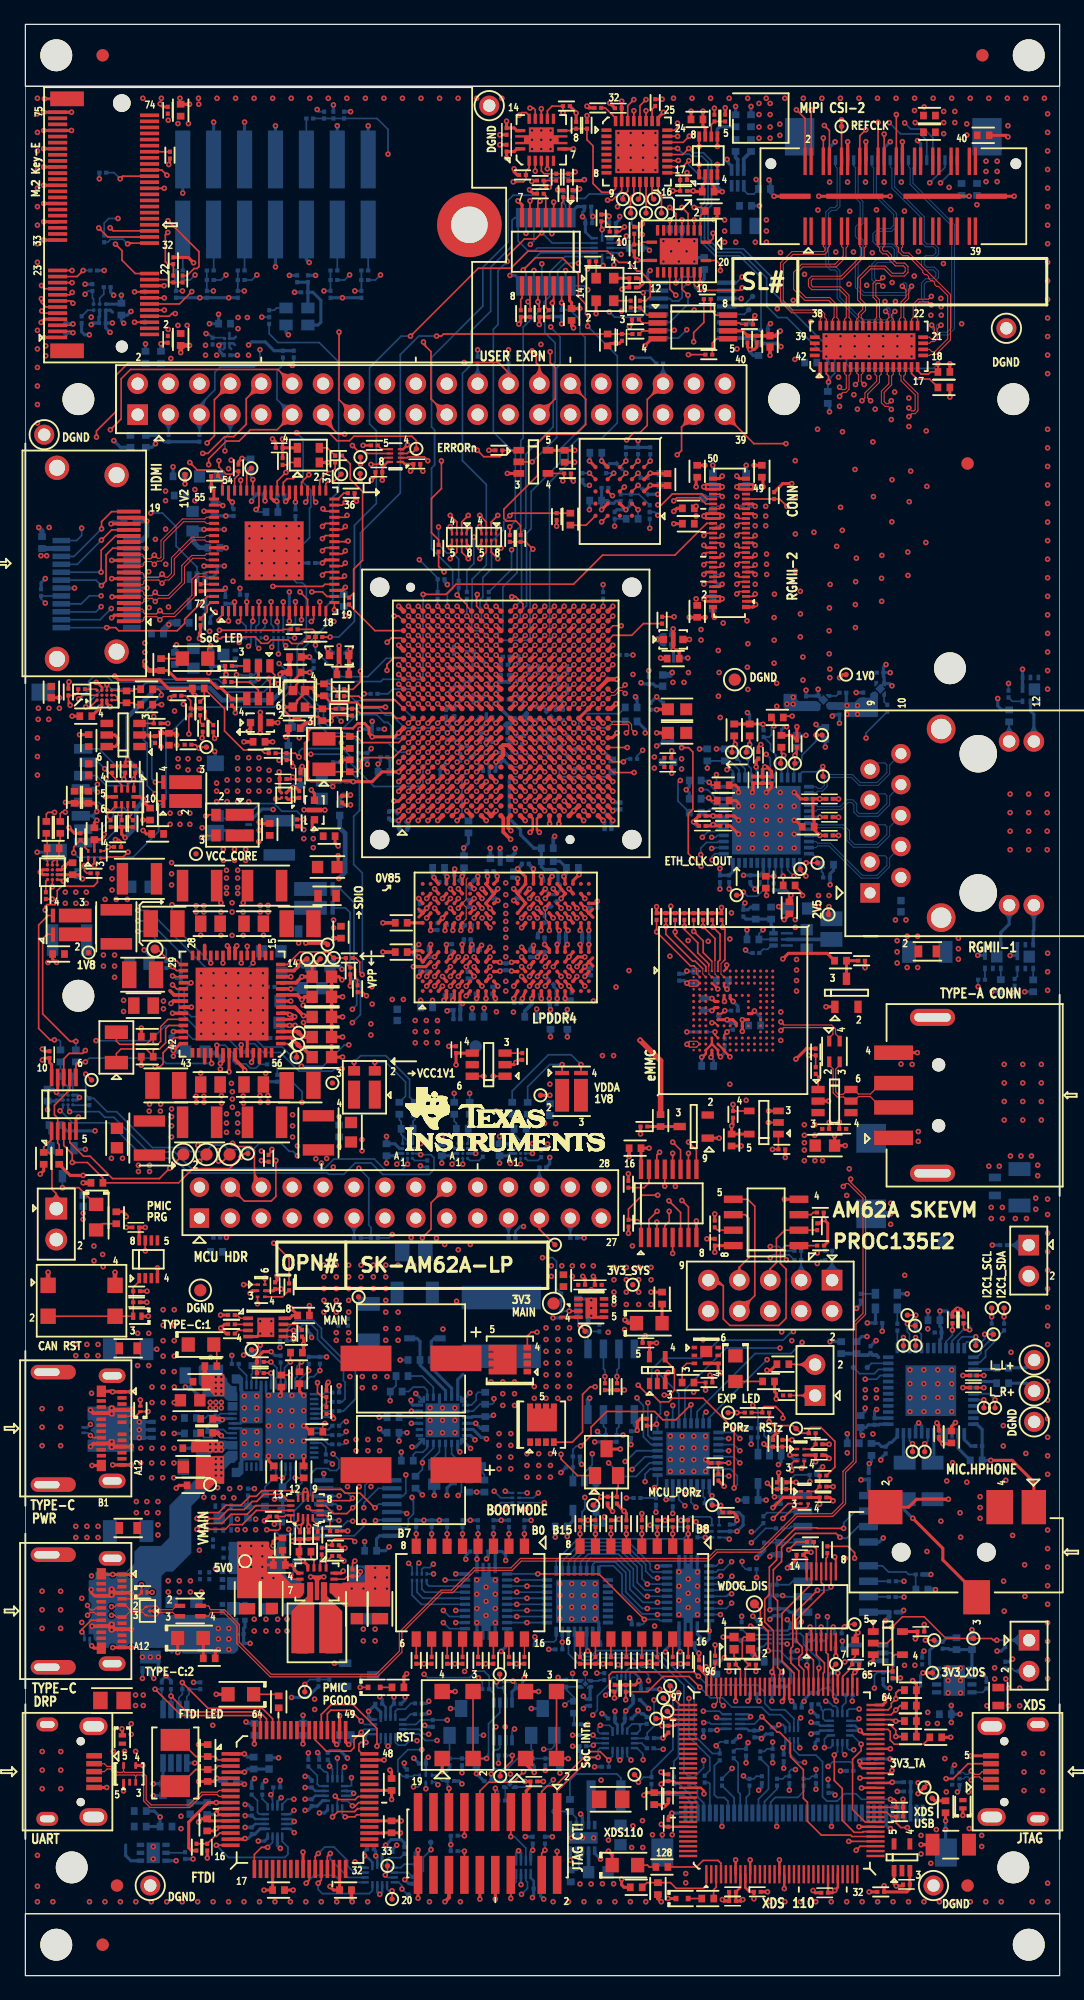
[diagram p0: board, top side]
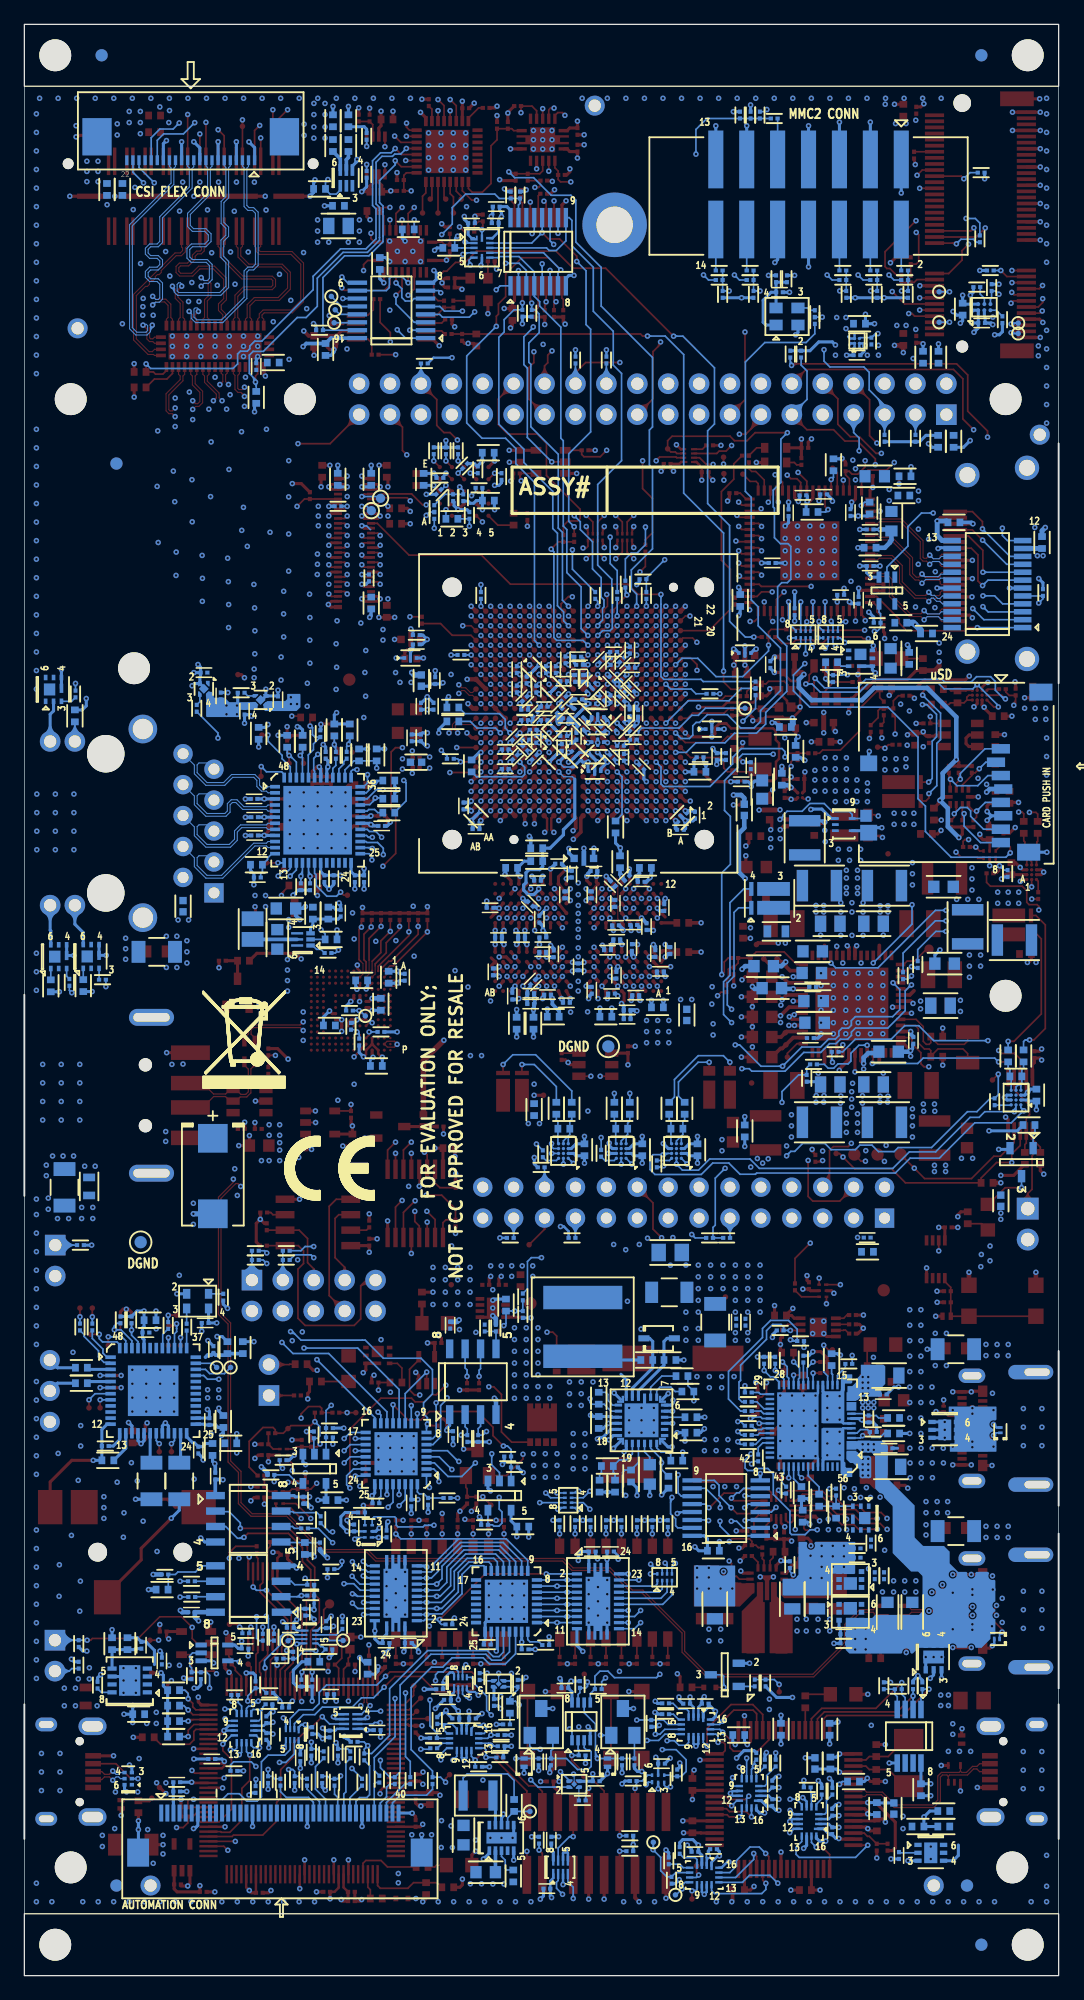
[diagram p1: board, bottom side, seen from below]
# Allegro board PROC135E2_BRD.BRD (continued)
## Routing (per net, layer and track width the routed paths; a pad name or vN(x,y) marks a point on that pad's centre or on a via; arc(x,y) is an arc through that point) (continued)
VBUS_5V0_TYPEA: length 0.6
  TOP w0.254: R125.2 v1(69,82.78)
  BOTTOM w0.14: C398.1 69.53,68.79
  vias: v1(73.38,69.33) v1(73.38,68.52)
VBUS_TYPEC1: length 8.4
  TOP w0.305: v1(5.35,43.45) 5.6,43.7 J13.B4 6.88,43.7 7.13,43.45 J13.A9 v1(8.7,43.45) ; v1(8.7,46.45) J13.A4 7.13,46.45 6.88,46.2 J13.B9 5.6,46.2 v1(5.35,46.45)
  TOP w0.381: R160.1 C118.1
  vias: v1(7.09,46.61) v1(7.09,46.15) v1(7.09,43.86) v1(7.09,43.4) v1(15.65,49.17) v1(15.65,48.71) v1(15.65,48.25) v1(15.65,47.8) v1(16.1,49.17) v1(16.1,48.71) v1(16.1,48.25) v1(16.1,47.8)
VBUS_TYPEC2: length 87.1
  TOP w0.254: v1(15.86,26.79) 15.6,26.54 R203.1 ; v1(7.09,31.27) 7.01,31.2 J15.B9 5.68,31.2 5.41,31.46 v1(5.41,31.71) ; R135.2 v1(50.55,69.13) ; v1(7.09,31.73) 7.37,31.45
  TOP w0.305: 7.37,31.45 J15.A4 v1(8.7,31.45) ; v1(5.48,28.7) J15.B4 6.84,28.7 7.09,28.45 J15.A9 v1(8.7,28.45)
  L06_PWR01 w0.508: v1(8.7,31.45) 8.7,32.11 12.59,35.99 20.74,35.99 22.04,34.7 22.04,33.81 22.54,33.3 22.54,31.64 23.6,30.58 33.91,30.58 36.57,33.24 39.72,33.24 44.85,38.37 44.85,44.73 45.54,45.41 45.54,51.42 47.38,53.26 47.38,59.95 50.55,63.13 v1(50.55,69.13)
  vias: v1(7.09,28.86) v1(7.09,28.4) v1(15.19,43.64) v1(15.19,43.18) v1(15.65,43.64) v1(15.65,43.18) v1(15.86,28.52) v1(15.86,27.65) v1(16.1,43.64) v1(16.1,43.18) v1(16.72,28.52) v1(16.72,27.65) v1(16.72,26.79)
VCC1V1: length 0.7
  BOTTOM w0.254: C90.2 v1(25.79,70.55)
  vias: v1(21.96,70.71) v1(21.96,69.79) v1(21.96,68.88)
VCC1V8_CLKBUF: length 29.1
  TOP w0.254: U7.6 58.95,135.08 C14.2 ; v1(46.19,140.15) 46.34,140.31 R23.2 ; v1(49.63,135.42) 49.86,135.64 R33.2 ; v1(49.04,138.5) 49.19,138.65 C15.2 C12.2 U6.4
  TOP w0.305: v1(62.04,135.07) 61.64,134.68 FL1.2 C16.2 C14.2
  L07_PWR02 w0.381: v1(62.04,135.07) 59.42,135.07 58.7,135.79 52.72,135.79 51.93,135 50.05,135 v1(49.63,135.42) 50.08,135.87 50.08,137.45 v1(49.04,138.5) 47.91,139.62 46.72,139.62 v1(46.19,140.15)
VCC1V8_SYS: length 97.8
  TOP w0.203: C22.1 31.18,124.16 31.02,124.32 U10.1 ; U28.M4 U28.N4 ; U28.N4 U28.P3 55.92,75.71 55.64,75.43 v1(55.58,75.43) ; U28.N4 U28.P5 56.92,75.67 v1(57.13,75.46) ; v1(57.67,81.01) 57.42,81.26 U28.C6 ; R40.1 v1(27.75,125.68) ; U54.2 22.82,37.18 v1(22.51,36.87)
  TOP w0.254: U12.D1 v1(51.35,123.4) 51.39,123.36 C26.2 ; U11.5 C21.1 v1(45.15,125.28) ; U32.5 C101.1 v1(58.04,69.78) 58.15,69.9 R133.1 ; v1(39.54,149.28) C9.2 40.18,149.81 40.4,150.03 U1.1 ; R49.2 v1(43.66,119.04) ; v1(31.65,123.56) 31.89,123.8 C22.1 ; R41.2 v1(38.09,125.28) ; U12.E4 v1(47.35,124.4) ; v1(40.17,148.39) 40.17,148.14 40.42,147.89 R9.2 ; v1(22.51,36.87) 22.51,36.86 22.57,36.81 C178.2 ; U12.B4 v1(47.35,120.4) ; v1(57.21,87.73) R118.1 R117.1 R116.1 R115.1 R114.1 R113.1 R112.1 R111.1 v1(51.88,87.8) ; R46.2 44.83,122.94 v1(45.03,122.75)
  TOP w0.305: U27.10 v1(21.81,81.04)
  L10_SIG03 w0.254: v1(58.48,36.49) 57.34,36.49 56.38,35.53 30.85,35.53 30.35,36.03 28.19,36.03 28.01,36.21 26.93,36.21 26.75,36.03 23.35,36.03 v1(22.51,36.87)
  BOTTOM w0.203: U51.1 48.24,142.7 48.53,142.99 ; C439.2 U96.5
  BOTTOM w0.254: R264.1 v1(23.85,139.64) ; v1(46.35,122.4) 46,122.4 45.79,122.61 R301.2 ; R277.2 v1(14.34,137.8) R276.2 v1(16.72,137.8) R275.2 ; C199.1 v1(47.35,120.4) ; C199.1 R303.2 ; C199.1 47.86,121.15 48.08,120.93 48.36,120.93 48.53,121.1 R306.2 ; R454.1 58.63,38.04 58.99,37.68 58.99,36.99 v1(58.48,36.49) C439.2 ; R262.2 v1(6.48,140.04) ; C191.1 47.37,124.41 v1(47.35,124.4) 47.35,124.39 47.74,124.01 R300.2 47.79,123.96 48.01,124.18 R299.2 ; R297.2 R296.2 ; R296.2 v1(50.35,126.07) ; R296.2 R295.2 ; v1(57.13,75.46) 57.48,75.82 R373.1 ; v1(57.67,81.01) 57.77,81.11 C358.1 ; R372.1 v1(54.36,77.51) ; R273.2 v1(26.06,137.8) R274.2 ; C384.1 v1(55.58,75.43) ; R411.2 v1(66.13,52.07) ; C195.1 51.37,123.38 v1(51.35,123.4) 51.13,123.17 R302.2 ; v1(48.85,144.48) 48.85,144.25 C173.2 48.53,142.99 ; R304.2 v1(51.97,121.66) ; R241.2 v1(26.73,153.09)
  BOTTOM w0.381: C361.1 22.71,81.04 v1(21.81,81.04)
  vias: v1(6.42,83.83) v1(6.42,82.91) v1(7.33,83.83) v1(7.33,82.91) v1(7.33,82)
VCC1V8_SYS_SW: length 1.2
  TOP w0.305: 11.89,80.89 12.24,80.54 U27.34
VCC2V5_PG: length 25.1
  L03_SIG01 w0.102: v1(69.09,101.64) 68.99,101.64 64.64,97.29 64.64,88.59 63.27,87.21 61.94,87.21 v1(60.62,85.9)
  BOTTOM w0.14: v1(69.09,101.64) 69.09,102.06 R329.1 ; U81.2 R360.1 60.28,85.56 v1(60.62,85.9)
VCC3V3_EXP: length 13.6
  BOTTOM w0.203: 17.22,133.92 17.09,134.05 U57.A1 16.77,133.74 16.92,133.59 ; v1(49.85,132.88) 51.37,132.88 R291.1 ; R290.1 v1(37.17,133.53) ; R289.1 v1(39.71,133.53)
  BOTTOM w0.254: C184.1 v1(17.43,133.09) ; R293.1 R294.1 11.42,125.98 10.9,126.5 C189.2 ; R287.1 R288.1 20.44,133.45 19.71,134.18 18.59,134.18 v1(18.34,133.92)
  vias: v1(18.34,133.09)
VCC3V3_TA: length 48.3
  TOP w0.254: R210.2 v1(37.83,25.61) R209.2 ; TP88.1 73.88,15.46 v1(73.37,14.95) ; R213.2 R214.2 v1(47.49,25.61) R215.2 ; R205.2 v1(32.75,25.61) R206.2 ; U45.5 C142.1 73.31,27.83 v1(73.14,27.66) ; v1(49.23,48.09) R166.1 R165.1 ; R208.2 v1(35.29,25.61) R207.2 ; R219.2 v1(53.85,25.61) R220.2 ; R211.2 v1(40.37,25.61) R212.2 ; R216.2 R217.2 51.17,25.61 v1(51.3,25.75) 51.44,25.61 R218.2
  L03_SIG01 w0.508: v1(61.18,34.42) 61.18,34.83 62.93,36.58 62.93,37.95 v1(61.56,39.32)
  BOTTOM w0.178: C453.2 60.69,28.55 60.9,28.34 U102.8
  BOTTOM w0.254: v1(66.54,14.84) 66.37,15.01 R559.1 ; U100.27 46.13,26.75 v1(46.22,26.66) ; U98.1 C457.2 53.72,26.7 v1(53.82,26.61) ; R546.2 v1(64.97,15.3) ; U101.1 C442.2 39.17,34.83 39.47,34.53 v1(39.47,34.1) ; v1(79.86,26.66) 80.2,26.66 R486.2 ; R548.2 60.52,15.49 v1(60.26,15.22) ; v1(49.66,29.38) 49.83,29.21 R480.2 ; v1(45.63,13.27) 45.78,13.12 U120.8 ; v1(59.6,28.7) 59.75,28.55 C453.2 ; U97.8 62.83,39.43 62.73,39.32 C437.2 v1(61.56,39.32) ; C460.2 v1(44.13,27.39) U100.31 ; J23.3 72.75,14.28 72.76,14.29 C492.1 C489.1 ; R490.2 v1(41.87,27.82) ; R547.2 v1(62.78,15.23) ; R531.2 v1(59.23,17.48) ; R530.2 v1(61.41,17.49) ; v1(58.7,19.65) 58.51,19.46 58.43,19.46 R527.2 ; R543.1 v1(66.99,16.82)
  BOTTOM w0.381: v1(70.68,29.14) 70.99,29.44 C451.2 U99.8 ; R470.2 61.35,34.59 v1(61.18,34.42) ; R474.2 v1(74.8,31.7)
  vias: v1(47.31,16.06) v1(47.89,52.83) v1(49.24,53.07) v1(73.37,15.84) v1(74.13,15.84)
VCC3V3_XDS: length 61.8
  TOP w0.203: v1(68.71,15.42) 68.72,15.43 U47.47 ; U47.113 53.44,15.83 53.29,15.98 C150.1 ; U47.8 58.77,7.25 C164.1 ; U47.101 53.48,20.63 53.37,20.52 C147.2 ; v1(66.51,7) 66.77,7.25 U47.28 ; v1(66.77,24.86) U47.69 ; U47.39 v1(68.51,12.23) ; C137.2 64.2,34.3 U44.14 ; U47.79 62.77,22.75 v1(62.97,22.55) ; U47.90 v1(58.37,22.55) ; U47.26 C166.1 ; U47.16 v1(61.97,9.51) ; U47.122 C156.1 ; U47.52 68.74,17.43 v1(68.56,17.6) 68.56,17.23 68.77,17.03 U47.51 ; U47.7 v1(58.37,9.51)
  TOP w0.254: v1(72.12,14.48) R233.1 R234.1 ; v1(68.43,28.17) 68.2,27.94 R202.2 ; v1(66.51,7) 66.32,6.81 C166.1 ; C137.2 64.14,34.77 v1(64.57,34.77) ; v1(58.96,6.25) 58.83,6.12 C167.1 C164.1 ; v1(52.25,15.72) 52.5,15.98 C150.1 ; C147.2 v1(52.32,20.52) ; C156.1 52.46,12.23 v1(52.26,12.43) ; TP79.1 v1(73.77,24.87) ; R239.1 v1(69.34,6.88)
  BOTTOM w0.178: U112.8 62.46,18.93 v1(62.26,18.73) ; U102.1 62.63,28.34 C454.2
  BOTTOM w0.203: C481.2 65.32,20.13 U111.2 ; C479.2 59.45,20.13 59.31,20.27 U109.8
  BOTTOM w0.254: v1(64.57,19.85) 64.64,19.92 C481.2 ; v1(61.35,22.55) R503.1 R502.1 62.58,23.74 62.89,24.05 62.89,25.09 62.19,25.78 R494.2 ; 74.31,25.55 74.31,26.72 75.01,27.42 C458.1 75.71,27.75 R488.1 ; v1(62.26,18.73) 62.32,18.66 C482.2 ; U99.1 62.81,29.85 62.53,30.13 C452.2 61.27,30.13 v1(61.19,30.05) 61.19,30.56 R479.1 R477.1 ; v1(62.97,22.55) 63.25,22.27 C469.1 ; R525.2 R522.2 R518.2 R514.2 73.58,23.8 73.58,24.68 v1(73.77,24.87) ; v1(68.56,17.6) 68.76,17.79 C483.2 ; C454.2 62.86,28.98 v1(62.61,29.24) ; C479.2 60.29,20.13 v1(60.49,20.33) ; v1(66.77,24.86) 66.2,24.86 66,24.66 R506.2
  BOTTOM w0.305: v1(68.67,40.72) 68.7,40.75 C135.2 69.31,39.44 U97.1
  vias: v1(72.25,25.49) v1(73.1,25.49)
VCC5V0_EXP: length 3.1
  BOTTOM w0.254: v1(6.96,134.96) 6.61,135.32 C181.1 ; C181.1 v1(7.15,135.73) ; C181.1 U53.A1 7,136.78 7.17,136.61
VCC_0V85: length 5.2
  TOP w0.305: v1(23.04,84.81) 24.71,84.81 TP30.1 ; C82.1 22.96,80.39 v1(22.73,80.16) 22.35,80.54 U27.9
  L08_PWR03 w0.457: v1(22.83,79.7) 22.73,79.81 v1(22.73,80.16)
  vias: v1(22.46,84.81)
VCC_1V8_AUD: length 3.3
  BOTTOM w0.305: 70.11,50.79 69.94,50.96 69.64,50.96 C411.1 69.28,50.96 68.44,50.96 C409.1 R411.1
VCC_1V8_FT4232: length 9.4
  TOP w0.254: v1(30.88,12.71) C158.2 U48.37 ; U48.49 26.32,19.19 26.53,18.98 v1(26.58,18.98) ; U48.12 15.1,12.71 C157.2 14.49,12.87 v1(14.24,12.62) ; U48.64 v1(18.82,19.03)
  BOTTOM w0.254: C476.2 v1(18.82,19.03) ; C480.1 26.78,19.18 v1(26.58,18.98)
VCC_3V3_AUD: length 20.1
  TOP w0.254: C125.1 76.04,43.69 v1(75.41,43.69) 75.07,44.03 C124.1
  BOTTOM w0.254: U88.16 75.66,43.94 v1(75.41,43.69) 75.16,43.94 U88.17 ; U88.24 71.66,44.27 71.17,43.78 71.04,43.78 C425.1 70.36,43.44 70.1,43.71 C424.1 ; U93.5 C434.1 v1(60.88,39.06) ; U88.25 70.22,45.29 70.16,45.23 C418.1 69.28,45.23 69.07,45.02 C419.1 68.64,44.51 v1(68.8,44.36) ; R402.1 R403.1 75.74,54.58 v1(75.16,54.58) C402.1 75.16,53.32 75.29,53.2 C407.1 75.29,52.36 75.16,52.23 U88.44 ; R399.1 68.65,55.15 v1(68.3,54.8) ; U86.4 C406.1 v1(69.19,53.61) ; R427.2 v1(58.75,44.97)
  vias: v1(69.65,44.49)
VCC_3V3_FT4232: length 23.8
  TOP w0.254: U48.20 C162.2 v1(19.61,7.03) ; U48.42 C152.2 v1(30.1,14.47) ; LD8.2 v1(15.69,23.11) ; U48.31 C163.2 25.33,7.03 v1(25.03,7.33) ; U48.56 v1(22.82,19.03) ; U48.50 v1(25.82,21.34)
  BOTTOM w0.203: U123.2 28.92,9.71 v1(28.79,9.84) ; U110.2 29.61,22.05 C468.2 ; C499.2 18.89,12.46 U119.2 ; U118.2 23.82,14.77 C493.2
  BOTTOM w0.254: R509.2 11.96,24.24 v1(11.57,24.64) 11.2,24.27 R510.2 ; v1(10.51,15.76) C491.2 U113.8 ; R508.2 v1(13.82,24.09) ; v1(22.99,14.49) C493.2 ; FL14.2 v1(20.82,17.89) ; C468.2 29.33,22.71 v1(29.12,22.91) ; v1(18.06,12.18) C499.2 ; C475.2 v1(22.82,19.03) ; C502.2 28.79,10.23 v1(28.79,9.84)
  vias: v1(12.79,13.09) v1(12.79,12.08)
VCC_3V3_MAIN: length 47.8
  TOP w0.254: v1(1.4,75.2) 1.56,75.36 C88.2 1.99,74.99 2.16,74.82 U31.10 ; U21.B2 20.9,97.29 C51.1 20.9,98.82 v1(20.86,98.86) ; R138.2 1.51,66.11 v1(1.22,65.83) ; v1(21.02,56.39) C107.2 20.38,56.25 U36.5 ; 43.95,54.08 U37.4
  TOP w0.279: U27.12 v1(21.81,82.04) ; U27.8 v1(21.81,80.04)
  TOP w0.305: v1(11.97,79.85) 12.16,80.04 U27.35 ; U27.54 19.24,74.97 ; U27.48 16.24,75.13 v1(16.03,74.91) ; R80.1 21.61,101.95 v1(21.41,101.75) ; U27.4 v1(21.71,78.04) v1(22.17,78.04) ; U27.26 14.74,84.61 ; U27.17 19.24,84.61 ; U27.45 14.74,74.97
  L06_PWR01 w0.254: v1(21.81,82.04) 21.81,83.36 21.8,83.38
  L06_PWR01 w0.432: v1(20.86,98.86) 20.86,99.01 19.78,100.08
  L07_PWR02 w0.381: v1(30.63,54.5) 31.43,54.5 37.9,48.02 v1(37.9,44.08) 37.9,42.69 v1(34.65,39.43)
  BOTTOM w0.254: v1(34.65,39.43) 34.65,40.05 R443.2 ; v1(21.41,101.75) 21.61,101.55 C280.1 ; C92.1 19.8,73.42 R574.1 ; R401.2 v1(43.36,54.02) ; v1(37.9,44.08) 37.78,44.2 37.46,44.2 36.81,44.86 U89.17
  BOTTOM w0.381: C383.1 14.88,75.77 15.64,75.77 16.03,75.39 v1(16.03,74.91)
  vias: v1(4.75,62.62) v1(4.75,62.12) v1(11.35,80.04) v1(11.35,79.41) v1(14.03,87.87) v1(14.03,87.36) v1(14.03,72.22) v1(14.06,71.74) v1(14.41,85.45) v1(14.41,74.13) v1(14.67,87.87) v1(14.67,87.36) v1(14.67,72.22) v1(14.69,71.74) v1(16.03,74.46) v1(19.31,87.89) v1(19.31,87.36) v1(19.28,72.27) v1(19.31,71.74) v1(19.57,85.45) v1(19.75,74.12) v1(19.94,87.89) v1(19.94,87.36) v1(19.92,72.27) v1(19.94,71.74) v1(24.54,58.36) v1(24.54,57.39) v1(24.54,56.43) v1(24.54,55.46) v1(24.54,54.5) v1(25.55,58.36) v1(25.55,57.39) v1(25.55,56.43) v1(25.55,55.46) v1(25.55,54.5) v1(26.57,58.36) v1(26.57,57.39) v1(26.57,56.43) v1(26.57,55.46) v1(26.57,54.5) v1(27.58,58.36) v1(27.58,57.39) v1(27.58,56.43) v1(28.6,58.36) v1(28.6,57.39) v1(28.6,56.43) v1(29.62,58.36) v1(29.62,57.39) v1(29.62,56.43) v1(29.62,55.46) v1(29.62,54.5) v1(30.63,58.36)
VCC_3V3_MAIN_PG: length 103.5
  TOP w0.14: U36.3 v1(19.08,55.18)
  L03_SIG01 w0.102: v1(35.57,39.43) 35.57,41.82 34.79,42.61 34.79,47.12 34.32,47.59 v1(34.32,53.1)
  L05_SIG02 w0.102: v1(54.92,47.92) 54.92,49.49 57.3,51.88 57.3,53.97 57.3,54.16 57.3,67.78 58.73,69.2 58.73,73.36 60.43,75.06 60.43,80.43 59.18,81.67 v1(59.18,84.24) ; v1(19.08,55.18) 19.85,55.18 20.08,55.41 21.85,55.41 23.61,53.65 33.77,53.65 v1(34.32,53.1)
  L10_SIG03 w0.102: v1(35.57,39.43) 35.57,41.55 37.42,43.39 37.42,44.43 37.9,44.91 40.37,44.91 40.61,44.67 46.5,44.67 48.32,42.85 50.27,42.85 52.28,44.86 52.28,46.67 52.94,47.33 54.33,47.33 v1(54.92,47.92)
  BOTTOM w0.14: U89.21 34.53,42.14 R443.1 35.65,41.53 35.84,41.34 35.84,39.7 v1(35.57,39.43) ; R361.1 59.44,83.99 v1(59.18,84.24)
VCC_3V3_SYS: length 227.8
  TOP w0.14: U4.19 v1(55.46,139.03) ; U2.27 v1(51.01,153.17)
  TOP w0.203: U54.3 23.22,36.95 v1(23.29,36.88) ; U10.8 29.77,124.32 29.33,123.88 C25.2 ; C65.1 U24.5
  TOP w0.229: J4.48 57.07,122.08 v1(57.27,122.28) 57.07,122.48 J4.50 55.96,122.48 v1(55.76,122.28) 55.96,122.08 J4.48
  TOP w0.254: v1(50.43,24.23) 50.43,24.19 50.12,23.87 R224.1 R223.1 ; v1(65.27,38.73) C133.1 U42.5 ; R83.2 R84.2 60.61,102.8 v1(60.63,102.77) ; v1(13.82,140.68) 13.38,141.12 R22.2 ; R162.2 61.56,47.97 61.71,47.82 v1(61.71,47.37) ; U33.16 C103.2 v1(51.26,67.96) ; C62.1 56.63,94.43 v1(56.52,94.54) 56.41,94.43 C61.1 ; R285.2 26.01,36.52 26.01,36.53 v1(26.49,36.53) ; R39.1 v1(75.98,129.64) ; C75.1 62.79,88.6 v1(62.92,88.74) ; R172.2 50.54,45.73 50.28,45.48 v1(50.28,44.79) ; v1(46.15,153.54) 46.29,153.4 R3.2 ; C180.2 23.29,36.87 v1(23.29,36.88) ; U1.14 40.4,151.53 40.18,151.75 C6.2 v1(39.54,152.31) ; R68.2 3.53,106.21 v1(3.58,106.26) ; v1(45.56,136.92) C13.2 44.89,137.4 44.72,137.58 U5.14 ; v1(55.69,153.12) C5.2 55.69,151.93 55.87,151.74 U3.7 ; R263.2 20,37.71 v1(19.65,37.35) ; U2.31 C1.2 v1(49.01,153.95) ; v1(48.26,38.13) 47.85,38.54 R183.1 ; U25.B1 C71.1 4.35,90.42 v1(4.7,90.07) ; v1(21.85,54.8) 22.37,54.28 C111.1 21.95,54.22 21.72,53.99 U38.8 ; R151.1 v1(16.04,54.25) ; U9.4 C20.2 ; C20.2 R44.2 ; C20.2 v1(21.14,126.2) ; R1.2 v1(52.33,154.11) ; v1(24.89,48.73) 24.74,48.58 R167.1 ; v1(51.87,51.96) C112.2 U40.5 ; U16.4 C35.2 16.09,105.75 15.76,105.75 15.05,106.47 12.42,106.47 11.7,107.19 R62.2 ; v1(63.4,102.58) R86.2 62.98,101.87 R85.2 ; R175.2 v1(63,44) ; R181.2 v1(63.33,40.52) ; v1(31.34,24.79) 31.11,24.57 R222.2 ; v1(41.06,15.95) C151.1 41.51,15.53 41.16,15.18 J19.5 ; v1(64.94,42.21) C127.1 U41.5 ; R136.2 v1(62.45,67.2) ; U28.E6 57.42,80.04 v1(57.45,80.01) ; R30.1 R29.1 40.71,135.79 v1(40.56,135.64) ; R32.1 R31.1 v1(42.24,135.61) ; U17.B1 6.29,104.35 v1(6.12,104.18) 6.12,104.11 C37.1 ; v1(8.29,62.33) 8.29,62.49 8.04,62.73 R143.2 ; R17.1 41.76,146.35 v1(41.43,146.67) ; R79.2 v1(11.71,102.84) ; R182.2 v1(66.39,40.16) ; R2.2 45.27,153.02 v1(45.27,152.97) R6.2 ; R126.2 v1(26.7,81.29) ; v1(29.33,122.82) C25.2 ; v1(63.32,75.27) 64.19,76.14 R128.1 ; C43.1 60.05,99.77 v1(60.05,99.27) ; U28.J10 v1(58.92,78.51) U28.K9 v1(58.92,77.55) ; C65.1 6.23,93.3 6.48,93.55 v1(6.48,93.74) ; v1(35.4,74.8) C87.2 U29.4 ; R38.1 v1(75.98,132.39) ; v1(56.42,80.26) 56.67,80.01 U28.F5 ; R176.2 v1(66.06,43.64) ; v1(65.19,131.37) 65.33,131.51 U8.1 ; v1(45.54,146.75) 45.44,146.64 R16.1 ; v1(55.12,122.28) 55.12,123.03 55.21,123.12 ; R150.2 v1(51.42,56.14) ; v1(62.98,122.54) 62.24,122.54 R571.2 ; R13.2 v1(54.37,148.08) ; R179.2 v1(57.42,40.19)
  TOP w0.305: v1(22.88,94.12) 22.6,94.4 R97.2
  TOP w0.381: v1(9.82,107.92) 9.82,107.55 10.18,107.19 R62.2
  L05_SIG02 w0.508: v1(63.44,26.7) 64.22,27.48 v1(67.14,27.48)
  L07_PWR02 w0.254: v1(20.37,95.77) 19.32,95.77 18.31,94.76 13.72,94.76 v1(13.52,94.55)
  BOTTOM w0.14: U83.B3 v1(41.68,67.53)
  BOTTOM w0.178: U112.1 62.46,20.4 62.24,20.61 v1(61.91,20.61) ; 49.79,24.9 49.69,24.79 U106.8 ; U106.1 49.69,23.26 49.79,23.15
  BOTTOM w0.203: U109.1 56.95,20.27 v1(56.84,20.17) ; U122.1 41.53,8.02 41.77,7.78 C506.2 ; v1(40.94,61.52) 40.66,61.52 40.27,61.14 R391.1 ; C496.2 18.89,12.86 U119.3 ; C467.2 30.01,22.05 U110.3 ; 16.77,134.92 U57.A2 17.15,134.45 17.3,134.61 ; U114.2 48.66,20.6 ; U111.3 65.32,20.53 C473.2 ; U118.3 23.82,15.17 C490.2 ; U116.5 C487.2 ; 49.79,24.9 50.02,24.9 50.43,24.49 v1(50.43,24.23) ; R390.2 v1(45.92,60.59) ; 46.02,143.21 46.53,142.7 U51.11 ; U114.3 49.06,20.63
  BOTTOM w0.254: R505.1 v1(40.07,24.19) 40.3,23.96 C462.2 39.99,23.31 U108.8 ; v1(45.85,22.95) 46.08,22.72 C466.2 U107.5 ; R408.1 23.52,52.63 v1(23.52,52.41) ; U101.24 v1(37.11,34.2) C443.1 ; U101.23 v1(35.37,32.99) ; 49.06,20.63 49.26,20.83 C471.2 49.26,21.66 v1(49.34,21.74) 49.95,22.35 C465.2 49.95,22.99 49.79,23.15 ; v1(55.12,37.28) 55.23,37.17 R465.2 ; v1(44.98,18.84) R528.2 45.53,18.42 45.64,18.31 R537.2 ; v1(1.83,71.11) C388.1 2.45,71.83 2.54,71.92 U82.B1 ; v1(6.08,147.57) 6.08,148.07 R250.2 ; R392.2 v1(79.47,60) ; R339.1 v1(56.79,100.75) ; U92.27 v1(55.2,39.51) ; R252.2 45.31,146.52 v1(45.54,146.75) ; C473.2 64.64,20.74 v1(64.57,20.81) ; v1(23.25,18.3) R541.2 ; U87.1 50.05,45.2 50.28,44.96 v1(50.28,44.79) 50.21,44.71 C422.1 ; 56.49,122.28 v1(57.27,122.28) ; R433.1 R434.1 v1(46.79,43.83) ; U78.19 60.65,90.68 C310.1 C311.1 v1(59.02,90.37) ; U95.16 29.12,36.13 28.86,35.87 C441.2 29.58,34.9 v1(29.9,35.22) ; U94.5 45,37.35 C438.1 v1(44.53,36.06) ; v1(21.87,22.85) 23.18,22.85 R501.2 ; C487.2 32.91,17.74 v1(33.11,17.94) ; R539.1 v1(35.88,16.66) ; v1(55.46,139.03) 55.79,139.36 C176.2 ; v1(1.64,114.74) 1.29,114.39 R317.2 ; R534.2 v1(38.88,17.44) ; R335.2 60.63,102.33 v1(60.63,102.77) ; v1(35.88,15.75) 35.64,15.99 R552.1 ; v1(61.91,20.61) 61.71,20.41 C478.2 ; R438.2 45.56,42.14 v1(45.71,41.99) ; v1(62.92,88.74) 62.5,89.15 R354.2 R355.1 ; U84.B1 35.1,67.53 34.91,67.34 C396.1 v1(34.22,66.73) ; R388.1 43.09,66.67 v1(43.09,67.2) ; v1(71.05,23.61) 70.75,23.61 70.5,23.86 R498.2 ; U92.31 C435.2 v1(52.66,39.1) ; v1(63.44,26.7) 63.34,26.6 R492.2 ; v1(43.78,24.5) 43.99,24.29 R504.2 ; U117.5 C488.2 v1(38.29,16.58) ; R367.2 v1(82.12,80.8) ; R346.2 54.56,97.65 v1(54.31,97.4) 54.56,97.15 R347.2 ; R558.1 v1(20.94,16.04) ; C61.1 56.41,94.43 v1(56.52,94.54) 56.62,94.64 U78.30 ; R542.2 46.9,17.15 46.89,17.15 v1(46.78,17.15) ; v1(18.84,16.19) 18.59,15.95 R561.2 ; R409.1 v1(20.93,51.6) ; v1(29.68,66.73) C397.1 30.37,67.34 30.56,67.53 U85.B1 ; v1(31.18,7.88) 31.51,7.55 R570.1 ; v1(44.07,135.66) R278.1 R279.1 ; R353.2 4.53,90.23 v1(4.7,90.07) ; U98.23 v1(56.2,28.32) 56.2,27.66 55.85,27.32 C456.1 55.56,27.72 55.22,28.06 U98.24 ; U84.B3 v1(37.01,67.53) ; U82.B3 4.24,71.92 v1(4.45,72.12) 4.26,72.32 U82.C3 ; v1(22.99,15.45) C490.2 ; R516.2 32.98,22.36 v1(33.15,22.54) ; v1(18.06,13.14) C496.2 ; v1(38.97,66.73) C395.1 39.66,67.34 39.85,67.53 U83.B1 ; v1(30.29,22.88) C467.2 ; U52.16 45.04,144.99 45.34,145.29 C172.2 45.94,144.97 45.79,144.82 v1(45.79,144.46) 46.02,144.23 C174.2 46.02,143.21 ; U103.5 67.71,27.16 67.42,26.87 C459.2 v1(67.14,27.48) ; U123.3 29.32,9.89 C503.2 v1(29.6,10.72) 30.06,11.17 30.89,11.17 31.14,10.92 R565.2 ; v1(66.08,128.44) 66.08,128.99 R292.1 ; v1(41.67,6.41) 41.77,6.52 C506.2 ; U85.C3 32.08,67.93 v1(32.49,68.34) ; R538.1 42.74,16.85 v1(42.73,16.85) ; R544.1 31.14,17.14 v1(31.14,17.46) ; R564.1 v1(34.96,10.76) R566.1 ; U79.1 18.69,95.03 19.46,95.81 20.33,95.81 v1(20.37,95.77) ; 48.66,20.6 48.45,20.81 C472.2 v1(48.45,21.72) ; R272.1 v1(21.7,139.64) ; C463.2 50.59,24.09 50.46,24.23 v1(50.43,24.23) ; v1(79.91,104.89) 79.91,104.28 80.24,103.95 R330.1 ; U122.8 41.53,10.13 v1(41.69,10.3) C501.2 ; R451.2 v1(51.82,38.06) ; R366.2 v1(79.43,80.82) ; v1(56.84,20.17) C477.2 ; U78.41 60.15,99.18 v1(60.05,99.27) 60.05,99.77 C43.1 ; R435.2 v1(67.54,44.51)
  BOTTOM w0.305: U55.16 59.81,134.49 C183.2 61.83,134.05 v1(62.09,133.79)
  BOTTOM w0.381: v1(56.42,80.26) 56.41,80.27 C371.1
  vias: v1(9.82,109.45) v1(9.82,108.69) v1(11.13,100.93) v1(11.74,152.39) v1(11.74,135.2) v1(11.9,95.47) v1(11.9,94.55) v1(12.45,101.05) v1(12.54,152.11) v1(12.54,135.53) v1(12.71,95.47) v1(12.71,94.55) v1(13.3,135.53) v1(13.4,152.11) v1(13.52,95.47) v1(17.48,136.18) v1(17.48,135.27) v1(18.24,136.18) v1(48.37,58.17) v1(48.37,57.15) v1(48.37,56.14) v1(48.37,55.12) v1(49.39,58.17) v1(49.39,57.15) v1(49.39,56.14) v1(49.39,55.12) v1(50.4,58.17) v1(50.4,57.15) v1(50.4,56.14) v1(50.4,55.12) v1(51.42,58.17) v1(51.42,57.15) v1(51.42,55.12) v1(63.38,83.45) v1(63.38,82.59) v1(63.38,81.73) v1(63.38,80.86) v1(67.54,42.94) v1(71.5,86.7) v1(72.37,86.7) v1(75.47,153.11) v1(75.47,152.19) v1(75.47,151.28) v1(76.38,153.11) v1(76.38,152.19) v1(78.95,149.02) v1(78.95,148.18) v1(78.95,147.34) v1(79.86,149.02) v1(79.86,148.18) v1(79.86,147.34)
VCC_3V3_SYS_EN: length 61.5
  TOP w0.14: TP53.1 45.99,52.99 v1(45.6,53.38) ; U27.47 v1(15.74,76.41) ; U37.3 v1(44.69,54.58)
  L05_SIG02 w0.102: v1(15.74,76.41) 15.26,76.41 14.12,75.27 14.12,74.48 13.52,73.88 13.52,65.66 13.23,65.37 13.23,61.48 16.25,58.46 23.23,58.46 23.88,57.81 41.46,57.81 v1(44.69,54.58)
  BOTTOM w0.14: v1(45.6,53.38) 45.42,53.56 R400.2 v1(44.69,54.58) R401.1 R398.2 ; v1(15.74,76.41) 16.42,76.41 17.07,75.76 17.07,75.11 17.3,74.88 18.13,74.88 18.48,74.53 18.94,74.53 19.26,74.84 R575.2
VCC_5V0: length 25.7
  TOP w0.229: 57.07,119.68 J4.36 55.96,119.68 v1(55.76,119.88) 55.96,120.08 J4.38 57.07,120.08 v1(57.27,119.88) 57.07,119.68
  TOP w0.254: R196.2 26.01,35.12 v1(26.27,35.12) ; v1(19.47,33.57) 19.62,33.72 R200.1 20.38,34.48 v1(20.39,34.49)
  L07_PWR02 w0.254: v1(20.39,34.49) 20.94,35.04 20.94,38.67 v1(20.47,39.14)
  L10_SIG03 w0.254: v1(20.39,32.66) 21.33,33.61 24.54,33.61 26.06,35.12 v1(26.27,35.12)
  BOTTOM w0.254: v1(7.26,138.01) 7,138.26 R270.1 ; C436.1 21.14,38.33 R447.1 20.53,39.19 v1(20.47,39.14) ; v1(7.89,138.01) C179.1 7.81,137.28 U53.A2 ; v1(5.26,134.76) 4.87,134.76 4.62,135.01 R281.2 ; 19.81,32.59 19.81,31.98
  BOTTOM w0.406: U58.11 C204.1 1.37,117.21
  vias: v1(1.28,116.62) v1(1.75,116.62) v1(17.65,35.3) v1(17.65,34.44) v1(17.65,33.57) v1(18.56,35.3) v1(18.56,34.44) v1(18.56,33.57) v1(19.47,35.3) v1(19.47,34.44) v1(19.47,32.66) v1(55.12,120.68) v1(55.12,119.88) v1(57.46,144.2) v1(57.46,143.28) v1(57.46,142.37) v1(58.38,142.37) v1(60.84,120.68) v1(60.84,119.88) v1(60.84,119.08) v1(64.02,69.88) v1(64.02,69.02) v1(64.02,68.41) v1(64.02,67.8) v1(64.02,66.94) v1(64.88,69.88) v1(64.88,69.02) v1(64.88,66.94) v1(65.52,66.94)
VCC_5V0_EN: length 45.6
  TOP w0.14: v1(27.54,33.19) 27.54,32.94 27.4,32.8 R201.2 26.47,32.8 26.24,32.56 U43.14
  L03_SIG01 w0.102: v1(27.54,33.19) 28.35,34 28.35,35.97 27.42,36.9 27.42,39.34 26.99,39.77 26.99,41.1 27.66,41.78 27.66,44.51 28.12,44.96 28.12,49.71 30.1,51.69 30.1,56.54 v1(31.9,58.34)
  L05_SIG02 w0.102: v1(31.9,58.34) 41.87,58.34 v1(42.5,58.97)
  BOTTOM w0.14: v1(42.5,58.97) 43.33,58.97 43.65,58.65 43.65,56.4 R398.1
VCC_5V0_FB: length 2.9
  TOP w0.254: R195.1 21.13,34.5 21.36,34.27 R200.2 21.9,33.72 22.1,33.53 22.1,33.35 22.39,33.06 U43.5
VCC_5V0_HDMICONN: length 5.1
  TOP w0.305: J5.18 9.7,119.74 v1(9.98,119.46)
  BOTTOM w0.406: U58.13 9.57,117.86 9.98,118.27 v1(9.98,119.46) 9.2,119.46 C202.1
VCC_5V0_PG: length 28.8
  TOP w0.14: v1(27.07,35.65) 26.84,35.88 25.42,35.88 25.21,35.67 R196.1 24.88,35.35 24.68,35.15 R197.2
  L05_SIG02 w0.102: v1(27.07,35.65) 27.07,35.65 27.07,35.16 26.55,34.64 26.05,34.64 25.25,33.84 25.25,28.77 27.11,26.9 27.11,18.98 30.59,15.5 v1(31.9,15.5)
  BOTTOM w0.14: U116.3 32.41,15.64 32.27,15.5 v1(31.9,15.5)
VCC_CORE:
  vias: v1(10.2,71.58) v1(10.18,71) v1(11.12,71.58) v1(11.09,71) v1(12.02,91.41) v1(12.02,90.5) v1(12.02,89.58) v1(12.02,71.18) v1(12.02,70.55) v1(12.02,69.79) v1(12.02,68.88) v1(16.27,92.51) v1(16.27,91.59) v1(17.19,92.51) v1(17.19,91.59) v1(18.1,92.51) v1(18.1,91.59) v1(19.18,93.13)
VCC_CSI_IO: length 9.5
  TOP w0.14: v1(54.96,145.22) 55.57,145.22 C11.2 55.46,144.52 U4.2 ; R4.2 v1(56.63,153.37)
  TOP w0.254: v1(50.7,143.88) 50.44,143.62 R20.2 ; v1(57.27,146.52) C10.2 56.61,146.98 56.37,147.21 U3.3
  BOTTOM w0.254: R249.1 56.87,146.92 v1(57.27,146.52) ; R246.1 56.87,151.65 57.07,151.85 R245.1
  vias: v1(60.29,151.83) v1(60.29,150.91) v1(61.21,151.83) v1(61.21,150.91) v1(77.36,152.08) v1(77.36,151.17)
VCC_LM5141: length 6.4
  BOTTOM w0.254: D9.2 32.18,52.34 32.43,52.09 C413.1 32.43,50.14 34.53,48.04 U89.10
VDD1_LPDDR4_1V8: length 12.5
  TOP w0.254: U26.U12 43.06,90.06 v1(43.29,90.29) ; U26.G4 v1(36.23,82.87) ; U26.U1 v1(43.06,80.24) ; U26.F12 v1(35.91,90.29) ; U26.G9 v1(36.88,87.67) ; U26.T9 v1(42.08,87.67) ; v1(35.92,79.84) 35.71,80.05 35.71,80.67 U26.F1 ; U26.T4 v1(42.73,83.67)
  BOTTOM w0.254: v1(42.08,87.67) 42.67,87.07 C328.1
  BOTTOM w0.305: C345.1 42.68,83.72 v1(42.73,83.67) ; v1(35.92,79.84) 35.74,79.66 C374.1 C375.2 ; C322.1 36.76,87.79 v1(36.88,87.67) ; C363.1 43.11,80.29 v1(43.06,80.24) 43.06,79.85 C370.1 43.11,79.4 v1(43.16,79.35) C378.1 ; C314.2 43.11,90.11 v1(43.29,90.29) ; v1(36.23,82.87) 36.34,82.75 C355.1 ; 35.66,89.94 35.91,90.18 v1(35.91,90.29) 36.05,90.43 C302.1
  vias: v1(30.15,80.17) v1(31.07,80.17)
VDD_1V0: length 26.6
  TOP w0.229: J4.2 55.96,112.88 v1(55.76,113.08) 55.96,113.28 J4.4 57.07,113.28 v1(57.27,113.08)
  TOP w0.254: J4.2 57.07,112.88 v1(57.27,113.08) ; C60.1 v1(65.29,95.14) ; C48.1 C49.1 ; C49.1 C50.1 61.33,98.91 60.97,99.27 v1(60.76,99.27) 60.57,99.07 C49.1 ; C59.1 v1(56.52,95.25) C58.1 ; v1(66.91,106.6) 67.17,106.85 TP17.1
  L07_PWR02 w0.305: v1(57.08,90.93) 57.08,94.69 v1(56.52,95.25) 57.89,96.62 57.89,97.63 58.4,98.13 59.63,98.13 v1(60.76,99.27)
  BOTTOM w0.254: C60.1 v1(65.29,95.14) U78.6 ; U78.24 58.15,90.67 C312.1 C313.1 v1(57.08,90.93) ; C267.1 v1(65.74,100.9) ; U78.42 60.65,99.15 v1(60.76,99.27) ; U78.31 56.62,95.14 v1(56.52,95.25)
  vias: v1(55.12,113.08) v1(66.11,107.31) v1(66.11,106.6)
VDD_1V2: length 0.8
  TOP w0.254: v1(13.12,122.51) TP13.1
  vias: v1(13.93,122.06) v1(13.93,121.14) v1(62.59,104.43) v1(63.1,104.99) v1(63.1,104.43)
VDD_2V5: length 18.7
  TOP w0.229: J4.49 58.67,122.48 v1(58.47,122.28) 58.67,122.08 J4.47 59.78,122.08 v1(59.98,122.28) 59.78,122.48 J4.49
  TOP w0.254: 60.52,123.12 60.61,123.03 v1(60.61,122.28) ; v1(66.04,87.8) 66,87.76 TP29.1 ; C67.1 v1(65.29,93.64) 64.82,94.11 C63.1 64.82,94.9 64.73,95 C54.1 v1(65.29,96.64) C300.1
  BOTTOM w0.203: U65.4 66.58,104.45
  BOTTOM w0.254: C67.1 v1(65.29,93.64) U78.9 ; R358.1 59.6,87.75 59.39,87.54 C327.1 59,87.97 v1(59.13,88.1) ; 66.58,104.45 C256.1 ; 59.24,122.28 v1(58.47,122.28) ; C293.1 v1(65.29,96.64) U78.3 ; v1(67.52,103.59) 67.52,103.6 67.52,104.07 67.4,104.19 v1(67.52,104.31) 67.46,104.38 R325.1
  BOTTOM w0.305: R360.2 v1(59.3,85.88)
  vias: v1(65.18,88.71) v1(65.18,87.8) v1(66.04,88.71) v1(68.39,104.31) v1(68.39,103.59)
VDD_2V5_FB: length 3.6
  BOTTOM w0.254: U81.3 61.48,86.07 61.29,86.26 R357.1 R358.2 59.21,86.77 C327.2
VDD_CANUART: length 24
  TOP w0.305: C47.1 22.6,99.16 v1(22.75,99.31)
  TOP w0.356: U18.H9 v1(36.28,101.27)
  L07_PWR02 w0.165: v1(36.28,101.27) 36.68,100.86 36.68,100.23 36.52,100.07 31.08,100.07 30.68,100.47 31.08,100.87 35.88,100.87 v1(36.28,101.27)
  L07_PWR02 w0.305: 30.68,100.47 29.12,100.47 28.84,100.18 25.58,100.18 24.46,99.05 23,99.05 v1(22.75,99.31)
  BOTTOM w0.305: v1(36.28,101.27) 36.28,101.02 C277.1
  BOTTOM w0.381: R95.2 v1(22.75,99.31)
VDD_CANUART_EN: length 33.9
  TOP w0.14: v1(20.59,96.64) 20.95,96.64 U21.A2
  L10_SIG03 w0.102: v1(20.59,96.64) 21.05,96.18 23.56,96.18 23.87,95.87 23.87,94.8 24.19,94.48 24.19,88.08 23.45,87.34 23.45,77.37 22.24,76.15 22.24,72.22 v1(22.74,71.72)
  BOTTOM w0.14: v1(22.74,71.72) 22.74,72.61 21.36,73.98 R574.2 20.7,74.56 R575.1
VDD_CORE: length 53.9
  TOP w0.305: v1(16.6,84.58) 16.74,84.45 U27.22
  TOP w0.356: U18.M12 v1(40.28,104.46) ; U18.J15 v1(37.08,106.86) ; U18.J13 v1(37.08,105.26) ; U18.N11 v1(41.08,102.87) ; U18.J11 v1(37.08,102.87) ; U18.R15 v1(42.68,106.86) ; U18.L11 v1(38.68,102.87) ; U18.J9 v1(37.08,101.26) ; U18.U15 v1(44.28,106.86) ; U18.K14 v1(37.88,106.06) ; U18.P14 v1(41.88,106.07) ; U18.L9 v1(38.68,101.27) ; U18.N13 v1(41.08,105.26) ; U18.P10 v1(41.88,102.07) ; U18.T16 v1(43.48,107.66) ; U18.L13 v1(38.68,105.26) ; U18.R9 v1(42.68,101.27)
  L03_SIG01 w0.14: v1(37.08,102.87) 36.83,103.11 36.83,103.7 36.53,104 30.1,104 28.58,102.48 28.2,102.48 27.62,101.9 27.43,101.9 26,100.47 25.6,100.47 24.43,99.29 24.43,97.44 23.68,96.69 22.68,96.69 22.15,96.15 22.15,88.4 19.99,86.25 17.11,86.25 16.57,85.7 16.57,84.61 v1(16.6,84.58)
  BOTTOM w0.254: v1(41.88,106.07) C508.1 ; v1(43.48,107.66) C512.1 ; C508.3 v1(41.08,105.26) ; v1(42.68,106.86) C512.3
  BOTTOM w0.305: C510.3 38.38,103.17 v1(38.68,102.87) 38.68,102.95 39.07,103.34 ; C246.1 36.95,105.26 v1(37.08,105.26) ; C248.1 39.93,104.81 v1(40.28,104.46) 39.87,104.05 C509.3 ; v1(37.08,102.87) 37.08,103.07 C510.1 ; v1(37.08,101.26) 37.12,101.3 C513.3 ; C511.1 37.97,106.06 v1(37.88,106.06) ; C511.3 38.79,105.37 v1(38.68,105.26) ; C513.1 38.64,101.3 v1(38.68,101.27) ; v1(44.28,106.86) 44.4,106.99 C227.1 ; C274.1 42.69,101.26 v1(42.68,101.27) ; 40.88,103.14 40.88,103.06 v1(41.08,102.87) 41.2,102.99 41.2,103.68 41.17,103.68 C260.1 40.88,103.14
  BOTTOM w0.381: v1(37.08,106.86) 36.93,106.71 C234.1
  vias: v1(15.71,97.95) v1(15.71,97.28) v1(15.71,96.42) v1(16.58,98.2) v1(16.58,97.28) v1(16.58,96.42) v1(17.44,100.03) v1(17.44,99.11) v1(17.44,98.2) v1(17.44,97.28) v1(17.44,96.42) v1(18.36,100.03) v1(18.36,99.11) v1(18.36,98.2) v1(18.36,97.28) v1(18.36,96.42) v1(19.19,100.03) v1(19.19,99.11) v1(19.19,98.2) v1(19.19,97.28) v1(20.03,98.99) v1(20.03,98.2) v1(20.03,97.28) v1(53.22,106.21) v1(54.13,106.21)
VDD_LPDDR4: length 133
  TOP w0.102: v1(42.73,87.67) 42.73,86.79 U26.U8 ; U26.F8 36.23,86.79 36.23,87.74 U26.F10 36.23,88.39 36.23,90.02 36.36,90.15
  TOP w0.254: v1(37.49,84.62) 37.49,84.59 37.47,84.56 37.46,84.56 37.21,84.31 U26.H5 ; U26.K10 v1(38.83,88.3) ; v1(35.89,84.69) 35.91,84.67 U26.F5 ; U26.U3 v1(42.73,82.07) ; U26.AA10 v1(45.98,87.67) U26.AB9 ; U26.AA8 45.66,85.91 v1(45.58,85.84) ; v1(32.33,83.67) U26.A4 U26.B5 v1(33.31,84.69) ; 43.06,84.06 U26.U5 43.06,84.3 v1(42.67,84.69) ; U26.N12 v1(40.46,90.1) ; U26.D5 v1(34.61,84.69) ; U26.N10 v1(40.13,88.3) ; U26.K3 38.97,82.46 v1(39.01,82.51) ; U26.AA3 v1(45.98,82.87) U26.AB4 ; U26.R5 v1(41.76,84.61) ; v1(44.25,90.29) 44.36,90.18 U26.W12 ; U26.N1 v1(40.13,80.24) ; v1(38.63,80.24) 38.51,80.37 U26.K1 ; v1(38.78,90.29) 38.78,89.94 U26.K12 ; U26.B3 v1(32.98,82.07) ; U26.D12 34.61,90.21 v1(34.66,90.26) ; U26.W8 44.36,86.09 v1(44.6,85.84) ; U26.AB4 46.63,83.59 ; U26.AB4 46.65,82.92 ; U26.W1 44.36,80.25 v1(44.36,80.24) ; U26.N3 39.99,82.46 v1(39.95,82.51) ; U26.AA5 45.66,84.62 v1(45.58,84.69) ; v1(43.06,85.84) 43.06,85.85 U26.U8 ; v1(41.61,80.24) 41.76,80.39 U26.R1 ; U26.D8 34.48,86.34 v1(34.48,85.84) ; U26.U10 v1(42.73,87.67) ; U26.F3 v1(35.58,82.07) ; U26.F10 v1(35.58,87.67) ; U26.B10 v1(32.98,87.67) U26.A9 ; U26.R8 41.76,86.03 ; U26.W5 44.36,84.5 v1(44.54,84.69) ; U26.A9 32.33,86.94 ; U26.A9 32.32,87.6 ; U26.B8 v1(33.31,85.84) ; U26.AB9 46.65,86.92 ; U26.AB9 46.63,87.59 ; U26.H12 37.21,90.26 v1(37.18,90.29) ; U26.F8 35.78,86.34 v1(35.78,85.84) ; U26.H1 37.21,80.37 v1(37.08,80.24) ; U26.H8 37.21,86.03 ; U26.R12 v1(41.76,90.9)
  TOP w0.305: U18.A2 v1(30.68,95.67) ; v1(34.39,80.1) 34.61,80.31 U26.D1 ; R119.1 v1(29.38,86.46) ; U27.50 17.24,75.24 18.03,74.45 v1(18.03,74.35) ; U18.B1 v1(31.48,94.87) ; R122.1 v1(29.38,84.07) ; U18.AA1 v1(47.48,94.87) ; U18.AB2 v1(48.28,95.67)
  TOP w0.356: v1(40.28,100.47) U18.M8 39.69,101.05 39.27,101.05 U18.L8 39.27,100.67 39.27,100.26 U18.L7 v1(38.68,99.67) ; U18.J7 v1(37.08,99.67) ; U18.K8 v1(37.88,100.47) ; U18.P8 v1(41.88,100.47) ; U18.N7 v1(41.08,99.67)
  L03_SIG01 w0.14: v1(18.03,74.35) 18.03,74.45 17.98,74.5 17.98,75.39 18.12,75.53 19.81,75.53 20.96,76.67 20.96,83.99 25.07,88.1 25.07,93.17 26.3,94.4 26.3,98.26 28.05,100.01 28.96,100.01 30.39,101.45 30.7,101.45 31.09,101.84 31.09,102.27 31.28,102.47 35.7,102.47 35.88,102.29 35.88,101.09 36.11,100.87 37.48,100.87 v1(37.88,100.47)
  L08_PWR03 w0.381: v1(38.68,99.67) v1(37.88,100.47) v1(37.08,99.67) ; v1(40.28,100.47) v1(41.08,99.67) v1(41.88,100.47)
  BOTTOM w0.14: 40.02,99.27 40.68,99.27 v1(41.08,99.67)
  BOTTOM w0.254: v1(41.08,99.67) v1(40.28,100.47) 40.08,100.47 39.99,100.56 ; C524.3 v1(47.48,94.87) ; v1(39.95,82.51) 39.89,82.57 C351.1 39.07,82.57 v1(39.01,82.51) ; C524.1 48.23,95.62 v1(48.28,95.67) ; C520.1 41.88,100.46 v1(41.88,100.47) ; C518.3 37.63,99.12 v1(37.08,99.67) v1(37.88,100.47) ; 40.02,99.27 39.87,99.27 39.29,99.85 39.1,99.67 v1(38.68,99.67) 38.68,98.97 C518.1 ; R352.2 43.92,91.53 C304.1
  BOTTOM w0.305: C365.1 41.72,80.36 v1(41.61,80.24) 41.61,79.79 41.04,79.22 R369.2 ; C341.1 34.63,84.71 v1(34.61,84.69) ; C348.1 41.49,84.35 v1(41.76,84.61) ; C366.1 34.48,80.18 v1(34.39,80.1) ; C333.1 33.34,85.88 v1(33.31,85.84) ; v1(37.49,84.62) 37.49,84.56 37.35,84.42 C342.1 ; C308.2 40.36,90.19 v1(40.46,90.1) ; C525.1 30.57,95.55 v1(30.68,95.67) 29.96,95.67 C295.1 ; v1(35.78,85.84) 35.78,85.92 C332.1 ; v1(38.78,90.29) 38.66,90.41 38.66,90.53 C306.1 ; v1(32.98,87.67) 32.76,87.45 C324.1 ; v1(32.98,82.07) 33.01,82.09 C352.1 ; R370.2 v1(37.7,79.46) ; C316.2 36.81,89.92 v1(37.18,90.29) ; C299.1 31.48,94.23 v1(31.48,94.87) 31.37,94.75 31.28,94.75 ; v1(48.28,95.67) 48.4,95.79 C294.1 ; C367.1 44.43,80.17 v1(44.36,80.24) ; C343.1 32.09,83.91 v1(32.33,83.67) ; C315.1 34.61,89.86 34.61,90.21 v1(34.66,90.26) 34.66,90.29 34.45,90.49 C305.1 ; v1(38.63,80.24) 38.63,80.38 C362.1 ; C373.1 v1(33.46,80.1) ; C331.1 34.48,86.14 v1(34.48,85.84) ; v1(44.6,85.84) 44.42,85.66 C337.1 44.42,84.81 v1(44.54,84.69) ; v1(37.08,80.24) 37.02,80.3 C364.1 ; C353.1 46.13,82.72 v1(45.98,82.87) ; v1(44.25,90.29) 44.47,90.5 C304.1 ; C321.1 38.65,88.48 v1(38.83,88.3) ; v1(45.58,84.69) 45.75,84.85 C336.1 45.75,85.68 v1(45.58,85.84) ; v1(33.31,84.69) 33.14,84.53 C347.1 ; v1(40.13,80.24) 40.17,80.2 C369.2 ; v1(41.76,90.9) 41.37,91.28 C303.1 ; v1(42.73,87.67) 42.88,87.82 C323.1 ; C359.1 42.99,81.8 v1(42.73,82.07) ; C325.1 46.02,87.7 v1(45.98,87.67) ; v1(38.19,92.59) 38.22,92.57 C517.3 ; v1(47.48,94.87) 47.6,94.74 C298.1 ; C338.2 36.03,84.83 v1(35.89,84.69) ; v1(40.13,88.3) 40.31,88.48 C320.1 ; C517.1 40.24,92.18 v1(40.24,92.57) ; C377.1 v1(44.54,79.35) ; C335.1 v1(42.67,84.69)
  vias: v1(32.04,78.45) v1(32.04,77.53) v1(32.04,76.62) v1(32.95,78.45) v1(32.95,77.53) v1(32.95,76.62) v1(33.87,78.45) v1(33.87,77.53) v1(33.87,76.62)
VDD_MMC1: length 2.5
  TOP w0.254: U20.5 7.35,101.89 7.61,101.64 7.61,101.18 7.37,100.94 U20.6
VDD_MMC1_SD: length 1.5
  BOTTOM w0.381: v1(5.92,97.2) 5.67,97.46 J22.4
  vias: v1(5.92,97.84)
VDDA1V8: length 4.2
  TOP w0.254: TP40.1 v1(43.11,72.3)
  TOP w0.305: C84.1 23.47,78.84 v1(22.85,78.84) 22.15,79.54 U27.7
  L08_PWR03 w0.457: v1(22.85,78.84) v1(22.85,78.28)
  vias: v1(43.11,73.22)
VDDA_1V8: length 49.1
  TOP w0.305: C515.3 v1(54.57,109.74) ; FL1.1 v1(61.2,133.08) ; C515.1 v1(51.89,109.74) ; C30.1 52.25,108.17 v1(52.2,108.22)
  TOP w0.356: U18.G18 v1(35.48,109.26) ; U18.T10 v1(43.48,102.07) ; U18.L10 v1(38.68,102.07) ; U18.P16 v1(41.88,107.66)
  L07_PWR02 w0.457: v1(25.76,90.11) 25.76,89.12 28.18,86.69 28.18,83.73 29.33,82.58 29.33,77.47 31.17,75.63 41.15,75.63 41.22,75.56 v1(47.43,75.56)
  L08_PWR03 w0.381: v1(47.43,75.56) v1(48.34,75.56)
  BOTTOM w0.254: C516.1 v1(54.44,108.22) ; C214.1 52.25,110.1 v1(51.89,109.74) 52.3,109.34 C215.1 ; C516.3 v1(52.2,108.22)
  BOTTOM w0.305: v1(41.88,107.66) 42,107.54 C228.1 ; C266.1 43.46,102.08 v1(43.48,102.07) ; C263.1 38.78,102.07 v1(38.68,102.07) ; v1(35.48,109.26) 35.36,109.14 C216.1
  BOTTOM w0.381: v1(25.76,90.11) 26.28,90.63 26.28,93.82 25.83,94.26 FL10.1
  BOTTOM w0.457: v1(53.16,107.02) 52.96,106.82 FL7.1
  vias: v1(53.93,99.94) v1(53.93,99.1)
VDDA_1V8_FB1: length 5.4
  TOP w0.254: U18.K13 v1(37.88,105.26) ; U18.M13 v1(40.28,105.26) ; U18.J10 v1(37.08,102.07) ; U18.R11 v1(42.68,102.87) ; U18.N9 v1(41.08,101.27) ; U18.K10 v1(37.88,102.07)
  BOTTOM w0.305: C243.1 37.73,105.11 v1(37.88,105.26) ; v1(37.88,102.07) 37.38,102.07 C265.1 v1(37.08,102.07) ; v1(42.68,102.87) 42.56,102.99 C262.1 ; C245.1 v1(40.28,105.26) ; C278.1 40.95,101.27 v1(41.08,101.27)
  vias: v1(51.69,100.09) v1(51.69,99.18)
VDDA_1V8_FB2: length 21.8
  TOP w0.356: U18.T12 v1(43.48,104.46)
  L06_PWR01 w0.381: v1(50.6,106.19) 50.83,105.95 50.83,104.85 49.91,103.93 44.02,103.93 v1(43.48,104.46)
  L07_PWR02 w0.381: v1(50.6,106.19) 50.83,105.95 50.83,104.85 49.91,103.93 44.02,103.93 v1(43.48,104.46)
  BOTTOM w0.254: FL7.2 51.8,105.9 51.62,106.08 C236.1 50.7,106.08 v1(50.6,106.19) ; C254.1 43.6,104.34 v1(43.48,104.46)
VDDA_1V8_FB_OSC: length 22.3
  TOP w0.254: v1(26.72,96.97) 26.65,96.89 C56.1
  TOP w0.356: U18.J8 v1(37.08,100.47)
  L06_PWR01 w0.165: 31.11,100.07 36.68,100.07 v1(37.08,100.47) 36.68,100.87 31.11,100.87 30.71,100.47 31.11,100.07
  L06_PWR01 w0.381: v1(26.72,96.97) 28.6,98.84 29.36,98.84 29.87,99.35 29.87,100.09 30.25,100.47 30.71,100.47
  BOTTOM w0.305: 36.88,100.26 v1(37.08,100.47)
  BOTTOM w0.381: FL10.2 25.83,96.71 26.09,96.97 v1(26.72,96.97)
VDDA_CORE_CSI: length 21.2
  TOP w0.254: FL3.2 51.91,104 v1(51.88,103.98)
  TOP w0.356: U18.T11 v1(43.48,102.87)
  L06_PWR01 w0.381: v1(51.88,103.98) 51.3,103.39 44.01,103.39 v1(43.48,102.87)
  L07_PWR02 w0.381: v1(51.88,103.98) 51.3,103.39 44.01,103.39 v1(43.48,102.87)
  BOTTOM w0.254: 43.21,103.4 43.21,103.13 v1(43.48,102.87) ; C252.1 v1(51.88,103.98) C251.1
  BOTTOM w0.305: C261.1 43.6,102.99 v1(43.48,102.87)
VDDA_CORE_USB: length 13.7
  TOP w0.254: FL4.2 v1(51.88,102.07)
  TOP w0.356: U18.T9 v1(43.48,101.27)
  L08_PWR03 w0.165: 48.44,101.67 43.88,101.67 v1(43.48,101.27) 43.88,100.87 48.8,100.87
  BOTTOM w0.254: v1(51.88,102.07) 52.28,102.07 C272.1 C271.1
  BOTTOM w0.305: C275.1 43.5,101.28 v1(43.48,101.27)
VDDA_DDR_PLL0: length 28.4
  TOP w0.356: U18.M9 v1(40.28,101.27)
  L07_PWR02 w0.165: 30.42,98.47 37.29,98.47 37.71,98.89 37.33,99.27 30.42,99.27 30.02,98.87 30.42,98.47
  L07_PWR02 w0.305: 37.71,98.89 38.64,98.89 39.32,99.57 39.32,100.31 v1(40.28,101.27) ; 30.02,98.87 26.8,98.87 25.6,97.66 v1(25.26,97.66)
  BOTTOM w0.254: 25.26,97.8 25.26,97.82 24.97,98.11 24.38,98.11 24.36,98.13 ; 25.26,97.8 25.52,98.06 C292.1 ; 25.26,97.8 v1(25.26,97.66)
  BOTTOM w0.305: v1(40.28,101.27) 39.87,101.27 C269.1
VDDA_LM5141: length 2.8
  BOTTOM w0.254: U89.19 35.53,43.2 v1(35.71,43.02) ; v1(30.71,43.9) C421.2 v1(31.36,44.59) ; U89.5 v1(31.73,46.36)
VDDA_SYS_MON: length 16.5
  TOP w0.305: R80.2 23.05,102.91 v1(23.55,102.91)
  TOP w0.356: U18.H12 v1(36.28,104.46)
  L07_PWR02 w0.254: v1(23.55,102.91) 24.58,103.94 28.19,103.94 28.93,104.68 29.82,104.68 30.57,103.94 35.75,103.94 v1(36.28,104.46)
  BOTTOM w0.254: v1(23.55,102.91) 23.3,102.91 R332.1
VDDC_1V2: length 5.6
  TOP w0.203: U47.115 53.42,15.03 ; U47.87 59.57,22.75 v1(59.37,22.55)
  TOP w0.254: v1(50.84,14.82) 51.05,15.03 C154.1 C153.1 53.42,15.03
  BOTTOM w0.254: C464.2 59.55,22.73 v1(59.37,22.55)
VDDIM: length 4
  TOP w0.102: 54.36,81.5 v1(54.36,81.51) 54.61,81.76 55.17,81.76 U28.C2 55.17,81.26 54.6,81.26 54.36,81.5
  BOTTOM w0.254: C356.1 54.15,81.72 v1(54.36,81.51) C357.1
VDDR_CORE: length 54.9
  TOP w0.254: 23.57,94.93 23.57,94.25 23.66,94.17 ; v1(23.5,97.38) 23.5,97.35 23.76,97.09 C526.3
  TOP w0.356: U18.P12 v1(41.88,104.46) ; U18.K12 v1(37.88,104.46) ; U18.P9 v1(41.88,101.26) ; U18.J14 v1(37.08,106.07) ; U18.M10 v1(40.28,102.07) ; U18.M14 v1(40.28,106.06)
  L10_SIG03 w0.381: v1(5.73,69.38) 7.13,67.98 11.64,67.98 13.61,66.01 20.49,66.01 21.18,66.69 21.18,91.67 v1(22.88,93.38)
  BOTTOM w0.254: C527.1 v1(29.51,102.38) ; v1(5.73,69.38) 3.4,69.38 R384.1 ; C527.3 v1(27.49,102.38)
  BOTTOM w0.305: C273.1 v1(41.88,101.26) ; C268.1 40.28,101.94 v1(40.28,102.07) ; C250.1 37.88,104.47 v1(37.88,104.46) ; v1(41.88,104.46) 42,104.34 C253.1 ; C237.1 40.4,106.18 v1(40.28,106.06)
  vias: v1(23.66,94.12) v1(23.66,93.38) v1(23.66,92.64)
VDDSHV_SDIO: length 60.6
  TOP w0.254: R90.2 9.02,99.35 R91.2 ; R91.2 8.21,99.67 v1(8.41,99.87) ; R91.2 7.14,99.35 R92.2 ; R100.2 R99.2 ; R99.2 7.92,93.75 v1(8.2,93.46) ; R99.2 R98.2 ; C57.2 9.88,96.25 9.88,96.4 v1(9.75,96.52) 9.47,96.81 U22.10 ; v1(22.43,83.26) 22.79,83.26 23.04,83.51 TP34.1
  TOP w0.305: U27.13 22.07,82.54 22.43,82.9 v1(22.43,83.26)
  TOP w0.381: v1(20.93,106.87) 21.09,107.03 C31.1 21.7,107.06 R61.1
  L07_PWR02 w0.508: v1(8.2,93.46) 9.88,91.79 9.88,88.99 12.37,86.49 19.72,86.49 21.29,84.92 21.29,84.4 v1(22.43,83.26)
  BOTTOM w0.381: v1(8.2,93.46) 9.11,94.37 9.11,95.88 v1(9.75,96.52) 9.53,96.75 9.53,98.75 v1(8.41,99.87) 8.41,103.36 10.81,105.76 15.17,105.76 16.17,104.75 20.3,104.75 21.35,105.8 21.35,106.45 v1(20.93,106.87) ; C350.1 22.78,82.91 v1(22.43,83.26)
VINT_PMIC_1V8: length 3.2
  TOP w0.305: U27.2 21.82,77.04 TP101.1 22.71,76.15 22.86,76.15 C382.1
ADCIN1: length 3.7
  BOTTOM w0.14: U90.6 16.57,44.56 16.28,44.84 15.71,44.84 R428.2 15.52,44.37 15.34,44.2 14.68,44.2 14.35,44.53 R429.1
ADCIN2: length 3.1
  BOTTOM w0.14: U90.10 16.03,46.16 15.88,46 R425.2 14.99,46 14.79,45.8 R424.1
ADDR_IO_EXP: length 1.6
  BOTTOM w0.14: R452.2 55.83,39.24 55.7,39.36 U92.26
ADDR_IO_EXP1: length 1.3
  TOP w0.14: R1.1 51.51,153.29 U2.26
AUD_RSTN: length 15.5
  L03_SIG01 w0.102: v1(64.47,40.58) 64.47,43.4 65.48,44.41 65.48,45.45 v1(69.01,48.98)
  BOTTOM w0.14: v1(64.47,40.58) 64.46,40.59 R450.2 63.24,41.13 62.54,40.43 U93.4 ; U88.33 70.26,49.29 69.95,48.98 v1(69.01,48.98)
AUDIO_EXT_REFCLK1: length 12.8
  TOP w0.14: R42.2 26.7,124.15 26.7,122.9 27.71,121.88 27.71,116.24 26.98,115.51 26.98,113.55 R55.1
AUDIO_MSTRCLK: length 1.4
  BOTTOM w0.14: R407.1 U88.37
AUTO_100M_1000M_CONFIG: length 41.1
  TOP w0.14: v1(57.27,117.48) 57.07,117.68 J4.26 ; v1(54.57,151.08) 54.06,150.56 U2.22
  L03_SIG01 w0.102: v1(54.96,136.79) 56.03,137.85 56.03,150.54 55.49,151.08 v1(54.57,151.08)
  L10_SIG03 w0.102: v1(54.96,136.79) 56.29,135.46 56.29,126.19 59.1,123.38 59.1,118.28 58.7,117.88 57.67,117.88 v1(57.27,117.48)
BOOTMODE0: length 25.5
  L05_SIG02 w0.102: v1(39.44,38.31) 38.97,38.78 38.97,40.04 38.46,40.55 32.26,40.55 30.33,38.62 30.33,33.01 v1(34.35,28.99)
  BOTTOM w0.14: U101.14 34.85,28.49 v1(34.35,28.99) ; RA5.1 39.58,38.45 v1(39.44,38.31)
BOOTMODE1: length 20.7
  L05_SIG02 w0.102: v1(35.37,28.99) 34.77,29.59 34.77,30.18 32.6,32.35 31.86,32.35 30.82,33.39 30.82,36.14 33.15,38.47 38.36,38.47 v1(38.52,38.31)
  BOTTOM w0.14: v1(38.52,38.31) 39.06,38.85 RA5.2 ; U101.15 v1(35.37,28.99)
BOOTMODE2: length 21.4
  L05_SIG02 w0.102: v1(38.52,39.79) 37.46,38.73 32.98,38.73 30.58,36.32 30.58,33.14 33.73,29.99 v1(34.35,29.99)
  BOTTOM w0.14: RA5.3 39.06,39.25 v1(38.52,39.79) ; U101.16 34.85,29.49 v1(34.35,29.99)
BOOTMODE3: length 21.6
  L05_SIG02 w0.102: v1(39.44,39.79) 39.88,39.35 39.88,37.25 39.42,36.79 32.01,36.79 31.05,35.84 31.05,33.61 32,32.66 32.71,32.66 v1(35.37,29.99)
  BOTTOM w0.14: U101.17 v1(35.37,29.99) ; v1(39.44,39.79) 39.58,39.65 RA5.4
BOOTMODE4: length 5.9
  BOTTOM w0.14: U101.18 32.54,30.49 31.78,31.25 RA6.4
BOOTMODE5: length 5.1
  BOTTOM w0.14: RA6.3 32.18,31.5 32.68,30.99 U101.19
BOOTMODE6: length 4.4
  BOTTOM w0.14: RA6.2 32.58,31.75 32.84,31.49 U101.20
BOOTMODE7: length 3.5
  BOTTOM w0.14: U101.21 33.16,31.99 32.98,32.18 RA6.1
BOOTMODE8: length 114.1
  L05_SIG02 w0.102: v1(57.15,34.02) 55.76,35.42 53.52,35.42 51.25,37.69 51.25,38.87 48.89,41.22 45.81,41.22 45.3,41.74 45.3,43.29 42.31,46.28 42.31,49.28 34.69,56.9 23.97,56.9 22.68,58.18 16.19,58.18 12.99,61.38 12.99,65.62 13.25,65.89 13.25,73.99 13.82,74.56 13.82,75.93 14.9,77.01 14.9,82.8 14.71,82.99 14.71,83.62 15.11,84.02 15.11,88.32 15.65,88.86 15.65,92.83 15.88,93.05 15.88,95.39 15.06,96.2 15.06,98.23 16.21,99.38 16.21,101.66 20.17,105.62 21.08,105.62 22.13,106.67 v1(22.13,109.87)
  BOTTOM w0.14: RA3.1 v1(22.13,109.87) ; U98.14 56.78,33.65 v1(57.15,34.02)
BOOTMODE9: length 115.8
  L05_SIG02 w0.102: v1(58.04,34) 57.69,33.64 56.92,33.64 55.4,35.17 52.43,35.17 50.24,37.36 50.24,39.49 48.82,40.92 45.8,40.92 45.06,41.66 45.06,43.18 41.43,46.81 41.43,48.77 34.18,56.01 23.97,56.01 22.02,57.95 16.06,57.95 12.75,61.26 12.75,65.75 13.02,66.03 13.02,74.11 13.59,74.68 13.59,78.83 14.07,79.3 14.07,81.99 13.65,82.4 13.65,91.31 15.62,93.29 15.62,95.32 14.82,96.12 14.82,98.31 15.97,99.46 15.97,101.84 20.45,106.32 20.45,106.97 20.8,107.33 21.09,107.33 21.39,107.63 v1(21.39,109.23)
  BOTTOM w0.14: v1(21.39,109.23) 21.19,109.43 RA3.2 ; v1(58.04,34) 57.38,33.33 56.96,33.33 56.78,33.15 U98.15
BOOTMODE10: length 114.3
  L05_SIG02 w0.102: v1(20.79,108.55) 20.44,108.55 18.7,106.81 18.7,106.05 15.16,102.51 15.16,98.97 14.61,98.42 14.61,98.42 14.59,98.41 14.59,96.02 15.39,95.22 15.39,93.38 13.22,91.21 13.22,74.7 12.8,74.27 12.8,66.24 12.5,65.95 12.5,61.15 16.14,57.51 18.67,57.51 19.37,56.81 22.62,56.81 24.42,55 34.84,55 41.18,48.67 41.18,46.72 44.8,43.1 44.8,41.43 45.57,40.66 48.67,40.66 50.01,39.33 50.01,36.35 51.48,34.89 55.1,34.89 v1(57.15,32.83)
  BOTTOM w0.14: U98.16 57.01,32.65 57.15,32.79 v1(57.15,32.83) ; v1(20.79,108.55) RA3.3
BOOTMODE11: length 116.3
  L05_SIG02 w0.102: v1(20.25,109.12) 20.25,108.88 18.38,107.01 18.38,106.12 14.92,102.66 14.92,99.13 14.36,98.57 14.36,95 14.93,94.44 14.93,93.27 12.97,91.31 12.97,74.88 12.56,74.47 12.56,66.42 12.23,66.08 12.23,61.09 16.12,57.2 18.52,57.2 19.8,55.92 23.07,55.92 23.92,55.07 23.92,54.46 24.27,54.11 35.4,54.11 40.78,48.73 40.78,46.69 44.54,42.93 44.54,41.32 45.5,40.36 47.55,40.36 49.78,38.13 49.78,36.18 51.36,34.61 54.82,34.61 57.03,32.4 57.66,32.4 v1(58.07,32.81)
  BOTTOM w0.14: U98.17 57.42,32.15 v1(58.07,32.81) ; RA3.4 20.39,109.27 v1(20.25,109.12)
BOOTMODE12: length 118.2
  L05_SIG02 w0.102: v1(58.73,32.19) 58.69,32.14 56.9,32.14 54.74,34.3 50.72,34.3 47.73,37.3 47.05,37.3 44.59,39.75 43.66,39.75 42.67,40.74 42.67,43.63 39.78,46.52 39.78,46.98 39.42,47.33 39.13,47.33 36.52,49.95 36.52,51.51 34.15,53.88 23.7,53.88 21.94,55.64 21.75,55.64 19.99,55.64 19.97,55.63 18.72,55.63 18.34,55.25 17.33,55.25 11.35,61.22 11.35,67.85 11.63,68.13 11.63,74.43 12.74,75.54 12.74,91.89 13.84,92.99 13.84,93.59 14.13,93.88 14.13,95.87 13.82,96.18 13.82,100.93 14.07,101.18 14.07,102.25 18.06,106.24 18.06,107.24 19.79,108.96 v1(19.79,109.87)
  BOTTOM w0.14: U98.18 57.39,31.65 57.93,32.19 v1(58.73,32.19) ; RA4.1 v1(19.79,109.87)
BOOTMODE13: length 118.2
  L05_SIG02 w0.102: v1(58.04,31.36) 56.84,31.36 56.62,31.58 54.98,31.58 54.48,32.08 54.3,32.08 53.8,32.58 52.99,32.58 52.47,33.1 49.62,33.1 48.65,34.07 46.57,34.07 44.95,35.7 44.95,36.25 43.13,38.06 41.95,38.06 40.72,39.29 40.72,39.94 39.35,41.31 39.35,44.64 39.09,44.9 38.71,44.9 34.06,49.54 31.02,49.54 27.37,53.19 23.35,53.19 22.41,54.14 20.77,54.14 20.42,54.5 17.43,54.5 10.59,61.34 10.59,66.88 9.65,67.81 9.65,74.13 10.06,74.53 10.06,76.01 12.5,78.45 12.5,92.07 13.56,93.13 13.56,93.76 13.9,94.1 13.9,95.71 13.51,96.11 13.51,98.18 12.96,98.73 12.96,100.47 13.83,101.34 13.83,102.43 17.76,106.36 17.76,107.58 v1(19.18,109.01)
  BOTTOM w0.14: v1(19.18,109.01) 18.94,109.24 RA4.2 ; U98.19 57.61,31.15 57.82,31.36 v1(58.04,31.36)
BOOTMODE14: length 118.4
  L05_SIG02 w0.102: v1(18.34,109.18) 18.34,108.69 16.9,107.26 16.9,106.04 13.06,102.2 13.06,101 12.07,100.01 12.07,99.12 13.09,98.1 13.09,93.04 11.6,91.55 11.6,80.94 10.9,80.24 10.9,77.25 8.89,75.24 8.89,67.73 9.67,66.95 9.67,62.24 10.24,61.67 10.24,61.32 17.31,54.24 20.35,54.24 20.69,53.9 22.24,53.9 23.18,52.96 24.17,52.96 25.34,51.79 28.45,51.79 31.15,49.09 33.7,49.09 36.53,46.26 36.53,45.31 37.25,44.59 37.97,44.59 38.38,44.17 38.38,41.49 38.76,41.11 39.14,41.11 40.44,39.82 40.44,38.16 40.82,37.78 42.42,37.78 44.05,36.16 44.05,35.79 46.6,33.24 47.57,33.24 49.27,31.54 51.14,31.54 51.66,32.07 52.3,32.07 53.03,31.34 53.88,31.34 54.23,30.98 54.74,30.98 55.02,31.26 55.63,31.26 56.24,30.65 v1(57.13,30.65)
  BOTTOM w0.14: v1(57.13,30.65) U98.20 ; RA4.3 18.54,109.39 v1(18.34,109.18)
BOOTMODE15: length 121.5
  L05_SIG02 w0.102: v1(58.04,30.6) 57.62,30.18 55.13,30.18 54.65,30.66 54.24,30.66 53.92,30.34 53.13,30.34 52.38,31.1 51.78,31.1 51.36,30.67 49.01,30.67 46.93,32.75 45.95,32.75 42.17,36.54 41.46,36.54 40.19,37.81 40.19,39.66 39.07,40.78 38.03,40.78 36.15,42.66 36.15,46.31 33.6,48.86 31.06,48.86 28.42,51.5 25.21,51.5 24.73,51.98 23.35,51.98 23.05,52.27 23.05,52.63 22.16,53.52 21.21,53.52 21.06,53.37 17.83,53.37 11.3,59.9 10.71,59.9 8.91,61.71 8.91,67.39 8.66,67.64 8.66,75.51 10.67,77.52 10.67,80.47 11.32,81.12 11.32,91.66 12.31,92.65 12.31,98.56 11.84,99.03 11.84,99.22 11.84,100.14 12.04,100.34 12.04,101.31 12.23,101.49 12.58,101.49 12.8,101.72 12.8,102.35 16.12,105.67 16.12,107.02 17.57,108.47 v1(17.57,109.49)
  BOTTOM w0.14: U98.21 57.6,30.15 v1(58.04,30.6) ; v1(17.57,109.49) 17.95,109.87 RA4.4
BOOTMODE_I2C_EN: length 5.4
  BOTTOM w0.14: R474.1 73.17,31.72 R473.2 72.59,32.95 72.38,33.15 70.94,33.15 70.43,33.66 U99.5
BOOTMODE_I2C_SCL: length 58.8
  TOP w0.14: TP77.1 73.97,27.55 v1(73.96,27.55)
  L03_SIG01 w0.102: v1(65.97,16.12) 67.65,16.12 70.72,19.19 71.81,19.19 72.94,20.33 72.94,23.33 73.36,23.74 73.36,25.13 74.25,26.02 74.25,27.27 v1(73.96,27.55) 73.08,28.44 73.08,30.22 v1(72.21,31.09)
  L05_SIG02 w0.102: v1(65.97,16.12) 66.41,16.57 66.41,17.44 65.54,18.3 64.67,18.3 63.33,19.65 61.28,19.65 60.29,18.66 57.65,18.66 56.68,17.69 v1(55.74,17.69)
  BOTTOM w0.14: R478.1 v1(72.21,31.09) ; v1(65.97,16.12) 66,16.09 R559.2 ; v1(55.74,17.69) 55.74,17.08 54.96,16.3 R549.1 54.12,16.73 54.12,23.86 51.59,26.4 47.07,26.4 46.58,25.91 45.82,25.91 45.13,26.6 U100.29
BOOTMODE_I2C_SDA: length 63.9
  TOP w0.14: v1(50.38,15.89) 50.38,16.18 TP86.1
  L03_SIG01 w0.102: v1(72.21,32.39) 71.6,31.78 71.6,30.92 72,30.51 72.28,30.51 72.65,30.14 72.65,24.94 72.46,24.74 72.46,21.06 71.71,20.31 70.59,20.31 67.85,17.57 66.36,17.57 v1(65.97,17.18)
  L05_SIG02 w0.102: v1(50.38,15.89) 50.81,15.89 51.82,14.87 53.93,14.87 54.59,15.53 59.64,15.53 60.35,16.24 62.27,16.24 62.8,16.78 62.8,17.34 63.45,17.98 65.16,17.98 v1(65.97,17.18)
  BOTTOM w0.14: R543.2 68.06,17.31 67.8,17.56 66.35,17.56 v1(65.97,17.18) ; R476.1 v1(72.21,32.39) ; v1(50.38,15.89) 50.79,16.3 R551.1 51.46,16.81 53.22,18.57 53.22,23.66 51.54,25.34 50.62,25.34 49.85,26.1 47.29,26.1 46.78,25.59 45.48,25.59 44.63,26.44 U100.30
BOOTMODEON: length 45.8
  TOP w0.14: U45.4 71.45,26.36 71.27,26.18 R221.2 69.42,25.01 v1(69.21,24.79)
  L05_SIG02 w0.102: v1(69.21,24.79) 68.71,25.29 66.7,25.29 65.9,26.09 60.69,26.09 v1(57.13,29.65)
  L10_SIG03 w0.102: v1(57.13,29.65) 55.42,31.36 55.1,31.36 53.9,32.55 52.91,32.55 52.33,33.14 43.84,33.14 43.21,32.5 41.48,32.5 40.82,33.16 36.65,33.16 35.99,32.49 v1(34.5,32.49)
  BOTTOM w0.14: v1(34.5,32.49) U101.22 ; U98.22 v1(57.13,29.65)
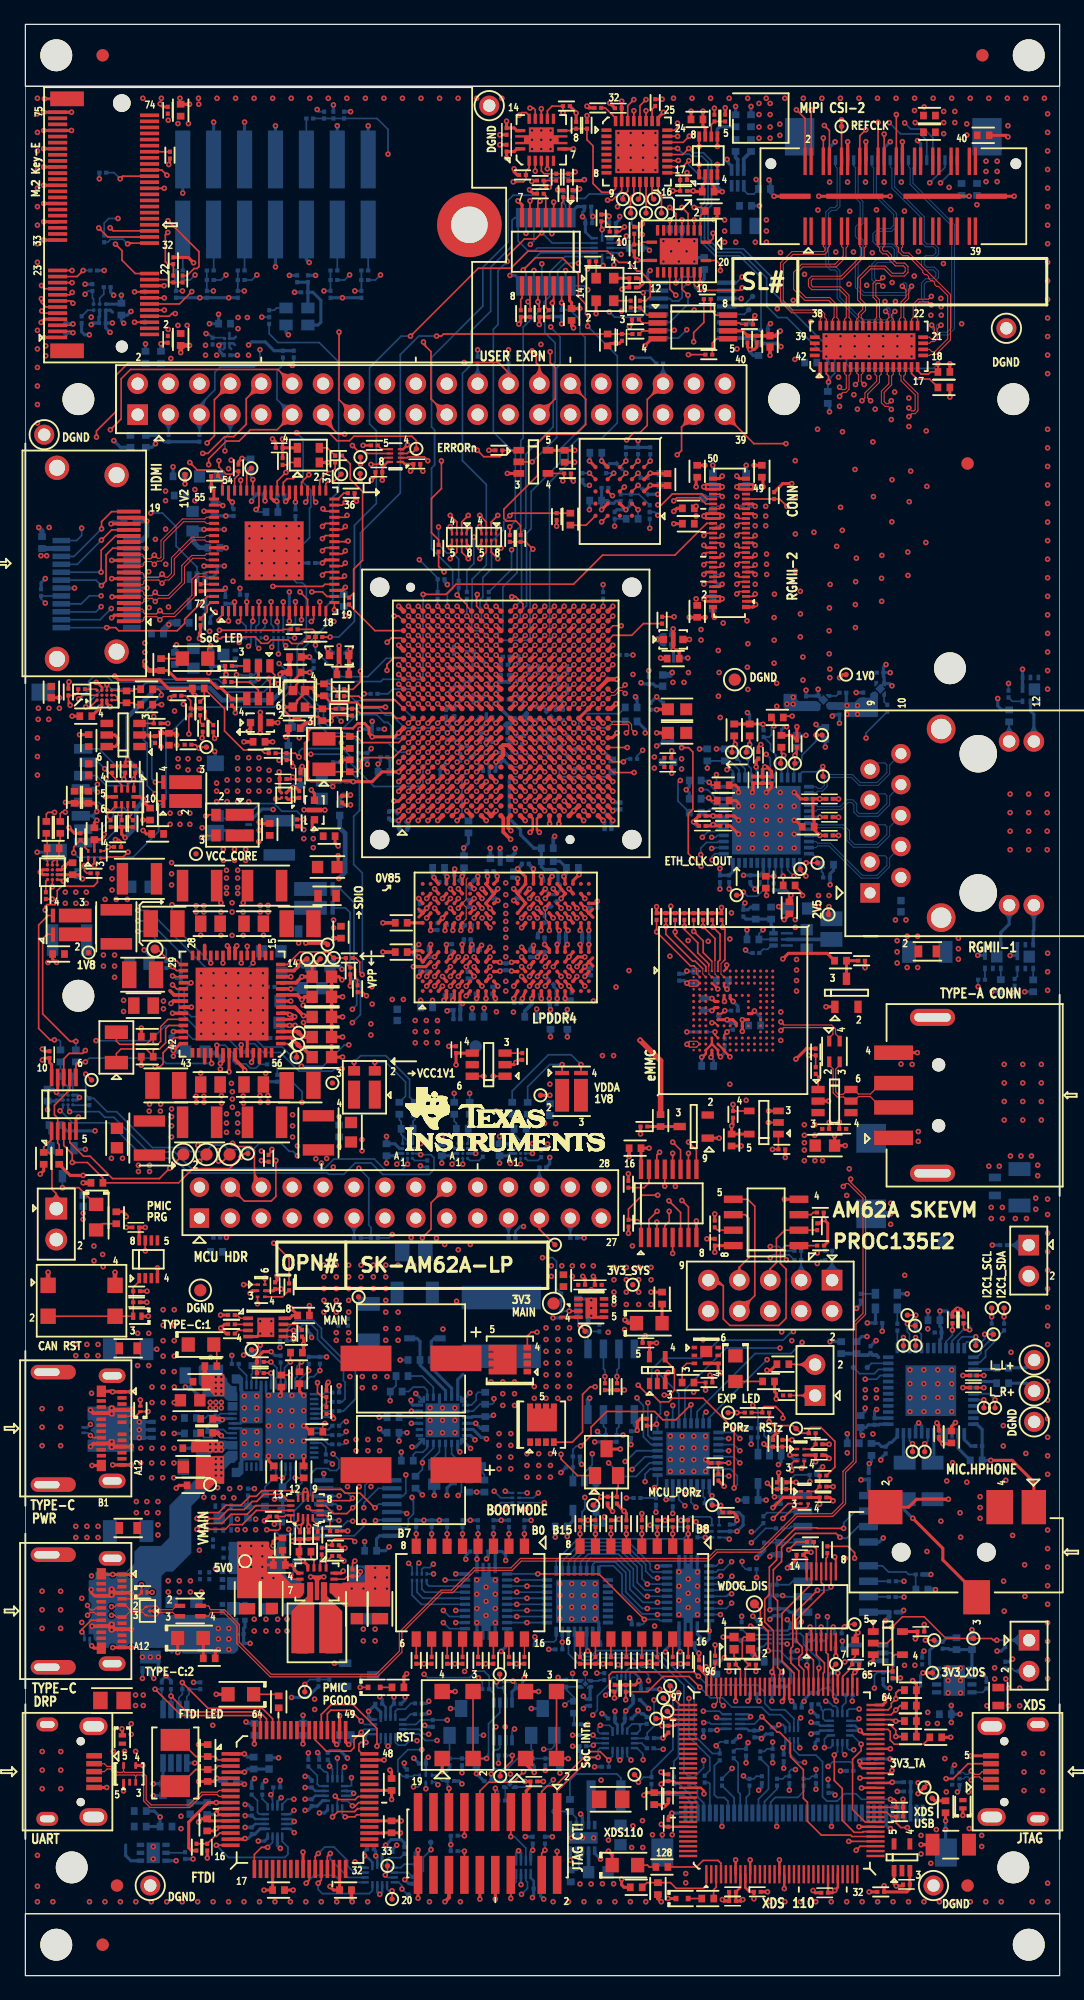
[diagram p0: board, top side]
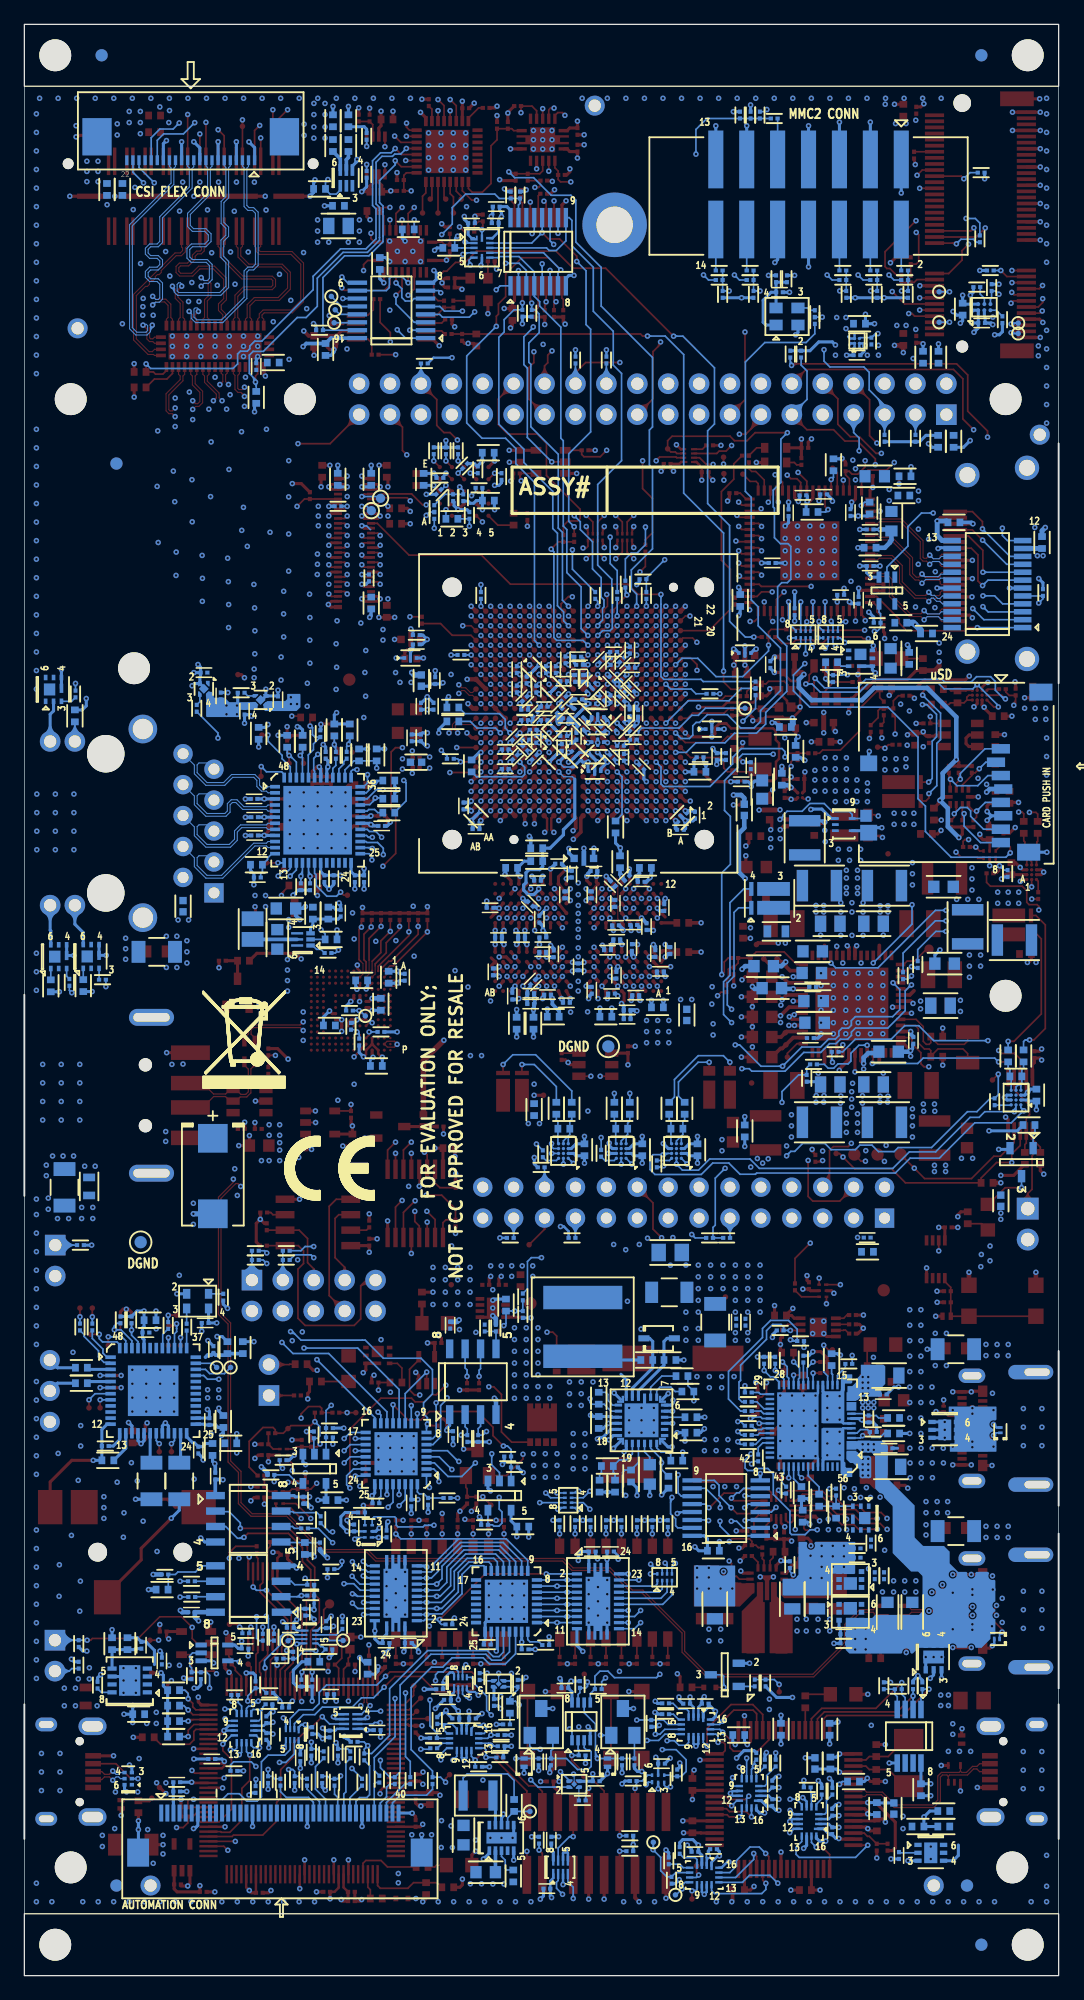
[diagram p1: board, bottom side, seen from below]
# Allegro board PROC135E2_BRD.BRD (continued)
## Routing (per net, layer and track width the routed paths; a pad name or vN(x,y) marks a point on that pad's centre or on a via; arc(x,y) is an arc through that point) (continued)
BT_EN_SOC: length 177.7
  TOP w0.14: v1(7.79,147.57) 8.01,147.79 J2.54
  L03_SIG01 w0.102: v1(16.79,39.99) 16.47,39.67 15.37,39.67 14.31,40.73 14.31,54.64 11.27,57.68 8.72,57.68 7.17,59.23 v1(6.35,59.23)
  L05_SIG02 w0.102: v1(11.96,132.81) 11.94,132.83 11.94,134.13 9.84,136.23 9.84,145.52 v1(7.79,147.57)
  L10_SIG03 w0.102: v1(16.79,39.99) 17.14,39.99 17.75,39.38 19.6,39.38 19.73,39.52 21.55,39.52 22.09,38.98 23.56,38.98 23.71,38.82 29.7,38.82 29.91,38.62 35.62,38.62 36.51,39.51 36.51,40.71 38.85,43.05 40.17,43.05 40.78,43.66 44.87,43.66 46.42,42.11 v1(47.93,42.11) ; v1(6.35,59.23) 1.94,59.23 1.34,59.83 1.34,64.64 2.29,65.59 2.29,71.21 3.81,72.73 4.4,72.73 7.37,75.71 7.37,80.81 7.8,81.24 7.8,84.09 4.68,87.21 4.24,87.21 3.76,87.69 3.76,89.96 3.88,90.08 3.88,91.49 3.52,91.85 3.52,92.71 5.48,94.67 5.48,98.69 5.69,98.91 5.69,105.14 5.26,105.58 5.26,108.19 7.85,110.78 7.85,121.3 9.65,123.1 9.65,125.6 7.82,127.42 7.82,131.36 9.28,132.81 v1(11.96,132.81)
  BOTTOM w0.14: v1(47.93,42.11) 49.05,41 50.18,41 51.3,42.11 U92.3 ; R250.1 7.29,148.08 v1(7.79,147.57)
BT_UART_WAKE_SOC_1V8: length 44.6
  TOP w0.14: v1(11.72,144.13) 14.27,141.59 14.27,140.36 14.11,140.21 13.87,140.21 13.28,139.62 R25.2 ; U1.3 v1(41.9,148.2)
  L05_SIG02 w0.102: v1(41.9,148.2) 41.24,148.86 39.16,148.86 37.41,150.62 29.1,150.62 26.78,148.3 11.28,148.3 10.83,147.86 10.83,145.02 v1(11.72,144.13)
BT_UART_WAKE_SOC_3V3: length 183.6
  TOP w0.14: v1(41.47,153.38) 41.76,153.38 41.9,153.24 U1.12 ; v1(11.7,143.17) 11.5,142.97 11.5,140.77 11.71,140.56 R22.1 R24.2
  L03_SIG01 w0.102: v1(41.47,153.38) 41.47,152.76 40.66,151.95 40.66,148.9 40.95,148.6 40.95,144.04 45.78,139.21 47.47,139.21 52.02,134.66 57.42,134.66 v1(58.48,133.6)
  L05_SIG02 w0.102: v1(41.47,153.38) 41.47,152.53 40.72,151.78 29.39,151.78 27.41,149.81 12.06,149.81 10.51,148.26 10.51,144.36 v1(11.7,143.17) ; v1(58.48,133.6) 59.49,134.61 62.38,134.61 64.75,132.25 64.75,131.12 65.62,130.25 65.62,110.15 67.32,108.45 67.32,106.35 66.8,105.84 66.8,103.34 66.37,102.91 66.37,99.4 65.71,98.74 65.71,90.91 66.66,89.97 66.66,78.5 67.34,77.83 67.34,68.97 66.6,68.24 66.6,64.02 67.44,63.18 67.44,54.04 66.35,52.95 65.36,52.95 63.95,51.54 v1(62.02,51.54)
  BOTTOM w0.14: U92.12 54.2,48.14 57.6,51.54 v1(62.02,51.54)
BT_UART_WAKE_SOC_R: length 2.8
  TOP w0.14: R25.1 R24.1 11.88,139.06 11.65,139.29 J2.20
BT_WLAN_EN: length 37.5
  TOP w0.14: v1(11.64,147.86) 11.21,148.29 J2.56 ; R11.2 R10.1 42.59,147.01 42.73,146.87 v1(43.05,146.87)
  L05_SIG02 w0.102: v1(11.64,147.86) 26.76,147.86 29.23,150.34 37.16,150.34 39.71,147.79 42.07,147.79 43,146.87 v1(43.05,146.87)
BUF_BOOTMODE_I2C1_SCL: length 22
  TOP w0.14: v1(67.25,36.73) 65.09,36.73 65.05,36.78 63.3,36.78 61.74,35.22 61.74,34.14 61.14,33.54 61.14,31.29 60.76,30.92 60.76,29.05 61.48,28.33 61.48,25.06 v1(61.35,24.93) 61.57,24.71 U47.82
  BOTTOM w0.14: R503.2 v1(61.35,24.93) ; v1(67.25,36.73) 67.25,37.19 68.17,38.11 69.24,38.11 U97.2
BUF_BOOTMODE_I2C1_SDA: length 21
  TOP w0.14: U47.81 61.97,24.71 v1(62.19,24.93) 61.81,25.31 61.81,30.79 61.47,31.14 61.47,33.34 62.15,34.02 62.15,35.17 63.3,36.32 66.62,36.32 v1(66.95,36)
  BOTTOM w0.14: U97.3 68.45,36.89 67.48,35.92 67.02,35.92 v1(66.95,36) ; v1(62.19,24.93) 62.23,24.89 R502.2
BUF_BOOTMODE_I2C_SCL: length 35.3
  TOP w0.14: v1(68.59,16.23) U47.49
  L03_SIG01 w0.102: v1(62.23,31.22) 62.34,31.1 66.35,31.1 68.19,32.95 72.64,32.95 73.33,32.25 73.33,28.79 74.63,27.49 74.63,24.54 73.44,23.35 73.44,20.06 71.57,18.19 70.55,18.19 v1(68.59,16.23)
  BOTTOM w0.14: R479.2 v1(62.23,31.22) 62.33,31.12 U99.2
BUF_BOOTMODE_I2C_SDA: length 35
  TOP w0.14: v1(71.22,16.85) 71,16.63 U47.50
  L03_SIG01 w0.102: v1(71.22,16.85) 73.75,19.38 73.75,23.18 74.96,24.39 74.96,30.75 73.88,31.83 73.88,32.62 73.2,33.3 66.64,33.3 65.46,32.13 62.43,32.13 v1(61.92,32.64)
  BOTTOM w0.14: U99.3 63.06,32.39 62.78,32.11 R477.2 61.75,32.46 v1(61.92,32.64)
BUF_TEST_GPIO1: length 3.9
  TOP w0.14: U47.74 64.77,25.91 64.2,26.48 U44.1
BUF_TEST_GPIO2: length 6.8
  TOP w0.14: v1(65.22,25.27) 65.17,25.22 U47.73
  BOTTOM w0.14: v1(65.22,25.27) 65.26,25.31 65.26,25.88 63.95,27.19 63.95,27.84 63.69,28.1 62.86,28.1 62.75,27.99 U102.2
BUF_TEST_GPIO3: length 4
  TOP w0.14: U47.72 65.57,24.83 65.67,24.93 65.67,25.68 65,26.34 U44.3
BUF_TEST_GPIO4: length 3.7
  TOP w0.14: U44.5 65.8,26.54 65.97,26.38 U47.71
BUF_TEST_PORZN: length 11.6
  TOP w0.14: v1(66.2,31.92) U44.9 ; U47.77 63.57,25.03 62.91,25.68 62.91,26.88 63.07,27.04 63.07,29.63 v1(65.09,31.65)
  BOTTOM w0.14: v1(65.09,31.65) 65.93,31.65 v1(66.2,31.92)
BUF_TEST_POWERDOWN: length 10.9
  TOP w0.14: U47.78 63.17,24.84 62.18,25.83 62.18,29.74 64.6,32.17 U44.13
BUF_TEST_WARMRESETN: length 11
  TOP w0.14: U44.11 65.4,32.28 65.63,32.06 65.63,31.5 63.37,29.24 63.37,27.46 63.85,26.98 63.85,26.44 63.57,26.16 63.57,25.51 63.97,25.11 U47.76
CAN_FD_WKUP_HDR_INH: length 47.5
  TOP w0.14: v1(13.44,101.97) 13.44,103.37 R75.1
  L05_SIG02 w0.102: v1(19.4,67.73) 18.81,67.14 18.81,65.75 18.33,65.27 18.33,63.27 J8.5
  L10_SIG03 w0.102: v1(19.4,67.73) 18.47,66.8 17.55,66.8 15.38,68.97 15.38,74.04 14.86,74.56 14.86,82.67 13.55,83.97 13.55,93.54 14.1,94.09 14.1,96.09 13.84,96.35 13.84,100.33 13.44,100.72 v1(13.44,101.97)
CAN_FD_WKUP_SW_INH: length 49.3
  TOP w0.14: v1(15.55,101.61) 15.45,101.71 R82.2 ; U35.7 v1(9.85,59.52)
  L03_SIG01 w0.102: v1(9.85,59.52) 9.06,60.31 9.06,64.46 8.77,64.76 8.77,83.96 9.88,85.08 9.88,90.72 11.12,91.96 14.58,91.96 16.16,93.53 16.16,101.05 15.6,101.61 v1(15.55,101.61)
CAN_IO_3V3: length 140
  TOP w0.254: v1(9.85,61.45) C104.1 U35.8 ; v1(13.92,105.15) 13.72,105.35 R65.1 11.75,105.72 11.04,106.43 7.65,106.43 v1(7.34,106.73) ; R149.1 v1(10,56.21) ; R139.2 3.69,65.72 v1(4.75,65.72)
  TOP w0.356: U18.H8 v1(36.28,100.47)
  TOP w0.381: R140.2 v1(4.75,65.11)
  L03_SIG01 w0.254: v1(13.92,105.15) 13.4,105.67 13.4,109.12 12.9,109.63 12.9,110.24 14.57,111.92 15.54,111.92 v1(15.6,111.98)
  L07_PWR02 w0.381: v1(4.75,65.11) 11.91,65.11 13.05,66.25 21.1,66.25 21.48,66.63 21.48,67.27 v1(22.36,68.14)
  L08_PWR03 w0.165: 30.78,100.47 31.18,100.86 35.88,100.86 v1(36.28,100.47) 35.88,100.07 31.17,100.07 30.78,100.46 30.78,100.47
  L08_PWR03 w0.381: 30.78,100.47 29.09,100.47 v1(28.1,99.48)
  L10_SIG03 w0.254: v1(7.34,106.73) 7.34,104.9 7.52,104.72 7.52,96.27 7.27,96.01 7.27,95.33 5.93,93.99 5.93,91.86 6.31,91.48 6.31,89.35 6.04,89.07 6.04,87.18 8.56,84.66 8.56,73.21 4.45,69.09 4.45,66.03 v1(4.75,65.72)
  L10_SIG03 w0.305: v1(28.1,99.48) 27.31,99.48 26.01,98.18 26.01,97.58 25.35,96.93 25.35,94.84 24.91,94.39 24.91,87.66 24.09,86.84 24.09,70.37 22.85,69.13 22.85,68.64 v1(22.36,68.14)
  BOTTOM w0.254: v1(26.47,17.87) 25.86,18.48 25.03,18.48 R535.1 ; v1(28.1,99.48) C282.1 C283.1 ; R579.2 15.2,111.57 v1(15.6,111.98) ; v1(32.82,20.56) 32.95,20.43 R523.1
CAP_VDDS0: length 0.8
  TOP w0.254: U18.G13 v1(35.48,105.26)
  BOTTOM w0.381: C241.1 v1(35.48,105.26)
CAP_VDDS1: length 0.8
  TOP w0.254: U18.K16 v1(37.88,107.66)
  BOTTOM w0.305: C222.1 37.74,107.8 v1(37.88,107.66)
CAP_VDDS2: length 0.8
  TOP w0.254: U18.T14 v1(43.48,106.06)
  BOTTOM w0.305: C235.1 43.55,106.13 v1(43.48,106.06)
CAP_VDDS3: length 0.9
  TOP w0.254: U18.M16 v1(40.28,107.66)
  BOTTOM w0.305: C220.1 40.4,107.79 v1(40.28,107.66)
CAP_VDDS4: length 0.9
  TOP w0.254: U18.R8 v1(42.68,100.47)
  BOTTOM w0.305: 42.88,100.26 v1(42.68,100.47)
CAP_VDDS5: length 0.7
  TOP w0.254: U18.G15 v1(35.48,106.86)
  BOTTOM w0.305: C231.1 v1(35.48,106.86)
CAP_VDDS6: length 0.8
  TOP w0.254: U18.J16 v1(37.08,107.66)
  BOTTOM w0.305: C223.1 37.07,107.65 v1(37.08,107.66)
CAP_VDDS_CANUART: length 0.9
  TOP w0.254: U18.G8 v1(35.48,100.47)
  BOTTOM w0.254: v1(35.48,100.47) 35.6,100.34 C287.1
CAP_VDDS_MCU: length 0.9
  TOP w0.254: U18.G10 v1(35.48,102.07)
  BOTTOM w0.305: v1(35.48,102.07) 35.43,102.07 C264.1
CLKOUT0: length 2.5
  TOP w0.14: R27.2 R28.2 50.51,136.97 51.1,136.38 U7.1
CLKOUT_OSC: length 1.4
  TOP w0.14: R27.1 U6.3
COM_SDIO_CLK: length 34.1
  TOP w0.14: v1(1.35,136.72) 1.52,136.54 J2.9
  L10_SIG03 w0.102: v1(23.98,153.26) 15.94,145.23 9.28,145.23 6.39,142.33 3.26,142.33 0.85,139.93 0.85,137.21 v1(1.35,136.72)
  BOTTOM w0.14: R243.1 24.16,153.09 v1(23.98,153.26)
COM_SDIO_CMD: length 34
  TOP w0.14: v1(1.31,137.73) 1.31,137.41 1.68,137.04 J2.11
  L10_SIG03 w0.102: v1(1.31,137.73) 1.97,138.38 1.97,140.01 3.31,141.35 9.06,141.35 11.36,143.65 15.09,143.65 18.13,140.61 18.36,140.61 18.54,140.79 18.54,141 16.21,143.33 16.21,143.49 16.38,143.65 16.57,143.65 19.03,141.19 v1(19.03,139.68)
  BOTTOM w0.14: v1(19.03,139.68) 18.61,139.26 R267.1
COM_SDIO_D0: length 34
  TOP w0.14: v1(3.91,137.35) 3.72,137.54 J2.13
  L10_SIG03 w0.102: v1(13.95,139.68) 14.4,140.13 14.4,142.45 14.2,142.65 12.09,142.65 11.97,142.53 11.97,142.36 12.09,142.24 13.5,142.24 13.62,142.12 13.62,141.96 13.5,141.84 12.09,141.84 11.97,141.72 11.97,141.55 12.09,141.43 13.37,141.43 13.49,141.31 13.49,141.14 13.37,141.02 11.69,141.02 11.57,141.14 11.57,142.3 11.46,142.4 10.98,142.4 10.86,142.29 10.86,141.1 10.73,140.96 3.48,140.96 2.38,139.86 2.38,139.54 2.5,139.42 2.93,139.42 3.05,139.3 3.05,139.13 2.93,139.01 2.5,139.01 2.38,138.89 2.38,138.72 2.5,138.61 2.93,138.61 3.05,138.49 3.05,138.32 2.93,138.2 2.5,138.2 2.38,138.08 2.38,137.55 2.58,137.35 v1(3.91,137.35)
  BOTTOM w0.14: v1(13.95,139.68) 13.53,139.26 R269.1
COM_SDIO_D1: length 34
  TOP w0.14: J2.15 3.65,138.04 v1(3.85,138.24)
  L10_SIG03 w0.102: v1(3.85,138.24) 3.35,138.74 3.35,140.31 3.66,140.62 7,140.62 7.12,140.5 7.12,139.92 7.24,139.8 10.6,139.8 10.73,139.93 10.73,140.1 10.61,140.21 7.64,140.21 7.53,140.33 7.53,140.5 7.64,140.62 11.19,140.62 12.54,139.26 14.71,139.26 14.82,139.38 14.82,141.58 14.94,141.7 15.75,141.7 15.87,141.58 15.87,141.41 15.75,141.29 15.35,141.29 15.23,141.17 15.23,141.01 15.35,140.89 15.73,140.89 15.85,140.77 15.85,140.6 15.73,140.48 15.35,140.48 15.23,140.36 15.23,140.19 15.35,140.07 15.75,140.07 15.87,139.95 15.87,139.79 15.75,139.67 15.35,139.67 15.23,139.55 15.23,139.38 15.35,139.26 16.07,139.26 v1(16.49,139.68)
  BOTTOM w0.14: v1(16.49,139.68) 16.07,139.26 R268.1
COM_SDIO_D2: length 34.1
  TOP w0.14: v1(1.32,138.81) 1.59,138.54 J2.17
  L10_SIG03 w0.102: v1(1.32,138.81) 1.32,139.9 3.41,141.98 6.55,141.98 9.27,144.7 21.62,144.7 22.43,143.89 22.43,143.7 22.33,143.61 22.33,143.42 22.47,143.29 22.66,143.29 22.75,143.38 22.94,143.38 23.08,143.25 23.08,143.06 22.98,142.96 22.98,142.77 23.11,142.64 23.3,142.64 23.4,142.73 23.59,142.73 v1(26.65,139.68)
  BOTTOM w0.14: v1(26.65,139.68) 26.23,139.26 R266.1
COM_SDIO_D3: length 34.1
  TOP w0.14: J2.19 v1(3.84,139.04)
  L10_SIG03 w0.102: v1(29.19,139.68) 28.43,138.91 26.08,138.91 25.94,139.05 25.94,139.58 25.81,139.71 25.62,139.71 25.49,139.58 25.49,139.05 25.35,138.91 25.16,138.91 25.03,139.05 25.03,139.58 24.9,139.71 24.71,139.71 24.57,139.58 24.57,139.05 24.44,138.91 22.84,138.91 22.71,139.05 22.71,139.64 22.56,139.78 22.37,139.78 22.25,139.65 22.25,139.05 22.11,138.91 20.54,138.91 20.4,139.05 20.4,139.8 20.27,139.93 20.08,139.93 19.95,139.8 19.95,139.05 19.81,138.91 12.16,138.91 11.7,139.37 4.17,139.37 v1(3.84,139.04)
  BOTTOM w0.14: v1(29.19,139.68) 28.77,139.26 R265.1
COMP_LM5141: length 4.1
  BOTTOM w0.14: C433.1 36.45,41.17 36.6,41.32 R441.1 36.1,42.36 35.52,42.36 35.03,42.85 U89.20
CONN_MCU_PORZ: length 45.9
  L03_SIG01 w0.102: v1(55.88,35.99) 56.37,36.47 56.37,37.87 55.87,38.37 55.87,39.66 55.25,40.27 52.4,40.27 49.93,42.75 48.54,42.75 47.86,43.44 47.86,47.99 47.17,48.68 47.17,50 53.68,56.51 53.68,63.08 53.42,63.34 v1(53.42,64.82)
  L10_SIG03 w0.102: v1(53.42,64.82) 52.85,65.39 50.59,65.39 49.96,64.76 J8.28
  BOTTOM w0.14: R465.1 55.24,35.99 v1(55.88,35.99) U96.1
CONN_MCU_RESETZ: length 25.1
  TOP w0.14: Q3.1 45.38,41.07 44.02,42.43 v1(44.02,42.83)
  L03_SIG01 w0.102: v1(44.02,42.83) 44.02,46.83 44.26,47.07 44.26,54.89 44.52,55.14 44.52,59.83 44.79,60.1 J8.25
  BOTTOM w0.14: R390.1 J8.25
CPSW1_GPIO_0: length 4.2
  BOTTOM w0.14: Q7.1 R367.1
  BOTTOM w0.254: J6.14 82.88,85.86 82.82,85.81 Q7.6
CPSW1_LED_1000: length 3.4
  BOTTOM w0.254: Q5.2 82.6,103.87 82.88,103.59 J6.12
CPSW1_LED_ACT: length 4.4
  BOTTOM w0.14: Q6.1 R366.1
  BOTTOM w0.254: J6.13 80.85,86.36 80.16,85.67 Q6.6
CPSW_ETH1_D0N: length 10.2
  BOTTOM w0.089: U78.2 64.97,97.14 65.11,97.28 65.51,97.28 65.89,97.67 65.89,98.17 66.14,98.42 67.87,98.42 68.53,97.76 70.08,97.76 71.03,98.7 71.03,99.42 J6.10
CPSW_ETH1_D0P: length 10.1
  BOTTOM w0.089: U78.1 64.97,97.64 65.11,97.51 65.41,97.51 65.67,97.76 65.67,98.26 66.05,98.64 67.97,98.64 68.63,97.99 69.99,97.99 70.8,98.8 70.8,99.44 70.64,99.6 69.93,99.6 J6.9
CPSW_ETH1_D1M: length 10.2
  BOTTOM w0.089: J6.8 71.03,96.88 71.03,96.16 70.08,95.22 68.43,95.22 68.09,95.56 68.09,96.16 67.9,96.35 67.62,96.35 67.05,95.78 65.11,95.78 64.97,95.64 U78.5
CPSW_ETH1_D1P: length 10.2
  BOTTOM w0.089: U78.4 64.97,96.14 65.11,96.01 66.96,96.01 67.52,96.58 68,96.58 68.32,96.25 68.32,95.65 68.52,95.45 69.99,95.45 70.8,96.26 70.8,96.9 70.64,97.06 69.93,97.06 J6.7
CPSW_ETH1_D2M: length 10.2
  BOTTOM w0.089: J6.6 71.03,94.34 71.03,93.62 70.08,92.68 68.06,92.68 67.5,93.24 67.5,93.92 67.14,94.28 65.11,94.28 64.97,94.14 U78.8
CPSW_ETH1_D2P: length 10.2
  BOTTOM w0.089: U78.7 64.97,94.64 65.11,94.51 67.23,94.51 67.73,94.01 67.73,93.33 68.15,92.91 69.99,92.91 70.8,93.72 70.8,94.36 70.64,94.52 69.93,94.52 J6.5
CPSW_ETH1_D3M: length 10.2
  BOTTOM w0.089: U78.11 64.97,92.64 65.11,92.78 66.05,92.78 68.69,90.14 70.08,90.14 71.03,91.08 71.03,91.8 J6.4
CPSW_ETH1_D3P: length 10.2
  BOTTOM w0.089: U78.10 64.97,93.14 65.11,93.01 66.14,93.01 68.79,90.37 69.99,90.37 70.8,91.18 70.8,91.82 70.64,91.98 69.93,91.98 J6.3
CPSW_ETH1_GPIO_0: length 51.7
  TOP w0.14: TP20.1 58.07,100.86 v1(58.35,101.13) 58.35,101.27 58.26,101.36 R83.1
  L03_SIG01 w0.102: v1(58.35,101.13) 58.47,101.13 59.01,101.66 63.19,101.66 64.42,102.89 64.42,103.75 65.48,104.81 69.14,104.81 69.95,104 69.95,101.46 68.07,99.57 68.07,85.77 72.14,81.7 80.13,81.7 v1(81.1,80.73)
  BOTTOM w0.14: R342.1 58.51,100.97 v1(58.35,101.13) 58.26,101.22 R83.1 ; v1(81.1,80.73) 81.3,80.92 R365.1
CPSW_ETH1_GPIO_1: length 2.8
  TOP w0.14: TP21.1 59.24,100.82 v1(59.53,101.11) R84.1
  BOTTOM w0.14: R341.1 59.4,100.98 v1(59.53,101.11) R84.1
CPSW_ETH1_LED0: length 4.7
  TOP w0.14: v1(64.98,101.89) TP18.1
  BOTTOM w0.14: U78.47 63.15,99.28 63.81,99.94 63.81,100.23 64.98,101.39 v1(64.98,101.89)
CPSW_ETH1_LED_1000: length 31.7
  TOP w0.14: TP23.1 v1(63.24,100.21) 63.4,100.37 R86.1
  L10_SIG03 w0.102: v1(80.8,106.13) 80.06,106.86 80.06,109.31 79.02,110.35 73.64,110.35 72.34,109.06 72.34,105.78 68.23,101.66 65.51,101.66 64.06,100.21 v1(63.24,100.21)
  BOTTOM w0.14: R327.1 v1(80.8,106.13) ; U78.46 62.65,99.67 63.18,100.2 63.23,100.2 v1(63.24,100.21) 63.24,100.27 63.4,100.43 R86.1
CPSW_ETH1_LED_ACT: length 42.5
  TOP w0.14: R85.1 62.13,100.41 v1(62.33,100.21) 62.06,99.95 TP22.1
  L03_SIG01 w0.102: v1(78.3,81.22) 72.13,81.22 67.76,85.6 67.76,99.73 69.62,101.59 69.62,101.99 69.37,102.25 66.3,102.25 64.87,100.83 62.89,100.83 62.33,100.26 v1(62.33,100.21)
  BOTTOM w0.14: U78.45 62.15,100.03 v1(62.33,100.21) 62.13,100.41 R85.1 ; R364.1 v1(78.3,81.22)
CPSW_ETH2_INH: length 78.7
  TOP w0.14: J4.28 57.07,118.08 v1(57.27,118.28)
  L05_SIG02 w0.102: v1(42.37,133.97) 44.12,133.97 45.85,132.25 50.32,132.25 51.08,131.48 51.08,127.97 51.95,127.1 51.96,127.1 52.35,126.71 53.72,126.71 55.22,125.21 55.22,123.77 56.8,122.19 56.8,118.78 57.27,118.31 v1(57.27,118.28)
  L10_SIG03 w0.102: v1(10.31,120.12) 10.25,120.12 10.08,120.3 10.08,122.18 10.66,122.76 10.66,124.44 13.25,127.03 13.25,131.27 14.18,132.2 15.85,132.2 17.99,134.33 23.17,134.33 24.29,133.21 33.61,133.21 34.88,134.48 41.86,134.48 v1(42.37,133.97)
  BOTTOM w0.14: v1(10.31,120.12) 11.27,120.12 12.39,119 12.39,117.4 14.11,115.68 U124.2
CPSW_ETH2_WAKE: length 37
  TOP w0.132: U18.E13 v1(33.88,105.26)
  TOP w0.14: v1(55.76,118.28) 55.96,118.48 J4.30
  L03_SIG01 w0.102: v1(57.35,111.09) 52.66,111.09 51.44,109.87 48.59,109.87 48.44,110.02 48.03,110.02 47.68,109.67 46.51,109.67 46.28,109.43 46.28,109.1 46.05,108.86 45.96,108.86 44.11,108.86 43.88,108.63 43.88,108.53 43.88,106.7 43.65,106.47 43.61,106.47 43.61,106.46 42.05,106.46 37.25,106.46 34.51,106.46 34.46,106.41 34.44,106.41 34.28,106.25 34.28,105.9 34.24,105.86 34.24,105.5 34.01,105.26 v1(33.88,105.26)
  L10_SIG03 w0.102: v1(57.35,111.09) 57.35,112.03 56.52,112.86 56.52,117.52 v1(55.76,118.28)
CPSW_ETH_INTN: length 52.5
  TOP w0.14: R53.1 33.96,117.92 33.37,118.51 33.37,121.32 34.19,122.13 v1(34.19,124.41) ; R78.1 62.4,103.44 v1(63.02,103.44)
  L03_SIG01 w0.102: v1(63.02,103.44) 62.73,103.44 62.08,102.79 62.08,102.37 61.7,101.99 59.9,101.99 58.88,103.01 58.88,105.22 58.52,105.58 58.52,108.57 57.41,109.69 v1(55.53,109.69)
  L10_SIG03 w0.102: v1(34.19,124.41) 40.5,124.41 41.28,123.64 43.34,123.64 43.56,123.42 45.03,123.42 45.8,122.65 45.8,122.28 46.33,121.76 46.89,121.76 54.02,114.63 54.02,111.2 v1(55.53,109.69)
CPSW_RGMII1_ETH1_CLK: length 55.9
  TOP w0.14: v1(54.92,134.18) 54.92,134.94 55.76,135.78 R26.2
  L05_SIG02 w0.102: v1(54.92,134.18) 54.92,132.51 53.83,131.41 53.83,127.57 55.04,126.35 58.36,126.35 61.3,123.42 61.3,115.93 62.77,114.46 62.77,105.96 63.48,105.24 63.48,103.32 62.94,102.78 62.94,102.2 62.77,102.02 62.77,92.06 63.15,91.68 v1(63.15,90.29)
  BOTTOM w0.14: U78.15 62.65,90.8 v1(63.15,90.29)
CPSW_RGMII1_ETH1_CLK_OUT: length 5.1
  TOP w0.132: v1(59.01,88.99) 58.75,88.74 TP28.1
  BOTTOM w0.14: U78.18 61.15,90.53 61.03,90.41 61.03,89.54 60.14,88.65 59.34,88.65 v1(59.01,88.99)
CPSW_RGMII1_ETH1_RBIAS: length 2.6
  BOTTOM w0.14: U78.12 64.65,92.14 65.01,91.78 65.01,91.66 R351.1 65.44,90.66 65.57,90.53 C307.2
CPSW_RGMII1_MDC: length 2.5
  TOP w0.14: R108.2 v1(62.28,90.29)
  BOTTOM w0.14: R354.1 v1(62.28,90.29) 62.15,90.42 U78.16
CPSW_RGMII1_MDIO: length 2.4
  TOP w0.14: R107.2 v1(61.52,90.29)
  BOTTOM w0.14: R355.2 v1(61.52,90.29) 61.65,90.42 U78.17
CPSW_RGMII1_RD0: length 32.3
  TOP w0.132: U18.AB16 v1(48.28,107.66)
  TOP w0.14: v1(56.16,96.73) 56.38,96.51 R96.2
  L05_SIG02 w0.102: v1(56.16,96.73) 56.59,96.73 56.75,96.89 56.75,97.05 56.38,97.42 56.38,97.59 56.49,97.7 56.64,97.7 57.02,97.32 57.18,97.32 57.29,97.43 57.29,97.59 56.87,98.01 56.87,98.15 56.98,98.27 57.15,98.27 57.56,97.85 57.72,97.85 57.83,97.97 57.83,98.12 57.58,98.38 57.58,98.52 57.69,98.63 57.86,98.63 58.1,98.39 58.26,98.39 58.43,98.56 58.43,100.63 58.33,100.73 58.13,100.73 58.03,100.63 58.03,99.57 57.92,99.47 57.74,99.47 57.64,99.56 57.64,101.1 58.42,101.87 58.42,104.22 55.22,107.41 54.04,107.41 53.89,107.27 53.66,107.27 53.51,107.41 52.58,107.41 52.47,107.3 52.47,107.09 52.36,106.98 52.2,106.98 52.09,107.09 52.09,107.3 51.98,107.41 51.72,107.41 51.47,107.66 50.96,107.66 50.79,107.5 50.58,107.5 50.41,107.66 49.23,107.66 49.1,107.54 49.1,107.29 48.99,107.18 48.39,107.18 48.28,107.28 48.28,107.66 v1(48.28,107.66)
  BOTTOM w0.14: U78.33 57.37,96.17 56.62,96.17 56.16,96.63 v1(56.16,96.73) 55.61,96.73 R347.1
CPSW_RGMII1_RD1: length 30.9
  TOP w0.132: U18.V15 v1(45.08,106.86)
  L05_SIG02 w0.102: v1(45.08,106.86) 44.88,106.86 44.48,106.46 44.06,106.46 43.88,106.29 43.88,105.1 44.11,104.86 48.73,104.86 49.25,104.34 51.59,104.34 51.76,104.5 52.29,104.5 54.54,102.25 54.72,102.25 54.86,102.38 54.86,102.57 52.71,104.72 52.71,104.86 52.88,105.03 53.04,105.03 55.23,102.84 55.23,101.37 54.36,100.5 54.36,98.58 v1(55.54,97.41)
  BOTTOM w0.14: v1(55.54,97.41) 56.07,97.41 56.83,96.64 U78.34
CPSW_RGMII1_RD2: length 32.3
  TOP w0.132: U18.W15 v1(45.88,106.86)
  TOP w0.14: R93.2 56.43,97.78 v1(56.2,98)
  L05_SIG02 w0.102: v1(56.2,98) 55.5,98 55.31,98.19 55.31,98.57 55.2,98.69 54.83,98.69 54.71,98.81 54.71,99.11 54.81,99.21 55.19,99.21 55.31,99.33 55.31,99.63 55.17,99.77 54.83,99.77 54.71,99.89 54.71,100.15 54.87,100.31 55.62,100.31 55.8,100.49 55.8,103.02 55.57,103.25 55.37,103.25 53.9,104.72 53.9,104.89 54.02,105.01 54.19,105.01 55.52,103.68 55.68,103.68 55.78,103.78 55.78,104 54.31,105.46 53.9,105.46 53.7,105.26 53.36,105.26 53.12,105.51 51.63,105.51 51.45,105.33 51.45,104.81 51.27,104.64 51.07,104.64 50.93,104.78 50.56,104.78 50.42,104.64 49.38,104.64 48.36,105.66 44.84,105.66 44.68,105.82 44.68,106.31 44.84,106.47 45.25,106.47 45.65,106.86 v1(45.88,106.86)
  BOTTOM w0.14: R346.1 56.05,98.16 v1(56.2,98) 56.37,97.84 56.37,97.68 56.9,97.14 U78.35
CPSW_RGMII1_RD3: length 30.9
  TOP w0.132: U18.V14 v1(45.08,106.06)
  L05_SIG02 w0.102: v1(56.8,98.64) 55.84,98.64 55.63,98.85 55.63,99.53 56.21,100.11 56.21,100.86 57.79,102.44 57.79,103.97 57.66,104.1 57.44,104.1 57.34,104 57.34,103.82 57.24,103.72 57.02,103.72 56.93,103.81 56.93,103.99 56.82,104.1 56.63,104.1 56.51,103.98 56.51,102.92 56.61,102.82 57.09,102.82 57.19,102.72 57.19,102.46 57.09,102.36 56.64,102.36 56.54,102.26 56.54,101.86 56.43,101.76 56.23,101.76 56.12,101.87 56.12,104.36 54.64,105.83 50.87,105.83 50.67,105.63 49.93,105.63 49.76,105.8 49.76,106.25 49.59,106.42 49.13,106.42 48.75,106.05 48.27,106.05 48.17,106.15 48.17,106.34 48.07,106.44 47.82,106.44 47.72,106.34 47.72,106.14 47.63,106.05 47.28,106.05 47.18,106.15 47.18,106.35 47.07,106.47 45.7,106.47 45.3,106.06 v1(45.08,106.06)
  BOTTOM w0.14: U78.36 57.11,97.64 56.8,97.96 v1(56.8,98.64)
CPSW_RGMII1_RESETN: length 83.8
  TOP w0.14: U41.4 64,41.89 v1(63.78,41.67)
  L05_SIG02 w0.102: v1(63.78,41.67) 63.78,41.19 64,40.97 64,39.37 64.75,38.62 64.75,37.99 63.65,36.89 61.33,36.89 58.63,39.59 56.93,39.59 55.45,41.07 55.45,44.72 55.27,44.9 55.27,46.78 57.81,49.32 57.81,53.79 57.53,54.06 57.53,66.02 59.79,68.28 59.79,73.31 63.73,77.25 63.73,79.87 62.95,80.65 62.94,84.54 62.85,84.63 62.85,87.73 60.86,89.73 60.86,91.78 61.34,92.27 61.34,97.85 61.45,97.96 61.45,99.74 v1(60.88,100.31)
  BOTTOM w0.14: v1(60.88,100.31) 61.22,99.97 61.22,99 61.15,98.93 U78.43 ; R440.1 64.01,41.9 v1(63.78,41.67)
CPSW_RGMII1_RX_CTL: length 31
  TOP w0.132: U18.AA15 v1(47.48,106.86)
  L05_SIG02 w0.102: v1(47.48,106.86) 49.29,106.86 49.73,107.3 50.1,107.3 50.76,106.64 51.24,106.64 51.35,106.53 51.35,106.32 51.46,106.2 51.62,106.2 51.73,106.32 51.73,106.53 51.84,106.64 52,106.64 52.11,106.53 52.11,106.32 52.22,106.2 52.38,106.2 52.49,106.32 52.49,106.53 52.6,106.64 55.57,106.64 56.63,105.57 56.63,105.39 56.53,105.28 56.33,105.28 55.34,106.28 55.18,106.28 55.03,106.14 55.03,105.99 56.33,104.69 56.57,104.69 56.75,104.51 57.1,104.51 57.28,104.69 57.5,104.69 58.09,104.1 58.09,102.08 57.31,101.3 57.31,99.24 57.21,99.14 57.06,99.14 56.94,99.26 56.94,100.24 56.84,100.34 56.66,100.34 56.56,100.24 56.56,99.3 56.43,99.17 v1(56.05,99.17)
  BOTTOM w0.14: v1(56.05,99.17) R340.2 R339.2 57.91,99.77 58.65,99.03 U78.38
CPSW_RGMII1_RXC: length 29.2
  TOP w0.132: U18.AA16 v1(47.48,107.66)
  L05_SIG02 w0.102: v1(53.82,98.16) 54.09,97.89 54.38,97.89 55.96,96.32 56.67,96.32 58.75,98.39 58.75,104.34 55.28,107.81 51.89,107.81 51.63,108.06 47.88,108.06 v1(47.48,107.66)
  BOTTOM w0.14: R348.1 54.56,95.55 53.63,96.48 53.63,97.97 v1(53.82,98.16)
CPSW_RGMII1_TD0: length 27.3
  TOP w0.132: U18.Y17 v1(46.68,108.46)
  L03_SIG01 w0.102: v1(46.68,108.46) 47.08,108.07 48.57,108.07 49.36,108.85 50.58,108.85 51.99,107.45 53.49,107.45 54.71,106.23 54.88,106.23 55.01,106.36 55.18,106.36 55.3,106.24 55.3,106.07 55.17,105.94 55.17,105.77 55.28,105.65 55.45,105.65 55.59,105.78 55.76,105.78 55.87,105.67 55.87,105.5 55.74,105.36 55.74,105.19 56.09,104.85 56.09,103.09 56.32,102.85 56.32,102.38 56.44,102.26 56.73,102.26 56.85,102.14 56.85,101.97 56.73,101.86 56.44,101.86 56.32,101.74 56.32,100.41 56.66,100.07 56.66,99.12 56.38,98.85 56.38,98.45 56.95,97.88 56.95,94.04 v1(56.4,93.49)
  BOTTOM w0.14: v1(56.4,93.49) 56.73,93.49 56.88,93.64 U78.28
CPSW_RGMII1_TD1: length 27.3
  TOP w0.132: U18.V16 v1(45.08,107.66)
  L03_SIG01 w0.102: v1(45.08,107.66) 45.48,107.26 46.05,107.26 46.28,107.03 46.28,107.02 46.28,106.62 46.44,106.47 47.9,106.47 48.31,106.88 49.07,106.88 49.56,106.39 50.13,106.39 50.4,106.65 50.78,106.65 51.51,105.92 51.67,105.92 52.69,104.89 52.99,104.89 54.71,103.18 54.71,97.18 55.34,96.55 55.34,94.42 54.9,93.97 54.9,92.67 v1(55.5,92.06)
  BOTTOM w0.14: U78.27 56.92,93.14 56.85,93.07 55.97,93.07 55.5,92.59 v1(55.5,92.06)
CPSW_RGMII1_TD2: length 27.3
  TOP w0.132: U18.Y16 v1(46.68,107.66)
  L03_SIG01 w0.102: v1(56.4,92.58) 55.61,92.58 55.23,92.96 55.23,93.86 55.72,94.35 55.72,96.63 55.02,97.33 55.02,101.09 55.43,101.5 55.43,102.43 55.28,102.58 55.28,103.64 54.92,104 54.92,104.17 55.18,104.44 55.18,104.61 55.06,104.73 54.9,104.73 54.63,104.46 54.46,104.46 54.34,104.58 54.34,104.75 54.61,105.01 54.61,105.18 54.49,105.3 54.32,105.3 54.05,105.04 53.89,105.04 53.63,105.29 52.97,105.29 52.36,105.91 52.36,106.48 52.18,106.66 51.2,106.66 50.77,107.09 50.77,107.43 50.6,107.6 49.02,107.6 48.68,107.26 47.08,107.26 v1(46.68,107.66)
  BOTTOM w0.14: v1(56.4,92.58) 56.46,92.64 U78.26
CPSW_RGMII1_TD3: length 27.3
  TOP w0.132: U18.AA17 v1(47.48,108.46)
  L03_SIG01 w0.102: v1(56.44,91.63) 57.25,92.44 57.25,102.57 56.52,103.3 56.52,105.61 54.65,107.47 54.08,107.47 53.76,107.8 52.06,107.8 50.71,109.16 49.13,109.16 48.83,108.86 48.11,108.86 47.71,108.46 v1(47.48,108.46)
  BOTTOM w0.14: U78.25 56.66,92.14 56.44,91.92 v1(56.44,91.63)
CPSW_RGMII1_TX_CTL: length 27.3
  TOP w0.132: U18.W16 v1(45.88,107.66)
  L03_SIG01 w0.102: v1(45.88,107.66) 46.28,108.07 46.28,108.68 46.47,108.86 47.65,108.86 47.88,109.1 47.88,109.49 48.08,109.69 48.45,109.69 48.65,109.49 50.93,109.49 51.62,108.8 52.23,108.8 52.82,108.21 53.85,108.21 54.26,107.79 54.9,107.79 55.05,107.65 55.22,107.65 55.55,107.98 55.72,107.98 55.84,107.86 55.84,107.69 55.5,107.36 55.5,107.19 55.62,107.08 55.79,107.08 56.12,107.41 56.29,107.41 56.41,107.29 56.41,107.12 56.08,106.79 56.08,106.62 56.57,106.13 56.74,106.13 57.09,106.49 57.26,106.49 57.38,106.37 57.38,106.2 57.02,105.84 57.02,105.67 57.66,105.04 57.66,104.56 57.54,104.44 57.11,104.44 56.99,104.32 56.99,104.15 57.11,104.03 57.54,104.03 57.66,103.92 v1(57.66,99.05)
  BOTTOM w0.14: v1(57.66,99.05) 58.01,99.05 58.15,98.91 U78.37
CPSW_RGMII1_TXC: length 24.2
  L03_SIG01 w0.102: v1(55.64,93.49) 56.03,93.89 56.03,95.39 56.56,95.92 56.56,97.03 55.41,98.17 55.41,99.98 55.53,100.1 55.76,100.1 55.86,100.2 55.86,102.68 55.66,102.89 55.66,104.77 54.66,105.78 53.04,105.78 52.69,106.13 52.69,106.83 52.48,107.04 51.91,107.04 50.81,108.14 50.44,108.14 50.21,107.91 49.53,107.91 49.4,108.04 49.4,108.34 49.53,108.46 v1(49.93,108.46)
  BOTTOM w0.14: v1(55.64,93.49) 56.11,93.97 56.65,93.97 56.82,94.14 U78.29 ; R322.2 v1(49.93,108.46)
CPSW_RGMII2_ETH2_CLK: length 23.8
  TOP w0.14: J4.22 55.96,116.88 v1(55.76,116.68) ; v1(54.48,133.13) R37.2
  L05_SIG02 w0.102: v1(55.76,116.68) 56.26,117.18 56.93,117.18 57.05,117.06 57.46,117.06 57.84,117.44 57.84,125.18 57.13,125.9 55.04,125.9 53.57,127.37 53.57,132.22 v1(54.48,133.13)
CPSW_RGMII2_RD0: length 20.4
  TOP w0.132: U18.AA21 v1(47.48,111.66)
  TOP w0.14: J4.27 59.78,118.08 v1(59.98,118.28)
  L03_SIG01 w0.102: v1(59.98,118.28) 59.57,118.69 54.34,118.69 54.17,118.51 54.17,118.34 54.44,118.07 54.44,117.91 54.33,117.79 54.16,117.79 53.89,118.06 53.72,118.06 52.99,117.33 52.99,113.66 50.59,111.26 47.88,111.26 v1(47.48,111.66)
CPSW_RGMII2_RD1: length 20.4
  TOP w0.132: U18.Y20 v1(46.68,110.86)
  TOP w0.14: v1(58.47,119.88) 58.67,119.68 J4.35
  L03_SIG01 w0.102: v1(46.68,110.86) 47.08,111.26 47.08,111.88 47.27,112.07 50.15,112.07 51.87,113.78 51.87,118.53 53.07,119.73 54.04,119.73 54.59,120.28 58.06,120.28 v1(58.47,119.88)
CPSW_RGMII2_RD2: length 20.3
  TOP w0.132: U18.AB21 v1(48.28,111.66)
  TOP w0.14: v1(58.47,119.08) 58.67,119.28 J4.33
  L03_SIG01 w0.102: v1(48.28,111.66) 50.41,111.66 52.63,113.88 52.63,114.18 52.51,114.3 52.37,114.3 52.25,114.42 52.25,114.59 52.37,114.7 52.51,114.7 52.63,114.82 52.63,114.99 52.51,115.11 52.37,115.11 52.25,115.23 52.25,115.4 52.37,115.52 52.51,115.52 52.63,115.64 52.63,115.8 52.51,115.92 52.37,115.92 52.25,116.04 52.25,116.21 52.37,116.33 52.51,116.33 52.63,116.45 52.63,116.62 52.51,116.74 52.37,116.74 52.25,116.86 52.25,117.02 52.37,117.14 52.51,117.14 52.63,117.26 52.63,117.63 52.78,117.78 52.78,117.95 52.42,118.31 52.42,118.48 52.54,118.6 52.71,118.6 53.07,118.24 53.24,118.24 54.45,119.46 58.09,119.46 v1(58.47,119.08)
CPSW_RGMII2_RD3: length 20.3
  TOP w0.132: v1(48.97,110.86) 48.28,110.86 U18.AB20
  TOP w0.14: J4.29 58.67,118.48 v1(58.47,118.28)
  L03_SIG01 w0.102: v1(48.97,110.86) 50.81,110.86 53.76,113.82 53.76,114.46 53.65,114.58 53.41,114.58 53.29,114.7 53.29,114.87 53.41,114.99 53.65,114.99 53.76,115.1 53.76,115.27 53.65,115.39 53.41,115.39 53.29,115.51 53.29,115.68 53.41,115.8 53.65,115.8 53.76,115.92 53.76,116.09 53.65,116.2 53.41,116.2 53.29,116.32 53.29,116.49 53.41,116.61 53.75,116.61 55,117.86 56.2,117.86 56.32,117.98 56.32,118.26 56.44,118.38 56.61,118.38 56.73,118.26 56.73,117.98 56.85,117.86 58.91,117.86 59.01,117.96 59.01,118.17 58.91,118.28 v1(58.47,118.28)
CPSW_RGMII2_RX_CTL: length 20.3
  TOP w0.132: U18.W18 v1(45.88,109.26)
  TOP w0.14: v1(58.47,116.68) 58.67,116.88 J4.21
  L03_SIG01 w0.102: v1(58.47,116.68) 58.08,116.29 55.49,116.29 55.2,115.99 55.2,114.16 54.44,113.41 54.44,113.24 54.65,113.02 54.65,112.86 54.53,112.74 54.37,112.74 54.15,112.95 53.98,112.95 53.86,112.83 53.86,112.66 54.08,112.45 54.08,112.28 53.96,112.16 53.79,112.16 53.58,112.38 53.41,112.38 51.21,110.18 48.66,110.18 48.38,110.46 46.51,110.46 46.28,110.23 46.28,109.89 46.08,109.69 46.08,109.46 v1(45.88,109.26)
CPSW_RGMII2_RXC: length 20.3
  TOP w0.132: U18.AA20 v1(47.48,110.86)
  TOP w0.14: v1(58.47,117.48) 58.67,117.28 J4.23
  L03_SIG01 w0.102: v1(58.47,117.48) 58.06,117.07 56.87,117.07 56.75,117.19 56.75,117.42 56.63,117.54 56.47,117.54 56.35,117.42 56.35,117.19 56.23,117.07 54.8,117.07 54.1,116.37 54.1,116.15 54.22,116.03 54.77,116.03 54.89,115.91 54.89,115.74 54.77,115.62 54.22,115.62 54.1,115.5 54.1,115.33 54.22,115.22 54.77,115.22 54.89,115.1 54.89,114.93 54.77,114.81 54.22,114.81 54.1,114.69 54.1,113.57 51.01,110.48 48.76,110.48 48.38,110.86 v1(47.48,110.86)
CPSW_RGMII2_TD0: length 16.3
  TOP w0.132: U18.AA19 v1(47.48,110.06)
  TOP w0.14: v1(59.98,115.88) 59.78,115.68 J4.15
  L05_SIG02 w0.102: v1(59.98,115.88) 59.56,115.46 54.51,115.46 49.51,110.45 47.87,110.45 v1(47.48,110.06)
CPSW_RGMII2_TD1: length 16.3
  TOP w0.132: U18.Y18 v1(46.68,109.26)
  TOP w0.14: v1(58.47,115.08) 58.67,114.88 J4.11
  L05_SIG02 w0.102: v1(58.47,115.08) 58.06,114.67 56.87,114.67 56.75,114.55 56.75,114.3 56.63,114.18 56.46,114.18 56.34,114.3 56.34,114.55 56.22,114.67 54.38,114.67 49.82,110.1 48.13,110.1 47.69,109.67 47.65,109.67 47.08,109.67 46.68,109.27 v1(46.68,109.26)
CPSW_RGMII2_TD2: length 16.3
  TOP w0.132: U18.AA18 v1(47.48,109.26)
  TOP w0.14: v1(58.47,114.28) 58.67,114.48 J4.9
  L05_SIG02 w0.102: v1(47.48,109.26) 47.66,109.26 48.14,109.74 50.08,109.74 53.74,113.4 53.91,113.4 54.17,113.14 54.34,113.14 54.46,113.26 54.46,113.43 54.19,113.69 54.19,113.86 54.43,114.09 55.14,114.09 55.42,113.81 56.18,113.81 56.3,113.69 56.3,113.46 56.42,113.34 56.59,113.34 56.71,113.46 56.71,113.69 56.83,113.81 58,113.81 v1(58.47,114.28)
CPSW_RGMII2_TD3: length 16.3
  TOP w0.132: U18.W17 v1(45.88,108.46)
  TOP w0.14: J4.5 58.67,113.68 v1(58.47,113.48)
  L05_SIG02 w0.102: v1(45.88,108.46) 46.28,108.86 48.57,108.86 49.03,109.33 50.34,109.33 53.68,112.67 58.03,112.67 58.47,113.1 v1(58.47,113.48)
CPSW_RGMII2_TX_CTL: length 16.3
  TOP w0.132: U18.Y19 v1(46.68,110.06)
  TOP w0.14: v1(58.47,115.88) 58.67,116.08 J4.17
  L05_SIG02 w0.102: v1(46.68,110.06) 46.71,110.06 47.08,110.43 47.08,111.06 47.28,111.26 49.77,111.26 54.76,116.26 58.09,116.26 v1(58.47,115.88)
CPSW_RGMII2_TXC: length 11.5
  TOP w0.14: R56.2 v1(53.31,111.6) ; J4.3 59.78,113.28 v1(59.98,113.48)
  L05_SIG02 w0.102: v1(53.31,111.6) 53.89,112.18 57.31,112.18 57.43,112.06 57.43,111.65 57.55,111.53 57.72,111.53 57.84,111.65 57.84,112.06 57.96,112.18 58.39,112.18 58.52,112.06 58.52,111.74 58.64,111.62 59.01,111.62 59.14,111.74 59.14,112.64 v1(59.98,113.48)
CPSW_RGMII2_TXC_R: length 5
  TOP w0.14: U18.AB19 48.3,110.08 49.83,110.08 50.79,111.04 R56.1
CPSW_RGMII_INTN: length 22.4
  TOP w0.14: J4.10 55.96,114.48 v1(55.76,114.28) ; v1(61.52,102.63) 61.52,103.12 R78.2
  L03_SIG01 w0.102: v1(61.52,102.63) 61.52,103.37 60.28,104.61 60.28,111.19 59.24,112.23 56.85,112.23 56.37,112.71 56.37,113.67 v1(55.76,114.28)
  BOTTOM w0.14: v1(61.52,102.63) 61.46,102.63 61.32,102.49 61.32,101.92 61.13,101.73 R335.1 61.24,101.16 61.24,100.68 61.67,100.25 61.67,98.42 U78.44
CPSW_RGMII_TXC_R: length 1.1
  TOP w0.132: U18.AB17 v1(48.28,108.46)
  BOTTOM w0.14: R322.1 v1(48.28,108.46)
CS_LM5141: length 12.9
  L03_SIG01 w0.254: v1(35.44,55.39) 35.44,47.96 36.35,47.04 36.35,44.61 v1(36.95,44.01)
  BOTTOM w0.254: U89.18 36.6,44.36 v1(36.95,44.01)
CSI0_FLEX_RXCLKN: length 20.1
  TOP w0.089: v1(70.47,138.75) 70.23,138.99 69.99,138.99 69.89,138.89 69.89,137.94 70.19,137.64 70.19,136.18 70.33,136.04 U8.28
  BOTTOM w0.089: v1(70.47,138.75) 70.23,138.99 69.86,138.99 69.57,139.29 69.57,140.55 69.96,140.94 71.19,140.94 71.41,141.15 71.41,141.77 71.18,141.99 70.08,141.99 69.65,142.42 69.65,143.06 70.08,143.48 71.09,143.48 71.36,143.75 71.36,144.64 69.71,146.29 69.71,148.47 69.58,148.61 J20.8
CSI0_FLEX_RXCLKP: length 20.1
  TOP w0.089: v1(70.47,139.46) 70.23,139.22 69.9,139.22 69.66,138.99 69.66,137.84 69.96,137.54 69.96,136.18 69.83,136.04 U8.29
  BOTTOM w0.089: J20.9 70.08,148.63 69.94,148.49 69.94,146.39 71.59,144.74 71.59,143.65 71.19,143.25 70.17,143.25 69.88,142.96 69.88,142.51 70.17,142.22 71.27,142.22 71.64,141.86 71.64,141.06 71.29,140.71 70.05,140.71 69.79,140.45 69.79,139.38 69.96,139.22 70.22,139.22 v1(70.47,139.46)
CSI0_FLEX_RXN0: length 20.1
  TOP w0.089: U8.26 71.33,136.04 71.19,136.18 71.19,136.42 v1(71.46,136.68)
  BOTTOM w0.089: J20.2 66.58,148.59 66.71,148.45 66.71,145.38 66.53,145.21 66.15,145.21 65.78,144.84 65.78,140.46 66.15,140.09 66.53,140.09 66.71,139.91 66.71,137.74 68.69,135.77 70.94,135.77 71.29,136.12 71.29,136.51 v1(71.46,136.68)
CSI0_FLEX_RXN1: length 20.1
  TOP w0.089: v1(72.83,138.75) 72.6,138.52 72.6,137.76 72.19,137.35 72.19,136.18 72.33,136.04 U8.24
  BOTTOM w0.089: v1(72.83,138.75) 72.67,138.59 72.67,138.27 72.41,138 68.85,138 68.21,138.64 68.21,140.8 68.62,141.2 68.62,142.44 68.21,142.85 68.21,143.61 68.6,144 68.6,145.62 68.21,146.01 68.21,148.5 68.08,148.63 J20.5
CSI0_FLEX_RXN2: length 20.1
  TOP w0.089: v1(74.46,137.21) 74.2,137.46 73.47,137.46 73.19,137.18 73.19,136.18 73.33,136.04 U8.22
  BOTTOM w0.089: v1(74.46,137.21) 74.23,137.43 73.9,137.43 73.64,137.69 73.64,139.02 73.99,139.36 74.61,139.36 74.82,139.57 74.82,139.87 74.61,140.09 73.99,140.09 73.64,140.43 73.64,140.92 73.99,141.27 74.61,141.27 74.82,141.48 74.82,141.78 74.61,141.99 73.99,141.99 73.64,142.34 73.64,144.36 71.21,146.8 71.21,148.42 71.08,148.56 J20.11
CSI0_FLEX_RXN3: length 20.1
  TOP w0.089: U8.20 74.3,134.07 74.44,134.2 74.71,134.2 74.93,134.42 74.93,135.24 v1(75.25,135.56)
  BOTTOM w0.089: J20.14 72.58,148.58 72.71,148.44 72.71,147.12 76.12,143.71 76.12,135.35 75.75,134.97 75,134.97 74.87,135.11 74.87,135.51 74.97,135.62 75.18,135.62 v1(75.25,135.56)
CSI0_FLEX_RXP0: length 20.1
  TOP w0.089: v1(70.7,136.68) 70.96,136.42 70.96,136.18 70.83,136.04 U8.27
  BOTTOM w0.089: J20.3 67.08,148.62 66.94,148.49 66.94,145.29 66.63,144.98 66.25,144.98 66.01,144.74 66.01,140.55 66.25,140.32 66.63,140.32 66.94,140.01 66.94,137.83 68.78,135.99 70.84,135.99 71.06,136.21 71.06,136.88 70.97,136.97 70.79,136.97 70.7,136.87 v1(70.7,136.68)
CSI0_FLEX_RXP1: length 20.1
  TOP w0.089: v1(72.07,138.75) 72.37,138.45 72.37,137.85 71.96,137.44 71.96,136.18 71.83,136.04 U8.25
  BOTTOM w0.089: J20.6 68.58,148.65 68.44,148.51 68.44,146.1 68.83,145.71 68.83,143.9 68.44,143.51 68.44,142.94 68.85,142.54 68.85,141.11 68.44,140.7 68.44,138.73 68.94,138.23 72.31,138.23 72.44,138.36 72.44,138.9 72.32,139.03 72.17,139.03 72.07,138.92 v1(72.07,138.75)
CSI0_FLEX_RXP2: length 20.1
  TOP w0.089: U8.23 72.83,136.04 72.96,136.18 72.96,137.28 73.37,137.69 74.22,137.69 v1(74.46,137.92)
  BOTTOM w0.089: J20.12 71.58,148.6 71.44,148.47 71.44,146.89 73.87,144.46 73.87,142.43 74.08,142.22 74.71,142.22 75.05,141.87 75.05,141.38 74.71,141.04 74.08,141.04 73.87,140.83 73.87,140.53 74.08,140.31 74.71,140.31 75.05,139.97 75.05,139.48 74.71,139.13 74.08,139.13 73.87,138.92 73.87,137.78 73.99,137.66 74.2,137.66 v1(74.46,137.92)
CSI0_FLEX_RXP3: length 20.1
  TOP w0.089: v1(74.49,135.56) 74.71,135.34 74.71,134.52 74.62,134.43 74.44,134.43 74.3,134.57 U8.21
  BOTTOM w0.089: J20.15 73.08,148.6 72.94,148.47 72.94,147.21 76.35,143.8 76.35,135.25 75.84,134.74 74.91,134.74 74.64,135.02 74.64,135.4 v1(74.49,135.56)
CSI0_MIPI_RXCLKN: length 13.7
  TOP w0.089: J1.7 66.08,142.02 65.94,141.88 65.94,141.61 65.7,141.37 63.09,141.37 62.28,140.56 62.28,137.58 63.07,136.79 65.38,136.79 65.69,136.48 65.69,136.18 65.83,136.04 U8.37
CSI0_MIPI_RXCLKP: length 13.7
  TOP w0.089: J1.5 65.58,142.02 65.71,141.88 65.71,141.7 65.6,141.6 63,141.6 62.06,140.66 62.06,137.48 62.97,136.57 65.28,136.57 65.46,136.39 65.46,136.18 65.33,136.04 U8.38
CSI0_MIPI_RXN0: length 13.7
  TOP w0.089: U8.35 66.83,136.04 66.69,136.18 66.69,137.24 66.11,137.82 64.14,137.82 63.37,138.6 63.37,139.8 63.9,140.33 66.63,140.33 67.44,141.14 67.44,141.88 67.58,142.02 J1.11
CSI0_MIPI_RXN1: length 13.7
  TOP w0.089: U8.33 67.83,136.04 67.69,136.18 67.69,138.01 67,138.7 64.72,138.7 64.58,138.83 64.58,139.22 64.71,139.34 67.12,139.34 68.94,141.17 68.94,141.88 69.08,142.02 J1.15
CSI0_MIPI_RXN2: length 13.7
  TOP w0.089: J1.19 70.58,142.02 70.44,141.88 70.44,141.75 70.55,141.64 70.86,141.64 71.19,141.3 71.19,141.05 71.59,140.65 72.26,140.65 72.53,140.37 72.53,139.88 72.24,139.58 71.16,139.58 70.57,140.17 69.47,140.17 68.62,139.33 68.62,137.73 69.04,137.3 69.04,136.76 68.69,136.4 68.69,136.18 68.83,136.04 U8.31
CSI0_MIPI_RXN3: length 13.7
  TOP w0.089: U8.18 74.3,133.07 74.38,133.15 74.83,133.15 76.02,134.34 76.02,138.07 72.61,141.49 72.18,141.49 72,141.67 72,141.89 72.08,141.97 J1.23
CSI0_MIPI_RXP0: length 13.7
  TOP w0.089: U8.36 66.33,136.04 66.46,136.18 66.46,137.14 66.01,137.59 64.05,137.59 63.14,138.5 63.14,139.9 63.81,140.56 66.54,140.56 67.21,141.24 67.21,141.88 67.08,142.02 J1.9
CSI0_MIPI_RXP1: length 13.7
  TOP w0.089: J1.13 68.58,142.02 68.71,141.88 68.71,141.26 67.02,139.57 64.62,139.57 64.35,139.31 64.35,138.74 64.63,138.47 66.91,138.47 67.46,137.92 67.46,136.18 67.33,136.04 U8.34
CSI0_MIPI_RXP2: length 13.7
  TOP w0.089: U8.32 68.33,136.04 68.46,136.18 68.46,136.5 68.82,136.85 68.82,137.21 68.39,137.63 68.39,139.42 69.37,140.4 70.67,140.4 71.26,139.81 72.15,139.81 72.31,139.97 72.31,140.28 72.16,140.42 71.49,140.42 70.96,140.95 70.96,141.21 70.76,141.41 70.46,141.41 70.21,141.65 70.21,141.88 70.08,142.02 J1.17
CSI0_MIPI_RXP3: length 13.6
  TOP w0.089: U8.19 74.3,133.57 74.49,133.37 74.74,133.37 75.8,134.43 75.8,137.98 75.04,138.74 74.89,138.74 74.72,138.9 74.72,139.06 74.55,139.22 74.4,139.22 74.23,139.39 74.23,139.54 74.07,139.71 73.91,139.71 73.75,139.87 73.75,140.03 72.52,141.26 72.09,141.26 71.77,141.58 71.77,141.9 71.58,142.09 J1.21
CSI0_RXCLKN: length 53
  TOP w0.089: U8.6 67.83,131.56 67.69,131.43 67.69,130.27 67.45,130.03 67.19,130.03 66.91,129.75 v1(66.91,129.7) ; v1(49.29,106.02) 49.05,105.77 48.74,105.77 48.34,105.38 48.17,105.38 U18.AB14
  L10_SIG03 w0.089: v1(66.91,129.7) 66.91,129.99 67,130.08 67.32,130.08 67.42,129.97 67.42,128.23 66.13,126.94 66.13,120.54 65.94,120.35 65.47,120.35 65.28,120.54 65.28,125.87 64.9,126.25 64.28,126.25 63.92,125.89 63.92,114.99 54.69,105.76 49.55,105.76 49.46,105.85 49.46,105.85 v1(49.29,106.02)
CSI0_RXCLKP: length 53
  TOP w0.089: v1(49.29,105.3) 49.05,105.55 48.83,105.55 48.44,105.15 48.17,105.15 U18.AB13 ; v1(66.91,130.46) 67.11,130.26 67.35,130.26 67.46,130.37 67.46,131.43 67.33,131.56 U8.5
  L10_SIG03 w0.089: v1(49.29,105.3) 49.54,105.55 54.78,105.55 64.14,114.91 64.14,125.8 64.37,126.03 64.81,126.03 65.07,125.78 65.07,120.45 65.38,120.14 66.03,120.14 66.34,120.45 66.34,126.85 67.64,128.14 67.64,130.06 67.41,130.29 67.08,130.29 v1(66.91,130.46)
CSI0_RXN0: length 53.1
  TOP w0.089: U8.8 68.83,131.61 68.69,131.48 68.69,130.92 v1(68.93,130.68) ; U18.W12 v1(45.88,104.46)
  L10_SIG03 w0.089: v1(68.93,130.68) 68.78,130.68 68.67,130.57 68.67,130.29 68.77,130.18 69.4,130.18 69.5,130.27 69.82,130.27 69.91,130.18 70.41,130.18 71,130.78 71.71,130.78 72.07,130.41 72.07,117.23 57.35,102.52 48.36,102.52 47.17,103.7 46.41,103.7 46.07,104.04 46.07,104.27 v1(45.88,104.46)
CSI0_RXN1: length 53.1
  TOP w0.089: U18.Y13 v1(46.68,105.26) ; U8.11 70.33,131.51 70.19,131.38 70.19,130.85 69.22,129.89 69.22,129.59 v1(69.46,129.35)
  L10_SIG03 w0.089: v1(46.68,105.26) 46.88,105.47 47.09,105.47 47.29,105.66 47.99,105.66 49.3,104.35 55.45,104.35 66.13,115.03 66.13,115.5 65.2,116.43 65.2,116.73 65.42,116.94 65.72,116.94 66.64,116.02 67.12,116.02 67.62,116.52 67.62,117.88 67.84,118.09 68.93,118.09 69.27,118.43 69.27,118.91 68.93,119.25 67.84,119.25 67.62,119.46 67.62,119.76 67.84,119.97 68.93,119.97 69.27,120.31 69.27,120.79 68.93,121.12 67.84,121.12 67.54,121.42 67.54,125.85 67.85,126.16 68.73,126.16 69.22,126.65 69.22,129.1 v1(69.46,129.35)
CSI0_RXN2: length 53
  TOP w0.089: U18.AA13 v1(47.48,105.26) ; U8.13 71.33,131.51 71.19,131.38 71.19,130.65 70.58,130.03 70.58,129.28 70.75,129.11 70.92,129.11 v1(71.16,129.35)
  L10_SIG03 w0.089: v1(71.16,129.35) 71.16,129.12 71.08,129.03 70.69,129.03 70.39,128.73 70.39,125.44 70.18,125.22 68.77,125.22 68.43,124.89 68.43,124.41 68.77,124.07 70.18,124.07 70.39,123.86 70.39,123.56 70.18,123.34 68.77,123.34 68.43,123.01 68.43,122.53 68.77,122.19 70.18,122.19 70.39,121.98 70.39,117.72 56.24,103.58 48.83,103.58 48.14,104.27 48.14,104.66 47.91,104.9 47.57,104.9 47.48,104.99 v1(47.48,105.26)
CSI0_RXN3: length 53
  TOP w0.089: U8.15 72.33,131.51 72.19,131.38 72.19,131.08 73.35,129.92 73.35,128.52 73.12,128.28 72.85,128.28 v1(72.61,128.04) ; U18.AB11 48.17,102.98 49.6,102.98 49.82,102.76 49.82,102.35 v1(50.1,102.07)
  L10_SIG03 w0.089: v1(72.61,128.04) 72.61,128.18 72.77,128.34 73.08,128.34 73.23,128.19 73.23,126.17 73.57,125.83 73.94,125.83 74.16,125.62 74.16,125.32 73.94,125.11 73.57,125.11 73.23,124.77 73.23,124.29 73.57,123.95 73.94,123.95 74.16,123.74 74.16,123.44 73.94,123.23 73.57,123.23 73.23,122.89 73.23,116.86 58.01,101.64 49.89,101.64 49.78,101.74 49.78,101.92 49.93,102.07 v1(50.1,102.07)
CSI0_RXP0: length 53.1
  TOP w0.089: U18.W13 v1(45.88,105.26) ; U8.7 68.33,131.61 68.46,131.48 68.46,130.92 v1(68.22,130.68)
  L10_SIG03 w0.089: v1(45.88,105.26) 46.29,104.86 46.29,104.13 46.5,103.92 47.26,103.92 48.45,102.73 57.26,102.73 71.86,117.32 71.86,130.32 71.62,130.56 71.09,130.56 70.5,129.97 68.68,129.97 68.45,130.2 68.45,130.44 v1(68.22,130.68)
CSI0_RXP1: length 53.1
  TOP w0.089: U18.Y14 v1(46.68,106.06) ; U8.10 69.83,131.51 69.96,131.38 69.96,130.95 68.99,129.98 68.99,129.59 v1(68.75,129.35)
  L10_SIG03 w0.089: v1(68.75,129.35) 69,129.1 69,126.74 68.64,126.38 67.76,126.38 67.33,125.94 67.33,121.33 67.75,120.91 68.84,120.91 69.05,120.7 69.05,120.4 68.84,120.18 67.75,120.18 67.41,119.85 67.41,119.37 67.75,119.03 68.84,119.03 69.05,118.82 69.05,118.52 68.84,118.31 67.75,118.31 67.41,117.97 67.41,116.61 67.03,116.23 66.73,116.23 65.81,117.16 65.33,117.16 64.99,116.82 64.99,116.34 65.91,115.42 65.91,115.12 55.36,104.57 49.39,104.57 48.08,105.88 47.2,105.88 47,105.68 46.69,105.68 46.61,105.77 46.61,105.99 v1(46.68,106.06)
CSI0_RXP2: length 53
  TOP w0.089: U18.AA12 v1(47.48,104.46) ; U8.12 70.83,131.51 70.96,131.38 70.96,130.74 70.35,130.13 70.35,129.18 70.65,128.88 70.92,128.88 v1(71.16,128.64)
  L10_SIG03 w0.089: v1(47.48,104.46) 47.48,104.54 47.62,104.68 47.82,104.68 47.93,104.57 47.93,104.18 48.74,103.36 56.33,103.36 70.6,117.63 70.6,122.07 70.26,122.4 68.86,122.4 68.65,122.62 68.65,122.92 68.86,123.13 70.26,123.13 70.6,123.47 70.6,123.95 70.26,124.28 68.86,124.28 68.65,124.5 68.65,124.8 68.86,125.01 70.26,125.01 70.6,125.35 70.6,128.64 70.78,128.81 70.99,128.81 v1(71.16,128.64)
CSI0_RXP3: length 53
  TOP w0.089: v1(72.61,128.75) 72.85,128.51 73.02,128.51 73.13,128.61 73.13,129.82 71.96,130.98 71.96,131.38 71.83,131.51 U8.14 ; v1(49.39,102.07) 49.59,102.26 49.59,102.67 49.5,102.75 48.17,102.75 U18.AB10
  L10_SIG03 w0.089: v1(72.61,128.75) 72.8,128.56 73.17,128.56 73.44,128.28 73.44,126.26 73.65,126.05 74.03,126.05 74.37,125.71 74.37,125.23 74.03,124.89 73.65,124.89 73.44,124.68 73.44,124.38 73.65,124.17 74.03,124.17 74.37,123.83 74.37,123.35 74.03,123.01 73.65,123.01 73.44,122.8 73.44,116.77 58.1,101.42 49.8,101.42 49.57,101.66 49.57,101.89 v1(49.39,102.07)
CSI0_RXRCALIB: length 6.1
  TOP w0.132: U18.V10 v1(45.08,102.07)
  BOTTOM w0.14: R328.2 48.79,103.65 45.95,103.65 45.48,103.17 45.48,102.47 v1(45.08,102.07)
CSI_EN: length 30.8
  TOP w0.14: U2.21 v1(53.61,150.06) ; U8.2 65.83,131.56 66,131.38 v1(66,130.88)
  BOTTOM w0.14: R292.2 65.94,130.82 v1(66,130.88) 66,131.09 66.51,131.59 66.51,133.08 66.2,133.4 65.35,133.4 62.57,136.18 61.84,136.18 60.92,137.1 60.92,139.41 58.8,141.53 56.8,141.53 55.81,142.52 55.81,142.76 55.81,145.22 56.1,145.51 56.1,148.93 55.61,149.42 54.74,149.42 54.56,149.6 54.07,149.6 v1(53.61,150.06)
CSI_GPIO0: length 138.3
  TOP w0.14: v1(57.12,140.04) 57.12,140.53 56.78,140.87 U4.20
  L05_SIG02 w0.102: v1(63.83,52.01) 65.15,53.33 65.15,57.85 66.17,58.87 66.17,66.96 65.44,67.7 65.44,72.87 66.43,73.86 66.43,88.9 66.13,89.21 65.85,89.21 65.48,89.58 65.48,92.47 64.7,93.25 64.7,100.5 65.89,101.69 65.89,104.43 66.53,105.07 66.53,108.75 65.2,110.07 65.2,116.28 65.2,117 65.2,123.8 62.55,126.45 61.05,126.45 59.39,128.11 59.39,132.09 57.12,134.36 v1(57.12,140.04)
  L10_SIG03 w0.102: v1(71,152.19) 71.43,152.19 72.54,151.07 72.54,150.23 70.56,148.24 68.98,148.24 68.02,147.27 68.02,146.16 61.89,140.04 v1(57.12,140.04)
  BOTTOM w0.14: U92.14 55.2,46.31 59.98,51.09 62.92,51.09 v1(63.83,52.01) ; v1(71,152.19) 71.93,151.26 73.55,151.26 74.08,150.73 J20.17
CSI_GPIO1: length 143.6
  TOP w0.14: U4.18 54.96,138.87 55.41,138.42 58.7,138.42 v1(58.91,138.62)
  L05_SIG02 w0.102: v1(55.94,46.29) 55.98,46.29 56.42,46.72 58.88,46.72 60.56,45.05 61.49,45.05 61.7,45.25 64.16,45.25 66.09,47.18 66.09,50.34 67.8,52.04 67.8,63.43 68.29,63.93 68.29,77.35 66.9,78.74 66.9,90.12 65.94,91.07 65.94,98.37 66.7,99.12 66.7,102.02 67.34,102.65 67.34,103.11 67.06,103.39 67.06,105.63 67.55,106.12 67.55,108.47 67.55,117.54 66.48,118.62 66.48,131.07 62.89,134.66 62.89,136.77 61.04,138.62 v1(58.91,138.62)
  L10_SIG03 w0.102: v1(72.27,152.16) 72.85,151.58 72.85,149.87 70.89,147.92 69.12,147.92 68.49,147.29 68.49,146.31 60.8,138.62 v1(58.91,138.62)
  BOTTOM w0.14: v1(72.27,152.16) 72.77,151.66 73.86,151.66 74.58,150.95 J20.18 ; U92.15 55.7,46.05 v1(55.94,46.29)
CSI_GPIO2: length 4.4
  TOP w0.14: U4.17 v1(54.46,139.03)
  BOTTOM w0.14: U55.6 52.97,137.74 53.17,137.54 53.69,137.54 53.98,137.82 53.98,138.55 v1(54.46,139.03)
CSI_GPIO3: length 5.9
  TOP w0.14: U4.16 53.96,138.51 v1(54.46,138.01)
  BOTTOM w0.14: U55.3 52.96,135.79 54.46,137.29 v1(54.46,138.01)
CSI_GPIO4: length 6.1
  TOP w0.14: U4.15 v1(53.46,139.03)
  BOTTOM w0.14: v1(53.46,139.03) 53.96,139.53 54.85,139.53 55,139.37 55,138.64 55.26,138.39 U55.10
CSI_I2C2_NINT1: length 2
  TOP w0.14: R29.2 40.71,137.66 40.82,137.77 U5.8
CSI_I2C2_SCL: length 67.8
  TOP w0.14: R31.2 42.24,137.35 v1(42.12,137.47) U5.10 ; U3.8 v1(55.37,150.21)
  L05_SIG02 w0.102: v1(74.32,147.25) 71.49,150.08 64.98,150.08 64.57,150.48 59.9,150.48 59.49,150.89 56.47,150.89 55.79,150.21 v1(55.37,150.21)
  L10_SIG03 w0.102: v1(55.37,150.21) 55.9,149.68 55.9,148.39 55.21,147.7 47.06,147.7 46.8,147.96 45.71,147.96 45.51,147.76 41.29,147.76 41.01,147.48 41.01,145.31 41.45,144.87 49.38,144.87 50.31,143.94 50.31,141.49 48.16,139.34 43.99,139.34 v1(42.12,137.47)
  BOTTOM w0.14: J20.20 75.58,148.5 v1(74.32,147.25)
CSI_I2C2_SDA: length 68.9
  TOP w0.14: R30.2 41.47,137.31 v1(41.3,137.48) 41.47,137.64 U5.9 ; U3.1 v1(55.37,148.73)
  L05_SIG02 w0.102: v1(55.37,148.73) 56.26,149.62 57.25,149.62 57.89,150.25 64.39,150.25 64.8,149.85 70.77,149.85 73.82,146.8 74.77,146.8 v1(75.21,147.24)
  L10_SIG03 w0.102: v1(41.3,137.48) 41.58,137.76 41.85,137.76 43.66,139.57 48.04,139.57 50.03,141.56 50.03,143.48 49.49,144.03 41.01,144.03 40,145.03 40,146.14 40.62,146.76 40.62,148.1 41.6,149.08 44.6,149.08 45,148.68 55.32,148.68 v1(55.37,148.73)
  BOTTOM w0.14: J20.21 76.08,148.11 v1(75.21,147.24)
CSI_I2C_LT_EN: length 2.2
  TOP w0.14: U3.6 56.37,152.02 R4.1 R5.2
CSI_MIPI_GPIO0: length 26.9
  TOP w0.14: v1(56.51,143.1) 56.51,142.67 56.22,142.37 U4.1 ; J1.6 v1(65.58,150.93)
  L10_SIG03 w0.102: v1(65.58,150.93) 65.58,150.1 62.08,146.6 58.34,146.6 57.7,147.23 52.63,147.23 52.5,147.1 51.82,146.42 51.82,144.42 53.13,143.1 v1(56.51,143.1)
CSI_MIPI_GPIO1: length 28.1
  TOP w0.14: U4.3 v1(54.96,144.2) ; v1(65.66,151.95) 66.08,151.54 J1.8
  L10_SIG03 w0.102: v1(54.96,144.2) 54.23,143.47 53.13,143.47 52.12,144.48 52.12,146.4 52.73,147 57.61,147 58.28,146.34 60.64,146.34 61.24,145.73 61.88,145.73 66.04,149.9 66.04,151.57 v1(65.66,151.95)
CSI_MIPI_GPIO2: length 25.7
  TOP w0.14: v1(53.96,145.22) 54.46,144.72 U4.4 ; J1.18 v1(70.08,152.21)
  L10_SIG03 w0.102: v1(70.08,152.21) 70.08,150.88 68.66,149.47 66.72,149.47 62.18,144.92 60.05,144.92 59.34,145.63 54.37,145.63 v1(53.96,145.22)
CSI_MIPI_GPIO3: length 23.3
  TOP w0.14: U4.5 v1(53.96,144.2) ; J1.20 v1(70.58,151.26)
  L10_SIG03 w0.102: v1(53.96,144.2) 54.59,144.84 59.71,144.84 59.95,144.59 62.25,144.59 66.79,149.13 69.23,149.13 70.58,150.48 v1(70.58,151.26)
CSI_MIPI_GPIO4: length 32.7
  TOP w0.14: U4.6 53.46,144.72 v1(52.96,145.22) ; v1(71.58,152.86) J1.22
  L10_SIG03 w0.102: v1(71.58,152.86) 70.93,152.86 70.59,152.52 70.59,151.78 71.51,150.86 71.51,150.3 69.9,148.69 66.79,148.69 61.88,143.78 60.35,143.78 59.53,144.59 54.78,144.59 54.38,144.19 54.38,144 54.16,143.78 53.67,143.78 53.39,144.06 53.39,144.79 52.97,145.22 v1(52.96,145.22)
CSI_MIPI_I2C2_SCL: length 19.3
  TOP w0.14: v1(63.37,153.24) 64.08,152.53 J1.2 ; U3.5 v1(56.87,150.23)
  L10_SIG03 w0.102: v1(63.37,153.24) 63.46,153.15 63.46,149.07 61.49,147.1 59.11,147.1 56.87,149.34 v1(56.87,150.23)
  BOTTOM w0.14: R246.2 v1(56.87,150.23)
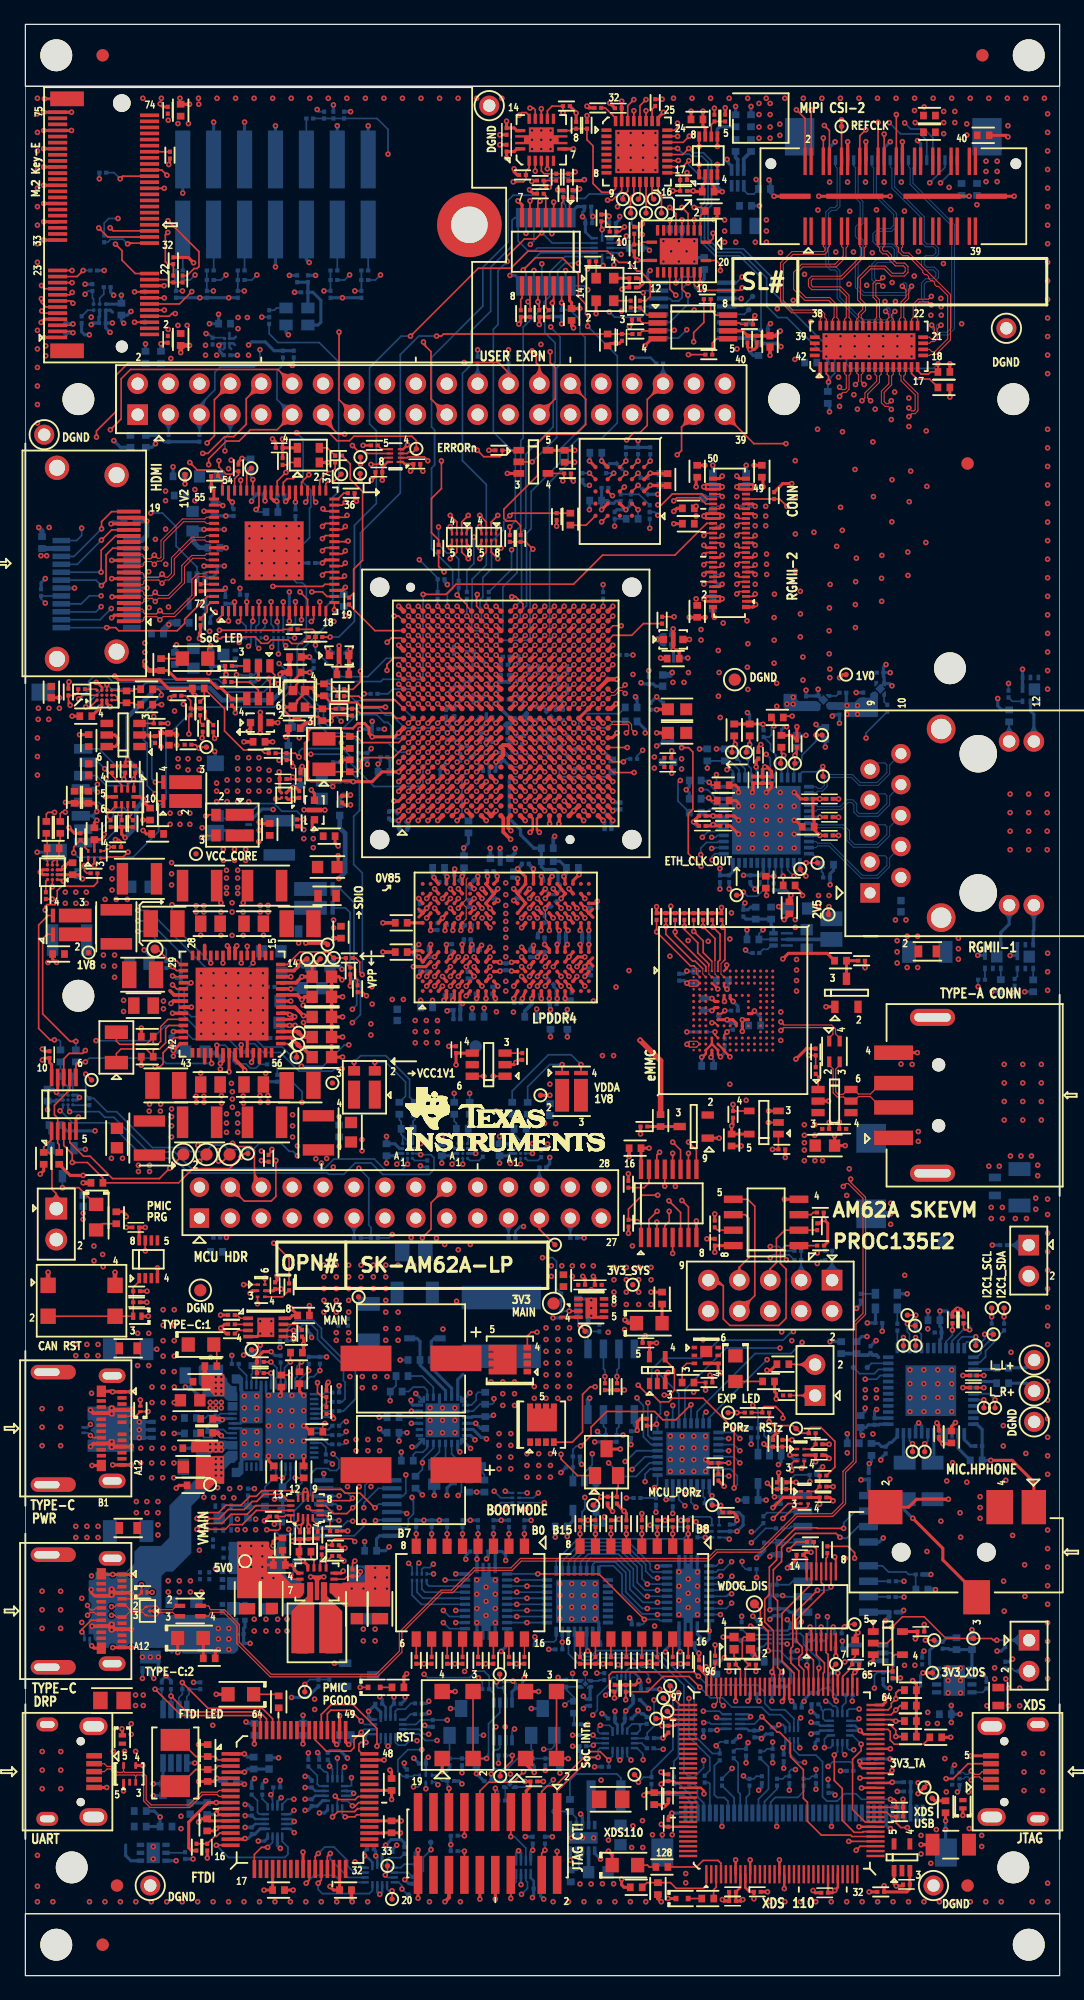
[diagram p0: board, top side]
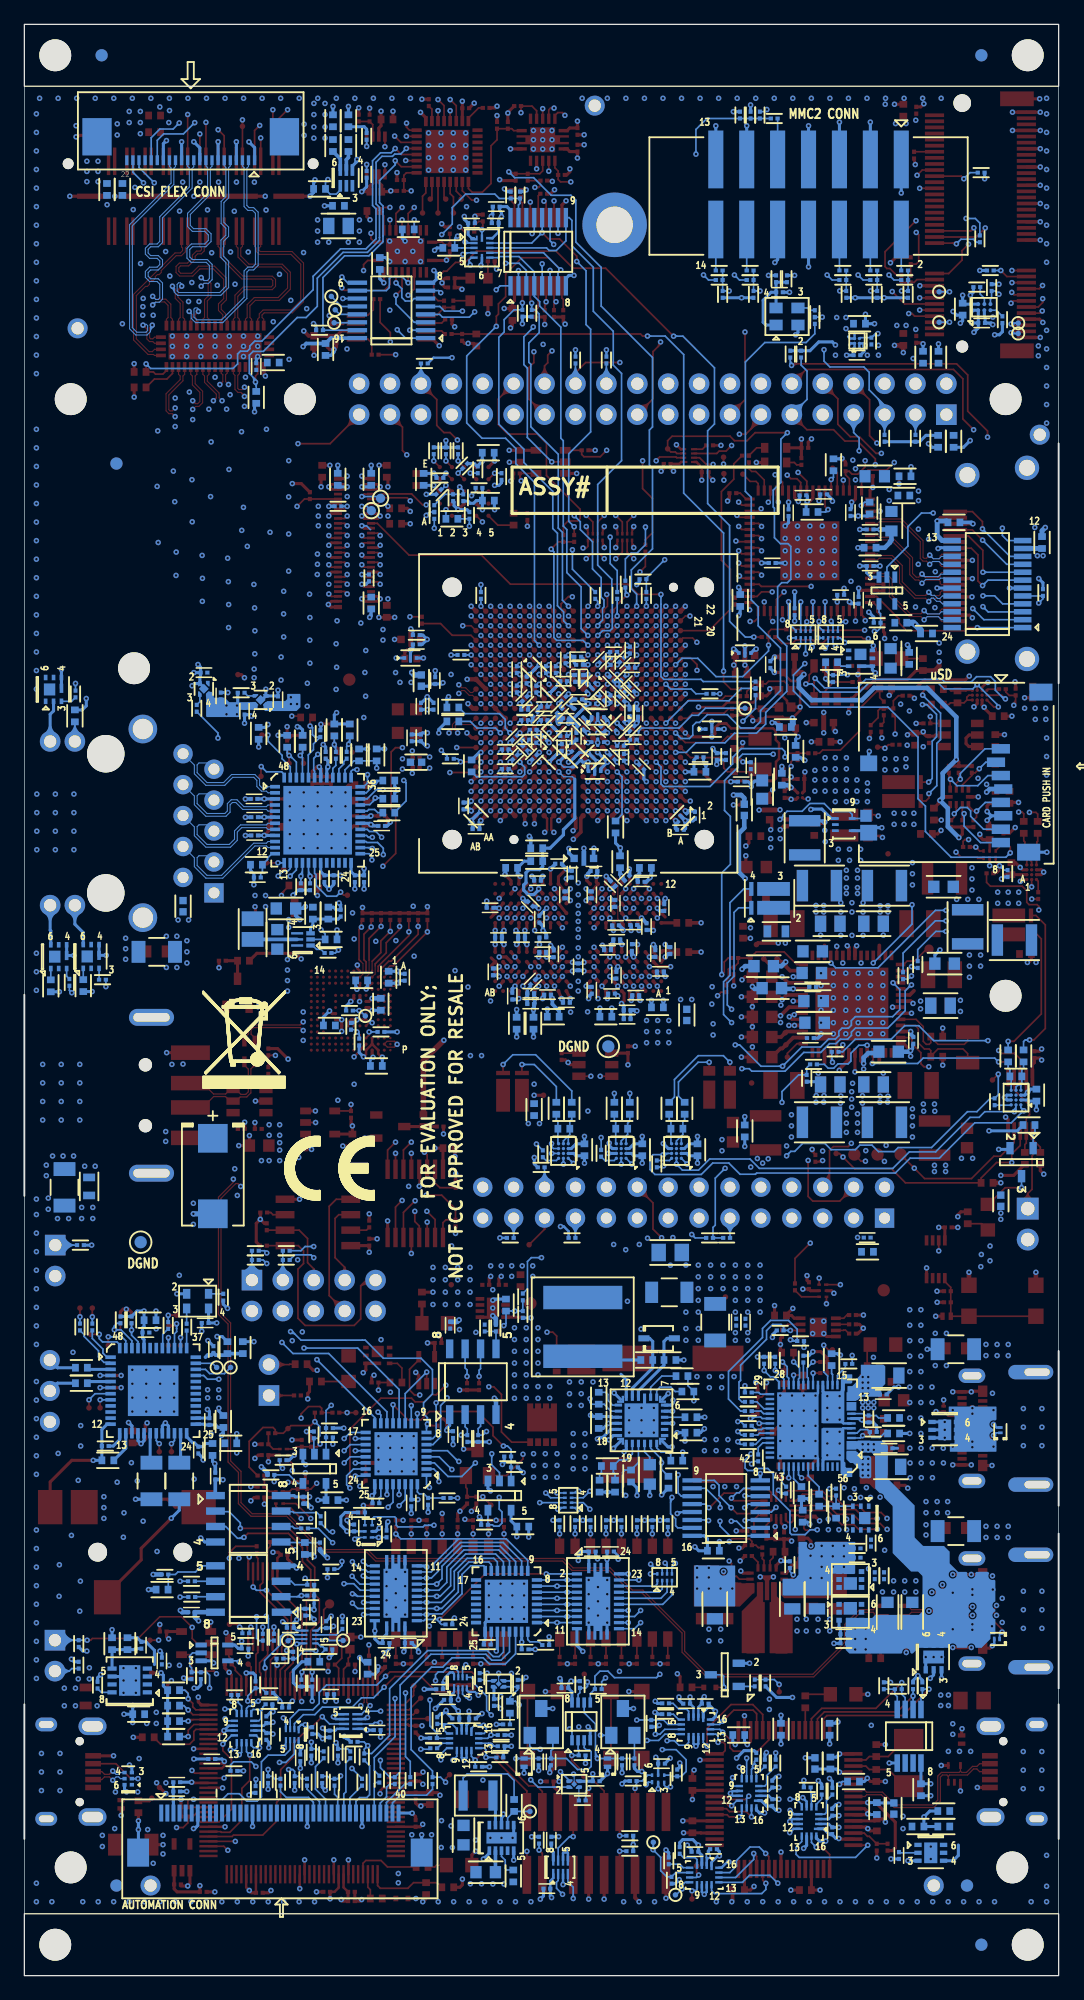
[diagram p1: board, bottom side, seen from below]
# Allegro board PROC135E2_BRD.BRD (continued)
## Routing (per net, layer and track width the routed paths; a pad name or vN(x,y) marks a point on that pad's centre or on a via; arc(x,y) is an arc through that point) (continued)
CSI_MIPI_I2C2_SDA: length 18.8
  TOP w0.14: U3.4 v1(56.87,148.75) ; J1.4 v1(64.58,153.24)
  L10_SIG03 w0.102: v1(64.58,153.24) 64.58,149.72 61.73,146.88 58.75,146.88 v1(56.87,148.75)
  BOTTOM w0.14: v1(56.87,148.75) R249.2
CSI_MIPI_LT_EN: length 2.4
  TOP w0.14: R20.1 R21.2 50.47,142.17 50.66,142.37 U4.10
CSI_MIPI_RSTZ: length 25.6
  TOP w0.14: U4.7 v1(52.96,144.2) ; v1(69.07,151.6) 68.58,151.11 J1.14
  L10_SIG03 w0.102: v1(52.96,144.2) 52.43,144.73 52.43,145.32 53.13,146.02 60.59,146.02 61.13,145.48 62.16,145.48 66.47,149.79 67.51,149.79 69.07,151.36 v1(69.07,151.6)
  BOTTOM w0.14: R255.1 v1(52.96,144.2)
CSI_REFCLK: length 34.4
  TOP w0.14: v1(67.08,152.41) TP1.1 J1.10 ; R34.2 59.79,136.18 v1(59.95,136.34)
  L10_SIG03 w0.102: v1(59.95,136.34) 60.41,136.8 60.41,136.94 70.14,146.67 72.08,146.67 73.74,148.33 73.74,152.21 73.27,152.68 72.91,152.68 72.24,153.35 68.02,153.35 v1(67.08,152.41)
CSI_RSTZ: length 15.8
  TOP w0.14: v1(47.84,145.82) 48.23,145.82 49.01,146.59 U2.10 ; v1(53.46,138.01) 52.96,138.51 U4.14
  L03_SIG01 w0.102: v1(53.46,138.01) 52,139.47 50.13,139.47 47.91,141.69 47.91,143.79 47.48,144.22 47.48,145.45 v1(47.84,145.82)
CSI_SEL1: length 3.2
  TOP w0.14: U8.16 72.83,131.58 73.28,131.13 74.31,131.13 R39.2
CSI_SEL2: length 38.3
  TOP w0.14: v1(75,132.37) R38.2 74.4,131.71 74.22,131.53 73.61,131.53 73.33,131.82 U8.17 ; v1(54.52,150.06) 54.02,149.56 U2.20
  BOTTOM w0.14: v1(54.52,150.06) 54.52,150.05 54.86,149.71 55.73,149.71 56.38,149.05 56.38,145.39 56.1,145.1 56.1,142.64 56.92,141.82 59.01,141.82 61.27,139.57 61.27,138.46 65.48,134.24 66.07,134.24 66.47,133.84 66.47,133.62 66.68,133.41 67.24,133.41 67.47,133.18 67.47,132.37 67.85,131.99 74.62,131.99 v1(75,132.37)
CSI_VLDO_SEL: length 12.2
  TOP w0.14: U2.23 v1(53.6,151.06)
  L10_SIG03 w0.102: v1(60.05,147.51) 60.05,148.04 56.61,151.49 54.03,151.49 v1(53.6,151.06)
  BOTTOM w0.14: v1(60.05,147.51) 60.25,147.32 R251.1 60.25,146.7 59.87,146.32 59.36,146.32 59.04,146.64 U50.1
DEBOUNCE_CAN_FD_WKUP: length 10.3
  TOP w0.14: U35.1 9.35,57.01 8.86,56.53 R149.2 C110.2 D3.2 SW1.3 SW1.2
DEBOUNCE_GPIO_INT_MCU_SOC: length 17.7
  TOP w0.14: SW5.3 SW5.2 44.53,17.83 44.54,17.83 v1(44.62,17.83)
  BOTTOM w0.14: C484.2 40.44,17.83 39.54,16.93 38.67,16.93 38.42,17.18 38.42,18.4 38.57,18.55 38.82,18.55 38.99,18.72 U108.3 ; C484.2 R538.2 D12.2 44.53,17.83 44.54,17.83 v1(44.62,17.83) ; C484.2 41.72,18.48 41.57,18.63 Q13.2
DEBOUNCE_MCU_RESETZ: length 27.1
  TOP w0.14: Q3.2 48.71,40.09 48.61,40 C134.2 R183.2 v1(47.32,39.33) 46.66,38.67 TP70.1
  L03_SIG01 w0.102: v1(47.32,39.33) 47.32,39.31 44.99,36.97 44.99,34.58 43.46,33.06 43.46,25.44 40.2,22.18 v1(40.2,20.26)
  BOTTOM w0.14: v1(40.2,20.26) 39.99,20.05 U108.1
DEBOUNCE_SOC_WARMRESETN: length 16.6
  TOP w0.14: SW4.3 SW4.2 v1(37.91,17.83)
  BOTTOM w0.14: Q14.2 C485.2 R539.2 D13.2 v1(37.91,17.83) 38.06,17.99 38.06,20.67 38.99,21.6 U108.6
DIR: length 15.6
  TOP w0.132: v1(42.11,32.99) 47.13,32.99 v1(50.87,29.25)
  BOTTOM w0.14: U98.2 52.16,29.15 52.06,29.25 v1(50.87,29.25) 50.87,28.99 50.72,28.85 R480.1 ; U101.2 v1(42.11,32.99)
DRAIN1: length 3.2
  BOTTOM w0.203: U90.8 17.69,45.36 v1(18,45.66) ; v1(18,47.6) 17.78,47.81 U90.15 ; v1(19.01,47.6) 19.38,47.96 U90.19
  vias: v1(18,46.63) v1(19.01,46.63) v1(19.01,45.66)
DRAIN2: length 3.2
  BOTTOM w0.203: U90.7 17.71,44.96 v1(18,44.67) ; U90.56 17.78,42.52 v1(18,42.74) ; U90.52 19.38,42.37 v1(19.01,42.74)
  vias: v1(18,43.71) v1(19.01,44.67) v1(19.01,43.71)
EEPROM_A0: length 1.2
  TOP w0.132: U38.1 17.66,53.99 17.4,54.25 R151.2
EEPROM_A1: length 1.1
  TOP w0.132: U38.2 R154.1
EEPROM_A2: length 1.2
  TOP w0.132: U38.3 17.68,52.99 17.66,53.01 17.51,53.01 17.23,52.73 R156.1
EEPROM_WP: length 1.7
  TOP w0.132: U38.7 22.28,53.49 R155.1
EMMC_RSTN: length 10.8
  TOP w0.14: v1(58.15,71.55) R133.2 U32.4 ; U28.K5 56.67,78.26 v1(56.42,78.26)
  L10_SIG03 w0.102: v1(58.15,71.55) 58.42,71.82 58.42,77.38 57.81,77.99 56.69,77.99 v1(56.42,78.26)
EN_DRV_OUT: length 2.9
  TOP w0.14: U27.29 12.73,83.04 12.45,83.33 11.84,83.33 10.85,84.31 TP31.1
EN_LM5141_ON: length 90.9
  TOP w0.14: v1(14.53,101.65) 14.58,101.7 R81.2
  L03_SIG01 w0.102: v1(15.22,50.78) 15.22,55.41 10.61,60.03 10.61,64.52 9.73,65.4 9.73,66.77 9.03,67.47 9.03,82.91 10.44,84.32 10.44,89.72 11.72,90.99 13.99,90.99 16.45,93.45 16.45,95.35 17.03,95.92 17.03,101.37 16.28,102.12 15.05,102.12 14.58,101.65 v1(14.53,101.65)
  L10_SIG03 w0.102: v1(15.22,50.78) 15.26,50.81 15.56,50.81 16.98,49.4 16.98,42.54 17.85,41.66 23.37,41.66 24.18,40.85 25.53,40.85 26.2,41.52 29.93,41.52 30.74,42.33 32.44,42.33 v1(32.63,42.13)
  BOTTOM w0.14: R444.1 32.63,41.58 v1(32.63,42.13) 32.63,42.42 33.53,43.32 U89.23
ETH1_EARTH:
  vias: v1(76.68,85.2) v1(76.68,84.34) v1(76.68,83.48) v1(80.93,97.04) v1(80.93,95.52) v1(80.93,93.99) v1(80.93,92.47) v1(82.45,97.04) v1(82.45,95.52) v1(82.45,93.99) v1(82.45,92.47) v1(83.97,97.04) v1(83.97,95.52) v1(83.97,93.99) v1(83.97,92.47)
ETH_CAN_INH: length 4.3
  TOP w0.14: R70.1 13.17,105.12 13.58,104.7 R75.2 R73.2 14.66,104.07 14.84,103.9 14.84,103.31 R82.1
ETH_CAN_INH_PREREG: length 0.9
  TOP w0.14: R76.1 14.37,102.93 R81.1
ETH_CAN_INH_SOC: length 9.8
  TOP w0.14: R73.1 14.7,104.97 R65.2 16.37,104.05 16.37,102.22 17.93,100.66 19.39,100.66 19.66,100.4 R88.1
EXP_CLKOUT0: length 28.6
  TOP w0.14: R59.1 22.75,109.41 21.89,109.41 21.6,109.7 20.2,109.7 19.93,109.42 19.4,109.42 18.87,109.94 16.2,109.94 16.06,109.81 v1(15.64,109.81)
  L10_SIG03 w0.102: v1(15.64,109.81) 15.54,109.91 15.54,110.57 14.62,111.49 14.62,113.42 15.11,113.9 15.11,121.42 15.72,122.03 15.72,123.78 15.49,124.01 15.49,124.82 15.89,125.23 v1(16.4,125.23)
  BOTTOM w0.14: J3.7 16.85,126.74 16.4,126.29 v1(16.4,125.23)
EXP_EHRPWM1_B: length 47.8
  TOP w0.132: U18.B20 v1(31.48,110.86)
  L05_SIG02 w0.102: J3.33 50.7,127.37 51.29,127.37 52.89,125.77 53.95,125.77 54.74,124.98 54.74,118.63 51.56,115.46 47.48,115.46 44.68,112.66 44.68,108.29 44.45,108.07 44.45,108.07 43.31,108.07 43.08,107.83 43.08,107.48 42.86,107.26 42.51,107.26 42.28,107.03 42.28,106.63 42.11,106.47 36.91,106.47 36.68,106.7 36.68,107.03 36.45,107.26 36.11,107.26 35.88,107.5 35.88,109.45 35.67,109.67 34.47,109.67 34.28,109.85 34.28,110.27 34.09,110.47 32.1,110.47 31.7,110.86 v1(31.48,110.86)
EXP_GPIO0_14: length 24.9
  TOP w0.14: v1(28.4,124.12) 28.96,124.12 29.51,124.67 U10.7
  L05_SIG02 w0.102: v1(28.4,124.12) 27.74,124.78 25.58,124.78 23.31,127.05 23.31,131.57 24.03,132.3 33.07,132.3 J3.22
EXP_GPIO0_14_LT: length 43.7
  TOP w0.132: U18.G20 v1(35.48,110.86)
  TOP w0.14: v1(33.07,124.41) 33.07,124.44 32.79,124.73 31.45,124.73 31.39,124.67 U10.2
  L10_SIG03 w0.102: v1(33.07,124.41) 33.05,124.44 30.42,124.44 30.18,124.69 27.45,124.69 26.2,123.44 24.87,123.44 22.6,121.17 22.6,120.11 22.08,119.59 22.08,113.41 21.81,113.15 21.81,112.5 22.21,112.1 24.59,112.1 25.31,112.82 25.83,112.82 26.79,113.79 26.79,114.63 28.25,116.09 31.94,116.09 35.09,112.93 35.6,112.93 35.88,112.65 35.88,111.24 35.51,110.86 v1(35.48,110.86)
EXP_GPIO0_32: length 18.2
  TOP w0.14: J3.30 46.05,129.48 46.05,127.39 45.27,126.61 42.85,126.61 42.09,125.85 42.09,123.2 39.32,120.44 39.32,119.67 39.52,119.47 40.31,119.47 40.7,119.08 R52.1
EXP_GPIO0_33: length 34.6
  TOP w0.132: U18.L17 v1(38.68,108.46)
  L05_SIG02 w0.102: v1(38.68,108.46) 39.11,108.46 39.47,108.83 39.47,110.15 39.79,110.47 40.45,110.47 40.68,110.7 40.68,111.09 40.86,111.26 41.27,111.26 41.48,111.48 41.48,112.61 41.48,112.61 41.48,112.63 45.32,116.47 51.08,116.47 53.8,119.19 53.8,123.63 50.93,126.51 49.03,126.51 J3.31
EXP_GPIO0_36: length 37.5
  TOP w0.132: U18.M18 v1(40.28,109.26)
  L05_SIG02 w0.102: v1(40.28,109.26) 40.28,109.4 40.68,109.8 40.68,110.23 40.91,110.47 42.05,110.47 42.06,110.48 42.06,110.48 42.28,110.69 42.28,112.7 45.82,116.24 51.26,116.24 54.05,119.03 54.05,123.72 50.98,126.79 49.15,126.79 48.45,127.49 48.45,128.99 48.08,129.35 45.93,129.35 J3.29
EXP_GPIO0_38: length 67.6
  TOP w0.132: U18.R17 v1(42.68,108.46)
  L05_SIG02 w0.102: v1(42.68,108.46) 42.28,108.06 42.28,107.49 42.05,107.26 36.91,107.26 36.91,107.27 36.68,107.5 36.68,107.53 36.68,107.53 36.68,108.68 36.86,108.86 37.25,108.86 37.48,109.1 37.48,109.44 37.71,109.67 38.05,109.67 38.28,109.9 38.28,110.23 38.51,110.46 38.9,110.46 39.88,111.44 39.88,112.63 40.11,112.86 40.41,112.86 44.85,117.31 50.77,117.31 52.41,118.95 52.41,123.88 51.06,125.24 48.41,125.24 47.32,126.33 26.88,126.33 26.61,126.06 25.99,126.06 25.74,126.32 25.74,129.47 J3.16
EXP_GPIO0_39: length 53.8
  TOP w0.132: U18.K17 v1(37.88,108.46)
  L05_SIG02 w0.102: v1(37.88,108.46) 38.28,108.86 38.85,108.86 38.85,108.87 38.86,108.87 39.17,109.18 39.17,110.44 39.99,111.26 40.45,111.26 40.68,111.5 40.68,111.83 41.07,112.22 41.07,112.72 45.07,116.73 50.93,116.73 52.88,118.68 52.88,124.18 51.36,125.69 48.8,125.69 47.61,126.88 31.38,126.88 30.76,127.5 30.76,129.53 J3.18
EXP_GPIO0_40/PR0_ECAP0_IN_APWM_: length 42.2
  TOP w0.132: U18.K18 v1(37.88,109.26)
  L05_SIG02 w0.102: v1(37.88,109.26) 37.88,109.14 37.48,108.74 37.48,108.3 37.71,108.06 41.22,108.06 41.22,108.07 41.25,108.07 41.48,108.3 41.48,108.63 41.71,108.86 43.68,108.86 43.88,109.07 43.88,112.7 46.92,115.74 51.46,115.74 54.51,118.78 54.51,124.78 53.95,125.34 52.86,125.34 51.13,127.06 49.28,127.06 48.65,127.69 48.65,129.42 J3.32
EXP_GPIO0_41: length 32.5
  TOP w0.132: U18.M19 v1(40.28,110.06)
  TOP w0.14: J3.37 53.93,127.18 53.93,125.26 v1(53.57,124.91)
  L05_SIG02 w0.102: v1(53.57,124.91) 54.28,124.19 54.28,118.94 51.34,115.99 46.41,115.99 43.08,112.66 43.08,109.9 42.85,109.67 42.83,109.66 41.71,109.66 41.48,109.43 41.48,109.08 41.27,108.86 39.95,108.86 39.84,108.97 39.84,109.63 v1(40.28,110.06)
EXP_GPIO0_42: length 51.6
  TOP w0.132: U18.M21 v1(40.28,111.66)
  TOP w0.14: J3.13 24.47,127.84 25.71,126.6 v1(26.24,126.6)
  L05_SIG02 w0.102: v1(40.28,111.66) 40.28,111.84 40.71,112.28 40.71,112.77 45,117.06 50.85,117.06 52.65,118.85 52.65,124 51.18,125.46 48.57,125.46 47.43,126.6 v1(26.24,126.6)
EXP_GPIO1_22: length 87.1
  TOP w0.132: U18.F14 v1(34.68,106.06)
  TOP w0.14: J3.15 25.78,129.43 v1(25.78,134.99)
  L10_SIG03 w0.102: v1(34.68,106.06) 34.45,106.06 34.05,105.67 33.72,105.67 33.48,105.43 33.48,105.42 33.48,105.1 33.25,104.86 32.91,104.86 32.68,104.63 32.68,104.6 32.68,104.6 32.68,104.3 32.13,103.75 30.98,103.75 30.7,103.47 29.05,103.47 28.77,103.75 27.73,103.75 26.23,102.25 24.08,102.25 22.74,100.9 22.11,100.9 21.83,100.62 17.98,100.62 16.46,102.15 14.03,102.15 13.04,103.13 12.1,103.13 11.94,103.29 11.3,103.29 8.89,105.69 8.89,110.63 8.75,110.76 8.13,111.39 8.13,121.22 9.9,122.99 9.9,125.93 8.03,127.8 8.03,131.12 9.25,132.35 12.03,132.35 12.38,132.7 12.38,133.61 13.22,134.45 15.01,134.45 17.17,136.62 24.15,136.62 v1(25.78,134.99)
EXP_HAT_DETECT: length 103.4
  TOP w0.14: v1(62.51,125.82) 59.87,125.82 J3.39 ; v1(51.88,45.3) 51.75,45.17 R172.1
  L05_SIG02 w0.102: v1(62.51,125.82) 64.21,124.12 64.21,116.05 64.76,115.5 64.76,107.31 66.03,106.04 66.03,105.19 65.46,104.61 65.46,101.66 64.47,100.67 64.47,93.03 65.1,92.4 65.1,89.48 65.59,88.99 65.59,87.18 65.25,86.84 65.25,73.69 63.59,72.03 63.59,58.96 64.86,57.69 64.86,53.98 63.78,52.9 v1(63.12,52.9)
  BOTTOM w0.14: U92.8 51.95,45.22 v1(51.88,45.3) 51.88,45.83 52.19,46.14 52.19,47.05 51.46,47.77 51.46,49.77 52.4,50.71 55.5,50.71 56.98,52.19 57.22,52.19 62.26,52.19 62.97,52.9 v1(63.12,52.9)
EXP_I2C2_NINT0: length 2
  TOP w0.14: U5.4 42.77,146.17 R17.2
EXP_I2C2_SCL: length 65.4
  TOP w0.14: U5.6 v1(41.47,145.76)
  L10_SIG03 w0.102: v1(19.28,133.54) 19.41,133.67 23.01,133.67 23.93,132.75 33.81,132.75 35.03,133.97 38.18,133.97 39.29,132.86 43.59,132.86 44.5,133.77 44.5,135.4 45.05,135.95 45.53,135.95 47.64,138.06 49.24,138.06 49.61,138.44 49.61,138.91 51.97,141.27 51.97,143.9 49.37,146.5 46.98,146.5 46.74,146.26 41.97,146.26 v1(41.47,145.76)
  BOTTOM w0.14: v1(19.28,133.54) 19.28,132.6 18.8,132.12 16,132.12 15.57,131.69 15.57,130.24 14.31,128.97 J3.5 R293.2
EXP_I2C2_SDA: length 65.5
  TOP w0.14: v1(42.3,145.74) 42.12,145.56 U5.5
  L10_SIG03 w0.102: J3.3 10.53,129.44 10.53,131.66 10.99,132.12 12.25,132.12 13.66,133.52 14.96,133.52 17.22,135.78 24.31,135.78 25.69,134.4 27.26,134.4 28.14,135.28 33.88,135.28 35.47,136.87 42.18,136.87 44.37,139.06 48.56,139.06 49.63,140.13 50.12,140.13 50.83,140.85 50.83,142.2 51.14,142.51 51.14,143.99 49.46,145.67 48.38,145.67 47.94,145.23 42.81,145.23 v1(42.3,145.74)
  BOTTOM w0.14: R294.2 J3.3
EXP_PS_3V3_EN: length 169
  L03_SIG01 w0.102: v1(15.8,40.08) 15.39,40.08 14.56,40.91 14.56,55.03 10.94,58.66 8.2,58.66 7.19,59.67 6.09,59.67 5.64,59.22 v1(5.64,58.71)
  L10_SIG03 w0.102: v1(14.85,134.86) 13.76,135.95 12.34,135.95 12.11,136.17 7.06,136.17 6.58,135.7 6.58,131.66 7.39,130.86 7.39,127.48 9.37,125.49 9.37,123.25 7.57,121.45 7.57,110.91 4.85,108.19 4.85,106.21 3.26,104.62 3.26,103.92 1.98,102.63 1.98,90.83 1.02,89.87 1.02,67.56 1.64,66.94 1.64,65.42 1.05,64.83 1.05,59.67 2.01,58.71 v1(5.64,58.71) ; v1(15.8,40.08) 16.52,40.8 17.01,40.8 17.52,41.31 23.24,41.31 24,40.56 25.73,40.56 26.33,41.16 30.02,41.16 30.91,42.06 31.97,42.06 32.34,41.69 32.84,41.69 34.03,42.88 34.03,43.33 34.82,44.11 34.82,45.73 35.13,46.04 35.7,46.04 36.07,46.41 38.63,46.41 39.18,45.86 48.66,45.86 v1(50.26,47.45)
  BOTTOM w0.14: U92.6 51.43,43.61 50.79,44.25 50.79,46.82 50.26,47.35 v1(50.26,47.45) ; v1(14.85,134.86) 15.06,134.86 R286.2 16.3,134.53 U57.B2
EXP_PS_5V0_EN: length 160
  L03_SIG01 w0.102: v1(6.4,58.23) 7.65,58.23 8.46,57.41 11.13,57.41 14.04,54.5 14.04,39.92 v1(14.67,39.29)
  L10_SIG03 w0.102: v1(14.67,39.29) 15.07,39.69 16.11,39.69 16.32,39.91 16.32,40.17 16.61,40.45 20.7,40.45 20.86,40.29 25.93,40.29 26.52,40.89 30.13,40.89 30.99,41.75 31.66,41.75 32,41.41 32.99,41.41 34.45,42.86 34.45,43.13 35.91,44.6 35.91,45.11 36.79,45.99 37.68,45.99 38.04,45.63 48.89,45.63 49.9,46.64 50.74,46.64 v1(51.16,47.05) ; v1(6.4,58.23) 2.04,58.23 0.79,59.48 0.79,90.8 1.53,91.54 1.53,104.84 4.55,107.86 4.55,108.85 6.09,110.39 6.09,111.08 6.66,111.65 6.66,121.43 6.25,121.83 6.25,126.91 7.16,127.82 7.16,130.76 4.6,133.32 4.6,137.78 v1(4.9,138.09)
  BOTTOM w0.14: U92.7 51.43,44.11 51.16,44.39 v1(51.16,47.05) ; U53.C2 5.61,137.69 5.51,137.78 R271.2 5.17,138.36 v1(4.9,138.09)
EXP_SPI0_CLK: length 25.9
  L10_SIG03 w0.102: v1(53.33,135.14) 53.33,132.1 53.52,131.91 53.52,127.6 53.01,127.09 38.28,127.09 J3.23
  BOTTOM w0.14: U55.2 v1(53.33,135.14)
EXP_SPI0_CS0: length 27.9
  L10_SIG03 w0.102: J3.24 37.51,130.74 38.59,131.81 44.38,131.81 48.54,135.98 48.54,136.88 48.96,137.3 58.39,137.3 v1(58.83,137.74)
  BOTTOM w0.14: R290.2 J3.24 ; U55.11 v1(58.83,137.74)
EXP_SPI0_CS1: length 76.9
  TOP w0.132: U18.C16 v1(32.28,107.66)
  TOP w0.14: v1(36.06,132.49) 38.87,132.49 39.71,131.65 J3.26
  L10_SIG03 w0.102: v1(32.28,107.66) 32.05,107.66 31.65,107.26 30.4,107.26 30.08,107.58 29.26,107.58 28.1,106.41 27,106.41 25.33,104.74 16.04,104.74 12,108.77 12,109.86 12.52,110.37 12.52,121.92 12.09,122.34 12.09,123 12.52,123.42 12.52,124.42 14.38,126.28 19.48,126.28 20.86,127.65 20.86,132.12 21.36,132.63 22.76,132.63 23.53,131.86 34.31,131.86 34.94,132.49 v1(36.06,132.49)
  BOTTOM w0.14: R289.2 J3.26
EXP_SPI0_D0: length 39.2
  L10_SIG03 w0.102: J3.19 33.51,126.79 53.09,126.79 53.83,127.53 53.83,135.55 52.67,136.71 v1(48.99,136.71)
  BOTTOM w0.14: U55.5 50.85,137.09 50.47,136.71 v1(48.99,136.71)
EXP_SPI0_D1: length 87.8
  TOP w0.132: U18.E15 v1(33.88,106.86)
  TOP w0.14: v1(32.72,134.17) 32.72,134 33.33,133.38 33.33,129.5 J3.21
  L10_SIG03 w0.102: v1(33.88,106.86) 33.88,106.64 33.48,106.24 33.48,105.9 33.25,105.67 32.96,105.67 32.96,105.66 32.91,105.66 32.68,105.43 32.68,105.39 32.68,105.07 32.48,104.86 32.11,104.86 31.88,104.64 31.88,104.63 31.88,104.3 31.65,104.07 30.75,104.07 30.43,103.74 29.25,103.74 28.93,104.07 27.65,104.07 26.14,102.55 23.98,102.55 22.56,101.13 22.01,101.13 21.73,100.85 19.05,100.85 17.53,102.37 14.21,102.37 13.19,103.39 12.19,103.39 12.04,103.54 11.5,103.54 9.12,105.92 9.12,110.72 8.85,110.99 8.36,111.48 8.36,121.13 10.2,122.97 10.2,124.69 12.82,127.31 12.82,131.6 13.92,132.71 15.08,132.71 15.34,132.96 15.34,133.24 15.61,133.52 16.33,133.52 18.37,135.55 24.06,135.55 25.43,134.17 v1(32.72,134.17)
EXP_SPI2_CLK: length 141.6
  TOP w0.14: J3.12 20.75,131.92 8.64,131.92 7.87,131.15 7.87,127.84 v1(6.99,126.96)
  L05_SIG02 w0.102: v1(25.8,38.43) 24.97,38.43 24.21,37.68 22.87,37.68 22.41,38.14 22.41,39.97 22.99,40.54 22.99,41.22 22.44,41.77 19.94,41.77 18.2,40.03 18.2,39.69 16.75,38.24 13.31,38.24 11.82,39.74 11.82,52.28 10.38,53.72 7.05,53.72 1.08,59.69 1.08,64.16 1.6,64.68 1.6,66.89 1.35,67.15 1.35,74.33 1.78,74.77 1.78,76.32 1.1,76.99 1.1,89.83 1.97,90.7 1.97,96.06 3.65,97.75 3.65,102.05 4.27,102.68 4.27,104.34 3.98,104.63 3.98,105.41 4.33,105.76 4.33,107.38 4.8,107.86 4.8,118.03 9.63,122.85 9.63,125.36 8.03,126.96 v1(6.99,126.96)
  BOTTOM w0.14: v1(25.8,38.43) 25.51,38.73 U95.5
EXP_SPI2_CS0/EHRPWM0_A: length 178.3
  TOP w0.14: v1(5.84,126.35) 5.84,126.86 7.47,128.49 7.47,131.46 8.38,132.37 21.82,132.37 v1(21.95,132.25)
  L05_SIG02 w0.102: v1(5.84,126.35) 6.71,126.35 6.89,126.53 8.03,126.53 9.25,125.31 9.25,122.92 4.5,118.17 4.5,108.12 4,107.62 4,105.98 3.24,105.22 3.24,97.79 1.65,96.2 1.65,92.15 0.77,91.28 0.77,59.57 6.94,53.4 9.3,53.4 9.73,52.97 9.73,51.25 10.85,50.13 10.85,40.25 13.16,37.94 16.92,37.94 18.35,39.37 18.87,39.37 20.94,41.44 22.34,41.44 22.64,41.14 22.64,40.64 22.05,40.05 22.05,37.93 22.63,37.35 24.71,37.35 25.21,37.85 26.38,37.85 v1(26.91,37.32)
  L10_SIG03 w0.102: J3.35 51.06,129.55 23.88,129.55 23.19,130.24 23.19,131.48 22.43,132.25 v1(21.95,132.25)
  BOTTOM w0.14: v1(21.95,132.25) 22.05,132.35 R287.2 ; U95.2 25.92,36.78 26.47,37.32 v1(26.91,37.32)
EXP_SPI2_CS1: length 49.3
  TOP w0.132: U18.A19 30.89,109.86 30.08,109.86 v1(29.73,109.51)
  TOP w0.14: v1(15.06,124.09) 15.06,124.58 16.53,126.04 17.57,126.04 18.49,126.96 20.69,126.96 J3.11
  L10_SIG03 w0.102: v1(15.06,124.09) 15.06,124.04 14.59,123.57 14.59,120.79 14.28,120.47 14.28,110.48 14.7,110.06 14.7,109.2 16.23,107.67 17.1,107.67 19.09,105.68 21.48,105.68 23.48,107.68 25.13,107.68 26,108.55 26.9,108.55 27.86,109.51 v1(29.73,109.51)
  BOTTOM w0.14: J3.11 20.68,129.45 20.68,131.79 21.16,132.28 R288.2
EXP_SPI2_CS2: length 81.5
  TOP w0.132: U18.B18 v1(31.48,109.26)
  TOP w0.14: v1(49.41,126.12) 50.01,126.73 50.51,126.73 51.11,127.32 51.11,129.44 J3.36
  L10_SIG03 w0.102: v1(49.41,126.12) 49.1,126.43 33.17,126.43 32.54,127.07 24.97,127.07 23.7,125.79 19.69,125.79 19.43,126.05 16.23,126.05 14.36,124.18 14.36,120.96 13.9,120.5 13.9,108.9 17.34,105.45 22.33,105.45 23.49,106.62 25.49,106.62 26.16,107.29 26.16,107.64 26.84,108.32 27.31,108.32 27.85,108.86 31.08,108.86 v1(31.48,109.26)
  BOTTOM w0.14: R291.2 J3.36
EXP_SPI2_D0: length 123.4
  L05_SIG02 w0.102: J3.40 56.24,129.5 56.24,127.32 56.77,126.79 58.46,126.79 61.61,123.63 61.61,116.09 63.07,114.64 63.07,106.08 63.8,105.36 63.8,102.4 63.48,102.08 63.48,100.65 63.65,100.47 63.65,90.06 64.27,89.44 64.27,77.13 62.13,74.98 62.13,67.78 61.65,67.3 61.65,62.95 62.54,62.07 v1(62.54,58.79)
  L10_SIG03 w0.102: v1(62.54,58.79) 62.59,58.74 62.59,54.06 57.13,48.6 52.63,48.6 51.78,47.75 51.78,46.92 51.22,46.36 50.06,46.36 49.09,45.39 37.62,45.39 37.1,44.87 36.53,44.87 34.71,43.05 34.71,42.66 33.19,41.13 v1(31.27,41.13)
  BOTTOM w0.14: v1(31.27,41.13) 31.27,39.64 31.01,39.38 U95.11
EXP_SPI2_D1/ECAP2_IN_APWM_OUT: length 134.1
  L05_SIG02 w0.102: J3.38 56.14,131.94 57.89,131.94 58.6,131.23 58.6,127.1 61.89,123.81 61.89,116.18 63.3,114.77 63.3,107.64 64.57,106.37 64.57,105.1 64.03,104.56 64.03,102.3 63.72,101.99 63.72,100.93 63.92,100.73 63.92,92.31 64.56,91.67 64.56,77.09 62.38,74.91 62.38,67.7 61.9,67.22 61.9,63.26 62.98,62.18 62.98,58.55 62.35,57.91 62.35,53.06 v1(62.16,52.87)
  L10_SIG03 w0.102: v1(28.77,37.37) 28.77,37.14 28.96,36.95 37.04,36.95 37.55,37.45 37.55,38.12 38.97,39.55 38.97,39.99 39.28,40.3 39.66,40.3 40.73,41.36 43.37,41.36 43.85,40.88 50.22,40.88 52.15,42.81 56.42,42.81 57.19,43.59 58.84,43.59 59.38,44.12 59.38,45.14 60.51,46.27 60.51,51.22 v1(62.16,52.87)
  BOTTOM w0.14: U95.14 29.07,37.43 29.02,37.37 v1(28.77,37.37)
EXP_UART5_RXD: length 47.4
  TOP w0.132: U18.B17 v1(31.48,108.46)
  TOP w0.14: v1(14.57,125.02) 15,125.02 16.37,126.39 17.12,126.39 18.15,127.42 18.15,129.5 J3.10
  L10_SIG03 w0.102: v1(31.48,108.46) 28.12,108.46 24.88,105.22 16.26,105.22 13.12,108.37 13.12,109.59 12.98,109.73 12.98,121.84 13.92,122.78 13.92,124.38 v1(14.57,125.02)
EXP_UART5_TXD: length 49
  TOP w0.132: U18.C18 v1(32.28,109.26)
  TOP w0.14: J3.8 15.54,129.43 15.54,126.47 v1(14.94,125.87)
  L10_SIG03 w0.102: v1(14.94,125.87) 14.4,125.87 12.75,124.21 12.75,123.33 12.4,122.98 12.4,122.44 12.75,122.09 12.75,109.62 12.89,109.48 12.89,108.27 16.17,105 25.08,105 26.72,106.64 27.79,106.64 29.21,108.07 32.45,108.07 32.68,108.3 U18.C18 v1(32.28,109.26)
EXT_CLKOUT0: length 55.3
  TOP w0.14: R28.1 51,137.56 51.35,137.92 51.35,139.16 50.53,139.98 50.29,139.98 49.57,140.71 48.77,140.71 47.85,141.63 41.3,141.63 39.9,140.23 37.23,140.23 v1(31.65,134.65) ; R60.1 v1(25.05,109.94)
  BOTTOM w0.14: v1(25.05,109.94) 25.75,109.94 27.04,111.23 27.04,119.1 28.84,120.91 28.84,126.87 28.29,127.43 28.29,132.06 30.88,134.65 v1(31.65,134.65)
EXT_CLKOUT0_R: length 13
  TOP w0.132: U18.B16 v1(31.48,107.66)
  TOP w0.14: R58.2 23.62,110.57 23.84,110.35 R60.2 v1(23.84,109.27)
  BOTTOM w0.14: v1(23.84,109.27) 23.84,108.8 25.96,106.69 28.15,106.69 29.66,108.19 30.95,108.19 v1(31.48,107.66)
FT4232_DO: length 2.7
  BOTTOM w0.14: U113.4 13.26,22.91 13.46,23.11 13.46,23.12 R513.2 R508.1
FT4232_EECLK: length 11.2
  TOP w0.14: U48.62 19.82,21.09 19.25,21.66 13.27,21.66 v1(11.96,22.97)
  BOTTOM w0.14: R509.1 v1(11.96,22.97) U113.2
FT4232_EECS: length 12.9
  TOP w0.14: v1(10.66,23.53) 12.82,21.36 19.04,21.36 19.32,21.09 U48.63
  BOTTOM w0.14: v1(10.66,23.53) R510.1 11.2,22.98 11.31,22.87 U113.1
FT4232_EEDATA: length 11.9
  TOP w0.14: v1(12.9,24.07) 15.02,21.95 19.47,21.95 20.32,21.1 U48.61
  BOTTOM w0.14: U113.3 12.61,22.83 12.9,23.12 R513.1 v1(12.9,24.07)
FT4232_MCU_UART0_CTS_3V3: length 9.4
  TOP w0.14: v1(28.89,18.84) 28.89,20.3 26.93,22.26 25.14,22.26 24.32,21.45 U48.53
  BOTTOM w0.14: v1(28.89,18.84) 29.21,19.16 U110.12
FT4232_MCU_UART0_RTS_3V3: length 7.1
  TOP w0.14: U48.54 23.82,19.36 24.74,18.44 26.72,18.44 27.01,18.72 27.01,19.39 v1(27.6,19.99)
  BOTTOM w0.14: U110.14 27.85,20.23 v1(27.6,19.99)
FT4232_MCU_UART0_RX_3V3: length 3.3
  TOP w0.14: v1(27.99,19.16) 27.55,19.16 27.41,19.02 27.41,18.48 27.67,18.21 U48.48
  BOTTOM w0.14: v1(27.99,19.16) 27.99,19.66 28.17,19.83 U110.13
FT4232_MCU_UART0_TX_3V3: length 5.7
  TOP w0.14: U48.52 24.82,21.51 25.11,21.81 26.7,21.81 v1(27.6,20.9)
  BOTTOM w0.14: U110.15 27.87,20.63 v1(27.6,20.9)
FT4232_REF: length 1.9
  TOP w0.14: U48.6 v1(18.01,15.71)
  BOTTOM w0.14: R553.2 17.78,15.94 v1(18.01,15.71)
FT4232_RESET: length 3.2
  TOP w0.14: U48.14 15.98,11.71 15.71,11.44 15.56,11.44 C160.2 R235.1
FT4232_SOC_UART0_RX_3V3: length 9.3
  TOP w0.14: U48.16 v1(15.69,10.71)
  BOTTOM w0.14: v1(15.69,10.71) 16.69,9.71 21.32,9.71 21.58,9.97 21.58,10.55 21.11,11.02 U119.13
FT4232_SOC_UART0_TX_3V3: length 3.6
  TOP w0.14: U48.17 18.82,9.95 19.41,10.54 v1(19.91,10.54)
  BOTTOM w0.14: U119.15 20.31,10.94 v1(19.91,10.54)
FT4232_SOC_UART1_CTS_3V3: length 7
  TOP w0.14: U48.28 24.32,7.85 v1(24.06,7.59)
  BOTTOM w0.14: v1(24.06,7.59) 24.06,7.08 24.4,6.74 28.27,6.74 28.52,6.99 U123.12
FT4232_SOC_UART1_RTS_3V3: length 5.3
  TOP w0.14: U48.29 24.82,9.79 v1(25.06,10.04)
  BOTTOM w0.14: v1(25.06,10.04) 25.06,9.55 26.54,8.06 U123.14
FT4232_SOC_UART1_RX_3V3: length 6.6
  TOP w0.14: v1(23.08,7.59) 23.32,7.83 U48.26
  BOTTOM w0.14: U123.13 25.98,7.66 25.41,8.24 23.73,8.24 v1(23.08,7.59)
FT4232_SOC_UART1_TX_3V3: length 6.6
  TOP w0.14: v1(24.08,10.04) 23.82,9.78 U48.27
  BOTTOM w0.14: v1(24.08,10.04) 24.61,10.56 25.36,10.56 26.48,9.45 26.48,9 27.02,8.46 U123.15
FT4232_USB_DM: length 14.8
  TOP w0.102: 8.07,16.79 7.97,16.69 7.58,16.69 7.08,17.18 6.72,17.18 6.5,17.4 J17.2 ; 8.07,16.79 8.17,16.69 9.64,16.69 9.93,16.39 9.93,14.43 10.34,14.02 13.43,14.02 14.48,15.07 15.78,15.07 15.92,15.21 U48.7 ; 8.07,16.79 U46.5
FT4232_USB_DP: length 14.8
  TOP w0.102: 9.07,16.37 9.17,16.48 9.55,16.48 9.72,16.3 9.72,14.34 10.25,13.81 13.52,13.81 14.57,14.86 15.78,14.86 15.92,14.71 U48.8 ; 9.07,16.37 U46.3 ; 9.07,16.37 8.96,16.48 7.49,16.48 6.99,16.97 6.72,16.97 6.5,16.75 J17.3
FT4232_USB_VBUS: length 3
  TOP w0.254: U46.1 v1(8.07,15.17)
  BOTTOM w0.254: U121.4 8.67,9.44 8.24,9.87 8.24,10.73
  vias: v1(7.23,18.42) v1(8.15,18.42) v1(9.06,18.42)
FT4232_WKUP_UART0_CTS_3V3: length 2.3
  TOP w0.14: U48.40 27.38,14.21 27.12,13.95 v1(26.88,13.95)
  BOTTOM w0.14: U118.12 26.45,14.37 v1(26.88,13.95)
FT4232_WKUP_UART0_RTS_3V3: length 4.1
  TOP w0.14: U48.41 27.35,14.71 27.11,14.46 25.74,14.46 v1(25.46,14.74)
  BOTTOM w0.14: U118.14 25.64,14.57 v1(25.46,14.74)
FT4232_WKUP_UART0_RX_3V3: length 2.9
  TOP w0.14: U48.38 27.24,13.21 27.07,13.04 v1(26.28,13.04)
  BOTTOM w0.14: U118.13 26.04,13.28 v1(26.28,13.04)
FT4232_WKUP_UART0_TX_3V3: length 4
  TOP w0.14: v1(25.24,13.04) 25.68,13.47 27.06,13.47 27.3,13.71 U48.39
  BOTTOM w0.14: U118.15 v1(25.24,13.04)
FT_PWREN#: length 1.8
  TOP w0.14: U48.60 R228.1
GPIO1_23_INTN: length 151.4
  TOP w0.132: U18.C15 v1(32.28,106.86)
  L03_SIG01 w0.102: v1(49.39,39.23) 48.4,40.22 46.2,40.22 43.03,37.05 43.03,35.72 39.93,32.63 39.93,28.31 37.24,25.62 v1(37.24,24.46)
  L05_SIG02 w0.102: v1(32.28,106.86) 31.88,107.26 31.3,107.26 31.08,107.48 31.08,107.87 30.85,108.1 28.82,108.1 28.4,108.51 24.67,108.51 24.32,108.86 24.32,109.39 23.24,110.48 17.7,110.48 16.89,109.67 16.89,108.68 15.55,107.33 15.55,105.96 11.53,101.94 11.53,100.51 11.36,100.35 11.36,98.86 11.79,98.43 11.79,96.36 11.28,95.84 11.28,92.8 10.81,92.33 10.81,81.4 10.09,80.67 10.09,77.76 8.14,75.82 8.14,67.51 8.37,67.29 8.37,66.42 7.68,65.73 7.68,61.12 9.81,58.99 11.41,58.99 15.65,54.75 15.65,54.01 16,53.66 16.74,53.66 18.16,52.24 21,52.24 22.11,51.12 23.86,51.12 28.62,46.35 28.62,41.71 29.78,40.55 29.78,36.12 28.3,34.64 28.3,31.22 35.06,24.46 v1(37.24,24.46)
  BOTTOM w0.14: R448.1 v1(49.39,39.23) ; R512.2 37.55,24.14 v1(37.24,24.46)
GPIO2_BUF_EN: length 2.3
  BOTTOM w0.14: U102.5 60.91,27.29 60.65,27.03 60.48,27.03 R491.2 60.72,26.32 R494.1
GPIO_AUD_RSTN: length 12.4
  L10_SIG03 w0.102: v1(52.7,46.17) 52.7,46.19 52.85,46.34 55.13,46.34 55.63,46.84 v1(59.78,46.84)
  BOTTOM w0.14: v1(52.7,46.17) U92.9 ; v1(59.78,46.84) 60.21,46.41 R427.1 R432.2 U93.1
GPIO_CPSW1_RST: length 18.3
  TOP w0.14: v1(60.69,43.66) 60.92,43.44 R174.1 R175.1 62.68,43.44 62.86,43.25 U41.1
  L10_SIG03 w0.102: v1(60.69,43.66) 60.69,41.6 59.56,40.47 57.85,40.47 57.68,40.65 57.04,40.65 56.48,40.09 53.97,40.09 53.41,39.53 51.38,39.53 50.93,39.98 v1(50.93,40.58)
  BOTTOM w0.14: v1(50.93,40.58) 50.93,41.19 51.35,41.61 U92.2
GPIO_CPSW2_RST: length 144
  TOP w0.14: U42.1 63.2,39.77 63.01,39.96 R181.1 R180.1 61.46,39.96 v1(60.98,40.44) ; v1(53.66,149.08) 53.65,149.06 U2.19
  L05_SIG02 w0.102: v1(53.66,149.08) 53.94,149.08 54.96,148.06 57.35,148.06 59.17,149.89 62.6,149.89 66.49,146 66.49,145.52 70.66,141.36 72.76,141.36 75.79,138.33 75.79,133.76 75.56,133.53 75.56,131.37 74.85,130.66 74.85,119.56 73.53,118.24 73.53,110.19 72.76,109.43 72.76,101.5 73.3,100.97 73.3,89.26 70.81,86.77 70.81,80.09 71.19,79.71 71.19,64.65 72.03,63.81 72.03,59.47 74.67,56.82 74.67,52.56 73.37,51.26 69.08,51.26 67.13,49.31 67.13,46.21 63.09,42.17 62.63,42.17 62.27,42.52 61.44,42.52 60.98,42.06 v1(60.98,40.44)
GPIO_EMMC_RSTN: length 28.3
  TOP w0.14: U32.1 R136.1 v1(61.4,67.86)
  L03_SIG01 w0.102: v1(61.4,67.86) 60.21,67.86 53.95,61.6 53.95,47.58 v1(53.2,46.83)
  BOTTOM w0.14: v1(53.2,46.83) U92.10
GPIO_HDMI_RSTN: length 16.3
  TOP w0.14: v1(54.7,46.89) 53.46,45.65 52.39,45.65 51.71,46.33 47.77,46.33 46.48,45.05 46.48,44.35 v1(45.63,43.5)
  BOTTOM w0.14: U94.1 R442.2 R438.1 45,43.21 45.29,43.5 v1(45.63,43.5) ; v1(54.7,46.89) U92.13
GPIO_MCU_SOC: length 54.6
  L03_SIG01 w0.102: v1(30.15,60.87) 30.91,60.11 33.91,60.11 34.33,60.53 36.73,60.53 37.14,60.12 37.14,45.86 37.47,45.53 37.47,41.7 36.53,40.76 36.53,38.27 35.33,37.07 35.33,35.95 33.99,34.61 33.99,31.38 33.38,30.77 33.38,25.36 v1(32.77,24.75)
  BOTTOM w0.14: U108.5 38.49,23.15 R512.1 38.11,24.59 37.7,25.01 37.04,25.01 36.5,24.47 33.05,24.47 v1(32.77,24.75) ; v1(30.15,60.87) 29.87,60.59 R572.1
GPIO_MCU_SOC_INTN: length 49
  TOP w0.14: U18.B9 v1(31.48,101.27)
  L05_SIG02 w0.102: v1(27.41,66.31) 26.94,66.78 26.94,70.23 24,73.18 24,91.78 24.11,91.89 24.11,96.59 24.8,97.28 24.8,97.96 26.93,100.09 28.67,100.09 29.6,101.02 30.14,101.02 30.39,101.27 v1(31.48,101.27)
  BOTTOM w0.14: R573.1 R572.2 28.4,61.45 28.22,61.63 28.22,65.49 v1(27.41,66.31)
GPIO_OSPI_RSTN: length 52
  TOP w0.132: U18.G19 v1(35.48,110.06)
  TOP w0.14: U11.1 R41.1 39.2,124.93 39.01,124.75 37.67,124.75 v1(37.14,125.28)
  L10_SIG03 w0.102: v1(35.48,110.06) 35.45,110.06 35.08,110.43 35.08,112.52 35.08,112.52 35.08,112.63 34.85,112.86 34.76,112.86 31.77,115.85 28.34,115.85 27.13,114.64 27.13,113.22 25.68,111.77 21.39,111.77 20.81,112.35 20.81,113.42 21.05,113.65 21.05,119.48 21.81,120.24 21.81,121.24 23.46,122.89 23.46,122.89 23.68,123.11 23.68,123.12 24.29,123.73 26.01,123.73 27.29,125.01 36.88,125.01 v1(37.14,125.28)
HB_LM5141: length 6.1
  BOTTOM w0.254: U89.11 35.03,48.25 33.36,49.92 C412.2 33.36,52.09 33.61,52.34 D9.1
HDMI_AUDD1: length 7.4
  TOP w0.14: TP10.1 v1(27.54,124.14) ; v1(23.03,121.01) 23.19,121.18 U13.40
  L10_SIG03 w0.102: v1(23.03,121.01) 23.03,121.02 23.03,121.06 25.11,123.14 26.53,123.14 v1(27.54,124.14)
HDMI_AUDD2: length 6
  TOP w0.132: v1(23.86,121.01) 23.69,121.18 U13.39
  TOP w0.14: TP12.1 v1(27.51,122.82)
  L10_SIG03 w0.102: v1(27.51,122.82) 25.67,122.82 v1(23.86,121.01)
HDMI_AUDD3: length 2.2
  TOP w0.132: U13.37 24.69,122.55 24.87,122.72 25.36,122.72 TP14.1
HDMI_CEC: length 14
  TOP w0.14: v1(6.68,110.71) 7.41,110.71 7.67,110.45 12.47,110.45 13.1,111.08 13.1,111.41 14.96,113.27 U13.71
  BOTTOM w0.14: U58.1 v1(6.68,110.71)
HDMI_CEC_D: length 2
  TOP w0.14: TP11.1 18.19,123.43 U13.50
HDMI_CLK+: length 11.7
  TOP w0.089: U13.59 14.88,119.27 14.74,119.41 13.01,119.41 11.37,117.77 11.37,116.4 11.15,116.17 10.86,116.17 v1(10.6,115.91) 10.36,116.14 9.86,116.14 9.73,116.01 9.73,115.86 9.61,115.74 J5.10
  BOTTOM w0.089: U58.16 9.6,115.91 9.83,116.14 10.36,116.14 v1(10.6,115.91)
HDMI_CLK-: length 11.7
  TOP w0.089: J5.12 9.6,116.74 9.73,116.6 9.73,116.46 9.82,116.37 10.3,116.37 v1(10.6,116.67) 10.86,116.4 11.06,116.4 11.15,116.49 11.15,117.87 12.91,119.64 14.74,119.64 14.88,119.77 U13.58
  BOTTOM w0.089: v1(10.6,116.67) 10.3,116.37 9.83,116.37 9.64,116.56 U58.15
HDMI_CONN_I2CSCL: length 7.8
  TOP w0.14: J5.15 7.41,118.24 6.23,117.06 v1(6.23,115.26)
  BOTTOM w0.14: U58.8 v1(6.23,115.26)
HDMI_CONN_I2CSDA: length 6.7
  TOP w0.14: v1(6.25,117.9) 7.09,118.74 J5.16
  BOTTOM w0.14: v1(6.25,117.9) 4.27,115.91 U58.9
HDMI_CONNCEC: length 8.3
  TOP w0.14: J5.13 7.18,117.24 6.63,116.69 6.63,114.54 v1(6.25,114.16)
  BOTTOM w0.14: v1(6.25,114.16) 5.8,114.61 U58.7
HDMI_EXTSWING: length 1.6
  TOP w0.14: U13.56 16.17,120.77 16.17,120.77 16.19,120.77 v1(16.23,120.73)
  BOTTOM w0.14: v1(16.23,120.73) 15.94,121.02 R308.1
HDMI_HPD: length 22.3
  TOP w0.14: v1(13.51,124.27) 14.13,123.65 15.66,123.65 15.83,123.48 R47.1 16.19,122.8 U13.54
  L05_SIG02 w0.102: v1(6.23,113.32) 6.78,113.88 7.29,113.88 7.6,114.19 7.6,116.88 8.8,118.09 8.8,119.84 12.09,123.13 12.36,123.13 v1(13.51,124.27)
  BOTTOM w0.14: v1(6.23,113.32) 5.26,113.32 4.6,112.66 U58.4
HDMI_I2C_SCL: length 27.6
  TOP w0.14: U13.49 v1(18.69,122.87)
  L05_SIG02 w0.102: v1(18.69,122.87) 18.69,121.96 19.18,121.48 19.18,120.94 19.59,120.54 19.59,120.21 19.31,119.93 17.45,119.93 17.07,120.31 16.06,120.31 15.51,119.76 11.22,119.76 8.13,116.68 8.13,112.76 7.65,112.28 v1(7.06,112.28)
  BOTTOM w0.14: v1(7.06,112.28) 6.14,111.36 U58.2 ; v1(18.69,122.87) 18.5,123.06 R298.2
HDMI_I2C_SDA: length 25.1
  TOP w0.14: U13.48 19.19,120.65 v1(18.95,120.41)
  L05_SIG02 w0.102: v1(6.23,112.43) 6.58,112.79 7.47,112.79 7.88,113.2 7.88,116.75 11.58,120.46 13.85,120.46 14.94,121.55 17.33,121.55 18.47,120.41 v1(18.95,120.41)
  BOTTOM w0.14: U58.3 2.96,112 5.79,112 v1(6.23,112.43) ; v1(18.95,120.41) 19.15,120.21 R310.2
HDMI_INTN: length 158.9
  TOP w0.14: v1(15.9,124.42) 15.9,123.91 16.5,123.32 16.98,123.32 17.22,123.55 R45.2 17.51,123.27 17.19,122.95 U13.52
  L05_SIG02 w0.102: v1(16.27,39.27) 15.84,38.84 14.53,38.84 13.67,39.71 13.67,53.02 12.42,54.27 11.03,54.27 10.39,54.9 8.37,54.9 4.02,59.26 4.02,66.03 4.32,66.33 4.32,69.73 5.4,70.81 5.4,76.15 5.08,76.47 5.08,77.07 7.21,79.21 7.21,81.52 6.89,81.85 6.89,84.48 5.54,85.82 5.54,89.61 5.29,89.87 5.29,92.07 4.89,92.46 4.89,99.4 5.39,99.89 5.39,104.56 5.18,104.76 5.18,106.77 5.57,107.15 5.57,115.63 8.28,118.35 8.28,120.03 10.59,122.34 10.59,123.59 11.89,124.88 14.07,124.88 14.32,124.64 15.69,124.64 v1(15.9,124.42)
  L10_SIG03 w0.102: v1(16.27,39.27) 16.9,38.65 19.7,38.65 20.55,37.8 29.25,37.8 29.66,37.38 32.03,37.38 32.51,37.86 36.45,37.86 38.06,39.47 38.06,39.95 38.73,40.62 39.52,40.62 40.59,41.68 40.59,41.97 40.97,42.36 44.2,42.36 45.44,41.11 50.12,41.11 52.56,43.54 52.56,44.49 52.86,44.79 58.03,44.79 v1(58.72,44.11)
  BOTTOM w0.14: v1(58.72,44.11) 58.22,44.61 U92.17
HDMI_MSTRCLK: length 3
  TOP w0.132: R43.2 25.45,123.76 25.22,123.53 24.89,123.53 24.19,122.83 U13.38
HDMI_PCLK: length 47.2
  TOP w0.14: U13.22 24.61,114.27 24.44,114.1 v1(20.34,114.1)
  L03_SIG01 w0.102: v1(20.34,114.1) 20.96,114.72 20.96,119.1 22.6,120.74 22.6,121.4 24.95,123.75 25.26,123.75 26.31,124.8 36.26,124.8 36.63,124.44 40.75,124.44 41.31,123.87 42.24,123.87 47.48,118.63 v1(47.48,114.24)
  BOTTOM w0.14: R318.2 v1(47.48,114.24)
HDMI_RSTN: length 145.8
  TOP w0.132: U13.51 v1(17.69,122.82)
  L05_SIG02 w0.102: v1(17.69,122.82) 17.29,123.23 15.12,123.23 13.69,124.66 12.02,124.66 10.87,123.51 10.87,122.26 8.54,119.93 8.54,118.25 5.79,115.51 5.79,106.97 5.41,106.59 5.41,104.99 5.66,104.73 5.66,99.29 5.23,98.86 5.23,92.68 6.11,91.79 6.11,90.76 5.88,90.52 5.88,86.2 6.1,85.97 6.11,85.97 7.82,84.27 7.82,81.59 7.44,81.22 7.44,79.07 5.39,77.02 5.39,76.56 5.74,76.21 5.74,70.77 4.54,69.57 4.54,66.16 4.24,65.86 4.24,59.39 7.9,55.74 11.74,55.74 13.9,53.58 13.9,40.86 15.46,39.29 v1(15.46,39.27)
  L10_SIG03 w0.102: v1(45.98,39.28) 44.96,40.3 40.97,40.3 39.91,39.24 39.91,37.08 38.68,35.85 31.52,35.85 30.92,36.45 28.31,36.45 27.84,36.93 25.47,36.93 24.87,37.52 20.48,37.52 19.79,38.21 16.53,38.21 v1(15.46,39.27)
  BOTTOM w0.14: v1(45.98,39.28) 45.98,38.32 45.75,38.09 45.75,37.17 46,36.92 46.42,36.92 46.53,37.02 R463.2 U94.4
HDMI_TX0+: length 12.4
  TOP w0.089: U13.62 14.88,117.77 14.74,117.91 13.78,117.91 12.23,116.36 12.23,115.06 11.79,114.62 11.5,114.62 v1(11.23,114.36) 10.98,114.61 9.83,114.61 9.73,114.51 9.73,114.34 9.63,114.24 J5.7
  BOTTOM w0.089: v1(11.23,114.36) 10.91,114.67 9.8,114.67 9.69,114.78 9.37,114.78 9.21,114.61 U58.18
HDMI_TX0-: length 12.4
  TOP w0.089: U13.61 14.88,118.27 14.74,118.14 13.69,118.14 12.01,116.46 12.01,115.16 11.7,114.85 11.5,114.85 v1(11.23,115.12) 10.95,114.84 9.83,114.84 9.73,114.94 9.73,115.1 9.6,115.24 J5.9
  BOTTOM w0.089: U58.17 9.22,115.26 9.38,115.1 9.69,115.1 9.89,114.9 11.02,114.9 v1(11.23,115.12)
HDMI_TX1+: length 11.9
  TOP w0.089: U13.65 14.88,116.27 14.74,116.41 13.77,116.41 13.08,115.72 13.08,114.38 11.82,113.12 10.94,113.12 v1(10.67,112.86) 10.42,113.11 9.83,113.11 9.73,113.01 9.73,112.84 9.63,112.74 J5.4
  BOTTOM w0.089: v1(10.67,112.86) 10.67,112.92 10.45,113.14 10.29,113.14 10.03,112.87 9.75,112.87 9.54,112.66 U58.21
HDMI_TX1-: length 11.9
  TOP w0.089: U13.64 14.88,116.77 14.74,116.64 13.67,116.64 12.85,115.81 12.85,114.47 11.73,113.35 10.94,113.35 v1(10.67,113.62) 10.39,113.34 9.83,113.34 9.73,113.44 9.73,113.6 9.6,113.74 J5.6
  BOTTOM w0.089: U58.20 9.56,113.31 9.77,113.1 9.93,113.1 10.2,113.36 10.46,113.36 10.67,113.58 v1(10.67,113.62)
HDMI_TX2+: length 12.2
  TOP w0.089: J5.1 9.63,111.24 9.73,111.34 9.73,111.51 9.83,111.61 10.8,111.61 v1(11.05,111.36) 11.32,111.62 12.27,111.62 13.91,113.26 13.91,114.57 14.24,114.91 14.74,114.91 14.88,114.77 U13.68
  BOTTOM w0.089: v1(11.05,111.36) 10.8,111.61 9.88,111.61 9.64,111.36 U58.23
HDMI_TX2-: length 12.2
  TOP w0.089: U13.67 14.88,115.27 14.74,115.14 14.15,115.14 13.68,114.67 13.68,113.35 12.18,111.85 11.32,111.85 v1(11.05,112.12) 10.77,111.84 9.83,111.84 9.73,111.94 9.73,112.1 9.6,112.24 J5.3
  BOTTOM w0.089: v1(11.05,112.12) 10.77,111.83 9.81,111.83 9.64,112.01 U58.22
HDMICONN_HPD: length 7.4
  TOP w0.14: J5.19 7.08,120.24 6.26,119.42 v1(6.26,118.82)
  BOTTOM w0.14: v1(6.26,118.82) 4,116.56 U58.10
HFOSC0_CLKOUT_32K: length 48.5
  TOP w0.132: U18.B10 v1(31.48,102.07)
  BOTTOM w0.14: v1(31.48,102.07) 31.02,101.61 30.35,101.61 30.07,101.88 30.07,102.65 29.79,102.93 29.51,102.93 28.87,103.56 27.22,103.56 26.13,102.47 25.04,102.47 24.5,103 24.5,103.89 22.86,105.53 22.86,109.03 24.69,110.86 24.69,112.42 25.26,112.99 25.26,121.41 25.75,121.9 25.75,132.53 24.15,134.13 20.75,134.13 20.03,134.85 R282.1
HO_LM5141: length 2.3
  BOTTOM w0.14: U89.13 36.65,46.86 37.05,47.26 37.05,47.74 37.22,47.91 R420.1
HOL_LM5141: length 11.8
  TOP w0.14: v1(42.05,52.85) 41.57,52.85 41.25,52.53 U39.4
  L03_SIG01 w0.102: v1(38.51,47.38) 38.76,47.64 38.76,49.56 v1(42.05,52.85)
  BOTTOM w0.14: v1(38.51,47.38) 38.51,47.07 38.37,46.93 R420.2 37.36,46.93 36.78,46.36 U89.14
HPLOUT: length 6.8
  TOP w0.254: J14.2 72.59,38.48 73.24,39.13 v1(75.86,39.13)
  BOTTOM w0.254: C430.2 v1(75.86,39.13)
HPLOUT_C: length 2.5
  BOTTOM w0.254: U88.18 74.66,42.23 C430.1
HPROUT: length 10.5
  TOP w0.254: v1(72.92,37.56) 75.4,35.09 75.4,34.15 77.4,32.14 77.4,31.85 J14.3
  BOTTOM w0.254: C431.2 72.27,38.22 v1(72.92,37.56)
HPROUT_C: length 2.5
  BOTTOM w0.254: U88.23 72.16,42.23 C431.1
INA_ALERT: length 83.8
  TOP w0.14: v1(3.69,104.33) 3.53,104.48 R68.1 4.06,105.14 4.35,105.43 R67.2 ; R109.2 v1(2.21,88.42) ; TP38.1 v1(4.96,74.04)
  L10_SIG03 w0.102: v1(22.36,67.33) 22.37,67.33 22.62,67.58 27.07,67.58 27.43,67.22 31.76,67.22 v1(32.46,66.51) 33.05,66.51 35.37,68.84 v1(37.6,68.84) 37.95,68.48 40.83,68.48 41.16,68.81 42.41,68.81 v1(42.92,68.3) ; v1(3.69,104.33) 3.69,103.87 2.83,103.02 2.83,93.96 2.36,93.49 2.36,90.78 1.81,90.23 1.81,88.82 v1(2.21,88.42) 2.21,85.57 1.43,84.78 1.43,76.65 4.03,74.04 v1(4.96,74.04)
  BOTTOM w0.14: R385.2 v1(37.6,68.84) ; v1(4.96,74.04) 4.96,72.35 R377.2 5.62,72.05 6.72,70.96 7.5,70.96 10.44,68.01 13.19,68.01 13.52,67.68 14.81,67.68 15.34,68.21 16.33,68.21 16.71,67.83 18.69,67.83 19.21,68.35 21.03,68.35 21.68,67.7 22,67.7 22.36,67.35 v1(22.36,67.33) ; R386.2 v1(42.92,68.3) ; v1(32.46,66.51) 32.59,66.39 R387.2
IO_EXP1_INTN: length 1.8
  TOP w0.14: U2.32 48.51,152.55 47.66,153.4 R3.1
IO_EXP_ADDR: length 1.1
  BOTTOM w0.14: U100.26 46.63,27.24 R489.1
IO_EXP_INTN: length 3
  BOTTOM w0.14: U92.32 52.7,39.73 52.53,39.56 52.15,39.56 R451.1 R448.2
IO_EXP_TEST_LED: length 10.3
  TOP w0.14: R163.1 R164.2 v1(55.9,48.09)
  L03_SIG01 w0.102: v1(57.81,41.03) 56.96,41.89 56.96,47.03 v1(55.9,48.09)
  BOTTOM w0.14: U92.24 57.03,41.03 v1(57.81,41.03)
JTAG_CTI_RTCK: length 3.1
  TOP w0.14: J19.9 v1(38.62,15.39)
  BOTTOM w0.14: v1(38.62,15.39) 38.87,15.15 R562.1
JTAG_CTI_TCK: length 25.2
  TOP w0.132: J19.11 37.35,15.16 38.08,15.89 40.08,15.89 v1(40.94,16.75)
  L05_SIG02 w0.102: v1(44.34,22.24) 44.05,22.52 38.46,22.52 37.09,21.15 37.09,19.44 37.82,18.71 38.66,18.71 40.62,16.75 v1(40.94,16.75)
  BOTTOM w0.14: v1(40.94,16.75) 40.21,16.02 U117.1 ; U107.1 R504.1 44.46,23.49 45.09,22.85 R519.1 44.64,22.54 v1(44.34,22.24)
JTAG_DIR: length 3.1
  BOTTOM w0.14: 50.52,20.68 50.01,20.68 50.01,20.67 49.86,20.67 49.46,20.27 U114.4 ; 50.52,20.68 R521.2 ; 50.52,20.68 50.52,20.16 50.24,19.89 U114.5
JTAG_EMU0: length 32.8
  TOP w0.14: J19.13 v1(36.08,11.49)
  L10_SIG03 w0.102: v1(36.08,11.49) 37.88,9.69 43.88,9.69 44.4,10.21 44.4,13.91 47.24,16.74 47.84,16.74 48.4,17.3 48.4,18.45 48.9,18.95 48.9,23.06 49.32,23.48 50.47,23.48 v1(51.21,24.22)
  BOTTOM w0.14: v1(51.21,24.22) 51.21,24.72 50.98,24.94 50.57,24.94 50.24,25.28 49.64,25.28 49.34,24.97 U106.7 ; R564.2 v1(36.08,11.49)
JTAG_EMU1: length 29.5
  TOP w0.14: J19.14 v1(36.08,10.22)
  L05_SIG02 w0.102: v1(36.08,10.22) 36.2,10.22 36.74,10.76 36.74,16.04 36.4,16.38 36.4,21.25 38.46,23.31 40.95,23.31 43.06,25.41 47.06,25.41 47.34,25.13 48.31,25.13 v1(48.72,25.54)
  BOTTOM w0.14: v1(48.72,25.54) 48.72,25.52 48.99,25.25 U106.6 ; R566.2 v1(36.08,10.22)
JTAG_EMU_RSTN: length 4.1
  TOP w0.14: J19.15 v1(34.81,15.38)
  BOTTOM w0.14: v1(34.81,15.38) 34.68,15.5 R552.2 34.23,15.99 33.76,16.46 U116.6
JTAG_TCK: length 9.1
  L10_SIG03 w0.102: v1(46.68,18.92) 46.73,18.92 47.89,20.08 47.89,21.97 46.97,22.9 v1(46.97,24.84)
  BOTTOM w0.14: R499.1 v1(46.97,24.84) ; R528.1 46.59,18.84 v1(46.68,18.92) 46.84,19.09 U114.14
JTAG_TDI: length 10.3
  TOP w0.14: v1(47.94,17.7) 47.24,18.4 46.37,18.4 43.55,15.58 42.89,15.58 42.43,15.12 J19.3
  BOTTOM w0.14: U114.12 48.26,18.02 v1(47.94,17.7) R542.1
JTAG_TDIS: length 2.7
  TOP w0.14: J19.4 42.43,10.04 v1(42.7,10.31)
  BOTTOM w0.14: R567.2 v1(42.7,10.31)
JTAG_TDO: length 4.7
  TOP w0.14: J19.7 v1(39.89,11.41)
  BOTTOM w0.14: v1(39.89,11.41) 40.2,11.41 41.13,10.48 U122.7
JTAG_TMS: length 8.4
  TOP w0.14: v1(47.07,17.93) 46.47,17.93 43.7,15.16 J19.1
  BOTTOM w0.14: U114.13 47.21,18.69 47.07,18.55 v1(47.07,17.93) 46.21,17.93 R537.1
JTAG_TRST#: length 14.4
  TOP w0.14: J19.2 v1(43.7,10.21)
  L10_SIG03 w0.102: v1(43.7,10.21) 44.11,10.62 44.11,14.25 45.58,15.72 45.58,18.69 v1(46.65,19.76)
  BOTTOM w0.14: R524.2 v1(46.65,19.76) 46.92,19.49 U114.15
LDO_1V8: length 1.6
  TOP w0.14: C122.1 24.44,45.19 v1(24.61,45.36)
  BOTTOM w0.14: U90.35 v1(24.61,45.36)
LDO_3V3: length 96.4
  TOP w0.254: v1(65.61,62.12) 65.94,61.78 65.94,60.26 R147.1 ; v1(65.61,62.12) 65.27,61.78 R146.1 ; v1(65.61,62.12) R142.1 ; R161.1 R158.1 19.03,50.74 19.54,51.25 v1(20.2,51.25) ; R145.1 v1(56.66,62.56) ; v1(16.74,74.22) U27.49 ; U34.8 C105.1 v1(56.66,59.41)
  TOP w0.381: C121.2 15.99,45.73 16.06,45.66 v1(16.18,45.66)
  L03_SIG01 w0.14: v1(16.74,74.22) 16.05,73.54 14.52,73.54 13.4,72.42 13.4,68.1 12.52,67.21 12.52,59.75 17.47,54.79 17.47,52.58 18.81,51.25 v1(20.2,51.25)
  L10_SIG03 w0.254: v1(24.75,50.81) 25.33,51.4 39.35,51.4 42.47,54.52 43.92,54.52 44.45,53.99 45.98,53.99 46.38,53.58 48.11,53.58 48.85,54.32 51.44,54.32 52.3,55.18 52.3,56.88 54.83,59.41 v1(56.66,59.41) 56.66,61.24 56.37,61.53 56.37,62.27 v1(56.66,62.56) 56.67,62.57 65.15,62.57 v1(65.61,62.12)
  BOTTOM w0.254: R412.1 20.52,50.92 v1(20.2,51.25) ; R419.1 v1(25.78,48.45) ; R428.1 14.96,45.16 15.24,45.44 R425.1 15.97,45.44 v1(16.18,45.66) 16.28,45.76 U90.9 ; R415.1 R414.1 v1(24.75,50.81)
LINE1L+: length 2.4
  BOTTOM w0.254: C414.1 82.27,49.93 TP59.1
LINE1L+_C: length 2
  BOTTOM w0.254: U88.3 79.69,49.79 C414.2
LINE1R+: length 2.4
  BOTTOM w0.254: TP60.1 82.27,48.66 C416.1
LINE1R+_C: length 2
  BOTTOM w0.254: C416.2 79.69,48.79 U88.5
LO_LM5141: length 3.3
  BOTTOM w0.14: U89.8 33.53,48.32 32.61,49.24 R417.1
LOL_LM5141: length 2.9
  BOTTOM w0.14: R418.1 31.51,47.97 31.87,48.33 32.76,48.33 33.03,48.06 U89.7
LPDDR4_CA0: length 33.9
  TOP w0.305: U26.H2 v1(37.53,81.27) ; U18.J5 v1(37.08,98.07) ; U26.R2 v1(41.43,81.27)
  L03_SIG01 w0.076: v1(41.43,81.27) 41.43,80.81 41.33,80.71 41.04,80.71 40.96,80.79 40.96,80.91 40.88,80.99 40.57,80.99 40.36,80.78 39.97,80.78 39.88,80.87 v1(39.48,80.87) 39.08,80.87 38.99,80.78 38.6,80.78 38.39,80.99 38.08,80.99 38,80.91 38,80.79 37.92,80.71 37.63,80.71 37.53,80.81 v1(37.53,81.27)
  L10_SIG03 w0.165: 33.48,94.7 33.48,95.06 33.69,95.27 34.88,95.27 35.08,95.46 35.08,95.83 35.31,96.07 35.65,96.07 35.88,96.3 35.88,96.63 36.11,96.86 36.49,96.86 36.68,97.06 36.68,97.44 37.08,97.84 v1(37.08,98.07)
  L10_SIG03 w0.203: 33.48,94.7 33.48,94.57 31.71,92.8 31.71,92.04 31.38,91.71 31.38,86.27 32.84,84.82 32.84,84.51 33.12,84.23 36.94,84.23 37.51,83.66 37.51,82.01 38.18,81.34 38.18,81.26 38.61,80.82 39.44,80.82 v1(39.48,80.87)
LPDDR4_CA1: length 33.9
  TOP w0.305: U26.P2 v1(40.78,82.07) ; U18.J2 v1(37.08,95.67) ; U26.J2 v1(38.18,82.07)
  L03_SIG01 w0.076: v1(38.18,82.07) 37.94,81.83 37.94,81.67 38.03,81.59 38.53,81.59 38.64,81.69 38.64,81.99 38.72,82.07 38.98,82.07 39.06,81.99 39.06,81.75 39.14,81.67 v1(39.48,81.67) 39.82,81.67 39.91,81.75 39.91,81.99 39.98,82.07 40.24,82.07 40.32,81.99 40.32,81.69 40.43,81.59 40.93,81.59 41.02,81.67 41.02,81.83 v1(40.78,82.07)
  L10_SIG03 w0.165: 38.71,83.96 38.71,83.5 38.61,83.4 38.61,82.33 38.82,82.13
  L10_SIG03 w0.203: v1(37.08,95.67) 36.61,95.19 36.22,95.19 36,94.98 36,94.74 35.7,94.43 34.21,94.43 32.37,92.59 32.37,91.88 31.89,91.4 31.89,88.13 32.09,87.93 32.33,87.93 32.53,87.72 32.53,87.38 32.32,87.17 32.05,87.17 31.89,87.01 31.89,86.57 32.5,85.97 32.78,85.97 33.45,86.63 33.82,86.63 34.05,86.4 34.05,85.89 33.6,85.44 33.6,85.08 33.81,84.88 34.16,84.88 34.62,85.34 35.57,85.34 35.8,85.12 36.31,85.12 36.42,85.23 36.8,85.23 36.98,85.04 38.46,85.04 38.71,84.8 38.71,83.96 ; 38.82,82.13 38.98,81.96 39.18,81.96 v1(39.48,81.67)
LPDDR4_CA2: length 33.9
  TOP w0.305: U26.R9 v1(42.08,86.86) ; U26.H9 v1(36.88,86.86) ; U18.J4 v1(37.88,98.07)
  L03_SIG01 w0.076: v1(42.08,86.86) 41.71,87.23 v1(39.48,87.23) 37.25,87.23 v1(36.88,86.86)
  L10_SIG03 w0.165: 34.7,88.06 35.83,88.06 35.99,88.23 35.99,88.64 35.77,88.86 33.38,88.86 33.29,88.95 ; v1(37.88,98.07) U18.J4 37.48,95.44
  L10_SIG03 w0.203: 33.29,88.95 33.25,88.99 32.67,88.99 32.46,89.2 32.46,91.11 32.99,91.63 32.99,92.39 34.54,93.95 36.05,93.95 37.48,95.38 37.48,95.44 ; 34.7,88.06 34.68,88.05 34.27,88.05 34.1,87.87 34.1,87.48 34.24,87.34 34.61,87.34 34.83,87.12 34.83,86.47 35.02,86.29 35.68,86.29 35.85,86.45 36.35,86.45 36.51,86.29 36.75,86.29 37,86.04 37,85.8 37.27,85.53 38.46,85.53 38.77,85.84 38.77,86.97 39.03,87.23 v1(39.48,87.23)
LPDDR4_CA3: length 33.9
  TOP w0.305: U18.L4 v1(38.68,97.27) ; U26.R10 v1(41.43,87.67) ; U26.H10 v1(37.53,87.67)
  L03_SIG01 w0.076: v1(37.53,87.67) 37.53,87.96 37.61,88.03 38.5,88.03 38.6,87.93 38.6,87.71 38.69,87.62 38.94,87.62 39.02,87.7 39.02,87.81 39.1,87.89 v1(39.48,87.89) 39.86,87.89 39.94,87.81 39.94,87.7 40.02,87.62 40.27,87.62 40.36,87.71 40.36,87.93 40.47,88.03 41.35,88.03 41.43,87.96 v1(41.43,87.67)
  L10_SIG03 w0.165: 40.01,96.87 40.51,96.87 40.68,96.69 40.68,96.24 40.85,96.07 43.68,96.07 43.88,95.86 43.88,95.43 ; v1(39.48,87.89) 39.48,88.21 39.88,88.61 39.88,88.62 39.88,88.95 39.73,89.1 39.73,89.43 39.96,89.66
  L10_SIG03 w0.203: v1(38.68,97.27) 38.99,97.57 39.55,97.57 39.76,97.37 39.76,97.11 40.01,96.87 ; 39.96,89.66 40.01,89.71 40.01,92.19 39.78,92.42 39.78,92.61 39.4,93 39.4,95.08 39.14,95.34 39.14,96.36 39.31,96.53 39.62,96.53 39.83,96.33 39.83,95.43 40.04,95.21 40.41,95.21 40.65,94.97 40.65,94.61 40.86,94.41 41.35,94.41 41.53,94.59 41.53,95.04 41.74,95.24 42.36,95.24 42.57,95.04 42.57,94.28 42.78,94.06 43.94,94.06 44.32,94.45 44.72,94.45 44.86,94.59 44.86,94.92 44.68,95.11 44.08,95.11 43.88,95.31 43.88,95.43
LPDDR4_CA4: length 33.9
  TOP w0.305: U26.H11 v1(37.53,88.46) ; U26.R11 v1(41.43,88.46) ; U18.J1 v1(37.88,94.87)
  L03_SIG01 w0.076: v1(41.43,88.46) 41.43,88.76 41.35,88.83 41.03,88.83 40.94,88.74 40.94,88.55 40.85,88.46 40.63,88.46 40.53,88.56 40.53,88.7 40.45,88.78 v1(39.48,88.78) 38.51,88.78 38.43,88.7 38.43,88.56 38.33,88.46 38.11,88.46 38.02,88.55 38.02,88.74 37.93,88.83 37.61,88.83 37.53,88.76 v1(37.53,88.46)
  L10_SIG03 w0.203: v1(39.48,88.78) 38.64,88.78 38.4,88.54 38.18,88.54 38,88.73 38,88.94 38.4,89.35 38.4,89.64 38.21,89.83 37.02,89.83 36.83,90.02 36.61,90.02 36.46,89.87 36.46,89.25 36.35,89.14 36.09,89.14 36,89.23 36,89.71 35.86,89.85 35.28,89.85 35.13,90.01 35.13,90.4 34.82,90.71 34.82,91.03 35.75,91.97 35.75,92.2 35.56,92.39 35.26,92.39 33.87,91 33.87,90.76 34.08,90.55 34.08,90.22 34.54,89.76 34.54,89.54 34.37,89.37 34.16,89.37 33.8,89.73 33.25,89.73 33.05,89.94 33.05,90.97 33.8,91.73 33.8,91.95 33.69,92.07 33.69,92.29 33.85,92.44 34.07,92.44 34.18,92.33 34.4,92.33 34.56,92.49 34.56,92.71 34.44,92.82 34.44,93.04 34.6,93.2 34.82,93.2 34.94,93.08 35.16,93.08 35.51,93.43 36.25,93.43 36.45,93.23 36.45,92.71 36.58,92.58 36.87,92.58 36.98,92.7 36.98,94.14 37.49,94.65 37.66,94.65 v1(37.88,94.87)
LPDDR4_CA5: length 33.9
  TOP w0.305: U26.J11 v1(37.53,89.26) ; U18.K5 v1(38.68,98.07) ; U26.P11 v1(41.43,89.26)
  L03_SIG01 w0.076: v1(37.53,89.26) 37.79,89.53 37.95,89.53 38.03,89.45 38.03,89.22 38.1,89.15 38.33,89.15 38.41,89.23 38.41,89.5 38.66,89.75 v1(39.48,89.75) 40.3,89.75 40.55,89.5 40.55,89.23 40.63,89.15 40.86,89.15 40.93,89.22 40.93,89.45 41.01,89.53 41.17,89.53 v1(41.43,89.26)
  L10_SIG03 w0.165: 38.28,95.5 38.28,98.29 38.1,98.47 37.72,98.47 37.6,98.6 37.6,98.77 37.72,98.9
  L10_SIG03 w0.203: v1(39.48,89.75) 39.22,90.01 39.22,90.42 39.47,90.68 39.47,92.02 39.35,92.14 39.05,92.14 38.92,92.01 38.92,90.9 38.77,90.76 38.55,90.76 38.4,90.9 38.4,92.03 38.29,92.14 37.99,92.14 37.87,92.02 37.87,90.82 37.73,90.68 37.5,90.68 37.34,90.84 37.34,91.35 37.19,91.49 36.74,91.49 36.62,91.37 36.62,91.12 36.8,90.94 36.8,90.69 36.69,90.57 36.4,90.57 36.24,90.72 36.06,90.72 35.84,90.94 35.84,91.37 36.52,92.05 37.14,92.05 37.5,92.41 37.5,92.89 37.65,93.04 38.7,93.04 38.85,93.19 38.85,93.46 38.7,93.6 37.71,93.6 37.57,93.73 37.57,94.01 37.73,94.16 38.7,94.16 38.85,94.31 38.85,94.52 38.71,94.65 38.52,94.65 38.38,94.79 38.38,95.15 38.28,95.26 38.28,95.5 ; 37.72,98.9 38.43,98.9 38.83,98.5 38.83,98.21 v1(38.68,98.07)
LPDDR4_CAL0: length 5
  TOP w0.132: U18.H6 v1(36.28,98.87)
  BOTTOM w0.14: R349.1 35.88,95.36 35.88,98.47 v1(36.28,98.87)
LPDDR4_CK_N: length 33.9
  TOP w0.305: U18.L1 39.27,95.07 39.27,93.93 39.87,93.33 v1(39.88,93.33) ; U26.J9 v1(38.18,86.86) ; U26.P9 v1(40.78,86.86)
  L03_SIG01 w0.076: v1(38.18,86.86) 38.18,86.76 38.3,86.64 38.73,86.64 38.96,86.41 38.96,86.01 38.86,85.91 38.86,85.64 38.98,85.51 39.19,85.51 39.27,85.59 39.27,85.72 v1(39.48,85.93) 39.69,85.72 39.69,85.59 39.77,85.51 39.98,85.51 40.1,85.63 40.1,85.91 40,86.01 40,86.4 40.24,86.64 40.66,86.64 40.78,86.76 v1(40.78,86.86)
  L10_SIG03 w0.188: v1(39.88,93.33) 40.13,93.58 40.64,93.58 41.05,93.17 42.79,93.17 42.98,92.98 42.98,92.72 42.79,92.52 42.79,92.01 43.15,91.64 43.7,91.64 43.98,91.93 44.25,91.93 44.56,91.61 45.09,91.61 45.31,91.83 45.61,91.83 45.99,91.44 45.99,89.96 45.79,89.76 45.25,89.76 45.04,89.96 45.04,90.65 44.68,91.01 42.66,91.01 41.94,91.74 41.94,92.26 41.57,92.62 40.9,92.62 40.52,92.24 40.52,91.44 41.02,90.94 41.02,90.02 40.57,89.57 40.57,88.01 39.97,87.41 39.97,85.89 39.8,85.72 39.67,85.72 39.48,85.91 v1(39.48,85.93)
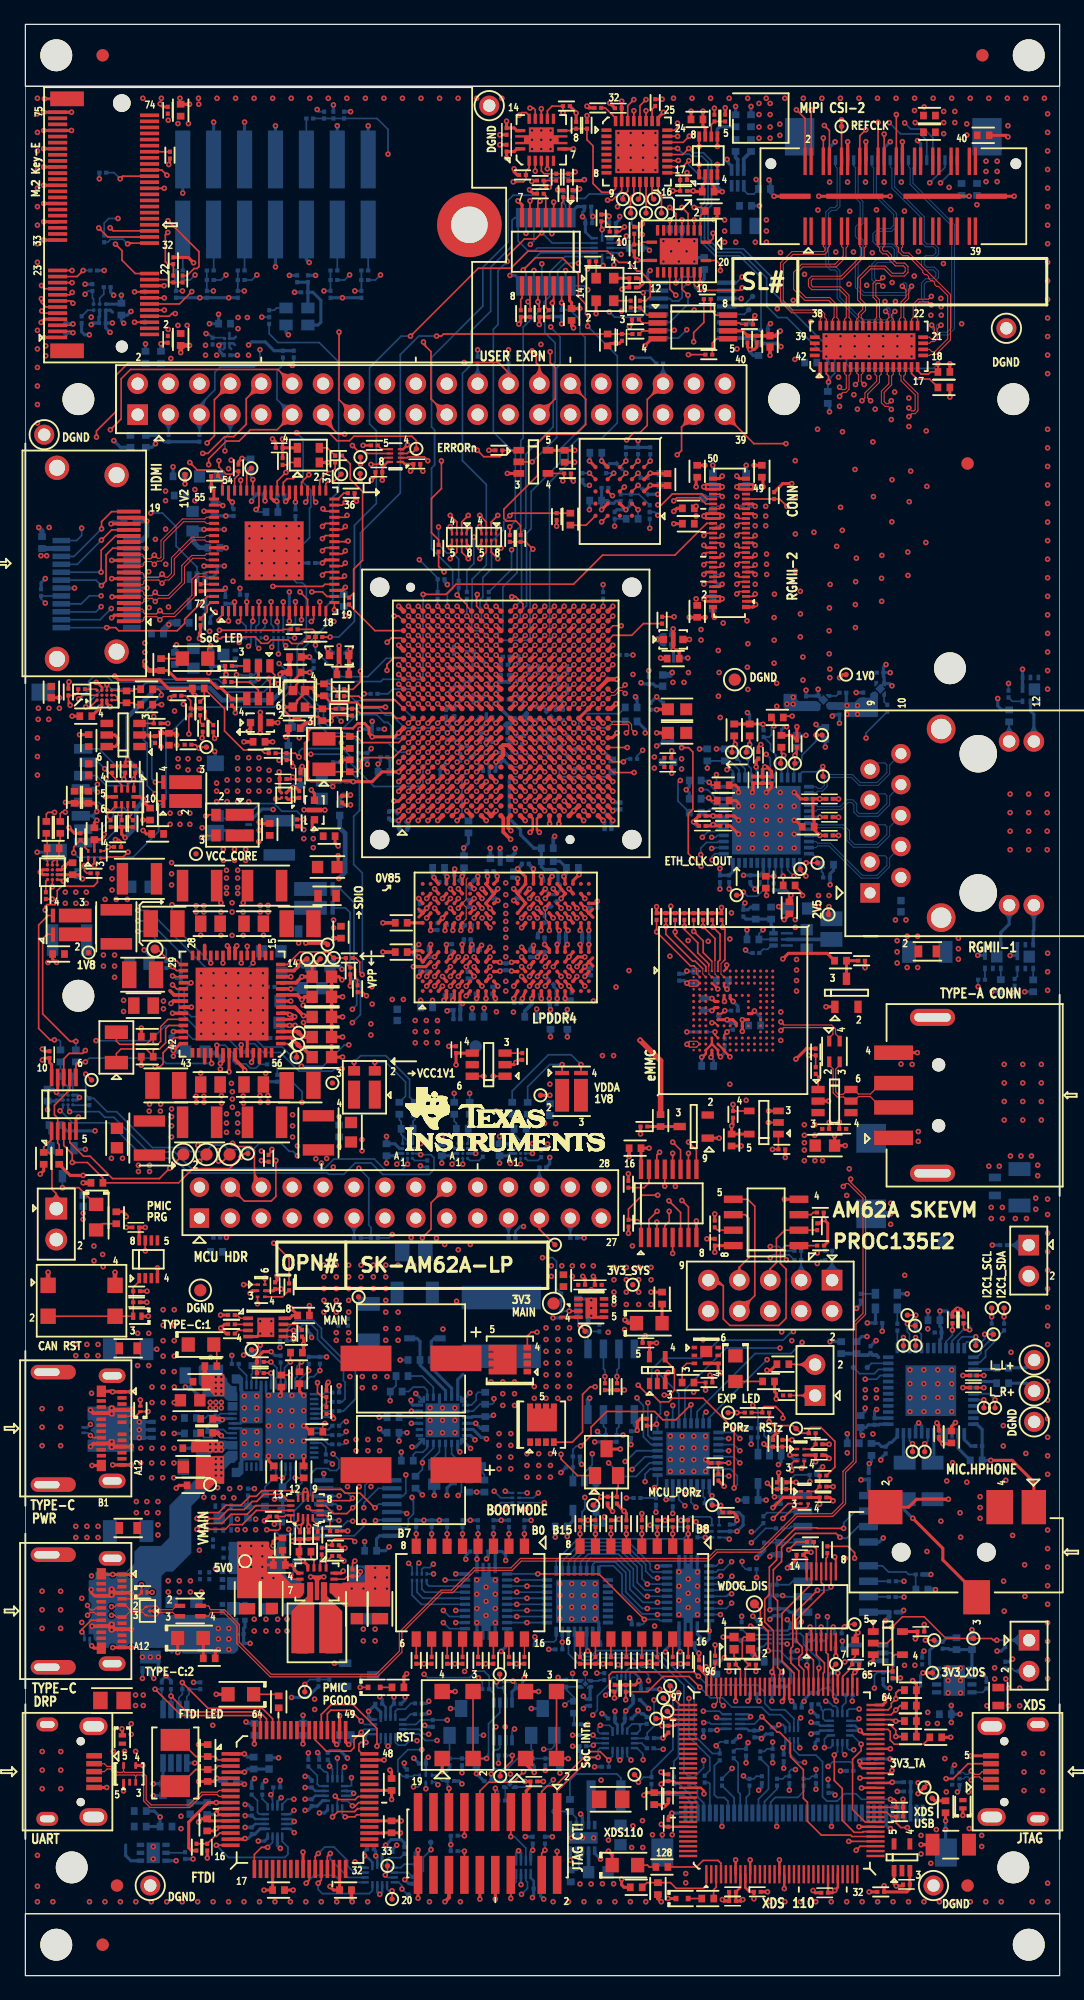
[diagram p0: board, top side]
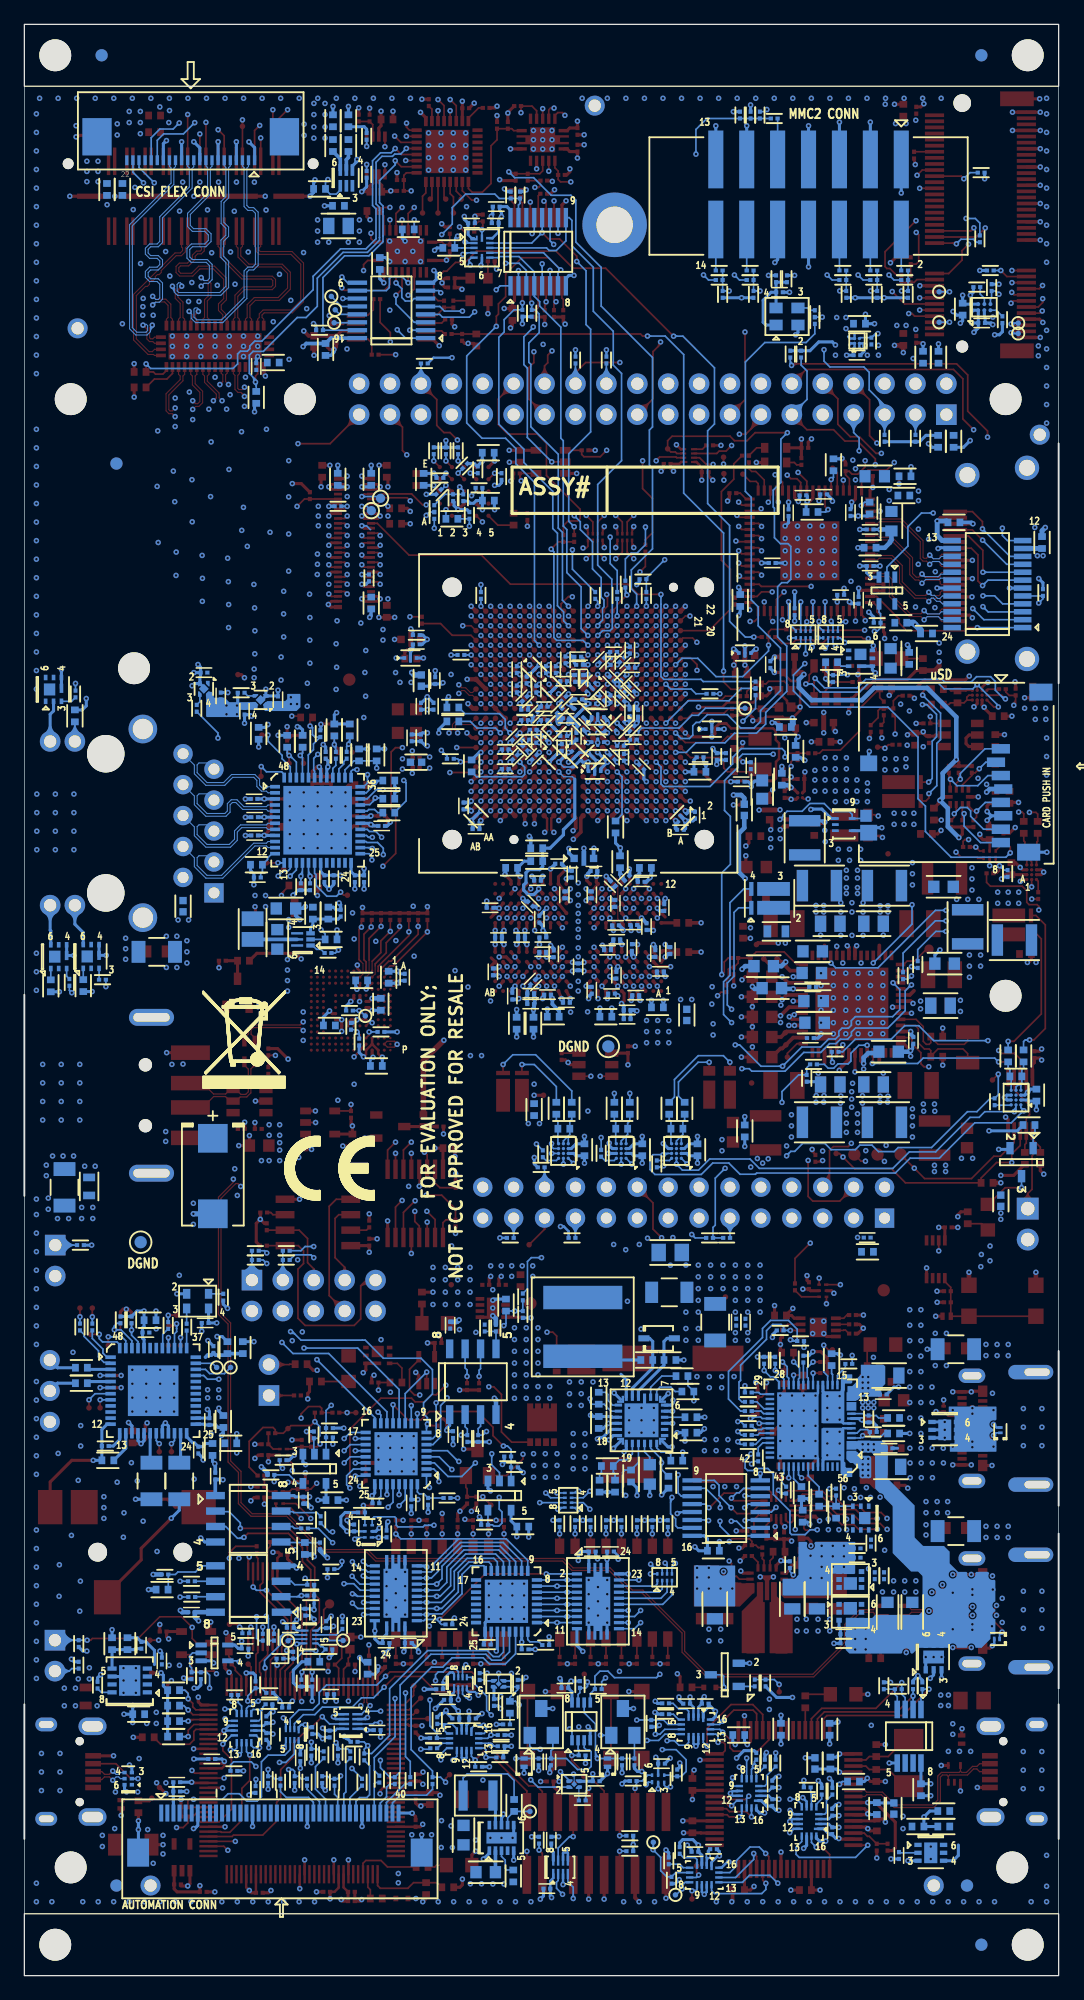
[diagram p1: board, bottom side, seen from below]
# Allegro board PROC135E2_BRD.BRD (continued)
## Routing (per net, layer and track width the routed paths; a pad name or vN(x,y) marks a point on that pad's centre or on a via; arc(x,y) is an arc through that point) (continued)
LPDDR4_CK_P: length 34
  TOP w0.305: U26.P8 v1(40.78,86.06) ; U18.M1 39.69,95.07 39.69,94.25 v1(39.9,94.04) ; U26.J8 v1(38.18,86.06)
  L03_SIG01 w0.076: v1(40.78,86.06) 40.86,86.15 40.86,86.33 40.79,86.4 40.34,86.4 40.24,86.3 40.24,86.11 40.34,86.01 40.34,85.53 40.08,85.27 v1(39.48,85.27) 38.88,85.27 38.62,85.54 38.62,86.01 38.72,86.11 38.72,86.31 38.63,86.4 38.17,86.4 38.1,86.33 38.1,86.15 v1(38.18,86.06)
  L10_SIG03 w0.188: v1(39.9,94.04) 40.06,93.88 40.77,93.88 41.17,93.47 42.92,93.47 43.28,93.11 43.28,92.59 43.09,92.4 43.09,92.13 43.27,91.94 43.57,91.94 43.86,92.23 44.37,92.23 44.69,91.91 44.97,91.91 45.18,92.13 45.73,92.13 46.29,91.57 46.29,89.84 45.91,89.46 45.12,89.46 44.74,89.84 44.74,90.52 44.55,90.71 42.54,90.71 41.64,91.61 41.64,92.14 41.45,92.32 41.03,92.32 40.82,92.12 40.82,91.56 41.32,91.06 41.32,89.9 40.87,89.45 40.87,87.89 40.27,87.29 40.27,85.77 39.92,85.42 39.63,85.42 v1(39.48,85.27)
LPDDR4_CKE0: length 33.9
  TOP w0.305: U18.P3 v1(41.08,96.47) ; U26.P4 v1(40.78,83.67) ; U26.J4 v1(38.18,83.67)
  L03_SIG01 w0.076: v1(38.18,83.67) 37.81,83.67 37.72,83.75 37.72,83.97 37.82,84.06 38.59,84.06 38.7,83.95 38.7,83.78 38.81,83.67 v1(39.48,83.67) 40.15,83.67 40.26,83.78 40.26,83.95 40.37,84.06 41.14,84.06 41.24,83.97 41.24,83.75 41.15,83.67 v1(40.78,83.67)
  L10_SIG03 w0.165: 45.48,95.51 45.48,95.83 45.25,96.07 45.23,96.07 44.85,96.07 44.68,96.23 44.68,96.66 44.48,96.87 41.48,96.87 v1(41.08,96.47)
  L10_SIG03 w0.203: v1(39.48,83.67) 39.47,83.67 39.06,84.09 39.06,84.64 39.26,84.84 39.87,84.84 40.56,85.53 41.75,85.53 41.96,85.74 41.96,86.06 42.16,86.26 42.38,86.26 42.6,86.48 42.6,86.93 43.02,87.35 43.44,87.35 43.58,87.49 43.58,87.87 43.18,88.27 43.18,88.63 43.32,88.77 43.62,88.77 43.91,89.06 44.23,89.06 44.59,88.7 44.59,88.27 44.75,88.12 45.27,88.12 45.39,88.24 45.39,88.69 45.6,88.89 46.81,88.89 47.02,89.1 47.02,91.84 46.13,92.72 46.13,94.1 45.93,94.3 45.62,94.3 45.35,94.57 45.35,95.05 45.48,95.18 45.48,95.51
LPDDR4_CKE1: length 33.9
  TOP w0.305: U26.P5 v1(40.78,84.47) ; U26.J5 v1(38.18,84.47) ; U18.P5 v1(41.08,98.07)
  L03_SIG01 w0.076: v1(40.78,84.47) 41.11,84.8 41.11,84.98 41.01,85.08 40.49,85.08 40.16,84.75 40.16,84.51 40.06,84.41 v1(39.48,84.41) 38.9,84.41 38.8,84.51 38.8,84.75 38.47,85.08 37.95,85.08 37.85,84.98 37.85,84.8 v1(38.18,84.47)
  L10_SIG03 w0.165: v1(41.08,98.07) 41.48,97.67 44.45,97.67 44.68,97.43 44.68,97.1 44.91,96.87 45.25,96.87 45.48,96.63 45.48,96.63 45.48,96.3 45.71,96.07 46.07,96.07 46.28,95.85 46.28,95.42
  L10_SIG03 w0.203: v1(39.48,84.41) 39.99,84.41 40.66,85.08 42.43,85.08 42.63,85.28 46.68,85.28 47.51,86.11 47.51,86.76 47.32,86.95 46.86,86.95 46.66,87.14 46.66,87.43 46.87,87.63 47.36,87.63 47.6,87.87 47.6,91.98 46.73,92.85 46.73,94.97 46.28,95.42
LPDDR4_CS0_A: length 28.4
  TOP w0.305: U26.H4 v1(36.88,83.67) ; U18.J6 v1(37.08,98.87)
  L10_SIG03 w0.165: v1(36.88,83.67) 36.88,83.43 36.72,83.27 35.91,83.27 35.81,83.17 35.81,82.99 35.7,82.88 35.47,82.88 35.35,83 35.35,83.17 35.26,83.27 34.65,83.27 34.51,83.41 34.51,83.68 34.4,83.79 34.16,83.79 34.05,83.68 34.05,83.41 33.91,83.27 33.42,83.27 ; v1(37.08,98.87) 37.08,98.64 36.68,98.24 36.68,97.9 36.45,97.67 36.09,97.67 35.88,97.46 35.88,97.1 35.65,96.86 35.31,96.86 35.08,96.63 35.08,96.28 34.87,96.07 33.71,96.07 33.48,95.83 33.48,95.5 33.25,95.26 32.91,95.26 32.68,95.03 32.68,95.03 32.68,94.66
  L10_SIG03 w0.203: 33.42,83.27 33.35,83.27 33.25,83.37 32.95,83.37 32.79,83.52 32.79,83.87 32.5,84.16 31.58,84.16 31.34,84.39 31.34,84.68 31.47,84.81 31.66,84.81 31.8,84.95 31.8,85.17 31.59,85.38 31.3,85.38 31.19,85.26 30.99,85.26 30.87,85.37 30.87,91.97 31.2,92.3 31.2,93.12 32.68,94.59 32.68,94.66
LPDDR4_CS0_B: length 28.9
  TOP w0.305: U18.M6 v1(40.28,98.87) ; U26.R4 v1(41.43,82.87)
  L10_SIG03 w0.165: 47.88,94.62 47.88,95.08 47.69,95.26 47.31,95.26 47.08,95.5 47.08,95.83 46.85,96.07 46.51,96.07 46.28,96.3 46.28,96.63 46.05,96.86 45.71,96.86 45.48,97.1 45.48,97.43 45.25,97.67 44.91,97.67 44.68,97.9 44.68,98.23 44.45,98.47 44.4,98.47 40.68,98.47 v1(40.28,98.87)
  L10_SIG03 w0.203: v1(41.43,82.87) 41.43,83.7 41.85,84.12 46.41,84.12 48.11,85.82 48.11,92.19 47.76,92.54 47.76,94.29 47.88,94.41 47.88,94.62
LPDDR4_CS1_A: length 32.6
  TOP w0.305: U18.N4 v1(41.08,97.27) ; U26.H3 v1(36.88,82.87)
  L10_SIG03 w0.165: v1(36.88,82.87) 36.88,82.86 36.48,82.47 33.35,82.47 ; v1(41.08,97.27) U18.N4 40.08,97.67 39.41,98.34 39.41,98.5 38.65,99.26 36.91,99.26 36.68,99.03 36.68,98.67 36.47,98.47 36.11,98.47 35.88,98.23 35.88,97.89 35.66,97.67 35.3,97.67 35.08,97.44 35.08,97.09 34.85,96.87 33.71,96.87 33.48,96.64 33.48,96.33 33.48,96.3 33.25,96.07 32.91,96.07 32.68,95.83 32.68,95.48 32.46,95.27 32.1,95.27 31.88,95.05 31.88,94.72
  L10_SIG03 w0.203: 31.88,94.72 31.88,94.55 30.69,93.36 30.69,92.65 30.36,92.33 30.36,84.62 31.67,83.31 32.09,83.31 32.81,82.58 33.23,82.58 33.35,82.47
LPDDR4_CS1_B: length 32.5
  TOP w0.305: U18.M5 v1(40.28,98.07) ; U26.R3 v1(41.43,82.07)
  L10_SIG03 w0.165: v1(40.28,98.07) 40.25,98.07 39.88,98.43 39.88,99.05 40.1,99.26 44.47,99.26 44.68,99.05 44.68,98.7 44.91,98.47 45.27,98.47 45.48,98.25 45.48,97.9 45.71,97.66 46.05,97.66 46.28,97.43 46.28,97.1 46.51,96.87 46.85,96.87 47.08,96.63 47.08,96.3 47.31,96.07 47.65,96.07 47.88,95.83 47.88,95.5 48.11,95.26 48.46,95.26 ; v1(41.43,82.07) 41.43,82.07 41.83,82.47 41.83,82.64 42.46,83.27 46.17,83.27
  L10_SIG03 w0.203: 48.46,95.26 48.52,95.26 48.72,95.06 48.72,94.53 48.27,94.08 48.27,92.76 48.61,92.41 48.61,85.56 46.32,83.27 46.17,83.27
LPDDR4_DMI0: length 25.7
  TOP w0.267: U26.C3 v1(33.63,82.07) ; U18.C2 v1(32.28,95.67)
  L05_SIG02 w0.14: v1(32.28,95.67) 31.88,96.07 31.88,96.66 31.68,96.87 30.47,96.87 30.35,96.99 29.71,96.99 27.16,94.43 27.16,84.95 29.93,82.17 30.79,82.17 30.91,82.3 31.37,82.3 31.5,82.17 31.79,82.17 32.09,82.47 33.23,82.47 v1(33.63,82.07)
LPDDR4_DMI1: length 16.4
  TOP w0.267: U18.F3 v1(34.68,96.47) ; U26.C10 v1(33.63,88.47)
  L03_SIG01 w0.14: v1(33.63,88.47) 33.21,88.89 33.07,88.89 32.93,89.03 32.93,89.56 32.82,89.68 32.62,89.68 32.51,89.57 32.51,89.01 32.38,88.88 32.18,88.88 32.05,89 32.05,89.96 31.96,90.06 31.96,91.16 31.83,91.28 31.69,91.28 31.57,91.17 31.57,90.47 31.46,90.35 31.21,90.35 31.07,90.49 31.07,91.27 31.47,91.68 31.8,91.68 31.92,91.8 31.92,93.34 33.03,94.45 33.28,94.45 33.48,94.65 33.48,95.03 33.71,95.26 34.14,95.26 34.28,95.4 34.28,96.33 34.42,96.47 v1(34.68,96.47)
LPDDR4_DMI2: length 25.3
  TOP w0.267: U18.U1 43.88,94.64 v1(43.84,94.6) ; U26.Y3 v1(44.68,82.87)
  L05_SIG02 w0.14: v1(44.68,82.87) 45.28,83.46 45.28,83.77 45.74,84.23 46.55,84.23 47.4,85.09 47.4,88.79 45.95,90.24 45.95,90.6 44.84,91.72 42.76,91.72 42.27,92.21 42.27,92.89 42.68,93.3 42.68,94.35 42.28,94.75 42.28,97.52 42.43,97.67 42.92,97.67 43.08,97.5 43.08,95.36 v1(43.84,94.6)
LPDDR4_DMI3: length 19.6
  TOP w0.267: U18.W3 v1(45.88,96.47) ; U26.Y10 v1(45.33,87.67)
  L03_SIG01 w0.14: v1(45.88,96.47) 46.28,96.07 48.9,96.07 49.3,95.66 49.3,95.43 49.14,95.26 48.05,95.26 47.88,95.1 47.88,92.36 48.03,92.21 48.03,91.94 47.88,91.79 47.88,91.32 47.98,91.21 48.25,91.21 48.35,91.31 48.35,91.52 48.49,91.66 48.69,91.66 49.09,91.25 49.33,91.25 49.47,91.11 49.47,90.52 49.34,90.39 49.14,90.39 48.88,90.65 48.68,90.65 48.54,90.52 48.54,90.32 48.81,90.06 48.81,89.86 47.76,88.81 46.98,88.81 46.23,88.07 45.73,88.07 v1(45.33,87.67)
LPDDR4_DQ0: length 25.7
  TOP w0.267: U18.A5 v1(30.68,98.07) ; U26.B2 v1(32.98,81.27)
  L05_SIG02 w0.14: v1(32.98,81.27) 32.32,81.27 32.29,81.23 29.68,81.23 26.32,84.6 26.32,94.78 27.78,96.24 27.78,97.27 28.57,98.07 v1(30.68,98.07)
LPDDR4_DQ1: length 25.7
  TOP w0.267: U26.C2 v1(33.63,81.27) ; U18.B4 v1(31.48,97.27)
  L05_SIG02 w0.14: v1(33.63,81.27) 33.23,81.67 29.84,81.67 26.74,84.77 26.74,94.61 28.21,96.08 28.21,96.48 28.41,96.69 28.59,96.69 29.47,97.56 30.35,97.56 30.45,97.66 31.08,97.66 v1(31.48,97.27)
LPDDR4_DQ2: length 25.7
  TOP w0.267: U18.B6 v1(31.48,98.87) ; U26.E2 v1(34.93,81.27)
  L05_SIG02 w0.14: v1(31.48,98.87) 31.88,98.47 32.47,98.47 32.68,98.26 32.68,97.9 32.91,97.67 33.27,97.67 33.48,97.46 33.48,97.1 33.71,96.87 34.05,96.87 34.28,96.63 34.28,96.3 34.51,96.07 34.85,96.07 35.08,95.83 35.08,91.43 34.86,91.21 34.86,90.69 35.99,89.57 35.99,87.43 35.82,87.27 35.3,87.27 35.07,87.03 35.07,86.47 35.28,86.26 36,86.26 36.18,86.08 36.18,85.27 36.29,85.16 36.29,84.42 36.64,84.07 37.04,84.07 37.29,83.82 37.29,82.65 37.1,82.46 36.56,82.46 36.34,82.25 36.34,81.92 36.09,81.67 35.33,81.67 v1(34.93,81.27)
LPDDR4_DQ3: length 25.7
  TOP w0.267: U18.D5 v1(33.08,98.07) ; U26.F2 v1(35.58,81.27)
  L05_SIG02 w0.14: v1(33.08,98.07) 33.56,98.55 34.14,98.55 34.28,98.41 34.28,97.8 34.42,97.67 34.88,97.67 35.08,97.47 35.08,97.07 35.28,96.86 35.65,96.86 35.88,96.63 35.88,93.35 35.61,93.07 35.61,92.26 35.75,92.12 36.17,92.12 36.31,91.97 36.31,91.78 36.17,91.63 35.79,91.63 35.65,91.49 35.65,91.21 35.79,91.07 36.29,91.07 36.45,90.91 36.45,87.22 36.33,87.11 36.33,86.61 36.6,86.34 36.74,86.34 37.02,86.07 37.02,85.78 37.22,85.57 37.22,85.26 37.09,85.13 37.09,84.46 37.33,84.22 37.53,84.22 37.68,84.07 37.68,82.12 37.36,81.8 37.2,81.8 36.78,81.38 36.78,81 36.64,80.86 35.98,80.86 v1(35.58,81.27)
LPDDR4_DQ4: length 25.7
  TOP w0.267: U26.F4 v1(36.23,83.67) ; U18.C5 v1(32.28,98.07)
  L05_SIG02 w0.14: v1(36.23,83.67) 36.23,83.93 35.95,84.2 35.57,84.2 35.25,84.52 35.25,85.14 34.94,85.44 32.12,85.44 31.9,85.67 31.9,86.01 32.14,86.26 32.14,86.66 31.9,86.91 31.9,87.28 32.18,87.56 32.18,87.93 31.9,88.21 31.9,89.77 32.07,89.94 32.26,89.94 32.81,89.39 33.01,89.39 33.14,89.53 33.14,89.72 32.59,90.27 32.59,90.47 33.01,90.88 33.2,90.88 33.43,90.65 33.63,90.65 33.77,90.78 33.77,90.98 33.53,91.21 33.53,91.4 33.67,91.54 33.87,91.54 34.1,91.31 34.29,91.31 34.43,91.45 34.43,91.64 34.2,91.88 34.2,92.07 34.55,92.42 34.55,95.02 34.28,95.29 34.28,95.83 34.05,96.07 33.71,96.07 33.48,96.3 33.48,96.63 33.25,96.86 33.21,96.87 32.86,96.87 32.68,97.04 32.68,97.5 32.54,97.64 32.42,97.64 32.28,97.78 v1(32.28,98.07)
LPDDR4_DQ5: length 25.7
  TOP w0.267: U26.E4 v1(35.58,83.67) ; U18.C3 v1(32.28,96.47)
  L05_SIG02 w0.14: v1(35.58,83.67) 35.57,83.67 34.99,84.25 34.45,84.25 34.18,84.51 34.18,84.92 34.02,85.09 31.46,85.09 31.2,85.34 31.2,85.82 31.46,86.07 31.46,90.11 31.84,90.49 31.84,90.69 31.36,91.17 31.36,91.36 31.5,91.5 31.69,91.5 32.17,91.02 32.37,91.02 32.51,91.16 32.51,91.35 32.02,91.84 32.02,92.03 32.16,92.17 32.36,92.17 32.84,91.68 33.03,91.68 33.27,91.92 33.27,92.11 32.84,92.54 32.84,92.73 32.98,92.87 33.17,92.87 33.6,92.44 33.79,92.44 34.1,92.75 34.1,93.21 33.93,93.38 33.55,93.38 33.41,93.52 33.41,93.76 33.51,93.86 33.95,93.86 34.09,94 34.09,94.24 33.95,94.38 33.62,94.38 33.48,94.52 33.48,95.83 33.25,96.07 32.68,96.07 v1(32.28,96.47)
LPDDR4_DQ6: length 25.7
  TOP w0.267: U26.C4 v1(33.63,82.86) ; U18.B2 v1(31.48,95.67)
  L05_SIG02 w0.14: v1(31.48,95.67) 31.08,95.27 31.08,94.36 30.7,93.98 30.7,92.59 29.79,91.68 29,91.68 28.77,91.45 28.77,91 28.63,90.86 28.19,90.86 28.01,90.68 28.01,90.44 28.16,90.29 28.74,90.29 28.91,90.12 28.91,89.91 28.77,89.77 28.16,89.77 28.01,89.61 28.01,89.4 28.16,89.25 28.74,89.25 28.91,89.08 28.91,88.87 28.77,88.72 28.16,88.72 28.01,88.57 28.01,88.36 28.16,88.2 28.74,88.2 28.91,88.04 28.91,87.82 28.77,87.68 28.16,87.68 28.01,87.53 28.01,87.25 28.16,87.1 28.72,87.1 28.87,86.95 28.87,86.73 28.72,86.58 28.16,86.58 28.01,86.43 28.01,85.93 28.14,85.79 28.53,85.79 30.78,83.55 31.84,83.55 32.13,83.27 32.63,83.27 32.75,83.38 33.11,83.38 v1(33.63,82.86)
LPDDR4_DQ7: length 25.7
  TOP w0.267: v1(31.89,82.86) 32.91,82.86 U26.B4 ; v1(30.27,96.47) 30.68,96.47 U18.A3
  L05_SIG02 w0.14: v1(30.27,96.47) 30.27,96.06 30.2,95.99 30.2,95.02 30.05,94.87 29.85,94.87 29.71,95.01 29.71,95.6 29.54,95.77 29.2,95.77 29.05,95.61 29.05,95.06 28.88,94.9 28.21,94.9 27.57,94.26 27.57,92.14 27.71,92 28.11,92 28.26,91.86 28.26,91.45 28.12,91.31 27.71,91.31 27.57,91.17 27.57,85.22 27.79,85 28,85 28.21,85.21 28.42,85.21 28.57,85.06 28.57,84.84 28.37,84.64 28.37,84.42 28.53,84.27 28.76,84.27 28.93,84.09 28.93,83.86 29.33,83.47 29.57,83.47 29.74,83.64 29.94,83.64 30.15,83.43 30.15,83.22 29.95,83.02 29.95,82.82 30.09,82.68 30.63,82.68 30.82,82.86 v1(31.89,82.86)
LPDDR4_DQ8: length 16.3
  TOP w0.267: U26.B11 v1(32.98,88.47) ; U18.E2 v1(33.88,95.67)
  L03_SIG01 w0.14: v1(33.88,95.67) 33.65,95.67 33.25,95.27 32.92,95.27 32.68,95.03 32.68,94.7 31.5,93.52 31.5,92.3 30.6,91.41 30.6,88.26 30.74,88.12 31.09,88.12 31.23,88.26 31.23,89.79 31.35,89.91 31.52,89.91 31.63,89.79 31.63,88.04 31.77,87.9 32.41,87.9 v1(32.98,88.47)
LPDDR4_DQ9: length 16.4
  TOP w0.267: U18.F5 v1(34.68,98.07) ; U26.C11 v1(33.63,89.27)
  L03_SIG01 w0.14: v1(33.63,89.27) 33.33,89.57 33.33,89.7 32.88,90.15 32.59,90.15 32.38,90.35 32.38,93.18 33.21,94 33.42,94 33.83,94.41 34.19,94.41 34.48,94.7 34.48,94.87 35.08,95.47 35.08,96.64 34.85,96.87 34.49,96.87 34.28,97.08 34.28,97.49 34.1,97.67 32.88,97.67 32.68,97.87 32.68,98.27 32.87,98.47 34.19,98.47 34.59,98.07 v1(34.68,98.07)
LPDDR4_DQ10: length 16.4
  TOP w0.267: U26.E11 v1(34.93,89.26) ; U18.E6 v1(34.68,98.87)
  L03_SIG01 w0.14: v1(34.93,89.26) 34.71,89.49 34.71,89.69 35.08,90.06 35.08,90.51 34.8,90.79 34.8,93.03 35,93.23 36.08,93.23 36.22,93.37 36.22,95.14 35.88,95.49 35.88,97.51 35.73,97.67 35.22,97.67 35.08,97.81 35.08,99.12 34.94,99.27 33.62,99.27 33.52,99.16 33.52,98.97 33.62,98.87 v1(34.68,98.87)
LPDDR4_DQ11: length 16.4
  TOP w0.267: U26.F11 v1(35.58,89.26) ; U18.G2 v1(36.28,96.47)
  L03_SIG01 w0.14: v1(36.28,96.47) 36.54,96.47 36.68,96.33 36.68,95.36 36.93,95.11 36.93,94.77 36.65,94.49 36.65,94.22 36.94,93.94 36.94,93.69 36.65,93.4 36.65,93.13 36.5,92.98 36.5,92.7 36.82,92.38 36.82,91.24 36.71,91.12 36.71,90.98 36.6,90.88 36.44,90.88 36.3,91.01 36.3,91.38 36.42,91.5 36.42,92.13 36.32,92.23 36.13,92.23 36.05,92.15 36.05,91.77 35.93,91.66 35.71,91.66 35.61,91.76 35.61,92.7 35.51,92.8 35.32,92.8 35.22,92.7 35.22,91.44 35.38,91.28 35.79,91.28 35.93,91.14 35.93,90.9 35.44,90.41 35.44,90.15 35.72,89.87 35.72,89.68 35.58,89.54 v1(35.58,89.26)
LPDDR4_DQ12: length 16.4
  TOP w0.267: U18.G6 v1(35.48,98.87) ; U26.F9 v1(35.58,86.87)
  L03_SIG01 w0.14: v1(35.58,86.87) 36.38,87.67 36.38,89.35 36.85,89.81 37.28,89.81 37.58,90.12 37.58,90.6 37.67,90.69 37.67,92.85 37.79,92.97 37.79,94.18 38.28,94.67 38.28,96.64 38.05,96.87 37.71,96.87 37.48,97.1 37.48,97.11 37.48,97.46 37.28,97.67 36.91,97.67 36.68,97.9 36.68,98.26 36.48,98.47 35.88,98.47 v1(35.48,98.87)
LPDDR4_DQ13: length 16.4
  TOP w0.267: U18.G4 v1(36.28,98.07) ; U26.E9 v1(34.93,87.67)
  L03_SIG01 w0.14: v1(36.28,98.07) 36.28,97.85 36.68,97.45 36.68,97.03 36.84,96.87 37.27,96.87 37.48,96.65 37.48,95.5 37.37,95.38 37.37,93.24 37.24,93.11 37.24,90.92 36.74,90.42 36.74,90.23 36.08,89.57 36.08,88.24 35.9,88.07 34.37,88.07 34.2,87.9 34.2,87.58 34.71,87.07 35.04,87.07 35.18,87.21 35.18,87.41 v1(34.93,87.67)
LPDDR4_DQ14: length 16.4
  TOP w0.267: U26.C9 v1(33.63,87.67) ; U18.E4 v1(33.88,97.27)
  L03_SIG01 w0.14: v1(33.88,97.27) 33.48,96.86 33.48,96.3 33.25,96.07 32.88,96.07 32.68,95.86 32.68,95.48 32.46,95.27 32.11,95.27 31.88,95.04 31.88,94.58 31.08,93.78 31.08,92.47 30.18,91.58 30.18,87.99 30.91,87.27 31.76,87.27 31.96,87.47 32.51,87.47 32.71,87.27 33.23,87.27 v1(33.63,87.67)
LPDDR4_DQ15: length 16.3
  TOP w0.267: U18.D3 v1(33.08,96.47) ; U26.B9 v1(32.98,86.87)
  L03_SIG01 w0.14: v1(33.08,96.47) 32.68,96.86 31.3,96.86 31.08,96.65 31.08,94.43 30.66,94.01 30.66,92.65 29.77,91.75 29.77,87.8 30.72,86.85 32.96,86.85 v1(32.98,86.87)
LPDDR4_DQ16: length 25.3
  TOP w0.267: U26.AA2 v1(45.98,81.27) ; U18.T6 v1(43.48,98.87)
  L05_SIG02 w0.14: v1(45.98,81.27) 46.78,81.27 49.5,83.98 49.5,91.45 48.3,92.65 48.3,94.29 48.71,94.7 48.71,95.8 48.45,96.07 48.11,96.07 47.88,96.3 47.88,96.63 47.65,96.86 47.31,96.86 47.08,97.1 47.08,97.43 46.85,97.67 46.51,97.67 46.28,97.9 46.28,98.23 46.05,98.47 43.88,98.47 v1(43.48,98.87)
LPDDR4_DQ17: length 25.3
  TOP w0.267: U18.T4 v1(43.48,97.27) ; U26.Y2 v1(45.33,82.07)
  L05_SIG02 w0.14: v1(43.48,97.27) 43.48,97.55 43.58,97.65 43.77,97.65 43.88,97.54 43.88,97.07 44.09,96.87 46.05,96.87 46.28,96.63 46.28,96.3 46.51,96.07 46.85,96.07 47.08,95.83 47.08,95.22 46.98,95.13 46.82,95.13 46.7,95.01 46.7,94.61 46.84,94.46 47.31,94.46 47.45,94.32 47.45,94.13 47.32,93.99 46.45,93.99 46.31,93.85 46.31,93.64 46.42,93.52 47.27,93.52 47.44,93.35 47.44,92.31 48.66,91.09 48.66,84.34 46.79,82.47 45.73,82.47 v1(45.33,82.07)
LPDDR4_DQ18: length 25.3
  TOP w0.267: U18.U5 v1(44.28,98.07) ; U26.V2 v1(44.03,81.27)
  L05_SIG02 w0.14: v1(44.28,98.07) 44.68,97.67 46.06,97.67 46.28,97.44 46.28,97.1 46.51,96.86 46.85,96.86 47.08,96.63 47.08,96.3 47.31,96.07 47.65,96.07 47.88,95.83 47.88,95.8 47.88,92.46 49.08,91.26 49.08,84.16 46.58,81.67 45.71,81.67 45.39,81.35 45.39,81.01 45.12,80.74 44.17,80.74 44.03,80.88 v1(44.03,81.27)
LPDDR4_DQ19: length 25.3
  TOP w0.267: U26.U2 v1(42.73,81.27) ; U18.R5 v1(41.88,98.07)
  L05_SIG02 w0.14: v1(41.88,98.07) 41.48,97.67 39.68,97.67 38.88,96.87 38.52,96.87 38.28,96.63 38.28,96.3 38.05,96.07 37.71,96.07 37.48,95.83 37.48,95.3 37.37,95.19 37.37,92.05 38.38,91.05 38.38,88.16 39.07,87.47 39.07,85.11 39.33,84.85 39.61,84.85 39.89,84.57 39.89,83.86 40.35,83.4 40.35,82.33 40.24,82.22 40.24,81.73 41.22,80.76 42.22,80.76 v1(42.73,81.27)
LPDDR4_DQ20: length 25.3
  TOP w0.267: U18.P2 v1(41.88,95.67) ; U26.U4 v1(42.73,82.87)
  L05_SIG02 w0.14: v1(42.73,82.87) 43.3,83.44 43.3,84.01 43.06,84.25 42.4,84.25 42.23,84.42 42.23,84.83 42.1,84.96 42.1,85.26 42.24,85.4 42.59,85.4 42.72,85.27 43.24,85.27 43.47,85.49 43.47,86.06 43.16,86.37 42.81,86.37 42.65,86.53 42.65,87.02 42.8,87.17 42.98,87.17 43.19,87.38 43.47,87.38 43.59,87.5 43.59,87.75 43.38,87.96 43.38,88.3 43.56,88.48 43.56,88.73 43.42,88.87 42.32,88.87 42.1,89.08 42.1,90 41.87,90.23 41.51,90.23 41.37,90.09 41.37,89.93 41.24,89.81 41.01,89.81 40.87,89.95 40.87,91.1 40.65,91.32 39.69,91.32 38.61,92.4 38.61,93.81 38.76,93.96 38.76,94.98 39.84,96.07 U18.P2 v1(41.88,95.67)
LPDDR4_DQ21: length 25.3
  TOP w0.267: U26.V4 v1(43.38,82.87) ; U18.R3 v1(41.88,96.47)
  L05_SIG02 w0.14: v1(43.38,82.87) 42.98,82.47 42.39,82.47 41.92,82.93 41.92,83.13 41.36,83.69 41.36,85.3 41.21,85.45 40.72,85.45 40.6,85.33 40.6,85.16 40.46,85.02 40.11,85.02 39.95,85.19 39.95,85.65 40.13,85.84 40.13,86.12 39.95,86.31 39.95,86.61 40.16,86.82 40.16,87.09 39.95,87.3 39.95,87.58 40.09,87.73 40.55,87.73 40.74,87.91 40.74,88.58 40.54,88.78 40.05,88.78 39.73,89.1 39.73,89.43 39.94,89.64 39.94,90.38 38.39,91.93 38.25,91.93 37.79,92.39 37.79,94.27 37.93,94.41 38.12,94.41 38.28,94.56 38.28,95.83 38.51,96.07 38.94,96.07 39.14,96.26 39.14,96.47 39.53,96.87 41.48,96.87 v1(41.88,96.47)
LPDDR4_DQ22: length 25.3
  TOP w0.267: U18.T2 v1(43.48,95.67) ; v1(45.98,83.67) 45.41,83.67 U26.Y4
  L05_SIG02 w0.14: v1(43.48,95.67) 43.89,95.25 44.19,95.25 44.41,95.04 44.68,95.04 44.9,95.25 45.22,95.25 45.41,95.07 45.41,94.67 45.16,94.41 44.27,94.41 44.02,94.17 43.28,94.17 43.1,93.99 43.1,93.13 42.71,92.74 42.71,92.39 42.92,92.19 43.24,92.19 43.51,92.45 43.93,92.45 44.19,92.19 45.07,92.19 45.51,91.75 46.21,91.75 46.35,91.61 46.35,90.85 46.49,90.71 47.31,90.71 47.45,90.85 47.66,90.85 47.82,90.69 47.82,90.39 47.69,90.26 46.99,90.26 46.87,90.14 46.87,89.93 46.99,89.81 47.68,89.81 47.82,89.67 47.82,84.69 46.8,83.67 v1(45.98,83.67)
LPDDR4_DQ23: length 25.3
  TOP w0.267: U26.AA4 v1(45.33,82.87) ; U18.U3 v1(43.48,96.47)
  L05_SIG02 w0.14: v1(45.33,82.87) 45.73,83.27 46.29,83.27 46.51,83.04 46.77,83.04 48.24,84.51 48.24,90.91 47.66,91.49 47.48,91.49 47.12,91.13 46.92,91.13 46.78,91.28 46.78,91.48 47.13,91.84 47.13,92.02 46.96,92.19 45.68,92.19 45.56,92.31 45.56,92.53 45.66,92.63 46.88,92.63 47.02,92.77 47.02,92.97 46.91,93.08 46.01,93.08 45.87,93.22 45.87,93.73 45.59,94.01 45.59,94.25 45.77,94.42 46.14,94.42 46.28,94.56 46.28,95.83 46.05,96.07 43.88,96.07 v1(43.48,96.47)
LPDDR4_DQ24: length 19.6
  TOP w0.267: U18.Y2 v1(46.68,95.67) ; U26.AA11 v1(45.98,88.46)
  L03_SIG01 w0.14: v1(46.68,95.67) 46.93,95.67 47.08,95.52 47.08,95.21 46.72,94.86 46.72,94.58 46.84,94.47 47.33,94.47 47.46,94.34 47.46,94.12 47.32,93.98 46.04,93.98 45.9,93.84 45.9,93.64 46.04,93.5 47.32,93.5 47.46,93.37 47.46,93.17 47.32,93.03 46.45,93.03 46.31,92.89 46.31,92.68 46.51,92.48 47.32,92.48 47.46,92.34 47.46,92.11 47.32,91.97 46.8,91.97 46.66,91.83 46.66,91.62 46.8,91.48 47.32,91.48 47.46,91.34 47.46,91.15 47.32,91.01 46.98,91.01 46.84,90.87 46.84,90.56 47.01,90.4 47.44,90.4 47.7,90.66 47.97,90.66 48.11,90.52 48.11,89.76 47.73,89.37 47.5,89.37 47.36,89.51 47.36,89.82 47.22,89.96 47.02,89.96 46.88,89.82 46.88,89.37 v1(45.98,88.46)
LPDDR4_DQ25: length 19.6
  TOP w0.267: U18.V2 v1(44.28,96.47) ; U26.Y11 v1(44.68,89.26)
  L03_SIG01 w0.14: v1(44.68,89.26) 44.01,89.26 43.75,89.52 43.75,90.66 43.1,91.31 42.14,91.31 41.98,91.47 41.6,91.47 41.45,91.31 41.23,91.31 41.04,91.5 41.04,91.7 41.27,91.93 41.27,92.12 41.13,92.27 40.89,92.27 40.62,92 40.33,92 39.93,91.59 39.73,91.59 39.57,91.75 39.57,91.95 39.84,92.23 39.84,92.74 40.08,92.97 40.39,92.97 40.53,93.11 40.53,93.47 40.33,93.67 40.33,93.92 40.57,94.17 40.57,94.5 40.46,94.61 40.14,94.61 40.03,94.73 40.03,95.07 40.14,95.18 40.51,95.18 40.68,95.36 40.68,95.83 40.91,96.07 41.27,96.07 41.48,96.28 41.48,96.65 41.7,96.87 44.14,96.87 44.28,96.73 v1(44.28,96.47)
LPDDR4_DQ26: length 19.6
  TOP w0.267: U26.V11 v1(43.38,89.26) ; U18.V4 v1(45.08,97.27)
  L03_SIG01 w0.14: v1(43.38,89.26) 43.38,89.52 43.24,89.67 42.87,89.67 42.75,89.79 42.75,90.01 42.84,90.1 42.84,90.43 42.95,90.54 42.95,90.75 42.81,90.88 42.35,90.88 41.92,90.46 41.3,90.46 40.87,90.89 40.87,91.07 40.55,91.39 40.34,91.39 39.94,90.99 39.74,90.99 39.06,91.66 39.06,92.06 39.42,92.42 39.42,92.93 39.31,93.04 39.31,94.12 39.64,94.45 39.64,95.82 39.89,96.07 40.45,96.07 40.68,96.3 40.68,96.65 40.9,96.87 41.25,96.87 41.48,97.1 41.48,97.45 41.7,97.67 44.94,97.67 45.08,97.53 v1(45.08,97.27)
LPDDR4_DQ27: length 19.6
  TOP w0.267: U18.W5 v1(45.88,98.07) ; U26.U11 v1(42.73,88.46)
  L03_SIG01 w0.14: v1(45.88,98.07) U18.W5 41.71,98.47 41.48,98.23 41.48,98.22 41.48,97.89 41.25,97.67 40.91,97.67 40.68,97.43 40.68,97.1 40.45,96.87 40.09,96.87 39.19,95.97 39.19,94.6 38.87,94.27 38.87,93.59 38.61,93.33 38.61,91.52 39.64,90.5 40.69,90.5 41.13,90.06 41.38,90.06 42.11,89.33 42.11,89.09 v1(42.73,88.46)
LPDDR4_DQ28: length 19.6
  TOP w0.267: U26.U9 v1(43.38,86.87) ; U18.Y4 v1(46.68,97.27)
  L03_SIG01 w0.14: v1(46.68,97.27) 46.28,96.87 44.9,96.87 44.68,96.65 44.68,96.28 44.47,96.07 42.49,96.07 42.28,95.86 42.28,95.47 41,94.19 41,93.06 42.33,91.73 43.39,91.73 45.1,90.02 45.1,89.12 44.79,88.81 44.4,88.81 44.33,88.89 43.69,88.89 43.47,88.67 43.47,87.41 43.38,87.32 v1(43.38,86.87)
LPDDR4_DQ29: length 19.6
  TOP w0.267: U18.AA3 v1(47.48,96.47) ; U26.V9 v1(44.03,86.87)
  L03_SIG01 w0.14: v1(47.48,96.47) 47.88,96.87 48.51,96.87 48.64,96.74 49.13,96.74 49.27,96.6 49.27,96.29 49.59,95.97 49.83,95.97 49.97,95.83 49.97,95.61 49.86,95.49 49.86,95.3 49.97,95.18 49.97,94.98 49.83,94.84 48.88,94.84 48.31,94.27 48.31,92.62 49.2,91.74 49.68,91.74 49.89,91.53 49.89,90.35 47.91,88.37 47.61,88.37 47.45,88.2 47.45,87.91 46.8,87.27 44.43,87.27 v1(44.03,86.87)
LPDDR4_DQ30: length 19.6
  TOP w0.267: U18.AA5 v1(47.48,98.07) ; U26.Y9 v1(45.33,86.87)
  L03_SIG01 w0.14: v1(45.33,86.87) 45.95,86.24 47.02,86.24 51.8,91.03 51.8,95.33 49.45,97.68 48.53,97.68 48.51,97.66 47.88,97.66 v1(47.48,98.07)
LPDDR4_DQ31: length 19.6
  TOP w0.267: U18.AB4 v1(48.28,97.26) ; U26.AA9 v1(45.98,86.87)
  L03_SIG01 w0.14: v1(45.98,86.87) 47.01,86.87 50.54,90.4 50.54,90.59 50.32,90.82 50.32,91.01 50.46,91.15 50.65,91.15 50.87,90.92 51.07,90.92 51.39,91.24 51.39,91.51 51.25,91.64 50.83,91.64 50.7,91.78 50.7,91.98 50.84,92.13 51.25,92.13 51.39,92.26 51.39,95.15 51.2,95.34 51.01,95.34 50.87,95.2 50.87,94.84 50.73,94.71 50.55,94.71 50.41,94.85 50.41,96.1 49.24,97.26 v1(48.28,97.26)
LPDDR4_DQS0_N: length 25.7
  TOP w0.203: v1(34.93,82.07) U26.E3 ; U18.C1 v1(32.28,94.87)
  L05_SIG02 w0.127: v1(34.93,82.07) 34.55,82.44 34.41,82.44 34.13,82.72 34.13,83.73 33.79,84.06 31.06,84.06 30.65,84.47 30.65,84.74 30.17,85.23 29.89,85.23 29.6,85.52 29.6,85.97 29.88,86.25 30.56,86.25 30.69,86.37 30.69,86.62 30.53,86.78 29.78,86.78 29.49,87.07 29.49,87.48 29.78,87.77 30.53,87.77 30.69,87.92 30.69,88.14 30.53,88.3 29.78,88.3 29.49,88.59 29.49,89 29.78,89.29 30.53,89.29 30.69,89.45 30.69,89.73 30.54,89.88 29.75,89.88 29.47,90.17 29.47,90.8 29.76,91.1 30.08,91.1 31.28,92.29 31.28,93.23 31.57,93.52 32.47,93.52 32.63,93.68 32.63,94.09 32.46,94.26 32.46,94.61 32.46,94.69 v1(32.28,94.87)
LPDDR4_DQS0_P: length 25.7
  TOP w0.203: v1(34.93,82.86) U26.D3 ; U18.D1 v1(33.08,94.86)
  L05_SIG02 w0.127: v1(33.08,94.86) 32.95,94.99 32.77,94.99 32.69,94.9 32.69,94.7 32.69,94.35 32.85,94.19 32.85,93.58 32.57,93.29 31.67,93.29 31.51,93.13 31.51,92.2 30.18,90.87 29.86,90.87 29.69,90.71 29.69,90.26 29.84,90.11 30.63,90.11 30.92,89.83 30.92,89.35 30.63,89.06 29.88,89.06 29.72,88.91 29.72,88.68 29.88,88.53 30.63,88.53 30.92,88.24 30.92,87.83 30.63,87.54 29.88,87.54 29.72,87.38 29.72,87.16 29.88,87 30.63,87 30.92,86.71 30.92,86.28 30.66,86.02 29.98,86.02 29.83,85.87 29.83,85.61 29.98,85.46 30.26,85.46 30.88,84.84 30.88,84.57 31.16,84.29 33.89,84.29 34.36,83.82 34.36,82.82 34.5,82.67 34.74,82.67 v1(34.93,82.86)
LPDDR4_DQS1_N: length 16.4
  TOP w0.203: U18.F1 v1(35.48,95.67) ; U26.E10 v1(35.58,88.47)
  L03_SIG01 w0.127: v1(35.58,88.47) 35.57,88.47 35.17,88.86 34.77,88.86 34.26,89.37 34.26,90.48 34.37,90.59 34.37,92.58 34.11,92.84 33.74,92.84 33.47,92.57 33.47,90.93 33.34,90.81 33.16,90.81 33.03,90.94 33.03,92.77 33.63,93.38 34.27,93.38 34.54,93.64 35.53,93.64 35.79,93.9 35.79,94.51 35.87,94.59 35.87,95.06 35.48,95.45 v1(35.48,95.67)
LPDDR4_DQS1_P: length 16.4
  TOP w0.203: v1(35.48,94.87) U18.G1 ; U26.D10 v1(34.93,88.47)
  L03_SIG01 w0.127: v1(35.48,94.87) 35.27,95.08 35.1,95.08 34.86,94.83 34.86,94.51 34.98,94.38 35.48,94.38 35.57,94.29 35.57,93.99 35.44,93.87 34.44,93.87 34.18,93.6 33.54,93.6 32.8,92.86 32.8,90.85 33.07,90.58 33.44,90.58 33.7,90.84 33.7,92.47 33.83,92.61 34.01,92.61 34.14,92.49 34.14,90.68 34.03,90.58 34.03,89.28 34.68,88.63 34.76,88.63 v1(34.93,88.47)
LPDDR4_DQS2_N: length 25.3
  TOP w0.203: U26.V3 v1(44.03,82.07) ; v1(41.48,93.9) 41.7,94.11 41.7,95.05 U18.P1
  L05_SIG02 w0.127: v1(41.48,93.9) 41.75,93.62 41.75,93.48 41.62,93.35 41.33,93.35 40.72,93.95 40.72,94.2 40.26,94.66 39.62,94.66 39.24,94.28 39.24,92.93 39.52,92.65 39.52,92.4 40,91.91 41.37,91.91 42.53,90.75 44.38,90.75 44.76,90.38 44.76,90.25 46.38,88.63 46.38,87.63 46.71,87.3 46.71,85.67 46.43,85.39 45.39,85.39 44.95,84.95 44.95,84.54 44.71,84.29 44.4,84.29 44,83.89 44,82.65 44.24,82.41 44.24,82.28 v1(44.03,82.07)
LPDDR4_DQS2_P: length 25.3
  TOP w0.203: v1(42.24,93.9) 42.04,94.1 42.04,95.02 U18.R1 ; U26.W3 v1(44.68,82.07)
  L05_SIG02 w0.127: v1(42.24,93.9) 41.98,93.63 41.98,93.38 41.72,93.12 41.23,93.12 40.5,93.86 40.5,94.1 40.17,94.43 39.72,94.43 39.47,94.18 39.47,93.02 39.75,92.75 39.75,92.49 40.1,92.14 41.46,92.14 42.62,90.98 44.47,90.98 44.98,90.47 44.98,90.35 46.61,88.73 46.61,87.72 46.94,87.39 46.94,85.57 46.53,85.16 45.48,85.16 45.18,84.85 45.18,84.44 44.8,84.06 44.5,84.06 44.23,83.8 44.23,82.75 44.47,82.51 44.47,82.28 v1(44.68,82.07)
LPDDR4_DQS3_N: length 19.6
  TOP w0.203: U18.Y1 v1(45.88,95.67) ; v1(44.03,87.67) U26.V10
  L03_SIG01 w0.127: v1(45.88,95.67) 45.48,95.27 45.48,94.78 45.35,94.65 44.78,94.65 44.19,95.25 42.68,95.25 42.33,94.9 42.33,94.41 42.83,93.91 42.83,93.57 42.7,93.45 42.24,93.45 41.98,93.19 41.98,92.72 42.38,92.33 43.54,92.33 44.41,91.45 44.82,91.45 45.6,92.23 45.82,92.23 45.99,92.06 45.99,91.8 45.57,91.38 45.57,90.97 46.21,90.33 46.21,89.68 44.92,88.39 44.58,88.39 44.31,88.12 44.31,87.95 v1(44.03,87.67)
LPDDR4_DQS3_P: length 19.6
  TOP w0.203: v1(44.68,87.67) U26.W10 ; U18.W1 v1(45.88,94.86)
  L03_SIG01 w0.127: v1(45.88,94.86) 46.18,94.86 46.3,94.74 46.3,94.56 46.17,94.43 44.69,94.43 44.1,95.02 42.77,95.02 42.56,94.8 42.56,94.51 43.06,94.01 43.06,93.48 42.79,93.22 42.34,93.22 42.21,93.09 42.21,92.82 42.47,92.56 43.63,92.56 44.51,91.68 44.73,91.68 45.5,92.46 45.91,92.46 46.22,92.15 46.22,91.71 45.8,91.29 45.8,91.06 46.43,90.42 46.43,89.59 45.01,88.16 44.68,88.16 44.54,88.02 44.54,87.81 v1(44.68,87.67)
LPDDR4_ODT_CA_A: length 3.3
  TOP w0.267: U26.G2 v1(36.23,81.27)
  L10_SIG03 w0.14: v1(36.72,79.46) 36.72,79.97 36.62,80.08 36.62,80.36 36.72,80.46 36.72,80.78 v1(36.23,81.27)
  BOTTOM w0.267: R370.1 v1(36.72,79.46)
LPDDR4_ODT_CA_B: length 3.1
  TOP w0.267: U26.T2 v1(42.08,81.27)
  L10_SIG03 w0.14: v1(42.02,79.38) 42.02,79.38 42.02,80.74 42.08,80.8 v1(42.08,81.27)
  BOTTOM w0.267: R369.1 v1(42.02,79.38)
LPDDR4_RESET_N: length 16
  TOP w0.267: U26.T11 v1(42.73,89.26) ; U18.P6 v1(41.08,98.87)
  BOTTOM w0.114: v1(41.08,98.87) 40.68,98.47 39.96,98.47 39.76,98.27
  BOTTOM w0.267: v1(42.73,89.26) 42.73,89.18 43.12,88.79 43.6,88.79 43.96,89.15 43.96,89.58 43.77,89.77 43.77,90.58 43.52,90.84 42.64,90.84 42.4,91.08 R352.1 R350.2 41.79,92.6 40.7,93.69 40.7,94.11 39.76,95.05 39.76,98.27
LPDDR4_ZQ0: length 1.4
  TOP w0.267: U26.A5 32.54,84.18 32.01,84.18 31.89,84.07 R122.2
LPDDR4_ZQ1: length 1.3
  TOP w0.267: U26.A8 R119.2
M2_LED1#: length 2.1
  TOP w0.14: J2.6 v1(8.97,135.79)
  BOTTOM w0.14: TP95.1 v1(8.97,135.79)
M2_LED2#: length 2.1
  TOP w0.14: J2.16 v1(8.97,138.29)
  BOTTOM w0.14: TP92.1 v1(8.97,138.29)
MCASP1_ACLKX_AUD: length 123.6
  TOP w0.14: TP56.1 v1(72.16,52.41)
  L05_SIG02 w0.102: v1(45.46,140.63) 45.23,140.86 45.23,142.03 47.34,144.14 47.34,144.65 48.55,145.86 58.34,145.86 59.62,144.58 61.09,144.58 68.88,136.79 68.88,132.82 70.46,131.25 70.46,118.47 69.45,117.46 69.45,103.37 67.82,101.74 67.82,80.16 69.66,78.32 69.66,54.61 71.87,52.41 v1(72.16,52.41)
  BOTTOM w0.14: U88.38 v1(72.16,52.41) ; v1(45.46,140.63) 44.34,140.63 43.74,140.04 U52.3
MCASP1_ACLKX_BT: length 42.4
  TOP w0.14: v1(12.32,136.5) 12.05,136.5 11.83,136.29 J2.8
  L10_SIG03 w0.102: v1(48.36,140.49) 47.63,141.22 44.65,141.22 41.46,138.02 35.96,138.02 33.61,135.68 25.86,135.68 24.69,136.84 12.66,136.84 v1(12.32,136.5)
  BOTTOM w0.14: v1(48.36,140.49) 48.45,140.58 48.45,140.89 48.24,141.1 U51.5
MCASP1_ACLKX_BUF: length 36.5
  TOP w0.132: U18.L19 v1(38.68,110.06)
  BOTTOM w0.14: U51.7 46.09,141.1 46,141.19 44.35,141.19 43.09,139.93 U52.4 43.09,137.92 42.65,137.48 42.65,137.13 40.91,135.39 40.91,126.26 40.71,126.07 40.71,119.06 40.41,118.76 40.41,115.23 39.25,114.06 39.25,110.63 v1(38.68,110.06)
MCASP1_ACLKX_HDMI: length 39.8
  TOP w0.14: v1(21.42,123.46) 20.69,122.74 U13.45
  L05_SIG02 w0.102: v1(44.39,140.04) 43.53,139.17 34.33,139.17 31.68,136.53 24.65,136.53 20.5,132.38 20.5,127.52 21.87,126.15 21.87,123.91 v1(21.42,123.46)
  BOTTOM w0.14: U52.2 v1(44.39,140.04)
MCASP1_AFSX_AUD: length 134.4
  TOP w0.14: TP52.1 72.65,53.38 v1(72.49,53.54)
  L05_SIG02 w0.102: v1(72.49,53.54) 70.59,55.44 70.59,78.95 69.94,79.59 69.94,87.2 70.59,87.85 70.59,101.79 71.65,102.84 71.65,117.61 73.27,119.23 73.27,136.63 71.95,137.95 70.58,137.95 69.87,138.66 69.87,139.3 68.75,140.42 68.14,140.42 67.56,141 67.56,141.61 66.97,142.19 66.47,142.19 61.9,146.76 59.38,146.76 58.72,147.42 46.87,147.42 44.02,144.57 40.44,144.57 39.81,143.94 39.81,142.03 v1(41.79,140.05)
  BOTTOM w0.14: v1(72.49,53.54) 72.49,53.15 72.48,53.14 72.48,52.89 72.66,52.71 U88.39 ; U52.6 v1(41.79,140.05)
MCASP1_AFSX_BT: length 42.7
  TOP w0.14: J2.10 v1(11.42,136.79)
  L10_SIG03 w0.102: v1(11.42,136.79) 11.7,137.07 24.97,137.07 26.11,135.93 33.47,135.93 35.91,138.37 41.3,138.37 44.39,141.47 48.86,141.47 v1(48.96,141.37)
  BOTTOM w0.14: v1(48.96,141.37) 48.83,141.5 U51.4
MCASP1_AFSX_BUF: length 49.3
  TOP w0.132: U18.R18 v1(42.68,109.26)
  TOP w0.14: v1(46.21,135.46) 46.21,136.28 46.04,136.45 46.04,137.3 45.45,137.89 45.45,139.76 44.12,141.09 41.92,141.09 v1(40.91,140.08)
  BOTTOM w0.14: U51.8 42.33,141.5 v1(40.91,140.08) 41.14,139.85 U52.7 ; v1(46.21,135.46) 48.64,133.02 48.64,127.52 47.39,126.26 45.46,126.26 44.6,125.41 44.6,124.17 43.08,122.64 43.08,109.66 v1(42.68,109.26)
MCASP1_AFSX_HDMI: length 43.6
  TOP w0.14: U13.44 21.19,122.63 21.51,122.94 22.01,122.94 v1(22.31,123.24)
  L05_SIG02 w0.102: v1(42.44,140.59) 44.5,140.59 44.82,140.28 44.82,139.54 44.02,138.74 35.06,138.74 32.5,136.19 24.98,136.19 20.81,132.01 20.81,127.62 22.31,126.12 v1(22.31,123.24)
  BOTTOM w0.14: U52.5 v1(42.44,140.59)
MCASP1_AXR0_AUD: length 126.1
  TOP w0.14: TP57.1 v1(73.16,52.41)
  L05_SIG02 w0.102: v1(41.14,143.09) 41.74,143.69 44.26,143.69 47.53,146.96 58.23,146.96 59.16,146.03 60.42,146.03 66.17,140.28 66.94,140.28 68.23,138.99 68.23,137.95 69.8,136.38 69.8,132.61 70.75,131.66 70.75,128.4 70.75,118.21 69.87,117.33 69.87,103.38 68.11,101.62 68.11,80.29 70,78.41 70,54.79 71.94,52.85 72.72,52.85 v1(73.16,52.41)
  BOTTOM w0.14: U88.40 v1(73.16,52.41) ; U52.10 v1(41.14,143.09)
MCASP1_AXR0_BT: length 46.1
  TOP w0.14: v1(13.68,138.31) 12.66,137.29 J2.12
  L10_SIG03 w0.102: v1(49.39,142.87) 49.35,142.91 47.04,142.91 46.72,142.59 43.72,142.59 41.86,140.73 40.21,140.73 38.72,139.24 35.64,139.24 32.87,136.46 26.62,136.46 25.55,137.53 17.92,137.53 17.04,138.41 16.64,138.41 16.17,137.94 15.06,137.94 14.68,138.31 v1(13.68,138.31)
  BOTTOM w0.14: U51.3 49.03,141.9 49.04,141.9 R256.2 49.63,142.67 49.43,142.87 v1(49.39,142.87)
MCASP1_AXR0_BUF: length 47.7
  TOP w0.132: U18.K19 v1(37.88,110.06)
  BOTTOM w0.14: U51.9 42.08,141.9 41.87,141.68 41.28,141.68 40.49,142.47 U52.9 40.22,144.38 40,144.16 40,142.07 38.24,140.31 38.24,136.69 36.6,135.05 36.6,132.27 35.92,131.59 35.92,124.42 37.88,122.46 37.88,115.85 36.72,114.68 36.72,112.78 36.68,112.75 36.68,110.64 36.86,110.46 37.48,110.46 v1(37.88,110.06)
MCASP1_AXR0_HDMI: length 44
  TOP w0.14: v1(23.3,123.27) 22.69,122.66 U13.41
  L05_SIG02 w0.102: v1(41.5,142.18) 43.33,142.18 45.12,140.4 45.12,139.43 43.92,138.24 35.02,138.24 32.52,135.73 25.46,135.73 23.05,133.32 23.05,123.53 v1(23.3,123.27)
  BOTTOM w0.14: v1(41.5,142.18) 41.79,142.48 U52.11
MCASP1_AXR2: length 13.1
  TOP w0.132: U18.L18 v1(38.68,109.26)
  TOP w0.14: v1(41.71,117.16) 41.11,117.76 R52.2 R51.2
  BOTTOM w0.14: v1(38.68,109.26) 39.08,109.67 41.25,109.67 41.48,109.9 41.48,116.93 v1(41.71,117.16)
MCASP1_AXR2_AUD: length 131.3
  TOP w0.14: TP51.1 73.17,54.25 v1(73.18,54.24)
  L05_SIG02 w0.102: v1(73.18,54.24) 73.18,53.49 72.8,53.11 72.17,53.11 70.28,55 70.28,78.65 68.35,80.59 68.35,101.47 70.28,103.4 70.28,109.96 70.9,110.59 70.9,117.37 71.82,118.29 71.82,131.47 71.06,132.24 71.06,135.71 68.65,138.12 68.65,139.26 67.4,140.51 66.56,140.51 60.73,146.34 59.31,146.34 58.46,147.19 47.2,147.19 44.05,144.03 40.98,144.03 40.71,143.77 40.71,142.92 40.95,142.68 42.88,142.68 v1(43.27,143.07)
  BOTTOM w0.14: v1(43.27,143.07) 43.09,143.24 U52.13 ; R404.1 v1(73.18,54.24)
MCASP1_AXR2_BT: length 42.6
  TOP w0.14: J2.14 v1(11.42,137.79)
  L10_SIG03 w0.102: v1(11.42,137.79) 11.91,137.3 25.25,137.3 26.34,136.21 33.26,136.21 35.8,138.75 41.22,138.75 44.19,141.71 48.01,141.71 48.67,142.38 v1(48.79,142.38)
  BOTTOM w0.14: U51.2 48.59,142.3 48.67,142.38 v1(48.79,142.38)
MCASP1_AXR2_BUF: length 33.8
  TOP w0.14: R51.1 v1(39.81,118.99) ; v1(39.6,140.78) 39.6,141.22 41.01,142.63 41.93,142.63 v1(42.44,143.15)
  BOTTOM w0.14: U51.10 43.3,142.3 v1(42.44,143.15) U52.12 ; v1(39.81,118.99) 40.26,119.44 40.26,124.98 38.46,126.79 38.46,135.22 38.84,135.6 38.84,140.02 v1(39.6,140.78)
MCASP1_BUF_BT_EN: length 128.6
  TOP w0.14: v1(49.24,143.62) 48.85,143.23 R19.1
  L05_SIG02 w0.102: v1(57.8,43.11) 58.18,42.73 60.93,42.73 61.52,43.32 63.31,43.32 66.83,46.84 66.83,50.08 68.71,51.96 68.71,53.94 69.29,54.53 69.29,78.17 67.59,79.88 67.59,101.89 69.09,103.39 69.09,117.67 70.22,118.79 70.22,130.99 68.55,132.66 68.55,136.18 60.96,143.78 59.08,143.78 58.26,144.59 50.21,144.59 v1(49.24,143.62)
  BOTTOM w0.14: U92.20 v1(57.8,43.11)
MCASP1_BUF_BT_EN_1V8: length 2.7
  TOP w0.14: v1(47.39,143.39) 47.32,143.47 R18.2 47.66,144.07 48.02,143.71 R19.2
  BOTTOM w0.14: U51.12 v1(47.39,143.39)
MCASP1_FET_EN: length 133.8
  L05_SIG02 w0.102: v1(50.7,142.99) 54.98,142.99 56.96,141.01 61.97,141.01 67.69,135.28 67.69,128.4 68.77,127.32 68.77,103.42 67.16,101.81 67.16,98.6 66.45,97.88 66.45,91.24 67.36,90.34 67.36,79.24 68.99,77.61 68.99,54.55 68.46,54.01 68.46,52.06 66.55,50.15 66.55,46.88 63.25,43.59 61.41,43.59 60.93,43.11 v1(58.72,43.11)
  BOTTOM w0.14: U92.19 58.22,43.61 v1(58.72,43.11) ; U52.15 44.39,145.42 44.27,145.55 R253.2 R252.1 45.97,145.96 46.33,146.32 48.73,146.32 49.83,145.21 49.83,143.86 v1(50.7,142.99)
MCASP1_FET_SEL: length 145.6
  TOP w0.132: R168.1 63.79,47.65 63.8,47.65 J12.1
  L03_SIG01 w0.102: J12.1 63.92,46.67 61.01,46.67 60.07,45.73 60.07,42.66 59.52,42.11 v1(58.72,42.11)
  L05_SIG02 w0.102: v1(58.72,42.11) 58.33,41.72 57.43,41.72 57.13,42.03 57.13,43.19 57.55,43.61 58.89,43.61 59.44,44.16 62.05,44.16 62.41,44.51 63.86,44.51 66.32,46.98 66.32,50.25 68.2,52.13 68.2,54.08 68.68,54.57 68.68,77.33 67.13,78.89 67.13,90.24 66.22,91.15 66.22,98.11 66.94,98.82 66.94,101.91 67.95,102.92 67.95,104.48 67.72,104.71 67.72,105.53 68.1,105.91 68.1,109.67 67.79,109.98 67.79,127.4 67.41,127.78 67.41,135.03 61.96,140.48 55.88,140.48 55.42,140.01 53.16,140.01 50.93,137.78 46.9,137.78 v1(46.22,138.46)
  BOTTOM w0.14: U92.21 58.22,42.61 v1(58.72,42.11) ; U52.1 45.89,138.78 v1(46.22,138.46)
MCU_GPIO0_15: length 37.3
  TOP w0.14: R89.2 21.84,99.84 21.99,99.69 v1(21.99,99.31)
  L05_SIG02 w0.102: J8.10 23.48,65.74 23.48,70.33 23.29,70.53 23.29,83.21 21.84,84.67 21.84,89.24 22.13,89.52 22.13,94.35 21.9,94.57 21.9,95.97 22.51,96.58 22.51,98.79 v1(21.99,99.31)
MCU_GPIO0_15_R: length 17
  TOP w0.132: U18.D7 v1(33.08,99.67)
  TOP w0.14: v1(22.49,100.08) 22.18,100.4 R89.1 R88.2
  BOTTOM w0.14: v1(22.49,100.08) 22.49,100.53 22.74,100.78 26.07,100.78 26.79,100.06 26.79,99.52 28.65,97.67 32.48,97.67 32.68,97.87 32.68,99.27 v1(33.08,99.67)
MCU_GPIO0_16: length 1.6
  BOTTOM w0.14: R573.2 J8.11
MCU_I2C0_SCL: length 86.6
  TOP w0.132: U18.E12 v1(33.88,104.46) ; v1(13.61,81.54) U27.32
  L05_SIG02 w0.102: J8.24 41.13,63.64 34.04,63.64 33.53,64.15 33.53,65.3 32.7,66.13 30.87,66.13 30.73,66.26 29.59,66.26 29.09,66.76 29.09,71.08 26.58,73.58 v1(26.58,76.44)
  L10_SIG03 w0.102: v1(33.88,104.46) 33.88,103.59 34.28,103.19 34.28,102.7 34.05,102.47 30.3,102.47 29.06,101.23 27.83,101.23 26.82,100.22 25.89,100.22 25.04,99.37 25.04,98.24 24.72,97.93 24.72,96.45 24.19,95.92 24.19,94.89 24.44,94.64 24.44,87.93 23.69,87.19 23.69,77.1 22.68,76.09 v1(22.68,74.69)
  BOTTOM w0.14: R388.2 J8.24 ; v1(26.58,76.44) 26.22,76.44 24.46,74.69 v1(22.68,74.69) 21.11,76.26 19.56,76.26 18.9,76.92 18.34,76.92 18.06,77.2 18.06,77.56 17.8,77.82 17.27,77.82 17.04,78.05 17.04,78.43 16.71,78.76 13.64,78.76 13.06,79.34 13.06,80.99 v1(13.61,81.54)
MCU_I2C0_SDA: length 99.2
  TOP w0.132: U18.D9 v1(33.08,101.26)
  TOP w0.14: R137.2 19.5,66.84 v1(19.4,66.94) ; U27.33 12.42,81.04 v1(12.09,81.37)
  L05_SIG02 w0.102: v1(26.04,74.49) 26.04,73.81 28.86,70.99 28.86,66.67 29.5,66.03 30.63,66.03 30.76,65.9 32.54,65.9 33.26,65.18 33.26,64.06 33.89,63.44 34.12,63.44 38.49,63.44 J8.21
  L10_SIG03 w0.102: v1(26.04,74.49) 25.61,74.92 25.61,76.85 24.74,77.72 24.74,82.55 26.16,83.97 26.16,96.17 26.54,96.55 27.2,96.55 29.44,98.79 29.44,99.53 30.77,100.86 32.5,100.86 32.9,101.26 v1(33.08,101.26) ; v1(12.09,81.37) 12.07,81.34 11.3,81.34 10.9,80.94 10.9,76.21 12.46,74.65 12.46,68.05 14.04,66.47 18.93,66.47 v1(19.4,66.94)
  BOTTOM w0.14: J8.21 39.71,62.21 R391.2 ; v1(12.09,81.37) 12.12,81.37 12.61,80.88 12.61,79.25 14.04,77.82 16.7,77.82 17.03,77.49 17.03,77.23 17.35,76.91 17.93,76.91 18.29,76.54 18.83,76.54 19.55,75.82 20.94,75.82 22.48,74.28 25.22,74.28 25.42,74.49 v1(26.04,74.49)
MCU_INTN: length 36
  TOP w0.132: U18.E11 v1(33.88,102.87)
  TOP w0.14: R123.1 27.15,83.58 27.48,83.25 27.48,82.42 v1(27.69,82.21)
  L10_SIG03 w0.102: v1(23.46,100.32) 24.43,100.32 24.71,100.59 26.46,100.59 28.17,102.3 28.6,102.3 29.22,102.91 30.95,102.91 31.3,103.27 33.48,103.27 v1(33.88,102.87)
  BOTTOM w0.14: v1(27.69,82.21) 27.69,90.56 26.98,91.27 26.98,95.21 27.46,95.69 27.46,98.14 26.38,99.22 26.38,99.91 25.97,100.32 v1(23.46,100.32)
MCU_MCAN0_RX: length 48.8
  TOP w0.132: U18.E8 v1(33.88,100.47)
  L03_SIG01 w0.102: J8.22 38.45,66.02 38.45,70.77 v1(38.69,71.01)
  L10_SIG03 w0.102: v1(33.88,100.47) 33.48,100.06 33.48,99.5 33.25,99.27 32.92,99.27 32.68,99.03 32.68,98.65 32.5,98.47 30.5,98.47 26.92,94.89 26.92,82.2 27.63,81.49 27.63,77.29 28.84,76.08 29.33,76.08 34.4,71.01 v1(38.69,71.01)
MCU_MCAN0_TX: length 46.1
  TOP w0.132: U18.C7 v1(32.28,99.67)
  L05_SIG02 w0.102: J8.16 31.35,65.49 30.76,65.49 30.45,65.81 29.39,65.81 28.35,66.85 28.35,69.65 24.48,73.52 24.48,91.55 24.72,91.78 24.72,94.89 25.87,96.05 25.87,98.32 26.59,99.04 29.15,99.04 30.17,100.07 31.88,100.07 v1(32.28,99.67)
MCU_OSC0_XI: length 5.3
  TOP w0.14: U18.A12 30.35,104.8 27.68,104.8 27.39,105.09 R69.2
MCU_OSC0_XO: length 5.3
  TOP w0.14: R74.2 R77.2 27.14,104.04 27.49,103.69 30.08,103.69 30.5,103.26 U18.A11
MCU_PORZ: length 89.9
  TOP w0.132: U18.A7 v1(30.68,99.67)
  TOP w0.14: TP69.1 56.48,38.62 v1(57.14,38.62) 57.14,38.22 R184.1
  L05_SIG02 w0.102: v1(57.14,38.62) 56.69,38.62 54.35,40.96 52.92,40.96 51.75,42.13 51.75,44.31 49.88,46.18 49.88,50.18 48.77,51.29 48.77,68.09 38.92,77.94 31.35,77.94 30.49,78.8 28.1,78.8 26.9,80 25.92,80 25.55,80.37 25.55,81.39 24.72,82.22 24.72,91.21 25,91.49 25,94.8 26.1,95.91 26.1,98.23 26.69,98.81 29.39,98.81 30.25,99.67 v1(30.68,99.67)
  BOTTOM w0.14: v1(57.14,38.62) 57.01,38.49 R454.2 U96.4
MCU_RESETSTATZ: length 74.5
  TOP w0.132: U18.D14 v1(33.08,106.07)
  TOP w0.14: J8.23 42.25,61.3 TP45.1
  L05_SIG02 w0.102: v1(33.08,106.07) U18.D14 33.48,104.04 32.68,103.24 32.68,102.67 32.48,102.47 30.51,102.47 29.65,101.6 29.18,101.6 28.83,101.26 27.66,101.26 26.96,100.56 25.77,100.56 23.92,98.7 23.92,97.23 23.47,96.79 23.47,95.59 23.22,95.35 22.55,95.35 22.38,95.18 22.38,94.8 22.6,94.58 23.09,94.58 23.28,94.39 23.28,92.07 23.76,91.59 23.76,71.23 26.19,68.8 26.19,66.41 26.75,65.85 27.64,65.85 28.12,65.37 28.12,64.1 28.86,63.36 32.54,63.36 33.2,62.7 33.2,60.44 33.52,60.12 33.9,60.12 34.88,61.1 41.3,61.1 42.25,62.04 J8.23
MCU_RESETZ: length 127.7
  TOP w0.132: U18.C12 v1(32.28,104.46)
  TOP w0.14: v1(38.72,24.11) 38.98,24.37 TP80.1
  L03_SIG01 w0.102: v1(23.77,22.71) 23.77,24.36 22.78,25.34 22.78,33.13 23.86,34.21 23.86,39.79 22.41,41.24 22.41,48.33 22.74,48.67 22.74,49.81 23.21,50.28 23.21,51.2 23.95,51.94 23.95,52.74 22.63,54.06 22.63,56.44 21.08,57.99 20.16,57.99 18.08,60.08 18.08,64.98 18.36,65.26 18.36,72.47 17.14,73.69 17.14,74.6 15.99,75.75 13.58,75.75 12.57,76.76 11.06,76.76 10.58,77.25 10.58,80.5 10.58,83.03 12.89,85.34 12.89,88.39 14.54,90.04 15.21,90.04 16.36,91.19 17.5,91.19 17.68,91.37 17.68,94.97 18.8,96.09 18.8,100.43 19.16,100.79 21.63,100.79 v1(22.51,101.66)
  L05_SIG02 w0.102: v1(22.51,101.66) 23.01,101.66 24.9,103.55 28.7,103.55 29.02,103.23 30.64,103.23 31,103.58 31.77,103.58 32.28,104.09 v1(32.28,104.46)
  L10_SIG03 w0.102: v1(23.77,22.71) 24.34,23.28 28.76,23.28 29.33,23.84 38.45,23.84 v1(38.72,24.11)
  BOTTOM w0.14: v1(38.72,24.11) 38.72,23.76 38.85,23.63 R505.2 39.34,23.24 39.49,23.09 U108.7
MCU_SAFETY_ERRORZ_1V8: length 48.6
  TOP w0.132: U18.B8 v1(31.48,100.47)
  TOP w0.14: v1(22.29,126.72) 24.95,126.72 25.61,126.06 26.63,126.06 27,126.43 31.77,126.43 32.13,126.06 TP9.1 31.87,125.13 31.5,125.13 31.38,125.02 U10.3
  BOTTOM w0.14: v1(31.48,100.47) 30.6,100.47 29.81,101.25 27.42,101.25 26.64,102.04 24.83,102.04 24.07,102.8 24.07,103.74 22.34,105.47 22.34,109.2 23.09,109.95 23.09,114.07 22.76,114.4 22.29,114.4 22.01,114.68 22.01,117.37 22.24,117.6 22.86,117.6 23.36,118.1 23.36,120.52 23.46,120.62 23.46,122 22.82,122.63 22.82,126.19 v1(22.29,126.72)
MCU_SAFETY_ERRORZ_3V3: length 124.3
  TOP w0.132: v1(18.71,83.17) 18.71,83.77 U27.18
  TOP w0.14: U10.6 28.09,125.02 27.9,125.21 27.33,125.21 v1(26.88,125.67)
  L03_SIG01 w0.102: v1(26.88,125.67) 22.37,125.67 17.99,121.29 17.99,116.68 12.95,111.64 12.95,110.9 11.7,109.66 11.7,106.51 13.88,104.33 13.88,103.36 12.96,102.43 12.96,98.54 15.78,95.71 15.78,93.52 14.45,92.19 10.62,92.19 9.25,90.82 v1(9.25,87.49)
  L05_SIG02 w0.102: J8.26 43.47,63.44 43.47,61.32 42.89,60.73 35.73,60.73 34.58,59.59 19.74,59.59 18.13,61.2 18.13,65.63 18.45,65.95 18.45,67.68 19.48,68.72 19.48,70.5 18.85,71.13 18.85,73.8 19.6,74.55 19.6,76.57 19.13,77.04 19.13,82.78 18.74,83.17 v1(18.71,83.17)
  BOTTOM w0.14: v1(9.25,87.49) 10.13,87.49 14.85,82.77 18.31,82.77 v1(18.71,83.17)
MCU_SPI0_CLK: length 72.6
  TOP w0.132: U18.B13 v1(31.48,105.26)
  TOP w0.14: v1(32.63,60.61) 33.34,61.31 33.34,63.47 J8.18
  L05_SIG02 w0.102: v1(31.48,105.26) 31.48,105.17 30.91,104.6 29.43,104.6 29.16,104.32 23.48,104.32 21.82,102.66 21.29,102.66 20.71,102.07 20.71,101.1 19.6,100 19.6,89.28 20.45,88.43 20.45,74.89 21.06,74.28 21.06,71.03 20.68,70.65 20.68,67.71 20.15,67.18 20.15,66.2 20.64,65.71 20.64,61.58 22.09,60.14 32.16,60.14 v1(32.63,60.61)
MCU_SPI0_CS1: length 44.4
  L05_SIG02 w0.102: J8.8 21.93,66.24 22.8,67.11 22.8,70.57 21.92,71.44 21.92,74.89 21.25,75.57 21.25,95.09 21.6,95.43 21.6,99.79 24.4,102.6 25.52,102.6 v1(25.95,103.03)
  BOTTOM w0.14: R580.1 24.91,104.07 v1(25.95,103.03)
MCU_SPI0_CS1_R: length 9.1
  TOP w0.132: U18.C11 v1(32.28,102.87)
  BOTTOM w0.14: R581.2 26.08,105.72 27.09,104.7 30.44,104.7 v1(32.28,102.87)
MCU_SPI0_D0: length 59.4
  TOP w0.132: U18.A15 v1(30.68,106.86)
  TOP w0.14: v1(17.04,68.36) 17.31,68.09 18.51,68.09 18.83,67.77 18.83,65.32 J8.6
  L05_SIG02 w0.102: v1(30.68,106.86) 30.31,106.49 22.69,106.49 21.44,105.24 20.2,105.24 16.44,101.48 16.44,99.21 15.29,98.06 15.29,96.3 16.15,95.44 16.15,93 15.89,92.74 15.89,88.62 15.36,88.08 15.36,84.38 15.83,83.91 15.83,82.7 16.01,82.51 16.01,77.13 16.23,76.91 16.23,76.1 15.74,75.6 15.27,75.6 14.85,75.19 14.85,74.59 15.47,73.97 15.47,68.78 15.89,68.36 v1(17.04,68.36)
MCU_SPI0_D1: length 56
  TOP w0.132: U18.B12 v1(31.48,104.46)
  TOP w0.14: J8.4 17.99,63.62 20.21,63.62 20.59,64 v1(20.59,66.95)
  L05_SIG02 w0.102: v1(20.59,66.95) 20.98,67.35 20.98,70.52 21.36,70.91 21.36,74.49 20.75,75.1 20.75,88.56 19.95,89.36 19.95,96.58 20.45,97.07 20.45,100.33 21.02,100.9 21.02,101.94 21.36,102.28 21.87,102.28 23.6,104.01 29.02,104.01 29.31,103.73 30.42,103.73 31.16,104.46 v1(31.48,104.46)
MCU_UART0_CTS: length 78
  TOP w0.132: U18.B11 v1(31.48,102.87)
  TOP w0.14: U33.9 55.15,67.81 v1(54.5,68.46)
  L05_SIG02 w0.102: v1(25.31,66.41) 25.31,69.15 23.53,70.92 23.53,91.35 22.42,92.46 22.42,94.41 22.15,94.68 22.15,95.85 22.75,96.45 22.75,97.85 25.68,100.79 26.66,100.79 28.06,102.18 28.95,102.18 29.2,101.94 29.63,101.94 30.38,102.69 31.3,102.69 v1(31.48,102.87)
  L10_SIG03 w0.102: v1(54.5,68.46) 54,67.96 54,67.58 53.19,66.76 48.02,66.76 47.37,66.12 29.6,66.12 28.85,66.87 25.76,66.87 v1(25.31,66.41)
MCU_UART0_CTS_3V3: length 64.3
  TOP w0.14: U33.11 53.85,67.81 v1(53.2,68.46)
  L03_SIG01 w0.102: v1(53.2,68.46) 52.37,68.46 50.68,66.77 50.68,63.52 47.11,59.95 47.11,54.19 45.23,52.31 45.23,47.17 44.47,46.41 44.47,39.87 42.06,37.46 42.06,36.63 40.77,35.35 39.91,35.35 38.05,33.49 37.34,33.49 36.55,32.7 36.55,27.73 34.78,25.95 34.78,24.96 32.18,22.37 v1(32.18,19.29)
  BOTTOM w0.14: U110.9 30.41,19.15 30.64,18.92 31.21,18.92 31.57,19.29 v1(32.18,19.29)
MCU_UART0_CTS_CONN: length 30
  TOP w0.14: U33.10 v1(54.5,67.54)
  L10_SIG03 w0.102: v1(54.5,67.54) 53.41,66.46 48.03,66.46 47.44,65.86 28.11,65.86 J8.12
MCU_UART0_MUX_OE: length 3
  TOP w0.14: R141.1 50.86,64.72 51.25,65.11 U33.15
MCU_UART0_MUX_SEL: length 44.8
  TOP w0.14: v1(51.97,64.1) 50.7,64.1 49.56,62.96 R144.2 50.36,62.08 50.6,61.84 U33.1
  L03_SIG01 w0.102: v1(51.97,64.1) 51.97,65.37 53.04,66.43 55.91,66.43 58.24,68.77 61.95,68.77 63.35,67.37 63.35,66 70.82,58.54 75.26,58.54 76.38,57.41 76.53,57.41 76.57,57.46 J10.2
MCU_UART0_RTS: length 66
  TOP w0.132: U18.D10 v1(33.08,102.07)
  TOP w0.14: U33.12 v1(53.2,67.54)
  L10_SIG03 w0.102: v1(53.2,67.54) 51.16,69.58 29.92,69.58 24.48,75.02 24.48,86.52 25.3,87.34 25.3,93.47 25.88,94.04 25.88,96.84 26.55,97.52 27.17,97.52 28.56,98.91 28.56,99.89 30.34,101.67 32.68,101.67 v1(33.08,102.07)
MCU_UART0_RTS_3V3: length 59.5
  TOP w0.14: U33.14 51.9,67.4 v1(52.12,67.63)
  L03_SIG01 w0.102: v1(52.12,67.63) 50.93,66.43 50.93,63.37 47.41,59.85 47.41,54.06 45.46,52.11 45.46,47.02 44.74,46.31 44.74,39.74 42.29,37.29 42.29,36.06 39.04,32.8 39.04,28.84 35.87,25.67 35.87,25.44 33.8,23.38 33.8,20.48 v1(33.15,19.83)
  BOTTOM w0.14: U110.7 32.36,20.23 32.77,19.83 v1(33.15,19.83)
MCU_UART0_RTS_CONN: length 20.4
  TOP w0.14: U33.13 v1(52.55,64.83)
  L10_SIG03 w0.102: J8.17 36.03,63.62 50.6,63.62 51.81,64.83 v1(52.55,64.83)
MCU_UART0_RX_3V3: length 57.6
  TOP w0.14: U33.2 51.25,62.1 v1(51.92,62.78)
  L03_SIG01 w0.102: v1(51.92,62.78) 50.77,62.78 47.69,59.7 47.69,53.92 45.71,51.94 45.71,46.85 45,46.14 45,39.67 42.55,37.22 42.55,35.89 39.37,32.71 39.37,28.66 36.55,25.85 36.55,22.77 35.21,21.43 34.37,21.43 34.11,21.17 34.11,19.6 v1(33.83,19.32)
  BOTTOM w0.14: v1(33.83,19.32) 32.87,19.32 32.36,19.83 U110.8
MCU_UART0_RXD: length 69
  TOP w0.132: U18.D8 v1(33.08,100.47)
  TOP w0.14: U33.4 52.55,61.57 52.91,61.94 v1(52.91,62.78)
  L10_SIG03 w0.102: v1(33.08,100.47) 33.08,100.3 32.68,99.9 32.68,99.5 32.45,99.26 30.31,99.26 30.01,98.96 30.01,98.4 26.63,95.02 26.63,82.09 27.32,81.41 27.32,77.23 28.79,75.76 29.21,75.76 34.34,70.63 53.26,70.63 54.99,68.9 55.12,68.76 55.12,64.16 53.74,62.78 v1(52.91,62.78)
MCU_UART0_RXD_CONN: length 24.4
  TOP w0.14: v1(51.9,61.89) U33.3
  L10_SIG03 w0.102: J8.13 30.69,61.08 47.7,61.08 48.52,61.89 v1(51.9,61.89)
MCU_UART0_TX_3V3: length 55.2
  TOP w0.14: U33.5 v1(53.2,59.31)
  L03_SIG01 w0.102: v1(53.2,59.31) 52.07,60.44 49.58,60.44 47.92,58.78 47.92,53.77 45.93,51.79 45.93,46.75 45.23,46.05 45.23,39.58 42.8,37.15 42.8,35.82 39.7,32.72 39.7,28.41 36.81,25.52 36.81,22.44 35.36,20.99 v1(34.67,20.99)
  BOTTOM w0.14: v1(34.67,20.99) R523.2 32.46,20.99 32.1,20.63 U110.6
MCU_UART0_TXD: length 71.2
  TOP w0.132: U18.F8 v1(34.68,100.47)
  TOP w0.14: v1(53.95,63.67) 54.5,63.12 U33.7
  L10_SIG03 w0.102: v1(53.95,63.67) 54.89,64.61 54.89,68.67 53.18,70.38 34.21,70.38 29.08,75.5 28.59,75.5 25.56,78.53 25.56,83.01 26.4,83.86 26.4,95.25 29.72,98.57 29.72,99.39 30.39,100.07 32.4,100.07 32.45,100.07 32.68,100.3 32.68,100.59 32.68,100.63 32.91,100.86 34.28,100.86 v1(34.68,100.47)
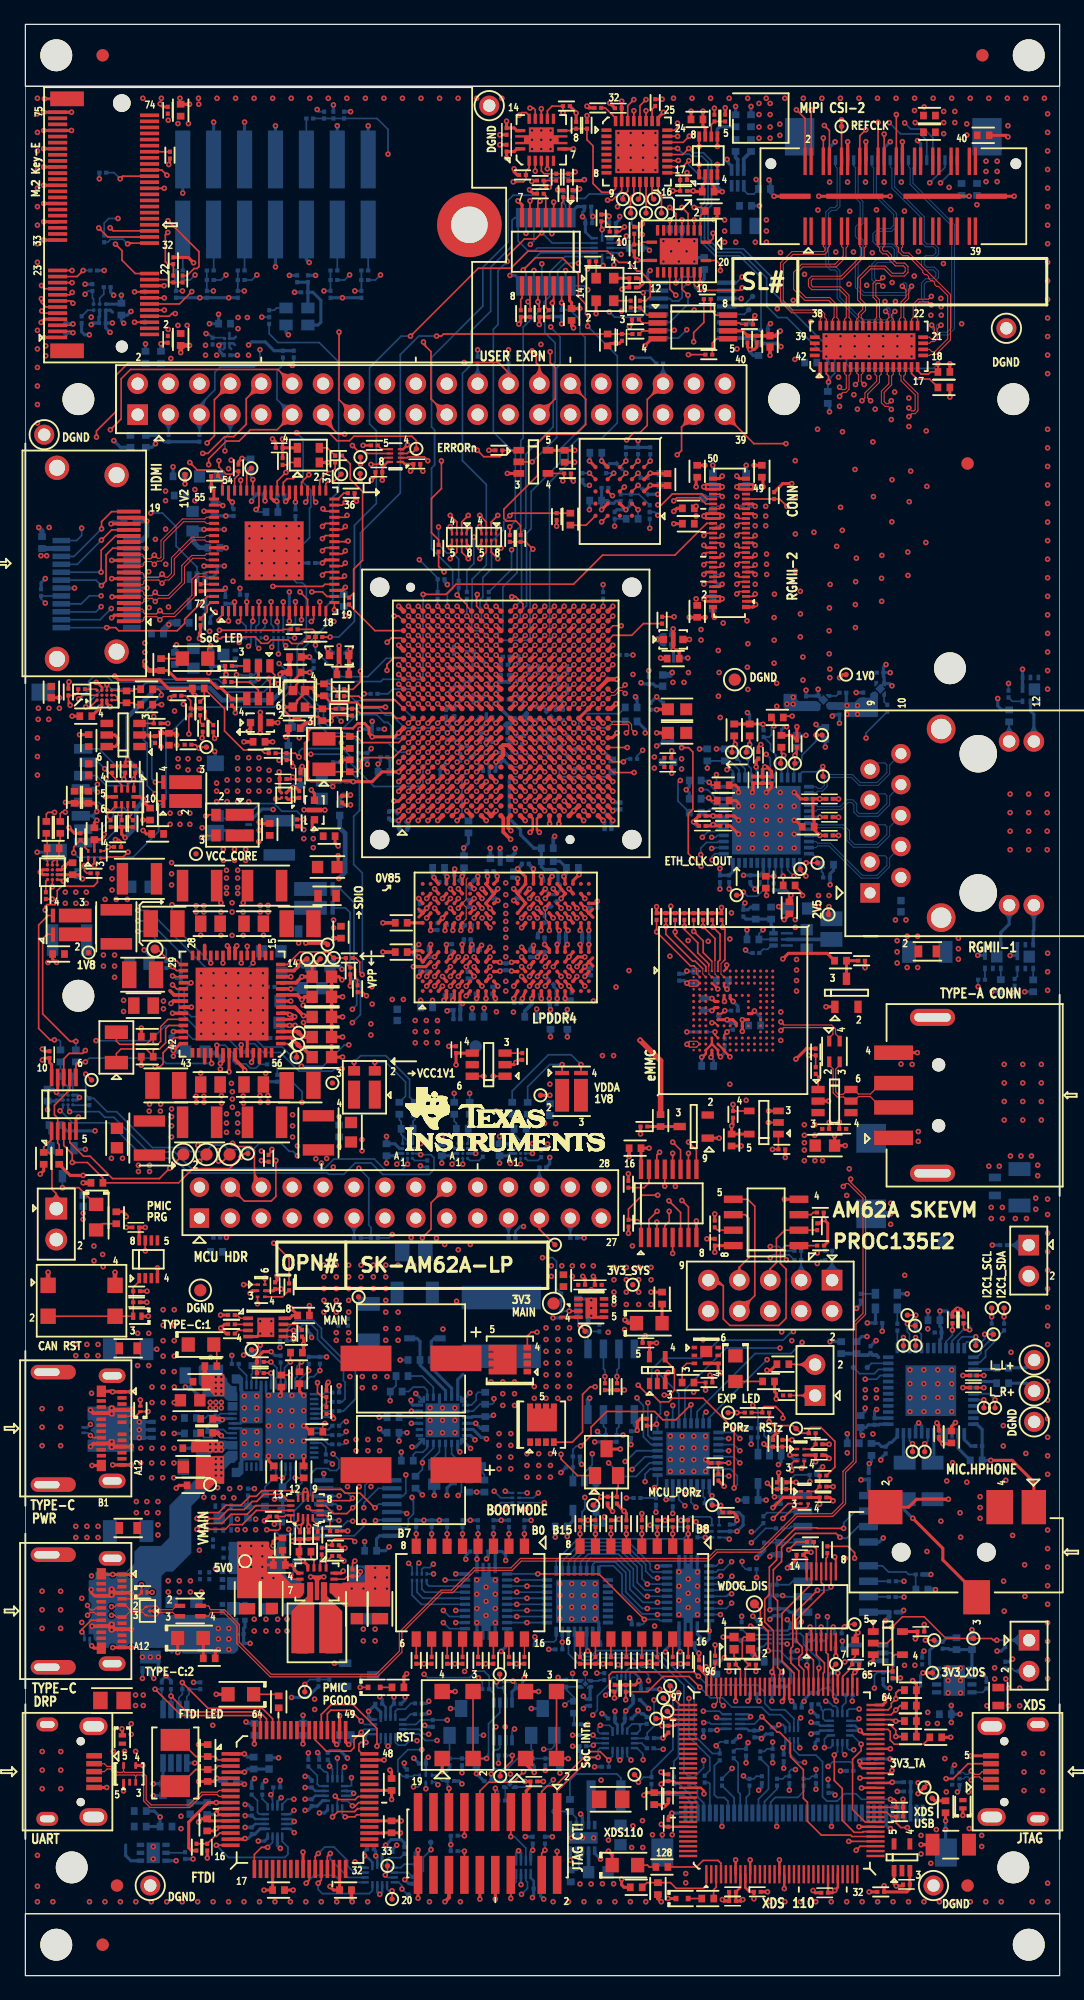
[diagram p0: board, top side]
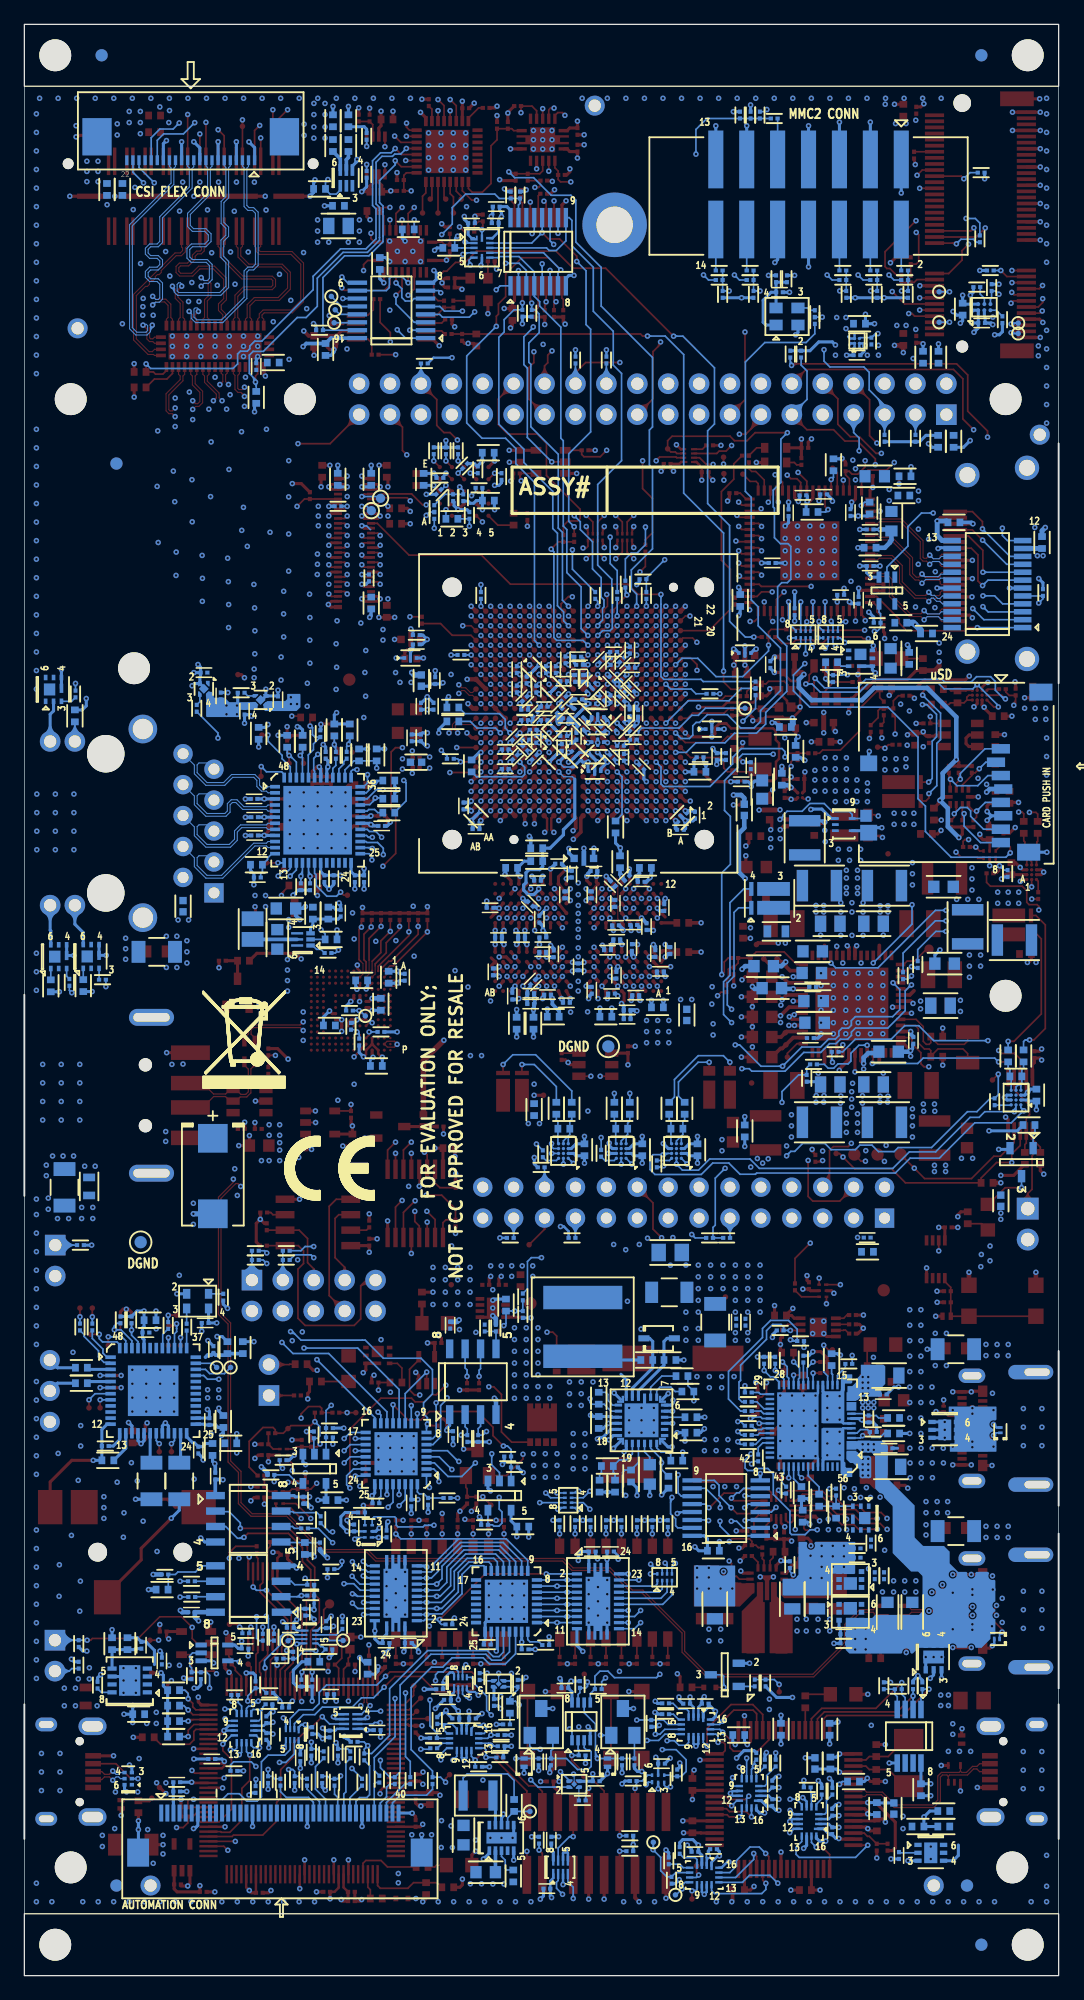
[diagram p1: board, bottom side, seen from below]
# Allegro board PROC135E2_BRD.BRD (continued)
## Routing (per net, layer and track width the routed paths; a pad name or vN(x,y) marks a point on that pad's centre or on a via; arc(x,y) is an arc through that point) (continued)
MCU_UART0_TXD_CONN: length 19.7
  TOP w0.14: U33.6 53.85,62.68 v1(52.89,63.64)
  L10_SIG03 w0.102: v1(52.89,63.64) 51.69,63.64 51.41,63.36 38.31,63.36 J8.19
MFP0: length 2.8
  TOP w0.14: R152.1 v1(76.19,53.02)
  BOTTOM w0.14: U88.45 75.66,52.07 76.19,52.6 v1(76.19,53.02) R152.1
MFP1: length 4.3
  TOP w0.14: R153.1 77.1,53.15 77.21,53.04 v1(77.61,53.04)
  BOTTOM w0.14: R153.1 77.38,53.58 77.61,53.35 v1(77.61,53.04) 77.07,53.04 76.16,52.14 U88.46
MFP2: length 2.9
  TOP w0.14: TP55.1 v1(78.11,52.47)
  BOTTOM w0.14: U88.47 76.66,52.14 76.99,52.47 v1(78.11,52.47)
MFP3: length 3.2
  TOP w0.14: TP54.1 v1(78.84,52.67)
  BOTTOM w0.14: U88.48 77.16,51.82 77.38,52.05 78.57,52.05 78.84,52.31 v1(78.84,52.67)
MIC_IN: length 10.5
  TOP w0.254: v1(79.34,42.32) 81.09,42.32 82.88,40.54 J14.1
  BOTTOM w0.254: U88.12 78.19,45.29 78.63,44.86 R437.1 C426.1 v1(79.34,42.32)
MMC0_CLK: length 29.6
  TOP w0.14: U28.M6 57.42,77.26 v1(57.67,77.51)
  L05_SIG02 w0.102: v1(57.67,77.51) 58.3,78.14 58.3,78.84 58.61,79.14 58.61,85.75 54.52,89.83 54.52,95.24 52.14,97.62 52.14,99.29 51.81,99.62 51.5,99.62 50.73,100.4 v1(50.73,100.64)
  BOTTOM w0.14: R371.1 57.85,77.69 v1(57.67,77.51) 57.48,77.32 R373.2 ; v1(50.73,100.64) 50.27,100.17 R343.1
MMC1_CLK: length 53.8
  TOP w0.14: R98.1 6.74,95.15 v1(6.74,95.64) 6.98,95.64 7.42,96.07 U22.6
  L05_SIG02 w0.102: v1(32.37,116.29) 30.22,118.44 16.82,118.44 16.62,118.24 11.56,118.24 8.79,115.47 8.79,107.61 7.5,106.31 7.5,104.1 7.04,103.65 7.04,95.93 v1(6.74,95.64)
  BOTTOM w0.14: R321.1 R315.1 33.88,114.78 v1(32.37,116.29) ; J22.5 6.03,96.36 v1(6.74,95.64)
MMC1_CLK_R: length 1.2
  TOP w0.132: U18.E22 v1(33.88,112.46)
  BOTTOM w0.14: R321.2 v1(33.88,112.46)
MMC1_CMD: length 55.6
  TOP w0.132: U18.C21 v1(32.28,111.66)
  TOP w0.14: U22.1 8.92,98.19 8.89,98.21 v1(8.89,98.26) 8.89,98.31 9.02,98.44 R90.1
  L05_SIG02 w0.102: v1(32.28,111.66) 31.88,112.06 27.34,112.06 26.99,112.41 26.99,112.94 26.86,113.07 26.61,113.07 26.48,113.21 26.48,113.4 26.61,113.53 26.86,113.53 26.99,113.66 26.99,114.31 26.8,114.5 25.69,114.5 25.57,114.62 25.57,115.01 25.45,115.12 25.22,115.12 25.1,115 25.1,114.62 24.98,114.5 23.82,114.5 23.7,114.62 23.7,114.97 23.58,115.09 23.33,115.09 23.19,114.96 23.19,114.66 23.07,114.53 19.62,114.53 19.47,114.38 19.47,114.03 19.35,113.91 19.18,113.91 19.06,114.03 19.06,114.38 18.94,114.5 18.78,114.5 18.66,114.38 18.66,114.03 18.54,113.91 18.37,113.91 18.25,114.03 18.25,114.51 17.78,114.98 15.67,114.98 14.72,114.02 14.53,114.02 13.89,114.65 13.7,114.65 13.57,114.52 13.57,114.33 14.2,113.69 14.2,113.5 13.11,112.41 13.11,112.22 13.49,111.83 13.49,111.61 13.29,111.41 13.15,111.41 12.7,111.86 12.56,111.86 12.2,111.5 12.2,110.7 11.97,110.47 11.15,110.47 11.02,110.33 11.02,110.11 11.12,110.01 11.35,110.01 11.45,109.91 11.45,109.68 11.35,109.58 10.69,109.58 10.59,109.49 10.59,109.15 10.71,109.03 11.08,109.03 11.2,108.91 11.2,108.74 11.08,108.63 10.71,108.63 10.59,108.51 10.59,107.67 8.74,105.82 8.74,100.09 8.89,99.94 v1(8.89,98.26)
  BOTTOM w0.14: v1(8.89,98.26) 8.36,97.73 6.65,97.73 5.82,98.56 J22.3
MMC1_D0: length 55.9
  TOP w0.132: U18.B22 v1(31.48,112.46)
  TOP w0.14: R100.1 8.58,95.14 v1(8.58,95.43) 8.58,95.48 8.42,95.64 U22.8
  L05_SIG02 w0.102: v1(8.58,95.43) 8.58,94.77 8.3,94.49 7.37,94.49 7.21,94.66 7.21,94.87 7.33,94.99 7.96,94.99 8.18,95.21 8.18,95.77 8.49,96.08 8.49,98.67 8,99.15 8,103.24 8.44,103.67 8.44,105.94 10.29,107.8 10.29,110.04 12.48,112.23 12.48,112.42 11.93,112.97 11.93,113.16 12.06,113.29 12.25,113.29 12.8,112.74 12.99,112.74 13.63,113.38 13.63,113.64 13.12,114.15 13.12,114.53 13.86,115.27 14.36,115.27 14.74,114.89 15.14,114.89 15.57,115.32 17.81,115.32 18.03,115.54 26.4,115.54 27.34,114.6 27.34,113.57 28.47,112.44 29.84,112.44 30.28,112.88 30.87,112.88 31.08,112.68 31.27,112.68 v1(31.48,112.46)
  BOTTOM w0.14: J22.7 6.17,94.16 7.23,95.21 7.23,95.66 7.51,95.94 8.07,95.94 v1(8.58,95.43)
MMC1_D1: length 56.3
  TOP w0.132: U18.D21 v1(33.08,111.66)
  TOP w0.14: 7.78,95.44 7.92,95.3 R99.1 ; 7.78,95.44 v1(7.77,95.44) ; 7.78,95.44 7.92,95.58 U22.7
  L05_SIG02 w0.102: v1(7.77,95.44) 7.37,95.84 7.37,96.27 7.57,96.47 7.57,96.72 7.37,96.93 7.37,97.24 7.58,97.45 7.58,97.69 7.37,97.91 7.37,103.54 7.81,103.98 7.81,106.18 9.1,107.47 9.1,113.64 11.08,115.63 11.08,116.07 12.75,117.74 16.66,117.74 16.97,117.44 29.93,117.44 33.06,114.31 33.06,113.19 32.68,112.8 32.68,112.06 v1(33.08,111.66)
  BOTTOM w0.14: v1(7.77,95.44) 7.77,94.4 6.42,93.06 J22.8
MMC1_D2: length 55.8
  TOP w0.132: U18.C22 v1(32.28,112.46)
  TOP w0.14: U22.2 8.42,97.92 v1(8.08,98.26) 8.21,98.39 R91.1
  L05_SIG02 w0.102: v1(32.28,112.46) 31.74,113 31.24,113 30.61,113.64 30.61,115.04 30.23,115.42 30.23,115.68 30.5,115.94 30.5,116.18 30.31,116.37 30.08,116.37 29.78,116.07 29.58,116.07 28.68,116.97 28.15,116.97 27.93,116.75 27.93,115.29 27.74,115.09 27.54,115.09 27.36,115.27 27.36,116.3 27.16,116.5 18.06,116.5 17.72,116.16 16.05,116.16 15.92,116.28 15.92,117.05 15.79,117.17 15.62,117.17 15.49,117.05 15.49,116.28 15.36,116.16 15.18,116.16 15.06,116.28 15.06,117.05 14.93,117.17 14.75,117.17 14.63,117.05 14.63,116.28 14.5,116.16 14.21,116.16 11.13,113.08 11.13,112.75 9.4,111.02 9.4,107.34 8.12,106.06 8.12,103.82 7.67,103.37 7.67,98.67 v1(8.08,98.26)
  BOTTOM w0.14: v1(8.08,98.26) 8.08,98.73 6.05,100.76 J22.1
MMC1_D3: length 57.4
  TOP w0.132: U18.D22 v1(33.08,112.47)
  TOP w0.14: U22.3 7.92,97.79 7.14,98.57 R92.1 6.86,98.79 v1(6.52,99.13)
  L05_SIG02 w0.102: v1(6.52,99.13) 6.52,104.7 6.23,104.99 6.23,109.4 8.44,111.6 8.44,116.53 11.28,119.38 11.93,119.38 12.06,119.25 12.06,118.89 12.2,118.76 12.39,118.76 12.52,118.89 12.52,119.25 12.66,119.38 12.84,119.38 12.98,119.25 12.98,118.89 13.11,118.76 13.3,118.76 13.44,118.89 13.44,119.25 13.57,119.38 16.74,119.38 16.86,119.5 26.93,119.5 27.06,119.37 27.06,119.18 27.19,119.05 27.36,119.05 27.49,119.18 27.49,119.37 27.62,119.5 27.8,119.5 27.92,119.37 27.92,119.18 28.05,119.05 28.23,119.05 28.35,119.18 28.35,119.37 28.48,119.5 29.92,119.5 32.82,116.6 32.82,114.99 33.37,114.44 33.37,113.01 33.08,112.72 v1(33.08,112.47)
  BOTTOM w0.14: v1(6.52,99.13) 5.99,99.66 J22.2
MMC1_SD_EN: length 107
  TOP w0.14: R106.1 5.92,89.79 5.61,89.47 2.99,89.47 2.62,89.1 2.62,88.15 2.43,87.96 1.77,87.96 1.63,87.82 v1(1.63,87.52)
  L05_SIG02 w0.102: v1(17.14,39.24) 16.45,38.55 14.49,38.55 12.77,40.27 12.77,53.51 12.37,53.91 10.95,53.91 10.24,54.62 6.65,54.62 1.38,59.89 1.38,63.83 2.26,64.71 2.26,71.46 1.68,72.05 1.68,74.08 2.09,74.49 2.09,76.44 1.44,77.08 1.44,87.33 v1(1.63,87.52)
  L10_SIG03 w0.102: v1(49.86,41.57) 45.59,41.57 44.96,42.2 44.96,42.42 44.14,43.25 41.06,43.25 40.57,42.75 40.57,42.72 39.96,42.12 39.85,42.12 39.4,41.67 39.4,41.55 38.82,40.98 38.77,40.98 37.62,39.83 37.62,39.71 36.3,38.39 30.27,38.39 29.92,38.05 20.8,38.05 19.89,38.96 17.42,38.96 v1(17.14,39.24)
  BOTTOM w0.14: U92.4 50.91,42.61 v1(49.86,41.57)
MMC1_SD_LS_EN: length 21.9
  TOP w0.14: v1(10.55,103.41) R79.1 U20.3 ; U24.4 6.49,92.37 v1(6.81,92.69) 6.82,92.7 R105.2
  L03_SIG01 w0.102: v1(10.55,103.41) 9.28,103.41 1.98,96.11 1.98,94.22 3.06,93.14 6.36,93.14 v1(6.81,92.69)
MMC1_SDCARD_EN: length 33.4
  TOP w0.14: R105.1 7.85,93.16 7.71,93.3 v1(7.4,93.3)
  L05_SIG02 w0.102: v1(5.81,76.79) 5.81,76.86 7.69,78.74 7.69,81.06 8.09,81.46 8.09,84.77 6.14,86.71 6.14,90.05 6.53,90.44 6.53,91.52 7.4,92.39 v1(7.4,93.3)
  BOTTOM w0.14: R374.1 17.74,75.87 16.7,76.91 13.76,76.91 12.65,78.02 11.49,78.02 10.27,76.79 v1(5.81,76.79)
MMC1_SDCD: length 32.5
  TOP w0.132: U18.E18 v1(33.88,109.26)
  TOP w0.14: R97.1 v1(22.9,94.96)
  L05_SIG02 w0.102: v1(33.88,109.26) 33.88,109.03 34.28,108.63 34.28,104.26 33.48,103.46 33.48,102.65 33.3,102.47 32.88,102.47 32.68,102.27 32.68,101.84 32.5,101.67 30.33,101.67 29.99,101.33 29.53,101.33 28.52,100.32 25.86,100.32 24.51,98.97 24.51,97.42 23.81,96.72 23.81,95.27 23.5,94.96 v1(22.9,94.96)
  BOTTOM w0.14: J22.9 16.06,95.03 U79.5 16.97,95.37 17.21,95.61 18.61,95.61 19.26,96.26 20.45,96.26 21.08,95.63 22.32,95.63 22.63,95.31 22.63,95.23 v1(22.9,94.96)
MMC2_CLK: length 63.2
  L05_SIG02 w0.102: v1(33.96,118.98) 29.71,123.22 27.08,123.22 26.62,122.76 21.52,122.76 20.98,123.3 20.98,124.36 18.28,127.06 18.28,131.45 20.04,133.21 20.04,133.83 23.16,136.95 26.35,136.95 28.62,139.21 28.62,140.35 29.81,141.54 v1(29.81,149.6)
  BOTTOM w0.14: R316.2 35.61,116.35 35.13,116.83 34.65,116.83 33.96,117.52 v1(33.96,118.98) ; R244.1 R243.2 R242.1 25.32,152.53 R241.1 28.9,152.53 29.81,151.62 v1(29.81,149.6)
MMC2_CMD: length 66.9
  TOP w0.132: U18.G22 v1(35.48,112.46)
  L05_SIG02 w0.102: v1(17.99,138.36) 17.99,138.87 18.18,139.05 19.86,139.05 19.96,139.15 19.96,141.17 20.09,141.31 20.5,141.31 20.64,141.44 20.64,141.63 20.5,141.76 20.09,141.76 19.96,141.9 19.96,142.15 19.86,142.25 19.58,142.25 19.44,142.11 19.44,140.31 19.31,140.17 19.12,140.17 18.98,140.31 18.98,142.13 18.85,142.25 18.67,142.25 18.53,142.11 18.53,139.61 18.39,139.47 18.2,139.47 18.07,139.61 18.07,142.13 17.94,142.25 17.68,142.25 17.55,142.13 17.55,137.16 16.97,136.58 16.97,134.67 17.11,134.53 17.81,134.53 17.94,134.4 17.94,134.21 17.81,134.07 17.11,134.07 16.97,133.94 16.97,133.06 15.73,131.81 15.73,127.42 16.5,126.64 17.8,126.64 20.35,124.09 20.35,122.98 21.2,122.13 29.64,122.13 34.21,117.56 34.21,116.1 35.07,115.24 35.07,113.17 35.48,112.77 v1(35.48,112.46)
  BOTTOM w0.14: v1(17.99,138.36) R275.1 R267.2 R259.2
MMC2_D0: length 67.3
  TOP w0.132: U18.E20 v1(33.88,110.86)
  L05_SIG02 w0.102: v1(33.88,110.86) 33.48,111.26 33.48,112.69 33.67,112.88 33.67,114.62 33.19,115.1 33.19,117.03 29.71,120.52 25.36,120.52 24.89,120.05 20.95,120.05 20.17,120.83 20.17,121.74 19.3,122.61 19.3,123.85 17.52,125.63 15.99,125.63 15.24,126.38 13.87,126.38 12.88,127.37 12.88,131.71 13.97,132.79 13.97,135.9 13.51,136.36 13.51,136.53 13.88,136.9 13.88,137.07 13.76,137.19 13.59,137.19 13.22,136.82 13.05,136.82 12.93,136.94 12.93,137.1 13.31,137.48 13.31,137.65 13.19,137.77 13.02,137.77 12.64,137.39 12.48,137.39 12.25,137.61 12.25,139.03 12.01,139.27 10.48,139.27 10.32,139.43 10.32,141.24 10.5,141.41 11.07,141.41 11.2,141.28 11.2,139.84 11.33,139.71 11.52,139.71 11.66,139.84 11.66,141.28 11.79,141.41 11.98,141.41 12.11,141.28 12.11,139.84 12.25,139.71 12.44,139.71 12.57,139.84 12.57,141.28 12.7,141.41 13.17,141.41 13.34,141.24 13.34,138.79 v1(12.91,138.36)
  BOTTOM w0.14: R261.2 R269.2 R277.1 v1(12.91,138.36)
MMC2_D1: length 67.2
  TOP w0.132: U18.F21 v1(34.68,111.66)
  L05_SIG02 w0.102: v1(15.45,138.36) 15.94,138.85 15.94,139.75 16.67,140.48 16.67,142.64 16.43,142.88 14.57,142.88 14.44,142.75 14.44,142.48 14.57,142.35 16.16,142.35 16.29,142.22 16.29,142.03 16.16,141.89 14.57,141.89 14.44,141.76 14.44,141.57 14.57,141.44 16.16,141.44 16.29,141.3 16.29,141.11 16.16,140.98 14.57,140.98 14.44,140.85 14.44,140.49 14.57,140.36 15.38,140.36 15.52,140.23 15.52,140.04 15.38,139.9 14.57,139.9 14.44,139.77 14.44,138.37 14.99,137.83 15.33,137.83 15.47,137.68 15.47,137.23 15.35,137.1 14.57,137.1 14.33,136.86 14.33,132.72 13.18,131.57 13.18,127.5 13.96,126.72 15.38,126.72 16.17,125.93 17.64,125.93 19.66,123.92 19.66,122.74 20.92,121.49 29.28,121.49 33.53,117.24 33.53,115.2 33.98,114.75 33.98,112.96 34.28,112.66 34.28,112.06 v1(34.68,111.66)
  BOTTOM w0.14: v1(15.45,138.36) R276.1 R268.2 R260.2
MMC2_D2: length 67
  TOP w0.132: U18.F20 v1(34.68,110.86)
  L05_SIG02 w0.102: v1(24.54,138.36) 24.54,142.16 24.04,142.66 23.45,142.66 23.32,142.53 23.32,141.58 23.18,141.44 22.99,141.44 22.86,141.58 22.86,142.53 22.72,142.66 22.53,142.66 22.4,142.53 22.4,141.58 22.27,141.44 22.08,141.44 21.94,141.58 21.94,142.53 21.81,142.66 21.62,142.66 21.49,142.53 21.49,141.58 21.35,141.44 21.16,141.44 21.03,141.58 21.03,142.53 20.9,142.66 17.44,142.66 17.12,142.35 17.12,137.42 16.6,136.89 16.6,133.11 15.42,131.94 15.42,127.17 16.31,126.29 17.72,126.29 20.03,123.98 20.03,122.82 21.02,121.82 29.45,121.82 33.83,117.44 33.83,115.33 34.28,114.87 34.28,113.43 35.08,112.63 35.08,111.26 v1(34.68,110.86)
  BOTTOM w0.14: v1(24.54,138.36) R274.1 R266.2 R258.2
MMC2_D3: length 67
  TOP w0.132: U18.G21 v1(35.48,111.66)
  L05_SIG02 w0.102: v1(35.48,111.66) 35.48,111.83 35.89,112.24 35.89,114.85 34.51,116.23 34.51,117.8 29.89,122.43 21.38,122.43 20.67,123.13 20.67,124.2 17.96,126.92 17.96,132.15 18.81,132.99 18.81,133.81 19.21,134.21 19.21,134.38 18.93,134.66 18.93,134.82 19.05,134.94 19.22,134.94 19.5,134.66 19.67,134.66 19.79,134.78 19.79,134.95 19.51,135.23 19.51,135.4 19.63,135.52 19.8,135.52 20.07,135.24 20.24,135.24 20.88,135.88 20.88,136.77 20.57,137.08 18.19,137.08 18.09,137.19 18.09,137.45 18.2,137.55 21.4,137.55 21.52,137.67 21.52,137.92 21.38,138.06 18.7,138.06 18.55,138.21 18.55,138.5 18.71,138.67 22.46,138.67 22.61,138.81 22.61,140.2 22.71,140.3 23.01,140.3 23.13,140.19 23.13,137.76 23.35,137.54 24.75,137.54 25.58,138.36 v1(27.08,138.36)
  BOTTOM w0.14: v1(27.08,138.36) R273.1 R265.2 R257.2
Net_1350: length 0.6
  TOP w0.132: 44.68,103.26 v1(45.08,102.87)
Net_1352: length 0.6
  TOP w0.132: 40.68,96.07 v1(41.08,95.67)
Net_1355: length 0.6
  TOP w0.132: 42.28,100.07 v1(42.68,99.67)
Net_1356: length 0.6
  TOP w0.132: 41.48,97.67 v1(41.88,97.26)
Net_1366: length 0.6
  TOP w0.132: 38.28,96.86 v1(37.88,96.47)
Net_1367: length 0.6
  TOP w0.132: 39.88,96.07 v1(40.28,95.67)
Net_1368: length 0.6
  TOP w0.132: 39.88,96.86 v1(40.28,96.47)
Net_1371: length 0.6
  TOP w0.132: 33.48,99.26 v1(33.08,98.87)
Net_1372: length 0.6
  TOP w0.132: 32.68,99.26 v1(32.28,98.87)
Net_1373: length 0.6
  TOP w0.132: 34.28,100.07 v1(33.88,99.67)
OSC0: length 5
  TOP w0.14: Y4.3 59.06,27.8 58.92,27.66 58.92,26.07 59.43,25.55 C146.2 59.17,25.25 U47.88
OSC1: length 3.3
  TOP w0.14: U47.89 58.77,25.17 C145.2 58.38,26.07 58.24,26.21 Y4.1
OSPI0_CSN0: length 2
  TOP w0.132: U18.H21 v1(36.28,111.66)
  BOTTOM w0.14: R320.2 v1(36.28,111.66)
OSPI0_LBCLK: length 25.2
  L05_SIG02 w0.102: v1(51.31,118.87) 50.38,117.94 42.71,117.94 42.51,117.73 42.51,116.93 42.26,116.68 41.51,116.68 41.39,116.56 41.39,115.24 41.26,115.11 41.07,115.11 40.95,115.23 40.95,117.18 40.81,117.32 40.6,117.32 40.48,117.2 40.48,115.26 40.35,115.14 40.1,115.14 39.96,115.27 v1(39.96,117.11)
  BOTTOM w0.14: v1(39.96,117.11) 39.96,115.51 R319.1 ; R312.2 v1(51.31,118.87)
OSPI0_LBCLKO_R: length 1.3
  TOP w0.132: U18.K22 v1(37.88,112.46)
  BOTTOM w0.14: v1(37.88,112.46) 37.88,112.47 37.88,112.87 R319.2
OSPI_CLK: length 27.8
  TOP w0.132: U18.L22 v1(38.68,112.46)
  L05_SIG02 w0.102: v1(48.42,119.04) 49.02,119.04 49.26,119.28 49.26,119.45 49.18,119.53 49.18,119.7 49.3,119.82 49.46,119.82 49.55,119.73 49.72,119.73 49.97,119.99 50.12,119.99 50.29,119.82 50.29,119.67 49.24,118.62 47.99,118.62 47.87,118.74 47.87,118.88 47.75,119 47.58,119 47.46,118.89 47.46,118.74 47.35,118.62 46.34,118.62 46.22,118.74 46.22,119.08 46.1,119.2 45.93,119.2 45.81,119.08 45.81,118.74 45.69,118.62 45.53,118.62 45.41,118.74 45.41,119.08 45.29,119.2 45.12,119.2 45,119.08 45,118.74 44.88,118.62 44.71,118.62 44.59,118.74 44.59,119.08 44.47,119.2 44.31,119.2 44.19,119.08 44.19,118.74 44.07,118.62 43.3,118.62 43.13,118.79 43.13,119.06 42.98,119.21 41.45,119.21 41.06,118.83 41.06,118.66 41.19,118.53 41.19,118.36 41.07,118.24 40.91,118.24 40.78,118.37 40.61,118.37 40.26,118.02 38.51,118.02 38.14,117.65 38.14,116.27 38.6,115.81 38.6,112.55 v1(38.68,112.46)
  BOTTOM w0.14: R313.1 R311.1 v1(48.42,119.04)
OSPI_CS: length 27.7
  TOP w0.14: U12.C2 v1(50.35,122.4)
  L05_SIG02 w0.102: v1(50.35,122.4) 50.81,122.4 50.89,122.31 50.89,121.88 50.79,121.78 50.3,121.78 50.2,121.68 50.2,121.47 50.28,121.38 51.53,121.38 51.65,121.26 51.65,121.08 51.54,120.97 49.39,120.97 48.84,120.43 48.84,119.63 48.72,119.51 48.46,119.51 48.35,119.62 48.35,120.38 48.23,120.49 47.98,120.49 47.85,120.36 47.85,120 47.72,119.88 47.1,119.88 46.79,119.57 41.38,119.57 40.14,118.33 38.11,118.33 37.92,118.15 v1(36.86,118.15)
  BOTTOM w0.14: R320.1 36.28,115.4 36.86,115.97 v1(36.86,118.15) ; R304.1 50.69,122.06 v1(50.35,122.4)
OSPI_DQ0: length 22.8
  TOP w0.14: RA1.2 35.86,119.39 v1(36.4,119.93) ; U12.D3 v1(49.35,123.4)
  L05_SIG02 w0.102: v1(49.35,123.4) 49.34,123.39 48.97,123.39 48.28,122.7 47.45,122.7 47.18,122.96 47.18,123.83 46.86,124.16 46.86,124.61 46.57,124.89 44.61,124.89 44.49,124.78 44.49,124.54 44.37,124.42 44.2,124.42 44.08,124.54 44.08,124.78 43.96,124.89 43.8,124.89 43.68,124.78 43.68,124.54 43.56,124.42 43.39,124.42 43.27,124.54 43.27,124.78 43.15,124.89 42.53,124.89 42.39,125.03 42.08,125.03 41.94,124.89 41.44,124.89 41.31,125.03 41.31,125.2 41.17,125.34 40.98,125.34 40.85,125.2 40.85,125.03 40.72,124.89 40.02,124.89 36.4,121.28 v1(36.4,119.93)
  BOTTOM w0.14: R299.1 48.98,123.77 v1(49.35,123.4)
OSPI_DQ1: length 19
  TOP w0.14: v1(38.82,119.01) 38.68,118.87 RA2.1 ; U12.D2 v1(50.35,123.4)
  L05_SIG02 w0.102: v1(38.82,119.01) 38.82,119.29 39.35,119.82 39.35,120.29 39.79,120.73 40.77,120.73 40.89,120.61 40.89,120.4 41.01,120.28 41.18,120.28 41.3,120.4 41.3,120.61 41.42,120.73 41.59,120.73 41.71,120.61 41.71,120.4 41.83,120.28 41.99,120.28 42.11,120.4 42.11,120.61 42.23,120.73 42.4,120.73 42.52,120.61 42.52,120.4 42.64,120.28 42.81,120.28 42.93,120.4 42.93,120.61 43.04,120.73 43.21,120.73 43.33,120.61 43.33,120.4 43.45,120.28 43.62,120.28 43.74,120.4 43.74,120.61 43.86,120.73 44.03,120.73 44.14,120.61 44.14,120.4 44.26,120.28 44.43,120.28 44.55,120.4 44.55,120.61 44.67,120.73 46.01,120.73 46.44,121.16 48.69,121.16 49.63,122.09 49.63,122.66 50.35,123.39 v1(50.35,123.4)
  BOTTOM w0.14: R302.1 50.57,123.18 v1(50.35,123.4)
OSPI_DQ2: length 20.8
  TOP w0.14: RA2.2 38.28,119.39 v1(38.82,119.93) ; U12.C4 v1(48.25,121.55)
  L05_SIG02 w0.102: v1(38.82,119.93) 38.82,120.76 39.85,121.79 40.38,121.79 40.5,121.67 40.5,121.27 40.62,121.15 40.79,121.15 40.91,121.27 40.91,121.67 41.03,121.79 41.2,121.79 41.31,121.67 41.31,121.27 41.43,121.15 41.6,121.15 41.72,121.27 41.72,121.67 41.84,121.79 42.01,121.79 42.13,121.67 42.13,121.27 42.25,121.15 42.41,121.15 42.53,121.27 42.53,121.67 42.65,121.79 42.82,121.79 42.94,121.67 42.94,121.27 43.06,121.15 43.23,121.15 43.35,121.27 43.35,121.67 43.47,121.79 43.63,121.79 43.75,121.67 43.75,121.27 43.87,121.15 44.04,121.15 44.16,121.27 44.16,121.67 44.28,121.79 44.45,121.79 44.57,121.67 44.57,121.27 44.68,121.15 44.85,121.15 44.97,121.27 44.97,121.67 45.09,121.79 45.26,121.79 45.38,121.67 45.38,121.27 45.5,121.15 45.67,121.15 45.79,121.27 45.79,121.67 45.9,121.79 47.47,121.79 47.7,121.55 v1(48.25,121.55)
  BOTTOM w0.14: v1(48.25,121.55) 47.91,121.89 R303.1
OSPI_DQ3: length 20.3
  TOP w0.14: RA1.3 35.46,119.39 v1(34.92,119.93) ; U12.D4 v1(48.35,123.4)
  L05_SIG02 w0.102: v1(34.92,119.93) 34.92,120.23 40.34,125.66 46.69,125.66 48.35,123.99 v1(48.35,123.4)
  BOTTOM w0.14: R300.1 v1(48.35,123.4)
OSPI_DQ4: length 23.1
  TOP w0.14: v1(37.34,119.01) 37.48,118.87 RA2.4 ; U12.D5 v1(46.35,123.4)
  L05_SIG02 w0.102: v1(46.35,123.4) 46.1,123.14 46.1,122.87 45.96,122.73 45.67,122.73 45.57,122.84 45.57,123.2 45.37,123.4 41.39,123.4 41.27,123.28 41.27,123.11 41.39,122.99 43.32,122.99 43.43,122.88 43.43,122.71 43.3,122.58 40.98,122.58 40.86,122.7 40.86,123.28 40.74,123.4 40.45,123.4 39.54,122.49 39.37,122.49 39.07,122.79 38.91,122.79 38.79,122.67 38.79,122.5 39.09,122.2 39.09,122.04 38.97,121.92 38.8,121.92 38.5,122.22 38.33,122.22 38.21,122.1 38.21,121.93 38.51,121.63 38.51,121.46 38.39,121.34 38.22,121.34 37.92,121.64 37.76,121.64 37.64,121.52 37.64,121.35 37.94,121.05 37.94,120.89 37.77,120.72 37.77,119.44 v1(37.34,119.01)
  BOTTOM w0.14: R301.1 v1(46.35,123.4)
OSPI_DQ5: length 21.2
  TOP w0.14: RA1.4 35.06,118.87 v1(34.92,119.01) ; U12.E3 v1(49.35,124.4)
  L05_SIG02 w0.102: v1(34.92,119.01) 34.53,119.41 34.53,120.29 40.21,125.97 47.23,125.97 48.8,124.4 v1(49.35,124.4)
  BOTTOM w0.14: R297.1 v1(49.35,124.4)
OSPI_DQ6: length 22.1
  TOP w0.14: RA2.3 37.88,119.39 v1(37.34,119.93) ; U12.E2 v1(50.35,124.4)
  L05_SIG02 w0.102: v1(37.34,119.93) 37.34,119.68 36.95,119.3 36.95,118.84 37.16,118.63 39.05,118.63 39.36,118.94 39.36,119.18 39.62,119.44 40.54,119.44 41.01,119.91 46.54,119.91 46.84,120.21 46.84,120.5 47.18,120.85 48.84,120.85 49.97,121.98 49.97,122.55 50.37,122.95 50.51,122.95 50.82,123.25 50.82,123.93 v1(50.35,124.4)
  BOTTOM w0.14: R296.1 v1(50.35,124.4)
OSPI_DQ7: length 23.7
  TOP w0.14: RA1.1 36.26,118.87 v1(36.4,119.01) ; U12.E1 v1(51.35,124.4)
  L05_SIG02 w0.102: v1(51.35,124.4) 50.84,124.91 50.15,124.91 49.81,124.58 49.81,123.31 49.34,122.83 49.04,122.83 48.53,122.31 47.24,122.31 46.79,122.76 46.79,123.55 46.44,123.9 40.87,123.9 40.75,124.01 40.75,124.24 40.63,124.36 40.47,124.36 40.35,124.24 40.35,124.01 40.23,123.9 39.47,123.9 36.83,121.26 36.83,119.74 36.4,119.3 v1(36.4,119.01)
  BOTTOM w0.14: R295.1 v1(51.35,124.4)
OSPI_DQS: length 4
  TOP w0.14: U12.C3 v1(49.23,122.27)
  BOTTOM w0.14: v1(49.23,122.27) 48.93,121.97 R306.1 R305.1 50.43,121.66 51.31,120.78 R309.1
OSPI_DQS_SOC: length 25.2
  TOP w0.132: U18.L21 v1(38.68,111.66)
  L05_SIG02 w0.102: v1(38.68,111.66) 39,111.66 39.37,112.03 39.37,112.8 39.25,112.92 39.25,116.63 39.04,116.84 38.61,116.84 38.44,117 38.44,117.52 38.61,117.69 41.85,117.69 42.13,117.97 42.13,118.75 42.23,118.86 42.46,118.86 42.58,118.74 42.58,118.39 42.68,118.29 49.59,118.29 50.87,119.58 50.87,120.42 50.99,120.54 51.35,120.54 51.46,120.43 51.46,120.1 51.63,119.93 v1(51.97,119.93)
  BOTTOM w0.14: R312.1 51.7,120.21 v1(51.97,119.93)
OSPI_INTN: length 15.9
  TOP w0.132: U18.K20 v1(37.88,110.86)
  TOP w0.14: R50.1 R49.1 40.01,120.11 v1(39.81,119.91)
  BOTTOM w0.114: 37.48,111.32 37.48,112.3
  BOTTOM w0.14: 37.48,112.3 37.37,112.41 37.37,112.99 37.6,113.22 37.6,114.82 38.31,115.54 38.31,117.76 39.31,118.77 39.31,119.41 v1(39.81,119.91) ; 37.48,111.32 37.88,110.93 v1(37.88,110.86)
OSPI_RSTN: length 7.7
  TOP w0.14: U11.4 R46.1 44.27,122.95 44.17,122.84 v1(44.17,122.77) ; U12.A4 v1(47.35,119.4)
  L10_SIG03 w0.102: v1(47.35,119.4) 46.87,119.88 46.87,120.66 46.1,121.43 45.51,121.43 v1(44.17,122.77)
P2_PP_EXT_ENABLE: length 2.6
  BOTTOM w0.14: R449.1 19.69,40.15 20.58,41.04 U90.49
PD_GPIO0: length 2
  BOTTOM w0.14: U90.16 18.18,49.3 17.53,49.95 R416.2
PD_GPIO2: length 4.3
  TOP w0.14: TP58.1 18.92,51.4 v1(19.3,51.78)
  BOTTOM w0.14: v1(19.3,51.78) 19.3,49.58 18.98,49.26 U90.18
PD_HRESET: length 1.8
  BOTTOM w0.14: R445.1 22.72,40.49 22.72,41.09 22.58,41.23 U90.44
PD_I2C_IRQ: length 58.1
  TOP w0.14: v1(58.24,40.04) 58.24,44.88 55.7,47.43 53.18,47.43 52.88,47.12 52.14,47.12 51.55,47.71 51.15,47.71 v1(50.36,48.49) ; R169.1 R167.2 24.39,47.52 24.01,47.91 v1(24.01,48.71)
  L10_SIG03 w0.102: v1(50.36,48.49) 49.98,48.11 49.98,47.78 48.3,46.11 39.35,46.11 38.72,46.74 38.41,46.74 37.92,47.22 37.32,47.22 37.18,47.09 37,47.09 33.09,47.09 32.66,46.65 32.66,44.93 31.2,43.47 30.68,43.47 30.22,43.02 29.95,43.02 29.57,42.64 26.75,42.64 25.65,41.54 24.99,41.54 23.74,42.79 23.74,48.44 v1(24.01,48.71)
  BOTTOM w0.14: U92.23 57.95,41.61 58.51,41.05 58.51,40.31 v1(58.24,40.04)
PD_M_I2C3_IRQ: length 1.9
  BOTTOM w0.14: U90.23 R412.2
PD_M_I2C3_SCL: length 53.4
  TOP w0.14: R161.2 v1(20.18,49.49)
  L10_SIG03 w0.102: v1(65.08,58.48) 64.16,59.4 60.89,59.4 60,58.51 55.6,58.51 53.57,56.48 53.57,54.47 50.5,51.4 45.65,51.4 45.04,50.79 42.27,50.79 41.89,50.41 31.54,50.41 31.05,49.92 25.22,49.92 24.62,49.32 23.55,49.32 23.08,48.85 20.82,48.85 v1(20.18,49.49)
  BOTTOM w0.14: R395.1 65.37,58.77 v1(65.08,58.48) ; v1(20.18,49.49) U90.21
PD_M_I2C3_SDA: length 55.1
  TOP w0.14: R158.2 v1(20.18,50.4)
  L10_SIG03 w0.102: v1(20.18,50.4) 19.68,49.9 19.68,49.21 20.3,48.59 23.35,48.59 23.85,49.09 24.71,49.09 25.31,49.69 31.15,49.69 31.64,50.18 42.09,50.18 42.39,49.87 44.94,49.87 46.03,50.97 52.5,50.97 53.95,52.41 53.95,56.48 55.72,58.24 60.16,58.24 60.89,58.97 v1(61.22,58.97)
  BOTTOM w0.14: v1(20.18,50.4) 20.66,49.92 20.66,49.16 20.58,49.08 U90.22 ; v1(61.22,58.97) 61.45,59.2 62.78,59.2 R396.1
PD_MS_I2C1_IRQ: length 1.5
  BOTTOM w0.14: U90.29 24.5,47.76 24.64,47.89 R419.2
PD_MS_I2C1_SCL: length 50.7
  L10_SIG03 w0.102: v1(65.08,59.35) 63.91,60.52 61.04,60.52 59.49,58.97 55.36,58.97 52.94,56.55 52.94,55.21 51.16,53.43 50.23,53.43 49.08,52.28 45.84,52.28 45.4,52.72 42.6,52.72 40.82,50.94 25.48,50.94 24.91,50.37 24.11,50.37 23.43,49.7 v1(23.29,49.7)
  BOTTOM w0.14: U90.27 22.58,48.99 v1(23.29,49.7) R415.2 ; R393.1 65.27,59.54 v1(65.08,59.35)
PD_MS_I2C1_SDA: length 46.6
  L10_SIG03 w0.102: v1(61.22,59.88) 60.89,59.88 59.74,58.74 55.45,58.74 53.19,56.48 53.19,55.08 51.23,53.13 50.65,53.13 49.28,51.75 42.42,51.75 41.3,50.64 31.44,50.64 30.95,50.15 24.65,50.15 v1(24.21,49.7)
  BOTTOM w0.14: v1(61.22,59.88) 61.93,59.88 62.27,59.54 R394.1 ; U90.28 22.98,48.76 23.41,49.18 23.69,49.18 v1(24.21,49.7) R414.2
PD_S_I2C2_IRQ: length 2.6
  TOP w0.14: R169.2 25.19,46.14 25.33,46 v1(25.33,45.76)
  BOTTOM w0.14: U90.34 24.36,45.76 24.48,45.88 25.21,45.88 v1(25.33,45.76)
PD_S_I2C2_SCL: length 1.7
  BOTTOM w0.14: R421.2 24.79,47.13 24.22,46.56 U90.32
PD_S_I2C2_SDA: length 1.6
  BOTTOM w0.14: R422.2 24.46,46.37 24.25,46.16 U90.33
PD_SPI_CLK: length 50.9
  TOP w0.14: U34.6 59.16,62.49 59.46,62.19 59.46,58.97 58.68,58.18 J11.7
  L10_SIG03 w0.102: J11.7 57.51,55.96 57.51,53.05 54.97,50.51 47.68,50.51 45.11,47.94 42.59,47.94 42.31,48.22 42.31,48.68 41.29,49.7 32,49.7 30.62,48.31 30.19,48.31 28.71,46.83 26.52,46.83 25.76,46.06 25.76,44.46 v1(26.37,43.85)
  BOTTOM w0.14: v1(26.37,43.85) 26.15,43.64 R436.2
PD_SPI_MISO: length 51.6
  TOP w0.14: R146.2 U34.2 62.41,61.22 61.72,60.54 61.72,58.56 61.22,58.05 J11.5
  L10_SIG03 w0.102: v1(26.37,45.51) 26.49,45.38 29.8,45.38 31.29,46.87 31.29,47.63 32.01,48.35 40.41,48.35 40.78,47.98 40.78,47.07 41.28,46.57 47.09,46.57 50.52,50 56.49,50 60.03,53.54 60.03,55.94 J11.5
  BOTTOM w0.14: R426.2 26.13,45.51 v1(26.37,45.51)
PD_SPI_MOSI: length 53.3
  TOP w0.14: U34.5 59.37,63.76 59.95,63.18 59.95,55.85 J11.8
  L10_SIG03 w0.102: J11.8 58.12,54.02 58.12,52.77 55.63,50.28 50.29,50.28 46.82,46.8 41.49,46.8 41.05,47.25 41.05,48.68 40.52,49.21 32.38,49.21 30.87,47.7 30.87,47.24 30.12,46.49 26.68,46.49 25.99,45.8 25.99,45.07 v1(26.37,44.69)
  BOTTOM w0.14: R431.2 26.07,44.4 v1(26.37,44.69)
PD_SPI_SS: length 62.8
  TOP w0.14: J11.9 56.89,57.12 57.36,56.66 57.36,53.94 57.89,53.4 61.93,53.4 62.51,53.99 62.51,58.03 62.05,58.48 62.05,59.53 62.48,59.95 U34.1 R147.2
  L10_SIG03 w0.102: v1(25.23,42.02) 24.03,43.22 24.03,45.38 25.86,47.21 28.68,47.21 30.08,48.61 30.59,48.61 31.9,49.92 41.56,49.92 42.57,48.91 44.99,48.91 46.81,50.74 52.78,50.74 54.94,52.9 54.94,55.93 J11.9
  BOTTOM w0.14: R439.2 25.01,42.24 v1(25.23,42.02)
PD_VIN_3V3: length 1.8
  TOP w0.381: C123.2 15.81,44.58 16.04,44.35 v1(16.11,44.35)
  BOTTOM w0.14: v1(16.11,44.35) 16.3,44.16 U90.5
PMIC_AMUXOUT: length 2
  TOP w0.14: TP36.1 22.29,75.75 21.5,76.54 U27.1
PMIC_ENABLE: length 26.6
  TOP w0.14: U31.4 3.66,68.42 4.78,67.3 5.32,67.3 7.16,65.46 11.01,65.46 v1(11.86,66.31) 11.86,66.32 TP42.1 ; U36.1 v1(17.93,56.75)
  L05_SIG02 w0.102: v1(11.86,66.31) 11.86,61.08 16.19,56.75 v1(17.93,56.75)
PMIC_ENABLE_SEL: length 7.3
  TOP w0.14: J9.1 2.54,64.23 2.19,64.58 2.19,67.33 1.91,67.61 R138.1 1.51,68.04 2.16,68.69 U31.1
PMIC_INT_B: length 8.8
  TOP w0.14: R127.2 27.3,81.75 27.13,81.92 27.13,81.93 27.14,81.94 27.14,82.65 27,82.79 R126.1 26.34,83.16 R123.2 TP33.1 24.85,84.08 22.55,84.08 21.52,83.04 U27.14
PMIC_INTN: length 46
  TOP w0.132: U18.F17 v1(34.68,108.46)
  TOP w0.14: R127.1 27.74,80.77 v1(28.03,80.48) ; v1(34.41,115.29) 33.96,115.73 R53.2
  L10_SIG03 w0.102: v1(28.03,80.48) 28.03,81.63 28.13,81.73 28.13,82.52 27.2,83.45 27.2,94.8 30.06,97.67 32.45,97.67 32.68,97.9 32.68,98.23 32.91,98.47 33.25,98.47 34.28,99.5 34.28,99.83 34.51,100.07 34.78,100.07 34.85,100.07 35.08,100.3 U18.F17 v1(34.68,108.46) 35.08,108.86 35.65,108.86 35.88,109.1 35.88,110.23 35.89,110.24 36.11,110.47 36.45,110.47 36.68,110.7 36.68,111.83 36.3,112.21 36.3,113.4 v1(34.41,115.29)
PMIC_LPM_EN0: length 83.3
  TOP w0.132: U18.D12 v1(33.08,104.46)
  TOP w0.14: TP41.1 18.01,67.52 v1(17.72,67.23) 16.75,66.26 13.73,66.26 12.59,65.11 R140.1 6.37,65.51 5.1,66.78 v1(3.85,66.78) 3.85,67.48 3.16,68.18 U31.3 ; U31.8 3.16,75.29 3.61,75.74 4.69,75.74 v1(4.93,75.99)
  L05_SIG02 w0.102: v1(4.93,75.99) 4.04,75.09 4.04,70.78 3.91,70.65 3.91,66.84 v1(3.85,66.78)
  L10_SIG03 w0.102: v1(33.08,104.46) 33.08,103.93 33.09,103.93 32.64,103.48 31.05,103.48 30.75,103.18 28.93,103.18 28.71,103.4 27.84,103.4 26.34,101.91 24.13,101.91 22.9,100.67 22.32,100.67 21.92,100.27 20.27,100.27 19.6,99.6 19.04,99.6 18.76,99.32 18.76,95.44 18.49,95.17 18.49,88.39 18.51,88.37 18.51,88.05 18.51,87.86 18.49,87.85 18.49,87.62 18.51,87.61 18.51,87.1 18.49,87.08 18.49,85.51 19.24,84.76 19.24,82.82 18.95,82.53 18.95,76.04 19.17,75.82 19.17,74.63 18.56,74.02 18.56,68.76 17.72,67.93 v1(17.72,67.23)
PMIC_NPWRON/ENABLE: length 29.7
  TOP w0.132: v1(17.74,83.17) U27.20
  TOP w0.14: v1(20.41,60.16) 21.67,58.9 R148.2
  L03_SIG01 w0.102: v1(17.74,83.17) 17.57,83.17 17.01,82.6 17.01,75.65 17.62,75.04 17.62,74.07 18.81,72.88 18.81,71.14 19.85,70.11 19.85,66.64 20.9,65.59 20.9,60.65 v1(20.41,60.16)
PMIC_NSLEEP: length 13.5
  TOP w0.14: U27.46 15.24,74.99 v1(15.31,74.91) ; v1(4.93,75.04) 4.34,75.04 4.16,74.86 U31.6
  BOTTOM w0.14: v1(4.93,75.04) 5.25,75.36 11.14,75.36 11.58,74.91 v1(15.31,74.91)
PMIC_OSC32KCAP: length 1.4
  TOP w0.305: U27.40 v1(12.16,77.54)
  BOTTOM w0.305: v1(12.16,77.54) 12.16,77.32 C381.1
PMIC_OSC32KIN: length 8.7
  TOP w0.132: 10.51,77.08 C85.2 ; 10.51,77.08 9.92,76.49 7.75,76.49 7.48,76.76 Y3.2 ; 10.51,77.08 10.51,76.62 10.64,76.49 10.88,76.49 11.12,76.73 11.12,77.94 11.72,78.54 U27.38
PMIC_OSC32KOUT: length 8.7
  TOP w0.132: U27.39 11.79,78.04 11.53,77.78 11.53,76.6 11.03,76.11 10.64,76.11 10.51,75.97 10.51,75.52 ; Y3.1 7.48,75.73 7.86,76.11 9.92,76.11 10.51,75.52 ; 10.51,75.52 C89.2
PMIC_POWERGOOD: length 98.6
  TOP w0.132: v1(15.24,83.17) U27.25
  TOP w0.14: TP81.1 v1(22.96,23.92)
  L03_SIG01 w0.102: v1(12.05,87.95) 12.05,85.26 10.12,83.33 10.12,80.88 10.12,76.59 10.12,76.03 10.31,75.84 10.31,75.83 12.76,73.39 12.76,68.66 10.97,66.87 10.97,60.23 15.61,55.58 15.61,51.66 17.59,49.68 17.59,40.9 18.14,40.36 18.14,39.98 21.04,37.08 21.04,34.7 22.45,33.29 22.45,24.99 22.96,24.47 v1(22.96,23.92)
  L05_SIG02 w0.102: v1(22.96,23.92) 23.32,23.56 23.32,20.49 25.37,18.44 27.14,18.44 30.72,14.86 33.08,14.86 v1(33.9,15.68)
  BOTTOM w0.14: v1(33.9,15.68) 33.9,15.7 33.72,15.89 U116.1 ; v1(12.05,87.95) 12.05,86.36 v1(15.24,83.17) ; v1(22.96,23.92) 23.37,24.32 R501.1 R500.1
PMIC_WDOG_DISABLE: length 92.4
  TOP w0.14: TP74.1 60.4,30.05 60.4,28.93 61.04,28.28 v1(61.04,26.69) ; U27.41 12.23,77.04 12.06,76.87 12.06,76.55 11.32,75.8 11.32,74.9 11.07,74.65 v1(10.67,74.65)
  L05_SIG02 w0.102: v1(61.04,26.69) 61.04,27.94 60.55,28.43 60.55,29.46 58.12,31.89 56.26,31.89 55.52,32.63 55.17,32.63 53.75,34.04 50.33,34.04 49.77,34.6 47.54,34.6 46.11,36.03 46.11,36.6 42.33,40.38 42,40.38 41.73,40.65 41.73,43.34 32.37,52.69 29.16,52.69 28.43,53.42 23.46,53.42 22.48,54.4 20.89,54.4 20.56,54.73 17.52,54.73 10.91,61.33 10.91,67.58 10.67,67.82 10.67,74.6 10.67,74.6 v1(10.67,74.65)
  BOTTOM w0.14: R493.2 R492.1 62.66,26.04 62.01,26.69 v1(61.04,26.69)
PMIC_WDOG_TRIGG: length 52.5
  TOP w0.132: U18.D13 v1(33.08,105.26)
  TOP w0.14: R137.1 20.26,67.67 v1(20.26,67.86)
  L05_SIG02 w0.102: v1(20.26,67.86) 20.26,70.69 20.75,71.18 20.75,74.11 20.14,74.72 20.14,85.74 18.82,87.06 18.82,88.54 18.5,88.86 18.5,90.79 18.74,91.02 18.74,100.31 20.1,101.67 20.1,102.8 20.81,103.52 21.54,103.52 22.67,104.65 29.04,104.65 29.34,104.95 30.34,104.95 30.44,104.86 30.84,104.86 31.08,105.1 31.08,105.43 31.31,105.66 32.68,105.66 v1(33.08,105.26)
PORZ_OUT: length 188.2
  TOP w0.132: U18.F18 v1(34.68,109.26)
  TOP w0.14: U42.3 62.69,38.77 v1(61.46,37.55) ; U41.3 63.17,42.25 62.98,42.06 v1(62.98,41.49) ; R170.2 v1(58.47,46.24) TP63.1 ; U24.6 5.17,92.4 4.91,92.66 4.91,92.89 R104.1 3.97,92.7 v1(3.97,92.21)
  L03_SIG01 w0.102: v1(5.63,59.92) 7.43,59.92 8.47,58.89 11.15,58.89 14.79,55.25 14.79,41.37 15.63,40.53 17.18,40.53 v1(17.64,40.07)
  L05_SIG02 w0.102: v1(58.47,46.24) 56.75,44.51 56.75,41.85 57.13,41.47 58.2,41.47 59.86,39.81 60.72,39.81 60.95,40.04 61.89,40.04 62.3,40.44 62.3,40.81 v1(62.98,41.49) 63.71,40.76 63.71,37.94 62.93,37.17 61.84,37.17 v1(61.46,37.55)
  L10_SIG03 w0.102: v1(34.68,109.26) 34.6,109.26 34.2,109.66 33.71,109.66 33.48,109.9 33.48,110.3 33.32,110.47 32.9,110.47 32.68,110.68 32.68,111.1 32.51,111.26 31.12,111.26 31.12,111.26 30.47,110.61 26.29,110.61 25.12,109.44 24.31,109.44 24.09,109.65 22.75,109.65 v1(20.86,107.76) ; v1(17.64,40.07) 18.09,39.61 19.28,39.61 19.51,39.84 21.76,39.84 22.36,39.24 24.98,39.24 25.54,39.81 26.14,39.81 26.32,39.63 29.54,39.63 30.27,38.9 35.58,38.9 36.06,39.38 36.06,41.22 38.77,43.94 46.02,43.94 46.61,43.34 47.08,43.34 47.82,42.61 50.35,42.61 53.16,45.42 57.66,45.42 v1(58.47,46.24) ; v1(3.97,92.21) 4.26,91.92 4.26,89.61 4.57,89.3 4.57,87.92 8.16,84.33 8.16,80.91 7.67,80.43 7.67,73.13 3.38,68.84 3.38,65.14 3.75,64.76 3.75,60.82 4.65,59.92 v1(5.63,59.92)
  BOTTOM w0.14: v1(3.97,92.21) 4.33,91.86 8.84,91.86 10.95,93.97 10.95,96.05 11.56,96.66 11.56,101.72 14.02,104.18 20.45,104.18 21.8,105.53 21.8,106.82 v1(20.86,107.76)
PP1_CABLE: length 1.6
  TOP w0.14: C117.1 v1(21.78,49.32)
  BOTTOM w0.14: v1(21.78,49.32) U90.25
PP2_CABLE: length 1.9
  BOTTOM w0.14: R447.2 21.78,40.81 U90.46
PR0_PRU0_GPO0: length 121.3
  TOP w0.132: U18.N21 v1(41.08,111.66)
  L10_SIG03 w0.102: v1(41.17,38.31) 40.84,38.64 40.84,39.82 41.08,40.07 44.58,40.07 45.94,38.71 47.69,38.71 48.63,39.65 50.72,39.65 51.66,38.71 53.5,38.71 54.15,38.06 57.64,38.06 58.18,38.61 59.32,38.61 60.35,39.65 61.21,39.65 61.71,40.15 61.71,40.9 61.45,41.16 61.45,43.63 62.92,45.1 62.92,51.37 63.38,51.83 63.38,52.52 64.87,54.01 64.87,57.45 64.87,57.65 66.09,58.86 66.09,62.37 64.24,64.22 59.52,64.22 55.4,68.35 55.4,69.52 50.95,73.96 50.95,82.19 49.54,83.6 49.54,89.81 51.51,91.78 51.51,93.64 49.09,96.07 48.11,96.07 47.88,96.3 47.88,96.63 47.65,96.86 47.32,96.86 47.31,96.87 47.08,97.1 47.08,97.11 47.08,97.43 46.85,97.67 46.8,97.67 46.8,97.67 46.51,97.67 46.28,97.9 46.28,98.23 46.05,98.47 45.71,98.47 45.48,98.7 45.48,99.03 45.25,99.26 44.91,99.26 44.68,99.5 44.68,99.89 44.5,100.07 39.91,100.07 39.39,100.58 39.39,110.19 39.69,110.49 39.69,111.84 39.91,112.06 40.68,112.06 v1(41.08,111.66)
  BOTTOM w0.14: v1(41.17,38.31) 41.03,38.45 RA5.8
PR0_PRU0_GPO1: length 117
  TOP w0.132: U18.N20 v1(41.08,110.86)
  L10_SIG03 w0.102: v1(42.65,38.85) 43.04,38.46 47.92,38.46 48.24,38.78 50.98,38.78 51.29,38.48 53.41,38.48 54.23,37.66 57.61,37.66 58.27,38.31 60.76,38.31 61.34,38.89 61.77,38.89 62.31,39.44 62.31,44.08 63.17,44.95 63.17,50.76 65.1,52.69 65.1,57.54 66.32,58.76 66.32,62.47 64.33,64.45 59.61,64.45 55.62,68.44 55.62,69.61 51.18,74.05 51.18,82.31 49.77,83.72 49.77,89.69 51.74,91.66 51.74,93.77 48.64,96.87 48.11,96.87 47.88,97.1 47.88,97.43 47.65,97.67 47.31,97.67 47.08,97.9 47.08,98.23 46.85,98.47 46.46,98.47 46.28,98.64 46.28,99.03 46.05,99.26 46,99.26 46,99.27 45.71,99.27 45.48,99.5 45.48,99.83 45.25,100.07 44.91,100.07 44.68,100.3 44.68,100.34 44.68,100.63 44.45,100.86 40.07,100.86 39.63,101.31 39.63,110.03 40.06,110.47 U18.N20 v1(41.08,110.86)
  BOTTOM w0.14: RA5.7 v1(42.65,38.85)
PR0_PRU0_GPO2: length 119.3
  TOP w0.132: U18.N19 v1(41.08,110.06)
  L10_SIG03 w0.102: v1(41.08,110.06) 41.08,110 40.74,109.66 40.09,109.66 39.87,109.45 39.87,101.85 40.06,101.67 44.45,101.67 44.68,101.43 44.68,101.1 44.91,100.86 45.25,100.86 45.48,100.63 45.48,100.28 45.7,100.07 46.05,100.07 46.28,99.83 46.28,99.54 46.28,99.5 46.51,99.27 46.56,99.27 46.56,99.26 46.85,99.26 47.08,99.03 47.08,98.7 47.31,98.47 47.65,98.47 47.88,98.23 47.88,97.9 48.11,97.67 48.45,97.67 52,94.11 52,91.53 50,89.53 50,83.85 51.41,82.44 51.41,74.15 55.85,69.71 55.85,68.65 59.82,64.68 64.43,64.68 67.41,61.7 67.41,53.96 66.67,53.23 66.02,53.23 63.43,50.64 63.43,42.79 62.54,41.9 62.54,38.98 61.49,37.93 58.39,37.93 57.71,37.25 55.71,37.25 55.21,36.74 54.73,36.74 54.47,37.01 52.28,37.01 51.9,37.39 50.87,37.39 50.56,37.08 47.57,37.08 46.51,38.14 42.69,38.14 42.15,38.67 v1(42.15,39.65)
  BOTTOM w0.14: RA5.6 41.75,39.25 v1(42.15,39.65)
PR0_PRU0_GPO3: length 117.7
  TOP w0.132: U18.N18 v1(41.08,109.26)
  L10_SIG03 w0.102: v1(41.08,109.26) U18.N18 40.68,102.7 40.91,102.47 44.45,102.47 44.68,102.23 44.68,101.9 44.91,101.67 45.2,101.67 45.25,101.67 45.48,101.43 45.48,101.1 45.71,100.86 46.05,100.86 46.28,100.63 46.28,100.3 46.51,100.07 46.8,100.07 46.85,100.07 47.08,99.83 47.08,99.79 47.08,99.5 47.31,99.26 47.69,99.26 47.91,99.04 47.91,98.71 48.14,98.49 48.42,98.49 52.25,94.66 52.25,91.33 50.23,89.31 50.23,84.03 51.67,82.59 51.67,74.22 56.08,69.8 56.08,68.8 59.98,64.91 64.52,64.91 67.64,61.8 67.64,53.84 66.75,52.95 66.07,52.95 63.68,50.56 63.68,42.69 63.38,42.38 63.38,41.26 62.77,40.66 62.77,38.7 61.87,37.8 61.87,37.37 61.45,36.95 56.66,36.95 56.09,36.38 55.51,36.38 55.04,35.9 51.68,35.9 50.75,36.82 43.56,36.82 41.24,39.14 v1(41.24,39.65)
  BOTTOM w0.14: RA5.5 v1(41.24,39.65)
PR0_PRU0_GPO4: length 125.2
  TOP w0.132: U18.N17 v1(41.08,108.46)
  L10_SIG03 w0.102: v1(31.5,33.86) 32.82,35.18 58.36,35.18 59.2,36.02 61.41,36.02 63.76,38.37 63.76,40.96 64.24,41.44 64.24,45.35 66.04,47.16 66.04,51.14 67.87,52.97 67.87,61.89 64.62,65.14 60.07,65.14 56.31,68.9 56.31,69.9 51.93,74.27 51.93,82.73 50.48,84.18 50.48,89.1 52.5,91.12 52.5,94.92 47.91,99.51 47.91,99.8 47.65,100.07 47.3,100.07 47.08,100.28 47.08,100.71 46.93,100.86 46.55,100.86 46.55,100.87 46.51,100.87 46.28,101.1 46.28,101.41 46.28,101.43 46.05,101.67 45.65,101.67 45.48,101.83 45.48,102.31 45.33,102.47 44.91,102.47 44.68,102.7 44.68,103.03 44.42,103.29 42.09,103.29 41.48,103.9 41.48,107.83 41.25,108.06 41.25,108.29 v1(41.08,108.46)
  BOTTOM w0.14: v1(31.5,33.86) 31.78,33.58 RA6.5
PR0_PRU0_GPO5: length 126
  TOP w0.132: U18.P18 v1(41.88,109.26)
  L10_SIG03 w0.102: v1(32.34,33.89) 33.37,34.91 58.65,34.91 58.87,35.13 60.88,35.13 64.06,38.32 64.06,40.83 64.49,41.26 64.49,45.2 66.3,47 66.3,51.07 68.15,52.92 68.15,54.04 68.73,54.62 68.73,61.38 64.75,65.37 60.3,65.37 57.89,67.78 57.89,68.64 52.2,74.33 52.2,82.81 50.73,84.29 50.73,88.99 52.75,91.02 52.75,95.17 48.24,99.69 48.24,99.98 47.88,100.34 47.88,100.63 47.65,100.86 47.64,100.87 47.31,100.87 47.08,101.1 47.08,101.55 46.97,101.67 46.51,101.67 46.28,101.9 46.28,102.35 46.17,102.47 45.71,102.47 45.48,102.7 45.48,103.05 45.01,103.52 42.73,103.52 42.28,103.96 42.28,107.9 42.12,108.07 41.71,108.07 41.48,108.3 U18.P18 v1(41.88,109.26)
  BOTTOM w0.14: RA6.6 32.18,33.73 v1(32.34,33.89)
PR0_PRU0_GPO6: length 125.3
  TOP w0.132: U18.P19 v1(41.88,110.07)
  L10_SIG03 w0.102: v1(41.88,110.07) 42.04,109.91 42.04,109.72 42.28,109.48 42.28,108.3 42.51,108.06 42.85,108.06 43.08,107.83 43.08,105.89 43.3,105.66 43.66,105.66 43.88,105.45 43.88,105.07 44.08,104.86 44.45,104.86 44.68,104.63 44.68,104.25 45.6,103.32 45.99,103.32 46.28,103.03 46.28,102.7 46.51,102.47 46.85,102.47 47.08,102.23 47.08,101.9 47.31,101.67 47.73,101.67 47.88,101.51 47.88,101.05 48.54,100.39 48.54,99.76 52.98,95.32 52.98,90.93 50.96,88.9 50.96,84.38 52.43,82.91 52.43,74.43 58.17,68.69 58.17,67.86 60.43,65.6 64.84,65.6 68.99,61.45 68.99,54.47 68.43,53.91 68.43,52.85 66.58,50.99 66.58,41.89 64.38,39.7 64.38,38.21 61.03,34.85 59.07,34.85 58.9,34.68 34.42,34.68 v1(33.53,33.8)
  BOTTOM w0.14: RA6.7 32.58,33.38 32.72,33.52 33.25,33.52 v1(33.53,33.8)
PR0_PRU0_GPO7: length 129.3
  TOP w0.132: U18.P21 v1(41.88,111.66)
  L10_SIG03 w0.102: v1(33.54,32.99) 34.25,33.7 40.07,33.7 40.78,34.41 55.15,34.41 55.97,33.58 61.44,33.58 62.17,34.32 62.17,35.29 63.29,36.4 63.8,36.4 65.66,38.26 65.66,40.47 66.8,41.62 66.8,50.84 68.71,52.74 68.71,53.79 69.24,54.32 69.24,61.52 64.94,65.83 60.56,65.83 58.43,67.95 58.43,68.75 52.69,74.49 52.69,82.97 51.18,84.48 51.18,88.8 53.21,90.83 53.21,96.26 49.22,100.24 49.08,100.24 48.08,101.23 48.08,101.6 47.91,101.77 47.91,102.3 47.74,102.47 47.31,102.47 47.08,102.7 47.08,103.05 46.82,103.31 46.34,103.31 45.48,104.17 45.48,104.67 45.28,104.86 44.89,104.86 44.68,105.07 44.68,105.43 44.45,105.66 44.1,105.66 43.88,105.88 43.88,107.93 43.74,108.07 43.23,108.07 43.08,108.22 43.08,109.49 42.9,109.67 42.51,109.67 42.28,109.9 42.28,110.25 42.07,110.47 41.71,110.47 41.48,110.7 U18.P21 v1(41.88,111.66)
  BOTTOM w0.14: RA6.8 v1(33.54,32.99)
REFCLK1_R: length 5.4
  TOP w0.14: U18.A20 28.73,110.47 26.6,112.6 R55.2
RES_LM5141: length 2.2
  BOTTOM w0.14: U89.24 33.03,43.35 32.67,42.99 32.08,42.99 31.87,42.78 C427.1
RESETSTATZ: length 281.8
  TOP w0.132: U18.F19 v1(34.68,110.06)
  TOP w0.14: U32.2 v1(61.06,70.07) ; R171.2 v1(61.13,45.5) 61.45,45.17 63.09,45.17 TP65.1 63.72,44.55 R173.1 64.38,44.83 64.57,45.02 65.38,45.02 66.53,43.88 66.53,41.77 R178.1 ; U2.28 50.51,153.58 v1(51.01,154.08) ; U11.2 v1(41.66,124.33) ; U5.3 v1(43.42,145.66) ; U24.3 6.64,91.77 6.75,91.88 8.04,91.88 v1(8.43,92.27)
  L03_SIG01 w0.102: v1(43.42,145.66) 45.51,145.66 47.04,147.19 47.04,150.96 49.69,153.61 50.53,153.61 v1(51.01,154.08) ; v1(46.59,42.86) 46.59,42.01 47.51,41.09 49.07,41.09 50.53,39.62 53.24,39.62 53.84,39.02 54.56,39.02 v1(55.11,38.47)
  L05_SIG02 w0.102: v1(59.24,71.89) 59.24,73.13 63.47,77.37 63.47,79.79 62.72,80.55 62.72,84.44 62.31,84.85 62.31,86.07 60.86,87.52 60.48,87.52 59.57,88.43 59.57,90.84 59.34,91.07 59.34,97.55 59.67,97.88 59.67,99.76 60.05,100.14 60.05,105.63 58.24,107.43 58.24,108.98 56.67,110.55 v1(55.53,110.55) ; v1(8.43,92.27) 8.43,92.86 8.88,93.31 8.88,95.12 8.98,95.21 8.98,97.33 9.27,97.63 9.27,99.99 9.04,100.22 9.04,105.69 11.55,108.2 11.55,109.23 14,111.67 14,112.33 16.18,114.52 v1(17.06,114.52) ; v1(61.06,70.07) 60.58,69.58 60.58,67.04 60.1,66.56 60.1,47.66 61.13,46.64 v1(61.13,45.5)
  L10_SIG03 w0.102: v1(34.68,110.06) 34.28,110.46 34.28,112.95 31.64,115.59 28.39,115.59 27.51,114.7 27.51,112.31 26.37,111.16 25.89,111.16 25.56,110.83 24.7,110.83 24.45,110.58 19.72,110.58 19.2,111.1 19.2,111.45 18.6,112.06 18.26,112.06 17.7,112.62 17.7,113.05 17.25,113.49 17.25,114.33 v1(17.06,114.52) 17.25,114.71 17.25,116.05 17.93,116.73 17.93,121.17 21.9,125.13 25.66,125.13 25.72,125.2 25.73,125.2 26.65,126.12 32.31,126.12 32.73,125.71 40.28,125.71 v1(41.66,124.33) 42.02,123.97 43.86,123.97 44.07,123.76 45.2,123.76 46.05,122.91 47.47,122.91 49.51,120.87 50.45,120.87 54.66,116.66 54.66,112.59 55.2,112.05 55.2,110.88 v1(55.53,110.55) ; v1(55.11,38.47) 56.4,38.47 57.25,39.33 58.07,39.33 58.74,40 61.2,40 61.42,40.22 61.42,40.76 61.13,41.05 v1(61.13,45.5) ; v1(43.42,145.66) 46.82,145.66 47.4,146.24 49.3,146.24 51.68,143.87 51.68,141.34 50.18,139.85 49.79,139.85 48.69,138.75 47.09,138.75 45.75,137.4 44.92,137.4 43.17,135.66 v1(43.17,135.41) ; v1(59.24,71.89) v1(61.06,70.07)
  BOTTOM w0.14: U94.2 45.95,41.31 46.59,41.95 v1(46.59,42.86) ; v1(55.11,38.47) 54.7,38.88 U92.28 ; v1(43.17,135.41) 43.17,135.37 43.94,134.6 43.94,132.31 43.67,132.03 43.67,126.33 v1(41.66,124.33) ; v1(61.13,45.5) 60.72,45.1 60.72,44.34 60.93,44.13 R430.1 61.21,42.88 U93.2
RGMII2_BRD_CONN_DET: length 96.9
  TOP w0.14: v1(62.59,120.67) 61.98,121.28 R571.1 J4.43
  L05_SIG02 w0.102: v1(62.59,120.67) 62.59,116.97 64.33,115.23 64.33,107.04 65.68,105.69 65.68,105.34 64.36,104.02 64.36,102.6 64.59,102.37 64.59,101.4 64.15,100.97 64.15,92.74 64.79,92.11 64.79,86.95 64.94,86.8 64.94,73.89 63.32,72.27 63.32,58.4 62.63,57.71 62.63,52.51 v1(62.98,52.15)
  L10_SIG03 w0.102: v1(62.98,52.15) 62.55,51.72 62.55,51.26 61.71,50.42 61.71,48.8 60.98,48.06 60.98,46.18 60.19,45.39 60.19,42.83 58.79,41.43 57.14,41.43 56.46,40.75 53.97,40.75 53.31,40.09 v1(51.71,40.09)
  BOTTOM w0.14: v1(51.71,40.09) 51.95,40.33 U92.1
RGMII2_RSTN: length 96.5
  TOP w0.14: U42.4 64.33,38.56 64.15,38.38 63.09,38.38 v1(62.25,37.55) ; J4.12 57.07,114.88 v1(57.27,115.08)
  L05_SIG02 w0.102: v1(62.25,37.55) 62.25,39.45 61.97,39.73 61.1,39.73 60.9,39.53 59.53,39.53 58.46,40.6 57.36,40.6 56.42,41.54 56.42,44.59 55.53,45.48 55.53,46.62 59.79,50.89 59.79,66.79 60.12,67.12 60.12,73.3 63.96,77.13 63.96,80.02 63.81,80.17 63.81,87.19 61.09,89.9 61.09,91.69 61.57,92.17 61.57,97.6 61.7,97.73 61.7,99.94 61.37,100.27 61.37,101.84 61.93,102.4 61.93,103.32 61.32,103.93 61.32,107.38 61.14,107.56 61.14,114.86 v1(60.92,115.08)
  L10_SIG03 w0.102: v1(60.92,115.08) 60.52,115.48 57.68,115.48 v1(57.27,115.08)
  BOTTOM w0.14: v1(57.27,115.08) R314.1
RMII_PHY_OBSCLK: length 40.9
  TOP w0.14: v1(32.68,113.44) 34.56,113.44 35.4,114.28 45.05,114.28 47.44,116.67 53.38,116.67 55.99,119.28 J4.34
  BOTTOM w0.14: v1(32.68,113.44) 32.68,112.63 32.68,112.63 32.68,109.9 32.68,109.9 32.68,106.69 32.45,106.46 29.39,106.46 29.2,106.28 R581.1
RMII_REF_CLOCK: length 67.5
  TOP w0.14: J4.39 58.67,120.48 v1(58.47,120.68) ; R58.1 21.17,110.57 21.1,110.5 v1(15.94,110.5)
  L10_SIG03 w0.102: v1(58.47,120.68) 58.07,121.07 55.58,121.07 51.28,125.38 47.61,125.38 46.95,126.04 32.98,126.04 32.48,126.54 26.75,126.54 25.63,125.43 17.29,125.43 16.48,124.62 16.48,124.26 16.1,123.88 16.1,121.87 15.49,121.26 15.49,113.57 15.06,113.14 15.06,111.49 15.94,110.6 v1(15.94,110.5)
  BOTTOM w0.14: R307.2 v1(58.47,120.68)
RT_LM5141: length 1.7
  BOTTOM w0.14: U89.4 30.71,45.86 R423.1
SEL_XDS: length 42.7
  L03_SIG01 w0.102: v1(46.63,21.4) 46.97,21.06 51.5,21.06 52.17,21.72 v1(55.72,21.72) ; v1(65.67,18.72) 65.18,18.24 63.32,18.24 63.02,18.54 63.02,21.69 63.48,22.15 63.48,22.76 65.23,24.51 65.48,24.51 66.74,25.77 v1(67.34,25.77)
  L05_SIG02 w0.102: v1(65.67,18.72) 65.12,19.28 64.4,19.28 63.58,20.09 61.73,20.09 61,20.82 60.17,20.82 60.08,20.73 56.71,20.73 v1(55.72,21.72)
  BOTTOM w0.14: U111.1 65.96,19.73 65.67,19.44 v1(65.67,18.72) 66.16,18.72 66.34,18.9 U111.16 ; v1(46.63,21.4) 47.01,21.78 47.01,22.96 48.14,24.09 48.14,24.36 48.28,24.5 U106.5 ; v1(67.34,25.77) 67.46,25.77 67.55,25.86 U103.4 ; U109.4 57.29,21.47 57.04,21.72 v1(55.72,21.72)
SEL_XDS110_INV: length 72.5
  TOP w0.14: J19.8 v1(39.89,6.34)
  L03_SIG01 w0.102: v1(69.78,23.61) 68.99,22.82 68.84,22.82 65.31,19.29 64.23,19.29 v1(63.64,18.7) ; v1(43.39,16.09) 44.73,16.09 45.58,16.94 45.58,19.36 46.78,20.56 v1(47.25,20.56)
  L05_SIG02 w0.102: v1(44.97,24.83) 47.84,21.95 47.84,21.15 v1(47.25,20.56) ; v1(39.89,6.34) 39.89,10.57 40.46,11.14 40.46,13.17 v1(43.39,16.09) 44.38,15.09 48.76,15.09 50,16.33 50.9,16.33 51.96,15.28 53.33,15.28 53.94,15.89 59.35,15.89 60.14,16.68 61.25,16.68 63.28,18.7 v1(63.64,18.7)
  BOTTOM w0.14: U114.16 47.22,19.89 47.03,20.08 47.03,20.34 v1(47.25,20.56) 48,20.56 48.26,20.3 U114.1 ; v1(44.97,24.83) 44.97,24.35 45.12,24.21 U107.2 ; U103.2 71.17,26.51 71.4,26.28 71.4,25.42 71.26,25.28 R497.2 R498.1 70.01,24.91 69.78,24.68 v1(69.78,23.61) ; U112.5 63.51,18.84 v1(63.64,18.7) ; v1(43.39,16.09) 42.79,15.49 U117.2 ; v1(39.89,6.34) 39.89,7.26 40.33,7.7 U122.4
SLOW_CLK: length 15.7
  TOP w0.14: J2.50 v1(11.42,146.79)
  L03_SIG01 w0.102: v1(11.42,146.79) 18.53,139.68 18.53,137.11 v1(19.43,136.21)
  BOTTOM w0.14: R280.2 v1(19.43,136.21)
SOC_CLKIN: length 49.6
  TOP w0.14: R69.1 26.93,105.64 27.54,106.26 v1(27.54,107.13) ; R35.2 C19.1 R36.2 34.36,134.83 34.19,134.66 v1(33.79,134.66)
  BOTTOM w0.14: v1(33.79,134.66) 32.33,134.66 30.81,133.14 30.81,121.76 27.54,118.48 v1(27.54,107.13)
SOC_DVDD1V8: length 52.6
  TOP w0.279: U27.37 v1(12.09,79.04)
  TOP w0.305: C32.1 26.58,107.51 v1(26.7,107.63) 26.58,107.75 C528.3 26.71,108.55 v1(26.71,108.95) ; C528.1 24.86,108.55 v1(24.86,108.95)
  TOP w0.356: U18.F12 v1(34.68,104.46) ; U18.U8 v1(44.28,100.47) ; U18.K15 v1(37.88,106.86) ; U18.L16 v1(38.68,107.66) ; U18.H16 v1(36.28,107.66) ; U18.H17 v1(36.28,108.46) ; U18.T8 v1(43.48,100.47)
  L03_SIG01 w0.14: v1(34.68,104.46) 34.28,104.86 31.05,104.86 30.81,104.62 29.1,104.62 27.03,102.55 26.49,102.55 23.56,99.63 23.56,98.47 22.16,97.08 21.78,97.08 21.29,96.58 21.29,87.96 19.93,86.6 16.55,86.6 13.13,83.19 13.13,80.03 12.14,79.04 v1(12.09,79.04)
  BOTTOM w0.254: C218.1 39.09,108.17 C225.1 ; C529.3 24.95,108.95 v1(24.86,108.95) ; v1(26.71,108.95) 26.61,108.95 C529.1
  BOTTOM w0.305: v1(36.28,107.66) 36.08,107.87 C221.1 ; 43.65,100.6 43.62,100.6 v1(43.48,100.47) ; 44.48,100.26 v1(44.28,100.47) ; v1(34.68,104.46) 34.68,104.06 C258.1 ; v1(38.68,107.66) 38.69,107.66 C225.1 ; C217.1 36.3,108.48 v1(36.28,108.46)
  vias: v1(3.28,88.99) v1(3.28,88.07) v1(4.15,88.99) v1(4.15,88.07) v1(5.01,88.99) v1(5.01,88.07) v1(28.4,78.17) v1(28.4,77.26)
SOC_DVDD3V3: length 16.6
  TOP w0.305: C522.1 18.51,102.34 v1(18.35,102.19) ; C522.3 v1(20.74,102.91) ; C41.1 v1(20.32,101.33)
  TOP w0.356: U18.F9 v1(34.68,101.27) ; U18.G14 v1(35.48,106.06) ; U18.H10 v1(36.28,102.07) ; U18.U13 v1(44.28,105.26) ; U18.R13 v1(42.68,105.26) ; U18.N15 v1(41.08,106.86) ; U18.M15 v1(40.28,106.86) ; U18.G11 v1(35.48,102.87) ; U18.T13 v1(43.48,105.26) ; U18.H13 v1(36.28,105.26) ; U18.L15 v1(38.68,106.86) ; U18.U10 v1(44.28,102.07)
  L07_PWR02 w0.165: 43.8,102.47 43.17,102.47
  L07_PWR02 w0.406: v1(36.28,105.26) v1(35.48,106.06) ; v1(38.68,106.86) v1(40.28,106.86)
  BOTTOM w0.305: C239.1 42.8,105.39 v1(42.68,105.26) ; v1(38.68,106.86) 38.72,106.82 C233.1 ; C229.1 41.2,106.99 v1(41.08,106.86) ; C232.1 40.24,106.82 v1(40.28,106.86) ; v1(34.68,101.27) 34.68,101.51 C276.1 ; C523.3 36.39,102.17 v1(36.28,102.07) ; C238.1 44.4,105.39 v1(44.28,105.26) ; C244.1 v1(43.48,105.26) ; C247.1 v1(36.28,105.26) ; v1(44.28,102.07) 44.47,101.88 C270.1 ; 35.68,102.97 35.59,102.97 v1(35.48,102.87) 35.26,103.09 C257.1 ; C240.1 v1(35.48,106.06)
  vias: v1(12.55,99.94) v1(12.55,99.28) v1(13.36,99.94) v1(13.36,99.03) v1(14.28,99.94) v1(14.28,99.03)
SOC_EMU0: length 156.6
  TOP w0.132: U18.C13 v1(32.28,105.26)
  TOP w0.14: v1(55.43,23.69) 54.54,24.57 52.41,24.57 51.15,23.31 R224.2 v1(49.34,22.65)
  L03_SIG01 w0.102: v1(31.7,60.62) 32.13,61.05 37.1,61.05 37.85,60.3 37.85,47.3 39.42,45.73 39.42,41.49 38.08,40.15 38.08,37.83 36.76,36.51 36.76,35.65 35.79,34.68 35.79,31.51 34.8,30.52 34.8,26.4 34.44,26.05 34.44,25.01 31.71,22.27 31.71,18.72 32.91,17.52 36.5,17.52 37.74,18.76 39.73,18.76 44.48,23.51 48.48,23.51 v1(49.34,22.65)
  L05_SIG02 w0.102: v1(32.28,105.26) 31.88,104.86 31.88,104.17 31.67,103.96 31.07,103.96 30.59,103.49 29.11,103.49 28.82,103.78 23.79,103.78 22.13,102.11 22.13,101.6 21.35,100.83 21.35,95.98 20.43,95.06 20.43,89.34 20.98,88.79 20.98,75.3 21.59,74.69 21.59,70.81 21.24,70.46 21.24,66.13 20.87,65.77 20.87,61.78 21.49,61.16 22.21,60.44 31.52,60.44 v1(31.7,60.62)
  BOTTOM w0.14: U106.2 v1(49.34,22.65) ; U112.2 62.81,20.7 62.07,21.43 61.13,21.43 60.51,22.05 58.06,22.05 57.29,22.82 56.3,22.82 v1(55.43,23.69)
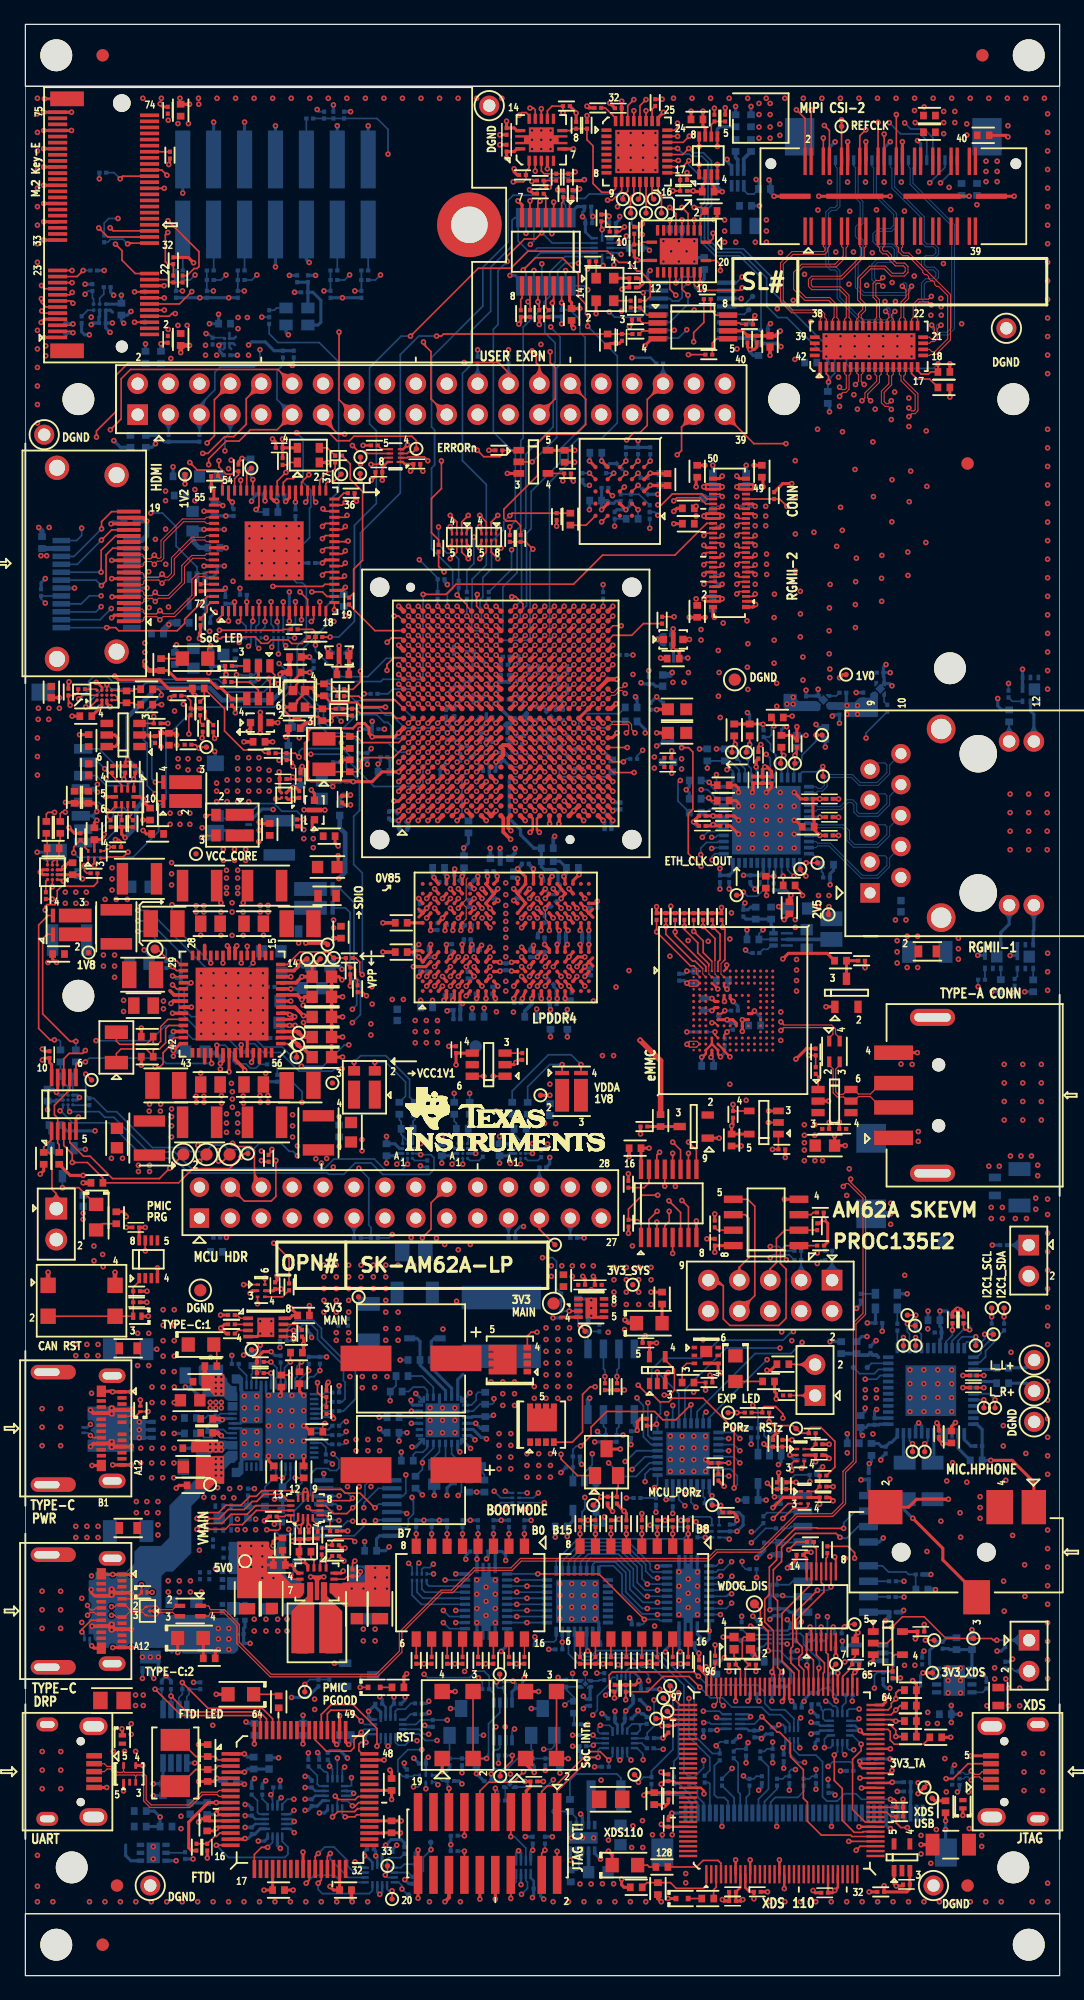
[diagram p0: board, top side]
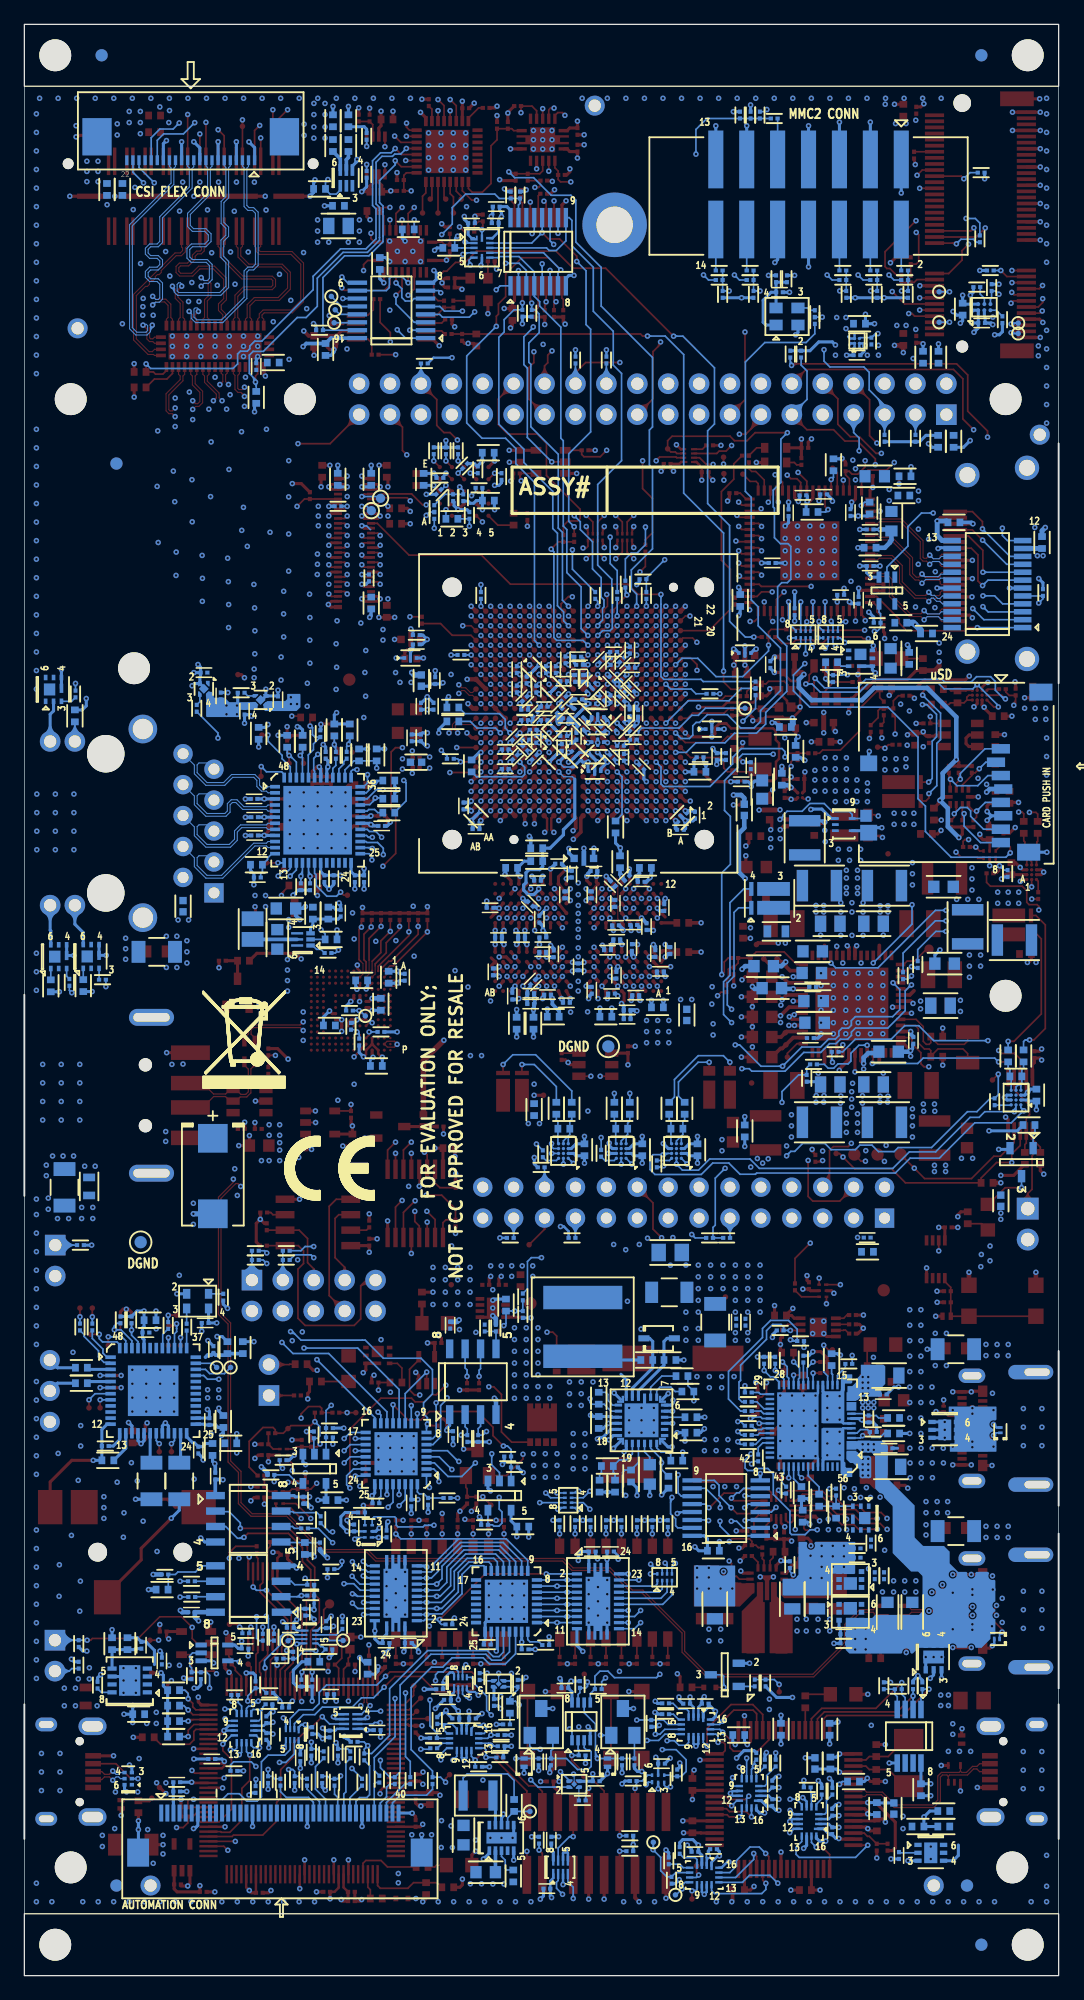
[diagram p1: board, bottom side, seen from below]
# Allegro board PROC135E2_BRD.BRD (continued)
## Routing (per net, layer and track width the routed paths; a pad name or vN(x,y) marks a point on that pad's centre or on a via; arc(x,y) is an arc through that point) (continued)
SOC_EMU1: length 146
  TOP w0.132: U18.E10 v1(33.88,102.07)
  TOP w0.14: v1(48.41,22.8) 48.41,22.88 48.42,22.88 R223.2 48.32,23.42 48.14,23.42 47.98,23.58 47.98,24.69 48.24,24.94 54.95,24.94 v1(55.31,24.58)
  L03_SIG01 w0.102: v1(33.78,60.57) 34,60.78 36.91,60.78 37.51,60.18 37.51,46.18 38.41,45.28 38.41,41.11 37.65,40.35 37.65,37.91 36.43,36.69 36.43,35.9 35.38,34.86 35.38,33.9 34.95,33.47 34.95,31.51 33.89,30.44 33.89,24.91 31.31,22.33 31.31,17.88 31.92,17.27 36.71,17.27 37.89,18.46 39.86,18.46 42.92,21.51 46.04,21.51 46.63,22.1 47.71,22.1 v1(48.41,22.8)
  L05_SIG02 w0.102: v1(33.88,102.07) 33.48,101.66 32.9,101.66 32.68,101.44 32.68,101.06 32.48,100.87 30.53,100.87 30.35,100.69 29.67,100.69 28.84,99.86 27.09,99.86 25.64,98.42 25.64,96.14 24.41,94.91 24.41,91.86 24.24,91.69 24.24,73.43 28.12,69.56 28.12,65.85 28.4,65.57 28.4,64.3 29.06,63.64 32.64,63.64 33.48,62.8 33.48,60.87 v1(33.78,60.57)
  BOTTOM w0.14: v1(55.31,24.58) 56.03,23.87 60.17,23.87 60.77,23.26 60.77,22.35 61.28,21.84 62.42,21.84 63.16,21.11 U112.3 ; v1(48.41,22.8) 48.67,22.8 48.99,23.12 U106.3
SOC_GPIO1_49: length 22.6
  TOP w0.132: U18.D18 v1(33.08,109.26)
  L03_SIG01 w0.102: v1(17.35,106.85) 17.35,105.36 18.05,104.66 25.4,104.66 27.15,106.41 27.97,106.41 30.42,108.86 32.68,108.86 v1(33.08,109.26)
  BOTTOM w0.14: v1(17.35,106.85) 17.75,106.85 17.79,106.81 R324.2 18.77,106.81 19.15,107.18 R323.1
SOC_I2C0_SCL: length 195.8
  TOP w0.132: U38.6 v1(22.05,52.99) ; U18.D17 v1(33.08,108.46)
  TOP w0.14: v1(41.63,133.44) 41.99,133.09 41.99,132.46 42.25,132.2 J3.28 ; v1(53.29,121.12) 53.54,121.37 55.43,121.37 55.92,120.88 J4.42
  L03_SIG01 w0.102: v1(22.05,52.99) 21.79,53.24 18.84,53.24 18.05,54.03 18.05,54.95 13.24,59.76 13.24,67.25 v1(14.18,68.19) ; J3.28 43.5,129.49 43.5,127.62 44.32,126.81 50.9,126.81 52.69,125.02 52.69,121.71 v1(53.29,121.12) ; v1(12.99,104.43) 12.99,103.09 11.95,102.05 11.95,99.22 15.52,95.64 15.52,93.59 14.36,92.42 10.52,92.42 10.51,92.41 10.16,92.41 8.85,91.09 8.85,87.03 v1(9.25,86.63)
  L10_SIG03 w0.102: v1(41.63,133.44) 40.87,134.2 34.93,134.2 33.72,132.98 24.08,132.98 23.07,134 19,134 18.82,133.82 18.82,132.98 18.09,132.25 16.51,132.25 15.73,131.46 15.73,127.83 15.05,127.15 13.7,127.15 10.89,124.34 10.89,122.66 10.56,122.33 10.56,120.55 10.76,120.35 10.76,119.66 9.04,117.94 9.04,111.77 9.41,111.4 9.41,111.4 10.36,110.46 10.36,107.06 v1(12.99,104.43) 14.45,102.96 19.75,102.96 20.23,102.48 22.11,102.48 23.33,103.7 25.75,103.7 26.9,104.85 30.83,104.85 31.08,105.1 31.08,105.49 31.26,105.67 31.65,105.67 31.88,105.9 31.88,106.31 32.03,106.47 32.45,106.47 32.68,106.7 32.68,106.99 32.68,107.03 32.91,107.26 33.22,107.26 33.25,107.26 33.48,107.5 33.48,108.06 v1(33.08,108.46) ; v1(14.18,68.19) 13.21,69.16 13.21,82.41 10.59,85.03 9.25,85.03 8.81,85.47 8.81,86.19 v1(9.25,86.63)
  BOTTOM w0.14: v1(9.25,86.63) 10.14,86.63 12.79,83.98 R363.1 ; v1(22.05,52.99) R408.2 22.6,53.27 22.81,53.48 23.5,53.48 24.01,52.97 24.01,52.26 26.14,50.13 26.14,48.88 26.27,48.76 26.27,47.36 26.04,47.13 R421.1
SOC_I2C0_SCL_PMIC: length 18.7
  TOP w0.132: U27.31 12.18,82.04 12.12,82.11 v1(12.09,82.11)
  TOP w0.14: TP43.1 14.32,66.87 v1(14.32,66.87)
  L10_SIG03 w0.102: v1(14.32,66.87) 12.71,68.48 12.71,81.49 v1(12.09,82.11)
  BOTTOM w0.14: R363.2 12.38,81.85 12.12,82.11 v1(12.09,82.11)
SOC_I2C0_SDA: length 204.2
  TOP w0.132: v1(22.05,52.22) 21.78,52.49 U38.5 ; U18.E16 v1(33.88,107.66)
  TOP w0.14: J4.44 56.01,121.28 55.59,121.69 53.17,121.69 52.28,120.8 v1(51.97,120.8) ; v1(43.13,133.37) 43.13,132.48 43.54,132.06 43.54,129.5 J3.27
  L03_SIG01 w0.102: v1(22.05,52.22) 22.48,52.66 22.48,53.13 21.17,54.44 18.93,54.44 15.42,57.95 15.42,67.32 v1(15.85,67.76) ; J3.27 43.9,126.55 50.67,126.55 52.41,124.81 52.41,121.23 v1(51.97,120.8) ; v1(12.26,103.86) 12.25,103.86 12.25,102.68 11.72,102.15 11.72,99.12 15.29,95.54 15.29,93.68 14.35,92.74 9.98,92.74 7.97,90.72 7.97,87.04 v1(9.25,85.76)
  L10_SIG03 w0.102: v1(15.85,67.76) 15.42,67.76 13.61,69.56 13.61,74.14 14.06,74.59 14.06,82.13 10.42,85.76 v1(9.25,85.76) ; v1(43.13,133.37) 43.13,134.06 42.47,134.71 34.78,134.71 33.51,133.44 25.61,133.44 23.8,135.24 18.58,135.24 15.81,132.48 14.1,132.48 13.02,131.4 13.02,127.13 10.43,124.53 10.43,122.86 8.59,121.02 8.59,111.58 9.22,110.95 9.38,110.79 9.38,106.39 10.98,104.79 11.34,104.79 v1(12.26,103.86) 13.11,103.86 14.29,102.69 19.64,102.69 20.08,102.24 22.2,102.24 23.42,103.47 25.85,103.47 26.97,104.59 30.98,104.59 31.25,104.86 31.65,104.86 31.88,105.1 31.88,105.44 32.11,105.67 32.45,105.67 32.68,105.9 32.68,106.23 32.91,106.46 33.25,106.46 33.48,106.7 33.48,107.03 33.88,107.43 v1(33.88,107.66)
  BOTTOM w0.14: v1(9.25,85.76) 10.09,85.76 11.58,84.27 R362.1 ; R422.1 26.14,46.37 27.13,47.36 27.13,49.62 24.34,52.41 24.34,53.15 23.68,53.81 22.2,53.81 21.49,53.1 R409.2 21.95,52.12 v1(22.05,52.22)
SOC_I2C0_SDA_PMIC: length 20.8
  TOP w0.132: U27.30 12.42,82.54 v1(12.09,82.87)
  TOP w0.14: TP44.1 16.24,66.89 v1(15.88,66.89)
  L10_SIG03 w0.102: v1(12.09,82.87) 12.97,81.99 12.97,68.85 14.93,66.89 v1(15.88,66.89)
  BOTTOM w0.14: v1(12.09,82.87) 11.99,82.76 R362.2
SOC_I2C1_SCL: length 332.9
  TOP w0.132: U13.1 16.19,111.79 15.89,111.48 v1(15.89,111.28) ; U18.C17 v1(32.28,108.46)
  TOP w0.14: U29.1 v1(38.44,73.87) ; U2.29 v1(50.01,153.17) ; U17.C3 v1(6.69,106.04) ; U17.A1 5.33,104.2 v1(4.96,104.2) ; U25.A1 3,90.02 v1(3.15,89.87) ; U16.1 20.1,107.22 20.5,106.82 20.5,106.36 v1(20.78,106.08) ; TP49.1 v1(79.41,54.11)
  L03_SIG01 w0.102: v1(38.44,73.87) 39.87,72.44 v1(39.87,66.7) 40.41,66.16 40.91,66.16 41.25,66.5 41.25,67.92 v1(41.67,68.34) ; v1(2.85,71.03) 3.76,70.12 4.52,70.12 7.68,73.27 7.68,80.27 7.96,80.55 7.96,84.08 5.13,86.91 3.88,86.91 2.88,87.91 2.88,89.6 v1(3.15,89.87)
  L05_SIG02 w0.102: v1(4.96,104.2) 4.96,106.97 5.34,107.35 5.34,115.81 8.03,118.5 8.03,120.16 10.26,122.39 10.26,125.59 7.6,128.26 7.6,131.73 6.32,133.01 6.32,138.5 5.16,139.66 3.63,139.66 3.33,139.96 3.33,146.55 7.93,151.15 26.68,151.15 28.18,152.66 36.51,152.66 37.01,152.16 38.76,152.16 40.53,153.93 46.72,153.93 47.49,153.17 v1(50.01,153.17) ; v1(30.53,66.65) 31.31,67.43 v1(32.49,67.43) 34.28,67.43 v1(35.07,66.65) 35.64,67.22 36.25,67.22 37.19,66.28 39.45,66.28 v1(39.87,66.7) 40.32,67.15 41.1,67.15 41.73,66.51 45.51,66.51 46.22,65.8 46.22,61.77 47.53,60.47 47.53,53.6 47.12,53.19 47.12,48.92 49.12,46.93 v1(49.12,44.39) 49.79,44.39 51.21,42.97 51.21,42.05 52.96,40.3 53.41,40.3 v1(54.2,39.51) 54.71,39 55.63,39 56.47,38.16 58.95,38.16 60.68,36.44 63.78,36.44 65.91,38.56 65.91,41.97 65.56,42.31 65.56,43.86 67.66,45.95 67.66,49.18 69.33,50.86 78,50.86 79.41,52.27 v1(79.41,54.11)
  L10_SIG03 w0.102: v1(3.15,89.87) 3.59,90.32 3.59,91.33 3.09,91.82 3.09,92.65 5.18,94.74 5.18,103.97 v1(4.96,104.2) ; v1(32.28,108.46) 31.88,108.86 31.88,109.5 31.72,109.66 31.2,109.66 30.83,110.03 27.16,110.03 25.04,107.91 23.08,107.91 21.25,106.08 v1(20.78,106.08) 19.03,106.08 16.72,108.4 16.72,110.48 15.92,111.28 v1(15.89,111.28)
  BOTTOM w0.14: U92.29 v1(54.2,39.51) ; U87.2 48.78,45.08 48.6,44.9 R433.2 v1(49.12,44.39) ; U84.A1 v1(35.07,66.65) ; U85.A1 v1(30.53,66.65) ; U85.B3 32.39,67.53 v1(32.49,67.43) 33.33,67.43 33.58,67.17 33.58,66.21 33.17,65.8 29.36,65.8 28.43,66.74 27.1,66.74 26.18,65.82 24.92,65.82 24.82,65.92 13.42,65.92 12.21,67.14 9.8,67.14 6.89,70.04 3.89,70.04 2.9,71.03 v1(2.85,71.03) 3.1,71.29 U82.A1 ; R406.1 v1(79.41,54.11) ; v1(41.67,68.34) 41.67,68.09 41.51,67.93 U83.C3 ; v1(4.96,104.2) 5.08,104.32 5.08,104.43 v1(6.69,106.04) 7.05,105.68 9.41,105.68 9.91,106.18 15.6,106.18 16.36,105.42 19.59,105.42 20.26,106.08 v1(20.78,106.08) ; U83.A1 v1(39.87,66.7)
SOC_I2C1_SDA: length 328
  TOP w0.132: v1(16.69,111.25) U13.2 ; U18.E17 v1(33.88,108.46)
  TOP w0.14: TP50.1 v1(80.43,54.11) ; U29.6 v1(37.68,73.87) ; U17.A2 4.68,105.16 v1(4.37,104.85) ; U2.30 49.51,153.58 v1(50.01,154.08) ; v1(20.02,106.54) 20.1,106.46 U16.6 ; U25.A2 v1(2.22,89.42)
  L03_SIG01 w0.102: v1(37.68,73.87) 38.22,74.41 39.14,74.41 40.7,72.86 v1(40.7,66.65) ; v1(2.22,89.42) 2.63,89.01 2.63,87.84 3.79,86.68 5.04,86.68 7.73,83.99 7.73,81.23 7.45,80.95 7.45,73.52 4.88,70.96 v1(3.63,70.96)
  L05_SIG02 w0.102: v1(80.43,54.11) 80.43,52.38 78.61,50.55 69.67,50.55 68.27,49.15 68.27,45.85 66.88,44.46 66.88,37.07 65.64,35.83 64.06,35.83 63.83,36.06 60.73,36.06 58.91,37.89 54.91,37.89 v1(54.2,38.6) 48.11,44.69 v1(47.02,44.69) 47.02,47.47 46.36,48.13 46.36,52.75 47.21,53.6 47.21,60.36 45.99,61.58 45.99,65.58 45.38,66.19 41.15,66.19 v1(40.7,66.65) 40.06,66 36.59,66 v1(35.95,66.65) 35.53,66.23 33.94,66.23 33.2,66.97 31.73,66.97 31.41,66.65 v1(31.41,66.65) ; v1(50.01,154.08) 49.32,153.39 47.59,153.39 46.83,154.16 40.35,154.16 38.61,152.41 37.21,152.41 36.68,152.95 28.04,152.95 26.55,151.46 7.77,151.46 2.98,146.68 2.98,139.86 3.41,139.43 5.06,139.43 6.07,138.43 6.07,132.93 7.37,131.64 7.37,128.06 9.96,125.46 9.96,122.49 7.67,120.21 7.67,118.53 5.11,115.96 5.11,107.58 4.7,107.18 4.7,105.56 4.37,105.23 v1(4.37,104.85)
  L10_SIG03 w0.102: v1(16.69,111.25) 17.04,110.91 17.04,109.26 19.76,106.54 v1(20.02,106.54) 20.83,107.35 21.31,107.35 22.68,108.73 23.95,108.73 24.11,108.57 25.01,108.57 25.24,108.8 25.24,109.2 26.31,110.28 30.92,110.28 31.11,110.46 32.46,110.46 32.68,110.24 32.68,109.84 32.85,109.66 33.28,109.66 33.48,109.46 33.48,108.95 33.88,108.55 v1(33.88,108.46) ; v1(4.37,104.85) 4.37,104.15 4.85,103.67 4.85,94.83 2.72,92.69 2.72,90.68 2.22,90.18 v1(2.22,89.42)
  BOTTOM w0.14: U85.A2 v1(31.41,66.65) 30.92,66.16 29.59,66.16 28.68,67.07 25.36,67.07 24.59,66.3 13.62,66.3 12.27,67.65 10.11,67.65 7.28,70.49 6.53,70.49 6.07,70.96 v1(3.63,70.96) 3.5,71.09 U82.A2 ; U92.30 53.7,39.1 v1(54.2,38.6) ; U84.A2 v1(35.95,66.65) ; v1(4.37,104.85) 4.49,104.85 5.2,105.57 5.2,106.29 5.59,106.68 6.75,106.68 7.19,106.24 9.35,106.24 9.58,106.46 15.86,106.46 16.56,105.77 19.24,105.77 v1(20.02,106.54) ; v1(47.02,44.69) 47.32,44.39 R434.2 47.71,44.93 47.51,45.12 U87.3 ; U83.A2 v1(40.7,66.65) ; R405.1 v1(80.43,54.11)
SOC_I2C1_TA_SCL: length 50.3
  TOP w0.14: R166.2 v1(48.62,49.21)
  L03_SIG01 w0.102: v1(48.62,49.21) 48.62,45.78 50.31,44.09 50.31,42.95 52.69,40.57 56.12,40.57 59.66,37.02 v1(59.66,36.45) 59.25,36.45 58.8,36.9 57.36,36.9 55.78,35.32 55.78,29.45 54.42,28.09 54.42,25.22 53.21,24.01 53.21,23.04 53.48,22.76 v1(54.53,22.76)
  BOTTOM w0.14: v1(54.53,22.76) 54.53,19.62 56.25,17.91 56.25,16.85 55.83,16.43 R545.1 ; v1(48.62,49.21) 48.62,49.75 48.78,49.91 U87.7 ; v1(59.66,36.45) 59.93,36.45 R464.1
SOC_I2C1_TA_SDA: length 52.1
  TOP w0.14: R165.2 v1(47.63,49.21)
  L03_SIG01 w0.102: v1(47.63,49.21) 48.11,49.7 49.01,49.7 49.7,49.01 49.7,46.33 50.72,45.32 50.72,43.11 52.94,40.88 56.14,40.88 60.13,36.89 60.13,36.02 v1(59.66,35.56) 58.78,35.56 58.04,36.3 57.37,36.3 56.06,34.99 56.06,29.17 54.82,27.93 54.82,24.37 v1(53.68,23.23)
  BOTTOM w0.14: v1(47.63,49.21) 47.63,49.73 47.51,49.85 U87.6 ; v1(53.68,23.23) 53.68,17.99 53.29,17.6 R550.1 ; v1(59.66,35.56) 60.84,36.73 R466.1
SOC_I2C2_SCL: length 29
  TOP w0.132: U18.M22 v1(40.28,112.46)
  TOP w0.14: v1(43.31,137.37) 43.42,137.48 U5.12
  BOTTOM w0.14: v1(43.31,137.37) 43.31,137.37 R279.2 43.03,136.81 42.69,136.47 42.69,134.94 43.54,134.09 43.54,132.5 43.37,132.34 43.37,127.2 41.13,124.96 41.13,118.89 40.78,118.54 40.78,112.96 v1(40.28,112.46)
SOC_I2C2_SDA: length 32.1
  TOP w0.132: U18.M20 v1(40.28,110.86)
  TOP w0.14: U5.13 v1(44.07,137.39)
  BOTTOM w0.14: v1(44.07,137.39) 44.07,137.39 R278.2 44.76,136.81 45.57,136.01 45.57,134.99 46,134.56 46,127.42 43.94,125.36 43.94,124.27 41.57,121.9 41.57,118.85 41.19,118.47 41.19,112.51 40.68,112 40.68,111.26 v1(40.28,110.86)
SOC_MMC0_CLK: length 2.1
  TOP w0.14: v1(49.15,99.69) 48.26,99.69 U18.AB7
  BOTTOM w0.14: v1(49.15,99.69) 49.4,99.94 R343.2
SOC_MMC0_CMD: length 32.8
  TOP w0.132: U18.Y6 v1(46.68,98.87)
  TOP w0.14: v1(56.67,77.51) 56.67,77.26 U28.M5
  L05_SIG02 w0.102: v1(56.67,77.51) 55.48,77.51 54.84,78.15 53.56,78.15 53.07,78.64 53.07,78.82 53.29,79.05 53.29,79.23 53.17,79.35 52.99,79.35 52.76,79.13 52.58,79.13 52.46,79.25 52.46,79.43 52.68,79.66 52.68,79.84 52.56,79.96 52.38,79.96 52.15,79.74 51.97,79.74 51.85,79.86 51.85,80.04 52.07,80.27 52.07,80.45 51.94,80.57 51.77,80.57 51.54,80.35 51.36,80.35 50.53,81.18 50.53,91.02 51.66,92.15 51.66,93.98 48.77,96.87 48.77,97.38 48.49,97.67 48.11,97.67 47.88,97.9 47.88,98.24 47.65,98.47 47.08,98.47 v1(46.68,98.87)
  BOTTOM w0.14: R372.2 v1(56.67,77.51)
SOC_MMC0_DAT0: length 32.9
  TOP w0.132: U18.AA6 v1(47.48,98.87)
  TOP w0.14: U28.A3 55.92,82.89 53.4,85.41 v1(53.4,85.72) R113.2
  L05_SIG02 w0.102: v1(47.48,98.87) 48.08,98.87 49.1,97.84 49.1,97 51.97,94.13 51.97,92.03 50.83,90.89 50.83,81.58 51.13,81.29 52.96,81.29 53.21,81.54 53.21,82.76 53.67,83.22 53.67,85.45 v1(53.4,85.72)
SOC_MMC0_DAT1: length 33.5
  TOP w0.102: U28.A4 56.42,83.31
  TOP w0.14: v1(50.03,98.81) 48.33,98.81 U18.AB6 ; R115.2 v1(54.92,85.76) 55.7,84.98 55.7,84.02 56.42,83.31
  L05_SIG02 w0.102: v1(54.92,85.76) 54.92,81 54.68,80.75 53.87,80.75 53.64,80.98 53.64,82.68 54.03,83.08 54.03,85.44 54.59,85.99 54.59,87.48 53.19,88.88 53.19,94.72 50.33,97.58 50.33,98.52 v1(50.03,98.81)
SOC_MMC0_DAT2: length 33.3
  TOP w0.14: U18.Y7 v1(46.68,99.67) ; R117.2 56.5,86.65 v1(56.5,86.12) 57.09,85.53 57.09,83.43 56.92,83.26 U28.A5
  L05_SIG02 w0.102: v1(46.68,99.67) U18.Y7 46.28,100.72 46.43,100.87 48.25,100.87 49.04,100.08 49.37,100.08 50.74,98.71 50.74,97.62 53.55,94.81 53.55,89.13 55.16,87.52 55.16,86.13 55.35,85.95 55.35,83.57 55.8,83.11 56.37,83.11 56.83,83.58 56.83,85.41 56.5,85.75 v1(56.5,86.12)
SOC_MMC0_DAT3: length 32.9
  TOP w0.081: 55.17,82.7 55.17,82.26 U28.B2
  TOP w0.132: U18.AA7 v1(47.48,99.67)
  TOP w0.14: 55.17,82.7 54.94,82.93 54.66,82.93 51.88,85.72 v1(51.88,85.73) R111.2
  L05_SIG02 w0.102: v1(47.48,99.67) 48.17,99.67 49.71,98.12 49.71,97.25 52.58,94.38 52.58,91.79 52.57,91.78 52.57,91.77 51.45,90.65 51.45,87.11 51.56,87 51.99,87 52.11,86.88 52.11,86.72 52,86.62 51.56,86.62 51.45,86.51 51.45,83.94 51.71,83.69 52.45,83.69 52.55,83.79 52.55,84.03 52.45,84.14 51.92,84.14 51.81,84.25 51.81,84.41 51.92,84.52 52.45,84.52 52.56,84.63 52.56,84.79 52.45,84.9 51.92,84.9 51.81,85.01 51.81,85.17 51.92,85.28 52.45,85.28 52.56,85.39 52.56,85.6 52.39,85.78 51.92,85.78 v1(51.88,85.73)
SOC_MMC0_DAT4: length 32.6
  TOP w0.081: U28.B3 55.67,82.26 55.67,82.7
  TOP w0.132: U18.Y8 v1(46.68,100.47)
  TOP w0.14: 55.67,82.7 55.05,83.31 54.85,83.31 52.64,85.53 v1(52.64,86.17) R112.2
  L05_SIG02 w0.102: v1(46.68,100.47) 47.08,100.07 48.22,100.07 50.02,98.26 50.02,97.4 52.89,94.53 52.89,91.23 52.77,91.12 52.58,91.12 52.46,91.01 52.46,90.85 52.58,90.74 52.77,90.74 52.89,90.63 52.89,90.37 52.77,90.26 51.93,90.26 51.82,90.15 51.82,89.99 51.93,89.88 52.77,89.88 52.89,89.77 52.89,89.61 52.77,89.5 51.93,89.5 51.82,89.39 51.82,89.23 51.93,89.12 52.77,89.12 52.89,89.01 52.89,88.85 52.77,88.74 51.93,88.74 51.82,88.63 51.82,88.47 51.93,88.36 52.49,88.36 52.59,88.26 52.59,87.46 52.75,87.31 53.88,87.31 54,87.2 54,87.04 53.89,86.93 52.75,86.93 52.64,86.82 v1(52.64,86.17)
SOC_MMC0_DAT5: length 32.7
  TOP w0.081: 56.17,82.93 56.17,82.26 U28.B4
  TOP w0.132: U18.W7 v1(45.88,99.67)
  TOP w0.14: R114.2 v1(54.16,86.17) 54.16,85.93 55.26,84.83 55.26,84 56.17,83.09 56.17,82.93
  L05_SIG02 w0.102: v1(45.88,99.67) 46.28,99.26 48.14,99.26 49.41,97.99 49.41,97.65 49.41,97.12 52.28,94.26 52.28,91.9 51.14,90.77 51.14,83.76 51.68,83.21 53.05,83.21 53.35,83.52 53.35,84.58 53.01,84.92 53.01,85.91 53.27,86.17 v1(54.16,86.17)
SOC_MMC0_DAT6: length 32.5
  TOP w0.081: 56.67,83.4 56.67,82.26 U28.B5
  TOP w0.132: U18.W9 v1(45.88,101.26)
  TOP w0.14: R116.2 v1(55.69,86.17) 56.67,85.18 56.67,83.4
  L05_SIG02 w0.102: v1(55.69,86.17) 55.68,86.17 55.68,84.01 55.84,83.86 56.33,83.86 56.52,84.04 56.52,85.21 56.09,85.63 56.09,87.13 53.88,89.35 53.88,94.95 51.41,97.42 51.41,98.48 50.95,98.94 50.95,99.02 49.53,100.44 49.27,100.44 48.05,101.67 46.28,101.67 v1(45.88,101.26)
SOC_MMC0_DAT7: length 33.4
  TOP w0.081: U28.B6 57.17,82.26 57.17,83.12 57.36,83.31
  TOP w0.14: 57.36,83.31 57.5,83.44 57.5,85.91 v1(57.3,86.11) 57.3,86.61 R118.2 ; v1(49.47,100.86) U18.AB8
  L05_SIG02 w0.102: v1(57.3,86.11) 57.76,86.11 58.29,85.58 58.29,82.84 57.96,82.5 57.45,82.5 57.23,82.72 57.23,85.56 56.9,85.9 56.9,86.85 54.21,89.54 54.21,95.09 51.72,97.58 51.72,98.61 51.27,99.05 51.27,99.29 49.69,100.86 v1(49.47,100.86)
SOC_MMC2_CLK: length 2.5
  TOP w0.14: U18.H22 36.3,112.45 36.3,112.57 v1(35.48,113.39)
  BOTTOM w0.14: R316.1 35.61,113.52 v1(35.48,113.39)
SOC_OSPI_DQ0: length 7.7
  TOP w0.132: U18.J21 v1(37.08,111.66)
  TOP w0.14: v1(36.4,116.37) 35.86,116.91 RA1.7
  L05_SIG02 w0.102: v1(36.4,116.37) 37.64,115.14 37.64,113.23 37.08,112.67 v1(37.08,111.66)
SOC_OSPI_DQ1: length 11.3
  TOP w0.132: U18.J18 v1(37.08,109.26)
  TOP w0.14: RA2.8 38.68,117.39 38.82,117.25 v1(39.09,117.25)
  L05_SIG02 w0.102: v1(39.09,117.25) 39.56,116.77 39.56,113.03 39.65,112.94 39.65,111.89 39.03,111.26 38.51,111.26 38.47,111.26 38.28,111.07 38.28,110.7 38.05,110.47 38.03,110.46 37.68,110.46 37.48,110.26 37.48,109.89 37.08,109.49 v1(37.08,109.26)
SOC_OSPI_DQ2: length 9.9
  TOP w0.132: U18.J19 v1(37.08,110.07)
  TOP w0.14: RA2.7 38.28,116.91 v1(38.82,116.37)
  L05_SIG02 w0.102: v1(38.82,116.37) 38.92,116.28 38.92,112.84 39.09,112.67 39.09,112.3 38.85,112.07 38.54,112.07 38.54,112.06 38.51,112.06 38.28,111.83 38.28,111.5 38.05,111.26 37.71,111.26 37.48,111.03 37.48,110.73 37.48,110.72 37.48,110.69 37.08,110.29 v1(37.08,110.07)
SOC_OSPI_DQ3: length 10.3
  TOP w0.132: U18.H18 v1(36.28,109.26)
  TOP w0.14: v1(34.92,116.37) 35.46,116.91 RA1.6
  L05_SIG02 w0.102: v1(34.92,116.37) 36.26,115.03 36.26,112.21 35.88,111.83 35.88,109.9 36.28,109.5 v1(36.28,109.26)
SOC_OSPI_DQ4: length 7.4
  TOP w0.132: U18.K21 v1(37.88,111.66)
  TOP w0.14: RA2.5 37.48,117.43 v1(37.34,117.29)
  L05_SIG02 w0.102: v1(37.34,117.29) 37.83,116.8 37.83,116.11 38.28,115.65 38.28,112.4 38.28,112.28 37.88,111.88 v1(37.88,111.66)
SOC_OSPI_DQ5: length 9.3
  TOP w0.132: U18.H19 v1(36.28,110.06)
  TOP w0.14: RA1.5 35.06,117.43 v1(34.92,117.29)
  L05_SIG02 w0.102: v1(34.92,117.29) 35.56,116.64 35.56,116.18 36.68,115.06 36.68,110.46 v1(36.28,110.06)
SOC_OSPI_DQ6: length 8.4
  TOP w0.132: U18.J20 v1(37.08,110.86)
  TOP w0.14: RA2.6 37.88,116.91 v1(37.34,116.37)
  L05_SIG02 w0.102: v1(37.08,110.86) 37.08,111.08 37.48,111.48 37.48,111.53 37.48,112.63 37.94,113.09 37.94,115.47 37.34,116.07 v1(37.34,116.37)
SOC_OSPI_DQ7: length 6.7
  TOP w0.132: U18.J22 37.08,112.47 37.08,113.38 v1(37.14,113.44)
  TOP w0.14: v1(36.4,117.29) 36.26,117.43 RA1.8
  L05_SIG02 w0.102: v1(37.14,113.44) 37.14,115.07 36.02,116.19 36.02,116.9 v1(36.4,117.29)
SOC_PORZ: length 46.7
  L03_SIG01 w0.102: v1(51.33,36.99) 53.12,36.99 53.67,36.44 53.67,35.47 52.96,34.76 52.96,29 47.83,23.87 44.37,23.87 39.63,19.13 37.62,19.13 37.05,18.56 v1(32.58,18.56)
  BOTTOM w0.14: v1(32.58,18.56) 31.44,18.56 30.62,17.74 30.62,16.76 31.01,16.37 R544.2 31.84,16.37 31.93,16.46 U116.4 ; U96.3 56.41,37.53 56.26,37.68 54.57,37.68 54.44,37.55 54.44,36.99 54.3,36.85 52.24,36.85 52.1,36.99 51.77,36.99 51.76,36.99 v1(51.33,36.99)
SOC_RGMII_MDC: length 67.9
  TOP w0.132: U18.V12 v1(45.08,104.46)
  TOP w0.14: R108.1 63.26,89.49 63.87,88.88 v1(63.87,88.71) ; v1(57.27,115.88) 57.07,115.68 J4.16
  L03_SIG01 w0.102: v1(57.27,115.88) 57.66,115.48 60.48,115.48 v1(60.91,115.91) ; v1(63.87,88.71) 63.37,88.21 60.53,88.21 60.18,88.56 58.83,88.56 58.35,89.04 58.35,89.54 57.78,90.11 55.43,90.11 54.26,91.28 54.26,96.47 53.39,97.33 53.39,98.37 53.52,98.5 53.52,102.65 52.6,103.57 51.57,103.57 50.84,104.31 49.25,104.31 48.94,104.62 48.94,104.63 48.7,104.86 45.48,104.86 v1(45.08,104.46)
  L05_SIG02 w0.102: v1(60.91,115.91) 60.91,115.64 62.16,114.39 62.16,100.78 61.85,100.47 61.85,100.12 62.05,99.91 62.05,98.02 62.46,97.62 62.46,90.84 62.74,90.56 62.74,89.84 v1(63.87,88.71)
SOC_RGMII_MDIO: length 70.5
  TOP w0.132: U18.V13 v1(45.08,105.26)
  TOP w0.14: R107.1 60.85,88.78 v1(60.91,88.71) ; v1(55.76,115.88) 55.96,116.08 J4.18
  L03_SIG01 w0.102: v1(60.91,88.71) 60.91,89.47 60.52,89.86 58.92,89.86 58.4,90.38 55.53,90.38 54.48,91.42 54.48,96.64 53.9,97.23 53.9,97.58 54.39,98.07 54.39,102.54 52.3,104.63 49.41,104.63 48.38,105.67 45.48,105.67 v1(45.08,105.26) ; v1(60.91,116.75) 61.39,116.27 61.39,114.91 61.17,114.68 56.95,114.68 v1(55.76,115.88)
  L05_SIG02 w0.102: v1(60.91,116.75) 60.45,116.29 60.45,106.62 60.86,106.21 60.86,103.44 61.06,103.24 61.06,102.3 60.89,102.12 60.89,100.98 60.43,100.52 60.43,100.06 60.71,99.78 60.99,99.78 61.19,99.58 61.19,98.49 60.33,97.63 60.33,89.93 60.91,89.34 v1(60.91,88.71)
SOC_SPI0_CLK: length 89.9
  TOP w0.14: v1(29.72,107.2) 29.72,107.68 30.28,108.24 30.9,108.24 U18.A17
  L10_SIG03 w0.102: v1(29.72,107.2) 28.7,106.19 27.13,106.19 25.35,104.41 22.11,104.41 21.5,103.8 20.66,103.8 20.1,104.36 16.08,104.36 11.75,108.69 11.75,110.03 11.38,110.4 11.38,111.14 12.27,112.03 12.27,121.72 11.64,122.35 11.64,124.11 14.04,126.51 19.28,126.51 20.63,127.85 20.63,132.21 21.27,132.86 22.86,132.86 23.64,132.07 24.21,132.07 34.11,132.07 34.91,132.87 36.49,132.87 37.19,132.17 44.36,132.17 47.99,135.8 v1(47.99,136.65)
  BOTTOM w0.14: v1(47.99,136.65) 48.43,136.21 50.64,136.21 50.87,136.44 U55.4
SOC_SPI0_CS0: length 105.4
  TOP w0.132: U18.D16 v1(33.08,107.66)
  L10_SIG03 w0.102: v1(58.91,139.51) 52.94,139.51 52.06,138.63 50.32,138.63 49.51,137.82 48.15,137.82 47.33,136.99 47.33,135.87 44.09,132.63 37.49,132.63 36.79,133.33 34.71,133.33 33.91,132.53 24.02,132.53 23.83,132.53 22.99,133.36 21.06,133.36 20.37,132.68 19.2,132.68 17.96,131.43 17.96,127.6 17.31,126.95 13.83,126.95 11.12,124.23 11.12,122.56 10.86,122.31 10.86,120.68 11.07,120.48 11.07,119.49 9.27,117.69 9.27,111.86 10.72,110.41 10.72,107.4 14.93,103.19 19.56,103.19 19.67,103.31 21.19,103.31 21.63,102.86 22.08,102.86 23.15,103.93 25.66,103.93 27.4,105.67 30.85,105.67 31.08,105.9 31.08,106.23 31.31,106.46 31.65,106.46 31.88,106.7 31.88,107.03 32.11,107.26 32.6,107.26 33,107.66 v1(33.08,107.66)
  BOTTOM w0.14: v1(58.91,139.51) 58.43,139.04 U55.9
SOC_SPI0_D0: length 92.2
  TOP w0.132: U18.B15 v1(31.48,106.86)
  L10_SIG03 w0.102: v1(31.48,106.86) 31.25,106.86 30.85,106.47 30.51,106.47 30.01,105.96 27.36,105.96 25.59,104.18 22.21,104.18 21.58,103.55 20.29,103.55 19.71,104.13 15.76,104.13 11.09,108.79 11.09,110.37 9.5,111.96 9.5,117.39 11.37,119.26 11.37,120.6 11.12,120.86 11.12,122.18 11.35,122.41 11.35,124.14 13.95,126.74 17.54,126.74 18.29,127.5 18.29,131.31 19.38,132.4 20.42,132.4 21.13,133.11 22.93,133.11 23.74,132.3 23.93,132.3 24.12,132.3 34.01,132.3 34.81,133.1 36.64,133.1 37.34,132.4 44.26,132.4 47.58,135.71 47.58,136.81 48.36,137.59 50.16,137.59 v1(50.78,138.21)
  BOTTOM w0.14: v1(50.78,138.21) 50.95,138.39 U55.7
SOC_SPI2_CLK: length 118.8
  TOP w0.132: U18.A21 30.68,111.66 v1(30.3,111.66)
  TOP w0.14: U54.8 26.68,39.01 v1(26.89,39.22)
  L05_SIG02 w0.102: v1(30.3,111.66) 27.31,111.66 26.16,112.81 25.84,112.81 24.55,114.1 21.16,114.1 20.62,113.56 16.63,113.56 16.08,113.01 15.11,113.01 14.32,112.22 14.32,111.24 13.03,109.96 13.03,109.18 9.35,105.5 9.35,100.34 9.58,100.12 9.58,97.5 9.28,97.21 9.28,95.08 9.24,95.04 9.24,93.16 9.01,92.93 9.01,90.09 7.98,89.05 7.98,87.91 8.54,87.35 8.54,79.12 6.21,76.79 6.21,68.58 5.5,67.87 5.5,61.1 9.95,56.66 11.28,56.66 14.2,53.73 14.2,51.11 15.28,50.03 16.2,50.03 18.1,48.14 22.16,48.14 22.43,47.87 22.43,47.45 22.77,47.12 23.06,47.12 23.47,46.71 23.47,39.56 22.73,38.82 22.73,38.27 23.01,37.99 24.04,37.99 24.99,38.94 26.61,38.94 v1(26.89,39.22)
  BOTTOM w0.14: v1(26.89,39.22) 26.45,39.66 26.25,39.66 25.88,40.03 U95.7
SOC_SPI2_CS0: length 110.2
  TOP w0.132: U18.B21 v1(31.48,111.66)
  TOP w0.14: v1(23.22,38.46) 23.47,38.21 U54.6
  L05_SIG02 w0.102: v1(31.48,111.66) 31.08,111.26 27.28,111.26 26.04,112.51 25.71,112.51 24.98,113.24 16.76,113.24 16.22,112.7 15.28,112.7 14.69,112.11 14.69,111.17 13.86,110.34 13.86,109.58 9.65,105.37 9.65,100.5 9.88,100.27 9.88,97 10.19,96.69 10.19,96.41 10.05,96.27 10.05,93.5 9.39,92.84 9.39,88.62 8.85,88.08 8.85,78.99 6.52,76.67 6.52,68.45 5.81,67.75 5.81,61.22 10.05,56.99 11.41,56.99 14.51,53.89 14.51,52.19 18.23,48.46 22.68,48.46 23.79,47.34 23.79,39.02 v1(23.22,38.46)
  BOTTOM w0.14: v1(23.22,38.46) 23.61,38.08 U95.4
SOC_SPI2_D0: length 117.5
  TOP w0.132: U18.C19 v1(32.28,110.06)
  TOP w0.14: U54.7 24.67,38.61 25.33,37.95 26.43,37.95 v1(26.91,38.43)
  L05_SIG02 w0.102: v1(26.91,38.43) 27.4,38.92 27.4,39.42 27.14,39.68 26.31,39.68 25.15,40.83 25.15,41.32 24.08,42.4 24.08,47.53 22.92,48.69 18.33,48.69 14.73,52.28 14.73,54.01 11.53,57.21 10.14,57.21 6.17,61.19 6.17,67.71 6.81,68.36 6.81,76.64 9.08,78.9 9.08,84.69 9.82,85.43 9.82,92.95 10.28,93.41 10.28,96.17 10.42,96.31 10.42,96.79 10.11,97.09 10.11,100.38 9.94,100.55 9.94,104.92 14.68,109.66 14.68,110.8 14.95,111.06 14.95,111.99 15.44,112.48 16.86,112.48 17.01,112.32 24.52,112.32 25.17,111.67 25.63,111.67 26.59,110.71 30.6,110.71 30.85,110.46 31.67,110.46 32.07,110.06 v1(32.28,110.06)
  BOTTOM w0.14: U95.9 28.3,40.68 27.91,40.28 27.91,39.43 v1(26.91,38.43)
SOC_SPI2_D1: length 116.6
  TOP w0.132: U18.B19 v1(31.48,110.06)
  TOP w0.14: U54.9 23.62,39.68 23.87,39.93 25.98,39.93 26.28,39.63 27.5,39.63 28.7,38.43 v1(28.74,38.43)
  L05_SIG02 w0.102: v1(31.48,110.06) 30.6,110.06 30.31,110.36 25.6,110.36 23.9,112.06 16.68,112.06 16.3,111.67 16.3,111 16.48,110.83 16.48,110.27 16.15,109.94 16.15,109.52 15.11,108.49 14.5,108.49 12.36,106.35 12.36,104.75 12.11,104.5 11.98,104.5 11.43,103.94 10.51,103.94 10.17,103.6 10.17,100.65 10.39,100.43 10.39,98.86 11.07,98.18 11.07,96.61 10.54,96.08 10.54,93.25 10.04,92.76 10.04,85.34 9.3,84.59 9.3,78.81 7.04,76.54 7.04,68.27 6.44,67.67 6.44,61.23 10.24,57.44 11.76,57.44 14.96,54.24 14.96,52.37 18.41,48.93 23.14,48.93 25.9,46.17 25.9,42.86 27.91,40.85 27.91,39.26 v1(28.74,38.43)
  BOTTOM w0.14: v1(28.74,38.43) 29.03,38.73 U95.12
SOC_TCK: length 177.9
  TOP w0.132: U18.A14 v1(30.68,106.07)
  L03_SIG01 w0.102: v1(36.57,60.05) 35.3,60.05 33.26,58.02 33.26,47.88 32.7,47.32 32.7,43.53 33.1,43.13 33.1,38.39 31.61,36.9 31.61,34.67 31.93,34.35 31.93,31.89 30.41,30.37 30.41,26.53 29.77,25.9 29.77,22.62 30.41,21.98 30.41,15.9 32.1,14.2 47.04,14.2 50.27,17.43 50.27,18.22 50.64,18.6 v1(52.42,18.6)
  L05_SIG02 w0.102: v1(36.57,60.05) 36.57,59.77 35.57,58.78 17.69,58.78 15.39,61.07 15.39,65.73 16.37,66.71 16.37,67 18.09,68.72 18.09,70.77 17.5,71.35 17.5,75.79 16.87,76.42 16.87,83.22 16.13,83.96 16.13,84.88 16.58,85.32 16.58,88.32 16.91,88.65 16.91,91.13 16.81,91.24 16.81,92.75 16.46,93.1 16.46,95.66 16.15,95.96 16.15,98.33 16.75,98.94 16.75,101.27 18.49,103.01 19.12,103.01 19.83,103.72 19.83,104 20.74,104.92 21.59,104.92 22.77,106.1 30.65,106.1 v1(30.68,106.07)
  L10_SIG03 w0.102: v1(67.96,22.55) 68.84,22.55 69.09,22.3 69.09,20.9 68.87,20.68 68.05,20.68 67.72,20.36 64.04,20.36 63.6,19.92 60,19.92 59.67,20.25 58.1,20.25 57.43,19.58 56.54,19.58 55.55,18.6 v1(52.42,18.6)
  BOTTOM w0.14: v1(67.96,22.55) 67.96,23.02 R515.1 ; v1(52.42,18.6) 51.72,18.6 R529.1
SOC_TDI: length 166.5
  TOP w0.132: U18.A16 v1(30.68,107.66)
  L05_SIG02 w0.102: v1(49.77,17.7) 49.77,25.14 48.77,26.14 33.93,26.14 29.19,30.88 29.19,35.1 30.07,35.99 30.07,45.94 28.23,47.78 28.23,49.27 27.34,50.16 26.09,50.16 24.81,51.44 22.24,51.44 20.56,53.11 17.76,53.11 17.74,53.14 17.7,53.14 11.32,59.53 10.59,59.53 8.67,61.45 8.67,67.31 8.37,67.6 8.37,75.73 10.31,77.67 10.31,80.56 11.04,81.28 11.04,92.2 11.5,92.66 11.5,95.75 12.02,96.27 12.02,98.52 11.61,98.93 11.61,99.31 11.61,100.27 11.76,100.41 11.76,101.84 15.85,105.93 15.85,107.24 17.12,108.51 17.12,109.57 17.79,110.25 22.31,110.25 24.41,108.15 28.22,108.15 28.71,107.66 v1(30.68,107.66)
  L10_SIG03 w0.102: v1(65.78,22.55) 64.19,24.13 52.04,24.13 49.77,21.87 v1(49.77,17.7)
  BOTTOM w0.14: U114.9 49.46,18.02 v1(49.77,17.7) ; U111.6 66.74,21.95 66.57,22.13 66.4,22.13 65.98,22.55 v1(65.78,22.55)
SOC_TDO: length 180.9
  L03_SIG01 w0.102: v1(35.58,59.62) 35.58,59.13 33.75,57.3 33.75,40.15 34.08,39.82 34.08,38.59 33.34,37.86 33.34,37.02 32.74,36.42 32.74,32.19 30.71,30.16 30.71,16.07 32.27,14.5 46.68,14.5 49.29,17.11 49.29,18.59 50.79,20.09 53.03,20.09 53.73,20.79 v1(55.74,20.79) 55.74,20.32 54.26,18.84 54.26,12.1 50.92,8.77 42.86,8.77 v1(40.77,6.68)
  L05_SIG02 w0.102: v1(35.58,59.62) 35.04,59.08 18.71,59.08 16.64,61.15 16.22,61.15 15.78,61.6 15.78,65.37 16.68,66.27 16.68,66.88 18.39,68.59 18.39,74 19.07,74.68 19.07,76.13 18.02,77.18 18.02,82.44 17.69,82.77 17.44,82.77 17.26,82.94 17.26,83.66 17.8,84.19 17.8,84.8 17.44,85.15 17.44,88.28 17.91,88.75 17.91,91.15 17.67,91.39 17.67,93 17.06,93.61 17.06,100.44 17.48,100.85 18.17,100.85 18.84,101.52 18.84,102.29 20.22,103.67 20.22,103.89 20.93,104.61 21.82,104.61 22.49,105.28 v1(27.84,105.28)
  BOTTOM w0.14: R326.1 v1(27.84,105.28) ; U122.2 41.13,7.81 41.26,7.68 41.26,7.17 v1(40.77,6.68) ; U109.2 56.34,20.67 56.22,20.79 v1(55.74,20.79)
SOC_TDO_R: length 4.2
  TOP w0.132: U18.C14 v1(32.28,106.06)
  BOTTOM w0.14: v1(32.28,106.06) 31.88,105.66 30.19,105.66 29.81,105.28 R326.2
SOC_TMS: length 167.6
  TOP w0.132: U18.B14 v1(31.48,106.06)
  L03_SIG01 w0.102: v1(34.46,60.05) 32.72,58.31 32.72,47.88 32.21,47.37 32.21,37.99 30.94,36.72 30.94,31.36 30.1,30.52 30.1,26.89 28.69,25.47 28.69,22.57 29.39,21.87 29.39,18.68 29.05,18.34 29.05,16.81 31.97,13.89 47.35,13.89 50.77,17.31 v1(50.77,17.72)
  L05_SIG02 w0.102: v1(31.48,106.06) 31.25,106.06 30.85,105.67 29.39,105.67 28.6,104.88 22.56,104.88 21.43,103.75 20.71,103.75 19.75,102.79 19.75,101.83 18.54,100.62 18.31,100.62 17.91,100.22 17.91,94.83 18.5,94.24 18.5,91.11 18.28,90.88 18.28,90.69 18.28,90.69 18.28,88.76 18.51,88.53 18.51,85.87 19.92,84.46 19.92,74.56 20.53,73.95 20.53,71.31 19.83,70.61 19.83,66.05 20.44,65.43 20.44,61.35 21.97,59.82 34.23,59.82 v1(34.46,60.05)
  L10_SIG03 w0.102: v1(68.52,21.9) 68.18,21.55 65.41,21.55 65.13,21.28 64.27,21.28 63.88,21.67 61.86,21.67 60.96,20.77 56.56,20.77 56.05,21.28 51.98,21.28 50.77,20.07 v1(50.77,17.72)
  BOTTOM w0.14: U111.8 67.54,21.74 67.69,21.9 v1(68.52,21.9) ; U114.8 50.27,18.69 50.74,18.22 50.74,17.75 v1(50.77,17.72)
SOC_TRST#: length 139.8
  TOP w0.132: U18.F15 v1(34.68,106.86)
  L03_SIG01 w0.102: v1(51.67,22.65) 51.67,24.58 53.19,26.1 53.19,34.56 53.98,35.35 53.98,36.56 51.15,39.39 50.44,39.39 48.97,40.86 47.35,40.86 46.19,42.02 46.19,45.17 46.86,45.83 46.86,47.55 46.19,48.22 46.19,50.41 48.42,52.63 48.42,53.61 48.87,54.06 48.87,58.92 v1(49.89,59.93)
  L05_SIG02 w0.102: v1(68.51,21.1) 66.23,21.1 65.22,22.12 64.21,22.12 63.82,21.73 56.41,21.73 55.89,22.26 53.59,22.26 53.2,22.65 v1(51.67,22.65) ; v1(49.89,59.93) 49.08,60.75 49.08,68.11 38.94,78.24 34.89,78.24 34.04,79.09 28.17,79.09 24.95,82.32 24.95,91.12 25.22,91.4 25.22,94.65 26.33,95.76 26.33,98.1 26.81,98.58 29.62,98.58 30.3,99.27 33.26,99.27 33.48,99.49 33.48,99.85 33.7,100.07 34.05,100.07 34.28,100.3 34.28,100.66 34.49,100.87 34.88,100.87 35.08,101.07 35.08,106.46 v1(34.68,106.86)
  BOTTOM w0.14: v1(68.51,21.1) 68.33,20.93 U111.9 ; U114.6 51.08,19.49 R526.1 51.1,19.94 51.67,20.51 v1(51.67,22.65)
SOC_UART0_RX_3V3: length 140.3
  TOP w0.132: U18.E14 v1(33.88,106.06)
  L05_SIG02 w0.102: v1(22.07,14.49) 22.38,14.79 22.38,28.21 23.96,29.79 23.96,33.58 26.42,36.04 28.15,36.04 29.44,37.33 29.44,40.23 27.67,42.01 27.67,45.88 25.35,48.2 25.35,49.26 23.77,50.85 19.04,50.85 17.34,52.54 16.03,52.54 15.42,53.15 15.42,54.57 11.36,58.64 9.74,58.64 7.45,60.92 7.45,67.25 7.72,67.53 7.72,76.57 9.76,78.61 9.76,80.88 10.51,81.63 10.51,92.5 11.05,93.03 11.05,95.94 11.55,96.45 11.55,98.34 10.96,98.94 10.96,100.55 10.67,100.84 10.67,102.47 11.55,103.35 12.54,103.35 13.48,104.29 13.48,106.13 16.66,109.31 16.66,109.76 17.6,110.71 23.67,110.71 24.87,109.51 25.35,109.51 25.48,109.64 28,109.64 29.26,108.38 31,108.38 31.31,108.07 32.45,108.07 32.68,107.83 32.68,106.7 32.91,106.47 33.48,106.47 v1(33.88,106.06)
  BOTTOM w0.14: v1(22.07,14.49) 21.53,14.49 21.11,14.07 U119.8
SOC_UART0_TX_3V3: length 141.8
  TOP w0.132: U18.D15 v1(33.08,106.86)
  L05_SIG02 w0.102: v1(33.08,106.86) 33.48,107.27 33.48,107.86 33.28,108.07 32.91,108.07 32.68,108.3 32.68,108.65 32.47,108.86 29.45,108.86 28.31,110.01 25.55,110.01 23.83,111.73 17.46,111.73 17.09,111.36 17.09,110.51 16.43,109.86 16.43,109.49 12.64,105.69 12.64,104.63 12.28,104.27 12.22,104.27 12.08,104.27 10.4,102.59 10.4,100.74 10.63,100.51 10.63,98.94 11.32,98.26 11.32,96.53 10.79,96.01 10.79,93.13 10.29,92.62 10.29,81.98 9.53,81.22 9.53,78.71 7.35,76.53 7.35,68.2 6.69,67.53 6.69,61.31 10.33,57.67 11.92,57.67 15.19,54.4 15.19,52.98 16.34,51.83 17.73,51.83 19.61,49.96 22.43,49.96 23.2,49.19 24.17,49.19 24.47,48.89 24.47,48.25 26.79,45.93 26.79,42.43 29.15,40.06 29.15,38.19 28.93,37.97 28.64,37.97 28.34,37.67 28.34,37.17 28.09,36.92 26.12,36.92 23.61,34.41 23.61,33.85 20.17,30.41 v1(20.17,14.86)
  BOTTOM w0.14: U119.6 20.31,14.72 v1(20.17,14.86) 20.38,15.07 R558.2
SOC_UART1_CTS: length 40.9
  TOP w0.14: TP91.1 v1(30.13,6.97)
  L03_SIG01 w0.102: v1(27.81,38.43) 28.45,37.8 29.86,37.8 30.48,37.17 30.48,31.74 29.64,30.9 29.64,27.31 28.16,25.83 28.16,22.4 28.83,21.73 28.83,20.61 27.6,19.38 27.6,18.72 28.2,18.12 28.2,10.92 28.38,10.74 28.38,8.73 v1(30.13,6.97)
  BOTTOM w0.14: U123.9 29.72,7.1 29.85,6.97 v1(30.13,6.97) ; U95.10 29.01,40.03 27.81,38.83 v1(27.81,38.43)
SOC_UART1_CTS_BT: length 135.3
  TOP w0.14: v1(14.09,36.65) 14.18,36.65 14.66,37.13 16.14,37.13 16.9,37.89 18.21,37.89 18.93,38.61 U54.14 ; v1(6.03,143.53) 6.77,142.79 J2.34
  L03_SIG01 w0.102: v1(14.09,36.65) 11.74,39 11.74,52.37 10.79,53.33 10.79,54.25 10.25,54.78 6.54,54.78 0.77,60.54 0.77,90.96 1.36,91.55 1.36,92.63 1.07,92.93 1.07,97.62 10.32,106.88 10.32,109.79 9.13,110.99 9.13,121.56 9.88,122.32 9.88,124.89 7.28,127.5 7.28,130.73 4.73,133.28 4.73,136.73 5.36,137.36 5.36,142.87 v1(6.03,143.53)
SOC_UART1_RTS: length 34.8
  TOP w0.14: TP90.1 29.75,8.44 v1(29.58,8.27)
  L03_SIG01 w0.102: v1(31.34,37.95) 30.71,37.32 30.71,31.53 29.87,30.7 29.87,27.22 28.44,25.78 28.44,22.45 29.06,21.82 29.06,19.61 28.43,18.97 28.43,11.01 29.58,9.86 v1(29.58,8.27)
  BOTTOM w0.14: v1(29.58,8.27) 29.78,8.06 U123.7 ; v1(31.34,37.95) 31.22,38.08 U95.13
SOC_UART1_RTS_BT: length 134.8
  TOP w0.14: v1(6.97,143.55) 7.22,143.29 J2.36 ; U54.12 22.42,39.63 22.22,39.83 19.44,39.83 18.98,39.37 18.45,39.37 17.72,38.64 16.5,38.64 15.89,38.04 14.59,38.04 v1(14.1,37.55)
  L03_SIG01 w0.102: v1(14.1,37.55) 13,38.65 13,47.73 12.73,48.01 12.73,53.6 11.79,54.53 11.79,55.04 11.11,55.73 7.03,55.73 3.84,58.92 3.84,64.82 1.2,67.46 1.2,72.31 1.92,73.03 1.92,76.3 1,77.22 1,89.61 1.63,90.23 1.63,92.96 1.29,93.3 1.29,97.53 10.55,106.78 10.55,109.89 9.35,111.08 9.35,121.32 10.11,122.07 10.11,125 7.5,127.61 7.5,130.85 5.83,132.53 5.83,142.41 v1(6.97,143.55)
SOC_UART1_RX_BT: length 134.3
  TOP w0.14: v1(7.4,142.21) 7.94,141.67 7.94,140.89 9.03,139.79 J2.22 ; v1(14.89,36.66) 16.43,36.66 16.82,37.04 17.82,37.04 18.99,38.21 U54.15
  L03_SIG01 w0.102: v1(14.89,36.66) 14.5,37.05 14.5,38.19 13.3,39.38 13.3,47.72 13.56,47.98 13.56,54.04 10.86,56.75 6.48,56.75 4.1,59.12 4.1,64.88 1.43,67.55 1.43,72.21 2.15,72.93 2.15,76.45 1.23,77.38 1.23,89.52 1.86,90.14 1.86,93.06 1.52,93.39 1.52,97.43 10.95,106.86 10.95,110.68 12.25,111.98 12.25,118.91 10.38,120.78 10.38,125.08 7.73,127.72 7.73,130.95 6.08,132.6 6.08,138.91 7.4,140.23 v1(7.4,142.21)
SOC_UART1_RXD: length 39.8
  L03_SIG01 w0.102: v1(30.95,7.12) 30.95,6.69 30.26,6.01 28.83,6.01 26.32,8.52 26.32,10.71 27.43,11.82 27.43,18.01 27.05,18.4 27.05,19.21 26.57,19.69 26.57,29.96 25.41,31.12 25.41,37.08 25.71,37.38 v1(25.77,37.38)
  BOTTOM w0.14: U95.3 25.73,37.43 v1(25.77,37.38) ; TP72.1 31.43,6.63 v1(30.95,7.12) 30.95,7.12 30.95,7.4 30.69,7.66 U123.8
SOC_UART1_TX_BT: length 134.2
  TOP w0.14: v1(14.9,37.54) 15.93,37.54 16.68,38.28 17.97,38.28 18.64,38.94 19.01,38.94 19.6,39.54 21.05,39.54 21.57,39.01 U54.13
  L03_SIG01 w0.102: v1(7.61,144.31) 7.61,142.93 7.88,142.67 7.88,140.25 6.31,138.68 6.31,132.69 7.96,131.04 7.96,127.87 10.6,125.23 10.6,120.9 12.52,118.98 12.52,111.01 11.3,109.78 11.3,106.89 1.75,97.34 1.75,93.68 2.08,93.35 2.08,90.05 1.82,89.78 1.82,88.09 2.03,87.88 2.03,83.94 1.46,83.38 1.46,79.03 3.21,77.28 3.21,72.21 2.4,71.41 2.4,66.9 4.36,64.95 4.36,59.33 6.55,57.13 10.93,57.13 13.81,54.25 13.81,39.42 14.9,38.34 v1(14.9,37.54)
  BOTTOM w0.14: R254.2 6.47,143.94 6.85,144.31 v1(7.61,144.31)
SOC_UART1_TXD: length 49.4
  L03_SIG01 w0.102: v1(33.34,10.35) 33.02,10.35 30.54,7.87 30.54,6.65 30.15,6.26 28.96,6.26 26.55,8.68 26.55,10.61 27.66,11.73 27.66,18.22 27.28,18.6 27.28,19.45 26.88,19.86 26.88,30.02 25.64,31.25 25.64,36.49 26.32,37.17 26.32,38.88 v1(25.78,39.42)
  BOTTOM w0.14: v1(25.78,39.42) 25.74,39.38 U95.6 ; TP71.1 33.31,10.38 v1(33.34,10.35) 32.7,9.71 32.7,8.62 32.2,8.11 R570.2 31.46,8.46 U123.6
SOC_USB0_DM: length 139.6
  TOP w0.102: v1(67.82,65.42) 67.82,65.16 69.05,63.93 69.05,54.31 68.26,53.52 68.26,42.19 67.4,41.33 67.4,38.76 66.37,37.73 63.44,37.73 60.49,34.78 56.87,34.78 56.14,34.05 40.76,34.05 39.99,33.28 36.95,33.28 35.12,31.45 34.26,31.45 30.95,28.14 30.95,26.56 28.93,24.54 20.12,24.54 17.37,27.29 17.37,28.76 16.28,29.84 15.24,29.84 15.14,29.74 15.14,29.62 15.03,29.52 L7.4 ; U18.AA10 v1(47.48,102.07)
  L03_SIG01 w0.102: v1(67.82,65.42) 67.41,65.42 66.75,66.08 66.75,67.07 65.59,68.24 65.59,70.42 62.92,73.09 62.92,84.01 61.93,85 60.83,85 60.06,85.77 60.06,86.4 57.86,88.61 55.96,88.61 53.52,91.05 53.52,96.2 51.62,98.11 51.62,98.65 50.14,100.13 50.14,101.14 49.72,101.56 48.32,101.56 48.06,101.82 47.72,101.82 v1(47.48,102.07)
SOC_USB0_DP: length 139.6
  TOP w0.102: L7.1 15.03,30.37 15.14,30.27 15.14,30.16 15.24,30.05 16.37,30.05 17.58,28.84 17.58,27.38 20.2,24.75 28.84,24.75 30.74,26.65 30.74,28.23 34.17,31.66 35.03,31.66 36.86,33.49 39.91,33.49 40.68,34.26 56.05,34.26 56.78,34.99 60.4,34.99 63.35,37.94 66.28,37.94 67.19,38.85 67.19,41.42 68.05,42.27 68.05,53.61 68.84,54.4 68.84,63.84 67.63,65.05 67.46,65.05 v1(67.22,64.82) ; U18.AA9 v1(47.48,101.27)
  L03_SIG01 w0.102: v1(67.22,64.82) 67.4,65 67.4,65.14 66.55,65.99 66.55,66.99 65.38,68.15 65.38,70.34 62.72,73.01 62.72,83.93 61.84,84.8 60.74,84.8 59.86,85.68 59.86,86.32 57.77,88.4 55.88,88.4 53.32,90.96 53.32,96.12 51.41,98.02 51.41,98.57 49.94,100.04 49.94,101.06 49.64,101.36 48.24,101.36 47.98,101.62 47.58,101.62 47.48,101.52 v1(47.48,101.27)
SOC_USB0_DRVVBUS: length 94.9
  TOP w0.132: U18.C20 v1(32.28,110.86)
  L03_SIG01 w0.102: v1(32.28,110.86) 32.29,110.86 32.69,110.47 33.25,110.47 33.47,110.24 33.47,110.24 33.48,110.23 33.48,109.87 33.68,109.67 34.05,109.67 34.28,109.44 34.28,108.3 34.05,108.07 33.72,108.07 33.48,107.83 33.48,107.5 33.25,107.26 30.37,107.26 29.01,105.9 27.38,105.9 25.43,103.95 21.95,103.95 21.35,103.35 19.98,103.35 18.86,102.23 18.86,101.28 17.93,100.35 17.93,95.82 16.79,94.68 16.79,92.42 16.42,92.05 15.68,92.05 12.58,88.95 12.58,85.43 10.35,83.19 10.35,80.78 10.35,76.5 10.35,76.12 12.99,73.48 12.99,68.27 11.42,66.71 11.42,60.1 16.97,54.56 v1(16.97,50.94) 18.49,49.41 18.49,40.32 v1(18.82,39.99)
  BOTTOM w0.14: R446.1 v1(18.82,39.99) ; R416.1 v1(16.97,50.94)
SOC_USB0_RCALIB: length 4.4
  TOP w0.132: U18.W10 v1(45.88,102.07)
  BOTTOM w0.14: R331.1 48.35,103.01 47.81,102.47 46.28,102.47 v1(45.88,102.07)
SOC_USB0_VBUS: length 13.7
  TOP w0.356: U18.V8 v1(45.08,100.47)
  TOP w0.457: v1(50.52,76.82) 52.2,75.14 R134.1
  L07_PWR02 w0.165: 47.93,100.86 45.48,100.86 v1(45.08,100.47) 45.48,100.07 47.93,100.07
  BOTTOM w0.305: v1(45.08,100.47) 45.2,100.59 R338.1
SOC_USB1_DM: length 42.4
  TOP w0.102: v1(62.08,77.62) 62.32,77.86 66.17,77.86 66.37,77.67 66.37,77.33 66.07,77.02 L4.1 ; U18.Y11 v1(46.68,102.87)
  L05_SIG02 w0.102: v1(46.68,102.87) 47.08,103.27 50.13,103.27 50.65,102.75 52.18,102.75 52.73,102.19 52.73,98.39 55.79,95.33 55.79,94.64 56.32,94.11 56.93,94.11 58.23,92.82 58.23,90.37 58.49,90.1 58.49,88.15 60.05,86.58 60.05,85.38 61.66,83.78 61.66,80.51 62.9,79.27 62.9,78.17 62.61,77.88 62.34,77.88 v1(62.08,77.62)
SOC_USB1_DP: length 42.7
  TOP w0.102: v1(62.08,78.33) 62.34,78.08 66.26,78.08 66.58,77.76 66.58,77.36 66.92,77.02 L4.4 ; U18.Y10 v1(46.68,102.07)
  L05_SIG02 w0.102: v1(62.08,78.33) 62.34,78.08 62.53,78.08 62.7,78.25 62.7,79.18 61.45,80.43 61.45,83.7 59.85,85.3 59.85,86.5 58.29,88.06 58.29,90.02 58.02,90.28 58.02,92.73 56.85,93.91 56.24,93.91 55.59,94.56 55.59,95.24 52.53,98.31 52.53,102.11 52.09,102.55 50.57,102.55 50.05,103.07 47.99,103.07 47.89,102.96 47.89,102.58 47.78,102.47 46.79,102.47 46.68,102.36 v1(46.68,102.07)
SOC_USB1_DRVVBUS: length 60.6
  TOP w0.132: U18.D19 v1(33.08,110.07)
  TOP w0.14: v1(55.54,91.11) 54.48,92.17 54.48,95.41 54.86,95.79 54.86,100.5 54.5,100.85 v1(53.93,100.85) ; R130.1 R128.2 v1(64.37,75.58)
  L05_SIG02 w0.102: v1(53.93,100.85) 53.93,102.25 52.62,103.56 51.7,103.56 51.29,103.97 44.21,103.97 43.88,104.3 43.88,104.63 43.65,104.86 43.63,104.86 37.64,104.86 37.48,105.02 37.48,105.46 37.27,105.66 36.89,105.66 36.68,105.87 36.68,106.23 36.45,106.46 36.11,106.46 35.88,106.7 35.88,107.03 35.65,107.26 35.64,107.26 35.31,107.26 35.08,107.5 35.08,108.65 34.86,108.86 34.51,108.86 34.49,108.89 34.28,109.1 34.28,109.43 34.05,109.66 34.04,109.67 U18.D19 v1(33.08,110.07)
  L10_SIG03 w0.102: v1(64.37,75.58) 63.56,76.39 61.71,76.39 60.86,77.24 60.86,80.07 60.25,80.68 60.25,81.65 58.52,83.38 58.52,85.7 55.54,88.69 v1(55.54,91.11)
SOC_USB1_RCALIB: length 6.3
  TOP w0.132: U18.U7 v1(44.28,99.67)
  BOTTOM w0.14: R344.1 47.84,98.47 44.07,98.47 43.88,98.66 43.88,99.24 44.28,99.64 v1(44.28,99.67)
SOC_USB1_VBUS: length 38.1
  TOP w0.254: v1(62.25,83.5) 62.71,83.96 65.89,83.96 R124.1 ; U18.V6 v1(45.08,98.87)
  L03_SIG01 w0.14: v1(45.08,98.87) U18.V6 44.68,99.91 44.83,100.07 48,100.07 48.39,99.67 47.98,99.27 45.48,99.27 v1(45.08,98.87)
  L03_SIG01 w0.254: 48.39,99.67 49.81,98.25 50.43,98.25 52.83,95.85 52.83,90.41 56.35,86.89 57.48,86.89 60.84,83.52 62.23,83.52 v1(62.25,83.5)
  BOTTOM w0.305: v1(45.08,98.87) 45.2,98.99 R345.1
SOC_VDDSHV5_SDIO: length 2.6
  TOP w0.356: U18.H15 v1(36.28,106.86) ; U18.G16 v1(35.48,107.66)
  TOP w0.381: R61.2 v1(23.35,108.3)
  BOTTOM w0.254: v1(23.35,108.3) 23.69,107.95 C224.1
  BOTTOM w0.305: C226.1 35.36,107.54 v1(35.48,107.66)
SOC_VOUT0_DATA0: length 48.3
  TOP w0.132: U18.U22 v1(44.28,112.46)
  TOP w0.14: U13.32 24.67,119.27 v1(24.41,119.02)
  L10_SIG03 w0.102: v1(44.28,112.46) 44.28,112.79 43.84,113.23 43.84,113.85 43.71,113.98 43.34,113.98 43.18,114.14 43.18,114.39 43.3,114.5 43.87,114.5 43.99,114.62 43.99,114.79 43.87,114.91 43.3,114.91 43.18,115.03 43.18,115.2 43.3,115.32 43.87,115.32 43.99,115.44 43.99,115.6 43.87,115.72 43.3,115.72 43.18,115.84 43.18,116.01 43.3,116.13 43.87,116.13 43.99,116.25 43.99,116.42 43.87,116.54 43.3,116.54 43.18,116.66 43.18,117.53 42.86,117.85 42.28,117.85 42.13,117.69 42.13,115.83 42.02,115.73 39.71,115.73 39.55,115.89 39.55,117.38 39.66,117.49 40.08,117.49 40.26,117.67 40.26,118.45 40.1,118.61 38.44,118.61 38.27,118.78 38.27,119.29 38.43,119.45 40.04,119.45 40.26,119.68 40.26,120.13 40.09,120.31 35.45,120.31 35.3,120.16 35.3,119.55 35.18,119.42 33.81,119.42 33.53,119.14 32.82,119.14 32.7,119.26 32.7,119.72 32.58,119.84 32.41,119.84 32.29,119.72 32.29,119.26 32.17,119.14 32,119.14 31.88,119.26 31.88,119.72 31.76,119.84 31.6,119.84 31.48,119.72 31.48,119.26 31.36,119.14 31.19,119.14 31.07,119.26 31.07,119.72 30.95,119.84 30.78,119.84 30.66,119.72 30.66,119.26 30.55,119.14 30.38,119.14 30.26,119.26 30.26,119.72 30.14,119.84 29.97,119.84 29.85,119.72 29.85,119.26 29.73,119.14 29.56,119.14 29.45,119.26 29.45,119.72 29.33,119.84 29.16,119.84 29.04,119.72 29.04,119.26 28.92,119.14 28.47,119.14 27.92,118.58 24.85,118.58 v1(24.41,119.02)
SOC_VOUT0_DATA1: length 48.1
  TOP w0.132: U18.U21 v1(44.28,111.66)
  TOP w0.14: v1(26.3,119.02) 26.05,118.77 U13.31
  L10_SIG03 w0.102: v1(44.28,111.66) 44.68,112.06 44.68,112.66 45.12,113.1 45.12,116.62 45,116.74 44.83,116.74 44.73,116.64 44.73,113.25 44.63,113.15 44.42,113.15 44.32,113.25 44.32,116.91 42.07,119.17 41.4,119.17 41.28,119.04 41.28,118.73 41.12,118.57 41.12,118.32 41.28,118.17 41.28,117.92 41.12,117.76 41.12,117.51 41.28,117.35 41.28,116.85 41.38,116.75 41.65,116.75 41.78,116.61 41.78,116.21 41.66,116.09 40.09,116.09 39.99,116.19 39.99,116.57 40.13,116.71 40.45,116.71 40.57,116.83 40.57,119.38 40.69,119.5 41.19,119.5 41.31,119.62 41.31,119.78 41.19,119.9 40.69,119.9 40.57,120.02 40.57,120.45 40.4,120.62 34.46,120.62 34.34,120.5 34.34,119.87 34.22,119.75 34.05,119.75 33.94,119.87 33.94,120.5 33.82,120.62 33.65,120.62 33.53,120.5 33.53,119.87 33.41,119.75 33.24,119.75 33.12,119.87 33.12,120.5 33,120.62 32.77,120.62 32.49,120.34 29.06,120.34 27.74,119.02 v1(26.3,119.02)
SOC_VOUT0_DATA2: length 48.4
  TOP w0.132: U18.U20 v1(44.28,110.86)
  TOP w0.14: U13.30 24.67,118.27 v1(24.41,118.02)
  L10_SIG03 w0.102: v1(44.28,110.86) 44.28,110.89 43.88,111.29 43.88,112.65 43.46,113.06 43.46,113.43 42.88,114.01 42.88,117.38 42.75,117.51 42.58,117.51 42.44,117.37 42.44,115.51 42.34,115.41 39.5,115.41 39.22,115.69 39.22,116.64 39.03,116.84 37.86,116.84 37.74,116.96 37.74,117.72 37.85,117.82 39.78,117.82 39.88,117.93 39.88,118.1 39.75,118.23 37.85,118.23 37.74,118.34 37.74,119.38 37.62,119.5 37,119.5 36.88,119.37 36.88,118.87 36.43,118.42 36.43,117.89 36.88,117.45 36.88,116.97 36.73,116.82 36.08,116.82 35.9,117.01 35.9,117.55 35.65,117.79 33.89,117.79 33.77,117.91 33.77,118.08 33.89,118.2 35.67,118.2 36.01,118.54 36.01,119.87 35.91,119.97 35.72,119.97 35.61,119.86 35.61,118.76 35.42,118.57 33.39,118.57 33.16,118.8 28.65,118.8 28.11,118.27 24.66,118.27 v1(24.41,118.02)
SOC_VOUT0_DATA3: length 48.7
  TOP w0.132: U18.U19 v1(44.28,110.06)
  TOP w0.14: v1(26.52,117.82) 26.47,117.77 U13.29
  L10_SIG03 w0.102: v1(44.28,110.06) 44.28,110.28 44.68,110.68 44.68,111.03 44.91,111.26 45.25,111.26 45.48,111.5 45.48,112.63 45.75,112.9 45.75,116.53 45.12,117.16 44.6,117.16 41.28,120.48 41.28,120.65 41.4,120.77 41.57,120.77 43.01,119.33 43.18,119.33 43.29,119.45 43.29,119.62 41.57,121.34 41.4,121.34 41,120.94 40.83,120.94 40.17,121.6 38.49,121.6 38.37,121.48 38.37,121.11 38.25,121 38.08,121 37.97,121.11 37.97,121.48 37.85,121.6 37.68,121.6 37.56,121.48 37.56,121.11 37.44,121 37.27,121 37.15,121.11 37.15,121.48 37.03,121.6 36.87,121.6 36.75,121.48 36.75,121.11 36.63,121 36.46,121 36.34,121.11 36.34,121.48 36.22,121.6 36.05,121.6 35.93,121.48 35.93,121.11 35.81,121 35.65,121 35.53,121.11 35.53,121.48 35.41,121.6 35.24,121.6 35.12,121.48 35.12,121.11 35,121 34.83,121 34.71,121.11 34.71,121.48 34.59,121.6 32.97,121.6 32.02,120.65 28.84,120.65 27.68,119.48 24.17,119.48 24,119.31 24,117.61 24.13,117.48 24.69,117.48 25.18,117.96 26.38,117.96 v1(26.52,117.82)
SOC_VOUT0_DATA4: length 47.9
  TOP w0.132: U18.T19 v1(43.48,110.06)
  TOP w0.14: U13.28 24.67,117.27 v1(24.41,117.02)
  L10_SIG03 w0.102: v1(43.48,110.06) 43.32,110.06 42.92,110.46 42.51,110.46 42.28,110.7 42.28,112.94 41.74,113.49 40.65,113.49 40.33,113.81 39.79,113.81 39.79,113.81 39.54,113.81 39.08,113.35 39.08,110.7 38.85,110.47 38.52,110.47 38.28,110.23 38.28,106.67 38.08,106.46 37.62,106.46 37.48,106.61 37.48,110.23 37.72,110.47 38.05,110.47 38.28,110.7 38.28,113.07 37.92,113.44 37.92,113.6 38.13,113.82 38.13,113.98 38.01,114.1 37.84,114.1 37.63,113.89 37.39,113.89 36.63,114.64 36.17,114.64 34.83,115.99 33.94,115.99 32.28,117.64 28.63,117.64 27.58,116.6 26.21,116.6 25.82,116.21 25.82,115.65 25.44,115.28 25.44,115.03 25.32,114.91 24.96,114.91 24.84,114.79 24.84,114.62 24.96,114.5 25.32,114.5 25.44,114.38 25.44,114.15 25.1,113.81 24.66,113.81 24,114.46 24,116.84 24.18,117.02 v1(24.41,117.02)
SOC_VOUT0_DATA5: length 48.3
  TOP w0.132: U18.U18 v1(44.28,109.26)
  TOP w0.14: v1(26.3,117.02) 26.05,116.77 U13.27
  L10_SIG03 w0.102: v1(26.3,117.02) 25.6,117.02 25.5,116.92 25.5,115.76 25.32,115.58 25.02,115.58 24.82,115.78 24.82,117.15 25.12,117.44 27.79,117.44 28.42,118.07 28.68,118.07 28.8,117.95 28.97,117.95 29.09,118.07 29.09,118.38 29.21,118.5 29.38,118.5 29.5,118.38 29.5,118.07 29.62,117.95 29.78,117.95 29.9,118.07 29.9,118.38 30.02,118.5 30.19,118.5 30.31,118.38 30.31,118.07 30.43,117.95 30.6,117.95 30.72,118.07 30.72,118.38 30.84,118.5 31,118.5 31.12,118.38 31.12,118.07 31.24,117.95 31.41,117.95 31.53,118.07 31.53,118.38 31.65,118.5 32.59,118.5 32.85,118.24 32.85,118.08 32.68,117.9 32.68,117.76 32.82,117.62 32.96,117.62 33.13,117.79 33.3,117.79 33.42,117.67 33.42,117.5 33.25,117.33 33.25,117.18 33.39,117.04 33.54,117.04 33.71,117.21 33.92,117.21 34.3,116.83 35.1,116.83 36.29,115.64 37.31,115.64 37.94,116.26 38.11,116.26 38.23,116.14 38.23,115.98 37.57,115.31 37.57,115.15 37.69,115.03 37.86,115.03 38.52,115.69 38.69,115.69 38.8,115.57 38.8,115.4 38.14,114.74 38.14,114.57 38.26,114.45 38.43,114.45 39.09,115.11 39.26,115.11 39.38,114.99 39.38,114.83 38.72,114.16 38.72,114 38.92,113.79 39.09,113.79 39.7,114.4 39.7,114.77 39.82,114.89 39.99,114.89 40.11,114.77 40.11,114.31 40.21,114.21 40.41,114.21 40.52,114.31 40.52,114.77 40.63,114.89 40.8,114.89 40.92,114.77 40.92,113.91 41.04,113.79 41.21,113.79 41.33,113.91 41.33,114.77 41.45,114.89 41.62,114.89 41.73,114.77 41.73,113.91 41.85,113.79 42.02,113.79 42.14,113.91 42.14,114.77 42.26,114.89 42.43,114.89 42.55,114.77 42.55,113.91 43.08,113.38 43.08,110.7 43.31,110.47 43.7,110.47 43.88,110.29 43.88,109.66 v1(44.28,109.26)
SOC_VOUT0_DATA6: length 50.1
  TOP w0.132: U18.V22 v1(45.08,112.46)
  TOP w0.14: v1(26.3,116.02) 26.05,115.77 U13.25
  L03_SIG01 w0.102: v1(26.3,116.02) 25.51,116.81 25.51,117.04 25.63,117.16 25.79,117.16 25.91,117.28 25.91,117.45 25.79,117.57 25.39,117.57 25.28,117.69 25.28,117.86 25.39,117.98 25.79,117.98 26.14,118.33 27,118.33 27.88,119.21 27.88,120.11 28,120.23 28.17,120.23 28.29,120.11 28.29,119.21 28.41,119.09 28.58,119.09 28.7,119.21 28.7,120.11 28.82,120.23 28.98,120.23 29.1,120.11 29.1,119.21 29.22,119.09 29.48,119.09 29.6,119.21 29.6,120.99 29.71,121.1 29.88,121.1 30.01,120.97 30.01,119.21 30.13,119.09 30.3,119.09 30.41,119.21 30.41,120.99 30.52,121.1 30.69,121.1 30.82,120.97 30.82,119.21 30.94,119.09 31.14,119.09 31.27,119.22 31.27,120.98 31.39,121.1 31.54,121.1 31.7,120.94 31.7,120.18 31.8,120.08 31.98,120.08 32.1,120.2 32.1,120.99 32.21,121.1 32.38,121.1 32.51,120.97 32.51,120.2 32.63,120.08 32.79,120.08 32.91,120.2 32.91,120.99 33.02,121.1 33.19,121.1 33.32,120.97 33.32,120.2 33.44,120.08 34.06,120.08 34.98,120.99 40.92,120.99 41.2,121.27 42.12,121.27 45.08,118.31 v1(45.08,112.46)
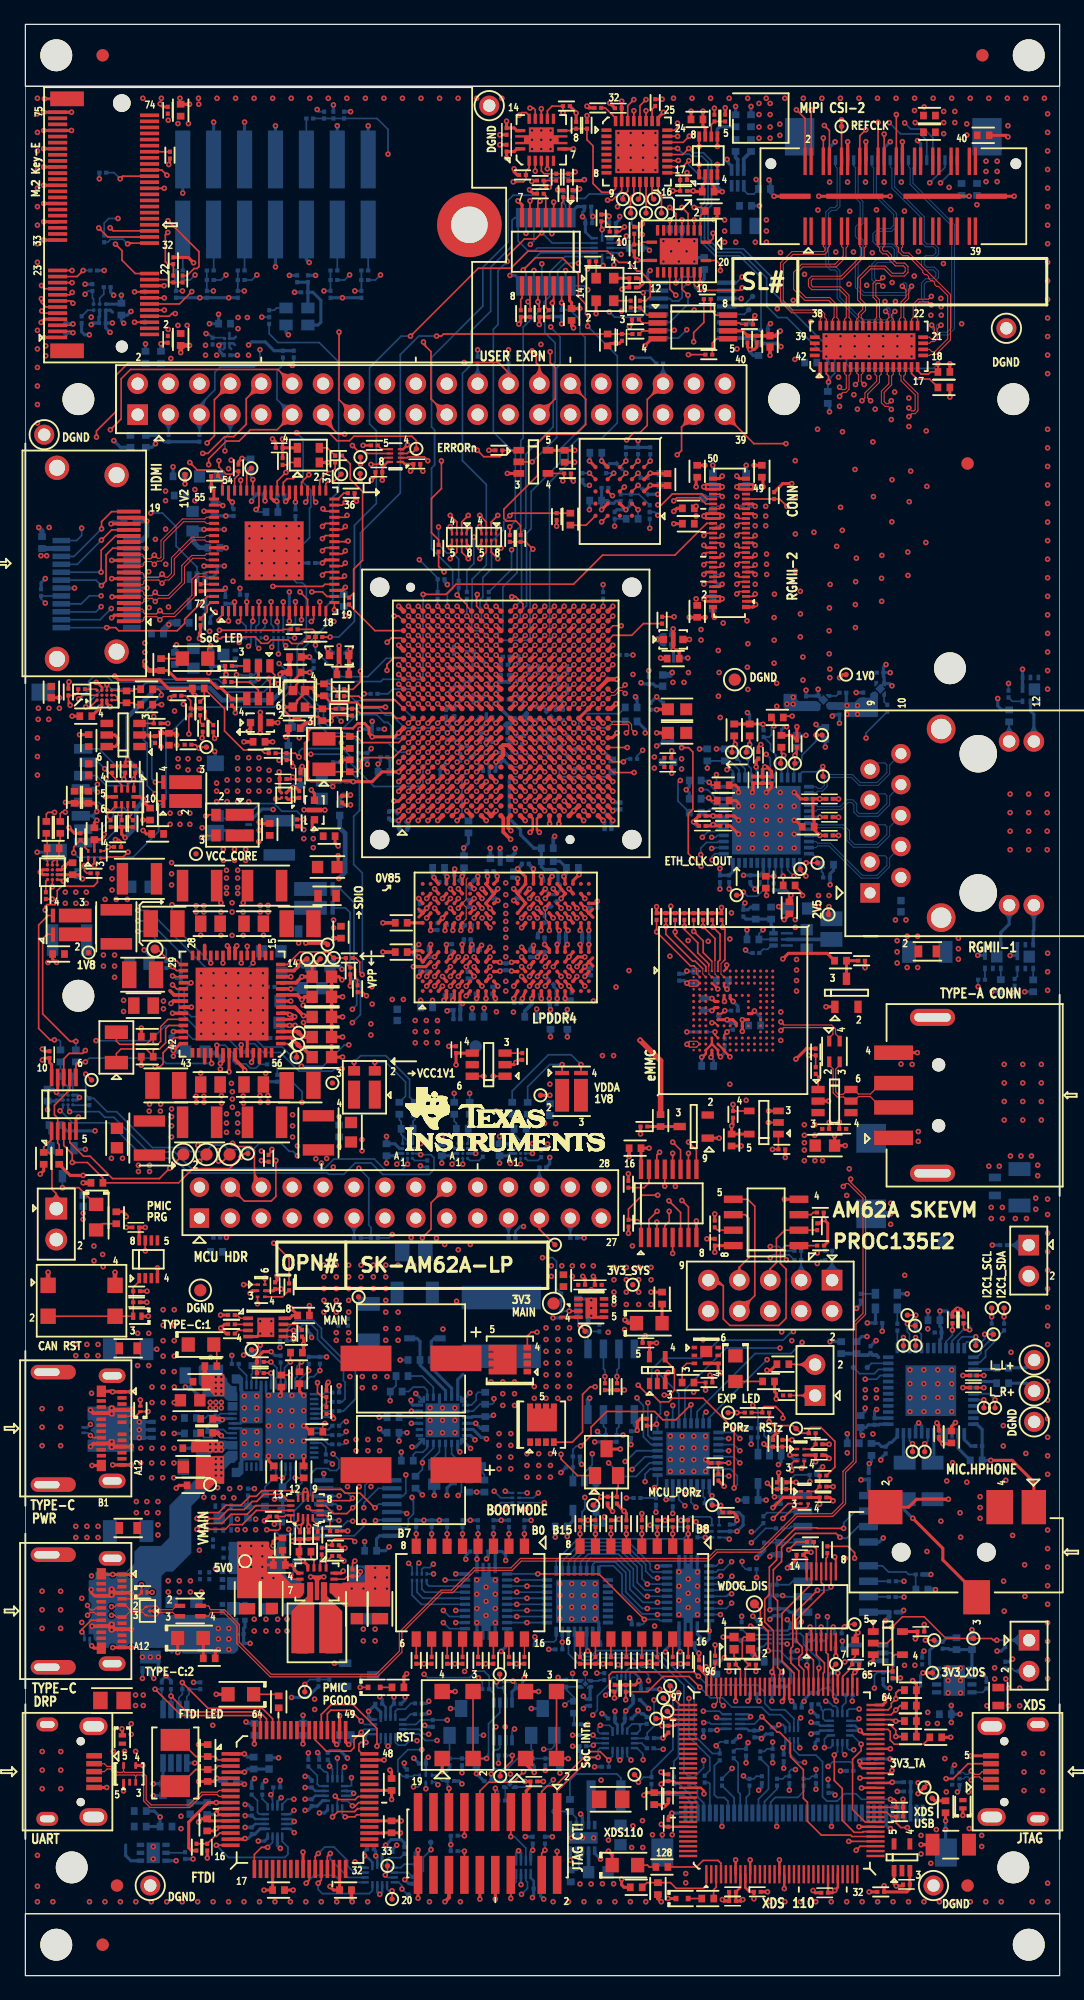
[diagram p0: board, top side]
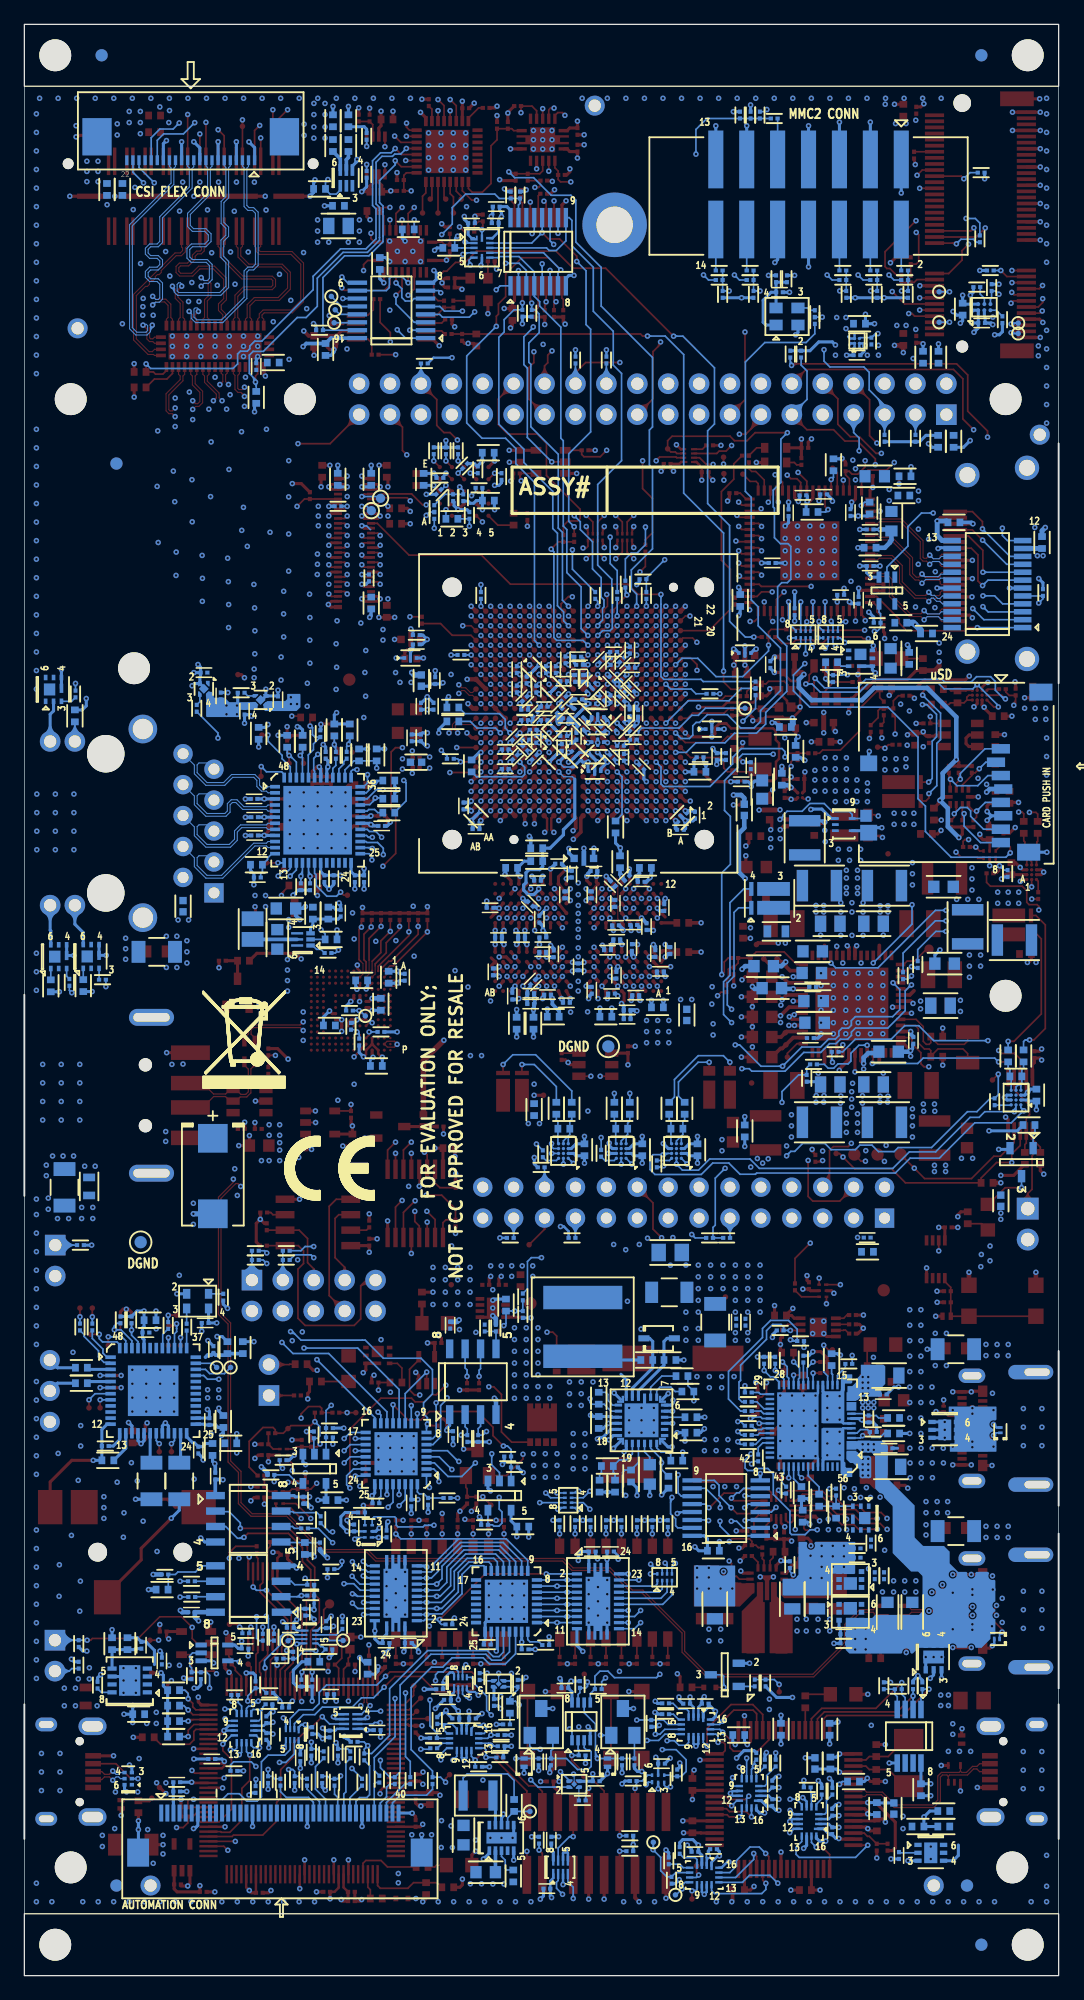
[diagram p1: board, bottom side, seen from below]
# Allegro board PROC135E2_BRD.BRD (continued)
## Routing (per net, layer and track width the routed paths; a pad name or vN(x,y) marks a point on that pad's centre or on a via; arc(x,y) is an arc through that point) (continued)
SOC_VOUT0_DATA7: length 50.2
  TOP w0.132: U18.V21 v1(45.08,111.66)
  TOP w0.14: U13.24 24.67,115.27 v1(24.41,115.02)
  L03_SIG01 w0.102: v1(24.41,115.02) 24.7,115.02 25.29,115.62 26.43,115.62 26.93,116.11 26.93,117.64 28.07,118.78 31.48,118.78 31.7,119.01 31.7,119.37 31.81,119.47 32.12,119.47 32.23,119.36 32.23,118.98 31.62,118.38 28.25,118.38 27.47,117.6 27.47,117.46 27.69,117.24 27.83,117.24 28.6,118.01 31.79,118.01 33.51,119.72 34.17,119.72 35.11,120.66 40.9,120.66 41.21,120.35 41.38,120.35 41.84,120.8 42.01,120.8 42.12,120.68 42.12,120.51 41.67,120.06 41.67,119.89 41.79,119.77 41.96,119.77 42.41,120.22 42.58,120.22 42.7,120.11 42.7,119.94 42.25,119.48 42.25,119.31 42.36,119.2 42.53,119.2 42.99,119.65 43.16,119.65 43.27,119.53 43.27,119.36 42.82,118.91 42.82,118.74 43.46,118.1 43.63,118.1 44.16,118.63 44.33,118.63 44.44,118.51 44.44,118.34 43.91,117.81 43.91,117.65 44.78,116.78 44.78,112.99 44.68,112.89 44.68,112.07 45.08,111.67 v1(45.08,111.66)
SOC_VOUT0_DATA8: length 50.3
  TOP w0.132: U18.V19 v1(45.08,110.06)
  TOP w0.14: v1(26.23,114.95) 26.23,114.95 26.05,114.77 U13.23
  L03_SIG01 w0.102: v1(26.23,114.95) 26.23,114.99 28.89,117.64 31.9,117.64 33.68,119.42 35.26,119.42 36.2,120.36 40.51,120.36 40.71,120.16 40.71,119.56 40.54,119.4 36,119.4 35.84,119.23 35.84,118.78 35.66,118.6 33.68,118.6 33.53,118.45 33.53,118.1 33.64,117.98 36.04,117.98 36.63,118.57 40.6,118.57 41.1,119.06 42.04,119.06 43.86,117.23 43.86,116.56 43.98,116.44 44.35,116.44 44.47,116.32 44.47,116.15 44.35,116.03 43.98,116.03 43.86,115.91 43.86,115.74 43.98,115.62 44.35,115.62 44.47,115.5 44.47,115.34 44.35,115.22 43.98,115.22 43.86,115.1 43.86,114.93 43.98,114.81 44.35,114.81 44.47,114.69 44.47,114.52 44.35,114.4 43.98,114.4 43.86,114.29 43.86,114.12 43.98,114 44.35,114 44.47,113.88 44.47,113.71 44.35,113.59 43.98,113.59 43.88,113.49 43.88,111.5 44.11,111.26 44.5,111.26 44.68,111.09 44.68,110.46 v1(45.08,110.06)
SOC_VOUT0_DATA9: length 48.6
  TOP w0.132: U18.V18 v1(45.08,109.26)
  TOP w0.14: U13.20 24.79,113.27 24.41,113.65 v1(23.54,113.65)
  L10_SIG03 w0.102: v1(23.54,113.65) 23.29,113.89 23.29,119.49 23.89,120.09 25.48,120.09 26.03,120.64 27.37,120.64 28.43,121.7 31.42,121.7 32.28,122.56 42.26,122.56 48.36,116.46 48.36,113.4 49.52,112.25 49.52,110.87 48.31,109.67 45.48,109.67 v1(45.08,109.26)
SOC_VOUT0_DATA10: length 49.4
  TOP w0.132: U18.W22 v1(45.88,112.47)
  TOP w0.14: v1(25.39,112.16) U13.19
  L03_SIG01 w0.102: v1(45.88,112.47) 45.88,118.39 41.72,122.54 38.93,122.54 38.82,122.43 38.82,122.09 38.68,121.96 38.37,121.96 38.25,122.07 38.25,122.4 38.13,122.52 37.96,122.52 37.84,122.4 37.84,122.07 37.72,121.96 37.52,121.96 37.4,122.07 37.4,122.4 37.28,122.52 37.11,122.52 36.99,122.4 36.99,122.07 36.87,121.96 36.71,121.96 36.59,122.07 36.59,122.4 36.47,122.52 36.3,122.52 36.18,122.4 36.18,122.07 36.06,121.96 35.89,121.96 35.77,122.07 35.77,122.4 35.65,122.52 35.49,122.52 35.37,122.4 35.37,122.07 35.25,121.96 35.08,121.96 34.96,122.07 34.96,122.4 34.84,122.52 34.67,122.52 34.55,122.4 34.55,122.07 34.44,121.96 34.27,121.96 34.15,122.07 34.15,122.4 34.03,122.52 33.86,122.52 33.74,122.4 33.74,122.07 33.62,121.96 33.45,121.96 33.33,122.07 33.33,122.4 33.22,122.52 33.05,122.52 32.93,122.4 32.93,122.07 32.81,121.96 32.64,121.96 32.52,122.07 32.52,122.4 32.4,122.52 32.23,122.52 32.12,122.4 32.12,122.07 32,121.96 31.83,121.96 31.71,122.07 31.71,122.4 31.59,122.52 31.42,122.52 31.3,122.4 31.3,122.07 31.18,121.96 31.02,121.96 30.9,122.07 30.9,122.4 30.78,122.52 30.61,122.52 30.49,122.4 30.49,122.07 30.37,121.96 29.43,121.96 29.07,121.6 26.95,121.6 26.75,121.4 26.75,120.89 26.38,120.53 25.99,120.53 25.58,120.11 25.58,119.95 25.75,119.77 25.75,119.6 25.63,119.48 25.46,119.48 25.35,119.59 25.14,119.59 24.93,119.38 24.93,118.84 24.57,118.48 24.19,118.48 24.01,118.3 24.01,115.97 23.66,115.62 23.66,114.61 25.39,112.88 25.39,112.16 v1(25.39,112.16)
SOC_VOUT0_DATA11: length 49.6
  TOP w0.132: U18.W21 v1(45.88,111.66)
  TOP w0.14: U13.18 24.69,111.52 25,111.22 v1(25.36,111.22)
  L03_SIG01 w0.102: v1(45.88,111.66) 45.48,112.06 45.48,118.34 42.22,121.6 41.38,121.6 41.26,121.72 41.26,122.07 41.15,122.19 40.98,122.19 40.86,122.07 40.86,121.72 40.74,121.6 40.57,121.6 40.45,121.72 40.45,122.07 40.33,122.19 40.17,122.19 40.05,122.07 40.05,121.72 39.93,121.6 39.76,121.6 39.64,121.72 39.64,122.07 39.52,122.19 39.35,122.19 39.23,122.07 39.23,121.72 39.11,121.6 34.27,121.6 34.15,121.48 34.15,120.9 34.03,120.78 33.86,120.78 33.74,120.9 33.74,121.48 33.62,121.6 29.54,121.6 28.63,120.69 27.79,120.69 26.53,119.43 26.03,119.43 24.95,118.35 24.95,115.86 24.57,115.49 24.1,115.49 23.96,115.35 23.96,114.75 24.78,113.93 25.12,113.93 25.3,114.11 25.59,114.11 26.11,113.6 26.11,112.51 25.88,112.27 25.88,111.93 25.65,111.7 24.99,111.7 24.88,111.8 24.88,112.31 24.78,112.41 24.52,112.41 24.42,112.31 24.42,110.9 24.52,110.8 24.93,110.8 v1(25.36,111.22)
SOC_VOUT0_DATA12: length 48.1
  TOP w0.132: U18.W20 v1(45.88,110.86)
  TOP w0.14: v1(24.19,112.83) U13.17
  L10_SIG03 w0.102: v1(45.88,110.86) 46.28,110.46 48.31,110.46 48.49,110.65 48.49,111.03 49.14,111.67 49.14,112.17 47.98,113.33 47.98,116.38 42.13,122.23 32.59,122.23 31.69,121.34 28.51,121.34 27.51,120.34 26.18,120.34 25.63,119.79 24.02,119.79 23.63,119.4 23.63,114.36 24.14,113.85 24.14,113.41 23.91,113.18 22.83,113.18 22.73,113.08 22.73,112.88 22.83,112.78 24.15,112.78 v1(24.19,112.83)
SOC_VOUT0_DATA13: length 49.7
  TOP w0.132: v1(23.5,111.21) 23.69,111.41 U13.16 ; U18.W19 v1(45.88,110.07)
  L03_SIG01 w0.102: v1(23.5,111.21) 23.5,110.7 23.65,110.54 23.88,110.54 24.05,110.71 24.05,112 23.7,112.36 23.7,113.05 23.97,113.32 23.97,113.84 23.3,114.51 23.3,116.31 23.42,116.43 23.58,116.43 23.7,116.55 23.7,116.72 23.58,116.83 23.42,116.83 23.3,116.95 23.3,117.12 23.42,117.24 23.58,117.24 23.7,117.36 23.7,117.53 23.58,117.65 23.42,117.65 23.3,117.77 23.3,118.6 24.34,119.64 24.71,119.64 25.21,120.14 25.21,120.6 26.98,122.37 27.41,122.37 27.53,122.25 27.53,122.02 27.65,121.9 27.81,121.9 27.93,122.02 27.93,122.25 28.05,122.37 28.22,122.37 28.34,122.25 28.34,122.02 28.46,121.9 28.63,121.9 28.75,122.02 28.75,122.25 28.87,122.37 29.51,122.37 30.02,122.87 41.83,122.87 46.28,118.43 46.28,111.4 46.14,111.26 45.64,111.26 45.48,111.11 45.48,110.17 45.59,110.07 v1(45.88,110.07)
SOC_VOUT0_DATA14: length 49.7
  TOP w0.132: U18.Y21 v1(46.68,111.66)
  TOP w0.14: U13.15 23.19,113.02 v1(22.56,113.65)
  L03_SIG01 w0.102: v1(22.56,113.65) 22.56,113.26 22.63,113.19 22.63,112.13 22.33,111.82 21.91,111.82 21.62,112.12 21.62,113.11 21.26,113.46 21.26,114.16 21.98,114.87 21.98,119.35 23.45,120.82 23.45,121.5 25.17,123.23 26.31,123.23 26.77,123.7 31.01,123.7 31.31,123.99 34.39,123.99 34.48,124.09 40.46,124.09 41.02,123.53 42.07,123.53 47.08,118.52 47.08,112.3 46.68,111.9 v1(46.68,111.66)
SOC_VOUT0_DATA15: length 49.5
  TOP w0.132: U18.Y22 v1(46.68,112.46)
  TOP w0.14: U13.14 v1(22.69,111.35)
  L03_SIG01 w0.102: v1(22.69,111.35) 22.96,111.61 22.96,118.78 23.08,118.9 23.08,119.15 22.78,119.46 22.78,119.62 22.9,119.74 23.08,119.74 23.37,119.44 23.54,119.44 23.66,119.56 23.66,119.73 23.35,120.04 23.35,120.2 23.47,120.32 23.65,120.32 23.99,119.98 24.54,119.98 24.87,120.3 24.87,120.68 25.14,120.95 25.14,121.12 24.46,121.8 24.46,121.97 24.58,122.09 24.74,122.09 25.42,121.41 25.59,121.41 25.71,121.53 25.71,121.7 25.02,122.39 25.02,122.54 25.15,122.67 25.32,122.67 25.95,122.03 26.1,122.03 27.33,123.27 31.4,123.27 31.49,123.18 38.52,123.18 39.13,123.79 40.27,123.79 40.84,123.21 41.95,123.21 46.68,118.48 v1(46.68,112.46)
SOC_VOUT0_DATA16: length 50.9
  TOP w0.132: v1(22.19,112.84) U13.13 ; U18.P22 v1(41.88,112.47)
  L10_SIG03 w0.102: v1(22.19,112.84) 22.62,112.42 24.42,112.42 25.81,113.81 25.81,115.11 26.29,115.59 27.21,115.59 28.79,117.17 29.17,117.17 29.29,117.05 29.29,116.63 29.41,116.51 29.57,116.51 29.69,116.63 29.69,117.05 29.81,117.17 29.98,117.17 30.1,117.05 30.1,116.63 30.22,116.51 30.39,116.51 30.51,116.63 30.51,117.05 30.63,117.17 30.79,117.17 30.91,117.05 30.91,116.63 31.03,116.51 31.2,116.51 31.32,116.63 31.32,117.05 31.44,117.17 32.25,117.17 33.04,116.38 33.04,116.21 32.91,116.09 32.91,115.92 33.03,115.8 33.2,115.8 33.33,115.92 33.49,115.92 33.74,115.68 34.62,115.68 36.68,113.63 36.68,112.9 37.48,112.09 37.48,110.7 37.25,110.47 36.84,110.47 36.68,110.3 36.68,104.28 36.91,104.05 38.91,104.05 39.11,104.26 39.11,108.6 39.11,110.4 39.38,110.67 39.38,112.47 39.75,112.84 40.14,112.84 40.32,113.02 41.71,113.02 41.88,112.85 v1(41.88,112.47)
  BOTTOM w0.14: v1(22.19,112.84) 22.19,111.07 21.59,110.47 RA3.8
SOC_VOUT0_DATA17: length 52
  TOP w0.132: U18.R19 v1(42.68,110.06)
  TOP w0.14: v1(21.19,112.83) U13.11
  L03_SIG01 w0.102: v1(42.68,110.06) 42.28,110.47 41.71,110.47 41.48,110.7 41.48,111.03 41.25,111.26 40.9,111.26 40.68,111.49 40.68,113.1 40.15,113.63 38.92,113.63 38.77,113.48 38.77,113.2 38.65,113.08 38.49,113.08 38.37,113.2 38.37,113.38 38.25,113.5 37.86,113.5 37.47,113.11 37.47,112.29 37.24,112.06 36.52,112.06 36.41,112.18 36.41,112.55 36.29,112.67 36.12,112.67 36,112.55 36,112.18 35.88,112.06 32.05,112.06 31.88,111.89 31.88,111.5 31.65,111.26 31.22,111.26 30.21,110.26 30.21,109.24 27.69,106.72 27,106.72 25.25,104.97 18.72,104.97 17.78,105.9 17.78,107.28 16.43,108.63 16.43,110.91 16.3,111.04 16.3,113.14 17.48,114.32 19.46,114.32 20.1,113.68 20.46,113.68 21.19,112.94 v1(21.19,112.83)
  BOTTOM w0.14: RA3.7 v1(21.19,112.83)
SOC_VOUT0_DATA18: length 51.1
  TOP w0.132: U18.R20 v1(42.68,110.86) ; U13.10 v1(20.69,111.19)
  L03_SIG01 w0.102: v1(20.69,111.19) 20.73,111.22 20.73,112.94 20.37,113.3 19.88,113.3 19.62,113.56 17.18,113.56 16.69,113.07 16.69,112.28 17.1,111.87 17.1,110.59 16.8,110.3 16.8,109.13 18.11,107.83 18.11,106.03 18.87,105.28 21.21,105.28 21.33,105.4 21.33,105.73 21.45,105.85 21.62,105.85 21.74,105.73 21.74,105.4 21.86,105.28 22.03,105.28 22.15,105.4 22.15,105.73 22.27,105.85 22.43,105.85 22.55,105.73 22.55,105.4 22.67,105.28 24.92,105.28 29.05,109.41 29.05,109.65 29.35,109.95 29.35,110.12 29.11,110.36 29.11,110.53 29.22,110.65 29.39,110.65 29.64,110.4 29.81,110.4 29.93,110.52 29.93,110.69 29.68,110.94 29.68,111.11 29.8,111.23 29.97,111.23 30.21,110.98 30.38,110.98 31.08,111.68 31.08,112.63 31.31,112.87 35.58,112.87 36.66,113.95 40.28,113.95 41.16,113.07 41.16,112.15 41.48,111.83 41.48,111.5 41.71,111.26 42.07,111.26 42.47,110.86 v1(42.68,110.86)
  BOTTOM w0.14: RA3.6 20.79,111.09 v1(20.69,111.19)
SOC_VOUT0_DATA19: length 51.9
  TOP w0.132: v1(20.19,112.84) U13.9 ; U18.R22 v1(42.68,112.46)
  L03_SIG01 w0.102: v1(42.68,112.46) 42.68,113.1 40.91,114.87 37.72,114.87 36.62,115.97 33.78,115.97 33.02,116.73 29.27,116.73 27.3,114.76 27.3,110.84 26.27,109.8 26.27,109.11 25.91,108.75 25.55,108.75 25.33,108.52 24.9,108.52 24.74,108.37 24.74,107.46 24.51,107.23 24.05,107.23 23.83,107.45 23.83,108.63 23.59,108.87 23.14,108.87 22.95,108.68 22.95,108.06 22.79,107.9 22.49,107.9 22.29,108.1 22.29,108.51 22.17,108.63 21.89,108.63 21.74,108.47 21.74,107.98 21.65,107.89 21.35,107.89 21.26,107.98 21.26,108.77 21.08,108.94 20.64,108.94 20.39,108.69 20.39,107.54 20.28,107.44 20.1,107.44 19.99,107.55 19.99,108.7 19.64,109.06 19.64,109.43 18.25,110.83 18.25,111.52 18.48,111.75 18.48,112.39 18.58,112.49 18.89,112.49 19,112.39 19,111.88 19.13,111.74 19.36,111.74 19.48,111.86 19.48,112.36 19.6,112.48 19.77,112.48 19.89,112.36 19.89,111.86 20.01,111.74 20.3,111.74 20.41,111.85 20.41,112.63 v1(20.19,112.84)
  BOTTOM w0.14: RA3.5 20.39,110.79 20.19,110.99 v1(20.19,112.84)
SOC_VOUT0_DATA20: length 50.5
  TOP w0.132: U18.T22 v1(43.48,112.46) ; U13.8 v1(19.69,111.21)
  L03_SIG01 w0.102: v1(19.69,111.21) 20.27,110.64 22.09,110.64 22.66,110.07 24.41,110.07 24.74,110.4 25.62,110.4 26.68,111.46 26.68,115 29.01,117.34 34.05,117.34 34.38,117.67 36.98,117.67 37.47,118.15 40.36,118.15 40.49,118.02 40.49,117.79 40.36,117.67 38,117.67 37.8,117.46 37.8,117.1 37.94,116.96 38.24,116.96 38.36,116.84 38.36,116.67 38.24,116.55 37.9,116.55 37.8,116.45 37.8,115.89 37.9,115.79 38.2,115.79 38.38,115.96 38.73,115.96 38.97,115.72 39.31,115.72 39.5,115.9 39.5,116.57 39.63,116.7 40.21,116.7 40.34,116.57 40.34,115.63 40.44,115.53 40.69,115.53 40.85,115.69 40.85,118.35 41.2,118.71 41.92,118.71 43.48,117.14 v1(43.48,112.46)
  BOTTOM w0.14: v1(19.69,111.21) 19.69,110.77 RA4.8
SOC_VOUT0_DATA21: length 51.9
  TOP w0.132: U18.R21 v1(42.68,111.66) ; U13.7 v1(19.19,112.84)
  L03_SIG01 w0.102: v1(19.19,112.84) 19.19,113.15 19.09,113.25 17.81,113.25 17.63,113.07 17.63,111.65 17.94,111.34 17.94,110.57 18.15,110.36 18.15,110.19 18.01,110.05 18.01,109.88 18.13,109.76 18.3,109.76 18.44,109.9 18.6,109.9 18.78,109.73 18.78,107.16 18.89,107.06 19.16,107.06 19.28,107.18 19.28,108.5 19.39,108.6 19.59,108.6 19.69,108.5 19.69,107.18 19.81,107.06 20.51,107.06 20.78,107.33 21.33,107.33 21.52,107.52 21.78,107.52 21.88,107.42 21.88,106.69 22,106.58 22.17,106.58 22.29,106.69 22.29,107.47 22.4,107.59 22.57,107.59 22.69,107.47 22.69,106.69 22.81,106.58 24.44,106.58 25.25,107.39 25.25,107.76 25.87,108.38 26.81,108.38 27.18,108.75 27.18,110.14 27.61,110.57 27.61,114.64 29.01,116.04 32.03,116.04 32.4,115.67 36.42,115.67 37.52,114.57 40.54,114.57 42.28,112.82 42.28,112.3 42.68,111.9 v1(42.68,111.66)
  BOTTOM w0.14: v1(19.19,112.84) 19.2,112.84 19.2,111.05 18.94,110.79 RA4.7
SOC_VOUT0_DATA22: length 50.4
  TOP w0.132: U18.T20 v1(43.48,110.86) ; v1(18.69,111.24) U13.6
  L03_SIG01 w0.102: v1(18.69,111.24) 18.97,111.24 20.48,109.73 21.57,109.73 21.83,109.47 22.7,109.47 22.95,109.72 24.47,109.72 24.71,109.48 25.32,109.48 26.99,111.14 26.99,114.88 29.14,117.03 33.17,117.03 33.42,116.79 36.64,116.79 36.85,116.58 36.85,116.2 37.87,115.18 40.9,115.18 41.23,115.51 41.23,117.49 41.46,117.72 42.47,117.72 43.18,117.02 43.18,116.72 43.06,116.6 41.96,116.6 41.86,116.5 41.86,116.29 41.96,116.19 43.06,116.19 43.18,116.07 43.18,115.9 43.06,115.78 41.99,115.78 41.89,115.68 41.89,115.48 41.99,115.38 43.06,115.38 43.18,115.26 43.18,114.97 43.06,114.86 42,114.86 41.89,114.74 41.89,114.57 42,114.45 43.06,114.45 43.18,114.33 43.18,114.11 43.06,113.99 42.87,113.99 42.75,113.87 42.75,113.7 42.87,113.58 43.06,113.58 43.18,113.46 43.18,112.73 43.08,112.63 43.08,111.5 43.48,111.1 v1(43.48,110.86)
  BOTTOM w0.14: RA4.6 18.54,110.79 18.54,111.09 v1(18.69,111.24)
SOC_VOUT0_DATA23: length 51.5
  TOP w0.132: U18.T21 v1(43.48,111.66) ; v1(17.5,111.2) 17.69,111.4 U13.4
  L03_SIG01 w0.102: v1(43.48,111.66) 43.48,111.48 43.88,111.08 43.88,109.9 43.65,109.66 43.31,109.66 43.08,109.43 43.08,107.39 42.96,107.26 42.41,107.26 42.28,107.39 42.28,109.49 42.46,109.67 42.85,109.67 43.08,109.9 43.08,111.03 42.85,111.26 42.51,111.26 42.28,111.5 42.28,111.83 42.05,112.06 42.02,112.06 42.02,112.07 41.71,112.07 41.48,112.3 41.48,112.31 41.48,113.18 40.4,114.26 37.05,114.26 36.66,114.65 33.54,114.65 33.08,115.12 31.1,115.12 30.6,114.62 30.6,112.97 29.9,112.26 29.63,112.26 29.47,112.11 29.47,111.84 29.32,111.69 29.05,111.69 28.9,111.54 28.9,111.26 28.64,111 28.64,109.77 26.95,108.08 26.55,108.08 26.24,107.77 26.24,107.42 25.06,106.24 21.62,106.24 21.39,106.47 20.55,106.47 20.14,106.06 18.95,106.06 18.48,106.53 18.48,108 17.18,109.3 17.18,110.14 17.5,110.46 v1(17.5,111.2)
  BOTTOM w0.14: v1(17.5,111.2) 17.76,111.2 18.14,110.82 RA4.5
SOC_VOUT0_DE: length 48.1
  TOP w0.132: U18.U17 v1(44.28,108.46)
  TOP w0.14: U13.33 26.28,119.77 v1(26.44,119.93)
  L10_SIG03 w0.102: v1(44.28,108.46) 44.68,108.86 44.68,110.23 44.91,110.46 45.33,110.46 45.48,110.62 45.48,111.05 45.7,111.26 45.75,111.26 47.75,111.26 47.88,111.39 47.88,111.9 47.71,112.07 46.41,112.07 46.28,112.2 46.28,112.77 46.38,112.87 47.57,112.87 47.68,112.97 47.68,113.16 47.54,113.29 46.42,113.29 46.28,113.43 46.28,115.77 46.37,115.86 46.5,115.86 46.61,115.75 46.61,113.72 46.7,113.63 46.84,113.63 46.92,113.71 46.92,115.53 47.02,115.64 47.17,115.64 47.27,115.53 47.27,114.75 47.38,114.64 47.54,114.64 47.65,114.74 47.65,116.23 41.96,121.92 32.78,121.92 31.82,120.96 28.64,120.96 27.62,119.93 v1(26.44,119.93)
SOC_VOUT0_HSYNC: length 48.3
  TOP w0.132: U18.T18 v1(43.48,109.26)
  TOP w0.14: v1(24.45,120.47) 24.65,120.27 U13.34
  L10_SIG03 w0.102: v1(24.45,120.47) 26.29,122.31 29.74,122.31 31.42,123.99 40.29,123.99 40.97,123.31 42.84,123.31 47.15,119 47.86,119 51.83,115.03 51.83,111.44 48.45,108.06 44.11,108.06 43.88,108.3 43.88,108.86 v1(43.48,109.26)
SOC_VOUT0_PCLK: length 1.2
  TOP w0.132: U18.AA22 v1(47.48,112.46)
  BOTTOM w0.14: R318.1 v1(47.48,112.46)
SOC_VOUT0_VSYNC: length 48.3
  TOP w0.132: U18.V17 v1(45.08,108.46)
  TOP w0.14: v1(26.3,121.02) 26.05,120.77 U13.35
  L10_SIG03 w0.102: v1(26.3,121.02) 27.28,122.01 30.58,122.01 31.47,122.9 42.65,122.9 46.86,118.69 47.73,118.69 47.93,118.49 47.93,118.33 47.52,117.91 47.52,117.74 47.64,117.62 47.8,117.62 48.22,118.04 48.39,118.04 48.51,117.92 48.51,117.75 48.09,117.33 48.09,117.16 48.21,117.04 48.38,117.04 48.8,117.46 48.97,117.46 49.08,117.34 49.08,117.18 48.67,116.76 48.67,116.59 48.79,116.47 48.95,116.47 49.37,116.89 49.54,116.89 49.66,116.77 49.66,116.6 49.24,116.18 49.24,116.01 49.36,115.89 49.53,115.89 49.95,116.31 50.12,116.31 51.41,115.02 51.41,111.68 50.84,111.11 50.67,111.11 50.36,111.42 50.19,111.42 50.07,111.3 50.07,111.13 50.39,110.82 50.39,110.65 48.6,108.86 45.48,108.86 v1(45.08,108.46)
SOC_WARM_RESETZ: length 140.5
  TOP w0.132: U18.E19 v1(33.88,110.06)
  TOP w0.14: TP87.1 39.02,16.67 40.02,17.66 v1(40.02,18.09)
  L03_SIG01 w0.102: v1(33.88,110.06) 34.28,110.47 34.89,110.47 35.08,110.27 35.08,108.3 34.85,108.06 34.51,108.06 34.28,107.83 34.28,107.5 34.05,107.26 33.71,107.26 33.48,107.03 33.48,106.7 33.25,106.47 33.23,106.46 29.98,106.46 29.19,105.67 27.58,105.67 25.44,103.54 24.82,103.54 24.02,102.75 24.02,102.28 22.23,100.48 20.27,100.48 19.64,99.85 19.64,96.08 18.63,95.07 18.63,87.45 18.1,86.92 14.89,86.92 10.81,82.84 10.81,77.39 11.17,77.03 12.68,77.03 13.69,76.01 16.16,76.01 17.39,74.78 17.39,73.89 18.59,72.7 18.59,66.89 19.33,66.15 19.91,66.15 20.57,65.49 20.57,61.5 19.83,60.76 19.83,59.29 20.67,58.45 21.42,58.45 22.93,56.94 22.93,54.29 24.35,52.87 24.35,51.81 23.78,51.24 23.78,49.24 23.29,48.75 23.29,40.68 24.09,39.88 24.09,33.99 23.01,32.91 23.01,25.62 24.25,24.38 24.25,22.34 v1(23.77,21.86)
  L10_SIG03 w0.102: v1(23.77,21.86) 26.68,21.86 27.16,22.34 29.03,22.34 29.77,21.6 32.49,21.6 35.52,18.57 39.54,18.57 v1(40.02,18.09)
  BOTTOM w0.14: v1(40.02,18.09) R534.1 39.44,18.56 39.49,18.61 U108.2
SOC_WLAN_SDIO_RST: length 15.8
  TOP w0.14: U1.13 41.4,152.77 41.16,153.01 40.8,153.01 v1(40.58,152.78) ; U2.24 53.34,151.56 53.59,151.82 v1(53.59,152.14)
  L10_SIG03 w0.102: v1(40.58,152.78) 40.62,152.78 41.26,152.14 v1(53.59,152.14)
SPI0_FET_OE: length 22.6
  TOP w0.14: U2.18 54.02,148.56 v1(54.52,149.06)
  BOTTOM w0.14: U55.15 R284.2 60.46,139.47 58.68,141.24 56.68,141.24 55.53,142.4 55.53,142.88 55.53,144.87 55.53,144.87 55.53,145.1 55.53,145.11 55.53,145.34 55.81,145.63 55.81,147.43 54.52,148.72 v1(54.52,149.06)
SPI0_FET_SEL: length 18.5
  TOP w0.14: v1(53.21,146.58) R14.2 R13.1 53.81,147.85 53.6,148.06 U2.17
  L03_SIG01 w0.102: v1(53.21,146.58) 51.98,145.35 51.98,141.91 53.98,139.91 53.98,135.55 v1(54.35,135.18)
  BOTTOM w0.14: v1(54.35,135.18) 53.67,134.49 U55.1
SPI_HOLDN: length 1.6
  TOP w0.14: R145.2 56.89,61.22 U34.7
SPI_WPN: length 1.5
  TOP w0.14: R142.2 64.75,62.67 64.57,62.49 U34.3
SS_LM5141: length 1.9
  BOTTOM w0.14: U89.22 34.03,43.02 33.6,42.59 C429.1
SW_2V5: length 3.7
  BOTTOM w0.305: L9.1 U81.5
SW_LM5141: length 6.5
  BOTTOM w0.254: C412.1 38.8,50.56 ; 35.97,49.39 35.53,48.95 U89.12
  vias: v1(41.82,48.38) v1(41.82,47.42) v1(42.79,53.21) v1(42.79,52.24) v1(42.79,51.28) v1(42.79,50.31) v1(42.79,49.35) v1(42.79,48.38) v1(42.79,47.42) v1(43.76,53.21) v1(43.76,52.24) v1(43.76,51.28) v1(43.76,50.31) v1(43.76,49.35) v1(43.76,48.38) v1(43.76,47.42) v1(44.72,53.21) v1(44.72,52.24) v1(44.72,51.28) v1(44.72,50.31) v1(44.72,49.35) v1(44.72,48.38) v1(44.72,47.42)
SYS_BOOTMODE0: length 17.4
  TOP w0.14: v1(41.01,36.28) SW2.1
  L05_SIG02 w0.102: v1(41.22,28.99) 41.73,28.99 43.41,30.67 44.91,30.67 45.34,31.1 45.34,32.98 42.04,36.28 v1(41.01,36.28)
  BOTTOM w0.14: R455.1 v1(41.01,36.28) ; U100.1 v1(41.22,28.99) U101.10
SYS_BOOTMODE1: length 17.3
  TOP w0.14: v1(39.74,36.28) SW2.2
  L05_SIG02 w0.102: v1(39.74,36.28) 40.19,35.83 42.09,35.83 44.43,33.49 44.43,31.99 44.12,31.69 43.54,31.69 41.34,29.49 v1(40.38,29.49)
  BOTTOM w0.14: U100.2 v1(40.38,29.49) U101.9 ; R456.1 v1(39.74,36.28)
SYS_BOOTMODE2: length 15.8
  TOP w0.14: v1(38.47,36.28) SW2.3
  L05_SIG02 w0.102: v1(38.47,36.28) 39.18,35.57 41.96,35.57 43.54,34 43.54,32.31 v1(41.22,29.99)
  BOTTOM w0.14: R457.1 v1(38.47,36.28) ; U101.8 v1(41.22,29.99) U100.3
SYS_BOOTMODE3: length 17
  TOP w0.14: v1(37.2,36.28) SW2.4
  L05_SIG02 w0.102: v1(40.38,30.49) 40.41,30.52 41.35,30.52 43.21,32.37 43.21,33.9 41.84,35.27 38.21,35.27 v1(37.2,36.28)
  BOTTOM w0.14: U101.7 v1(40.38,30.49) U100.4 ; R458.1 v1(37.2,36.28)
SYS_BOOTMODE4: length 16.3
  TOP w0.14: v1(35.93,36.28) SW2.5
  L05_SIG02 w0.102: v1(35.93,36.28) 35.93,36.27 37.19,35.01 41.67,35.01 42.85,33.83 42.85,32.62 v1(41.22,30.99)
  BOTTOM w0.14: R459.1 v1(35.93,36.28) ; U101.6 v1(41.22,30.99) U100.5
SYS_BOOTMODE5: length 16.6
  TOP w0.14: v1(34.66,36.28) SW2.6
  L05_SIG02 w0.102: v1(40.38,31.49) 41.26,31.49 41.73,31.96 41.73,34.23 41.23,34.74 36.21,34.74 v1(34.66,36.28)
  BOTTOM w0.14: U100.6 v1(40.38,31.49) U101.5 ; R460.1 v1(34.66,36.28)
SYS_BOOTMODE6: length 15
  TOP w0.14: v1(33.39,36.28) SW2.7
  L05_SIG02 w0.102: v1(41.22,31.99) 41.22,32.81 40.31,33.72 35.95,33.72 v1(33.39,36.28)
  BOTTOM w0.14: U100.7 v1(41.22,31.99) U101.4 ; R461.1 v1(33.39,36.28)
SYS_BOOTMODE7: length 14.7
  TOP w0.14: v1(32.12,36.28) SW2.8
  L05_SIG02 w0.102: v1(40.38,32.49) 39.5,33.38 35.03,33.38 v1(32.12,36.28)
  BOTTOM w0.14: U101.3 v1(40.38,32.49) U100.8 ; R462.1 v1(32.12,36.28)
SYS_BOOTMODE8: length 19
  TOP w0.14: R192.1 v1(54.47,36.28) SW3.1
  BOTTOM w0.14: U100.9 43.63,34.1 45.4,35.87 49.31,35.87 ; U98.10 51.57,33.15 51.35,33.38 51.35,33.84 49.31,35.87 ; 49.31,35.87 54.06,35.87 v1(54.47,36.28)
SYS_BOOTMODE9: length 17.3
  TOP w0.14: SW3.2 v1(53.2,36.28) R191.1
  L03_SIG01 w0.102: v1(51.95,32.65) 52.61,33.32 52.61,35.69 v1(53.2,36.28)
  BOTTOM w0.14: U98.9 v1(51.95,32.65) 51.55,32.65 50.98,33.22 50.98,33.75 49.16,35.57 45.65,35.57 44.13,34.05 U100.10
SYS_BOOTMODE10: length 17.3
  TOP w0.14: R190.1 v1(51.93,36.28) SW3.3
  L03_SIG01 w0.102: v1(51.11,32.15) 51.11,35.46 v1(51.93,36.28)
  BOTTOM w0.14: U100.11 44.63,34.01 45.89,35.27 49.03,35.27 50.68,33.63 50.68,32.59 v1(51.11,32.15) U98.8
SYS_BOOTMODE11: length 18.2
  TOP w0.14: SW3.4 v1(50.66,36.28) R189.1
  L03_SIG01 w0.102: v1(51.95,31.65) 51.94,31.66 51.03,31.66 50.66,32.03 v1(50.66,36.28)
  BOTTOM w0.14: U98.7 v1(51.95,31.65) 50.92,31.65 50.28,32.3 50.28,33.56 48.88,34.96 46.01,34.96 45.13,34.08 U100.12
SYS_BOOTMODE12: length 17.8
  TOP w0.14: SW3.5 v1(49.39,36.28) R188.1
  L03_SIG01 w0.102: v1(51.11,31.15) 49.39,32.87 v1(49.39,36.28)
  BOTTOM w0.14: U100.13 45.63,33.99 46.27,34.63 48.73,34.63 49.97,33.4 49.97,32.02 50.83,31.15 v1(51.11,31.15) U98.6
SYS_BOOTMODE13: length 19.2
  TOP w0.14: R187.1 v1(48.12,36.28) SW3.6
  L03_SIG01 w0.102: v1(51.95,30.65) 51.92,30.68 50.92,30.68 48.12,33.47 v1(48.12,36.28)
  BOTTOM w0.14: U100.14 46.13,33.98 46.42,34.27 48.6,34.27 49.67,33.21 49.67,31.74 50.76,30.65 v1(51.95,30.65) U98.5
SYS_BOOTMODE14: length 19
  TOP w0.14: SW3.7 v1(46.85,36.28) R186.1
  L03_SIG01 w0.102: v1(51.11,30.15) 50.66,30.15 46.85,33.96 v1(46.85,36.28)
  BOTTOM w0.14: U100.15 46.63,33.77 46.82,33.97 48.48,33.97 49.34,33.11 49.34,31.51 50.7,30.15 v1(51.11,30.15) U98.4
SYS_BOOTMODE15: length 20.2
  TOP w0.14: SW3.8 v1(45.58,36.28) R185.1
  L03_SIG01 w0.102: v1(45.58,36.28) 45.58,34.71 50.63,29.65 v1(51.95,29.65)
  BOTTOM w0.14: U98.3 v1(51.95,29.65) 51.89,29.71 50.69,29.71 49.03,31.36 49.03,32.95 48.32,33.66 47.26,33.66 47.13,33.54 U100.16
SYSBOOT_BUF_ENZ: length 30.6
  TOP w0.132: v1(69.68,29.04) U45.1
  TOP w0.14: R170.1 R171.1 60.57,46.6 60.71,46.74 61.66,46.74 62.26,46.14 v1(62.26,45.79)
  L03_SIG01 w0.102: v1(69.68,29.04) 68.41,30.32 61.5,30.32 60.55,31.27 60.55,35.11 60.91,35.47 60.91,37.38 59.81,38.49 59.81,41.66 62.26,44.11 v1(62.26,45.79)
TCA6424_EXP_INT: length 2
  BOTTOM w0.14: R490.1 42.7,27.42 43.45,27.42 43.63,27.6 U100.32
TEMP_DIODE_P: length 10.3
  TOP w0.132: U18.F10 v1(34.68,102.07)
  BOTTOM w0.14: TP99.1 29.03,104.09 29.61,103.51 30.14,103.51 31.19,102.47 34.26,102.47 34.66,102.07 v1(34.68,102.07)
TEST_GPIO1: length 41.4
  L03_SIG01 w0.102: v1(59.01,16.41) 59.01,17.05 58.63,17.43 58.63,18.97 59.18,19.51 59.18,21.65 59.89,22.35 59.89,23.84 60.77,24.73 60.77,25.36 61.97,26.56 61.97,27.17 62.65,27.85 64.42,27.85 64.94,28.38 64.94,29.34 v1(65.12,29.52)
  L05_SIG02 w0.102: v1(59.01,16.41) 58.82,16.22 51.7,16.22 51.26,16.66 49.77,16.66 48.71,15.6 46.12,15.6 43.14,18.59 v1(42.6,18.59)
  BOTTOM w0.14: v1(65.12,29.52) 64.95,29.35 64.95,27.63 64.83,27.52 R484.1 ; R548.1 60.07,16.38 59.86,16.17 R556.1 59.26,16.17 v1(59.01,16.41) ; Q13.1 43.47,18.85 43.21,18.59 v1(42.6,18.59)
TEST_GPIO2: length 39.5
  L03_SIG01 w0.102: v1(59.39,19.14) 59.72,18.8 59.72,16.03 59.36,15.66 58.24,15.66 57.65,16.26 57.65,19.87 57.97,20.19 57.97,22.62 57.24,23.35 57.24,24.97 58.24,25.97 58.24,27.32 58.86,27.94 v1(58.86,29.52) 59.63,30.28 59.63,34.73 60.48,35.57 60.48,37.22 59.27,38.42 59.27,40.67 58.29,41.65 58.29,43.63 v1(57.8,44.11)
  BOTTOM w0.14: R533.1 58.42,18.63 R531.1 59.23,18.98 v1(59.39,19.14) ; U92.18 v1(57.8,44.11) ; v1(58.86,29.52) R481.1
TEST_GPIO3: length 42.5
  TOP w0.132: U45.2 70.82,27.31 71.21,27.69 v1(71.21,28.61) 72.07,29.47 73.87,29.47 75.65,27.69 TP76.1 79.41,27.69 79.55,27.55 v1(79.84,27.55)
  L03_SIG01 w0.102: v1(58.08,17.02) 58.08,19.75 58.91,20.57 58.91,26.11 62.77,29.98 65.42,29.98 v1(65.91,29.48) 67.67,29.48 68.56,28.58 70.75,28.58 70.78,28.61 v1(71.21,28.61)
  BOTTOM w0.14: v1(79.84,27.55) R486.1 J16.1 ; v1(65.91,29.48) 65.91,27.71 65.72,27.52 R483.1 ; v1(58.08,17.02) 57.25,16.19 R557.1
TEST_GPIO4: length 44.9
  TOP w0.14: TP75.1 67.53,28.86 v1(67.31,28.63)
  L03_SIG01 w0.102: v1(56.77,18.89) 57.24,18.42 57.24,16.17 58.03,15.38 59.47,15.38 60.05,15.96 60.05,21.53 60.73,22.21 60.73,22.77 66.04,28.08 66.75,28.08 v1(67.31,28.63)
  BOTTOM w0.14: v1(67.31,28.63) 67.08,28.41 R482.1 ; U100.28 45.63,26.57 45.99,26.2 46.46,26.2 46.95,26.69 51.86,26.69 54.98,23.57 54.98,19.73 56.46,18.25 R536.1 57.07,18.59 v1(56.77,18.89) 57.09,19.2 R527.1
TEST_PORZN: length 37.1
  L03_SIG01 w0.102: v1(63.29,16.93) 61.13,14.77 57.53,14.77 56.38,15.92 56.38,19.05 57.74,20.42 57.74,22.42 57.01,23.15 57.01,25.06 58.01,26.06 58.01,27.96 56.34,29.63 56.34,34.34 v1(57.85,35.85)
  L05_SIG02 w0.102: v1(57.85,35.85) 57.85,35.82 58.65,35.02 58.9,34.77 v1(58.9,34.02)
  BOTTOM w0.14: R555.1 62.24,16.17 62.45,16.38 R547.1 62.78,16.78 62.93,16.93 v1(63.29,16.93) ; R472.1 59.2,33.38 58.9,33.69 v1(58.9,34.02) ; v1(57.85,35.85) 57.71,35.99 U96.6
TEST_POWERDOWN: length 104.6
  TOP w0.14: v1(27.08,34.05) 26.89,33.86 R201.1 ; R194.1 63.37,35.62 v1(62.73,34.98) ; U36.6 v1(19.68,57.29)
  L03_SIG01 w0.102: v1(21.64,36.65) 21.64,41.51 21.42,41.73 21.42,48.39 22.3,49.26 22.3,51.9 22.81,52.41 22.81,53.18 19.68,56.31 v1(19.68,57.29) ; v1(62.73,34.98) 62.73,34.42 61.17,32.86 61.17,31.13 61.65,30.65 69.4,30.65 69.75,30.29 71.05,30.29 71.78,29.55 71.78,25.51 70.23,23.96 70.23,21.89 68.94,20.6 68.21,20.6 64.97,17.36 v1(64.97,16.93)
  L10_SIG03 w0.102: v1(21.64,36.65) 21.89,36.65 22.85,35.68 26.31,35.68 27.08,34.91 v1(27.08,34.05) 27.18,33.95 28.01,33.95 28.33,34.28 30.46,34.28 32.13,32.6 33.84,32.6 34.66,33.43 40.23,33.43 40.98,34.18 54.85,34.18 55.8,33.23 61.59,33.23 62.73,34.37 v1(62.73,34.98)
  BOTTOM w0.14: v1(64.97,16.93) R546.1 64.64,16.38 64.43,16.17 R554.1
TEST_WARMRESETN: length 55.3
  TOP w0.14: v1(68.15,34.28) 68.15,34.74 67.63,35.26 R198.1
  L05_SIG02 w0.102: v1(61.41,19.18) 60.61,18.38 58.18,18.38 56.91,17.1 49.63,17.1 49.04,16.52 46.67,16.52 43.44,19.75 v1(37.65,19.75)
  L10_SIG03 w0.102: v1(68.15,34.28) 68.15,31.36 70.16,29.35 70.16,21.02 68.32,19.18 v1(61.41,19.18)
  BOTTOM w0.14: R532.1 60.74,18.41 60.95,18.63 R530.1 v1(61.41,19.18) ; Q14.1 37.62,19.74 37.63,19.75 v1(37.65,19.75)
TM4C129_TCK: length 2.7
  TOP w0.132: TP85.1 53.43,21.1 53.51,21.03 U47.100
TM4C129_TDI: length 2.4
  TOP w0.14: TP83.1 53.39,21.83 U47.98
TM4C129_TDO: length 2.6
  TOP w0.14: TP82.1 52.99,23.39 53.01,23.37 53.01,23.01 53.8,22.23 U47.97
TM4C129_TMS: length 1.8
  TOP w0.14: TP84.1 53.04,21.43 U47.99
TMP1_ADD0: length 3.2
  TOP w0.14: U16.5 19.15,105.55 18.46,106.24 R64.1
TMP1_ADD1: length 1.2
  TOP w0.14: R63.1 U16.3
TMP2_ADD1: length 1.4
  TOP w0.14: U29.3 R129.1
TPS6593_EN: length 2.2
  TOP w0.14: U36.4 21.13,55.75 R148.1
UART1_FET_BUF_EN: length 54.5
  TOP w0.14: v1(19.83,36.62) 19.87,36.59 20.79,36.59 20.93,36.73 20.93,37.43 R263.1 21.3,37.71 21.4,37.81 U54.16 21.82,37.36 21.96,37.22 22.24,37.22 22.42,37.4 U54.1 ; U40.2 v1(51.93,49.57)
  L10_SIG03 w0.102: v1(51.93,49.57) 50.6,49.57 49.68,48.65 49.68,47.96 48.05,46.34 40.06,46.34 39.79,46.6 39.79,47.09 39.54,47.34 39.12,47.34 38.68,47.78 37.55,47.78 37.09,47.31 32.97,47.31 32.18,46.52 32.18,45.94 32,45.76 31.27,45.76 29.7,44.19 29.7,43.95 29.33,43.58 26.95,43.58 26.23,42.85 v1(25.29,42.85)
  BOTTOM w0.14: v1(25.29,42.85) 25.77,42.37 25.77,41.69 25.57,41.49 25.03,41.49 24.87,41.65 23.9,41.65 23.45,41.2 23.45,39.52 22.08,38.15 22.08,36.36 21.94,36.22 20.83,36.22 20.43,36.62 v1(19.83,36.62) ; U92.11 53.7,47.8 v1(51.93,49.57)
UART1_FET_BUF_EN_INV: length 32.8
  TOP w0.14: U40.4 52.58,50.56 53.34,49.8 53.34,48.1 52.94,47.69 v1(52.5,47.69)
  L10_SIG03 w0.102: v1(31.78,39.28) 35,42.5 35,43.01 36.57,44.58 37.18,44.58 37.76,45.16 49.29,45.16 50.23,46.11 51.41,46.11 52.05,46.74 52.05,47.23 v1(52.5,47.69)
  BOTTOM w0.14: U95.15 31.3,36.78 31.47,36.95 31.47,37.51 31.89,37.93 31.89,39.17 v1(31.78,39.28)
UART1_FET_SEL: length 39.5
  TOP w0.14: R179.1 R177.2 v1(57.8,42.11)
  L10_SIG03 w0.102: v1(27.83,37.33) 28.45,36.71 37.7,36.71 38.98,38 38.98,38.69 40.82,40.53 50.19,40.53 51.59,41.93 57.62,41.93 v1(57.8,42.11)
  BOTTOM w0.14: v1(27.83,37.33) 27.83,36.93 27.02,36.13 U95.1 ; R177.2 v1(57.8,42.11)
UART_SHIELD:
  vias: v1(1.38,18.4) v1(1.38,16.88) v1(1.38,15.36) v1(2.91,18.4) v1(2.91,16.88) v1(2.91,15.36)
USB_DM: length 1.9
  TOP w0.132: v1(3.91,135.65) 3.77,135.65 3.66,135.54 J2.5
  BOTTOM w0.14: TP97.1 3.77,135.72 3.83,135.65 v1(3.91,135.65)
USB_DP: length 1.9
  TOP w0.132: v1(3.91,134.94) 3.77,134.94 3.66,135.04 J2.3
  BOTTOM w0.14: v1(3.91,134.94) 3.84,134.87 TP98.1
USB_TYPEA_EARTH:
  vias: v1(79.18,66.48) v1(80.04,66.48) v1(80.44,74.84) v1(80.44,73.32) v1(80.44,71.79) v1(80.44,70.27) v1(80.96,67.32) v1(81.82,67.32) v1(81.97,74.84) v1(81.97,73.32) v1(81.97,71.79) v1(81.97,70.27) v1(82.68,67.32) v1(83.19,66.56) v1(83.19,65.7) v1(83.49,74.84) v1(83.49,73.32) v1(83.49,71.79) v1(83.49,70.27)
USB_TYPEACONN_DM: length 8.5
  TOP w0.102: J7.2 70.33,71.3 69.44,72.2 68.47,72.2 68.1,71.83 U30.5 67.59,71.83 67.26,72.17 66.72,72.17 66.38,72.5 66.38,74.47 66.07,74.79 L4.2
USB_TYPEACONN_DP: length 8.1
  TOP w0.102: L4.3 66.92,74.77 66.59,74.45 66.59,72.59 66.81,72.38 67.2,72.38 67.6,72.78 U30.6 68.09,72.78 68.46,72.41 69.45,72.41 70.34,73.3 J7.3
USB_TYPEC1_EARTH:
  vias: v1(1.37,46.57) v1(1.37,45.05) v1(1.37,43.52) v1(2.9,46.57) v1(2.9,45.05) v1(2.9,43.52) v1(4.14,51.84) v1(4.14,50.92) v1(5.06,51.84) v1(5.06,50.92) v1(5.97,51.84) v1(5.97,50.92)
USB_TYPEC2_EARTH:
  vias: v1(1.37,31.57) v1(1.37,30.05) v1(1.37,28.52) v1(2.9,31.57) v1(2.9,30.05) v1(2.9,28.52) v1(4.14,36.9) v1(4.14,35.99) v1(5.06,36.9) v1(5.06,35.99) v1(5.97,36.9) v1(5.97,35.99)
USBC_CONN1_CC1: length 21.4
  TOP w0.14: v1(10.08,46.33) D4.1 9.07,45.95 J13.A5 ; C113.1 21.79,50.41 v1(21.78,50.4)
  L10_SIG03 w0.102: v1(21.78,50.4) 21.38,50.8 19.44,50.8 18.48,51.76 15.22,51.76 14.65,51.19 14.64,51.19 14.42,50.97 14.42,50.96 13.97,50.52 13.97,47.57 12.73,46.33 v1(10.08,46.33)
  BOTTOM w0.14: U90.24 21.38,49 21.3,49.09 21.3,49.92 v1(21.78,50.4)
USBC_CONN1_CC2: length 28.1
  TOP w0.14: v1(5.35,44.36) 5.52,44.2 J13.B5 ; v1(22.69,50.4) 22.53,50.24 C116.1
  L10_SIG03 w0.102: v1(5.35,44.36) 6.3,44.36 7.83,45.89 7.83,46.39 9.29,47.85 13.32,47.85 13.66,48.19 13.66,50.93 14.98,52.25 21.26,52.25 21.76,51.75 21.76,51.34 v1(22.69,50.4)
  BOTTOM w0.14: D10.1 5.14,44.58 v1(5.35,44.36) ; U90.26 22.18,49.06 22.31,49.2 22.31,50.02 v1(22.69,50.4)
USBC_CONN2_CC1: length 21.2
  TOP w0.14: v1(9.55,32.1) D5.1 9.01,30.95 J15.A5 ; C131.1 v1(22.18,40.88)
  L05_SIG02 w0.102: v1(22.18,40.88) 21.56,40.26 20.98,40.26 18.49,37.77 18.49,36.35 17.98,35.84 13.28,35.84 v1(9.55,32.1)
  BOTTOM w0.14: U90.45 v1(22.18,40.88)
USBC_CONN2_CC2: length 28.4
  TOP w0.14: J15.B5 5.41,29.2 4.65,28.44 v1(4.65,28.23) ; C130.1 v1(21.12,40.88)
  L05_SIG02 w0.102: v1(4.65,28.23) 5,27.87 7.18,27.87 9.12,29.82 9.12,32.67 12.62,36.17 15.96,36.17 16.83,37.04 17.68,37.04 18.25,37.61 18.25,38.01 v1(21.12,40.88)
  BOTTOM w0.14: U90.47 21.38,41.14 v1(21.12,40.88) ; D11.1 4.85,28.02 v1(4.65,28.23)
USBC_CONN2_DM: length 12.3
  TOP w0.102: v1(7.07,29.59) 7.36,29.59 7.5,29.45 J15.A7 8.17,29.45 8.56,29.84 9.65,29.84 D6.3 10.05,29.61 10.12,29.53 10.8,29.53 11.11,29.84 12.09,29.84 12.41,29.52 L7.3 ; v1(5.11,30.41) 5.11,30.3 5.36,30.05 5.64,30.05 5.79,30.2 J15.B7
  L10_SIG03 w0.102: v1(7.07,29.59) 7.25,29.76 7.53,29.76 7.85,30.08 7.85,30.56 7.53,30.89 6.46,30.89 5.8,30.23 5.28,30.23 v1(5.11,30.41)
USBC_CONN2_DP: length 12.3
  TOP w0.102: v1(5.11,29.59) 5.35,29.84 5.65,29.84 5.79,29.7 J15.B6 ; v1(7.07,30.3) 7.35,30.3 7.5,30.45 J15.A6 8.19,30.45 8.58,30.05 9.65,30.05 D6.2 10.05,30.29 10.12,30.36 10.8,30.36 11.11,30.05 12.08,30.05 12.4,30.37 L7.2
  L10_SIG03 w0.102: v1(7.07,30.3) 7.07,30.07 7.18,29.97 7.45,29.97 7.65,30.17 7.65,30.48 7.44,30.68 6.54,30.68 5.88,30.02 5.03,30.02 4.93,29.92 4.93,29.77 v1(5.11,29.59)
VHDMI_AVCC_1V2: length 6
  TOP w0.254: v1(14.68,115.77) U13.66 ; v1(14.68,118.77) U13.60
  BOTTOM w0.254: C207.1 v1(14.68,115.77) ; C203.1 v1(14.68,118.77)
  BOTTOM w0.381: v1(14.68,118.77) 13.97,118.77 13.85,118.65 FB2.1 13.74,117.9 13.85,117.79 13.85,117.71 14.29,117.27 C205.1
VHDMI_CVCC_1V2: length 9
  TOP w0.254: U13.12 v1(21.69,111.25) ; U13.5 v1(18.19,112.82) ; v1(22.2,121.02) 22.2,121.12 22.19,121.12 U13.42 ; U13.53 16.69,121.28 16.96,121.01 v1(17.01,121.01) ; U13.26 24.67,116.27 v1(24.41,116.02) ; U13.47 v1(19.69,121.12)
  BOTTOM w0.254: C196.1 19.59,121.22 v1(19.69,121.12) ; v1(24.41,116.02) C206.1 ; C201.1 v1(22.2,121.02) ; C200.1 17.01,120.54 v1(17.01,121.01) ; C212.1 v1(21.69,111.25) ; C208.1 v1(18.19,112.82)
  vias: v1(16.69,123.76) v1(16.69,122.85)
VHDMI_IOVCC_3V3: length 10.5
  TOP w0.254: U13.3 v1(17.19,112.82) ; R45.1 17.51,124.32 v1(17.8,124.61) ; v1(26.3,114.02) 26.05,113.77 U13.21 ; v1(14.3,109.82) 14.3,110.28 14.39,110.37 R57.1 ; U13.46 20.19,121.35 20.45,121.09 v1(20.66,121.09)
  L06_PWR01 w0.381: 18.75,124.61 v1(17.8,124.61) 17.45,124.96
  L06_PWR01 w0.406: 20.78,121.81 20.66,121.68 v1(20.66,121.09)
  BOTTOM w0.254: v1(17.8,124.61) 17.85,124.61 17.88,124.57 R298.1 ; C197.1 20.66,121.5 v1(20.66,121.09) 20.75,121 R310.1 ; C210.1 17.05,112.68 v1(17.19,112.82) ; C211.1 26.17,113.89 v1(26.3,114.02)
  vias: v1(13.44,109.82)
VLDO_CSI_1V8: length 1.6
  BOTTOM w0.305: U50.5 58.54,149.15 58.37,149.32 R248.1
VLDO_CSI_3V3: length 1.8
  BOTTOM w0.305: R247.1 59.04,149.22 U50.6
VMAIN: length 5.5
  TOP w0.254: R199.1 v1(26.17,34.06)
  BOTTOM w0.254: R444.2 32.08,40.03 v1(32.63,39.49) ; v1(38.47,46.03) 38.37,45.92 C420.1 36.75,45.92 36.69,45.86 U89.15
  BOTTOM w0.305: U120.2 C505.1
  vias: v1(15.19,47.09) v1(15.19,46.63) v1(15.65,47.09) v1(15.65,46.63) v1(15.65,42.45) v1(15.65,41.99) v1(15.65,41.53) v1(15.65,41.08) v1(16.1,47.09) v1(16.1,46.63) v1(16.1,42.45) v1(16.1,41.99) v1(16.1,41.53) v1(16.1,41.08) v1(26.82,31.79) v1(27.78,31.79) v1(28.75,33.49) v1(28.75,32.7) v1(28.75,31.79) v1(29.71,33.49) v1(29.71,32.7) v1(29.71,31.79) v1(38.27,48.76) v1(38.93,44.52) v1(38.93,43.55) v1(38.93,42.59) v1(38.93,41.62) v1(39.23,48.76) v1(39.23,47.8) v1(39.23,46.83) v1(39.89,44.52) v1(39.89,43.55) v1(39.89,42.59) v1(39.89,41.62) v1(40.2,48.76) v1(40.2,47.8) v1(40.2,46.83) v1(45.58,7.53) v1(46.5,7.53)
VPHY_3V3_FT4232: length 3.3
  TOP w0.254: U48.4 v1(18.01,16.71)
  BOTTOM w0.254: FL14.1 C486.2 18.26,16.97 v1(18.01,16.71)
VPLL_3V3_FT4232: length 9.1
  TOP w0.254: U48.9 v1(15.69,14.21) 15.03,14.21 13.42,12.61 13.42,10.5 13.65,10.27 R235.2
  BOTTOM w0.254: v1(15.69,14.21) C494.2 14.91,14.18 FL15.1
VPP_1V8: length 8.4
  TOP w0.254: TP35.1 23.57,82.84 C81.1
  TOP w0.305: C81.1 v1(22.73,82.04) 22.23,81.54 U27.11
  TOP w0.356: U18.F7 v1(34.68,99.67)
  L06_PWR01 w0.457: v1(22.73,82.04) 23.44,82.04
  L08_PWR03 w0.305: 35.03,99.31 v1(34.68,99.67) 34.31,99.29
  BOTTOM w0.254: C288.1 29.19,99.73 28.99,99.53 v1(28.99,99.51) C291.1
  BOTTOM w0.305: v1(34.68,99.67) 34.48,99.46 C290.1
VPP_EN: length 75.4
  TOP w0.132: U27.19 v1(18.24,84.54)
  L05_SIG02 w0.102: v1(18.24,84.54) 18.24,82.95 18.43,82.75 18.74,82.75 18.9,82.59 18.9,76.91 19.37,76.44 19.37,74.66 18.62,73.9 18.62,68.46 18.15,67.99 18.15,66.96 17.92,66.73 17.92,61.01 19.6,59.34 34.74,59.34 35.85,60.45 42.19,60.45 43.65,58.99 43.65,56.68 45.13,55.21 45.13,45.95 46.8,44.27 46.9,44.27 48.95,42.23 v1(49.29,42.23)
  BOTTOM w0.14: U92.5 50.22,43.11 49.34,42.23 v1(49.29,42.23)
VRTC_PMIC_1V8: length 2.8
  TOP w0.305: U27.3 22.36,77.54 TP37.1 22.82,77.09 C86.1
VSEL_SD_SOC: length 59.7
  TOP w0.132: v1(16.24,83.17) U27.23
  TOP w0.14: v1(39.97,113.24) 39.99,113.26 40.29,113.26 40.89,112.66 40.89,112.28 U18.N22 ; TP19.1 14.37,100.9 v1(14.28,100.8) 13.99,101.09 R87.1
  L03_SIG01 w0.102: v1(14.28,100.8) 14.06,101.02 14.06,102.06 14.94,102.94 19.25,102.94 19.89,103.58 21.25,103.58 21.9,104.23 25.33,104.23 27.25,106.15 28.09,106.15 30,108.06 33.29,108.06 33.48,108.25 33.48,109.44 33.25,109.67 32.45,109.67 32.06,109.67 31.88,109.84 31.88,111.08 32.06,111.26 38.91,111.26 39.5,111.86 39.5,112.78 v1(39.97,113.24)
  L10_SIG03 w0.102: v1(16.24,83.17) 15.22,84.19 15.22,88.53 15.65,88.96 15.65,95.73 15.15,96.23 15.15,99.93 v1(14.28,100.8)
WKUP_LFOSCO_XI: length 7.8
  TOP w0.14: Y2.1 24.74,98.87 C45.1 27.21,98.87 27.52,99.19 27.52,99.72 27.84,100.04 30.25,100.04 30.48,100.26 U18.A8
WKUP_LFOSCO_XO: length 7
  TOP w0.14: U18.A9 30.69,101.27 27.71,101.27 27.21,101.77 C42.1 24.74,101.77 Y2.2
WKUP_UART0_CTS_3V3: length 96
  TOP w0.132: U18.C10 v1(32.28,102.07)
  L03_SIG01 w0.102: v1(26.8,16.27) 26.78,16.24 25.28,16.24 24.51,17.01 24.51,24.62 23.87,25.26 23.87,33.32 24.35,33.8 24.35,40 23.55,40.8 23.55,47.41 24.41,48.27 24.41,48.96 24.6,49.15 24.6,50.14 24.23,50.51 24.23,51.11 24.72,51.6 24.72,53.58 23.93,54.37 23.93,60.36 23.23,61.06 23.23,66.28 22.94,66.57 22.94,70.48 23.55,71.08 23.55,80.99 26.93,84.37 26.93,94.43 27.56,95.07 27.56,97.47 29.57,99.48 29.57,99.93 31.3,101.67 31.88,101.67 v1(32.28,102.07)
  BOTTOM w0.14: U118.9 26.71,15.57 26.8,15.66 v1(26.8,16.27)
WKUP_UART0_RTS_3V3: length 91
  TOP w0.132: U18.C8 v1(32.28,100.47)
  L03_SIG01 w0.102: v1(25.64,17.87) 25.12,18.39 25.12,25.1 24.94,25.28 24.94,40.08 24.02,41 24.02,46.03 26.19,48.2 26.19,50.2 27.13,51.14 27.13,60.24 28.17,61.28 28.17,75.38 28.9,76.1 28.9,81.81 27.38,83.33 27.38,94.24 28.02,94.88 28.02,97.24 30.03,99.25 30.03,99.61 30.48,100.07 31.68,100.07 32.08,100.47 v1(32.28,100.47)
  BOTTOM w0.14: v1(25.64,17.87) U118.7
WKUP_UART0_RX_3V3: length 92.3
  TOP w0.132: U18.C9 v1(32.28,101.27)
  L03_SIG01 w0.102: v1(32.28,101.27) 31.88,100.87 30.93,100.87 29.8,99.73 29.8,99.39 27.79,97.38 27.79,94.97 27.16,94.34 27.16,81.73 27.61,81.27 27.61,70.35 26.88,69.61 26.88,68.09 25.71,66.92 25.71,59.09 26.04,58.76 26.04,51.7 25.29,50.95 25.29,48.37 23.78,46.85 23.78,40.92 24.64,40.06 24.64,33.69 24.1,33.15 24.1,25.56 24.79,24.87 24.79,18.05 25.71,17.13 v1(26.24,17.13)
  BOTTOM w0.14: v1(26.24,17.13) 26.04,16.93 U118.8
WKUP_UART0_TX_3V3: length 95.8
  TOP w0.132: U18.E9 v1(33.88,101.27)
  L03_SIG01 w0.102: v1(24.99,17.2) 25.54,16.65 26.43,16.65 26.9,17.12 26.9,18.07 26.03,18.94 26.03,20.6 26.28,20.84 26.28,28.7 25.17,29.8 25.17,39.66 25.76,40.26 25.76,45.76 27.23,47.23 27.23,49.92 28.15,50.84 28.15,60.49 28.48,60.82 28.48,74.07 29.15,74.75 29.15,81.99 27.61,83.53 27.61,94.15 28.25,94.78 28.25,97.09 30.42,99.27 31.65,99.27 31.88,99.5 31.88,99.83 32.11,100.07 32.45,100.07 32.68,100.3 32.68,100.64 32.91,100.87 33.48,100.87 v1(33.88,101.27)
  BOTTOM w0.14: U118.6 25.24,16.95 24.99,17.19 v1(24.99,17.2) 24.99,17.59 R535.2
WL_LT_EN: length 9.6
  TOP w0.14: U1.8 44.78,151.53 44.94,151.69 R6.1 R7.2 46.15,150.78 46.65,150.28 46.65,147.18 47.36,146.47 48.2,146.47 48.51,146.78 U2.9
WLAN_ALERT_1V8: length 34.2
  TOP w0.14: U1.5 v1(42.9,148.39) ; v1(11.78,148.74) 11.88,148.84 R8.2
  L05_SIG02 w0.102: v1(42.9,148.39) 42.6,148.7 42.08,148.7 40.98,149.8 38.9,149.8 37.83,150.87 28.89,150.87 26.76,148.74 v1(11.78,148.74)
WLAN_ALERTN: length 143.8
  TOP w0.14: U1.10 42.9,153.16 43.28,153.54 R2.1 v1(44.19,153)
  L03_SIG01 w0.102: v1(72.27,57.52) 67.99,53.24 66.06,53.24 63.41,50.59 v1(60.96,50.59)
  L05_SIG02 w0.102: v1(72.27,57.52) 71.53,58.25 71.53,63.77 70.88,64.42 70.88,79.19 70.33,79.74 70.33,87.05 70.88,87.6 70.88,101.32 72.26,102.7 72.26,109.57 73.03,110.35 73.03,118.33 73.61,118.91 73.61,139.68 72.65,140.64 69.74,140.64 67.56,142.83 66.36,142.83 62.18,147 59.67,147 58.98,147.69 48.64,147.69 46.84,149.49 46.84,150.34 v1(44.19,153)
  BOTTOM w0.14: v1(60.96,50.59) 56.2,45.84 U92.16
WLAN_EN: length 47.9
  TOP w0.132: U18.F22 v1(34.68,112.46)
  TOP w0.14: v1(45.19,148.15) 45.03,147.99 R12.2 R11.1 42.64,147.99 42.4,148.22 U1.4
  BOTTOM w0.14: v1(34.68,112.46) 34.68,113.46 35.12,113.89 35.12,115.44 33.38,117.18 33.38,123.81 33.63,124.07 33.63,126.94 33.38,127.19 33.38,132.9 37.59,137.12 37.59,140.3 39.68,142.38 39.68,145.81 40.09,146.22 41.7,146.22 43.15,147.66 44.71,147.66 v1(45.19,148.15)
WLAN_EN_3V3: length 8.1
  TOP w0.14: R10.2 41.67,147.43 v1(41.61,147.36) ; U1.11 v1(42.4,153.33)
  L03_SIG01 w0.102: v1(42.4,153.33) 42.4,153.11 41.04,151.74 41.04,149.18 41.34,148.87 41.34,147.55 41.53,147.36 v1(41.61,147.36)
WLAN_IRQ: length 61.1
  TOP w0.132: U18.E21 v1(33.88,111.66)
  TOP w0.14: v1(4.75,140.04) 4.25,139.54 J2.21
  L05_SIG02 w0.102: v1(16.91,124.47) 16.86,124.52 16.46,124.52 15.53,125.46 14.62,125.46 14.35,125.73 12.29,125.73 10.52,127.51 10.52,135.07 9.5,136.08 9.5,139.71 8.56,140.65 5.36,140.65 v1(4.75,140.04)
  L10_SIG03 w0.102: v1(16.91,124.47) 17.11,124.27 17.11,122.37 15.78,121.03 15.78,113.54 19.04,110.28 24.57,110.28 24.88,110.58 25.63,110.58 25.99,110.94 28.37,110.94 29.5,112.06 33.48,112.06 v1(33.88,111.66)
  BOTTOM w0.14: R262.1 v1(4.75,140.04)
WLAN_SDIO_RST: length 55.7
  TOP w0.14: J2.23 v1(3.84,140.04) ; v1(40.09,147.32) 40.93,147.32 41.13,147.52 R9.1 41.13,148.21 41.4,148.48 U1.2
  L05_SIG02 w0.102: v1(3.84,140.04) 3.84,146.54 5.6,148.31 8.56,148.31 10.19,146.67 10.19,143.67 11.18,142.68 13.59,142.68 15.17,144.26 23.68,144.26 29.48,150.07 36.82,150.07 39.57,147.32 v1(40.09,147.32)
XDS110_DIR: length 3.1
  BOTTOM w0.14: 65.56,21.71 65.56,21.11 65.73,20.93 U111.4 ; 65.56,21.71 65.41,21.85 65.41,22.05 R517.2 ; 65.56,21.71 65.71,21.86 66.2,21.86 66.34,21.72 U111.5
XDS110_EMU0: length 21.2
  TOP w0.14: v1(72.49,12.16) 71.95,12.16 71.57,12.55 R234.2 71.14,13.07 70.78,13.43 U47.42
  L05_SIG02 w0.102: v1(64.04,17.51) 64.04,13.25 67.43,9.85 70.18,9.85 v1(72.49,12.16)
  BOTTOM w0.14: U112.7 62.81,18.22 63.51,17.51 v1(64.04,17.51)
XDS110_EMU1: length 15.3
  TOP w0.14: U47.43 R233.2 71.57,14.34 71.42,14.48 v1(71.1,14.48)
  BOTTOM w0.14: v1(71.1,14.48) 68.72,14.48 68.26,14.94 67.32,14.94 66.72,14.33 65.87,14.33 65.52,14.69 65.52,17.56 64.96,18.11 63.59,18.11 63.16,18.55 U112.6
XDS110_TCK: length 11.7
  TOP w0.14: v1(68.28,10.3) 68.61,10.63 U47.35
  L05_SIG02 w0.102: v1(68.28,10.3) 67.63,10.3 67.26,10.67 67.26,15.36 67.67,15.76 67.67,17.82 v1(67.34,18.15)
  BOTTOM w0.14: U111.14 67.14,18.34 v1(67.34,18.15)
XDS110_TDI: length 9.9
  TOP w0.14: v1(66.47,18.13) 66.47,16.03 67.12,15.38 67.12,12.76 68.11,11.77 68.81,11.77 68.86,11.83 U47.38
  BOTTOM w0.14: v1(66.47,18.13) 66.74,18.39 U111.15
XDS110_TDO: length 18.4
  TOP w0.14: v1(60.52,21.27) 61.78,20 61.97,20 62.88,19.09 62.88,17.97 63.93,16.92 63.93,14.57 64.26,14.24 64.26,12.69 65.41,11.55 67.81,11.55 67.93,11.43 U47.37
  BOTTOM w0.14: v1(60.52,21.27) 59.92,20.67 U109.7
XDS110_TMS: length 10.9
  TOP w0.14: U47.36 v1(67.66,11.03)
  L05_SIG02 w0.102: v1(68.07,18.55) 68.07,14.01 67.66,13.6 v1(67.66,11.03)
  BOTTOM w0.14: v1(68.07,18.55) 67.69,18.55 67.54,18.7 U111.13
XDS110_TRST#: length 9.2
  TOP w0.132: v1(68.69,19.01) 68.69,18.48 67.98,17.77 67.98,13.65 69,12.63 U47.40
  BOTTOM w0.14: U111.12 67.97,19.73 v1(68.69,19.01)
XDS_GPIO1: length 1.8
  TOP w0.14: v1(64.49,28.63) 64.6,28.52 U44.2
  BOTTOM w0.14: R484.2 v1(64.49,28.63)
XDS_GPIO2: length 2.4
  BOTTOM w0.14: R481.2 59.35,27.99 U102.7
XDS_GPIO3: length 1.8
  TOP w0.14: U44.4 v1(65.4,28.63)
  BOTTOM w0.14: R483.2 v1(65.4,28.63)
XDS_GPIO4: length 1.9
  TOP w0.14: U44.6 66.2,28.44 v1(66.39,28.63)
  BOTTOM w0.14: v1(66.39,28.63) 66.52,28.51 R482.2
XDS_I2C1_EN: length 3.2
  BOTTOM w0.14: R471.2 61.94,35.57 R470.1 63.85,35.57 U97.5
XDS_PORZN: length 9.8
  TOP w0.14: v1(66.52,34.39) 66.6,34.3 U44.8
  L05_SIG02 w0.102: v1(66.52,34.39) 63.96,31.83 60.95,31.83 v1(60.09,32.69)
  BOTTOM w0.14: R472.2 v1(60.09,32.69)
XDS_POWERDOWN: length 2.5
  TOP w0.14: U44.12 65,35.05 64.8,35.26 R194.2
XDS_RSTN: length 5.6
  TOP w0.14: v1(66.64,22.55) 66.64,22.58 66.37,22.85 U47.70 66.37,25.35 TP78.1
  BOTTOM w0.14: v1(66.64,22.55) 66.64,22.97 R506.1 65.51,23.61 65.13,23.23 R511.1
XDS_SHIELD:
  vias: v1(77.57,12.08) v1(78.59,11.52) v1(78.59,10.61) v1(79.02,22.16) v1(80.8,22.16) v1(81.71,22.16) v1(82.07,18.25) v1(82.07,16.73) v1(82.07,15.2) v1(83.59,18.25) v1(83.59,16.73) v1(83.59,15.2)
XDS_USB_DM: length 29.7
  TOP w0.102: v1(77.73,16.05) 78.01,16.32 78.41,16.32 78.63,16.1 J18.2 ; U47.93 57.12,23.68 57.12,22.87 57.07,22.82 57.07,22.45 v1(57.35,22.18)
  L05_SIG02 w0.102: v1(57.35,22.18) 56.99,22.53 56.99,22.76 57.74,23.51 67.9,23.51 71.22,20.2 71.55,20.2 74.94,16.8 75.72,16.8 76.09,16.42 77.63,16.42 77.73,16.32 v1(77.73,16.05)
  BOTTOM w0.102: U115.5 77.1,16.18 77.25,16.32 77.46,16.32 v1(77.73,16.05)
XDS_USB_DP: length 29.7
  TOP w0.102: U47.94 56.81,23.68 56.81,22.87 56.86,22.82 56.86,22.45 v1(56.59,22.18) ; J18.3 78.63,16.75 78.41,16.53 78.01,16.53 v1(77.73,16.81)
  L05_SIG02 w0.102: v1(77.73,16.81) 77.55,16.63 76.18,16.63 75.8,17 75.03,17 71.63,20.4 71.3,20.4 67.99,23.71 57.65,23.71 56.79,22.85 56.79,22.38 v1(56.59,22.18)
  BOTTOM w0.102: v1(77.73,16.81) 77.46,16.53 77.25,16.53 77.1,16.68 U115.4
XDS_USB_ID: length 38.6
  TOP w0.14: J18.4 77.47,17.4 76.24,16.18 v1(75.66,16.18) ; R204.2 v1(56.68,27.17)
  L03_SIG01 w0.102: v1(75.66,16.18) 73.39,13.91 57.76,13.91 56.15,15.52 56.15,22.76 56.68,23.29 v1(56.68,27.17)
  BOTTOM w0.14: U115.2 v1(75.66,16.18)
XDS_USB_VBUS: length 4.6
  TOP w0.254: TP89.1 74.73,14.36 C155.1 ; v1(49,7.93) 49,7.46 49.21,7.26 R237.1
  BOTTOM w0.254: R496.1 57.06,25.74 v1(57.44,26.12) ; v1(76.6,15.09) 76.77,15.26 U115.6 ; R507.1 78.98,24.46 v1(78.72,24.73)
  vias: v1(74.16,21.63) v1(74.16,20.71) v1(74.94,20.71) v1(75.68,15.09) v1(77.51,15.09)
XDS_VREF: length 18.4
  TOP w0.203: U47.9 59.17,7.23 59.51,6.88 C165.2
  TOP w0.254: v1(70.58,7.39) R239.2 72.44,6.88 72.69,7.13 C161.1 U49.3 ; C165.2 v1(59.87,6.31)
  L03_SIG01 w0.305: v1(59.87,6.31) 60.3,6.74 60.3,7.07 61.04,7.81 70.16,7.81 v1(70.58,7.39)
XDS_WARMRESETN: length 1.5
  TOP w0.14: U44.10 65.8,34.27 65.91,34.37 R198.2
N15951749: length 7.3
  BOTTOM w0.254: U56.1 24.06,135.56 24.28,135.79 24.28,137.6 23.63,138.25 C177.1 ; R272.2 R264.2 C177.1 ; C177.1 U56.4
N15952254: length 1.5
  BOTTOM w0.14: R280.1 20.46,136.77 20.65,136.96 U56.3
N16839912: length 2.4
  BOTTOM w0.14: U82.D3 3.9,73.76 C385.1 4.01,74.42 4.15,74.56 R375.1
N16839940: length 2.5
  BOTTOM w0.14: U83.D3 41.15,68.38 C392.1 41.15,70.14 41.28,70.27 R378.1
N16839975: length 2.5
  BOTTOM w0.14: R382.1 32.01,70.31 31.86,70.17 C394.1 31.86,68.38 U85.D3
N16856152: length 5.2
  TOP w0.14: U48.3 15.84,17.21 15.56,16.93 C149.1 14,16.93 12.63,15.56 Y5.2
N16856224: length 5.2
  TOP w0.14: U48.2 15.84,17.71 15.56,18 C148.1 14.01,18 12.64,19.36 Y5.1
N16857368: length 1.6
  BOTTOM w0.14: C504.2 13.06,10.09 U121.2
N16878333: length 1.2
  BOTTOM w0.14: R560.2 19.47,14.51 19.91,14.07 U119.5
N16878339: length 2.4
  BOTTOM w0.14: R561.1 18.59,14.86 19.08,14.37 19.08,13.41 19.23,13.26 U119.4
N16878497: length 1.9
  TOP w0.14: v1(57.48,79.26) 57.23,79.01 U28.H5
  BOTTOM w0.14: TP100.1 57.42,79.26 v1(57.48,79.26) R368.1
N16880083: length 2.6
  TOP w0.14: R106.2 5.06,90.53 4.86,90.74 v1(4.86,91.16) 5.17,91.47 U24.1
  BOTTOM w0.14: v1(4.86,91.16) 4.49,90.79 R353.1
N16893179: length 1.2
  BOTTOM w0.14: U110.5 31.22,21.03 31.66,21.47 R520.2
N16893185: length 2.4
  BOTTOM w0.14: R516.1 31.69,22.36 31.2,21.88 30.57,21.88 30.41,21.72 U110.4
N16894003: length 1.4
  BOTTOM w0.14: R540.2 24.14,17.17 24.56,16.75 24.74,16.75 24.84,16.64 U118.5
N16894009: length 2.5
  BOTTOM w0.14: U118.4 24.15,15.57 23.99,15.73 23.99,16.43 23.25,17.17 R541.1
N16906426: length 4.8
  TOP w0.14: Y1.1 22.24,105.8 22.24,106 22.55,106.3 23.83,106.3 24.05,106.09 C33.2 25.01,106.09 25.63,105.47 R71.1
N16906432: length 2.6
  TOP w0.14: Y1.3 23.65,104.19 23.8,104.04 C36.2 R74.1
N16927060: length 1.9
  TOP w0.14: U13.72 15.22,112.77 14.94,112.48 14.94,112.01 R57.2
N16927228: length 1.1
  TOP w0.14: U13.69 R54.1
N16927289: length 1.3
  TOP w0.14: R48.2 26.16,121.76 25.68,121.27 U13.36
N16929458: length 2.6
  TOP w0.14: TP62.1 v1(79.69,47.29)
  BOTTOM w0.14: U88.7 79.19,47.79 v1(79.69,47.29)
N16929460: length 1.5
  TOP w0.14: TP61.1 v1(78.77,47.29)
  BOTTOM w0.14: U88.8 v1(78.77,47.29)
N16929474: length 1.8
  BOTTOM w0.14: U88.41 73.62,51.58 73.62,52.68 R404.2
N16929699: length 1.4
  TOP w0.14: C115.1 v1(78.77,49.29)
  BOTTOM w0.14: U88.4 v1(78.77,49.29)
N16929703: length 1.4
  TOP w0.14: C119.1 v1(78.77,48.29)
  BOTTOM w0.14: U88.6 v1(78.77,48.29)
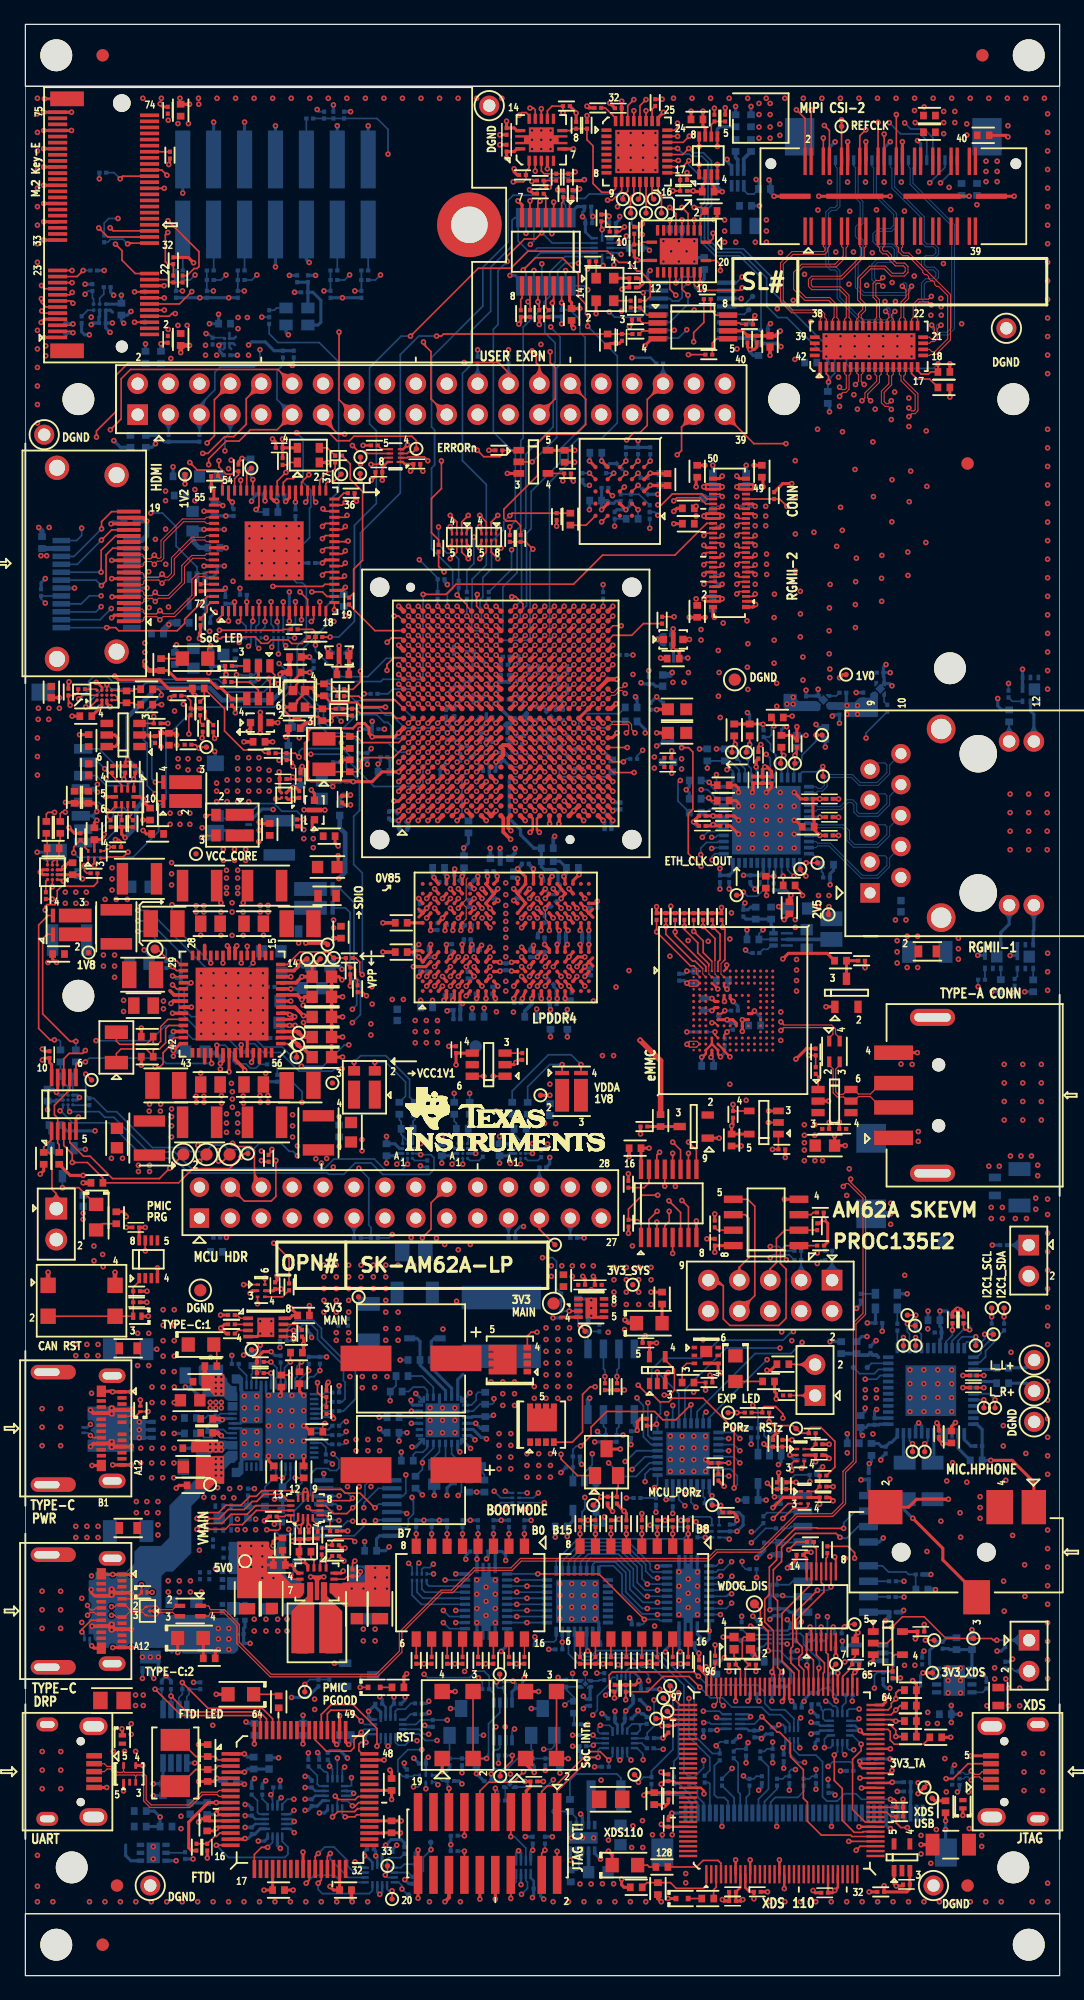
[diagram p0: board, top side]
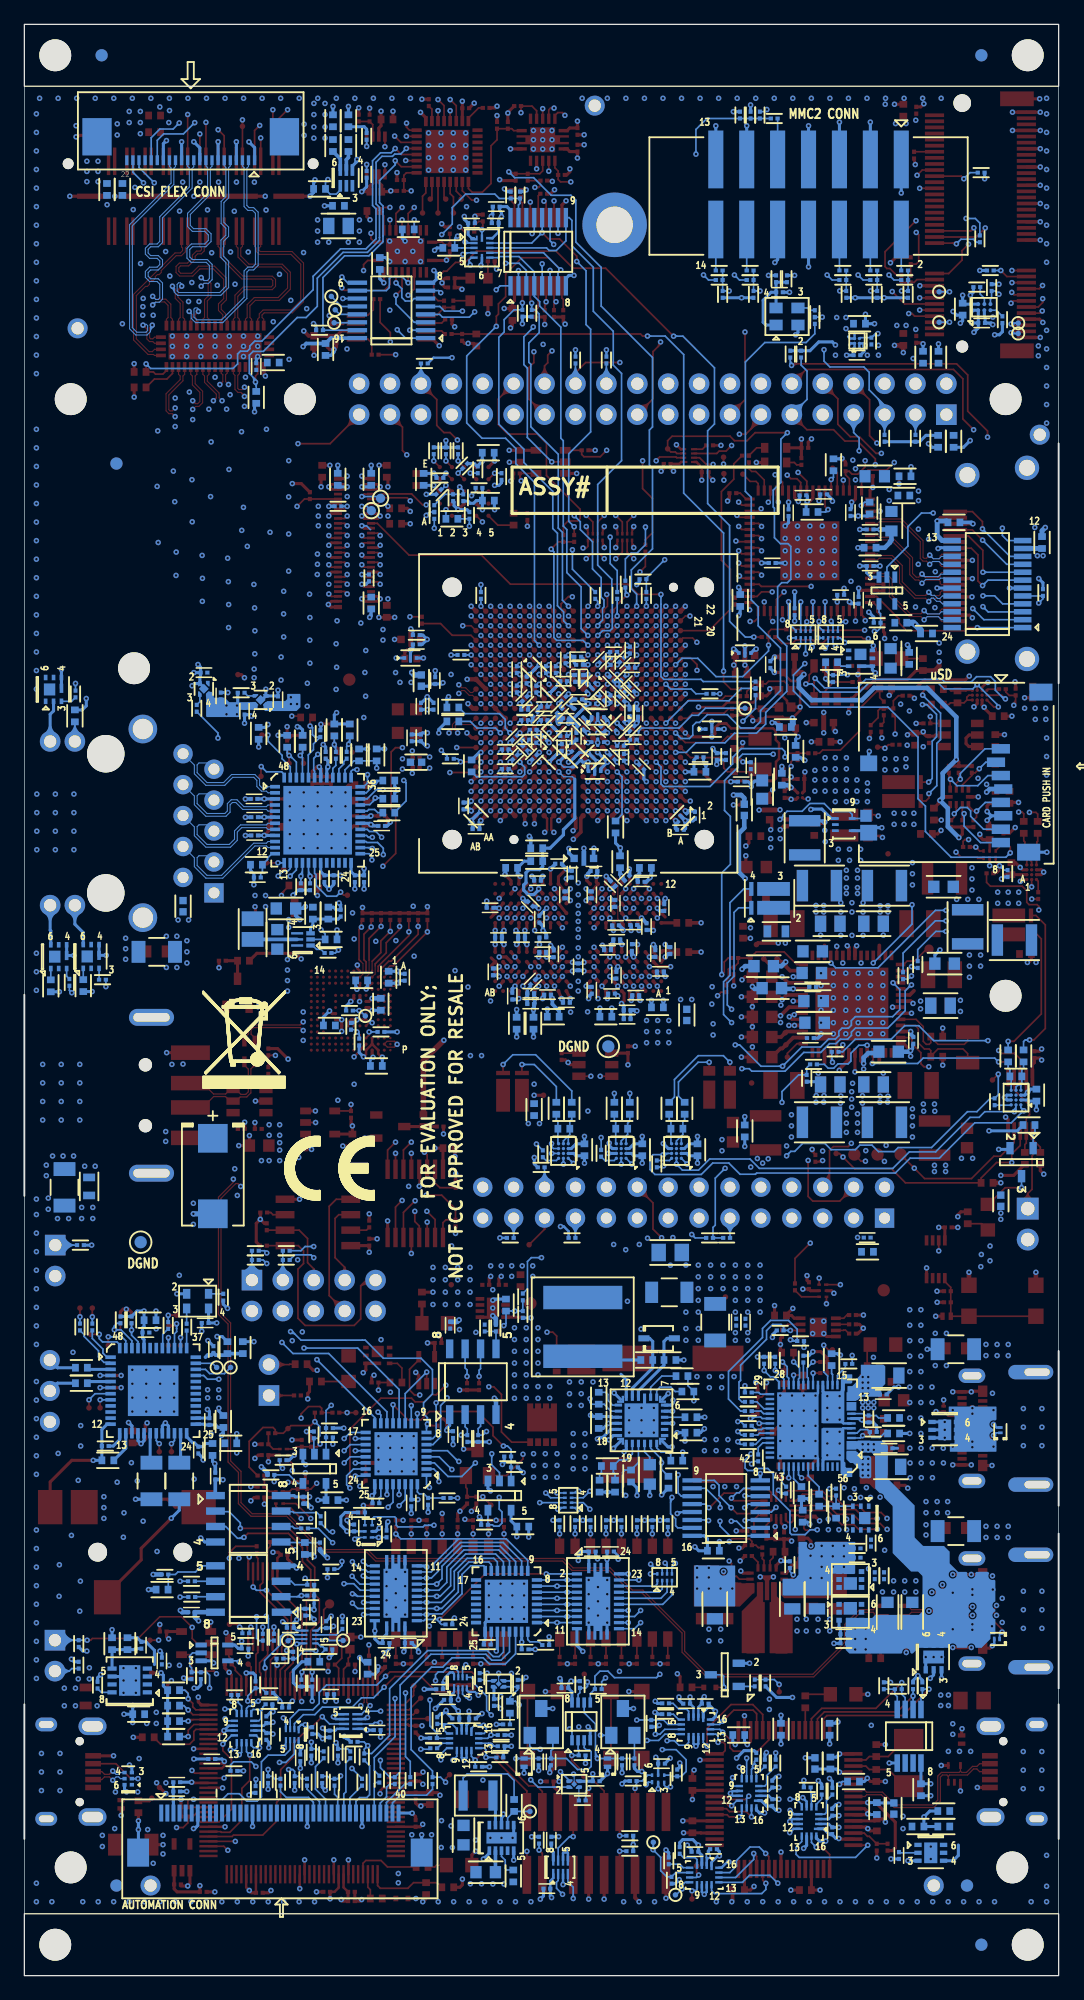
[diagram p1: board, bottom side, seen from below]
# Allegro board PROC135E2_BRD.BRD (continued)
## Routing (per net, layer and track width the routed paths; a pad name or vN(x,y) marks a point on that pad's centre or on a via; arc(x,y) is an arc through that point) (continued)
N16929744: length 1.6
  TOP w0.14: TP67.1 v1(73.91,43.69)
  BOTTOM w0.14: v1(73.91,43.69) 74.16,43.94 U88.19
N16929747: length 1.6
  TOP w0.14: TP66.1 v1(72.91,43.69)
  BOTTOM w0.14: U88.22 72.66,43.94 v1(72.91,43.69)
N16929749: length 1.9
  BOTTOM w0.14: TP102.1 69.53,50.29 U88.35
N16929751: length 3.2
  BOTTOM w0.14: TP103.1 68.56,49.44 69.77,49.44 70.12,49.79 U88.34
N16931396: length 1.5
  BOTTOM w0.14: U53.B2 6.11,137.76 6.44,138.1 R270.2
N16931420: length 1.2
  BOTTOM w0.14: R281.1 5.12,136.78 U53.C1
N16943223: length 1.7
  TOP w0.14: R33.1 50.7,135.73 U7.2
N16947096: length 1.4
  TOP w0.14: R23.1 U6.1
N16960546: length 1.5
  TOP w0.14: U12.B2 v1(50.35,120.4)
  BOTTOM w0.14: R313.2 v1(50.35,120.4)
N16990175: length 2.7
  BOTTOM w0.14: R555.2 61.77,15.32 60.75,14.3 J23.27
N16990176: length 2.4
  BOTTOM w0.14: R556.2 59.51,14.9 59.25,14.64 J23.30
N16990179: length 4.7
  BOTTOM w0.14: J23.31 58.75,14.92 58.57,15.09 58.57,17.48 58.21,17.84 R533.2
N16990180: length 2.7
  BOTTOM w0.14: R557.2 58.25,14.61 J23.32
N16990246: length 4.4
  BOTTOM w0.14: J23.26 61.25,14.24 61.64,14.64 63.47,14.64 63.95,15.12 R554.2
N16990247: length 5.1
  BOTTOM w0.14: J23.28 60.25,14.5 61.08,15.33 61.08,17.16 60.4,17.84 R532.2
N16990252: length 5.3
  BOTTOM w0.14: R536.2 56.63,17.24 56.63,14.86 56.86,14.63 57.44,14.63 57.75,14.32 J23.33
N16994873: length 1.2
  BOTTOM w0.14: R499.2 47.18,24.28 47.11,24.21 U107.4
N16994875: length 1.1
  BOTTOM w0.102: R562.2 U117.4
N16995245: length 0.9
  BOTTOM w0.14: R519.2 C474.1
N16997746: length 5.6
  TOP w0.14: R232.1 74.33,19.53 73.8,19.01 71.42,19.01 71.07,19.35 71.07,20.05 70.89,20.23 U47.59
N17030208: length 1.6
  BOTTOM w0.14: U111.7 67.14,22.15 67.43,22.43 R515.2
N17031262: length 1.7
  TOP w0.254: LD6.2 R203.2
N17078351: length 1.5
  TOP w0.14: SW2.13 R209.1
N17078353: length 1.5
  TOP w0.14: SW2.14 R210.1
N17078355: length 1.5
  TOP w0.132: SW2.15 R211.1
N17078357: length 1.5
  TOP w0.102: 41.01,27.42 R212.1
  TOP w0.14: SW2.16 41.01,27.42
N17078758: length 1.5
  TOP w0.14: SW3.11 R215.1
N17078760: length 1.5
  TOP w0.14: SW3.12 R216.1
N17078762: length 1.5
  TOP w0.14: SW3.13 R217.1
N17078764: length 1.5
  TOP w0.14: SW3.14 R218.1
N17078766: length 1.5
  TOP w0.14: SW3.9 R213.1
N17078768: length 1.5
  TOP w0.14: SW3.10 R214.1
N17078770: length 1.5
  TOP w0.14: SW3.15 R219.1
N17078778: length 1.5
  TOP w0.14: SW3.16 R220.1
N17078974: length 2
  BOTTOM w0.14: J16.2 81.31,25.01 81.1,25.22 R495.2
N17084256: length 1.5
  TOP w0.132: SW2.9 R205.1
N17084257: length 1.5
  TOP w0.14: SW2.10 R206.1
N17084258: length 1.5
  TOP w0.14: SW2.11 R207.1
N17084259: length 1.5
  TOP w0.14: SW2.12 R208.1
N17110597: length 1.5
  TOP w0.14: v1(64.16,91.39) TP26.1
  BOTTOM w0.14: v1(64.16,91.39) U78.13
N17137240: length 1.6
  BOTTOM w0.14: J6.11 R330.2
N17153379: length 15.6
  TOP w0.14: v1(2.4,95.54) 1.86,95.54 1.72,95.4 R102.2 ; v1(14.48,93.48) 14.64,93.64 R101.3
  L03_SIG01 w0.102: v1(14.48,93.48) 14.36,93.36 9.2,93.36 8.37,94.2 4.68,94.2 4.07,94.81 3.13,94.81 v1(2.4,95.54)
N17153381: length 15
  TOP w0.14: R103.2 2.87,95.43 3,95.56 v1(3.29,95.56) ; v1(14.82,95.24) 14.99,95.24 15.09,95.34 R101.2
  L03_SIG01 w0.102: v1(14.82,95.24) 14.72,95.14 14.69,95.14 13.2,93.64 9.5,93.64 8.66,94.48 4.83,94.48 4.19,95.11 3.66,95.11 3.29,95.48 v1(3.29,95.56)
N17153383:
  vias: v1(25.33,86.7) v1(25.33,86.06)
N17153415: length 24.2
  L05_SIG02 w0.102: v1(26.88,79.36) 27.38,78.86 27.38,77.58 30.18,74.78 34.37,74.78 36.04,73.11 36.04,72.56 36.14,72.46 v1(36.51,72.46)
  BOTTOM w0.14: R380.2 v1(36.51,72.46) ; v1(26.88,79.36) 27.23,79.72 27.23,81.52 26.68,82.07 26.68,87.32 26.3,87.7 R356.1
N17153417: length 25.6
  L05_SIG02 w0.102: v1(26.88,78.27) 26.88,77.72 30.11,74.49 34.24,74.49 35.76,72.97 35.76,72.65 35.58,72.46 v1(35.24,72.46)
  BOTTOM w0.14: v1(26.88,78.27) 27.54,78.93 27.54,81.62 27.01,82.15 27.01,88.12 25.88,89.25 R356.4 ; R381.2 v1(35.24,72.46)
N17153507: length 11.3
  TOP w0.14: v1(10.67,97.08) 10.67,96.71 10.91,96.47 R94.1 ; R66.2 10.92,105.66 11.18,105.4 v1(11.18,105.17)
  BOTTOM w0.14: v1(11.18,105.17) 9.71,103.7 9.71,101.51 10.01,101.21 10.01,97.73 v1(10.67,97.08)
N17153509: length 8.7
  TOP w0.14: R94.4 v1(10.68,98.02) ; R72.2 v1(11.2,104.39)
  BOTTOM w0.14: v1(10.68,98.02) 10.39,98.31 10.39,101.39 10.04,101.74 10.04,103.59 10.83,104.39 v1(11.2,104.39)
N17153511: length 3.3
  TOP w0.14: U17.D1 7.55,104.76 ; 7.55,104.76 7.55,104.99 7.37,105.16 U17.D2 ; 7.55,104.76 7.78,104.53 C34.2 8.89,104.53 9.04,104.39 R72.1
N17153515: length 2.5
  TOP w0.14: U17.D3 7.57,105.56 7.62,105.51 C34.1 8.84,105.51 8.99,105.66 R66.1
N17153617: length 11.5
  TOP w0.14: R120.1 1.79,85.52 1.42,85.15 1.42,78.98 3.67,76.73 v1(4.15,76.73)
  BOTTOM w0.14: R375.2 v1(4.15,76.73)
N17153619: length 12.9
  TOP w0.14: R120.4 1.86,87.07 1.09,86.3 1.09,77.79 2.03,76.85 v1(2.39,76.85)
  BOTTOM w0.14: R376.2 2.88,76.71 2.74,76.85 v1(2.39,76.85)
N17153623: length 5.6
  TOP w0.14: R132.1 v1(44.11,74.83)
  BOTTOM w0.14: R378.2 41.28,73.02 43.09,74.83 v1(44.11,74.83)
N17153625: length 8.8
  TOP w0.14: R132.4 v1(45.66,74.83)
  BOTTOM w0.14: v1(45.66,74.83) 44.86,75.63 42.98,75.63 40.01,72.66 R379.2
N17153667: length 8.4
  TOP w0.14: R131.3 v1(27.02,75.02)
  BOTTOM w0.14: R382.2 31.57,72.16 31.57,73.6 29.62,75.55 27.55,75.55 v1(27.02,75.02)
N17153669: length 5.8
  TOP w0.14: R131.2 v1(28.71,75.02)
  BOTTOM w0.14: R383.2 31.24,72.24 31.24,73.39 29.62,75.02 v1(28.71,75.02)
N17153681: length 2.6
  TOP w0.14: U25.D3 1.82,91.56 1.79,91.59 C69.1 1.79,93.1 1.72,93.17 R102.1
N17153685: length 3.5
  TOP w0.14: U25.D2 2.22,91.47 2.62,91.87 ; 2.62,91.87 2.77,92.02 C69.2 2.77,93.1 2.87,93.2 R103.1 ; 2.62,91.87 U25.D1
N17153701: length 3.3
  BOTTOM w0.14: R381.1 35.24,70.19 35.42,70.01 C393.2 35.42,69.08 35.55,68.96 ; U84.D2 35.95,68.56 35.55,68.96 ; U84.D1 35.55,68.96
N17153703: length 2.5
  BOTTOM w0.14: U84.D3 36.4,68.38 C393.1 36.4,70.13 36.51,70.24 R380.1
N17153749: length 3.2
  BOTTOM w0.14: U82.D2 3.5,72.99 3.33,73.16 3.1,73.16 ; 3.1,73.16 3.03,73.24 C385.2 3.03,74.38 2.88,74.53 R376.1 ; 3.1,73.16 U82.D1
N17153787: length 3.3
  BOTTOM w0.14: U83.D1 40.3,68.96 ; 40.3,68.96 40.17,69.08 C392.2 40.17,70.17 40.01,70.33 R379.1 ; 40.3,68.96 40.7,68.56 U83.D2
N17153799: length 3.3
  BOTTOM w0.14: U85.D2 31.41,68.56 31.01,68.96 ; 31.01,68.96 30.88,69.08 C394.2 30.88,70.14 30.74,70.29 R383.1 ; 31.01,68.96 U85.D1
N17153878: length 1.5
  BOTTOM w0.14: U84.A3 36.53,66.95 37.29,66.95 R385.1
N17153949: length 1.4
  BOTTOM w0.14: U82.A3 3.93,71.49 R377.1
N17153951: length 1.5
  BOTTOM w0.14: R386.1 42.12,66.95 41.28,66.95 U83.A3
N17154063: length 1.3
  BOTTOM w0.14: R387.1 31.99,66.95 U85.A3
N17167245: length 2
  BOTTOM w0.14: U78.32 56.82,95.64 56.7,95.77 56.21,95.77 55.96,95.51 R348.2
N17253632: length 7.6
  BOTTOM w0.14: R563.2 44.75,16.04 45.28,16.57 48.61,16.57 48.94,16.23 L11.2
  vias: v1(49.93,12.3) v1(50.72,12.73)
N17253649: length 2.5
  BOTTOM w0.254: L11.1 46.28,14.59 U120.9
N17253673: length 2.7
  BOTTOM w0.14: U120.7 45.28,12.96 R563.1 TP106.1
N17253694: length 2.3
  BOTTOM w0.14: R569.2 45.36,8.68 45.48,8.8 45.48,9.48 45.78,9.79 U120.3
N17269599: length 2
  TOP w0.14: U41.6 64.55,43.25 R176.1 R173.2
N17275147: length 1.3
  BOTTOM w0.14: R407.2 U86.3
N17285208: length 12.2
  L10_SIG03 w0.102: v1(1.64,112.73) 3.62,114.71 3.62,117.88 v1(4.63,118.89)
  BOTTOM w0.14: U58.5 R317.1 1.29,113.08 v1(1.64,112.73) ; v1(4.63,118.89) 4.63,118.28 4.21,117.86 U58.12
N17370891: length 1.6
  BOTTOM w0.14: R413.2 18.66,49.45 18.58,49.37 U90.17
N17378539: length 2.1
  TOP w0.14: R228.2 20.69,23.11 LD8.1
N17479799: length 1.3
  BOTTOM w0.14: R507.2 78.67,23.27 U105.8
N17479805: length 4
  BOTTOM w0.254: C458.2 75.89,26.86 75.97,26.77 R488.2 R487.1 U105.5
N17479881: length 3.3
  TOP w0.14: R202.1 68.2,26.21 67.96,25.97 C144.2 67.95,25.56 67.66,25.28 67.66,25.07 67.17,24.57 U47.68
N17481587: length 1.6
  TOP w0.14: LD9.2 51.12,9.08 51.27,8.93 R236.2
N17481598: length 3.8
  TOP w0.203: C143.2 55.36,25.23 55.97,24.62 U47.96
  TOP w0.254: C143.2 55.43,25.28 55.84,25.28 v1(55.93,25.37)
  BOTTOM w0.254: R496.2 56.19,24.76 55.93,25.02 v1(55.93,25.37)
N17481613: length 2.1
  TOP w0.14: U47.95 56.37,24.82 56.68,25.14 R204.1
N17481619: length 6.6
  TOP w0.14: R237.2 51.08,7.64 R238.1 53.02,7.64 53.48,7.17 55.74,7.17 55.97,7.4 U47.1
N17481621: length 3.8
  TOP w0.14: U47.60 71.06,20.63 71.53,20.15 v1(71.53,19.63) R231.2
  BOTTOM w0.14: R231.2 v1(71.53,19.63)
N17481627: length 2.1
  TOP w0.14: R240.1 56.57,7.06 56.77,7.26 U47.3
N17481631: length 1.1
  TOP w0.14: R240.2 LD10.2
N17481633: length 4.8
  TOP w0.14: R225.2 71.76,23.44 71.53,23.22 v1(71.53,22.73) 71.16,22.36 71.16,22.08 70.9,21.83 U47.63
  BOTTOM w0.14: R225.2 71.81,23.44 71.53,23.17 v1(71.53,22.73)
N17481635: length 3.1
  TOP w0.14: U47.61 71.41,21.03 v1(71.53,20.9) R230.2
  BOTTOM w0.14: R230.2 v1(71.53,20.9)
N17481637: length 5.6
  TOP w0.14: R236.1 55.16,8.93 55.69,9.46 56.94,9.46 57.17,9.23 U47.4
N17481641: length 3.5
  TOP w0.14: R229.2 71.89,22.17 v1(71.53,21.82) 71.14,21.43 U47.62
  BOTTOM w0.14: R229.2 71.89,22.17 v1(71.53,21.82)
N17492093: length 1.1
  TOP w0.14: R40.2 29.27,125.37 U10.5
N17492111: length 1.8
  BOTTOM w0.14: R392.1 J10.1
N17498937: length 4
  BOTTOM w0.14: U88.2 77.99,50.37 78.46,50.37 78.91,50.82 78.91,51.32 80.1,52.51 80.1,52.66 R405.2
N17498940: length 3
  BOTTOM w0.14: U88.1 78.2,50.79 78.54,51.13 78.54,51.46 79.41,52.33 R406.2
N17653582: length 1.3
  BOTTOM w0.14: Q5.3 81.11,104.66 R327.2
N17726648: length 2.7
  TOP w0.254: D2.3 R134.2 R135.1
N17796705: length 0.9
  BOTTOM w0.14: Q6.3 78.86,82.73 R364.2
N17796716: length 1
  BOTTOM w0.14: Q7.3 81.52,82.08 R365.2
N17824845: length 1.7
  BOTTOM w0.14: R426.1 24.91,44.85 24.41,44.85 24.31,44.96 U90.36
N17824852: length 1.6
  BOTTOM w0.14: R431.1 24.73,44.4 24.58,44.56 U90.37
N17824859: length 1.7
  BOTTOM w0.14: R436.1 24.9,43.64 24.39,44.16 U90.38
N17824866: length 1.7
  BOTTOM w0.14: U90.39 24.31,43.76 24.69,43.38 R439.1
N17827086: length 2.4
  BOTTOM w0.14: R393.2 R395.2 J11.1
N17827089: length 2.4
  BOTTOM w0.14: J11.3 R396.2 R394.2
N17850096: length 9.8
  L05_SIG02 w0.381: v1(15.62,33.41) 17.68,31.36 17.68,28.08 v1(18.47,27.29)
  BOTTOM w0.254: Q11.3 18.04,28.62 17.93,28.51 C455.2 R485.2 v1(18.47,27.29)
N17935978: length 3.7
  BOTTOM w0.14: R453.1 R449.2 ; R453.1 R446.2 ; R453.1 Q9.3
N18121816: length 3.4
  BOTTOM w0.14: R261.1 J21.2
N18121892: length 3.4
  BOTTOM w0.14: R260.1 J21.4
N18121904: length 3.4
  BOTTOM w0.14: R259.1 J21.6
N18121916: length 3.4
  BOTTOM w0.14: R244.2 J21.9
N18121928: length 3.4
  BOTTOM w0.14: R258.1 J21.12
N18121940: length 3.4
  BOTTOM w0.14: R257.1 J21.14
N18374804: length 2.9
  BOTTOM w0.14: R545.2 56.16,15.86 56.25,15.77 J23.36
N18374807: length 3.1
  BOTTOM w0.14: J23.37 55.75,14.18 55.23,14.69 55.23,15.47 54.97,15.74 R549.2
N18374810: length 3.5
  BOTTOM w0.14: J23.38 55.25,14.22 53.73,15.74 R550.2
N18374813: length 5
  BOTTOM w0.14: R551.2 51.46,15.31 51.95,14.82 54.11,14.82 54.75,14.19 J23.39
N18516151: length 1.1
  TOP w0.14: R109.1 1.68,89.88 U25.A3
N18520654: length 1
  TOP w0.14: U17.A3 5.8,105.66 5.26,105.66 5.25,105.65 R67.1
N18571509: length 1.8
  BOTTOM w0.14: U123.5 30.85,8.86 31.14,9.15 R568.2
N18571515: length 2.1
  BOTTOM w0.14: R565.1 30.82,9.69 29.87,9.69 29.72,9.54 U123.4
N18576337: length 1.8
  BOTTOM w0.14: R342.2 58.75,99.71 58.75,99.51 59.15,99.11 U78.39
N18576340: length 1.7
  BOTTOM w0.14: U78.40 59.65,99.15 59.4,99.39 R341.2
N18736007: length 2.6
  BOTTOM w0.254: U88.14 76.66,43.31 C426.2
N18736028: length 1.6
  BOTTOM w0.254: U88.13 77.16,44.02 77.69,43.49 R437.2
N19082749: length 1.6
  TOP w0.14: U9.3 24.82,125.48 R42.1
N19361712: length 2.7
  TOP w0.14: LD7.1 v1(27.51,23.68)
  BOTTOM w0.14: Q12.3 27.64,24.71 27.53,24.59 27.53,23.69 v1(27.51,23.68)
N19806973: length 1.2
  BOTTOM w0.14: U114.7 50.65,19.09 51.06,18.68 R529.2
N20199452: length 2.4
  TOP w0.254: D1.3 R124.2 R125.1
N20506305: length 1.1
  TOP w0.356: U43.11 24.46,30.77 24.71,30.52
N20506307: length 1.2
  TOP w0.33: 23.31,30.46 23.46,30.62 U43.9
N20506388: length 1.7
  TOP w0.14: v1(21.81,32.92) 21.81,32.7 21.95,32.56 U43.6
  BOTTOM w0.132: v1(21.81,32.92) 22.09,33.2 R469.1
N20506390: length 1.2
  TOP w0.14: R197.1 24.36,34.24 24.21,34.1 U43.2
N20506392: length 1.2
  TOP w0.14: U43.1 24.71,33.97 R199.2
N20506511: length 1.4
  TOP w0.14: U43.3 23.71,34.08 23.47,34.33 C136.1
N20878915: length 1.8
  TOP w0.14: R16.2 44.96,145.72 44.72,145.48 U5.1
N20878927: length 1.8
  TOP w0.14: R15.1 44.19,145.71 44.07,145.58 U5.2
N20878931: length 2.1
  TOP w0.14: U5.11 42.77,137.01 R32.2
N20900570: length 1.6
  TOP w0.14: U7.3 50.7,135.08 R35.1
N20900572: length 2.5
  TOP w0.14: U7.8 56.75,136.38 56.32,136.81 R26.1
N20900574: length 2.4
  TOP w0.14: U7.5 56.8,134.43 56.45,134.08 R37.1
N20900809: length 1.5
  TOP w0.14: R34.1 58.79,135.62 58.68,135.73 U7.7
N20933818: length 1.3
  TOP w0.14: U54.4 23.62,37.4 24.02,37 R283.2
N20933822: length 1.9
  TOP w0.14: U54.5 24.68,37.81 25.04,37.45 R285.1
N20936712: length 2.2
  TOP w0.132: J12.2 63.22,50.19 63.19,50.22 R159.2
N21016640: length 3.2
  TOP w0.14: TP24.1 65.55,99.28 v1(65.53,99.3)
  BOTTOM w0.14: U78.48 63.65,98.66 63.86,98.87 65.1,98.87 v1(65.53,99.3)
N21068099: length 1.4
  TOP w0.14: U30.1 65.15,73.86 R130.2
N21079949: length 2.5
  TOP w0.14: TP27.1 63.68,90.77 v1(64.14,90.31)
  BOTTOM w0.14: U78.14 63.15,90.92 63.37,90.7 63.75,90.7 v1(64.14,90.31)
N21197992: length 2.7
  TOP w0.14: U2.16 52.01,146.41 52.28,146.14 TP7.1
N21197993: length 1.5
  TOP w0.14: TP4.1 51.51,146.04 U2.15
N21197994: length 1.5
  TOP w0.14: U2.13 50.51,146.04 TP3.1
N21197995: length 2.6
  TOP w0.14: TP6.1 U2.14
N21197996: length 2.7
  TOP w0.14: TP5.1 49.74,146.08 50.01,146.35 U2.12
N21198784: length 1.6
  TOP w0.14: TP2.1 49.1,146.15 49.51,146.55 U2.11
N22124383: length 2.4
  TOP w0.14: R50.2 46.09,119.13 U12.A5
N22155496: length 3.4
  BOTTOM w0.14: U97.7 63.84,38.11 62.93,38.11 62.86,38.03 60.95,38.03 R464.2
N22155498: length 1.7
  BOTTOM w0.14: U97.6 62.96,36.89 62.81,36.73 R466.2
N22156088: length 1.7
  BOTTOM w0.14: U99.7 70.93,31.12 R478.2
N22156090: length 1.7
  BOTTOM w0.14: R476.2 U99.6
N22373538: length 6.8
  TOP w0.14: R139.1 2.78,68.25 2.66,68.37 U31.2 2.66,70.43 2.39,70.7 2.39,71.49 3.66,72.76 U31.7
N22424368: length 1.2
  BOTTOM w0.14: C432.1 37.72,41.14 37.58,41.28 R441.2
N22424482: length 29.5
  TOP w0.14: Q2.4 44.95,43.81 45.79,44.66 45.79,47.73 46.42,48.36 v1(46.83,48.36)
  L10_SIG03 w0.102: v1(29.98,47.22) 32.21,49.44 40.66,49.44 41.32,48.78 41.32,47.33 41.62,47.03 44.99,47.03 46.32,48.36 v1(46.83,48.36)
  BOTTOM w0.14: v1(29.98,47.22) R418.2 30.46,48.45 R417.2
N22441821: length 1
  BOTTOM w0.14: R329.2 70.57,104.63 U63.3
N22441998: length 1.4
  BOTTOM w0.14: R361.2 60.63,84.29 60.99,84.29 61.3,84.6 U81.1
N22442187: length 1
  BOTTOM w0.14: R325.2 66.64,105.1 U65.3
N22498870: length 2
  TOP w0.14: U42.6 64.88,39.77 R182.1 R178.2
N22682365: length 1.9
  TOP w0.14: LD4.2 15.73,51.58 R160.2
N22685157: length 4.3
  TOP w0.14: v1(3.05,64.71) 4.39,64.71 5.76,63.34 LD2.1
  BOTTOM w0.14: Q8.3 v1(3.05,64.71)
N22685161: length 1.9
  TOP w0.14: LD2.2 6.33,61.75 R143.1
N22685196: length 2.1
  BOTTOM w0.14: R384.2 1.95,69.18 2.1,69.03 Q8.1 2.1,67.86
N22685214: length 1.6
  TOP w0.254: R150.1 LD3.2
N22685551: length 1.6
  TOP w0.14: v1(15.23,109.23) 15,108.99 LD1.1
  BOTTOM w0.14: v1(15.23,109.23) 15.31,109.15 Q4.6
N22685595: length 1.1
  BOTTOM w0.14: Q4.3 17.88,107.54 18.17,107.83 R323.2
N22685622: length 1.7
  TOP w0.14: R62.1 LD1.2
N22685670: length 2.4
  TOP w0.132: R163.2 53.97,49.9 54.35,50.29 Q1.3
N22685686: length 2.2
  TOP w0.14: R162.1 LD5.2
N22734804: length 4
  TOP w0.14: v1(8.4,142.23) 8.46,142.29 J2.32
  BOTTOM w0.14: R254.1 6.76,142.36 7.01,142.61 8.02,142.61 v1(8.4,142.23)
N22816067: length 1.7
  TOP w0.14: J2.62 R8.1
N22885689: length 1.7
  TOP w0.14: U27.53 18.74,75.16 v1(18.59,75.01)
  BOTTOM w0.14: R374.2 18.65,75.2 18.59,75.14 v1(18.59,75.01)
N23161423: length 2.4
  TOP w0.14: v1(64.23,25.5) 64.23,25.5 64.37,25.36 U47.75
  BOTTOM w0.14: R493.1 64.27,25.55 v1(64.23,25.5)
N23178593: length 2.3
  BOTTOM w0.14: TP104.1 59.93,27.52 60.04,27.64 U102.6
N23178631: length 1.4
  BOTTOM w0.14: TP105.1 63.19,27.64 U102.3
N23178675: length 1.9
  BOTTOM w0.14: TP96.1 57.67,135.75 U55.14
N23178691: length 2
  BOTTOM w0.14: TP94.1 59.08,136.44 U55.13
N23178707: length 2.5
  BOTTOM w0.14: TP93.1 58.95,137.09 U55.12
N23233575: length 2.2
  TOP w0.254: C507.1 22.22,97.58 v1(21.99,97.58) 21.89,97.58 U21.B1
  BOTTOM w0.381: v1(21.99,97.58) 22.17,97.77 R95.1
N23398363: length 2.4
  TOP w0.14: v1(57.27,121.48) 57.07,121.68 J4.46
  BOTTOM w0.14: TP109.1 55.87,121.48 v1(57.27,121.48)
N23398366: length 1.8
  TOP w0.14: v1(57.27,120.68) 57.07,120.48 J4.40
  BOTTOM w0.14: TP108.1 56.84,120.68 v1(57.27,120.68)
N23413104: length 1.3
  TOP w0.14: R44.1 21.53,124.08 21.73,124.28 U9.1
N23415089: length 1.2
  BOTTOM w0.14: U86.1 R399.2
N23696264: length 2.4
  BOTTOM w0.14: R410.2 R576.2 46.24,52.89 U87.5
N23823404: length 10.1
  TOP w0.14: v1(11.85,104.91) 11.85,104.98 11.99,105.12 R70.2
  L05_SIG02 w0.102: v1(15.14,110.41) 14.91,110.17 14.91,109.49 11.75,106.33 11.75,105.06 11.85,104.96 v1(11.85,104.91)
  BOTTOM w0.14: v1(15.14,110.41) 14.92,110.41 14.64,110.69 R579.1 14.64,111.85 14.76,111.98 U124.4
N193617400: length 1.3
  BOTTOM w0.14: Q12.1 R500.2
N193617480: length 1
  TOP w0.14: LD7.2 R222.1

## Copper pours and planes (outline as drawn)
DGND on L03_SIG01 (solid shape): 10.1,84.94 10.13,84.96 10.16,84.95 10.17,84.95 10.19,84.92 10.19,84.45 10.19,84.43 10.18,84.41 9.11,83.34 9.08,83.33 9.05,83.33 9.04,83.34 9.02,83.36 9.02,83.84 9.02,83.86 9.03,83.87
DGND on L03_SIG01 (solid shape): 10.81,58.4 10.83,58.4 10.85,58.39 11.21,58.02 11.23,58 11.22,57.97 11.22,57.95 11.19,57.93 8.85,57.93 8.83,57.94 8.81,57.95 8.44,58.32 8.43,58.34 8.43,58.37 8.44,58.39 8.46,58.4
DGND on L03_SIG01 (solid shape): 18.38,54.63 18.81,54.2 18.83,54.19 18.85,54.18 21.04,54.18 21.06,54.18 21.08,54.17 21.66,53.58 21.68,53.56 21.67,53.53 21.67,53.51 21.64,53.5 18.97,53.5 18.95,53.5 18.93,53.51 18.32,54.12 18.31,54.14 18.31,54.16 18.31,54.58 18.32,54.61 18.34,54.63 18.35,54.64
DGND on L03_SIG01 (solid shape): 36.21,25.65 36.24,25.67 36.27,25.66 36.28,25.66 36.3,25.63 36.3,22.9 36.29,22.88 36.28,22.86 35.12,21.7 35.1,21.68 35.08,21.68 34.28,21.68 34.27,21.68 34.25,21.67 34.15,21.56 34.12,21.55 34.09,21.55 34.08,21.56 34.06,21.58 34.06,23.25 34.06,23.27 34.07,23.29 36.11,25.32 36.12,25.34 36.12,25.35 36.12,25.54 36.13,25.56 36.14,25.58
DGND on L03_SIG01 (solid shape): 22.4,49.01 22.43,49.02 22.46,49.02 22.47,49.01 22.49,48.99 22.49,48.79 22.49,48.77 22.48,48.76 22.17,48.45 22.16,48.44 22.15,48.42 22.15,41.23 22.13,41.21 22.08,41.19 22.03,41.17 22,41.18 21.92,41.23 21.9,41.25 21.9,41.27 21.9,41.59 21.89,41.61 21.88,41.63 21.69,41.82 21.68,41.84 21.67,41.86 21.67,48.26 21.68,48.28 21.69,48.3
DGND on L03_SIG01 (solid shape): 45.16,91.35 45.19,91.36 45.22,91.36 45.23,91.35 45.25,91.33 45.25,90.86 45.25,90.84 45.26,90.82 45.87,90.21 45.88,90.2 45.89,90.18 45.89,89.83 45.88,89.81 45.87,89.8 45.46,89.39 45.43,89.37 45.41,89.38 45.39,89.38 45.37,89.41 45.37,90.11 45.37,90.13 45.36,90.15 44.46,91.05 44.44,91.08 44.45,91.1 44.45,91.12 44.48,91.14 44.93,91.14 44.95,91.14 44.97,91.15
DGND on L03_SIG01 (solid shape): 14.95,94.92 15.02,94.86 15.03,94.85 15.04,94.82 15.04,93.81 15.04,93.79 15.02,93.77 14.91,93.65 14.89,93.64 14.87,93.64 14.78,93.65 14.76,93.66 14.75,93.67 14.46,93.81 14.19,93.64 14.18,93.63 14.16,93.62 13.65,93.62 13.63,93.62 13.61,93.65 13.6,93.66 13.61,93.69 14.82,94.9 14.88,94.91 14.92,94.92
DGND on L03_SIG01 (solid shape): 26.76,54.21 26.85,54.16 26.87,54.14 26.88,54.11 26.88,51.27 26.87,51.25 26.86,51.23 25.95,50.32 25.94,50.31 25.94,50.29 25.94,48.88 25.93,48.86 25.92,48.84 25.85,48.78 25.75,48.78 25.67,48.76 25.64,48.76 25.57,48.82 25.55,48.84 25.55,48.86 25.55,50.82 25.55,50.84 25.56,50.86 26.28,51.58 26.29,51.59 26.29,51.61 26.29,54.1 26.3,54.12 26.31,54.14 26.4,54.2 26.42,54.2 26.43,54.19 26.58,54.16 26.73,54.2 26.74,54.21
DGND on L03_SIG01 (solid shape): 27.86,11.56 27.88,11.58 27.91,11.57 27.93,11.57 27.94,11.54 27.94,10.83 27.95,10.81 27.96,10.8 28.11,10.65 28.12,10.63 28.12,10.61 28.12,8.64 28.13,8.62 28.14,8.61 29.8,6.94 29.81,6.92 29.89,6.74 30.06,6.64 30.09,6.63 30.1,6.6 30.09,6.56 30.06,6.53 30.05,6.52 30.03,6.52 29.09,6.52 29.07,6.52 29.05,6.53 26.81,8.77 26.8,8.78 26.8,8.8 26.8,10.49 26.8,10.51 26.81,10.52
DGND on L03_SIG01 (solid shape): 15.94,55.22 16.7,54.47 16.71,54.45 16.71,54.43 16.71,51.17 16.68,51.11 16.66,51.1 16.57,51.09 16.55,51.09 16.53,51.1 15.88,51.75 15.87,51.77 15.87,51.79 15.87,53.83 15.87,53.85 15.88,53.87 15.95,53.92 15.97,53.93 15.99,53.93 16.37,54.25 15.99,54.58 15.97,54.58 15.95,54.58 15.88,54.64 15.87,54.66 15.87,54.68 15.87,55.18 15.88,55.2 15.9,55.22 15.91,55.23
DGND on L03_SIG01 (solid shape): 73.56,27.56 73.58,27.56 73.61,27.55 73.63,27.53 73.64,27.51 73.73,27.32 73.92,27.23 73.94,27.22 73.98,27.18 73.99,27.16 73.99,27.14 73.99,26.15 73.99,26.13 73.98,26.11 73.53,25.67 73.51,25.65 73.49,25.65 73.4,25.66 73.38,25.67 73.37,25.68 73.22,25.8 73.03,25.82 73.02,25.81 73,25.82 72.93,25.88 72.91,25.89 72.91,25.91 72.91,27.25 72.91,27.27 72.93,27.29 73,27.34 73.03,27.35 73.04,27.34 73.27,27.36 73.44,27.52 73.45,27.53 73.47,27.55
DGND on L03_SIG01 (solid shape): 23.14,53.2 23.45,52.89 23.46,52.87 23.46,52.85 23.44,52.75 23.42,52.73 23.41,52.72 23.2,52.37 23.5,52.08 23.51,52.08 23.54,52.07 23.58,51.96 23.58,51.94 23.56,51.91 22.97,51.32 22.96,51.3 22.96,51.28 22.96,50.8 22.95,50.78 22.94,50.76 22.86,50.71 22.83,50.71 22.82,50.71 22.74,50.73 22.66,50.73 22.63,50.74 22.57,50.8 22.56,50.81 22.55,50.83 22.55,51.77 22.56,51.79 22.57,51.81 23.05,52.29 23.06,52.3 23.06,52.32 23.06,53.16 23.07,53.18 23.09,53.2 23.11,53.21
DGND on L03_SIG01 (solid shape): 45.45,96.59 45.47,96.59 45.49,96.58 45.54,96.51 45.55,96.48 45.62,96.27 45.8,96.14 45.82,96.13 45.88,96.08 45.89,96.04 45.88,96.01 45.85,95.99 45.7,95.94 45.59,95.83 45.59,95.83 45.18,95.41 45.17,95.4 45.16,95.38 45.16,95.02 45.15,94.99 45.11,94.97 44.94,94.97 44.92,94.98 44.9,94.99 44.34,95.55 44.32,95.56 44.3,95.56 43.91,95.56 43.89,95.57 43.88,95.58 43.82,95.64 43.82,95.71 43.87,95.78 43.89,95.79 43.91,95.79 44.56,95.79 44.58,95.8 44.59,95.81 44.94,96.15 44.95,96.17 44.95,96.19 44.95,96.51 44.96,96.53 44.97,96.55 45,96.58 45.01,96.59 45.03,96.59
DGND on L03_SIG01 (solid shape): 58.28,90.12 58.3,90.12 58.31,90.11 58.8,89.62 58.82,89.61 58.84,89.61 60.39,89.61 60.41,89.6 60.43,89.59 60.64,89.38 60.65,89.36 60.66,89.34 60.66,88.94 60.6,88.83 60.58,88.75 60.58,88.73 60.56,88.71 60.46,88.67 60.44,88.67 60.41,88.68 60.3,88.8 60.28,88.81 60.26,88.81 59.43,88.81 59.41,88.82 59.39,88.83 59.34,88.9 59.33,88.92 59.33,88.93 59.11,89.3 58.71,89.13 58.7,89.12 58.66,89.1 58.63,89.12 58.6,89.15 58.6,89.17 58.6,89.63 58.6,89.65 58.59,89.66 58.21,90.04 58.2,90.06 58.2,90.09 58.21,90.11 58.23,90.12
DGND on L03_SIG01 (solid shape): 1.56,78.57 2.94,77.19 2.95,77.17 2.95,77.15 2.95,72.34 2.95,72.32 2.94,72.3 2.16,71.53 2.15,71.51 2.14,71.46 2.12,71.44 2.03,71.39 2.01,71.39 1.99,71.4 1.9,71.44 1.8,71.44 1.76,71.45 1.7,71.51 1.69,71.52 1.68,71.54 1.68,72.08 1.69,72.1 1.7,72.11 2.39,72.81 2.4,72.82 2.41,72.84 2.41,76.5 2.43,76.53 2.45,76.53 2.66,77.04 2.11,77.03 2.1,77.02 2.08,77.01 1.99,77 1.97,77 1.95,77.02 1.5,77.47 1.49,77.48 1.49,77.5 1.49,78.52 1.49,78.55 1.52,78.57 1.53,78.57
DGND on L03_SIG01 (solid shape): 18.84,102.69 18.87,102.68 18.88,102.66 18.89,102.64 18.88,102.61 18.71,102.44 18.69,102.43 18.67,102.42 18.59,102.42 18.57,102.43 18.03,102.25 18.47,101.88 18.48,101.88 18.5,101.88 18.58,101.82 18.6,101.8 18.6,101.78 18.6,101.41 18.6,101.39 18.59,101.37 17.69,100.47 17.68,100.46 17.67,100.43 17.66,100.41 17.58,100.34 17.55,100.34 17.47,100.36 17.39,100.35 17.37,100.36 17.3,100.42 17.29,100.44 17.28,100.46 17.28,101.46 17.28,101.47 17.27,101.49 16.4,102.36 16.39,102.37 16.37,102.37 14.96,102.37 14.94,102.37 14.93,102.36 14.56,101.99 14.5,101.98 14.45,101.97 14.43,101.98 14.42,101.99 14.41,102.03 14.42,102.06 15.03,102.68 15.05,102.69 15.07,102.69
DGND on L03_SIG01 (solid shape): 33.85,89 33.88,88.98 34.43,88.43 34.45,88.4 34.45,88.37 34.44,88.36 34.41,88.34 34.28,88.34 34.26,88.33 34.24,88.32 33.94,88.03 33.93,88.01 33.92,87.96 33.9,87.94 33.87,87.93 33.85,87.92 33.82,87.93 33.59,87.99 33.38,87.88 33.37,87.87 33.35,87.87 33.26,87.87 33.24,87.87 33.23,87.88 33.13,87.96 33.01,87.99 32.98,88.01 32.97,88.04 32.98,88.08 33.04,88.13 33.06,88.14 33.15,88.18 33.23,88.25 33.25,88.26 33.27,88.26 33.34,88.26 33.36,88.26 33.38,88.25 33.91,88.29 33.71,88.79 33.69,88.8 33.63,88.85 33.62,88.89 33.63,88.92 33.74,88.95 33.81,88.99
DGND on L03_SIG01 (solid shape): 31.85,96.59 31.87,96.59 31.89,96.58 31.94,96.51 31.95,96.48 32.25,96.14 32.61,96.43 32.62,96.46 32.66,96.48 32.7,96.46 32.75,96.41 32.77,96.36 32.76,96.33 32.42,95.98 32.39,95.98 32.38,95.98 32.04,95.89 31.97,95.55 31.97,95.54 31.97,95.51 31.64,95.18 31.61,95.17 31.59,95.18 31.5,95.2 31.37,95.2 31.35,95.24 31.35,95.29 31.37,95.33 31.41,95.34 31.81,95.64 31.46,96 31.43,96 31.37,96.06 31.36,96.08 31.35,96.1 31.35,96.51 31.36,96.53 31.37,96.55 31.39,96.58 31.41,96.59 31.43,96.59
DGND on L03_SIG01 (solid shape): outline of 103 points within 43.17,21.77 48.43,23.25
DGND on L03_SIG01 (solid shape): 25.27,29.34 26.01,28.61 26.02,28.59 26.02,28.57 26.02,21.76 26.02,21.74 26,21.72 25.93,21.67 25.91,21.66 25.9,21.67 25.49,21.32 25.95,21.04 25.97,21.04 26.01,21.03 26.02,20.99 26.02,20.95 26.01,20.93 25.79,20.72 25.78,20.7 25.78,20.68 25.78,18.85 25.78,18.83 25.79,18.82 26.3,18.3 26.32,18.28 26.32,18.26 26.31,18.17 26.3,18.15 26.29,18.15 26.16,17.75 26.53,17.54 26.54,17.55 26.56,17.54 26.63,17.48 26.64,17.47 26.64,17.41 26.62,17.39 26.51,17.35 26.48,17.36 26.47,17.37 26.26,17.46 26.04,17.4 26.01,17.39 25.83,17.39 25.81,17.39 25.8,17.4 25.78,17.42 25.77,17.44 25.76,17.46 25.78,17.56 25.79,17.58 25.8,17.58 25.96,17.93 25.69,18.2 25.66,18.21 25.39,18.48 25.38,18.49 25.38,18.51 25.38,25.18 25.37,25.2 25.36,25.22 25.21,25.37 25.2,25.39 25.2,25.41 25.2,29.29 25.21,29.32 25.23,29.34 25.24,29.34
DGND on L03_SIG01 (solid shape): outline of 122 points within 57.49,22.81 62.43,32.38
DGND on L03_SIG01 (solid shape): 18.27,91.29 18.35,91.24 18.37,91.22 18.38,91.2 18.38,87.58 18.37,87.56 18.36,87.54 18.01,87.19 18,87.18 17.98,87.18 15.09,87.18 15.07,87.18 15.05,87.2 14.99,87.27 14.99,87.29 14.99,87.3 14.99,87.44 14.92,87.57 14.92,87.66 14.88,88.12 14.42,88.09 14.41,88.08 14.39,88.08 14.31,88.08 14.29,88.08 14.27,88.09 13.81,88.12 13.77,87.66 13.77,87.57 13.81,87.11 14.27,87.13 14.29,87.15 14.31,87.15 14.39,87.15 14.41,87.15 14.42,87.13 14.46,87.1 14.51,87.07 14.52,87.05 14.54,86.95 14.53,86.93 14.52,86.91 13.23,85.62 13.21,85.61 13.18,85.61 13.16,85.62 13.15,85.64 13.15,88.26 13.15,88.28 13.16,88.3 14.63,89.77 14.65,89.78 14.67,89.79 15.3,89.79 15.32,89.79 15.33,89.8 16.45,90.92 16.47,90.93 16.49,90.94 17.58,90.94 17.6,90.94 17.62,90.95 17.95,91.28 17.98,91.29 17.99,91.28 18.11,91.26 18.23,91.29 18.25,91.3
DGND on L03_SIG01 (solid shape): outline of 132 points within 59.16,22.85 64.8,29.72
DGND on L03_SIG01 (solid shape): outline of 198 points within 34.31,104.27 36.99,106.21
DGND on L03_SIG01 (solid shape): outline of 290 points within 66.55,17.83 72.39,25.26
DGND on L05_SIG02 (solid shape): 1.62,91.77 1.65,91.78 1.68,91.78 1.69,91.77 1.71,91.75 1.71,90.82 1.71,90.8 1.7,90.79 1.12,90.21 1.09,90.19 1.06,90.19 1.05,90.2 1.03,90.23 1.03,91.15 1.03,91.17 1.04,91.19
DGND on L05_SIG02 (solid shape): 9.75,78.23 9.77,78.25 9.8,78.24 9.82,78.24 9.83,78.21 9.83,77.89 9.83,77.87 9.82,77.85 8.07,76.1 8.04,76.09 8.01,76.09 8,76.1 7.98,76.12 7.98,76.45 7.98,76.46 7.99,76.48
DGND on L05_SIG02 (solid shape): 9.94,84.88 9.97,84.89 10,84.89 10.01,84.88 10.03,84.86 10.03,82.1 10.03,82.08 10.02,82.07 9.65,81.69 9.62,81.68 9.59,81.68 9.58,81.69 9.56,81.72 9.56,84.47 9.56,84.49 9.57,84.5
DGND on L05_SIG02 (solid shape): 12.69,110.01 12.72,110.02 12.75,110.02 12.76,110.01 12.78,109.99 12.78,109.31 12.77,109.29 12.76,109.27 11.89,108.4 11.86,108.39 11.84,108.39 11.82,108.4 11.8,108.42 11.8,109.1 11.81,109.12 11.82,109.13
DGND on L05_SIG02 (solid shape): 13.1,53.23 13.4,52.93 13.41,52.92 13.41,52.9 13.41,40.11 13.4,40.08 13.38,40.06 13.37,40.05 13.34,40.06 13.04,40.36 13.03,40.37 13.02,40.39 13.02,53.18 13.03,53.21 13.06,53.23 13.07,53.24
DGND on L05_SIG02 (solid shape): 20.22,53.99 20.24,53.98 20.26,53.97 20.52,53.71 20.54,53.68 20.53,53.65 20.53,53.64 20.5,53.62 17.96,53.62 17.94,53.63 17.92,53.64 17.66,53.9 17.64,53.93 17.65,53.96 17.65,53.97 17.68,53.99
DGND on L05_SIG02 (solid shape): 20.44,52.86 20.46,52.86 20.47,52.84 20.74,52.58 20.76,52.55 20.75,52.52 20.75,52.51 20.72,52.49 18.29,52.49 18.27,52.49 18.25,52.51 17.99,52.77 17.97,52.8 17.98,52.83 17.98,52.84 18.01,52.86
DGND on L05_SIG02 (solid shape): 22.94,55.66 22.96,55.66 22.98,55.65 23.65,54.98 23.66,54.96 23.66,54.94 23.66,54.4 23.65,54.37 23.63,54.35 23.62,54.35 23.59,54.35 22.36,55.58 22.35,55.6 22.35,55.63 22.36,55.65 22.38,55.66
DGND on L05_SIG02 (solid shape): 26.42,100.07 26.45,100.06 26.47,100.04 26.47,100.02 26.47,99.99 24.85,98.38 24.82,98.36 24.8,98.37 24.78,98.37 24.76,98.4 24.76,98.84 24.77,98.86 24.78,98.88 25.95,100.05 25.97,100.06 25.99,100.07
DGND on L05_SIG02 (solid shape): 27.25,52.94 27.26,52.93 27.28,52.92 28.07,52.14 28.08,52.11 28.08,52.08 28.07,52.07 28.05,52.05 25.46,52.05 25.44,52.05 25.43,52.06 24.64,52.85 24.63,52.88 24.63,52.91 24.63,52.92 24.66,52.94
DGND on L05_SIG02 (solid shape): 61,97.94 61.03,97.95 61.06,97.95 61.07,97.95 61.09,97.92 61.09,92.39 61.09,92.37 61.07,92.36 60.67,91.95 60.64,91.94 60.61,91.94 60.6,91.95 60.58,91.97 60.58,97.5 60.59,97.52 60.6,97.54
DGND on L05_SIG02 (solid shape): 69.21,136.61 69.53,136.29 69.54,136.27 69.55,136.25 69.55,132.64 69.54,132.61 69.52,132.59 69.5,132.58 69.47,132.59 69.15,132.91 69.14,132.93 69.14,132.95 69.14,136.56 69.14,136.59 69.17,136.61 69.18,136.61
DGND on L05_SIG02 (solid shape): 64.54,124.1 64.93,123.71 64.94,123.7 64.95,123.68 64.95,117 64.95,115.8 64.94,115.77 64.91,115.75 64.9,115.75 64.87,115.75 64.48,116.14 64.47,116.16 64.47,116.17 64.47,124.05 64.48,124.08 64.5,124.1 64.51,124.11
DGND on L05_SIG02 (solid shape): 28.24,40.61 28.88,39.97 28.9,39.95 28.9,39.93 28.9,38.8 28.88,38.76 28.85,38.75 28.76,38.77 28.18,39.35 28.17,39.37 28.16,39.39 28.16,40.57 28.17,40.6 28.2,40.61 28.21,40.62
DGND on L05_SIG02 (solid shape): 49.66,44.14 49.68,44.14 49.7,44.13 50.94,42.88 50.95,42.87 50.95,42.85 50.95,42.33 50.95,42.3 50.92,42.28 50.91,42.27 50.88,42.28 49.23,43.93 49.21,43.95 49.21,43.98 49.23,44.07 49.24,44.09 49.29,44.11 49.34,44.14
DGND on L05_SIG02 (solid shape): 63.22,99.88 63.3,99.89 63.32,99.88 63.38,99.82 63.4,99.81 63.4,99.78 63.4,91.91 63.39,91.88 63.37,91.86 63.35,91.86 63.32,91.86 63.04,92.15 63.02,92.17 63.02,92.19 63.02,99.8 63.03,99.82 63.04,99.84 63.12,99.89 63.14,99.9
DGND on L05_SIG02 (solid shape): 29.15,121.23 29.17,121.23 29.19,121.22 29.55,120.86 29.56,120.83 29.56,120.8 29.55,120.79 29.53,120.77 26.7,120.77 26.68,120.78 26.66,120.8 26.61,120.87 26.6,120.9 26.61,120.91 26.63,121.01 26.62,121.1 26.61,121.12 26.62,121.14 26.67,121.21 26.69,121.23 26.71,121.23
DGND on L05_SIG02 (solid shape): 7.38,67.87 7.41,67.88 7.44,67.88 7.45,67.87 7.47,67.85 7.47,67.65 7.47,67.63 7.45,67.62 7.21,67.37 7.2,67.36 7.2,67.34 7.2,61.29 7.19,61.26 7.17,61.24 7.15,61.23 7.12,61.24 6.96,61.4 6.95,61.42 6.94,61.44 6.94,67.41 6.95,67.43 6.96,67.44
DGND on L05_SIG02 (solid shape): 9.04,89.76 9.07,89.77 9.1,89.77 9.11,89.77 9.13,89.74 9.13,88.75 9.13,88.73 9.12,88.71 8.61,88.2 8.6,88.18 8.59,88.16 8.59,87.78 8.58,87.75 8.56,87.73 8.55,87.73 8.52,87.73 8.25,88 8.24,88.02 8.23,88.04 8.23,88.93 8.24,88.95 8.25,88.96
DGND on L05_SIG02 (solid shape): 11.61,55.49 11.63,55.48 11.65,55.47 12.51,54.61 12.52,54.58 12.52,54.55 12.51,54.54 12.49,54.52 11.15,54.52 11.13,54.53 11.12,54.54 10.51,55.14 10.49,55.15 10.48,55.16 8.5,55.16 8.48,55.16 8.46,55.17 8.23,55.4 8.22,55.43 8.22,55.46 8.23,55.47 8.25,55.49
DGND on L05_SIG02 (solid shape): 15.72,61.3 16.1,60.91 16.12,60.9 16.14,60.9 16.51,60.9 16.53,60.89 16.55,60.88 18.31,59.12 18.33,59.09 18.32,59.06 18.32,59.05 18.29,59.03 17.82,59.03 17.8,59.03 17.78,59.05 15.66,61.16 15.65,61.18 15.65,61.2 15.65,61.25 15.65,61.28 15.68,61.3 15.69,61.3
DGND on L05_SIG02 (solid shape): 15.75,53.55 15.88,53.42 15.9,53.41 15.92,53.4 16.62,53.4 16.63,53.4 16.65,53.39 17.16,52.88 17.17,52.86 17.17,52.83 17.16,52.81 17.14,52.8 16.16,52.8 16.14,52.8 16.12,52.81 15.69,53.24 15.68,53.26 15.67,53.28 15.67,53.51 15.68,53.53 15.71,53.55 15.72,53.56
DGND on L05_SIG02 (solid shape): 18.15,37.15 18.17,37.16 18.2,37.16 18.22,37.15 18.23,37.13 18.23,36.48 18.23,36.46 18.22,36.44 17.89,36.11 17.87,36.1 17.85,36.1 16.37,36.1 16.34,36.1 16.32,36.13 16.32,36.14 16.32,36.17 16.92,36.77 16.94,36.78 16.96,36.79 17.77,36.79 17.79,36.79 17.8,36.8
DGND on L05_SIG02 (solid shape): 20.36,104.98 20.38,104.95 20.38,104.94 20.38,104.91 19.59,104.12 19.58,104.11 19.58,104.09 19.58,103.84 19.57,103.83 19.56,103.81 19.03,103.28 19.02,103.27 19,103.27 18.71,103.27 18.68,103.27 18.66,103.3 18.66,103.31 18.66,103.34 20.29,104.97 20.31,104.98
DGND on L05_SIG02 (solid shape): 54.61,34.05 54.63,34.05 54.65,34.03 56.45,32.23 56.46,32.21 56.46,32.18 56.45,32.16 56.43,32.15 56.38,32.15 56.36,32.15 56.35,32.16 55.64,32.87 55.63,32.88 55.61,32.88 55.3,32.88 55.28,32.88 55.26,32.9 54.19,33.96 54.18,33.99 54.18,34.02 54.19,34.03 54.21,34.05
DGND on L05_SIG02 (solid shape): 61.47,114.72 61.89,114.3 61.9,114.29 61.9,114.27 61.9,103.82 61.89,103.8 61.87,103.78 61.86,103.77 61.83,103.78 61.59,104.02 61.58,104.03 61.57,104.05 61.57,107.46 61.57,107.48 61.56,107.5 61.41,107.65 61.4,107.66 61.39,107.68 61.39,114.67 61.4,114.7 61.43,114.72 61.44,114.72
DGND on L05_SIG02 (solid shape): 63.4,107.18 64.3,106.28 64.32,106.26 64.32,106.24 64.32,105.22 64.31,105.2 64.3,105.19 64.14,105.02 64.11,105.01 64.08,105.01 64.07,105.02 64.05,105.04 64.05,105.44 64.05,105.46 64.04,105.48 63.34,106.17 63.33,106.19 63.33,106.21 63.33,107.13 63.33,107.16 63.36,107.18 63.37,107.19
DGND on L05_SIG02 (solid shape): 13.14,124.4 13.17,124.39 13.17,124.3 12.27,123.4 12.26,123.39 12.24,123.38 12.01,123.38 11.99,123.38 11.97,123.37 11.21,122.61 11.19,122.6 11.16,122.6 11.15,122.6 11.13,122.63 11.13,123.39 11.13,123.41 11.14,123.42 12.11,124.39 12.12,124.4 12.14,124.4
DGND on L05_SIG02 (solid shape): 25.23,97.34 25.31,97.33 25.37,97.27 25.39,97.25 25.39,97.23 25.39,96.27 25.39,96.25 25.37,96.23 24.45,95.3 24.42,95.29 24.39,95.29 24.38,95.3 24.36,95.32 24.36,96.46 24.37,96.48 24.38,96.5 25.04,97.16 25.05,97.17 25.05,97.19 25.05,97.25 25.06,97.27 25.07,97.29 25.14,97.34 25.17,97.35
DGND on L05_SIG02 (solid shape): 63.18,87.45 63.54,87.1 63.55,87.08 63.55,87.06 63.55,83.88 63.55,83.86 63.53,83.84 63.47,83.78 63.44,83.78 63.38,83.78 63.31,83.78 63.29,83.78 63.22,83.84 63.2,83.86 63.2,83.88 63.2,84.62 63.19,84.64 63.18,84.66 63.12,84.72 63.11,84.73 63.11,84.75 63.11,87.4 63.12,87.43 63.14,87.45 63.16,87.46
DGND on L05_SIG02 (solid shape): 66.06,128.11 66.14,128.1 66.2,128.04 66.22,128.03 66.22,128.01 66.22,118.53 66.23,118.51 66.24,118.5 67.28,117.45 67.29,117.43 67.3,117.41 67.3,108.95 67.29,108.92 67.27,108.9 67.25,108.9 67.22,108.9 65.89,110.24 65.88,110.25 65.88,110.27 65.88,128.02 65.88,128.04 65.89,128.06 65.97,128.12 65.99,128.12
DGND on L05_SIG02 (solid shape): 9.24,67.02 9.4,66.86 9.41,66.84 9.42,66.82 9.42,62.15 9.42,62.14 9.43,62.12 9.68,61.88 9.69,61.86 9.69,61.84 9.68,61.75 9.67,61.73 9.66,61.72 9.6,61.67 9.56,61.6 9.55,61.59 9.53,61.58 9.44,61.56 9.42,61.57 9.4,61.58 9.18,61.8 9.17,61.81 9.16,61.83 9.16,66.98 9.17,67 9.2,67.02 9.21,67.03
DGND on L05_SIG02 (solid shape): 60.1,21.48 60.12,21.47 60.14,21.46 60.19,21.39 60.2,21.36 60.19,21.28 60.2,21.19 60.19,21.17 60.13,21.1 60.12,21.08 60.07,21.07 60.05,21.06 59.99,21 59.97,20.99 59.95,20.99 56.83,20.99 56.81,20.99 56.8,21 56.41,21.39 56.39,21.42 56.4,21.45 56.4,21.46 56.43,21.48
DGND on L05_SIG02 (solid shape): 67.06,129.39 67.13,129.33 67.15,129.31 67.15,129.29 67.15,127.7 67.16,127.68 67.17,127.66 67.52,127.31 67.53,127.29 67.54,127.27 67.54,118.04 67.53,118.01 67.5,117.99 67.49,117.99 67.46,117.99 66.74,118.71 66.73,118.72 66.73,118.74 66.73,129.27 66.73,129.29 66.75,129.31 66.82,129.37 66.84,129.37 66.85,129.37 66.94,129.37 67.02,129.39 67.03,129.39
DGND on L05_SIG02 (solid shape): 26.21,48.37 26.23,48.37 26.26,48.36 28.35,46.26 28.36,46.25 28.37,46.23 28.37,41.79 28.36,41.76 28.34,41.74 28.32,41.73 28.29,41.74 27.94,42.1 27.93,42.11 27.92,42.13 27.92,45.97 27.92,45.99 27.91,46 25.91,48 25.9,48.02 25.9,48.04 25.91,48.13 25.93,48.15 25.94,48.16 26.03,48.23 26.09,48.33 26.09,48.34 26.11,48.35
DGND on L05_SIG02 (solid shape): 50.57,39.19 50.98,38.78 50.99,38.76 51,38.74 51,37.61 51,37.59 51.01,37.57 51.16,37.42 51.17,37.4 51.18,37.38 51.17,37.29 51.16,37.27 51.15,37.26 51.08,37.2 51.03,37.12 51.03,37.11 51.01,37.09 50.91,37.08 50.89,37.08 50.87,37.09 50.51,37.45 50.5,37.46 50.49,37.48 50.49,39.14 50.5,39.17 50.53,39.19 50.54,39.19
DGND on L05_SIG02 (solid shape): 10.25,53.47 10.27,53.46 10.29,53.45 11.55,52.19 11.56,52.18 11.56,52.16 11.56,40.01 11.55,39.99 11.53,39.97 11.52,39.96 11.49,39.97 11.12,40.34 11.11,40.35 11.1,40.37 11.1,50.21 11.1,50.23 11.09,50.25 10,51.34 9.99,51.35 9.99,51.37 9.99,53.06 9.98,53.08 9.97,53.09 9.68,53.38 9.67,53.41 9.67,53.44 9.68,53.45 9.7,53.47
DGND on L05_SIG02 (solid shape): 42.3,37.53 42.32,37.52 42.33,37.51 43.78,36.07 43.79,36.05 43.79,36.03 43.79,35.71 43.8,35.69 43.81,35.67 46.38,33.1 46.39,33.07 46.39,33.04 46.39,33.03 46.36,33.01 46.08,33.01 46.06,33.01 46.04,33.02 42.29,36.78 42.27,36.79 42.25,36.79 41.58,36.79 41.56,36.8 41.55,36.81 40.91,37.44 40.9,37.47 40.9,37.5 40.91,37.51 40.93,37.53
DGND on L05_SIG02 (solid shape): 61.78,146.51 61.8,146.5 61.81,146.49 66.35,141.95 66.36,141.94 66.38,141.94 66.85,141.94 66.87,141.94 66.88,141.93 67.29,141.52 67.3,141.5 67.3,141.48 67.3,140.92 67.31,140.9 67.32,140.88 67.35,140.85 67.36,140.83 67.36,140.8 67.35,140.78 67.33,140.76 66.69,140.76 66.67,140.77 66.65,140.78 61.02,146.42 61,146.44 61,146.47 61.01,146.49 61.04,146.51
DGND on L05_SIG02 (solid shape): 66.76,78.04 67.07,77.74 67.08,77.72 67.08,77.7 67.08,69.1 67.08,69.08 67.07,69.07 66.36,68.36 66.35,68.34 66.35,68.32 66.35,67.27 66.34,67.24 66.32,67.23 66.3,67.22 66.27,67.23 65.71,67.79 65.7,67.81 65.69,67.83 65.69,72.74 65.7,72.76 65.71,72.78 66.67,73.74 66.68,73.76 66.69,73.78 66.69,78 66.7,78.02 66.72,78.04 66.73,78.05
DGND on L05_SIG02 (solid shape): 66.78,46.43 66.81,46.45 66.84,46.44 66.85,46.44 66.87,46.41 66.87,46.33 66.87,46.31 66.86,46.3 63,42.44 62.98,42.43 62.96,42.42 62.76,42.42 62.74,42.43 62.72,42.44 62.39,42.76 62.38,42.78 62.36,42.78 61.46,42.78 61.43,42.79 61.41,42.81 61.41,42.82 61.41,42.85 61.61,43.05 61.63,43.06 61.65,43.07 63.4,43.07 63.41,43.07 63.43,43.08
DGND on L05_SIG02 (solid shape): 59.43,71.61 59.52,71.56 59.53,71.54 59.54,71.51 59.54,68.41 59.54,68.39 59.52,68.37 57.65,66.49 57.62,66.48 57.59,66.48 57.58,66.49 57.56,66.51 57.56,67.65 57.56,67.67 57.57,67.69 58.97,69.08 58.98,69.1 58.98,69.12 58.98,71.49 58.99,71.51 59,71.53 59.08,71.59 59.11,71.59 59.12,71.59 59.26,71.56 59.39,71.6 59.4,71.61
DGND on L05_SIG02 (solid shape): 27.27,70.05 27.85,69.47 27.86,69.45 27.87,69.43 27.87,66.1 27.86,66.08 27.83,66.06 27.82,66.05 27.79,66.06 27.71,66.13 27.71,66.16 27.71,66.18 27.7,66.47 27.46,66.63 27.43,66.64 27.21,66.87 27.2,66.88 27.19,66.9 27.19,70 27.2,70.03 27.22,70.05 27.24,70.06
DGND on L05_SIG02 (solid shape): 42.81,97.39 42.81,95.27 42.81,95.25 42.82,95.23 43.51,94.54 43.53,94.49 43.51,94.45 43.48,94.44 43.18,94.44 43.16,94.43 43.15,94.42 43.04,94.32 43.01,94.3 42.98,94.3 42.97,94.31 42.95,94.34 42.95,94.44 42.95,94.46 42.94,94.48 42.57,94.85 42.56,94.86 42.55,94.88 42.55,97.34 42.57,97.38 42.6,97.39 42.8,97.39
DGND on L05_SIG02 (solid shape): 23.08,104.4 23.11,104.39 23.12,104.37 23.13,104.35 23.12,104.32 21.73,102.93 21.71,102.92 21.69,102.91 21.21,102.91 21.19,102.91 21.16,102.88 21.12,102.87 21.09,102.88 21.07,102.92 21.05,103.02 21.01,103.1 21,103.11 21,103.14 21.05,103.24 21.07,103.26 21.09,103.26 21.62,103.26 21.64,103.27 21.66,103.28 22.76,104.38 22.78,104.39 22.8,104.4
DGND on L05_SIG02 (solid shape): 46.75,120.9 46.78,120.89 46.8,120.87 46.8,120.85 46.8,120.83 46.6,120.62 46.59,120.61 46.58,120.59 46.58,120.34 46.58,120.32 46.57,120.3 46.45,120.18 46.43,120.17 46.41,120.16 44.79,120.16 44.76,120.17 44.75,120.19 44.74,120.21 44.75,120.24 44.79,120.28 44.8,120.3 44.81,120.32 44.81,120.42 44.82,120.46 44.86,120.47 46.1,120.47 46.12,120.48 46.13,120.49 46.53,120.89 46.55,120.9 46.57,120.9
DGND on L05_SIG02 (solid shape): 17.9,102.05 17.92,102.07 17.94,102.07 18.03,102.06 18.05,102.04 18.06,102.03 18.23,101.88 18.45,101.87 18.47,101.88 18.49,101.87 18.57,101.82 18.58,101.8 18.59,101.77 18.59,101.65 18.58,101.63 18.57,101.61 18.08,101.12 18.07,101.11 18.05,101.11 17.4,101.11 17.38,101.1 17.36,101.09 17.09,100.83 17.07,100.81 17.04,100.82 17.02,100.82 17.01,100.85 17.01,101.14 17.01,101.16 17.02,101.18
DGND on L05_SIG02 (solid shape): 44.76,33.21 45.07,32.89 45.08,32.88 45.09,32.86 45.09,31.23 45.08,31.21 45.07,31.19 44.82,30.94 44.8,30.93 44.78,30.93 43.33,30.93 43.31,30.92 43.29,30.91 41.64,29.26 41.63,29.25 41.58,29.25 41.55,29.26 41.53,29.28 41.53,29.29 41.53,29.32 43.63,31.42 43.65,31.43 43.66,31.43 44.21,31.43 44.23,31.44 44.24,31.45 44.67,31.87 44.68,31.89 44.68,31.91 44.68,33.16 44.69,33.19 44.71,33.21 44.73,33.21
DGND on L05_SIG02 (solid shape): 57,125.64 57.02,125.64 57.04,125.63 57.57,125.09 57.58,125.08 57.58,125.06 57.58,122.65 57.58,122.63 57.56,122.61 57.47,122.56 57.44,122.56 57.43,122.56 57.21,122.6 57.02,122.49 56.99,122.47 56.9,122.47 56.88,122.47 56.87,122.48 55.49,123.86 55.48,123.87 55.48,123.89 55.48,125.29 55.47,125.31 55.46,125.33 55.24,125.55 55.22,125.58 55.23,125.61 55.23,125.62 55.26,125.64
DGND on L05_SIG02 (solid shape): 29.08,105.84 29.11,105.83 29.13,105.81 29.13,105.8 29.13,105.77 28.51,105.15 28.5,105.14 28.48,105.14 28.27,105.14 28.25,105.14 28.23,105.15 28.18,105.22 28.17,105.25 28,105.57 27.64,105.54 27.61,105.53 22.68,105.53 22.66,105.54 22.64,105.56 22.63,105.58 22.64,105.61 22.86,105.83 22.87,105.84 22.89,105.84
DGND on L05_SIG02 (solid shape): 24.34,136.7 24.36,136.69 24.38,136.66 24.39,136.65 24.38,136.62 20.26,132.5 20.25,132.48 20.25,132.46 20.25,131.62 20.24,131.59 20.22,131.57 20.12,131.53 20.09,131.53 20.08,131.54 19.68,131.76 19.24,131.79 19.22,131.79 19.19,131.8 19.14,131.9 19.14,131.93 19.15,131.96 20.28,133.09 20.29,133.11 20.3,133.13 20.3,133.71 20.3,133.73 20.31,133.74 23.25,136.68 23.27,136.69 23.28,136.7
DGND on L05_SIG02 (solid shape): 25.16,50.7 25.19,50.7 25.21,50.69 25.97,49.92 25.99,49.91 26.01,49.9 27.21,49.9 27.23,49.9 27.25,49.89 27.96,49.18 27.97,49.16 27.97,49.14 27.97,47.7 27.98,47.68 27.99,47.66 29.8,45.85 29.81,45.83 29.82,45.81 29.82,41 29.81,40.97 29.78,40.95 29.77,40.95 29.74,40.95 28.89,41.8 28.88,41.82 28.88,41.84 28.88,46.44 28.87,46.46 28.86,46.47 24.94,50.4 24.93,50.41 24.92,50.44 24.93,50.52 24.94,50.54 24.95,50.55 25,50.6 25.04,50.66 25.05,50.67 25.07,50.69
DGND on L05_SIG02 (solid shape): 67.74,127.99 68.5,127.23 68.51,127.22 68.51,127.2 68.51,104.75 68.51,104.73 68.5,104.71 68.44,104.65 68.41,104.64 68.32,104.64 68.23,104.61 68.22,104.6 68.19,104.6 67.99,104.8 67.98,104.82 67.97,104.84 67.97,105.4 67.98,105.42 67.99,105.43 68.34,105.79 68.35,105.8 68.35,105.82 68.35,109.75 68.35,109.77 68.34,109.79 68.06,110.07 68.05,110.08 68.04,110.1 68.04,127.48 68.04,127.5 68.03,127.52 67.68,127.87 67.67,127.89 67.66,127.91 67.66,127.95 67.67,127.97 67.69,127.99 67.71,128
DGND on L05_SIG02 (solid shape): 64.03,18.56 64.06,18.55 64.08,18.54 64.29,18.33 64.31,18.3 64.3,18.27 64.3,18.26 64.27,18.24 63.37,18.24 63.35,18.23 63.33,18.22 62.56,17.46 62.55,17.44 62.55,17.42 62.55,16.9 62.55,16.88 62.53,16.87 62.18,16.51 62.16,16.5 62.14,16.5 61.56,16.5 61.53,16.51 61.51,16.53 61.51,16.54 61.51,16.57 63.37,18.44 63.39,18.45 63.44,18.44 63.7,18.38 63.92,18.53 63.93,18.54 63.94,18.55
DGND on L05_SIG02 (solid shape): 18.39,56.95 18.41,56.94 18.43,56.93 19.39,55.97 19.41,55.94 19.4,55.91 19.4,55.9 19.37,55.88 18.64,55.88 18.62,55.88 18.6,55.87 18.25,55.52 18.23,55.5 18.21,55.5 17.45,55.5 17.43,55.5 17.42,55.52 16.52,56.41 16.51,56.44 16.51,56.47 16.52,56.48 16.54,56.5 17.71,56.5 17.74,56.49 18.11,56.47 18.26,56.82 18.25,56.84 18.26,56.86 18.32,56.93 18.33,56.94 18.36,56.95
DGND on L05_SIG02 (solid shape): 36.39,152.4 36.41,152.4 36.42,152.39 36.69,152.12 36.7,152.1 36.7,152.07 36.69,152.05 36.67,152.04 29.3,152.04 29.28,152.03 29.27,152.02 27.32,150.08 27.31,150.07 27.29,150.06 11.98,150.06 11.96,150.06 11.94,150.05 10.27,148.38 10.26,148.36 10.26,148.34 10.26,147.09 10.25,147.06 10.22,147.04 10.21,147.03 10.18,147.04 8.68,148.54 8.66,148.56 8.64,148.56 5.82,148.56 5.79,148.57 5.77,148.59 5.77,148.61 5.77,148.64 8.02,150.88 8.04,150.89 8.06,150.9 26.76,150.9 26.78,150.9 26.8,150.91 28.27,152.39 28.29,152.4 28.31,152.4
DGND on L05_SIG02 (solid shape): 65.09,109.82 66.26,108.66 66.27,108.64 66.27,108.62 66.27,107.74 66.27,107.72 66.25,107.7 66.19,107.64 66.16,107.64 65.8,107.43 65.93,107.04 65.94,107.02 65.95,106.99 65.95,106.91 65.94,106.89 65.93,106.87 65.88,106.83 65.83,106.77 65.81,106.75 65.72,106.74 65.7,106.75 65.68,106.76 65.03,107.4 65.02,107.42 65.02,107.44 65.02,109.78 65.03,109.8 65.05,109.82 65.06,109.83
DGND on L05_SIG02 (solid shape): 16.55,108.84 16.58,108.85 16.61,108.85 16.62,108.85 16.64,108.82 16.63,108.78 16.62,108.77 15.31,107.45 15.3,107.44 15.29,107.42 15.29,106.09 15.29,106.07 15.28,106.05 14.41,105.19 14.39,105.18 14.36,105.18 14.27,105.2 14.25,105.22 14.23,105.28 14.2,105.34 14.2,105.37 14.37,105.55 14.38,105.56 14.39,105.58 14.39,106.07 14.33,106.11 14.3,106.1 13.82,105.62 13.8,105.61 13.77,105.61 13.75,105.62 13.73,105.64 13.73,106 13.74,106.02 13.75,106.04
DGND on L05_SIG02 (solid shape): 17.64,63.96 17.66,63.94 17.67,63.92 17.67,60.93 17.67,60.91 17.68,60.89 19.15,59.42 19.17,59.4 19.16,59.37 19.16,59.35 19.13,59.34 18.84,59.34 18.82,59.34 18.8,59.35 16.76,61.39 16.74,61.4 16.72,61.41 16.35,61.41 16.33,61.41 16.31,61.42 16.05,61.69 16.04,61.7 16.03,61.72 16.03,63.91 16.04,63.94 16.06,63.96 16.16,64 16.19,64 16.2,63.99 16.85,63.75 17.5,63.99 17.51,64 17.54,64.01
DGND on L05_SIG02 (solid shape): 16.45,91.3 16.53,91.24 16.55,91.22 16.55,91.2 16.55,91.15 16.56,91.13 16.57,91.12 16.64,91.04 16.65,91.03 16.66,91.01 16.66,88.78 16.65,88.76 16.64,88.74 16.34,88.44 16.33,88.42 16.33,88.4 16.33,85.45 16.32,85.43 16.31,85.41 15.89,85 15.88,84.98 15.88,84.96 15.88,84.34 15.87,84.31 15.85,84.29 15.83,84.29 15.8,84.29 15.63,84.47 15.61,84.49 15.61,84.51 15.61,87.96 15.61,87.98 15.63,87.99 16.13,88.5 16.14,88.51 16.14,88.53 16.14,91.16 16.15,91.18 16.16,91.2 16.22,91.26 16.33,91.27 16.41,91.29 16.42,91.3
DGND on L05_SIG02 (solid shape): 28.45,66.39 29.27,65.57 29.29,65.56 29.31,65.56 30.32,65.56 30.34,65.55 30.36,65.54 30.64,65.26 30.66,65.24 30.68,65.24 31.05,65.24 31.07,65.23 31.09,65.22 31.15,65.14 31.15,65.12 31.15,65.1 31.1,64.55 31.36,64.07 31.37,64.06 31.37,64.03 31.33,63.93 31.31,63.9 31.28,63.9 29.19,63.9 29.17,63.9 29.15,63.91 28.67,64.39 28.66,64.41 28.65,64.43 28.65,65.66 28.65,65.67 28.64,65.69 28.39,65.94 28.38,65.96 28.37,65.98 28.37,66.35 28.38,66.37 28.41,66.39 28.42,66.4
DGND on L05_SIG02 (solid shape): 34.26,36.54 34.28,36.53 34.3,36.52 34.35,36.44 34.36,36.41 34.35,36.4 34.37,36.11 34.61,35.95 34.64,35.95 36.09,34.5 36.1,34.48 36.12,34.48 36.72,34.48 36.74,34.47 36.76,34.46 36.81,34.37 36.81,34.35 36.81,34.34 36.78,34.22 36.79,34.1 36.8,34.09 36.79,34.07 36.74,33.99 36.72,33.98 36.7,33.97 36.08,33.97 36.06,33.98 36.04,33.99 33.73,36.31 33.71,36.36 33.69,36.41 33.7,36.44 33.75,36.52 33.77,36.53 33.79,36.54
DGND on L05_SIG02 (solid shape): 49.64,34.35 49.66,34.35 49.68,34.33 50.21,33.81 50.23,33.79 50.24,33.79 53.63,33.79 53.65,33.79 53.66,33.78 55.05,32.39 55.07,32.38 55.09,32.37 55.4,32.37 55.42,32.37 55.43,32.36 55.87,31.92 55.88,31.9 55.88,31.87 55.87,31.85 55.84,31.84 55.1,31.84 55.09,31.84 55.07,31.85 54.6,32.32 54.59,32.33 54.57,32.33 54.42,32.33 54.4,32.34 54.39,32.35 53.92,32.82 53.9,32.83 53.89,32.83 53.12,32.83 53.1,32.83 53.08,32.85 52.59,33.34 52.57,33.35 52.55,33.36 49.75,33.36 49.73,33.36 49.71,33.37 48.82,34.26 48.8,34.29 48.81,34.32 48.81,34.33 48.84,34.35
DGND on L05_SIG02 (solid shape): 17.65,114.72 17.67,114.72 17.69,114.71 17.98,114.42 17.99,114.4 18,114.38 18,114.03 18,113.99 18.01,113.93 18.01,113.91 17.95,113.83 17.94,113.82 17.91,113.81 16.55,113.81 16.53,113.81 16.51,113.8 15.99,113.28 15.98,113.27 15.96,113.26 15.41,113.26 15.38,113.27 15.36,113.3 15.36,113.31 15.36,113.34 16.27,114.25 16.29,114.26 16.31,114.26 16.84,114.26 16.87,114.25 17.25,114.24 17.39,114.6 17.38,114.61 17.39,114.63 17.45,114.7 17.46,114.72 17.49,114.72
DGND on L05_SIG02 (solid shape): 24.12,41.99 24.88,41.23 24.89,41.21 24.9,41.19 24.9,40.75 24.9,40.73 24.91,40.71 25.73,39.9 25.74,39.88 25.74,39.85 25.71,39.76 25.7,39.74 25.68,39.73 25.49,39.57 25.47,39.32 25.47,39.31 25.47,39.29 25.41,39.21 25.39,39.2 25.37,39.19 24.9,39.19 24.88,39.19 24.87,39.18 23.95,38.26 23.93,38.25 23.91,38.24 23.64,38.24 23.62,38.25 23.6,38.26 23.54,38.34 23.54,38.36 23.56,38.43 24.03,38.9 24.04,38.92 24.05,38.94 24.05,41.94 24.05,41.97 24.08,41.99 24.09,42
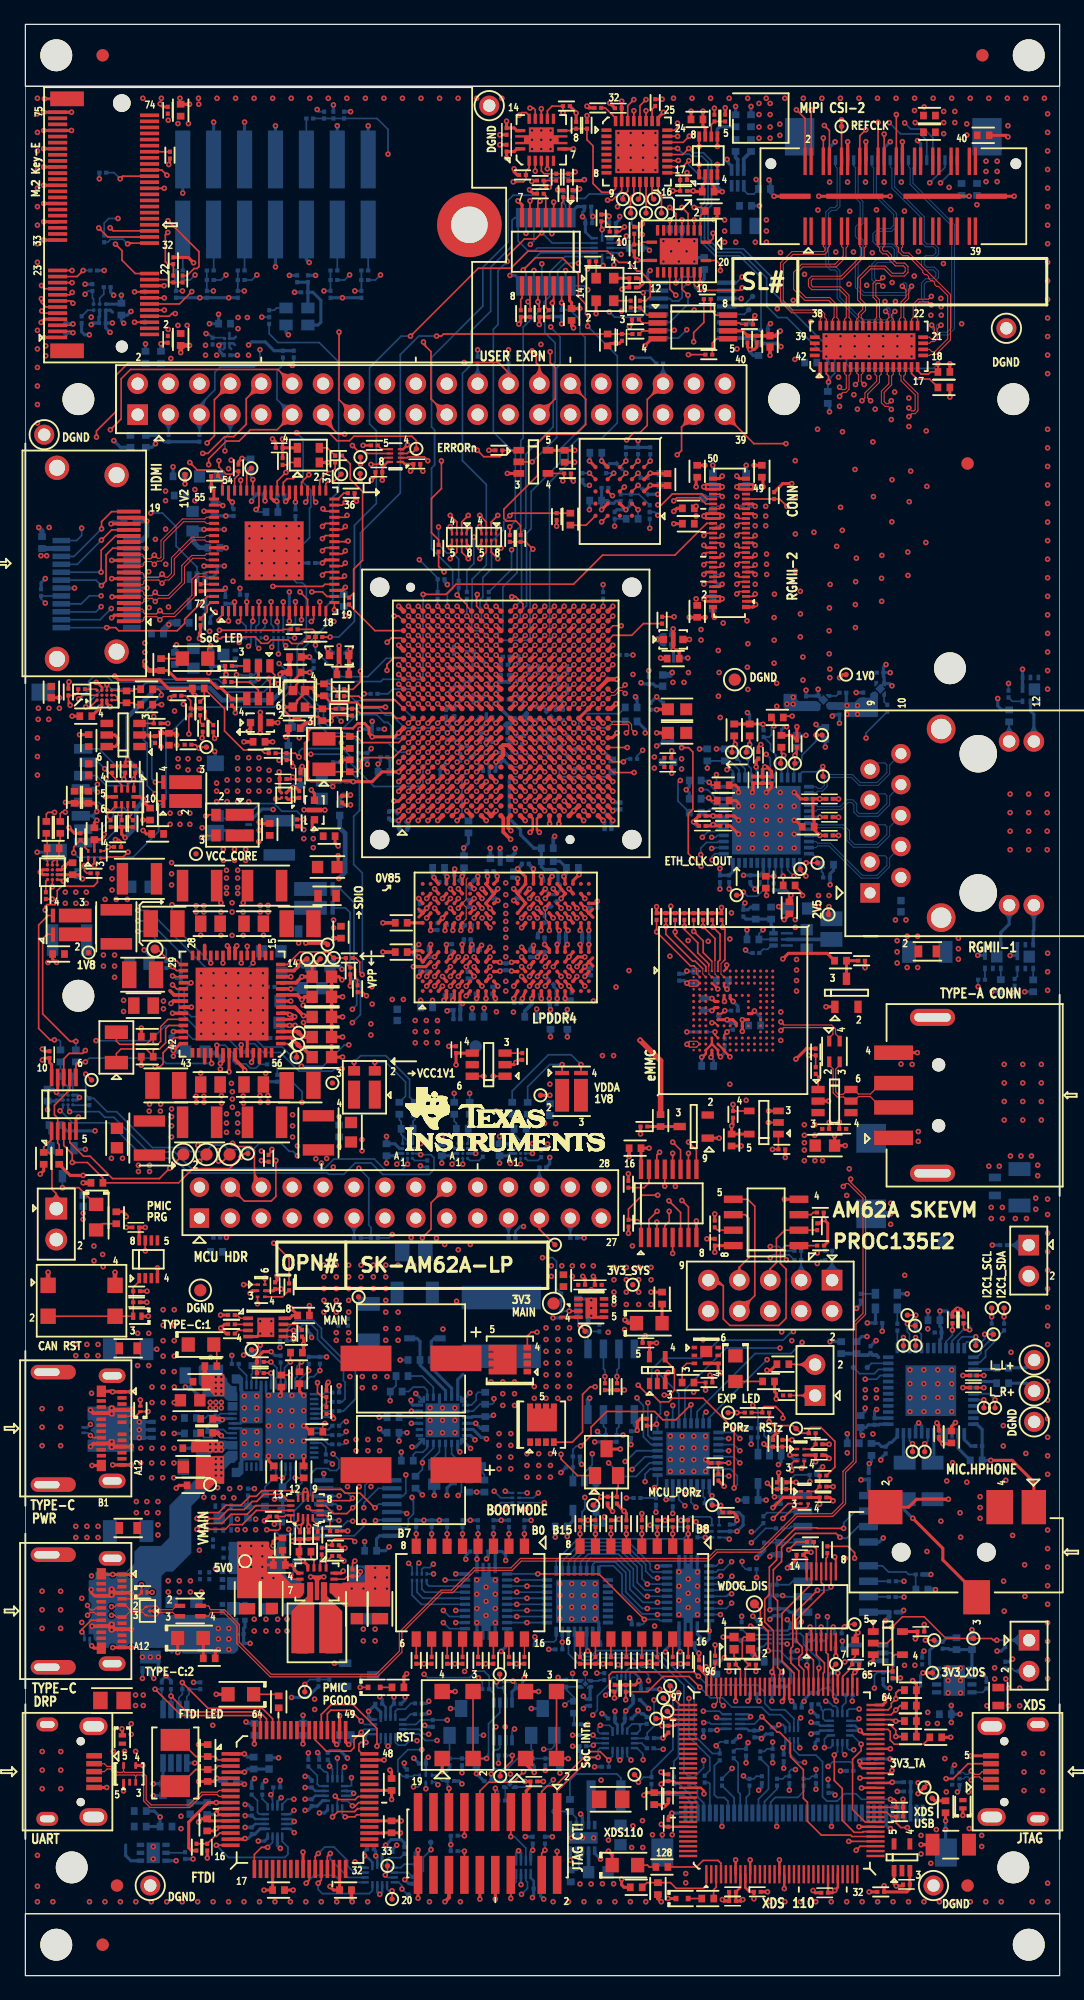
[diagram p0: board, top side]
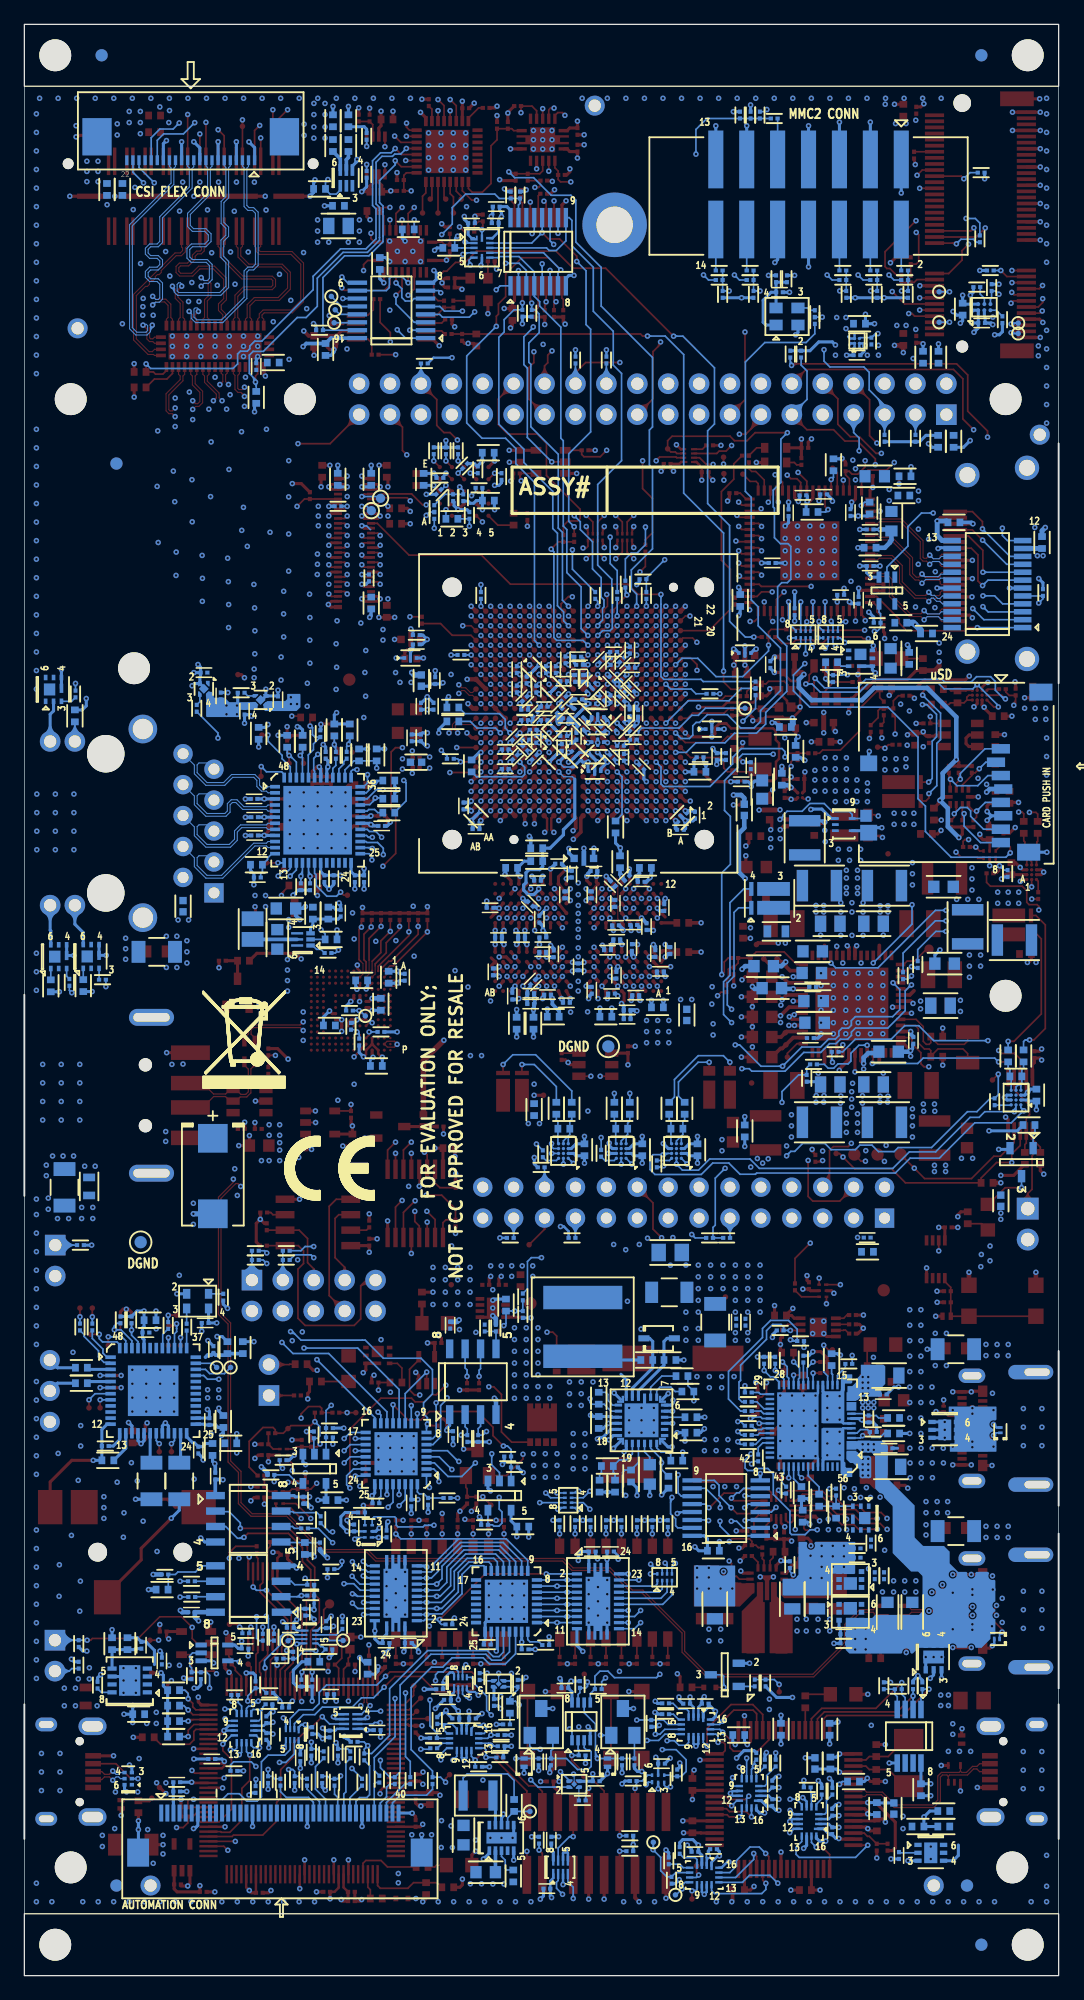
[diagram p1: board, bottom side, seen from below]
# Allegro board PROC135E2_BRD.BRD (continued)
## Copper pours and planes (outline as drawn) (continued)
DGND on L05_SIG02 (solid shape): 66.54,44.48 66.57,44.49 66.59,44.49 66.61,44.48 66.63,44.45 66.63,40.57 66.62,40.55 66.61,40.53 66.53,40.48 66.5,40.47 66.49,40.48 66.39,40.49 66.29,40.48 66.28,40.47 66.26,40.48 66.18,40.53 66.17,40.55 66.16,40.57 66.16,42.05 66.16,42.07 66.15,42.09 65.83,42.4 65.82,42.42 65.81,42.44 65.81,43.23 65.82,43.26 65.84,43.27 65.91,43.33 65.94,43.33 65.95,43.33 66.37,43.52 66.2,43.94 66.19,43.95 66.17,43.97 66.16,44.06 66.16,44.08 66.17,44.11
DGND on L05_SIG02 (solid shape): 10.23,127.57 10.25,127.55 10.26,127.52 10.26,127.42 10.27,127.41 10.28,127.39 12.17,125.5 12.19,125.48 12.21,125.48 14.22,125.48 14.24,125.48 14.26,125.47 14.33,125.39 14.34,125.38 14.34,125.36 14.34,125.28 14.29,125.2 14.25,125.13 14.22,125.12 14.18,125.14 11.81,125.14 11.79,125.13 11.77,125.12 10.61,123.96 10.58,123.95 10.55,123.95 10.54,123.95 10.52,123.98 10.52,125.68 10.51,125.7 10.5,125.71 9.24,126.98 9.22,127 9.22,127.03 9.26,127.13 9.29,127.15 9.3,127.15 9.74,127.28 10.08,127.58 10.09,127.6 10.12,127.61
DGND on L05_SIG02 (solid shape): 33.64,53.39 33.66,53.39 33.68,53.38 33.98,53.08 33.99,53.05 34.24,52.78 34.59,52.91 34.6,52.92 34.61,52.93 34.7,52.94 34.73,52.94 34.74,52.92 36.25,51.42 36.26,51.41 36.26,51.39 36.26,49.86 36.26,49.84 36.28,49.83 38.31,47.79 38.32,47.78 38.32,47.75 38.32,47.67 38.3,47.64 38.23,47.56 38.19,47.46 38.18,47.45 38.16,47.43 38.07,47.4 38.04,47.4 38.02,47.41 32.49,52.93 32.48,52.94 32.46,52.95 29.29,52.95 29.27,52.95 29.25,52.96 28.91,53.31 28.89,53.33 28.9,53.36 28.9,53.38 28.93,53.39
DGND on L05_SIG02 (solid shape): 45.45,95.79 45.47,95.79 45.49,95.78 45.54,95.71 45.55,95.68 45.66,95.42 45.95,95.34 45.99,95.33 46.01,95.29 46.01,95.24 45.99,95.2 45.84,95.19 45.74,95.17 45.73,95.16 45.7,95.17 45.35,95.51 45.34,95.52 45.32,95.53 44.8,95.53 44.78,95.52 44.77,95.51 44.58,95.32 44.56,95.31 44.52,95.31 44.5,95.32 44.32,95.51 44.3,95.52 44.28,95.53 44.03,95.53 44.01,95.53 43.99,95.54 43.81,95.73 43.8,95.73 43.82,95.76 43.83,95.78 43.86,95.79
DGND on L05_SIG02 (solid shape): 42.31,108.61 42.35,108.6 42.34,108.49 42.04,108.18 42.03,108.17 42.03,108.15 42.03,108.09 42.02,108.07 42.01,108.06 41.94,108 41.91,107.99 41.65,107.9 41.55,107.63 41.55,107.6 41.49,107.54 41.47,107.52 41.45,107.52 40.71,107.52 40.69,107.52 40.67,107.54 40.61,107.6 40.61,107.66 40.61,107.73 40.67,107.79 40.69,107.81 40.71,107.81 41.32,107.81 41.35,107.81 41.37,107.83 41.72,108.18 41.73,108.2 41.73,108.21 41.73,108.5 41.74,108.52 41.75,108.54 41.83,108.61
DGND on L05_SIG02 (solid shape): 7.26,116.61 7.28,116.62 7.31,116.62 7.33,116.62 7.34,116.59 7.34,114.31 7.34,114.29 7.33,114.28 7.2,114.15 7.19,114.14 7.17,114.14 6.7,114.14 6.68,114.13 6.65,114.11 6.61,114.11 6.59,114.13 6.58,114.16 6.46,114.42 6.17,114.48 6.16,114.48 6.14,114.49 6.07,114.54 6.05,114.56 6.05,114.58 6.05,114.84 6.05,114.86 6.07,114.88 6.13,114.93 6.16,114.94 6.17,114.94 6.54,115.15 6.38,115.55 6.37,115.56 6.36,115.58 6.35,115.67 6.35,115.69 6.36,115.71
DGND on L05_SIG02 (solid shape): 17.61,51.58 17.62,51.57 17.64,51.56 19.49,49.72 19.5,49.7 19.52,49.7 19.76,49.7 19.78,49.7 19.8,49.68 19.86,49.61 19.86,49.59 19.86,49.57 19.85,49.45 19.89,49.33 19.9,49.32 19.89,49.29 19.84,49.21 19.82,49.19 19.8,49.18 18.54,49.18 18.52,49.19 18.5,49.2 17.17,50.53 17.15,50.55 17.15,50.57 17.16,50.66 17.17,50.68 17.2,51.17 16.71,51.15 16.68,51.13 16.6,51.12 16.58,51.13 16.56,51.14 16.21,51.49 16.2,51.51 16.2,51.54 16.2,51.56 16.23,51.58
DGND on L05_SIG02 (solid shape): 41.95,84.32 42.28,83.99 42.29,83.98 42.31,83.97 42.35,83.97 42.38,83.97 42.39,83.95 42.45,83.86 42.45,83.83 42.44,83.82 42.44,83.51 42.7,83.34 42.73,83.32 42.74,83.29 42.73,83.25 42.67,83.2 42.65,83.19 42.52,83.12 42.43,83 42.43,82.99 42.41,82.98 42.31,82.96 42.29,82.96 42.27,82.97 42.21,83.03 42.2,83.05 42.19,83.07 42.19,83.22 42.19,83.24 42.18,83.26 41.64,83.79 41.63,83.81 41.63,83.83 41.63,84.18 41.63,84.2 41.64,84.22 41.71,84.27 41.74,84.28 41.82,84.29 41.9,84.31 41.92,84.32
DGND on L05_SIG02 (solid shape): 44.17,108.95 44.24,108.94 44.34,108.93 44.41,108.87 44.42,108.86 44.43,108.83 44.41,108.8 44.36,108.79 44.06,108.72 43.95,108.43 43.95,108.4 43.89,108.34 43.87,108.32 43.85,108.32 43.23,108.32 43.21,108.32 43.19,108.3 42.84,107.95 42.83,107.93 42.83,107.91 42.83,107.61 42.82,107.59 42.81,107.57 42.77,107.53 42.76,107.52 42.74,107.52 42.59,107.52 42.55,107.53 42.53,107.57 42.53,107.94 42.54,107.96 42.55,107.97 42.7,108.13 42.73,108.14 42.94,108.26 43.01,108.5 43.01,108.51 43.01,108.53 43.07,108.59 43.09,108.61 43.11,108.61 43.76,108.61 43.78,108.61 43.8,108.63 44.12,108.95 44.15,108.96
DGND on L05_SIG02 (solid shape): 18.06,88.54 18.1,88.56 18.14,88.54 18.24,88.44 18.25,88.42 18.26,88.4 18.26,85.79 18.26,85.77 18.27,85.75 19.65,84.37 19.66,84.36 19.66,84.34 19.66,76.99 19.65,76.96 19.63,76.94 19.62,76.94 19.59,76.94 19.4,77.13 19.39,77.15 19.38,77.17 19.38,82.86 19.38,82.88 19.37,82.9 19.05,83.22 19.04,83.24 18.88,83.45 18.62,83.49 18.61,83.48 18.59,83.49 18.51,83.54 18.5,83.56 18.49,83.58 18.49,84.31 18.5,84.34 18.5,84.74 18.12,84.85 18.1,84.85 18.06,84.86 18.05,84.9 18.05,84.9 17.71,85.24 17.7,85.26 17.69,85.28 17.69,88.15 17.7,88.17 17.71,88.19
DGND on L05_SIG02 (solid shape): 17.2,82.64 17.32,82.53 17.34,82.52 17.36,82.51 17.57,82.51 17.59,82.51 17.6,82.5 17.75,82.35 17.77,82.33 17.77,82.31 17.77,77.09 17.77,77.08 17.78,77.06 18.8,76.04 18.81,76.03 18.81,76.01 18.81,75.42 18.81,75.4 18.79,75.38 18.72,75.33 18.69,75.32 18.68,75.33 18.27,75.1 18.5,74.69 18.52,74.69 18.53,74.67 18.56,74.57 18.56,74.54 18.55,74.52 18.49,74.46 18.47,74.45 18.45,74.45 18.35,74.46 18.33,74.48 18.33,74.49 18.15,74.66 17.9,74.66 17.89,74.65 17.86,74.65 17.78,74.71 17.76,74.73 17.76,74.75 17.76,75.88 17.75,75.9 17.74,75.91 17.14,76.51 17.13,76.53 17.13,76.55 17.13,82.6 17.14,82.62 17.16,82.64 17.17,82.65
DGND on L05_SIG02 (solid shape): 20.22,129.92 20.24,129.9 20.25,129.87 20.25,127.44 20.25,127.42 20.26,127.4 21.01,126.65 21.02,126.63 21.02,126.61 21.01,126.52 20.99,126.5 20.98,126.49 20.91,125.97 21.43,126.05 21.44,126.06 21.46,126.07 21.55,126.08 21.57,126.08 21.61,126.04 21.62,126.02 21.62,124.04 21.61,124.02 21.6,124.01 21.39,123.79 21.34,123.78 21.32,123.79 21.25,123.84 21.24,123.86 21.23,123.88 21.23,124.45 21.23,124.47 21.22,124.48 18.55,127.15 18.54,127.17 18.53,127.19 18.53,129.87 18.54,129.89 18.56,129.91 18.66,129.96 18.69,129.95 18.7,129.94 19.39,129.69 20.08,129.95 20.09,129.96 20.12,129.96
DGND on L05_SIG02 (solid shape): 7.33,120.2 7.36,120.21 7.39,120.21 7.4,120.2 7.42,120.18 7.42,118.66 7.42,118.64 7.4,118.62 6.74,117.95 6.71,117.94 6.69,117.94 6.59,117.96 6.57,117.98 6.57,117.99 6.02,118.13 6.15,117.58 6.17,117.58 6.18,117.56 6.21,117.46 6.21,117.43 6.19,117.41 5.14,116.36 5.12,116.35 5.09,116.35 5.07,116.36 5.06,116.38 5.06,117.9 5.06,117.92 5.07,117.94 5.82,118.68 5.84,118.69 5.86,118.7 5.95,118.68 5.97,118.67 5.98,118.66 6.5,118.59 6.43,119.11 6.42,119.12 6.4,119.14 6.39,119.23 6.39,119.25 6.4,119.27
DGND on L05_SIG02 (solid shape): 42.06,60.2 42.08,60.19 42.1,60.18 43.38,58.9 43.39,58.88 43.4,58.86 43.4,56.6 43.4,56.58 43.41,56.56 44.86,55.12 44.87,55.1 44.87,55.08 44.87,55.01 44.87,54.99 44.86,54.97 44.79,54.91 44.77,54.91 44.72,54.92 41.63,58 41.62,58.03 41.62,58.06 41.63,58.07 41.65,58.09 41.96,58.09 41.98,58.09 41.99,58.1 42.52,58.63 42.54,58.64 42.73,59.2 42.17,59.01 42.16,58.99 41.78,58.61 41.77,58.6 41.75,58.6 35.88,58.6 35.85,58.61 35.83,58.63 35.82,58.64 35.83,58.67 36.81,59.65 36.82,59.67 36.82,59.69 36.82,59.82 36.89,59.96 36.9,60.09 36.9,60.12 36.96,60.18 36.98,60.19 37,60.2
DGND on L05_SIG02 (solid shape): 21.65,53.26 21.67,53.26 21.69,53.24 21.74,53.16 21.75,53.13 21.74,53.12 21.89,52.7 22.33,52.82 22.33,52.83 22.35,52.84 22.44,52.85 22.47,52.85 22.49,52.84 22.78,52.54 22.79,52.52 22.8,52.5 22.8,52.19 22.8,52.17 22.81,52.15 23.19,51.78 23.2,51.75 23.2,51.72 23.2,51.71 23.17,51.69 22.37,51.69 22.35,51.69 22.33,51.71 22.23,51.8 22.22,51.82 22.22,51.84 22.23,51.93 22.24,51.95 22.25,51.96 22.28,52.45 21.78,52.42 21.78,52.41 21.76,52.4 21.67,52.39 21.65,52.4 21.63,52.41 21.01,53.03 21,53.05 21,53.08 21.01,53.1 21.03,53.11 21.15,53.11 21.16,53.12 21.18,53.13 21.3,53.25 21.32,53.26 21.34,53.26
DGND on L05_SIG02 (solid shape): 71.31,117.41 71.33,117.43 71.36,117.43 71.38,117.42 71.39,117.39 71.39,102.97 71.39,102.95 71.38,102.93 70.35,101.91 70.34,101.89 70.33,101.87 70.33,99.83 70.32,99.8 70.3,99.78 70.2,99.74 70.17,99.75 70.16,99.76 69.48,100.09 68.77,99.85 68.76,99.84 68.73,99.84 68.63,99.88 68.61,99.9 68.6,99.93 68.6,101.35 68.61,101.36 68.62,101.38 68.68,101.44 68.7,101.45 68.72,101.46 68.81,101.45 68.83,101.43 69.32,101.41 69.3,101.9 69.28,101.92 69.27,102.01 69.28,102.03 69.29,102.05 70.51,103.28 70.53,103.29 70.53,103.31 70.53,109.84 70.53,109.86 70.54,109.87 71.14,110.47 71.15,110.49 71.16,110.51 71.16,117.25 71.16,117.27 71.17,117.28
DGND on L05_SIG02 (solid shape): 16.62,121.29 16.64,121.29 16.66,121.27 16.72,121.19 16.72,121.16 16.71,121.15 16.92,120.7 17.34,120.95 17.34,120.97 17.36,120.99 17.46,121.02 17.49,121.02 17.51,121.01 18.25,120.27 18.26,120.24 18.26,120.21 18.26,120.2 18.23,120.18 17.58,120.18 17.56,120.19 17.54,120.2 17.19,120.55 17.18,120.56 17.16,120.56 16.65,120.56 16.63,120.57 16.61,120.58 16.56,120.65 16.55,120.67 16.55,120.68 16.18,121.06 15.93,120.59 15.94,120.58 15.93,120.54 15.42,120.03 15.4,120.02 15.38,120.02 11.62,120.02 11.59,120.03 11.58,120.05 11.57,120.06 11.58,120.09 11.68,120.19 11.69,120.2 11.71,120.21 13.93,120.21 13.95,120.21 13.97,120.22 15.03,121.28 15.04,121.29 15.06,121.29
DGND on L05_SIG02 (solid shape): outline of 91 points within 43.64,34.86 49.74,39.5
DGND on L05_SIG02 (solid shape): 33.07,66.71 33.09,66.71 33.11,66.7 33.82,65.99 33.83,65.98 33.85,65.98 35.62,65.98 35.64,65.98 35.65,65.99 35.91,66.25 35.95,66.26 35.98,66.25 36.47,65.76 36.49,65.75 36.5,65.75 39.05,65.75 39.08,65.74 39.1,65.71 39.14,65.61 39.13,65.57 39.11,65.57 38.71,64.85 38.98,64.07 38.99,64.06 38.99,64.03 38.95,63.93 38.93,63.9 38.9,63.9 35.43,63.9 35.4,63.9 35.38,63.93 35.34,64.03 35.35,64.06 35.36,64.07 35.31,65.49 33.89,65.44 33.87,65.42 33.78,65.42 33.76,65.43 33.74,65.44 32.79,66.39 32.78,66.42 32.78,66.43 32.79,66.51 32.79,66.59 32.78,66.6 32.79,66.62 32.84,66.69 32.86,66.71 32.88,66.71
DGND on L05_SIG02 (solid shape): 17.39,91.31 17.64,91.06 17.65,91.04 17.66,91.02 17.66,88.88 17.65,88.86 17.64,88.84 17.2,88.4 17.19,88.38 17.19,88.36 17.19,85.07 17.19,85.05 17.23,85 17.23,84.98 17.22,84.89 17.21,84.87 17.2,84.86 17.05,84.53 17.29,84.26 17.31,84.26 17.32,84.24 17.35,84.14 17.35,84.12 17.34,84.09 17.02,83.78 17.01,83.76 17.01,83.74 17.01,83.57 17,83.54 16.98,83.52 16.96,83.51 16.93,83.52 16.4,84.05 16.39,84.07 16.39,84.09 16.39,84.17 16.39,84.19 16.41,84.21 16.48,84.26 16.5,84.27 16.51,84.26 16.92,84.48 16.71,84.89 16.7,84.9 16.68,84.92 16.66,85.01 16.66,85.04 16.68,85.06 16.82,85.2 16.83,85.22 16.83,85.24 16.83,88.19 16.84,88.21 16.85,88.23 17.15,88.53 17.16,88.55 17.17,88.56 17.17,91.19 17.17,91.21 17.18,91.23 17.21,91.26 17.29,91.28 17.36,91.31
DGND on L05_SIG02 (solid shape): outline of 83 points within 13.85,76.39 14.86,87.12
DGND on L05_SIG02 (solid shape): 8.5,107.87 8.53,107.85 8.54,107.82 8.54,107.73 8.53,107.71 8.52,107.7 7.75,106.93 7.73,106.92 7.71,106.91 7.63,106.92 7.6,106.94 7.08,106.93 7.21,106.43 7.23,106.42 7.24,106.4 7.24,104.23 7.24,104.21 7.23,104.19 6.86,103.83 6.84,103.81 6.81,103.82 6.79,103.82 6.77,103.85 6.77,104.78 6.77,104.8 6.76,104.82 6.49,105.08 6.48,105.1 6.48,105.12 6.48,105.62 6.49,105.64 6.5,105.66 6.57,105.72 6.6,105.72 6.61,105.72 7.02,106.04 6.61,106.36 6.6,106.35 6.57,106.36 6.5,106.42 6.49,106.43 6.48,106.46 6.48,107.8 6.49,107.83 6.51,107.85 6.61,107.89 6.64,107.89 6.65,107.88 7.51,107.53 8.36,107.89 8.37,107.9 8.4,107.91
DGND on L05_SIG02 (solid shape): 32.63,111.69 32.66,111.7 32.7,111.69 32.74,111.64 32.75,111.62 32.88,111.4 33.11,111.34 33.15,111.33 33.21,111.27 33.22,111.26 33.23,111.23 33.23,111.18 33.23,111.16 33.24,111.14 33.54,110.84 33.55,110.73 33.51,110.72 32.71,110.72 32.69,110.72 32.67,110.74 32.61,110.8 32.61,110.83 32.4,111.17 32.02,111.07 31.99,111.05 31.9,111.04 31.88,111.04 31.87,111.06 31.82,111.1 31.8,111.12 31.78,111.12 31.71,111.12 31.59,111.18 31.49,111.2 31.46,111.21 31.44,111.25 31.46,111.28 31.5,111.33 31.53,111.34 31.73,111.44 31.81,111.65 31.83,111.69 31.86,111.7 31.9,111.69 31.94,111.64 31.95,111.62 32.3,111.33 32.61,111.65
DGND on L05_SIG02 (solid shape): 50.73,124.65 50.75,124.64 51.02,124.37 51.03,124.35 51.26,124.08 51.6,124.18 51.63,124.19 51.71,124.2 51.73,124.19 51.75,124.18 52.14,123.79 52.15,123.77 52.16,123.75 52.16,122.08 52.15,122.06 52.14,122.04 52.07,121.99 52.05,121.98 52.04,121.98 51.77,121.92 51.64,121.68 51.64,121.66 51.61,121.63 51.13,121.63 51.1,121.64 51.08,121.67 51.07,121.68 51.08,121.71 51.13,121.76 51.14,121.78 51.15,121.8 51.15,122.39 51.14,122.41 51.13,122.43 50.99,122.58 50.9,122.63 50.81,122.65 50.69,122.65 50.67,122.66 50.65,122.68 50.64,122.7 50.65,122.73 51.08,123.16 51.12,123.16 51.14,123.15 51.68,123.35 51.21,123.7 51.2,123.69 51.18,123.69 51.09,123.74 51.08,123.76 51.07,123.79 51.07,124.02 51.07,124.04 51.05,124.05 50.69,124.42 50.67,124.5 50.64,124.55 50.64,124.58 50.64,124.6 50.66,124.63 50.68,124.65
DGND on L05_SIG02 (solid shape): 64.6,76.77 64.63,76.78 64.65,76.78 64.67,76.77 64.69,76.75 64.69,75.95 64.68,75.93 64.66,75.91 64.57,75.86 64.55,75.86 64.53,75.86 64.04,75.58 64.53,75.29 64.55,75.3 64.57,75.3 64.66,75.25 64.68,75.23 64.69,75.2 64.69,74.02 64.68,74 64.67,73.98 63.08,72.39 63.06,72.37 63.06,72.35 63.06,62.58 63.05,62.56 63.03,62.54 63.01,62.53 62.99,62.54 62.17,63.35 62.16,63.37 62.16,63.39 62.16,66.81 62.16,66.83 62.18,66.85 62.26,66.9 62.29,66.91 62.3,66.9 62.73,67.02 62.65,67.46 62.64,67.48 62.63,67.58 62.64,67.6 62.64,74.79 62.64,74.81 62.65,74.82 62.91,75.08 62.93,75.09 62.95,75.1 63.04,75.09 63.06,75.07 63.56,75.04 63.53,75.54 63.51,75.56 63.5,75.65 63.51,75.67 63.52,75.69
DGND on L05_SIG02 (solid shape): 60.11,115.56 60.18,115.5 60.19,115.48 60.2,115.46 60.2,113.89 60.19,113.87 60.18,113.85 60.11,113.79 60.08,113.79 60.07,113.79 59.8,113.75 59.65,113.52 59.64,113.5 58.9,112.76 58.89,112.74 58.89,112.72 58.89,111.92 58.87,111.89 58.84,111.87 58.82,111.87 58.78,111.89 58.77,111.92 58.77,112.06 58.75,112.16 58.7,112.24 58.51,112.42 58.5,112.43 58.48,112.43 58.28,112.43 58.25,112.44 58.23,112.46 58.23,112.48 58.23,112.51 58.71,112.98 58.72,113 58.72,113.02 58.72,113.25 58.73,113.28 58.77,113.62 58.48,113.81 58.44,113.82 58.43,113.86 58.44,113.89 58.49,113.94 58.51,113.95 58.8,114.29 58.48,114.61 58.44,114.62 58.43,114.66 58.44,114.69 58.49,114.74 58.51,114.75 58.72,114.87 58.8,115.09 58.8,115.12 58.86,115.19 58.88,115.2 58.9,115.2 59.64,115.2 59.66,115.21 59.68,115.22 60,115.54 60.08,115.56
DGND on L05_SIG02 (solid shape): 40.71,95.79 40.74,95.78 40.76,95.73 41.03,95.34 41.41,95.63 41.42,95.66 41.46,95.68 41.5,95.66 41.55,95.61 41.56,95.59 41.68,95.4 41.9,95.34 41.93,95.33 41.99,95.27 42,95.25 42.01,95.23 42.01,94.66 42.01,94.64 42.02,94.62 42.25,94.39 42.26,94.37 42.26,94.34 42.23,94.24 42.21,94.22 42.19,94.22 42.05,94.17 41.96,94.06 41.95,94.06 41.9,94 41.86,93.99 41.82,94 41.77,94.06 41.76,94.06 41.47,94.23 41.18,94.04 41.17,94.03 41.14,94.01 41.1,94.03 41.06,94.07 41.05,94.09 41.04,94.11 41.04,94.31 41.04,94.33 41.03,94.35 40.41,94.96 40.39,94.97 40.37,94.98 39.51,94.98 39.49,94.97 39.47,94.96 39.12,94.61 39.09,94.59 39.06,94.6 39.05,94.6 39.03,94.63 39.03,94.85 39.04,94.87 39.05,94.89 39.79,95.63 39.81,95.64 39.84,95.64 39.94,95.62 39.96,95.6 39.96,95.58 40.35,95.34 40.6,95.73 40.62,95.78 40.65,95.79
DGND on L05_SIG02 (solid shape): outline of 148 points within 58.66,130.54 64.49,134.35
DGND on L05_SIG02 (solid shape): 33.11,95.79 33.13,95.79 33.15,95.78 33.19,95.73 33.2,95.72 33.21,95.7 33.21,95.31 33.2,95.28 33.18,95.26 33.16,95.26 33.13,95.26 33.1,95.29 33.08,95.31 33.06,95.31 32.77,95.31 32.65,95.28 32.55,95.22 32.49,95.15 32.45,95.15 32.44,95.16 31.99,95.03 32.11,94.58 32.14,94.55 32.14,94.53 32.14,94.15 32.14,94.13 32.16,94.11 32.29,93.97 32.3,93.96 32.31,93.94 32.31,93.89 32.29,93.86 32.26,93.84 31.46,93.84 31.44,93.84 31.43,93.83 31.06,93.46 31.04,93.44 31.01,93.45 30.99,93.45 30.97,93.48 30.97,93.85 30.98,93.87 30.99,93.89 31.34,94.24 31.35,94.25 31.35,94.27 31.35,94.43 31.36,94.45 31.37,94.47 31.43,94.53 31.46,94.53 31.81,94.84 31.51,95.19 31.48,95.21 31.47,95.24 31.48,95.28 31.54,95.34 31.56,95.34 31.73,95.45 31.81,95.63 31.82,95.66 31.86,95.68 31.9,95.66 31.95,95.61 31.96,95.59 32.33,95.34 32.61,95.68 32.62,95.71 32.67,95.78 32.69,95.79 32.71,95.79
DGND on L05_SIG02 (solid shape): outline of 140 points within 57,43.5 63.91,46.28
DGND on L05_SIG02 (solid shape): 34.85,83.97 34.87,83.97 34.89,83.96 35.25,83.6 35.26,83.58 35.51,83.34 35.83,83.45 35.85,83.46 35.87,83.46 35.94,83.46 35.96,83.46 35.98,83.45 36.23,83.33 36.48,83.45 36.49,83.46 36.51,83.46 36.6,83.46 36.62,83.46 36.63,83.45 36.78,83.35 36.95,83.34 37,83.33 37.02,83.29 37.02,83.24 37,83.2 36.95,83.19 36.78,83.18 36.63,83.08 36.61,83.07 36.59,83.07 36.52,83.07 36.5,83.07 36.48,83.08 35.97,83.07 36.09,82.57 36.1,82.56 36.11,82.54 36.13,82.45 36.13,82.43 36.11,82.4 36.09,82.38 36.07,82.36 36.07,82.34 36.07,82.06 36.07,82.04 36.06,82.02 35.99,81.95 35.95,81.94 35.92,81.95 35.91,81.96 35.9,81.99 35.9,82 35.73,82.36 35.33,82.28 35.32,82.27 35.3,82.27 35.21,82.27 35.19,82.27 35.14,82.32 35.09,82.35 35.02,82.43 35,82.47 35.02,82.5 35.09,82.58 35.1,82.58 35.23,83.01 34.81,83.17 34.8,83.17 34.78,83.17 34.7,83.23 34.68,83.24 34.67,83.27 34.67,83.92 34.69,83.96 34.72,83.97
DGND on L05_SIG02 (solid shape): 38.73,91.21 39.65,90.28 39.66,90.27 39.67,90.25 39.67,90.17 39.66,90.15 39.65,90.13 39.58,90.07 39.56,90.07 39.55,90.07 39.16,89.81 39.42,89.42 39.43,89.42 39.46,89.39 39.46,89.14 39.43,89.11 39.42,89.11 39.21,88.6 39.76,88.6 39.8,88.62 39.83,88.61 39.88,88.56 39.88,88.52 39.87,88.51 39.8,88.28 39.9,88.06 39.91,88.04 39.91,87.96 39.91,87.94 39.86,87.9 39.82,87.92 39.81,87.94 39.5,88.22 39.16,87.98 39.16,87.97 39.14,87.95 39.04,87.92 39.01,87.92 38.97,87.97 39,88.02 39.14,88.41 38.77,88.62 38.76,88.62 38.74,88.63 38.67,88.69 38.66,88.7 38.65,88.72 38.65,89.86 38.66,89.88 38.67,89.89 38.73,89.95 38.76,89.96 39.11,90.29 38.76,90.62 38.73,90.62 38.67,90.68 38.66,90.7 38.65,90.72 38.65,91.16 38.66,91.19 38.68,91.21 38.7,91.21
DGND on L05_SIG02 (solid shape): 21.78,121.23 21.8,121.23 21.82,121.21 21.87,121.14 21.88,121.12 21.88,121.1 22.2,120.69 22.52,121.1 22.51,121.12 22.52,121.14 22.57,121.21 22.59,121.23 22.64,121.23 22.66,121.21 22.71,121.14 22.72,121.11 22.71,121.1 23.03,120.68 23.35,121.1 23.35,121.11 23.35,121.14 23.41,121.21 23.43,121.23 23.45,121.23 23.52,121.23 23.55,121.22 23.57,121.18 23.56,121.16 23.83,120.68 24.18,121.1 24.17,121.11 24.18,121.14 24.24,121.21 24.25,121.23 24.28,121.23 25.88,121.23 25.9,121.23 25.92,121.21 25.97,121.14 25.98,121.12 25.98,121.1 25.97,121.01 25.99,120.91 25.99,120.9 25.99,120.87 25.93,120.8 25.91,120.78 25.89,120.77 25.28,120.77 25.26,120.77 25.24,120.76 24.95,120.47 24.93,120.45 24.9,120.46 24.8,120.49 24.78,120.51 24.78,120.52 24.4,120.8 24.12,120.42 24.13,120.41 24.12,120.39 24.06,120.32 24.04,120.31 24.02,120.3 21.08,120.3 21.06,120.31 21.04,120.32 20.74,120.62 20.73,120.64 20.73,120.67 20.75,120.76 20.76,120.78 20.78,120.79 20.94,120.92 20.99,121.12 20.99,121.15 21.05,121.21 21.07,121.23 21.09,121.23
DGND on L05_SIG02 (solid shape): outline of 167 points within 22.63,18.69 26.86,35.05
DGND on L05_SIG02 (solid shape): outline of 185 points within 55.99,26.59 60.79,31.33
DGND on L05_SIG02 (solid shape): outline of 213 points within 64.29,10.71 67.41,17.73
DGND on L05_SIG02 (solid shape): outline of 223 points within 51.51,16.4 63.48,19.39
DGND on L05_SIG02 (solid shape): outline of 214 points within 60.35,57.89 62.42,74.62
DGND on L05_SIG02 (solid shape): outline of 104 points within 67.08,49.7 74.41,64.03
DGND on L05_SIG02 (solid shape): outline of 243 points within 57.38,130.77 67.15,140.22
DGND on L05_SIG02 (solid shape): outline of 307 points within 4.5,56 9.76,70.56
DGND on L05_SIG02 (solid shape): outline of 272 points within 32.24,99.53 34.83,104.16
DGND on L05_SIG02 (solid shape): outline of 322 points within 1.64,54.88 7.96,79.29
DGND on L05_SIG02 (solid shape): outline of 428 points within 21.13,60.53 32.95,70.34
DGND on L05_SIG02 (solid shape): outline of 523 points within 32.17,84.93 35.98,91.14
DGND on L05_SIG02 (solid shape): outline of 714 points within 37.34,16.77 49.58,25.4
DGND on L05_SIG02 (solid shape): outline of 951 points within 0.64,28.13 18.92,59.28
DGND on L10_SIG03 (solid shape): 8.15,80.54 8.17,80.56 8.2,80.55 8.22,80.55 8.23,80.52 8.23,73.37 8.23,73.35 8.22,73.33 8.01,73.12 7.99,73.11 7.96,73.11 7.94,73.12 7.93,73.14 7.93,80.3 7.93,80.32 7.94,80.34
DGND on L10_SIG03 (solid shape): 17.05,108.9 19.52,106.43 19.53,106.4 19.53,106.37 19.53,106.36 19.5,106.34 19.16,106.34 19.14,106.34 19.12,106.35 16.99,108.49 16.98,108.5 16.97,108.52 16.97,108.85 16.98,108.88 17,108.9 17.02,108.9
DGND on L10_SIG03 (solid shape): 17.4,102.12 17.42,102.12 17.44,102.11 18.58,100.96 18.59,100.94 18.59,100.91 18.58,100.89 18.56,100.88 18.11,100.88 18.09,100.88 18.07,100.89 16.93,102.03 16.92,102.06 16.92,102.09 16.93,102.1 16.95,102.12
DGND on L10_SIG03 (solid shape): 31.01,50.69 31.03,50.68 31.05,50.66 31.06,50.64 31.05,50.61 30.85,50.41 30.84,50.4 30.82,50.4 25.42,50.4 25.39,50.41 25.37,50.43 25.37,50.45 25.37,50.48 25.57,50.67 25.59,50.68 25.61,50.69
DGND on L10_SIG03 (solid shape): 45.98,121.17 46,121.17 46.01,121.16 46.6,120.57 46.61,120.56 46.61,120.54 46.61,120.02 46.6,119.99 46.58,119.97 46.57,119.96 46.54,119.97 45.42,121.08 45.41,121.11 45.41,121.14 45.41,121.15 45.44,121.17
DGND on L10_SIG03 (solid shape): 46.38,37.88 46.4,37.88 46.42,37.87 47.12,37.16 47.14,37.14 47.13,37.11 47.13,37.09 47.1,37.08 43.68,37.08 43.67,37.08 43.65,37.09 42.94,37.8 42.93,37.82 42.93,37.85 42.94,37.87 42.97,37.88
DGND on L10_SIG03 (solid shape): 56.64,69.53 57.62,68.55 57.63,68.53 57.64,68.51 57.64,68.05 57.63,68.03 57.61,68.01 57.59,68 57.56,68.01 56.58,68.99 56.57,69.01 56.56,69.03 56.56,69.48 56.57,69.51 56.6,69.53 56.61,69.54
DGND on L10_SIG03 (solid shape): 28,121.75 28.02,121.74 28.04,121.72 28.05,121.71 28.04,121.68 27.28,120.91 27.26,120.9 27.24,120.89 26.67,120.89 26.63,120.91 26.63,121 27.37,121.74 27.39,121.75 27.41,121.75
DGND on L10_SIG03 (solid shape): 13.71,81.22 13.78,81.16 13.8,81.14 13.8,81.12 13.8,74.71 13.8,74.69 13.79,74.68 13.55,74.44 13.52,74.42 13.49,74.42 13.48,74.43 13.46,74.46 13.46,81.11 13.47,81.13 13.48,81.15 13.54,81.21 13.63,81.21 13.69,81.22
DGND on L10_SIG03 (solid shape): 30.18,46.24 30.21,46.23 30.22,46.21 30.23,46.19 30.22,46.16 29.71,45.65 29.69,45.64 29.67,45.63 26.69,45.63 26.67,45.65 26.66,45.66 26.6,45.74 26.53,45.8 26.51,45.8 26.5,45.82 26.49,45.91 26.49,45.94 26.5,45.96 26.77,46.22 26.78,46.23 26.8,46.24
DGND on L10_SIG03 (solid shape): 43.24,41.11 43.26,41.11 43.28,41.09 43.51,40.87 43.52,40.84 43.52,40.81 43.51,40.8 43.49,40.78 40.73,40.78 40.71,40.78 40.69,40.77 39.88,39.95 39.86,39.93 39.83,39.93 39.74,39.94 39.72,39.95 39.72,39.97 39.76,40.05 39.77,40.05 40.82,41.09 40.83,41.11 40.85,41.11
DGND on L10_SIG03 (solid shape): 53.23,54.76 53.26,54.78 53.29,54.77 53.3,54.77 53.32,54.74 53.32,54.6 53.31,54.58 53.3,54.56 50.41,51.67 50.39,51.66 50.37,51.65 49.66,51.65 49.63,51.66 49.61,51.68 49.61,51.7 49.61,51.73 50.74,52.86 50.76,52.87 50.78,52.87 51.32,52.87 51.34,52.87 51.35,52.89
DGND on L10_SIG03 (solid shape): 61.03,37.67 61.05,37.67 61.07,37.66 61.12,37.6 61.13,37.57 61.14,37.46 61.19,37.36 61.2,37.35 61.2,37.32 61.15,37.23 61.13,37.21 61.1,37.2 58.14,37.2 58.12,37.21 58.1,37.23 58.09,37.25 58.1,37.28 58.48,37.66 58.5,37.67 58.51,37.67
DGND on L10_SIG03 (solid shape): 13.55,109.49 13.62,109.44 13.64,109.42 13.64,109.4 13.64,108.81 13.65,108.79 13.66,108.78 16.87,105.57 16.88,105.54 16.88,105.51 16.87,105.5 16.85,105.48 16.39,105.48 16.37,105.48 16.36,105.49 13.39,108.46 13.38,108.47 13.38,108.49 13.38,109.39 13.38,109.41 13.39,109.42 13.44,109.48 13.53,109.5
DGND on L10_SIG03 (solid shape): 28.21,99.13 28.28,99.07 28.3,99.06 28.3,99.01 28.29,99 27.08,97.79 27.06,97.78 27.04,97.77 26.47,97.77 26.45,97.77 26.43,97.75 26.4,97.76 26.37,97.78 26.36,97.81 26.36,98.01 26.37,98.03 26.38,98.05 27.44,99.11 27.46,99.12 27.48,99.12 28.1,99.12 28.14,99.13 28.19,99.14
DGND on L10_SIG03 (solid shape): 36.47,46.15 36.5,46.14 36.52,46.12 36.52,46.11 36.52,46.08 35.67,45.23 35.66,45.21 35.65,45.19 35.65,44.72 35.65,44.7 35.64,44.69 35.16,44.2 35.13,44.19 35.1,44.19 35.09,44.2 35.07,44.22 35.07,45.6 35.07,45.62 35.09,45.64 35.22,45.77 35.24,45.78 35.25,45.78 35.79,45.78 35.81,45.79 35.82,45.8 36.16,46.14 36.18,46.15 36.2,46.15
DGND on L10_SIG03 (solid shape): 29.02,102.35 29.04,102.37 29.07,102.37 29.16,102.34 29.18,102.32 29.19,102.3 29.25,102.17 29.36,102.08 29.38,102.07 29.39,102.05 29.41,101.96 29.4,101.94 29.39,101.91 28.97,101.5 28.96,101.49 28.94,101.48 27.84,101.48 27.81,101.49 27.79,101.51 27.78,101.53 27.79,101.56 28.26,102.03 28.28,102.04 28.3,102.05 28.68,102.05 28.7,102.05 28.72,102.06
DGND on L10_SIG03 (solid shape): 26.34,108.29 26.36,108.28 26.38,108.26 26.39,108.25 26.38,108.22 25.93,107.76 25.91,107.74 25.91,107.72 25.91,107.42 25.91,107.4 25.9,107.38 25.4,106.89 25.38,106.88 25.36,106.87 23.41,106.87 23.39,106.87 23.37,106.86 22.23,105.72 22.22,105.71 22.2,105.71 21.98,105.71 21.96,105.72 21.94,105.74 21.93,105.75 21.94,105.78 23.57,107.42 23.59,107.43 23.61,107.43 25.22,107.43 25.24,107.43 25.25,107.44 26.09,108.28 26.1,108.29 26.12,108.29
DGND on L10_SIG03 (solid shape): 65.52,56.41 65.53,56.4 66.24,56.07 66.99,56.33 67,56.34 67.03,56.34 67.12,56.3 67.15,56.28 67.15,56.25 67.15,54.09 67.15,54.07 67.14,54.05 66.58,53.5 66.56,53.48 66.55,53.48 65.93,53.48 65.91,53.48 65.9,53.47 65.44,53.01 65.42,53 65.39,53 65.37,53.01 65.36,53.03 65.36,56.33 65.37,56.36 65.39,56.37 65.49,56.41
DGND on L10_SIG03 (solid shape): 20.34,130.05 20.36,130.03 20.37,130 20.37,127.98 20.37,127.96 20.36,127.94 19.19,126.77 19.17,126.76 19.15,126.76 18.04,126.76 18.01,126.77 17.99,126.79 17.98,126.81 17.99,126.84 18.53,127.38 18.54,127.39 18.55,127.41 18.55,129.86 18.55,129.88 18.57,129.9 18.67,129.95 18.7,129.94 18.71,129.93 19.48,129.69 20.19,130.06 20.2,130.08 20.23,130.09
DGND on L10_SIG03 (solid shape): 6.66,122.36 6.68,122.35 7.08,122.11 7.54,122.03 7.56,122.03 7.58,122.01 7.63,121.91 7.63,121.88 7.62,121.86 7.33,121.57 7.32,121.55 7.32,121.54 7.32,112.69 7.31,112.66 7.3,112.64 7.22,112.59 7.19,112.59 7.18,112.59 7.1,112.61 7.03,112.61 6.99,112.62 6.93,112.67 6.92,112.69 6.91,112.71 6.91,121.51 6.91,121.53 6.9,121.55 6.52,121.92 6.51,121.94 6.51,121.96 6.51,122.28 6.51,122.31 6.54,122.33 6.64,122.37
DGND on L10_SIG03 (solid shape): 59.97,39.75 60,39.74 60.02,39.71 60.02,39.7 60.02,39.67 59.22,38.88 59.21,38.87 59.19,38.86 58.1,38.86 58.08,38.86 58.06,38.85 57.54,38.33 57.53,38.32 57.51,38.32 57.46,38.32 57.43,38.33 57.41,38.35 57.4,38.37 57.4,38.4 57.41,38.42 57.46,38.67 57.33,38.89 57.32,38.89 57.31,38.91 57.31,39 57.31,39.02 57.32,39.04 57.34,39.06 57.36,39.07 57.38,39.08 58.16,39.08 58.18,39.08 58.19,39.09 58.83,39.73 58.85,39.74 58.87,39.75
DGND on L10_SIG03 (solid shape): 41.14,104.93 41.21,104.87 41.22,104.86 41.23,104.83 41.23,103.82 41.23,103.8 41.24,103.78 41.97,103.05 41.99,103.04 42.01,103.04 42.25,103.04 42.27,103.03 42.29,103.02 42.35,102.95 42.36,102.93 42.35,102.87 42.35,102.8 42.29,102.74 42.27,102.72 42.25,102.72 41.51,102.72 41.49,102.72 41.47,102.74 41.41,102.8 41.41,102.83 41.31,103.1 41.05,103.19 41.02,103.2 40.95,103.26 40.94,103.27 40.93,103.3 40.93,104.83 40.94,104.86 40.95,104.87 41.02,104.93 41.08,104.93
DGND on L10_SIG03 (solid shape): 40.28,104.13 40.34,104.13 40.41,104.07 40.42,104.06 40.43,104.03 40.43,102.61 40.43,102.6 40.44,102.58 40.79,102.23 40.81,102.21 40.83,102.21 41.45,102.21 41.47,102.21 41.49,102.19 41.55,102.13 41.55,102.07 41.55,102 41.49,101.94 41.47,101.92 41.45,101.92 40.71,101.92 40.69,101.92 40.67,101.94 40.61,102 40.61,102.03 40.51,102.3 40.24,102.39 40.21,102.4 40.14,102.46 40.13,102.47 40.12,102.49 40.12,104.04 40.13,104.06 40.14,104.07 40.21,104.13
DGND on L10_SIG03 (solid shape): 4.51,107.47 4.54,107.48 4.57,107.48 4.58,107.47 4.6,107.45 4.6,106.34 4.6,106.32 4.58,106.3 3.02,104.74 3.01,104.72 3.01,104.7 3.01,104.05 3,104.03 2.99,104.01 1.87,102.88 1.84,102.87 1.81,102.87 1.8,102.88 1.78,102.91 1.78,104.71 1.79,104.73 1.8,104.75 3.15,106.1 3.17,106.11 3.19,106.12 3.28,106.11 3.3,106.09 3.31,106.08 3.82,106.03 3.76,106.54 3.75,106.55 3.74,106.57 3.73,106.66 3.73,106.68 3.74,106.7
DGND on L10_SIG03 (solid shape): 15.72,131.94 15.75,131.93 15.77,131.91 15.78,131.9 15.77,131.87 15.49,131.58 15.47,131.56 15.47,131.55 15.47,127.95 15.47,127.93 15.46,127.92 15.41,127.87 15.37,127.85 15.33,127.87 15.32,127.88 15.32,127.9 15.32,127.92 14.9,129.08 13.67,129.04 13.66,129.04 13.63,129.03 13.54,129.08 13.51,129.1 13.51,129.13 13.51,131.15 13.51,131.17 13.52,131.18 14.27,131.93 14.28,131.94 14.3,131.94
DGND on L10_SIG03 (solid shape): 39.56,37.98 39.63,37.93 39.65,37.91 39.65,37.89 39.65,37.21 39.65,37.19 39.64,37.17 38.91,36.44 38.89,36.43 38.86,36.43 38.77,36.44 38.75,36.45 38.75,36.46 38.35,36.59 38.14,36.23 38.15,36.21 38.14,36.19 38.08,36.13 38.06,36.11 38.04,36.11 37.63,36.11 37.6,36.11 37.59,36.13 37.53,36.19 37.52,36.21 37.53,36.28 37.52,36.35 37.53,36.37 37.59,36.44 37.6,36.45 37.63,36.46 37.78,36.46 37.8,36.46 37.82,36.47 39.23,37.88 39.24,37.91 39.33,37.98 39.35,37.99 39.36,37.98 39.44,37.97 39.52,37.99 39.54,37.99
DGND on L10_SIG03 (solid shape): 14.3,109.49 14.36,109.48 14.43,109.43 14.44,109.41 14.44,109.39 14.44,109.12 14.45,109.1 14.46,109.08 16.11,107.43 16.12,107.42 16.14,107.42 16.98,107.42 16.99,107.41 17.01,107.4 17.16,107.26 17.17,107.24 17.17,107.22 17.17,107.13 17.15,107.11 17.12,106.61 17.61,106.64 17.64,106.66 17.72,106.67 17.74,106.66 17.76,106.65 18.62,105.79 18.63,105.77 18.63,105.74 18.62,105.72 18.6,105.71 17.47,105.71 17.45,105.71 17.43,105.72 14.17,108.99 14.15,109 14.15,109.02 14.15,109.39 14.16,109.41 14.17,109.43 14.23,109.48
DGND on L10_SIG03 (solid shape): 43.05,95.78 43.07,95.78 43.08,95.76 43.14,95.7 43.15,95.67 43.24,95.44 43.47,95.33 43.5,95.33 43.56,95.27 43.57,95.25 43.57,95.23 43.57,95.2 43.58,95.18 43.59,95.17 43.71,95.05 43.72,95.03 43.72,95.01 43.71,94.91 43.69,94.89 43.68,94.89 43.54,94.72 43.53,94.5 43.53,94.49 43.53,94.47 43.47,94.39 43.45,94.37 43.43,94.37 42.93,94.37 42.91,94.37 42.87,94.41 42.87,94.43 42.87,95.14 42.87,95.16 42.86,95.18 42.5,95.53 42.49,95.54 42.47,95.54 42.31,95.54 42.29,95.55 42.28,95.56 42.22,95.62 42.22,95.7 42.28,95.76 42.29,95.78 42.31,95.78
DGND on L10_SIG03 (solid shape): 39.41,97.27 39.43,97.26 39.45,97.23 39.45,97.01 39.46,96.99 39.47,96.97 39.52,96.92 39.53,96.9 39.53,96.87 39.52,96.85 39.5,96.84 39.21,96.84 39.19,96.83 39.17,96.82 38.85,96.5 38.84,96.49 38.83,96.47 38.83,95.23 38.84,95.21 38.85,95.2 39.08,94.97 39.09,94.95 39.09,94.93 39.09,94.83 39.08,94.8 39.06,94.78 39.05,94.77 39.02,94.78 38.85,94.94 38.84,94.95 38.82,94.96 38.74,94.96 38.7,94.97 38.69,95.01 38.69,95.26 38.69,95.28 38.67,95.29 38.6,95.37 38.59,95.39 38.59,95.4 38.59,95.5 38.58,95.55 38.57,95.6 38.57,96.83 38.57,96.85 38.58,96.87 38.64,96.93 38.67,96.93 38.86,96.99 38.98,97.13 38.99,97.14 39.1,97.25 39.12,97.26 39.14,97.27
DGND on L10_SIG03 (solid shape): 63.76,21.41 63.79,21.4 64.17,21.02 64.17,21.02 64.25,20.93 64.25,20.91 64.24,20.87 64.24,20.82 64.24,20.76 64.25,20.72 64.24,20.7 64.18,20.62 64.16,20.61 63.96,20.61 63.92,20.6 63.51,20.19 63.47,20.17 60.92,20.17 60.82,20.25 60.82,20.27 60.82,20.31 60.82,20.37 60.81,20.4 60.82,20.43 61.19,20.64 61.58,20.64 61.58,20.58 61.59,20.53 61.61,20.48 61.63,20.44 61.66,20.39 61.7,20.36 61.74,20.33 61.79,20.3 61.84,20.29 61.89,20.28 61.94,20.28 61.99,20.29 62.04,20.3 62.09,20.33 62.13,20.36 62.17,20.39 62.2,20.44 62.22,20.48 62.24,20.53 62.24,20.58 62.24,20.64 62.24,20.69 62.22,20.74 62.2,20.78 62.17,20.82 62.13,20.86 62.09,20.89 62.04,20.92 61.99,20.93 61.94,20.94 61.89,20.94 61.84,20.93 61.79,20.92 61.74,20.89 61.7,20.86 61.66,20.82 61.63,20.78 61.61,20.74 61.59,20.69 61.58,20.64 61.19,20.64 61.95,21.4 61.99,21.41
DGND on L10_SIG03 (solid shape): 25.74,89.78 25.82,89.77 25.89,89.72 25.9,89.7 25.9,89.68 25.9,84.1 25.9,84.08 25.89,84.06 24.83,83 24.8,82.99 24.77,82.99 24.76,82.99 24.74,83.02 24.74,86.39 24.74,86.41 24.75,86.43 24.88,86.55 24.9,86.57 24.92,86.57 25.01,86.56 25.03,86.54 25.07,86.49 25.1,86.45 25.11,86.44 25.12,86.42 25.12,86.34 25.11,86.32 25.1,86.3 25.33,85.73 25.55,86.3 25.54,86.32 25.53,86.34 25.53,86.42 25.54,86.44 25.55,86.45 25.65,86.73 25.49,86.98 25.48,86.99 25.47,87.01 25.45,87.1 25.46,87.12 25.47,87.14 25.54,87.22 25.55,87.24 25.56,87.25 25.56,89.69 25.56,89.71 25.58,89.73 25.65,89.78 25.67,89.79
DGND on L10_SIG03 (solid shape): 57.81,57.99 57.84,57.98 57.85,57.96 57.9,57.86 57.89,57.83 57.88,57.82 57.64,57.34 57.67,56.81 57.67,56.79 57.63,56.57 57.55,56.36 57.54,56.35 57.27,56.08 57.26,56.06 57.26,56.04 57.26,53.18 57.25,53.16 57.24,53.14 54.88,50.78 54.86,50.77 54.84,50.76 53.29,50.76 53.26,50.77 53.25,50.79 53.24,50.81 53.25,50.84 55.18,52.78 55.19,52.79 55.2,52.81 55.2,55.8 55.2,55.82 55.21,55.84 55.36,55.99 55.38,56 55.58,56.08 55.8,56.12 55.82,56.12 57.02,56.55 56.93,57.82 56.92,57.83 56.91,57.86 56.96,57.96 56.98,57.98 57,57.99
DGND on L10_SIG03 (solid shape): 72.9,127.71 72.92,127.69 72.93,127.67 72.93,126.07 72.93,126.05 72.94,126.03 73.43,125.55 73.44,125.54 73.46,125.53 73.8,125.53 73.82,125.53 73.85,125.49 73.85,125.45 73.82,125.41 73.8,125.41 73.46,125.41 73.44,125.4 73.43,125.39 72.94,124.91 72.93,124.89 72.93,124.87 72.93,124.19 72.93,124.17 72.94,124.15 73.43,123.67 73.44,123.66 73.46,123.65 73.8,123.65 73.82,123.65 73.85,123.61 73.85,123.57 73.82,123.53 73.8,123.53 73.46,123.53 73.44,123.52 73.43,123.51 72.94,123.03 72.93,123.01 72.93,122.99 72.93,117 72.92,116.98 72.91,116.96 57.9,101.95 57.89,101.94 57.87,101.94 52.31,101.94 52.29,101.94 52.27,101.95 52.22,102.02 52.21,102.13 52.27,102.2 52.29,102.21 52.31,102.22 57.46,102.22 57.48,102.22 57.49,102.23 72.36,117.1 72.37,117.11 72.37,117.13 72.37,127.63 72.38,127.65 72.39,127.67 72.47,127.73 72.49,127.73 72.5,127.73 72.64,127.71 72.77,127.76 72.79,127.76 72.81,127.76
DGND on L10_SIG03 (solid shape): outline of 84 points within 26.31,41.78 38.05,46.97
DGND on L10_SIG03 (solid shape): 1.35,76.36 3.91,73.8 3.93,73.79 3.95,73.79 4.73,73.79 4.8,73.75 4.85,73.73 4.86,73.71 4.88,73.61 4.88,73.59 4.87,73.57 4.31,73 4.29,72.99 4.27,72.99 3.73,72.99 3.71,72.98 3.69,72.97 2.08,71.36 2.04,71.36 2.03,71.37 1.5,71.18 1.91,70.79 1.92,70.8 1.94,70.79 2.01,70.73 2.03,70.72 2.03,70.69 2.03,65.71 2.03,65.69 2.02,65.68 1.98,65.64 1.95,65.63 1.93,65.63 1.91,65.63 1.89,65.66 1.89,67.02 1.89,67.04 1.88,67.06 1.29,67.65 1.28,67.66 1.27,67.68 1.27,74.77 1.28,74.79 1.29,74.8 1.35,74.86 1.38,74.87 1.73,75.2 1.38,75.53 1.35,75.53 1.29,75.59 1.28,75.61 1.27,75.63 1.27,76.32 1.28,76.34 1.3,76.36 1.32,76.37
DGND on L10_SIG03 (solid shape): 39.48,42.8 39.5,42.79 39.52,42.78 39.57,42.71 39.58,42.68 39.57,42.67 39.57,42.51 39.65,42.37 39.65,42.36 39.66,42.34 39.66,42.31 39.65,42.29 39.64,42.27 39.25,41.88 39.23,41.86 39.21,41.86 39.18,41.86 39.16,41.86 39.15,41.87 38.67,41.83 38.73,41.36 38.74,41.35 38.75,41.33 38.75,41.29 38.75,41.27 38.72,41.24 38.67,41.23 38.65,41.22 37.38,39.95 37.37,39.93 37.37,39.91 37.37,39.83 37.36,39.81 37.35,39.8 36.21,38.66 36.19,38.64 36.18,38.64 36.12,38.64 36.1,38.65 36.08,38.67 36.07,38.69 36.08,38.72 36.75,39.39 36.76,39.41 36.76,39.43 36.76,40.58 36.77,40.6 36.78,40.62 38.53,42.37 38.55,42.39 38.57,42.39 38.66,42.39 38.68,42.37 39.09,42.3 39.25,42.67 39.25,42.68 39.25,42.71 39.31,42.78 39.33,42.79 39.35,42.8
DGND on L10_SIG03 (solid shape): 32.27,88.96 32.52,88.7 32.54,88.69 32.59,88.68 32.61,88.67 32.66,88.59 32.67,88.57 32.66,88.56 32.82,88.18 33.23,88.25 33.25,88.26 33.27,88.26 33.34,88.26 33.36,88.26 33.38,88.25 33.75,88.16 33.96,88.47 33.97,88.5 34.03,88.56 34.04,88.57 34.06,88.58 34.5,88.58 34.52,88.57 34.53,88.56 34.59,88.5 34.59,88.43 34.53,88.37 34.52,88.36 34.5,88.35 34.17,88.35 34.15,88.35 34.13,88.34 33.78,87.98 33.75,87.97 33.74,87.98 33.54,87.98 33.38,87.88 33.36,87.87 33.34,87.87 33.27,87.87 33.25,87.87 33.23,87.88 33.03,87.99 32.8,87.94 32.77,87.94 32.74,87.95 32.47,88.22 32.45,88.23 32.43,88.23 32.24,88.23 32.22,88.24 32.19,88.27 32.19,88.91 32.2,88.94 32.22,88.96 32.24,88.97
DGND on L10_SIG03 (solid shape): outline of 91 points within 27.15,34.02 32.4,35.88
DGND on L10_SIG03 (solid shape): 26.29,83.39 26.32,83.4 26.35,83.4 26.36,83.39 26.38,83.37 26.38,82.01 26.38,81.99 26.39,81.97 26.61,81.76 26.62,81.74 26.62,81.71 26.6,81.62 26.59,81.6 26.58,81.59 26.42,81.12 26.9,81.02 26.91,81.03 26.94,81.04 27.04,80.99 27.06,80.97 27.07,80.94 27.07,79.79 27.06,79.76 27.05,79.75 26.98,79.69 26.95,79.68 26.94,79.69 26.54,79.36 26.94,79.04 26.95,79.04 26.98,79.04 27.05,78.98 27.06,78.96 27.07,78.94 27.07,78.69 27.06,78.67 27.05,78.65 26.98,78.6 26.95,78.59 26.94,78.59 26.54,78.27 26.94,77.95 26.95,77.95 26.98,77.94 27.05,77.89 27.06,77.87 27.07,77.85 27.07,77.5 27.06,77.48 27.03,77.46 27.02,77.45 26.99,77.46 25.83,78.62 25.82,78.63 25.81,78.65 25.81,82.89 25.82,82.91 25.83,82.92
DGND on L10_SIG03 (solid shape): outline of 102 points within 24,45.77 30.98,49.43
DGND on L10_SIG03 (solid shape): outline of 107 points within 42.53,103.77 44.72,106.53
DGND on L10_SIG03 (solid shape): 28.02,124.43 28.05,124.42 28.07,124.41 28.12,124.32 28.12,124.29 28.11,124.28 28.4,123.79 28.69,124.28 28.68,124.29 28.68,124.32 28.73,124.41 28.75,124.42 28.78,124.43 30.05,124.43 30.07,124.43 30.09,124.42 30.3,124.2 30.32,124.19 30.34,124.19 31.13,124.19 31.16,124.18 31.18,124.15 31.19,124.14 31.18,124.11 29.83,122.76 29.81,122.75 29.78,122.75 29.68,122.79 29.66,122.82 29.66,122.83 29.27,123.15 29.02,122.7 29.03,122.69 29.02,122.67 28.97,122.59 28.95,122.57 28.93,122.57 27.91,122.57 27.89,122.57 27.87,122.59 27.82,122.67 27.81,122.69 27.82,122.7 27.71,123.09 27.31,123.09 27.28,123.08 26.96,123.08 26.93,123.09 26.91,123.11 26.9,123.12 26.91,123.15 27.56,123.81 27.59,123.82 27.83,123.99 27.84,124.29 27.83,124.3 27.83,124.32 27.89,124.41 27.9,124.43 27.93,124.43
DGND on L10_SIG03 (solid shape): 10.24,130.13 10.26,130.11 10.27,130.08 10.27,129.36 10.28,129.34 10.29,129.32 10.63,128.98 10.64,128.96 10.72,128.76 10.76,128.54 10.76,128.52 11.02,127.46 12.08,127.2 12.09,127.2 12.13,127.19 12.19,127.09 12.19,127.06 12.18,127.03 10.24,125.09 10.21,125.07 10.18,125.08 10.17,125.08 10.15,125.11 10.15,126.02 10.15,126.04 10.14,126.05 9.21,126.98 9.2,127 9.2,127.03 9.24,127.13 9.26,127.15 9.28,127.15 10.18,128.65 8.46,128.93 8.45,128.91 8.42,128.91 8.31,128.95 8.29,128.97 8.28,129 8.28,129.95 8.29,129.98 8.31,130 8.42,130.04 8.45,130.03 8.46,130.02 9.3,129.69 10.09,130.14 10.1,130.15 10.13,130.16
DGND on L10_SIG03 (solid shape): 36.44,44.1 36.47,44.11 36.5,44.11 36.6,44.06 36.62,44.04 36.62,44.02 36.74,43.75 37.03,43.69 37.05,43.69 37.07,43.69 37.14,43.63 37.16,43.61 37.16,43.59 37.16,43.52 37.16,43.5 37.15,43.48 35.33,41.67 35.32,41.65 35.32,41.63 35.32,39.66 35.31,39.63 35.24,39.47 35.27,39.3 35.28,39.29 35.27,39.26 35.22,39.18 35.2,39.16 35.18,39.16 35.04,39.16 35.02,39.16 35,39.18 34.95,39.26 34.94,39.29 34.95,39.3 34.65,39.77 34.35,39.3 34.35,39.29 34.35,39.26 34.3,39.18 34.28,39.16 34.25,39.16 33,39.16 32.97,39.16 32.95,39.18 32.9,39.27 32.9,39.3 32.91,39.31 32.95,39.56 32.8,39.77 32.79,39.77 32.78,39.79 32.77,39.88 32.77,39.91 32.78,39.93 35.24,42.38 35.25,42.4 35.25,42.42 35.25,42.89 35.26,42.91 35.27,42.92 35.3,42.96 35.34,42.97 35.38,42.96 35.39,42.93 35.92,42.76 35.85,43.32 35.84,43.32 35.83,43.34 35.81,43.44 35.81,43.46 35.83,43.48
DGND on L10_SIG03 (solid shape): outline of 139 points within 47.22,43.11 52.02,46.28
DGND on L10_SIG03 (solid shape): 59.85,45.07 59.88,45.08 59.91,45.08 59.92,45.07 59.94,45.05 59.94,42.96 59.93,42.94 59.92,42.92 59.19,42.19 59.17,42.18 59.15,42.18 59.05,42.2 59.03,42.22 59.03,42.23 58.53,42.38 58.5,41.86 58.51,41.85 58.52,41.82 58.48,41.72 58.46,41.7 58.43,41.69 58.09,41.69 58.06,41.7 58.04,41.72 58,41.82 58.01,41.85 58.02,41.86 57.99,42.39 57.49,42.22 57.49,42.21 57.46,42.19 52.01,42.19 51.98,42.2 51.96,42.22 51.95,42.23 51.96,42.26 52.24,42.54 52.26,42.55 52.28,42.56 56.5,42.56 56.52,42.56 56.54,42.57 57.29,43.32 57.3,43.33 57.32,43.34 57.39,43.34 57.41,43.33 57.43,43.32 57.48,43.24 57.49,43.22 57.49,43.21 57.8,42.78 58.12,43.21 58.12,43.22 58.12,43.24 58.18,43.32 58.19,43.33 58.22,43.34 58.3,43.34 58.33,43.33 58.34,43.32 58.4,43.24 58.4,43.22 58.4,43.21 58.77,42.79 58.98,43.31 58.97,43.34 58.99,43.37 59.62,44 59.63,44.02 59.63,44.04 59.63,44.83 59.64,44.85 59.65,44.86
DGND on L10_SIG03 (solid shape): 62.92,53.93 62.95,53.91 63.32,53.62 63.78,53.53 63.8,53.53 63.82,53.51 63.87,53.41 63.87,53.38 63.86,53.36 63.56,53.06 63.54,53.05 63.52,53.04 63.43,53.05 63.41,53.06 63.4,53.07 62.9,53.14 62.91,52.64 62.92,52.63 62.93,52.61 62.91,52.49 62.89,52.47 62.88,52.46 62.73,52.36 62.66,52.2 62.65,52.18 62.29,51.81 62.25,51.8 62.22,51.81 61.72,51.69 61.94,51.22 61.95,51.22 61.97,51.2 62,51.1 62,51.08 61.98,51.05 61.48,50.54 61.46,50.53 61.46,50.51 61.46,48.92 61.46,48.91 61.45,48.89 60.85,48.29 60.82,48.28 60.79,48.28 60.78,48.28 60.76,48.31 60.76,50.17 60.76,50.19 60.78,50.21 60.85,50.27 60.87,50.27 60.88,50.27 61.29,50.59 60.88,50.92 60.87,50.91 60.85,50.92 60.78,50.97 60.76,50.99 60.76,51.01 60.76,51.09 60.76,51.11 60.77,51.13 62.18,52.54 62.2,52.54 62.49,52.84 62.27,53.18 62.26,53.19 62.24,53.21 62.22,53.3 62.22,53.33 62.23,53.35 62.8,53.91 62.81,53.93 62.84,53.93
DGND on L10_SIG03 (solid shape): outline of 83 points within 33.74,106.25 34.83,109.17
DGND on L10_SIG03 (solid shape): outline of 98 points within 52.98,38.32 58.04,40.21
DGND on L10_SIG03 (solid shape): outline of 113 points within 41.64,87.65 44.46,90.66
DGND on L10_SIG03 (solid shape): outline of 91 points within 26.82,111.19 33.92,115.33
DGND on L10_SIG03 (solid shape): outline of 303 points within 44.87,128.99 53.39,136.45
DGND on TOP: outline of 112 points within 0.64,5.71 84.36,154.54 ; 46 cut-outs
DGND on BOTTOM: 11.73,76.69 11.73,75.33 13.61,75.33 13.61,76.69
DGND on BOTTOM: 6.99,80.56 6.99,78.86 9.3,78.86 9.3,80.56
DGND on BOTTOM: 3.74,95.77 3.74,94.68 6.1,94.68 6.1,95.77
DGND on BOTTOM: 5.16,136.46 5.16,135.34 6.23,135.34 6.23,136.46
DGND on BOTTOM: 25.25,53.51 25.25,51.27 30.88,51.27 30.88,53.51
DGND on L02_GND01: 0.64,5.71 0.64,154.54 84.36,154.54 84.36,104.71 73.51,104.71 73.51,101.25 74.14,100.61 74.14,88.54 73.64,88.04 73.64,84.64 84.36,84.64 84.36,5.71
DGND on L04_GND02, L09_GND03: 0.64,154.54 84.36,154.54 84.36,104.71 73.51,104.71 73.51,101.25 74.14,100.61 74.14,88.54 73.64,88.04 73.64,84.64 84.36,84.64 84.36,5.71 0.64,5.71
DGND on L06_PWR01: 7.55,5.73 7.55,18.84 42.38,18.84 42.6,18.26 42.82,18.84 49.25,18.84 49.25,5.73
DGND on L06_PWR01: 28.63,98.49 27.41,97.27 27.41,96.19 26.13,94.92 26.13,83.05 30.33,78.86 46.69,78.86 49.86,82.03 49.86,95.26 45.23,99.89 35.39,99.89 34.8,99.3 30.94,99.3 30.13,98.49
DGND on L06_PWR01: 69.04,63.92 84.33,63.92 84.33,23.94 83.8,23.41 78.49,23.41 77.32,24.58 77.32,35 69.04,43.28
DGND on L06_PWR01: 0.64,154.54 84.36,154.54 84.36,105.61 84.18,105.42 75.54,105.42 74.35,106.62 74.35,115.74 70.06,120.03 56.59,120.03 53.01,116.45 50.17,116.45 46.21,112.48 35.08,112.48 34.42,111.82 34.42,110.48 33.91,109.97 29.7,109.97 29.7,109.44 22.74,109.44 21.57,108.27 21.57,106.9 16,101.33 16,89.6 0.64,89.6
DGND on L07_PWR02: 76.33,38.9 76.33,64.22 84.37,64.22 84.37,38.9
DGND on L07_PWR02: 78.69,154.5 84.31,154.5 84.31,104.81 74.5,104.81 74.5,142.28 78.69,142.28
DGND on L10_SIG03: 64.27,133.98 73.77,133.98 74.82,132.93 74.82,115.08 58.94,99.2 49.64,99.2 45.48,103.36 45.48,106.21 46.77,107.49 54.37,107.49 62.06,115.19 62.06,131.77
DGND on L11_GND04: 0.64,154.54 84.36,154.54 84.36,104.71 73.51,104.71 73.51,101.25 74.14,100.61 74.14,88.54 73.51,87.91 73.51,84.64 84.36,84.64 84.36,5.71 0.64,5.71
VBUS_5V0_TYPEA on TOP: 67.29,71.28 67.29,69.13 68.58,67.83 73.66,67.83 73.66,69.6 69.69,69.6 68.82,70.46 68.82,71.28
VBUS_5V0_TYPEA on BOTTOM: 68.28,70.17 68.28,67.7 73.61,67.7 73.61,70.17
VBUS_5V0_TYPEA on L06_PWR01: 68.43,83.2 70.03,83.2 70.03,73.57 73.81,69.79 73.81,68.47 73.59,68.24 73.08,68.24 68.43,72.89
VBUS_TYPEC1 on L07_PWR02 (solid shape): outline of 1697 points within 4.67,42.29 18.54,53.04
VBUS_TYPEC2 on BOTTOM (solid shape): 14.52,43.95 14.54,43.95 14.58,43.92 15.44,43.92 15.46,43.93 15.5,43.95 16.49,43.95 16.54,43.9 17.34,43.9 17.37,43.89 17.39,43.85 17.39,43.31 17.37,43.28 17.34,43.26 16.5,43.26 16.47,43.23 16.47,43.23 16.22,42.98 16.2,42.97 16.18,42.96 15.4,42.96 15.38,42.96 15.37,42.95 15.09,42.67 15.08,42.66 15.08,42.64 15.08,41.13 15.06,41.1 15.03,41.08 14.11,41.08 14.07,41.1 14.06,41.13 14.06,43.52 14.06,43.54 14.07,43.56 14.45,43.94 14.47,43.95 14.49,43.95
VBUS_TYPEC2 on BOTTOM (solid shape): outline of 504 points within 5.2,26.45 17.5,43.55
VBUS_TYPEC2 on L06_PWR01: 4.85,32.63 4.85,27.53 9.22,27.53 9.22,32.63
VBUS_TYPEC2 on L07_PWR02: 14.96,44.17 25.99,44.17 25.99,26.44 11.2,26.44 10.45,27.2 5.34,27.2 4.74,27.8 4.74,32.5 5.14,32.91 8.84,32.91 11.08,35.15 11.08,40.3
VCC1V1 on TOP: 23.03,74.61 26.16,74.61 26.16,73.5 27.57,73.5 27.57,69.45 23.02,69.45 22.25,68.68 20.58,68.68 20.58,71.25 22.48,71.25 23.03,71.81
VCC1V1 on BOTTOM: 20.6,71.51 20.6,68.67 22.33,68.67 22.33,71.51
VCC1V1_SW on TOP: 22.34,71.99 20.71,71.99 20.71,74.3 19.6,75.42 19.6,76.13 19.65,76.18 21.03,76.18 22.34,74.87
VCC1V8_SYS on TOP: 2.75,86.07 7.98,86.07 9.3,84.75 9.3,81.09 7.32,81.09 5.31,83.1 2.75,83.1
VCC1V8_SYS on BOTTOM: 65.89,52.54 65.89,51.8 67.36,51.8 67.36,52.54
VCC1V8_SYS on BOTTOM: 5.49,86.38 5.9,85.97 9.1,85.97 9.1,81.75 7.27,81.75 5.69,83.33 4.04,83.33 4.04,86.38
VCC1V8_SYS on L07_PWR02: 22.23,68.01 0.64,68.01 0.64,83.37 1.49,84.22 7.89,84.22 10.85,81.26 21.99,81.26 22.39,80.86 22.39,76.59 24.03,74.94 50.35,74.94 51.64,76.24 51.64,87.87 53.81,90.04 57.59,90.04 61.54,93.98 61.54,100.31 63.93,102.71 63.93,107.91 61.32,110.53 61.32,111.48 53.94,118.86 31.32,118.86 23.47,126.71 12.83,126.71 12.83,137.1 10.14,139.79 1.37,139.79 1.37,154.1 49.76,154.1 49.76,143.25 50.52,142.48 73.51,142.48 73.51,101.31 74.15,100.67 74.15,88.56 73.51,87.92 73.51,82.26 72.18,80.93 72.16,80.93 71.52,80.29 71.52,56.62 70.69,55.79 67.21,55.79 67.21,52.69 66.19,51.68 62.49,51.68 57.81,47 57.81,43.73 59.24,42.3 59.24,35.88 53.67,35.88 52.48,37.07 52.48,52.77 51.22,54.03 30.21,54.03 24.79,59.45 24.2,59.45 23,60.65 23,67.23
VCC1V8_SYS_SW on TOP: 9.88,83.35 11.2,83.35 11.43,83.12 11.43,81.7 12.29,80.84 12.01,80.56 11.41,80.56 11.08,80.89 9.88,80.89
VCC3V3_EXP on BOTTOM: 8.16,129.17 8.16,126.3 10.37,126.3 10.37,129.17
VCC3V3_EXP on BOTTOM: 16.74,132.6 18.6,132.6 18.6,134.13 16.89,134.13 16.74,133.97
VCC3V3_EXP on L06_PWR01: 7.8,125.74 7.8,132.93 9.32,134.46 50.1,134.46 50.1,127.04 13.77,127.04 12.47,125.74
VCC3V3_TA on TOP: 44.85,15.42 44.85,12.88 47.74,12.88 47.74,16.41 45.84,16.41
VCC3V3_TA on BOTTOM: 74.37,12.66 74.37,16.09 72.6,16.09 72.6,12.66
VCC3V3_TA on BOTTOM: 49.75,50.68 49.57,50.86 49.57,52.3 49.4,52.48 47.74,52.48 47.54,52.68 47.54,53.24 47.49,53.29 47.01,53.29 47.01,54.79 46.98,54.77 46.98,58.96 46.75,59.19 43.6,59.19 43.43,59.36 42.33,59.36 42.03,59.06 34.03,59.06 33.57,58.6 32.4,58.6 32.33,58.68 32.33,60.76 32.73,61.17 38.4,61.17 39.39,60.18 40.76,60.18 41.12,60.53 44.11,60.53 44.47,60.18 47.21,60.18 48,59.39 48,55 48.68,54.31 48.68,53.52 48.91,53.29 50.21,53.29 50.41,53.09 50.41,50.68
VCC3V3_TA on L07_PWR02: 76.46,6.29 35.11,6.29 35.11,22.95 32.29,25.77 32.29,36.69 38.31,42.71 38.31,52.9 39.01,53.6 51.17,53.6 51.87,52.9 51.87,35.32 53.37,33.82 60.56,33.82 60.56,37.76 60.96,38.16 84,38.16 84,23.94 77.32,23.94 76.46,23.08
VCC3V3_XDS on BOTTOM: 71.97,25.74 75.22,25.74 75.22,24.39 72.46,24.39 71.97,24.88
VCC3V3_XDS on L06_PWR01: 76.46,8.34 74.32,6.21 50.17,6.21 50.17,20.33 59.84,30 59.84,32.8 65.06,38.03 65.06,37.54 68.57,41.05 70.53,41.05 76.46,35.12
VCC5V0_EXP on BOTTOM: 6.5,136.92 7.09,136.92 7.39,136.61 7.39,135.01 7.11,134.74 6.78,134.74 6.48,135.04 6.48,136.89
VCC5V0_EXP on BOTTOM: 7.86,132.63 7.86,129.73 12.94,129.73 12.94,132.63
VCC5V0_EXP on L03_SIG01: 6.91,136.49 9.81,136.49 12.83,133.47 12.83,130.29 12.14,129.6 9.17,129.6 6.58,132.2 6.58,136.16
VCC_0V85 on TOP: 22.27,80.93 24.07,80.93 24.07,79.5 22.74,79.5 22.09,80.16 22.09,80.75
VCC_0V85 on BOTTOM: 22.1,86.3 22.1,84.6 23.32,84.6 23.32,86.02 23.04,86.3
VCC_0V85 on L08_PWR03: 22.13,85.1 23.45,85.1 23.74,84.81 23.74,79.54 22.13,79.54
VCC_1V8_AUD on BOTTOM: 66.68,51.35 69.14,51.35 69.24,51.25 70.03,51.25 70.08,51.19 71.33,51.19 71.33,50.64 66.68,50.64
VCC_1V8_FT4232 on L10_SIG03: 13.59,19.44 14.53,20.38 31.5,20.38 32.54,19.34 32.54,12.15 31.75,11.37 14.3,11.37 13.59,12.08
VCC_3V3_AUD on BOTTOM: 68.19,45.37 69.94,45.37 69.94,43.44 68.19,43.44
VCC_3V3_AUD on L07_PWR02: 68.02,55.06 75.08,55.06 75.75,54.4 75.75,38.8 60.15,38.8 60.15,42.41 58.52,44.03 58.52,46.6 62.94,51.02 66.47,51.02 68.02,52.57
VCC_3V3_FT4232 on BOTTOM: 11.82,13.52 11.82,11.44 11.27,11.44 11.27,10.55 13.04,10.55 13.91,11.41 13.91,13.52
VCC_3V3_FT4232 on L07_PWR02: 9.12,24.9 27.44,24.9 29.36,22.98 29.36,20.51 28.32,19.47 25.53,19.47 25.53,15.99 34.29,15.99 34.29,6.62 9.12,6.62
VCC_3V3_MAIN on TOP: 20.25,88.25 19.04,88.25 19.04,87.15 18.88,86.98 18.88,84.6 19.06,84.42 19.42,84.42 20.25,85.25
VCC_3V3_MAIN on TOP: 10.03,80.27 11.41,80.27 11.46,80.21 12.18,80.21 12.3,80.1 12.3,79.9 11.56,79.16 11.28,79.16 11.08,78.96 10.06,78.96 9.96,79.06 9.96,80.2
VCC_3V3_MAIN on TOP: 13.73,88.25 14.93,88.25 14.93,87.15 15.1,86.98 15.1,84.6 14.91,84.42 14.56,84.42 13.73,85.25
VCC_3V3_MAIN on TOP: 24.25,53.79 24.25,58.64 41.15,58.64 42.9,56.88 45.61,56.88 45.61,56.3 45.75,56.16 45.75,54.94 44.53,54.94 44.21,54.62 44.21,53.79
